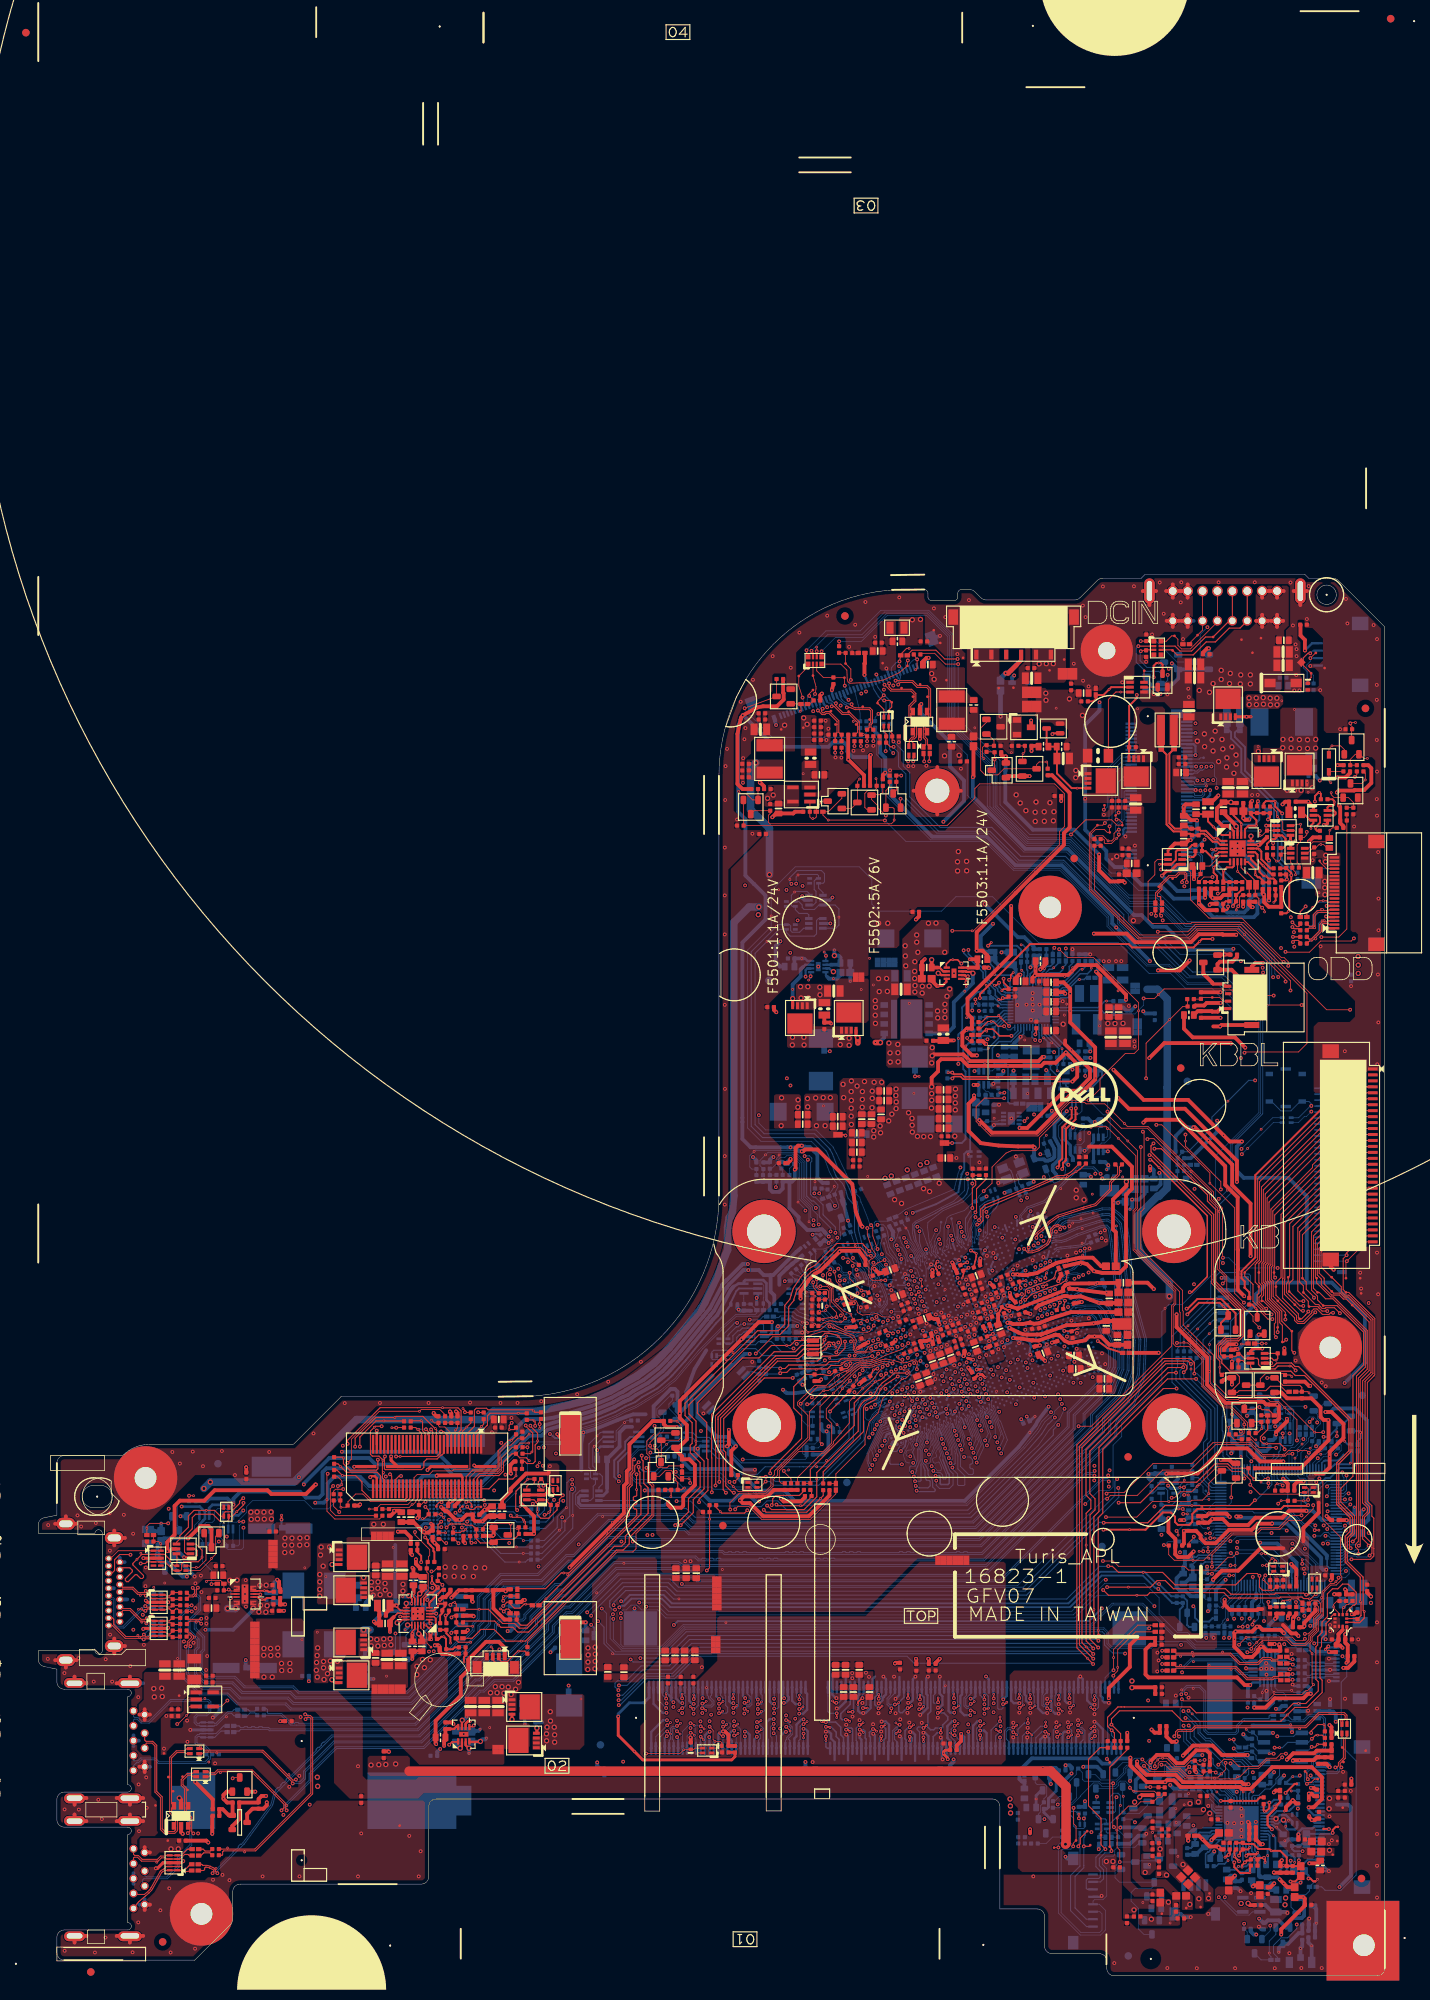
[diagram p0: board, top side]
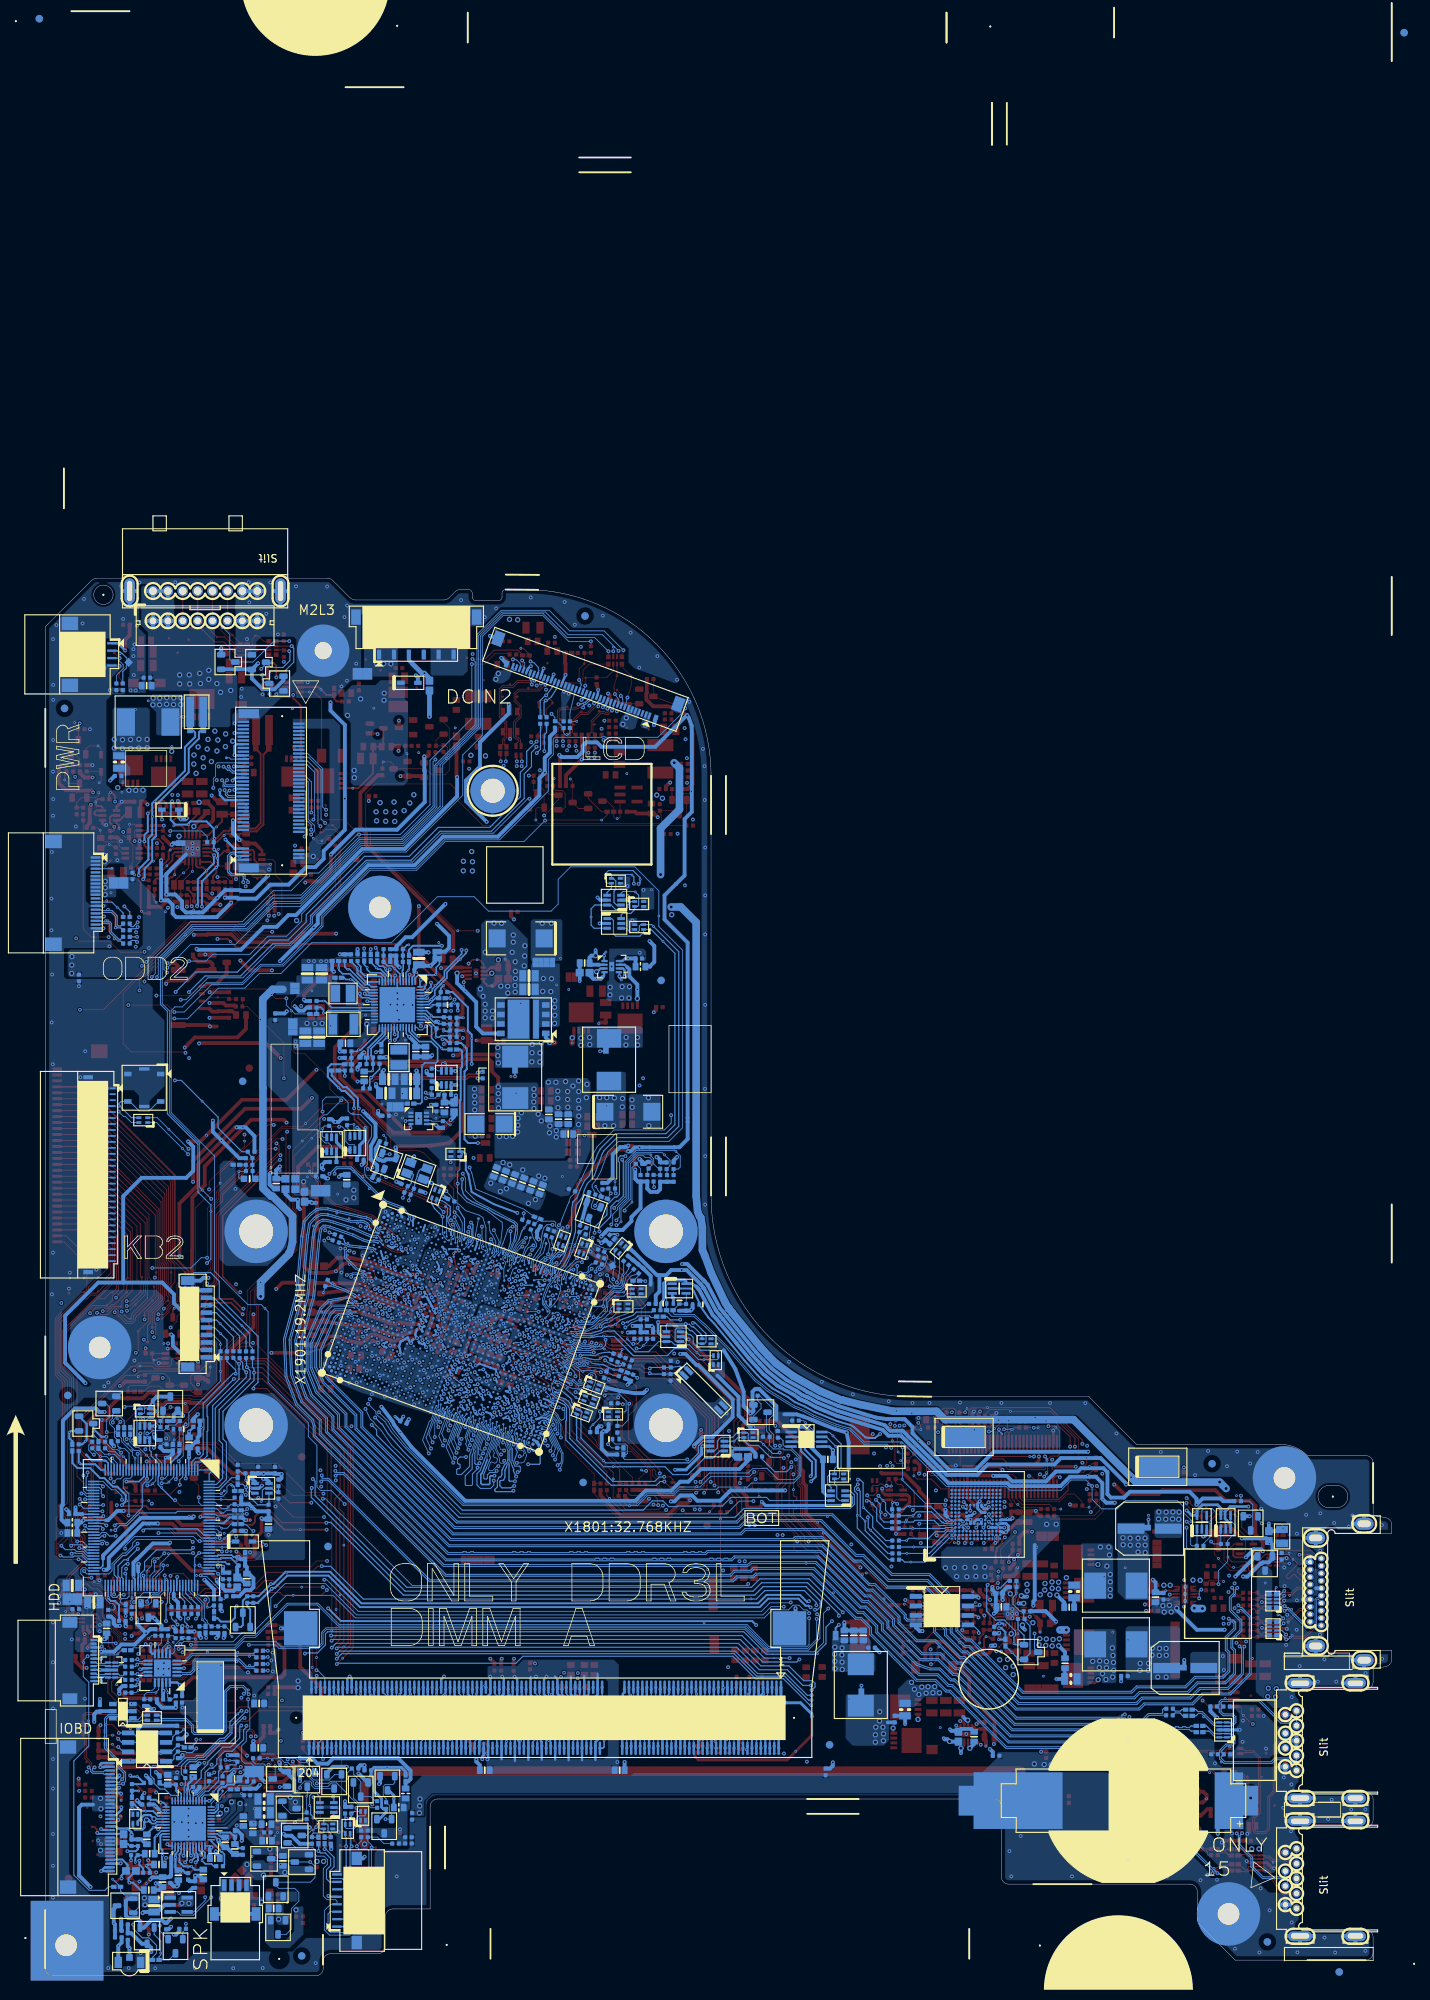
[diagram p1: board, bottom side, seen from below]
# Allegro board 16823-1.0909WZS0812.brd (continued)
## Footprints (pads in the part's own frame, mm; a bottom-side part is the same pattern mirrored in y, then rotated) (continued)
C144KA-108A7-L-1
  round 1.422 hole 1.016: 1(7,0) 2(5,0) 3(3,0) 4(1,0) 5(-1,0) 6(-3,0) 7(-5,0) 8(-7,0)
  oval 1.422x3.404 hole 0.711x2.692: 9(10.125,0) 10(-10.125,0)
C402H22
  custom 0.14x0.14 smd: 1(0,0.445) 2(0,-0.445)
C402H24
  custom 0.14x0.14 smd: 1(0,0.445) 2(0,-0.445)
C603
  custom 0.197x0.197 smd: 1(0,0.66) 2(0,-0.66)
C603H36
  custom 0.197x0.197 smd: 1(0,0.66) 2(0,-0.66)
C603H38
  custom 0.197x0.197 smd: 1(0,0.66) 2(0,-0.66)
C603H40
  custom 0.197x0.197 smd: 1(0,0.66) 2(0,-0.66)
C805H54
  rect 1.549x0.94 smd: 1(0,0.838) 2(0,-0.838)
C805H56
  rect 1.549x0.94 smd: 1(0,0.838) 2(0,-0.838)
C805H58
  rect 1.549x0.94 smd: 1(0,0.838) 2(0,-0.838)
C1206H71
  rect 1.854x1.27 smd: 1(0,1.397) 2(0,-1.397)
CON2O-U
  custom 0.159x0.159 smd: 1(0,0.254) 2(0,-0.254)
CT3528H79
  rect 2.286x2.286 smd: 1(0,1.905) 2(0,-1.905)
CT7343H83
  rect 2.413x2.286 smd: 1(0,3.15) 2(0,-3.15)
DFN8-G125065H32
  rect 0.305x0.838 smd: 1(0.75,1.029) 2(0.25,1.029) 3(-0.25,1.029) 4(-0.75,1.029) 5(-0.75,-1.029) 6(-0.25,-1.029) 7(0.25,-1.029) 8(0.75,-1.029)
  rect 1.245x0.66 smd: 9(0,0)
DFN8G2-G1710-U1H32
  rect 0.305x0.686 smd: 1(0.75,1.106) 2(0.25,1.106) 3(-0.25,1.106) 4(-0.75,1.106) 5(-0.75,-1.106) 6(-0.25,-1.106) 7(0.25,-1.106) 8(0.75,-1.106)
  rect 1.702x0.94 smd: 9(0,0)
DFN10G2510H26
  rect 0.305x0.787 smd: 1(1,0.494) 5(-1,0.494) 6(-1,-0.494) 10(1,-0.494)
  rect 0.254x0.787 smd: 2(0.521,0.494) 4(-0.521,0.494) 7(-0.521,-0.494) 9(0.521,-0.494)
  rect 0.025x0.025 smd: 3(0,0.494)
  rect 0.406x1.753 smd: 8(0,-0.494)
GAP-CLOSE-PWR-3
  rect 0.66x0.762 smd: 1(-0.305,0) 2(0.305,0)
HOLE276R91
  round 7.01 hole 2.311: 1(0,0)
HOLE335R115
  round 8.509 hole 2.921: 1(0,0)
HOLE335R178
  round 8.509 hole 4.521: 1(0,0)
HOLE384X421R115
  rect 9.754x10.693 hole 2.921: 1(0,0)
L603H38
  custom 0.197x0.197 smd: 1(0,0.66) 2(0,-0.66)
L2520-D620H48
  rect 2.261x1.245 smd: 1(0,1.018) 2(0,-1.018)
L7066-1630-1H119
  rect 3.251x2.489 smd: 1(0,2.866) 2(0,-2.866)
L7066-1830-UH119
  rect 3.505x2.921 smd: 1(0,2.78) 2(0,-2.78)
L125100-4P-4H28
  rect 0.762x0.432 smd: 1(-0.625,0.341) 2(0.625,0.341) 3(0.625,-0.341) 4(-0.625,-0.341)
L686647-127318H119
  rect 3.683x2.413 smd: 1(0,2.986) 2(0,-2.986)
L32250525H48
  rect 2.743x1.143 smd: 1(0,1.417) 2(0,-1.417)
LED3020-3P-19H44
  rect 1.499x0.991 smd: 1(0,1.5) 3(0,-1.5)
  rect 0.889x0.889 smd: 2(0.65,0)
LGA12G2H40
  rect 0.381x0.381 smd: 1(0.809,0.809) 4(-0.809,0.809) 7(-0.809,-0.809) 10(0.809,-0.809)
  rect 0.305x0.432 smd: 2(0.25,0.784) 3(-0.25,0.784) 8(-0.25,-0.784) 9(0.25,-0.784)
  rect 0.432x0.305 smd: 5(-0.784,0.25) 6(-0.784,-0.25) 11(0.784,-0.25) 12(0.784,0.25)
LQFP128H63
  rect 0.203x1.524 smd: 1(6.2,7.747) 2(5.8,7.747) 3(5.4,7.747) 4(5,7.747) 5(4.6,7.747) 6(4.2,7.747) 7(3.8,7.747) 8(3.4,7.747) 9(3,7.747) 10(2.6,7.747) 11(2.2,7.747) 12(1.8,7.747) 13(1.4,7.747) 14(0.999,7.747) 15(0.599,7.747) 16(0.199,7.747) 17(-0.199,7.747) 18(-0.599,7.747) 19(-0.999,7.747) 20(-1.4,7.747) 21(-1.8,7.747) 22(-2.2,7.747) 23(-2.6,7.747) 24(-3,7.747) 25(-3.4,7.747) 26(-3.8,7.747) 27(-4.2,7.747) 28(-4.6,7.747) 29(-5,7.747) 30(-5.4,7.747) 31(-5.8,7.747) 32(-6.2,7.747) 65(-6.2,-7.747) 66(-5.8,-7.747) 67(-5.4,-7.747) 68(-5,-7.747) 69(-4.6,-7.747) 70(-4.2,-7.747) 71(-3.8,-7.747) 72(-3.4,-7.747) 73(-3,-7.747) 74(-2.6,-7.747) 75(-2.2,-7.747) 76(-1.8,-7.747) 77(-1.4,-7.747) 78(-0.999,-7.747) 79(-0.599,-7.747) 80(-0.199,-7.747) 81(0.199,-7.747) 82(0.599,-7.747) 83(0.999,-7.747) 84(1.4,-7.747) 85(1.8,-7.747) 86(2.2,-7.747) 87(2.6,-7.747) 88(3,-7.747) 89(3.4,-7.747) 90(3.8,-7.747) 91(4.2,-7.747) 92(4.6,-7.747) 93(5,-7.747) 94(5.4,-7.747) 95(5.8,-7.747) 96(6.2,-7.747)
  rect 1.524x0.203 smd: 33(-7.747,6.2) 34(-7.747,5.8) 35(-7.747,5.4) 36(-7.747,5) 37(-7.747,4.6) 38(-7.747,4.2) 39(-7.747,3.8) 40(-7.747,3.4) 41(-7.747,3) 42(-7.747,2.6) 43(-7.747,2.2) 44(-7.747,1.8) 45(-7.747,1.4) 46(-7.747,0.999) 47(-7.747,0.599) 48(-7.747,0.199) 49(-7.747,-0.199) 50(-7.747,-0.599) 51(-7.747,-0.999) 52(-7.747,-1.4) 53(-7.747,-1.8) 54(-7.747,-2.2) 55(-7.747,-2.6) 56(-7.747,-3) 57(-7.747,-3.4) 58(-7.747,-3.8) 59(-7.747,-4.2) 60(-7.747,-4.6) 61(-7.747,-5) 62(-7.747,-5.4) 63(-7.747,-5.8) 64(-7.747,-6.2) 97(7.747,-6.2) 98(7.747,-5.8) 99(7.747,-5.4) 100(7.747,-5) 101(7.747,-4.6) 102(7.747,-4.2) 103(7.747,-3.8) 104(7.747,-3.4) 105(7.747,-3) 106(7.747,-2.6) 107(7.747,-2.2) 108(7.747,-1.8) 109(7.747,-1.4) 110(7.747,-0.999) 111(7.747,-0.599) 112(7.747,-0.199) 113(7.747,0.199) 114(7.747,0.599) 115(7.747,0.999) 116(7.747,1.4) 117(7.747,1.8) 118(7.747,2.2) 119(7.747,2.6) 120(7.747,3) 121(7.747,3.4) 122(7.747,3.8) 123(7.747,4.2) 124(7.747,4.6) 125(7.747,5) 126(7.747,5.4) 127(7.747,5.8) 128(7.747,6.2)
MSOP8-1H44
  rect 0.356x1.524 smd: 1(-0.975,-2.055) 2(-0.325,-2.055) 3(0.325,-2.055) 4(0.975,-2.055) 5(0.975,2.055) 6(0.325,2.055) 7(-0.325,2.055) 8(-0.975,2.055)
NTC-402H24-U
  custom 0.14x0.14 smd: 1(0,0.445) 2(0,-0.445)
NTC-603H38
  custom 0.216x0.216 smd: 1(0,0.762) 2(0,-0.762)
OSC-3225-4P-4H32
  rect 1.397x1.067 smd: 1(-1.171,-0.756) 2(1.171,-0.756) 3(1.171,0.756) 4(-1.171,0.756)
PAD-60P-1-NSP
  rect 0.305x2.515 smd: 1(-7.25,-2.99) 2(-7.25,2.99) 3(-6.75,-2.99) 4(-6.75,2.99) 5(-6.25,-2.99) 6(-6.25,2.99) 7(-5.751,-2.99) 8(-5.751,2.99) 9(-5.25,-2.99) 10(-5.25,2.99) 11(-4.75,-2.99) 12(-4.75,2.99) 13(-4.249,-2.99) 14(-4.249,2.99) 15(-3.75,-2.99) 16(-3.75,2.99) 17(-3.25,-2.99) 18(-3.25,2.99) 19(-2.75,-2.99) 20(-2.75,2.99) 21(-2.25,-2.99) 22(-2.25,2.99) 23(-1.75,-2.99) 24(-1.75,2.99) 25(-1.25,-2.99) 26(-1.25,2.99) 27(-0.751,-2.99) 28(-0.751,2.99) 29(-0.25,-2.99) 30(-0.25,2.99) 31(0.25,-2.99) 32(0.25,2.99) 33(0.751,-2.99) 34(0.751,2.99) 35(1.25,-2.99) 36(1.25,2.99) 37(1.75,-2.99) 38(1.75,2.99) 39(2.25,-2.99) 40(2.25,2.99) 41(2.75,-2.99) 42(2.75,2.99) 43(3.25,-2.99) 44(3.25,2.99) 45(3.75,-2.99) 46(3.75,2.99) 47(4.249,-2.99) 48(4.249,2.99) 49(4.75,-2.99) 50(4.75,2.99) 51(5.25,-2.99) 52(5.25,2.99) 53(5.751,-2.99) 54(5.751,2.99) 55(6.25,-2.99) 56(6.25,2.99) 57(6.75,-2.99) 58(6.75,2.99) 59(7.25,-2.99) 60(7.25,2.99)
  rect 2.54x0.432 smd: 61(-8.065,0) 64(8.065,0)
  rect 4.699x0.432 smd: 62(-3.175,0) 63(3.175,0)
PAD-87212-1002N
  rect 0.61x1.549 smd: 1(-4.5,-2.525) 2(-3.5,-2.525) 3(-2.5,-2.525) 4(-1.5,-2.525) 5(-0.5,-2.525) 6(0.5,-2.525) 7(1.5,-2.525) 8(2.5,-2.525) 9(3.5,-2.525) 10(4.5,-2.525)
  rect 1.194x1.803 smd: 11(-5.797,0) 12(5.797,0)
POLYSW-2114H30
  rect 1.6x0.965 smd: 1(0,0.94) 2(0,-0.94)
POLYSW-2114H50
  rect 1.6x0.965 smd: 1(0,0.94) 2(0,-0.94)
POLYSW-4633-UH43
  rect 3.505x1.626 smd: 1(0,1.834) 2(0,-1.834)
PPAK-8P-3232H36
  rect 0.406x0.914 smd: 1(-0.975,-2.396) 2(-0.325,-2.396) 3(0.325,-2.396) 4(0.975,-2.396)
  rect 3.353x2.692 smd: 5(0,0)
  rect 0.025x0.025 smd: 6(0.65,0.838) 7(0,0.838) 8(-0.65,0.838)
PPAK-8P-G5324H44-COLAY
  rect 0.762x1.016 smd: 1(-1.905,-3.01) 2(-0.635,-3.01) 3(0.635,-3.01) 4(1.905,-3.01) 5(1.905,3.01) 6(0.635,3.01) 7(-0.635,3.01) 8(-1.905,3.01)
  rect 5.207x2.896 smd: 9(0,0.65)
  rect 5.207x0.787 smd: 10(0,-1.7)
QFN20-G1D75H32
  rect 0.203x0.914 smd: 1(0.8,1.551) 2(0.4,1.551) 3(0,1.551) 4(-0.4,1.551) 5(-0.8,1.551) 11(-0.8,-1.551) 12(-0.4,-1.551) 13(0,-1.551) 14(0.4,-1.551) 15(0.8,-1.551)
  rect 0.914x0.203 smd: 6(-1.551,0.8) 7(-1.551,0.4) 8(-1.551,0) 9(-1.551,-0.4) 10(-1.551,-0.8) 16(1.551,-0.8) 17(1.551,-0.4) 18(1.551,0) 19(1.551,0.4) 20(1.551,0.8)
  rect 1.753x1.753 smd: 21(0,0)
QFN20-G2D25H32
  rect 0.305x1.168 smd: 1(1,1.924) 2(0.5,1.924) 3(0,1.924) 4(-0.5,1.924) 5(-1,1.924) 11(-1,-1.924) 12(-0.5,-1.924) 13(0,-1.924) 14(0.5,-1.924) 15(1,-1.924)
  rect 1.168x0.305 smd: 6(-1.924,1) 7(-1.924,0.5) 8(-1.924,0) 9(-1.924,-0.5) 10(-1.924,-1) 16(1.924,-1) 17(1.924,-0.5) 18(1.924,0) 19(1.924,0.5) 20(1.924,1)
  rect 2.261x2.261 smd: 21(0,0)
QFN20G3D5-G2D15H40
  rect 0.305x0.914 smd: 1(1,1.801) 5(-1,1.801) 11(-1,-1.801) 15(1,-1.801)
  rect 0.305x0.965 smd: 2(0.5,1.775) 3(0,1.775) 4(-0.5,1.775) 12(-0.5,-1.775) 13(0,-1.775) 14(0.5,-1.775)
  rect 0.914x0.305 smd: 6(-1.801,1) 10(-1.801,-1) 16(1.801,-1) 20(1.801,1)
  rect 0.965x0.305 smd: 7(-1.775,0.5) 8(-1.775,0) 9(-1.775,-0.5) 17(1.775,-0.5) 18(1.775,0) 19(1.775,0.5)
  rect 2.159x2.159 smd: 21(0,0)
QFN48J6-G465H40
  rect 0.203x0.965 smd: 1(2.2,3.025) 2(1.8,3.025) 3(1.4,3.025) 4(1,3.025) 5(0.6,3.025) 6(0.2,3.025) 7(-0.2,3.025) 8(-0.6,3.025) 9(-1,3.025) 10(-1.4,3.025) 11(-1.8,3.025) 12(-2.2,3.025) 25(-2.2,-3.025) 26(-1.8,-3.025) 27(-1.4,-3.025) 28(-1,-3.025) 29(-0.6,-3.025) 30(-0.2,-3.025) 31(0.2,-3.025) 32(0.6,-3.025) 33(1,-3.025) 34(1.4,-3.025) 35(1.8,-3.025) 36(2.2,-3.025)
  rect 0.965x0.203 smd: 13(-3.025,2.2) 14(-3.025,1.8) 15(-3.025,1.4) 16(-3.025,1) 17(-3.025,0.6) 18(-3.025,0.2) 19(-3.025,-0.2) 20(-3.025,-0.6) 21(-3.025,-1) 22(-3.025,-1.4) 23(-3.025,-1.8) 24(-3.025,-2.2) 37(3.025,-2.2) 38(3.025,-1.8) 39(3.025,-1.4) 40(3.025,-1) 41(3.025,-0.6) 42(3.025,-0.2) 43(3.025,0.2) 44(3.025,0.6) 45(3.025,1) 46(3.025,1.4) 47(3.025,1.8) 48(3.025,2.2)
  rect 4.648x4.648 smd: 49(0,0)
QFN52J6-G4D75H32
  rect 0.203x0.838 smd: 1(2.4,3.051) 13(-2.4,3.051) 27(-2.4,-3.051) 39(2.4,-3.051)
  rect 0.203x0.914 smd: 2(2,3.051) 3(1.6,3.051) 4(1.2,3.051) 5(0.8,3.051) 6(0.4,3.051) 7(0,3.051) 8(-0.4,3.051) 9(-0.8,3.051) 10(-1.2,3.051) 11(-1.6,3.051) 12(-2,3.051) 28(-2,-3.051) 29(-1.6,-3.051) 30(-1.2,-3.051) 31(-0.8,-3.051) 32(-0.4,-3.051) 33(0,-3.051) 34(0.4,-3.051) 35(0.8,-3.051) 36(1.2,-3.051) 37(1.6,-3.051) 38(2,-3.051)
  rect 0.838x0.203 smd: 14(-3.051,2.4) 26(-3.051,-2.4) 40(3.051,-2.4) 52(3.051,2.4)
  rect 0.914x0.203 smd: 15(-3.051,2) 16(-3.051,1.6) 17(-3.051,1.2) 18(-3.051,0.8) 19(-3.051,0.4) 20(-3.051,0) 21(-3.051,-0.4) 22(-3.051,-0.8) 23(-3.051,-1.2) 24(-3.051,-1.6) 25(-3.051,-2) 41(3.051,-2) 42(3.051,-1.6) 43(3.051,-1.2) 44(3.051,-0.8) 45(3.051,-0.4) 46(3.051,0) 47(3.051,0.4) 48(3.051,0.8) 49(3.051,1.2) 50(3.051,1.6) 51(3.051,2)
  rect 4.75x4.75 smd: 53(0,0)
R402H14
  custom 0.14x0.14 smd: 1(0,0.445) 2(0,-0.445)
R402H16
  custom 0.14x0.14 smd: 1(0,0.445) 2(0,-0.445)
R603H22
  custom 0.197x0.197 smd: 1(0,0.66) 2(0,-0.66)
R805H24
  rect 1.549x0.94 smd: 1(0,0.838) 2(0,-0.838)
R1206H28
  rect 1.854x1.27 smd: 1(0,1.397) 2(0,-1.397)
R3720H40
  rect 4.013x1.041 smd: 1(0,0.867) 2(0,-0.867)
SC70-2D2-312H44
  custom 0.152x0.152 smd: 1(-0.65,-0.902) 2(0.65,-0.902) 3(0,0.902)
SC70-5-1H44
  rect 0.356x1.219 smd: 1(-0.65,-0.922) 2(0,-0.922) 3(0.65,-0.922) 4(0.65,0.921) 5(-0.65,0.921)
SC70-6H44
  rect 0.406x1.016 smd: 1(-0.65,-0.94) 2(0,-0.94) 3(0.65,-0.94) 4(0.65,0.94) 5(0,0.94) 6(-0.65,0.94)
SE361414H178
  rect 1.372x3.607 smd: 1(0,2.499) 2(0,-2.499)
SKT-HDMI23-188137-5
  oval 0.787x0.94 hole 0.533: 1(-4.5,5.75) 2(-4,7.25) 3(-3.5,5.75) 4(-3,7.25) 5(-2.5,5.75) 6(-2,7.25) 7(-1.5,5.75) 8(-1,7.25) 9(-0.5,5.75) 10(0,7.25) 11(0.5,5.75) 12(1,7.25) 13(1.5,5.75) 14(2,7.25) 15(2.5,5.75) 16(3,7.25) 17(3.5,5.75) 18(4,7.25) 19(4.5,5.75)
  oval 1.626x2.515 hole 0.914x1.803: 20(-7.25,6.5) 21(7.25,6.5) 22(-9.15,0) 23(9.15,0)
SKT-USB13-157164-1
  round 1.067 hole 0.711: 1(3.5,9.41) 2(1,9.41) 3(-1,9.41) 4(-3.5,9.41) 5(-4,7.91) 6(-2,7.91) 7(0,7.91) 8(2,7.91) 9(4,7.91)
  oval 1.321x3.2 hole 0.711x2.489: 10(7.7,7.43) 11(-7.7,7.43)
  oval 1.321x2.819 hole 0.711x2.108: 12(7.7,0) 13(-7.7,0)
SLP2510P8-1H22
  rect 0.305x0.762 smd: 1(-1,-0.5) 5(1,-0.5) 6(1,0.5) 10(-1,0.5)
  rect 0.203x0.762 smd: 2(-0.5,-0.5) 4(0.5,-0.5) 7(0.5,0.5) 9(-0.5,0.5)
  rect 0.406x0.762 smd: 3(0,-0.5) 8(0,0.5)
SM3ZS067U410TAR1000R-DT
  round 0.254 hole 1.168 unplated: (-10,0)
  round 0.254 hole 1.651 unplated: (10,0)
  rect 0.305x1.549 smd: 1(-9.25,5.225) 2(-9,-2.225) 3(-8.75,5.225) 4(-8.5,-2.225) 5(-8.25,5.225) 6(-8,-2.225) 7(-7.75,5.225) 16(-5.5,-2.225) 17(-5.25,5.225) 18(-5,-2.225) 19(-4.75,5.225) 20(-4.5,-2.225) 21(-4.25,5.225) 22(-4,-2.225) 23(-3.75,5.225) 24(-3.5,-2.225) 25(-3.25,5.225) 26(-3,-2.225) 27(-2.75,5.225) 28(-2.5,-2.225) 29(-2.25,5.225) 30(-2,-2.225) 31(-1.75,5.225) 32(-1.5,-2.225) 33(-1.25,5.225) 34(-1,-2.225) 35(-0.75,5.225) 36(-0.5,-2.225) 37(-0.25,5.225) 38(0,-2.225) 39(0.25,5.225) 40(0.5,-2.225) 41(0.75,5.225) 42(1,-2.225) 43(1.25,5.225) 44(1.5,-2.225) 45(1.75,5.225) 46(2,-2.225) 47(2.25,5.225) 48(2.5,-2.225) 49(2.75,5.225) 50(3,-2.225) 51(3.25,5.225) 52(3.5,-2.225) 53(3.75,5.225) 54(4,-2.225) 55(4.25,5.225) 56(4.5,-2.225) 57(4.75,5.225) 58(5,-2.225) 59(5.25,5.225) 60(5.5,-2.225) 61(5.75,5.225) 62(6,-2.225) 63(6.25,5.225) 64(6.5,-2.225) 65(6.75,5.225) 66(7,-2.225) 67(7.25,5.225) 68(7.5,-2.225) 69(7.75,5.225) 70(8,-2.225) 71(8.25,5.225) 72(8.5,-2.225) 73(8.75,5.225) 74(9,-2.225) 75(9.25,5.225)
  rect 1.194x2.743 smd: 76(-10.35,4.5) 77(10.35,4.5)
SMD49-6914-0603H56
  rect 1.321x0.584 smd: 1(-3.297,-0.437) 4(-3.297,0.437)
  rect 1.372x0.584 smd: 2(3.272,-0.437) 3(3.272,0.437)
SMD-ARES4H18
  rect 0.356x0.66 smd: 1(-0.325,-0.599) 2(0.325,-0.599) 3(0.325,0.599) 4(-0.325,0.599)
SMD-ARES4H20
  rect 0.356x0.66 smd: 1(-0.325,-0.599) 2(0.325,-0.599) 3(0.325,0.599) 4(-0.325,0.599)
SOD123AK-2H43
  rect 1.143x1.499 smd: A(0,1.758) K(0,-1.758)
SOD323AKH38
  rect 0.559x1.016 smd: A(0,1.143) K(0,-1.143)
SOD323AKH42
  rect 0.559x1.016 smd: A(0,1.143) K(0,-1.143)
SOD882-10D6-1H20
  custom 0.114x0.114 smd: 1(0,0.445) 2(0,-0.445)
SOIC8-1H86
  rect 0.635x1.651 smd: 1(-1.905,-3.493) 2(-0.635,-3.493) 3(0.635,-3.493) 4(1.905,-3.493) 5(1.905,3.493) 6(0.635,3.493) 7(-0.635,3.493) 8(-1.905,3.493)
SOIC8H69
  rect 0.635x1.651 smd: 1(-1.905,-2.54) 2(-0.635,-2.54) 3(0.635,-2.54) 4(1.905,-2.54) 5(1.905,2.54) 6(0.635,2.54) 7(-0.635,2.54) 8(-1.905,2.54)
SON14J3020-G2610H32
  rect 0.025x0.025 smd: 1(1.2,1.105) 6(-0.8,1.105) 9(-0.8,-1.105) 14(1.2,-1.105)
  custom 0.151x0.151 smd: 2(0.8,1.105) 7(-1.2,1.105) 8(-1.2,-1.105) 13(0.8,-1.105)
  rect 0.203x0.813 smd: 3(0.4,1.105) 4(0,1.105) 5(-0.4,1.105) 10(-0.4,-1.105) 11(0,-1.105) 12(0.4,-1.105)
  rect 2.591x0.889 smd: 15(0,0)
SOT23-2D4-312H44
  custom 0.191x0.191 smd: 1(-0.984,-0.953) 2(0.984,-0.953) 3(0,0.953)
SOT23-2D4-312H48
  custom 0.191x0.191 smd: 1(-0.984,-0.953) 2(0.984,-0.953) 3(0,0.953)
SOT23CBE2D4H44
  custom 0.191x0.191 smd: B(-0.984,-0.953) C(0,0.953) E(0.984,-0.953)
SOT23CBE2D6H62
  custom 0.165x0.165 smd: B(-0.95,-1.092) C(0,1.092) E(0.95,-1.092)
SOT23DGS2D4H44
  custom 0.191x0.191 smd: D(0,0.953) G(-0.984,-0.953) S(0.984,-0.953)
SOT23DGS2D4H48
  custom 0.191x0.191 smd: D(0,0.953) G(-0.984,-0.953) S(0.984,-0.953)
SOT323CBE2D2H40
  custom 0.152x0.152 smd: B(-0.65,-0.902) C(0,0.902) E(0.65,-0.902)
SOT-6H58
  rect 0.584x1.016 smd: 1(-0.953,-1.346) 2(0,-1.346) 3(0.953,-1.346) 4(0.953,1.346) 5(0,1.346) 6(-0.953,1.346)
SOT-23-5H51
  rect 0.508x1.524 smd: 1(-0.95,-1.143) 2(0,-1.143) 3(0.95,-1.143) 4(0.95,1.143) 5(-0.95,1.143)
SOT-23-5H58
  rect 0.508x1.524 smd: 1(-0.95,-1.143) 2(0,-1.143) 3(0.95,-1.143) 4(0.95,1.143) 5(-0.95,1.143)
SOT-23-9H44
  custom 0.178x0.178 smd: 1(-0.95,-0.999) 2(0.95,-0.999) 3(0,0.999)
SOT-23-10H44
  rect 0.762x1.143 smd: 1(-0.984,-0.953) 2(0.984,-0.953) 3(0,0.953)
SOT-363H44
  rect 0.406x1.016 smd: 1(-0.65,-0.94) 2(0,-0.94) 3(0.65,-0.94) 4(0.65,0.94) 5(0,0.94) 6(-0.65,0.94)
SPR4527H308
  rect 8.992x3.404 smd: 1(-2.248,0)
SPR5630H142
  rect 5.283x2.692 smd: 1(-2.413,0)
STF236R128H101
  round 5.994 hole 3.251: 1(0,0)
TJE-533-S-V-T-R-744
  rect 0.61x0.991 smd: 1(-1.845,2.205) 2(-1.845,-2.205) 3(1.845,2.205) 4(1.845,-2.205)
  rect 0.457x1.397 smd: 5(-2.521,0) 6(2.521,0)
TPAD14-OP
  round 0.356 smd: 1(0,0)
unnamed
  round 0.254 hole 2.184 unplated: (0,0)

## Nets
1V_CPU_VCGI: C1019.1 C1020.1 C1021.1 C1022.1 C1023.1 C1024.1 C1025.1 C1026.1 C1027.1 C1028.1 C1029.1 C1030.1 CPU1.AA28 CPU1.AA30 CPU1.AA32 CPU1.AA36 CPU1.AA37 CPU1.AA39 CPU1.AC28 CPU1.AC30 CPU1.AC32 CPU1.AC36 CPU1.AC37 CPU1.AE28 CPU1.AE30 CPU1.AE32 CPU1.AE36 CPU1.AE37 CPU1.AG28 CPU1.AG30 CPU1.AG32 CPU1.AG36 CPU1.AJ28 CPU1.AJ30 CPU1.AJ32 CPU1.AK28 CPU1.AK30 CPU1.AK32 CPU1.AK34 CPU1.AM30 CPU1.E29 CPU1.E35 CPU1.E37 CPU1.E43 CPU1.E45 CPU1.E48 CPU1.E50 CPU1.F29 CPU1.R45 CPU1.R47 CPU1.U28 CPU1.U30 CPU1.U32 CPU1.U36 CPU1.U37 CPU1.U39 CPU1.U41 CPU1.U42 CPU1.U44 CPU1.U46 CPU1.U47 CPU1.U48 CPU1.V28 CPU1.V30 CPU1.V32 CPU1.V36 CPU1.V37 CPU1.V39 CPU1.V41 CPU1.Y28 CPU1.Y30 CPU1.Y32 CPU1.Y36 CPU1.Y37 CPU1.Y39 CPU1.Y41 PC1010.1 PC1012.1 PC1013.1 PC1014.1 PC1015.1 PC1016.1 PC1017.1 PC1018.1 PC1019.1 PC1020.1 PC1021.1 PC1022.1 PC1024.1 PC1025.1 PC1026.1 PC1028.1 PC1030.1 PC1031.1 PC1032.1 PC1033.1 PC1034.1 PC1035.1 PC1036.1 PC1037.1 PC1038.1 PC1039.1 PC1044.1 PC5106.2 PG5101.2 PL5103.2 PR5107.2 PR5108.2 PR5113.1 PT5102.1
1V_CPU_VNN: C1016.1 C1017.1 CPU1.AJ37 CPU1.AJ39 CPU1.AJ41 CPU1.AJ42 CPU1.AJ46 CPU1.AK37 CPU1.AK39 CPU1.AK41 CPU1.AK42 CPU1.AK44 CPU1.AK46 CPU1.AM23 CPU1.AM25 CPU1.AM41 CPU1.AM42 CPU1.AM44 PC1006.1 PC1007.1 PC1009.1 PC1011.1 PC1023.1 PC1048.1 PC1049.1 PC1050.1 PC1051.1 PG5103.2 PL5101.2 PT5101.1
3V_5V_PWRGD: ED1803.1 PR4534.2 PR5033.2 PR5046.2 PU4503.7
3V_EN: KBC24.63 Q2403.6 R4013.2 RN2406.2(A)
3V_FEEDBACK: PG4535.2 PR4512.1 PR4535.1
3V_S5_EN: D4001.1 PR4503.1 PR4504.2 R4013.1
5V_DDC_HDMI1: D5701.1 RN5701.3(B)
5V_DDC_HDMI2: D5701.2 RN5701.4(B)
5V_HDD_S0: C6022.1 C6023.1 HDD1.2 HDD1.3 HDD1.4 R6025.2
5V_HDMI_R_S0: F5701.1 R5718.2
5V_HDMI_S0: EC5701.1 F5701.2 HDMI1.18
5V_PWR: PC4518.1 PG4519.1 PG4523.1 PG4527.1 PG4532.1 PG4533.1 PG4537.1 PG4538.1 PG4540.1 PG4541.1 PG4544.1 PG4545.1 PL4501.2 PT4501.1
5V_PWR_2: PC4524.1 PU4503.13
5V_S0: C4006.1 C6020.1 C6021.1 D5701.3 EC4003.1 EC8919.1 EC8920.1 EC8921.1 EC8922.1 EC8923.1 EC8924.1 EC8925.1 EC8926.1 EC8928.1 EC8930.1 EC8931.1 Q2701.D Q2907.E Q5702.G Q6502.E R2712.1 R2716.1 R2720.2 R2733.1 R2926.2 R5512.2 R5718.1 R6004.1 R6025.1 R6504.1 R7009.1 U4001.8 U4001.9
5V_S0_CT: C4003.1 U4001.10
5V_S0_SIP: C2728.1 C2729.1 L2701.2 Q2701.S
5V_S5: C3509.1 C3604.1 C4005.1 DB3.1 EC4001.1 EC4005.1 EC8909.1 EC8910.1 EC8911.1 PC5003.1 PC5004.1 PC5007.1 PC5008.1 PC5024.1 PC5025.1 PG4519.2 PG4523.2 PG4527.2 PG4533.2 PG4537.2 PG4538.2 PG4540.2 PG4541.2 PG4544.2 PG4545.2 PR4303.1 PR4506.1 PR5031.1 PR5101.1 PR5103.1 PR5104.1 PU5001.19 PU5001.25 PU5001.26 PU5001.36 Q6403.E Q6404.E U3601.5 U3602.5 U4001.4 U4001.6 U4001.7 U4002.4
5V_S5_EN: D4001.2 PR4501.2 PR4502.1 PR4504.1 PR4530.1 R4007.1
5V_USB30: AFTP3501.1 AFTP3507.1 C3601.1 C3602.1 C3605.1 C3606.1 C3607.1 EU3502.5 EU5501.5 R3601.1 U3601.1 USB1.1 USB2.1
19V_AD+: PC4303.1 PC4304.1 PC4305.1 PC4306.1 PR4404.1 PR4405.1 PR4407.1 PR4408.1 PR4469.1 PU4301.5 PU4301.6 PU4301.7 PU4301.8 PU4402.5 PU4402.6 PU4402.7 PU4402.8 PU4403.4
19V_DCBATOUT: EC4401.1 EC4402.1 EC5501.1 EC5502.1 EC5503.1 EC8903.1 EC8904.1 EC8905.1 EC8906.1 EC8907.1 EC8908.1 F5501.1 PC4406.1 PC4408.1 PC4409.1 PC4426.1 PC4519.1 PC4531.1 PG4403.1 PG4518.1 PG4520.1 PG4521.1 PG4524.1 PG4525.1 PG4531.1 PG4534.1 PG4536.1 PG4542.1 PG4543.1 PG5113.1 PG5114.1 PG5115.1 PG5116.1 PG5117.1 PG5118.1 PG5119.1 PG5120.1 PR4402.2 PR4468.1 PR5007.1 PR5008.1 PT5103.1 PU4403.1 PU4403.2 PU4403.3 PU4405.5 PU4405.6 PU4405.7 PU4405.8 PU4503.12 R2726.1
19V_DCBATOUT_LCD: AFTP5501.1 C5501.1 C5503.1 C5511.1 F5501.2 LCD1.1 LCD1.2
+3.3V_1.8V_DVDD-IO: C2719.1 C2723.2 HDA27.9 R2729.2
+3V_1D5V_AVDD: C2715.1 C2721.1 HDA27.40 R2724.2
+3V_AVDD: C2716.1 C2717.1 HDA27.1 R2706.1 R2708.2 R2711.1
+5V_AVDD: C2710.1 C2711.1 HDA27.26 R2720.1
+5V_KB_BL: AFTP6501.1 C6501.1 KBBL1.1 R6504.2
+5V_PVDD: C2706.1 C2707.1 C2708.1 C2709.1 HDA27.41 HDA27.46 L2701.1 R2712.2 R2716.2
DVSS: HDA27.4 R2707.1
GND: AFTP2501.1 AFTP3504.1 AFTP3505.1 AFTP4309.1 AFTP4310.1 AFTP4311.1 AFTP6403.1 AFTP6531.1 AFTP6537.1 AFTP6565.1 AFTP6612.1 BATT1.7 BATT1.8 BATT1.9 BATT1.10 BATT2.7 BATT2.8 C601.2 C1001.2 C1002.2 C1003.2 C1004.2 C1005.2 C1006.2 C1007.2 C1008.2 C1009.2 C1010.2 C1011.2 C1012.2 C1013.2 C1014.2 C1015.2 C1016.2 C1017.2 C1018.2 C1019.2 C1020.2 C1021.2 C1022.2 C1023.2 C1024.2 C1025.2 C1026.2 C1027.2 C1028.2 C1029.2 C1030.2 C1101.2 C1102.2 C1103.2 C1104.2 C1106.2 C1107.2 C1108.2 C1109.2 C1110.2 C1111.2 C1112.2 C1113.2 C1201.2 C1202.2 C1203.2 C1205.2 C1206.2 C1207.2 C1208.2 C1209.2 C1210.2 C1211.2 C1212.2 C1213.2 C1214.2 C1215.2 C1216.2 C1217.2 C1218.2 C1220.2 C1223.2 C1224.2 C1801.2 C1802.2 C1803.2 C1804.2 C1805.2 C1901.2 C1902.2 C2401.2 C2414.2 C2417.2 C2418.2 C2428.1 C2429.2 C2430.2 C2431.2 C2432.2 C2433.2 C2439.2 C2440.2 C2441.2 C2443.2 C2444.2 C2445.2 C2446.2 C2447.2 C2501.2 C2502.2 C2503.2 C2504.2 C2601.2 C2602.2 C2605.2 C2701.2 C2704.1 C2706.2 C2707.2 C2708.2 C2709.2 C2714.2 C2716.2 C2717.2 C2718.2 C2719.2 C2722.1 C2723.1 C2728.2 C2729.2 C2905.2 C2907.2 C2909.2 C2910.2 C3509.2 C3515.2 C3517.2 C3518.2 C3601.2 C3602.2 C3604.2 C3605.2 C3606.2 C3607.2 C4002.2 C4003.2 C4004.2 C4005.2 C4006.2 C4010.2 C4011.2 C4014.2 C4030.2 C4031.2 C4033.2 C5501.2 C5502.2 C5503.2 C5509.1 C5510.2 C5511.2 C5514.2 C5515.2 C5516.2 C5536.1 C5538.2 C6009.2 C6010.2 C6012.2 C6020.2 C6021.2 C6022.2 C6023.2 C6024.2 C6101.2 C6102.2 C6103.2 C6301.2 C6302.2 C6303.2 C6304.2 C6305.2 C6401.2 C6501.2 C6502.2 C6504.2 C6601.2 C7001.2 C7002.2 C7003.2 C9901.2 C9902.2 C9903.2 C9904.2 C9905.2 CPU1.A5 CPU1.A9 CPU1.A12 CPU1.A16 CPU1.A20 CPU1.A24 CPU1.A28 CPU1.A32 CPU1.A36 CPU1.A40 CPU1.A44 CPU1.A48 CPU1.A52 CPU1.A56 CPU1.A62 CPU1.AA1 CPU1.AA2 CPU1.AA27 CPU1.AA34 CPU1.AA41 CPU1.AA63 CPU1.AB5 CPU1.AB9 CPU1.AB10 CPU1.AB12 CPU1.AB16 CPU1.AB48 CPU1.AB52 CPU1.AB57 CPU1.AB59 CPU1.AC18 CPU1.AC27 CPU1.AC34 CPU1.AC39 CPU1.AE1 CPU1.AE2 CPU1.AE4 CPU1.AE5 CPU1.AE7 CPU1.AE8 CPU1.AE10 CPU1.AE11 CPU1.AE13 CPU1.AE14 CPU1.AE16 CPU1.AE17 CPU1.AE23 CPU1.AE27 CPU1.AE34 CPU1.AE39 CPU1.AE41 CPU1.AE47 CPU1.AE48 CPU1.AE50 CPU1.AE51 CPU1.AE53 CPU1.AE54 CPU1.AE56 CPU1.AE57 CPU1.AE59 CPU1.AE63 CPU1.AG13 CPU1.AG18 CPU1.AG23 CPU1.AG27 CPU1.AG34 CPU1.AG37 CPU1.AG39 CPU1.AG41 CPU1.AG42 CPU1.AG44 CPU1.AG46 CPU1.AH5 CPU1.AH6 CPU1.AH7 CPU1.AH15 CPU1.AH16 CPU1.AH48 CPU1.AH52 CPU1.AH54 CPU1.AH55 CPU1.AH57 CPU1.AH58 CPU1.AH59 CPU1.AJ1 CPU1.AJ2 CPU1.AJ18 CPU1.AJ23 CPU1.AJ27 CPU1.AJ34 CPU1.AJ36 CPU1.AJ63 CPU1.AK5 CPU1.AK9 CPU1.AK10 CPU1.AK12 CPU1.AK18 CPU1.AK23 CPU1.AK27 CPU1.AK36 CPU1.AK48 CPU1.AK52 CPU1.AK59 CPU1.AM18 CPU1.AM22 CPU1.AM27 CPU1.AM34 CPU1.AM36 CPU1.AM39 CPU1.AM46 CPU1.AN1 CPU1.AN2 CPU1.AN5 CPU1.AN7 CPU1.AN8 CPU1.AN10 CPU1.AN11 CPU1.AN13 CPU1.AN14 CPU1.AN16 CPU1.AN17 CPU1.AN25 CPU1.AN27 CPU1.AN28 CPU1.AN30 CPU1.AN34 CPU1.AN36 CPU1.AN37 CPU1.AN39 CPU1.AN47 CPU1.AN48 CPU1.AN50 CPU1.AN51 CPU1.AN53 CPU1.AN54 CPU1.AN56 CPU1.AN57 CPU1.AN59 CPU1.AN63 CPU1.AP9 CPU1.AP55 CPU1.AR19 CPU1.AR32 CPU1.AR45 CPU1.AT2 CPU1.AT3 CPU1.AT7 CPU1.AT12 CPU1.AT16 CPU1.AT19 CPU1.AT25 CPU1.AT29 CPU1.AT35 CPU1.AT39 CPU1.AT45 CPU1.AT48 CPU1.AT52 CPU1.AT57 CPU1.AT61 CPU1.AT62 CPU1.AU32 CPU1.AV2 CPU1.AV3 CPU1.AV9 CPU1.AV19 CPU1.AV21 CPU1.AV23 CPU1.AV29 CPU1.AV32 CPU1.AV35 CPU1.AV41 CPU1.AV43 CPU1.AV45 CPU1.AV55 CPU1.AV61 CPU1.AV62 CPU1.AW14 CPU1.AW30 CPU1.AW34 CPU1.AW50 CPU1.AY6 CPU1.AY10 CPU1.AY32 CPU1.AY54 CPU1.AY58 CPU1.B2 CPU1.B3 CPU1.B9 CPU1.B62 CPU1.B63 CPU1.BA1 CPU1.BA2 CPU1.BA12 CPU1.BA16 CPU1.BA17 CPU1.BA21 CPU1.BA25 CPU1.BA27 CPU1.BA29 CPU1.BA32 CPU1.BA35 CPU1.BA37 CPU1.BA39 CPU1.BA43 CPU1.BA47 CPU1.BA48 CPU1.BA52 CPU1.BA62 CPU1.BA63 CPU1.BB3 CPU1.BB19 CPU1.BB25 CPU1.BB39 CPU1.BB45 CPU1.BB61 CPU1.BC32 CPU1.BD3 CPU1.BD8 CPU1.BD32 CPU1.BD56 CPU1.BD61 CPU1.BE1 CPU1.BE10 CPU1.BE12 CPU1.BE16 CPU1.BE17 CPU1.BE21 CPU1.BE27 CPU1.BE29 CPU1.BE35 CPU1.BE37 CPU1.BE43 CPU1.BE47 CPU1.BE48 CPU1.BE52 CPU1.BE54 CPU1.BE63 CPU1.BF3 CPU1.BF32 CPU1.BF61 CPU1.BG19 CPU1.BG23 CPU1.BG29 CPU1.BG32 CPU1.BG35 CPU1.BG41 CPU1.BG45 CPU1.BH1 CPU1.BH2 CPU1.BH21 CPU1.BH25 CPU1.BH39 CPU1.BH43 CPU1.BH62 CPU1.BH63 CPU1.BJ4 CPU1.BJ8 CPU1.BJ10 CPU1.BJ14 CPU1.BJ18 CPU1.BJ28 CPU1.BJ32 CPU1.BJ36 CPU1.BJ46 CPU1.BJ50 CPU1.BJ54 CPU1.BJ56 CPU1.BJ60 CPU1.C12 CPU1.C16 CPU1.C28 CPU1.C32 CPU1.C40 CPU1.C48 CPU1.D6 CPU1.D32 CPU1.D58 CPU1.E4 CPU1.E12 CPU1.E14 CPU1.E19 CPU1.E27 CPU1.E54 CPU1.F3 CPU1.F10 CPU1.F21 CPU1.F32 CPU1.F37 CPU1.F43 CPU1.F45 CPU1.F50 CPU1.F56 CPU1.F59 CPU1.F63 CPU1.G1 CPU1.G32 CPU1.H3 CPU1.H7 CPU1.H17 CPU1.H23 CPU1.H29 CPU1.H37 CPU1.H47 CPU1.H61 CPU1.J12 CPU1.J14 CPU1.J19 CPU1.J27 CPU1.J30 CPU1.J32 CPU1.J35 CPU1.J37 CPU1.J48 CPU1.J63 CPU1.K5 CPU1.K6 CPU1.K32 CPU1.K54 CPU1.K57 CPU1.L21 CPU1.L27 CPU1.L29 CPU1.L35 CPU1.L43 CPU1.L45 CPU1.L50 CPU1.M3 CPU1.M9 CPU1.M14 CPU1.M21 CPU1.M27 CPU1.M32 CPU1.M50 CPU1.M59 CPU1.N1 CPU1.N32 CPU1.N63 CPU1.P5 CPU1.P9 CPU1.P13 CPU1.P19 CPU1.P35 CPU1.P37 CPU1.P41 CPU1.P43 CPU1.P45 CPU1.P55 CPU1.P59 CPU1.R23 CPU1.R29 CPU1.R32 CPU1.T49 CPU1.U1 CPU1.U2 CPU1.U5 CPU1.U7 CPU1.U8 CPU1.U10 CPU1.U11 CPU1.U13 CPU1.U14 CPU1.U16 CPU1.U17 CPU1.U18 CPU1.U27 CPU1.U34 CPU1.U50 CPU1.U51 CPU1.U53 CPU1.U54 CPU1.U56 CPU1.U57 CPU1.U59 CPU1.U62 CPU1.U63 CPU1.V20 CPU1.V27 CPU1.V34 CPU1.V42 CPU1.Y5 CPU1.Y6 CPU1.Y7 CPU1.Y12 CPU1.Y16 CPU1.Y22 CPU1.Y27 CPU1.Y34 CPU1.Y42 CPU1.Y46 CPU1.Y48 CPU1.Y52 CPU1.Y54 CPU1.Y55 CPU1.Y57 CPU1.Y59 D4304.1 D4305.1 D4306.1 DB1.1 DB1.3 DB1.11 DB1.12 DB3.4 DB3.5 DB3.6 DCIN1.7 DCIN1.8 DCIN2.7 DCIN2.8 DM1.2 DM1.3 DM1.8 DM1.9 DM1.11 DM1.13 DM1.14 DM1.19 DM1.20 DM1.25 DM1.26 DM1.28 DM1.31 DM1.32 DM1.37 DM1.38 DM1.43 DM1.44 DM1.46 DM1.48 DM1.49 DM1.54 DM1.55 DM1.60 DM1.61 DM1.63 DM1.65 DM1.66 DM1.71 DM1.72 DM1.127 DM1.128 DM1.133 DM1.134 DM1.136 DM1.138 DM1.139 DM1.144 DM1.145 DM1.150 DM1.151 DM1.153 DM1.155 DM1.156 DM1.161 DM1.162 DM1.167 DM1.168 DM1.170 DM1.172 DM1.173 DM1.178 DM1.179 DM1.184 DM1.185 DM1.187 DM1.189 DM1.190 DM1.195 DM1.196 DM1.205 DM1.206 EC1801.2 EC1901.2 EC1902.2 EC2001.2 EC2002.2 EC2102.2 EC2401.2 EC2402.2 EC2403.2 EC2501.2 EC2502.2 EC2503.2 EC2504.2 EC2505.2 EC2506.2 EC2702.2 EC2703.2 EC2704.2 EC2705.2 EC2706.2 EC2708.2 EC2709.1 EC2901.2 EC2902.2 EC2903.2 EC2904.2 EC4001.2 EC4002.2 EC4003.2 EC4004.2 EC4005.2 EC4306.1 EC4307.2 EC4308.2 EC4309.2 EC4310.2 EC4401.2 EC4402.2 EC5501.2 EC5502.2 EC5503.2 EC5504.2 EC5505.2 EC5506.2 EC5507.2 EC5701.2 EC6401.2 EC6402.2 EC6403.2 EC6404.2 EC6501.2 EC6502.2 EC6503.2 EC6504.2 EC6505.2 EC6506.2 EC8901.2 EC8902.2 EC8903.2 EC8904.2 EC8905.2 EC8906.2 EC8907.2 EC8908.2 EC8909.2 EC8910.2 EC8911.2 EC8912.2 EC8913.2 EC8914.2 EC8915.2 EC8916.2 EC8917.2 EC8918.2 EC8919.2 EC8920.2 EC8921.2 EC8922.2 EC8923.2 EC8924.2 EC8925.2 EC8926.2 EC8927.2 EC8928.2 EC8929.2 EC8930.2 EC8931.2 ED1201.2 ED1202.2 ED1803.2 ED1804.2 ED1805.2 ED1806.2 ED1807.2 ED1808.2 ED1809.2 ED5701.3 ED5701.8 ED5702.3 ED5702.8 ED5703.3 ED5703.8 ED6401.2 ED6601.2 EL4303.2 EL4304.2 EU3501.3 EU3501.8 EU3502.2 EU3504.3 EU3504.8 EU5501.2 EU6001.3 EU6001.8 FC3503.2 FC3504.2 FC3505.2 FC3506.2 G1801.1 G6401.1 G6402.1 H1.1 H2.1 H3.1 H4.1 H5.1 H6.1 H7.1 H8.1 H9.1 H10.1 HDA27.49 HDD1.6 HDD1.9 HDD1.12 HDD1.13 HDD1.14 HDMI1.2 HDMI1.5 HDMI1.8 HDMI1.11 HDMI1.17 HDMI1.20 HDMI1.21 HDMI1.22 HDMI1.23 HS1.1 IOBD1.1 IOBD1.2 IOBD1.5 IOBD1.8 IOBD1.29 IOBD1.30 IOBD1.31 IOBD1.32 KB1.1 KB1.31 KB1.32 KB2.1 KB2.31 KB2.32 KBBL1.5 KBBL1.6 KBC24.5 KBC24.18 KBC24.45 KBC24.78 KBC24.89 KBC24.116 LCD1.13 LCD1.16 LCD1.19 LCD1.23 LCD1.24 LCD1.25 LCD1.29 LCD1.36 LCD1.41 LCD1.42 LCD1.43 LCD1.44 LED1.3 ODD1.1 ODD1.4 ODD1.7 ODD1.18 ODD1.19 ODD1.20 ODD1.21 ODD1.22 ODD2.1 ODD2.2 ODD2.3 ODD2.14 ODD2.17 ODD2.20 ODD2.21 ODD2.22 PC1001.2 PC1002.2 PC1003.2 PC1004.2 PC1006.2 PC1007.2 PC1008.2 PC1009.2 PC1010.2 PC1011.2 PC1012.2 PC1013.2 PC1014.2 PC1015.2 PC1016.2 PC1017.2 PC1018.2 PC1019.2 PC1020.2 PC1021.2 PC1022.2 PC1023.2 PC1024.2 PC1025.2 PC1026.2 PC1027.2 PC1028.2 PC1030.2 PC1031.2 PC1032.2 PC1033.2 PC1034.2 PC1035.2 PC1036.2 PC1037.2 PC1038.2 PC1039.2 PC1040.2 PC1041.2 PC1042.2 PC1043.2 PC1044.2 PC1045.2 PC1046.2 PC1047.2 PC1048.2 PC1049.2 PC1050.2 PC1051.2 PC1052.2 PC1101.2 PC1102.2 PC1103.2 PC4302.2 PC4303.2 PC4304.2 PC4305.2 PC4306.2 PC4401.2 PC4406.2 PC4407.2 PC4408.2 PC4409.2 PC4415.2 PC4416.2 PC4417.2 PC4418.2 PC4419.2 PC4425.2 PC4426.2 PC4435.2 PC4501.2 PC4509.2 PC4517.2 PC4518.2 PC4519.2 PC4520.2 PC4524.2 PC4525.2 PC4526.2 PC4527.2 PC4528.2 PC4529.2 PC4530.2 PC4531.2 PC4536.2 PC5003.2 PC5004.2 PC5005.2 PC5006.2 PC5007.2 PC5008.2 PC5009.2 PC5010.2 PC5011.2 PC5013.2 PC5015.2 PC5017.2 PC5018.2 PC5019.2 PC5020.2 PC5021.2 PC5022.2 PC5023.2 PC5024.2 PC5025.2 PC5026.2 PC5027.2 PC5028.2 PC5029.2 PC5030.2 PC5031.2 PC5032.2 PC5034.2 PC5035.2 PC5036.2 PC5101.2 PC5102.2 PC5103.2 PC5104.2 PC5107.2 PC5108.2 PC5109.2 PC5110.2 PC5112.2 PC5113.2 PC5114.2 PC5117.2 PC5118.2 PC5119.2 PC5120.2 PC5123.2 PC5124.2 PC5126.2 PC5127.2 PC5128.2 PC5129.2 PC5130.2 PC5131.2 PD4301.A PD4302.1 PD4303.3 PD4304.A PG4411.2 PQ4302.E PQ4304.E PQ4306.1 PQ4306.4 PQ4402.1 PQ4402.4 PQ4408.1 PQ4408.4 PQ4410.1 PQ4410.4 PQ4414.S PR4302.2 PR4308.2 PR4313.2 PR4405.2 PR4432.2 PR4433.2 PR4436.2 PR4464.2 PR4470.2 PR4471.1 PR4474.2 PR4517.2 PR4523.2 PR4526.2 PR4530.2 PR4531.2 PR5012.1 PR5014.1 PR5018.1 PR5021.2 PR5024.2 PR5036.2 PR5102.2 PR5112.2 PR5114.2 PT4501.2 PT4502.2 PT5101.2 PT5102.2 PT5103.2 PU4404.14 PU4406.1 PU4406.2 PU4406.3 PU4502.1 PU4502.2 PU4502.3 PU4503.21 PU4505.1 PU4505.2 PU4505.3 PU5001.7 PU5001.53 PU5101.1 PU5101.2 PU5101.3 PU5104.1 PU5104.2 PU5104.3 PU5105.5 PU5105.6 PU5105.7 PU5106.6 PU5106.9 PU5107.6 PU5107.9 PU5108.6 PU5108.9 PWR1.4 PWR1.5 PWR1.6 PWSW2.1 PWSW2.2 PWSW2.5 PWSW2.6 Q1801.S Q1802.S Q2401.C Q2402.S Q2403.1 Q2403.4 Q2502.S Q2906.E Q2908.E Q4001.1 Q4001.4 Q4002.1 Q4002.4 Q4003.1 Q4003.4 Q5503.S Q5702.S Q5703.S Q6501.S Q6505.S Q7001.1 Q7001.4 R803.1 R808.1 R1201.1 R1211.2 R1212.2 R1213.1 R1502.2 R1504.2 R1505.2 R1507.2 R1508.2 R1510.2 R1511.2 R1513.2 R1515.2 R1516.2 R1517.2 R1519.2 R1526.2 R1702.1 R1807.1 R1813.2 R1814.2 R1816.1 R1826.2 R1827.2 R1828.2 R2001.1 R2002.1 R2003.1 R2004.1 R2005.1 R2006.1 R2007.1 R2008.1 R2009.1 R2010.1 R2011.1 R2012.2 R2020.2 R2023.2 R2025.2 R2028.2 R2101.2 R2419.2 R2438.2 R2440.1 R2442.2 R2443.2 R2468.2 R2507.2 R2509.1 R2516.2 R2611.2 R2717.2 R2725.2 R2727.2 R2728.2 R2928.2 R3601.2 R4301.1 R5501.1 R5502.1 R5503.1 R5517.2 R5520.2 R5526.1 R5528.1 R5537.2 R5702.1 R6008.1 R6016.2 R6017.1 R6020.2 R6021.1 R6024.1 R6505.2 R6507.2 R6513.2 R6601.1 R6602.1 R6603.2 R7005.1 R7011.2 R9906.2 R9917.2 R9921.2 RTC1.2 SPI251.4 SPI252.4 SPK1.5 SPK1.6 SPR1.1 SPR2.1 SPR3.1 SPR4.1 SPR5.1 TP1.5 TP1.9 TP1.10 U1801.3 U2404.2 U2601.5 U3601.2 U3602.2 U4001.11 U4001.15 U4002.5 U4002.9 U4003.3 U4004.3 U5501.2 U6001.3 U6001.13 U6001.18 U6001.21 U6301.A6 U6301.C4 U6301.E7 U6301.G5 U6301.H10 U6301.J5 U6301.K8 U6301.N2 U6301.N5 U6301.P4 U6301.P6 U7001.5 U7001.6 U7001.7 U7001.8 USB1.4 USB1.7 USB1.10 USB1.11 USB1.12 USB1.13 USB2.4 USB2.7 USB2.10 USB2.11 USB2.12 USB2.13 WLAN1.1 WLAN1.7 WLAN1.18 WLAN1.33 WLAN1.39 WLAN1.45 WLAN1.51 WLAN1.57 WLAN1.63 WLAN1.69 WLAN1.75 WLAN1.76 WLAN1.77 X1801.2 X1801.3 X1901.2 X1901.4 XDP1.16 XDP1.57 XDP1.58 XDP1.61 XDP1.62 XDP1.63 XDP1.64
GND_R1: IOBD1.9 R6601.2
GND_R2: IOBD1.17 R6602.2
V3D3_STB: HDA27.20 R2710.1
VSS_VCCGI: CPU1.R43 PR5013.1
0D675V_S0_DISCHG: Q4001.3 R4003.2
0D675V_VREF_S0: C1207.1 C1208.1 C1209.1 C1210.1 C1212.1 C1220.1 DM1.203 DM1.204 PG5014.1 R4003.1
1D05V_FHV0: CPU1.T13 R609.1
1D05V_FHV1: CPU1.T15 R608.1
1D05V_FUSE: CPU1.P16 R610.1
1D05V_IO_3PHASEIO: C1001.1 C1002.1 C1003.1 C1004.1 CPU1.AA22 CPU1.AA23 CPU1.AC23 CPU1.V18 CPU1.Y18 CPU1.Y20 PC1008.1 R607.1
1D05V_PCH: C1005.1 C1006.1 C1007.1 C1008.1 CPU1.AA25 CPU1.AC25 CPU1.AE25 CPU1.U20 CPU1.U22 CPU1.U23 CPU1.U25 CPU1.V22 CPU1.V23 CPU1.V25 CPU1.Y23 CPU1.Y25 PC1040.1 PC1041.1 R701.2
1D05V_S0: EC8927.1 EC8929.1 PG5003.2 PG5004.2 PG5005.2 R607.2 R608.2 R609.2 R610.2 R701.1
1D8V_PCH: C1101.1 C1102.1 C1103.1 C1104.1 CPU1.AA46 CPU1.AC42 CPU1.AC44 CPU1.AC46 CPU1.AE42 CPU1.AE44 CPU1.AE46 CPU1.AG25 PC1101.1 R702.2
1D8V_S0: Q2101.G Q5701.2 Q5701.5 Q6301.G R804.1 R805.1 R2018.1 R2019.1 R2024.1 R2029.1 R2106.2 R2115.1 R2125.2 R2511.1 R2705.1 R2724.1 R2729.1 R4012.1 R4049.2 R4050.2 R5514.1 R5530.1 R5532.1 R6408.2 R7003.1 R7007.1 R7008.1 RN801.3(B) RN801.4(B)
1D8V_S0_DISCHG: Q4003.3 R4012.2
1D8V_S0_EN: C4011.1 R4005.2 U4002.3
1D8V_S0_SIP: C4030.1 R4049.1 U4002.7 U4002.8
1D8V_S5: C2439.1 C2446.1 C4031.1 C9901.1 C9902.1 C9905.1 PC5034.1 PG5007.2 PG5008.2 PG5009.2 PR5016.1 PR5025.1 PR5044.1 PU5001.17 Q1901.2 Q1901.5 Q1903.2 Q1903.5 Q1904.2 Q1904.5 Q2102.G Q6508.G R702.1 R1501.1 R1503.1 R1506.1 R1509.1 R1512.1 R1514.1 R1518.1 R1520.1 R1521.1 R1522.1 R1523.1 R1524.1 R1525.1 R1703.2 R1806.1 R1812.2 R1815.2 R1819.2 R1833.2 R1834.2 R2114.2 R2119.2 R2120.1 R2421.1 R2436.1 R2497.1 R2522.1 R2523.2 R2529.2 R2530.2 R2532.1 R2533.2 R2534.2 R2535.1 R5527.1 R5536.1 R5703.1 R6322.2 R9904.1 R9905.1 RN802.3(B) RN802.4(B) RN1603.3(B) RN1603.4(B) RN1606.3(B) RN1606.4(B) RN1607.3(B) RN1607.4(B) RN1608.3(B) RN1608.4(B) RN1701.1(A) RN1701.2(A) RN1802.1(A) RN1802.2(A) RN1904.3(B) RN1904.4(B) RN1909.1(A) RN1909.2(A) RN1910.3(B) RN1910.4(B) RN2101.3(B) RN2101.4(B) U2404.1 U4002.1 U4002.2 XDP1.1 XDP1.12
1D24V_AUD_ISH_PLL: C1009.1 C1010.1 CPU1.AJ20 CPU1.AJ22 CPU1.AK22 PC1042.1 R603.2
1D24V_DSI_CSI: C1106.1 C1107.1 CPU1.AA18 CPU1.AA20 PC1102.1 R606.1
1D24V_GLML: C601.1 C1011.1 C1012.1 C1013.1 CPU1.AK20 CPU1.AM20 CPU1.AM28 CPU1.AM37 PC1043.1 R605.1
1D24V_MPHY: C1014.1 C1015.1 C1018.1 CPU1.AE18 CPU1.AE20 CPU1.AE22 CPU1.AG22 PC1046.1 R604.1
1D24V_S5: PG5011.2 PG5012.2 R602.2 R603.1 R604.2 R605.2 R606.2
1D24V_USB2: C1112.1 CPU1.AG20 R602.1
1D35V_CPU_VDDQ_S3: CPU1.AN18 CPU1.AN20 CPU1.AN22 CPU1.AN23 CPU1.AN41 CPU1.AN42 CPU1.AN44 CPU1.AN46 CPU1.AR17 CPU1.AR47 CPU1.AT13 CPU1.AT17 CPU1.AT47 CPU1.AT51 CPU1.AV14 CPU1.AV50 PC1001.1 PC1002.1 PC1003.1 PC1004.1 PC1027.1 PC1045.1 PC1047.1 PC1052.1 PC5010.1 PG5104.2 PG5105.2 PG5106.2 PG5121.1 PG5122.1 PG5123.1 PG5124.1 PG5125.1 PG5126.1 PG5127.2 PG5128.2 PG5129.2 PU5001.3 R4006.1
1D35V_DIMM_VDDQ_S3: C1201.1 C1202.1 C1203.1 C1205.1 C1206.1 C1211.1 C1213.1 C1214.1 C1215.1 C1216.1 C1217.1 C1218.1 DM1.75 DM1.76 DM1.81 DM1.82 DM1.87 DM1.88 DM1.93 DM1.94 DM1.99 DM1.100 DM1.105 DM1.106 DM1.111 DM1.112 DM1.117 DM1.118 DM1.123 DM1.124 EC8912.1 EC8913.1 EC8914.1 PG5107.2 PG5108.2 PG5109.2 PG5121.2 PG5122.2 PG5123.2 PG5124.2 PG5125.2 PG5126.2 R1207.1 R1208.1 RN1201.1(A)
1D35V_S3_DISCHG: Q4002.3 R4006.2
1P8U: PC5023.1 PU5001.18 R4050.1
3D3V_1D8V_GSEN2: C7001.1 C7002.1 R7001.1 R7003.2 R7004.1 U7001.10
3D3V_AUX_KBC: D4304.2 D4305.2 D4306.2 PR4412.1 PR4415.1 Q2404.D R2408.2 R2435.2 R2437.1 R2441.1 R2462.1 R2608.1 R2613.1 RN2402.1(A) RN2402.2(A) RN2404.1(A) RN2404.2(A) RN2406.3(B) RN2406.4(B)
3D3V_AUX_S5: C2442.2 KBC24.75 PR4417.1 PR4419.1 PR4434.1 PR4435.1 PR4438.2 PR4501.1 PR4505.2 PR4534.1 Q2404.S Q2501.2 R2405.1 R2489.2 R2491.2 R2515.2 R2518.1 R2612.1 R4002.1 R4009.2 R4011.1
3D3V_CAMERA_S0: AFTP5522.1 C5510.1 EC5507.1 F5502.2 LCD1.32 R5525.2
3D3V_G_VDD_S0: C7003.1 R7002.2 U7001.9
3D3V_LCDVDD_S0: C5515.1 R5507.2 U5501.3
3D3V_LCDVDD_S0_CONN: AFTP5523.1 C5502.1 C5509.2 C5536.2 C5538.1 LCD1.4 LCD1.5 LCD1.6 LCD1.7 R5507.1
3D3V_PWR: PC4517.1 PG4517.2 PG4522.2 PG4526.2 PG4528.2 PG4529.2 PG4535.1 PL4502.1 PT4502.1
3D3V_PWR_2: PC4526.1 PR4505.1 PU4503.3
3D3V_S0: C1223.1 C1224.1 C2601.1 C2602.1 C4004.1 C5516.1 C6009.1 C6010.1 C6012.1 DB1.10 DM1.199 EC4004.1 EC8915.1 EC8916.1 EC8917.1 EC8918.1 F5502.1 IOBD1.15 PR5030.1 Q1601.G Q1701.2 Q1701.5 Q1905.2 Q1905.5 Q2103.G Q2104.G Q2603.2 Q2603.5 R1606.1 R1921.2 R1922.2 R2116.1 R2123.1 R2126.1 R2400.1 R2427.1 R2430.1 R2445.1 R2472.1 R2512.1 R2605.1 R2606.1 R2708.1 R5515.1 R5522.1 R5525.1 R5529.1 R5531.1 R6005.2 R6007.2 R6012.1 R6013.2 R6014.2 R6022.1 R6105.1 R6517.1 R6520.2 R7002.1 R7006.1 RN1704.1(A) RN1704.2(A) RN1912.3(B) RN1912.4(B) RN2601.1(A) RN2601.2(A) U2601.1 U4001.13 U4001.14 U5501.4 U5501.5 U6001.7 U6001.10 U6001.20
3D3V_S0_CT: C4014.1 U4001.12
3D3V_S5: AFTP6402.1 C2445.1 C4002.1 C6401.1 EC4002.1 PD4302.2 PG4517.1 PG4522.1 PG4526.1 PG4528.1 PG4529.1 PR4304.1 PR4472.1 PR4473.2 PWR1.1 R601.2 R1605.1 R1701.1 R1808.2 R1811.2 R1823.1 R1824.2 R1832.1 R1835.1 R1836.1 R1923.2 R2122.1 R2124.1 R2426.1 R2439.1 R2471.1 R2473.1 R2710.2 R6106.1 R6327.2 R6521.2 R6525.1 RN1703.1(A) RN1703.2(A) RN1803.1(A) RN1803.2(A) RN1907.3(B) RN1907.4(B) RN1908.3(B) RN1908.4(B) RN1911.3(B) RN1911.4(B) RN2401.1(A) RN2401.2(A) U1801.5 U2404.6 U4001.1 U4001.2 U4003.5 U4004.5
3D3V_TP_S5_R: C6503.2 Q6504.S R6520.1 R6521.1
3D3V_USB: C1108.1 C1109.1 C1110.1 C1111.1 CPU1.AA42 CPU1.AC41 CPU1.AJ25 CPU1.AK25 CPU1.V44 CPU1.V46 CPU1.Y44 PC1103.1 R601.1
3D3V_VCCRTC: C1113.1 CPU1.AA44 R611.2
3D3V_WLAN_S0: AFTP6101.1 C6101.1 C6102.1 C6103.1 R6105.2 R6106.2 WLAN1.2 WLAN1.4 WLAN1.72 WLAN1.74
+DC_IN: EC8902.1 EL4301.2 EL4302.2 PC4301.1 PC4302.1 PD4301.K PQ4305.2 PR4307.1 PR4312.1 PR4314.1 PU4301.1 PU4301.2 PU4301.3
+DC_IN_C: AFTP4313.1 AFTP4314.1 DCIN1.1 DCIN1.2 DCIN2.5 DCIN2.6 EC4301.1 EC4302.1 EL4301.1 EL4302.1
+RTC_PWR: AFTP2502.1 R2527.2 RTC1.1
AC_DIS: KBC24.11 PQ4304.B PQ4306.5
AC_IN#: PC4401.1 PQ4408.5 PR4425.2 PR4433.1 PR4434.2 PU4404.5 R2500.1
AC_IN#_G: PQ4306.2 PR4312.2 PR4313.1
AC_IN_KBC: PQ4306.6 TP4301.1
AC_IN_KBC#: KBC24.65 R2462.2
AC_PRESENT: CPU1.AK49 R1813.1 R2505.2 RN1803.3(B)
AC_PRESENT_KBC: KBC24.113 R2505.1
AD+_G_1: PQ4402.5 PQ4402.6 PR4401.1
AD+_G_2: PR4401.2 PR4403.2 PU4402.4
AD+_TO_SYS: PG4402.1 PR4402.1 PR4403.1 PU4402.1 PU4402.2 PU4402.3
AD_IA: C2428.2 C2438.2 KBC24.97 PR4422.2
AD_IA_HW: KBC24.105 PQ4407.5
AD_IA_HW2: KBC24.9 PQ4407.2
AD_OFF_L: PQ4304.C PQ4305.1
AD_OFF_R: PC4301.2 PQ4305.3 PR4307.2 PR4308.1 PU4301.4
ALERT#: R2605.2 U2601.6
AMBER_LED_BAT: EC6402.1 Q6403.C R6407.1
AUD_AGND: AFTP2908.1 AFTP6611.1 C2702.1 C2705.1 C2710.2 C2711.2 C2712.1 C2713.2 C2715.2 C2721.2 C2901.2 EC2702.1 EC2703.1 EC2704.1 EC2705.1 EC2706.1 EC2905.2 EC2906.2 EC2907.2 EC2908.2 HDA27.25 HDA27.38 IOBD1.18 IOBD1.28 R2713.1 R2714.2 R2725.1 R2727.1 R2728.1 R2917.2 R2918.2 R6603.1
AUD_HP1_JACK_L: HDA27.32 R2908.1 R2920.2
AUD_HP1_JACK_L1: EC2907.1 R2907.1 R2908.2 R2912.2 R2917.1
AUD_HP1_JACK_R: HDA27.33 R2910.1 R2919.2
AUD_HP1_JACK_R1: EC2908.1 R2909.1 R2910.2 R2913.2 R2918.1
AUD_PC_BEEP_3246: HDA27.16 R2719.1
AUD_PC_BEEP_C: C2720.1 D2701.3 R2717.1
AUD_PC_BEEP_R: C2720.2 R2719.2
AUD_PORTA_L_R_B: AFTP6606.1 IOBD1.19 R2907.2
AUD_PORTA_R_R_B: AFTP6608.1 IOBD1.20 R2909.2
AUD_SENSE: AFTP2909.1 C2901.1 R2715.2 R2914.2
AUD_SENSE_A: HDA27.13 R2711.2 R2715.1
AUD_SPK_L+: EC2902.1 HDA27.42 R2902.2 R2922.1
AUD_SPK_L+_C: AFTP2902.1 R2902.1 SPK1.3
AUD_SPK_L+_R: C2908.1 C2909.1 Q2904.B Q2905.E R2921.1 R2922.2
AUD_SPK_L-: EC2901.1 HDA27.43 R2901.2 R2923.1
AUD_SPK_L-_C: AFTP2901.1 R2901.1 SPK1.4
AUD_SPK_L-_R: C2908.2 C2910.1 Q2904.E Q2905.B R2921.2 R2923.2
AUD_SPK_R+: EC2904.1 HDA27.45 R2904.2 R2915.1
AUD_SPK_R+_C: AFTP2904.1 R2904.1 SPK1.1
AUD_SPK_R+_R: C2906.1 C2907.1 Q2902.E Q2903.B R2915.2 R2930.1
AUD_SPK_R-: EC2903.1 HDA27.44 R2903.2 R2916.1
AUD_SPK_R-_C: AFTP2903.1 R2903.1 SPK1.2
AUD_SPK_R-_R: C2905.1 C2906.2 Q2902.B Q2903.E R2916.2 R2930.2
AUD_VREF: C2705.2 HDA27.28
AVS_DMIC_CLK: CPU1.P54 Q1904.4 RN1910.2(A)
AVS_DMIC_DATA: CPU1.M54 Q1904.1 RN1910.1(A)
BAT_AMBER: LED1.1 R6407.2
BAT_WHITE: LED1.2 R6406.2
BATT_WHITE_LED#: KBC24.118 R6404.1
BATT_WHITE_LED_R#: Q6401.D Q6404.B R6404.2
BEEP: KBC24.32 R2730.1
BKLGT_PWM: KBC24.62 Q6501.G R6505.1
BKLT_CTRL: D5502.3 R5510.1 R5526.2 RN5501.6(B)
BLON_OUT_C: AFTP5516.1 LCD1.21 R5501.2 R5519.2
BLUETOOTH_EN_KBC: AFTP6108.1 KBC24.83 R2472.2 WLAN1.54
BOARD_ID2: CPU1.T54 R2028.1 R2029.2
BOOST_MODE#: PR4418.1 PR4435.2
BOOT_HALT_N: R9904.2 R9909.1 XDP1.36
BT+: AFTP4302.1 AFTP4306.1 AFTP4307.1 BATT1.1 BATT1.2 BATT2.1 BATT2.2 EC4307.1 EC4308.1 EC8901.1 PC4415.1 PC4416.1 PC4417.1 PC4418.1 PC4419.1 PD4304.K PG4410.2 PR4416.2 PU4403.5 PU4403.6 PU4403.7 PU4403.8
BT+_R: PG4409.2 PL4401.2 PR4416.1
BT+_R_1: PC4435.1 PR4440.2
BT_USB20_N: CPU1.AB7 ER6103.2
BT_USB20_P: CPU1.AB6 ER6102.2
BVCCRTC_EXTPAD: C1805.1 CPU1.AG51
CAMERA_DET#: CPU1.AB54 R2018.2 R5505.2
CAMERA_DET#_R: LCD1.33 R5505.1
CAP_LED: AFTP6532.1 KB1.4 KB2.4 R6506.2
CAP_LED#: KBC24.109 R6508.1
CAP_LED_Q: Q6502.C R6506.1
CAP_LED_R#: Q6502.B R6508.2
CARD1_USB20_N: CPU1.AC10 EL6602.2
CARD1_USB20_P: CPU1.AC12 EL6602.3
CBN: C2703.1 HDA27.35
CBP: C2703.2 HDA27.37
CCD_USB20_N: CPU1.V7 TR5501.3
CCD_USB20_P: CPU1.V9 TR5501.2
CFG0: CPU1.B33 XDP1.19
CFG1: CPU1.C39 XDP1.21
CFG2: CPU1.B39 XDP1.23
CFG3: CPU1.B35 XDP1.25
CFG4: CPU1.A34 XDP1.27
CFG5: CPU1.B31 XDP1.29
CFG6: CPU1.H39 R9924.1
CFG7: CPU1.B29 R9919.1
CHG_AGND: PC4403.2 PC4404.2 PC4410.2 PC4412.2 PC4420.2 PC4422.2 PC4423.2 PG4411.1 PQ4407.1 PQ4407.4 PR4413.2 PR4423.2 PR4424.2 PR4431.2 PU4404.21
CHG_AMBER_LED#: KBC24.16 R6405.1
CHG_AMBER_LED_R#: Q6403.B R6405.2
CLK_TP_SIO: EC6503.1 KBC24.72 RN6503.1(A) RN6504.4(B)
CLKRUN#: KBC24.8 R1921.1 R1924.1
COMBO-GPI: HDA27.48 TP2701.1
COMP2: PC5014.1 PR5019.2
COMP2_P: PC5016.1 PR5020.2
CPVDD: C2701.1 C2714.1 HDA27.36 R2705.2
CPVEE: C2704.2 HDA27.34
CT#_U4002: C4033.1 U4002.6
DAT_TP_SIO: EC6501.1 KBC24.71 RN6503.2(A) RN6504.3(B)
DBC_EN: Q2104.S R2123.2 RN5501.8(B)
DBC_EN_C: CPU1.AC48 Q2104.D R2122.2
DBC_EN_R: AFTP5513.1 LCD1.8 RN5501.1(A)
DBG_CFG6: R9924.2 XDP1.31
DBG_CFG7: R9919.2 XDP1.33
DBG_I2C_SCL_LB: Q1903.3 R1912.1 RN1908.2(A) XDP1.48
DBG_I2C_SDA_LB: Q1903.6 R1911.1 RN1908.1(A) XDP1.50
DBG_PMU_PLTRST: R9926.1 XDP1.7 XDP1.38
DBG_PMU_PWRBTN: C9904.1 R9925.2 R9929.2 XDP1.40
DBG_PMU_RSTBTN: C9903.1 R9913.2 XDP1.6 XDP1.34
DBG_PTI_CLK0: R2117.2 XDP1.13
DBG_RSMRST: R9912.1 XDP1.42
DBG_TARGET_PRESENT_N: R9905.2 R9917.1 R9930.1 XDP1.15
DBG_UART_RXD: R9901.1 XDP1.56
DBG_XDP_PRDY#: R9918.2 XDP1.11
DBG_XDP_PREQ#: R9902.1 XDP1.10
DBG_XDP_TCK: R9916.2 XDP1.3
DBG_XDP_TDI: R9922.2 XDP1.5
DBG_XDP_TDO: R9920.1 XDP1.4
DBG_XDP_TMS: R9910.1 XDP1.2
DBG_XDP_TRST#: R9908.2 XDP1.9
DC_DET: Q2908.B R2707.2 R2733.2 R2929.2
DC_IN_D: PQ4402.3 PR4404.2
DDI0_RCOMP_N: CPU1.AG2 R801.1
DDI0_RCOMP_P: CPU1.AG1 R801.2
DDR_DRAMRST#: CPU1.AR34 ED1202.1 RN1201.3(B) RN1201.4(B)
DDR_DRAMRST#_R: DM1.30 ED1201.1 RN1201.2(A)
DFX_MSR_STRAP: R9906.1 XDP1.17
DGPU_PWROK: KBC24.124 TP2412.1
DIMM1_SA0: DM1.197 R1213.2
DIMM1_SA1: DM1.201 R1201.2
DMIC_CLK: C2722.2 EC5505.1 R2723.1 RN5502.4(B)
DMIC_CLK_C: AFTP5510.1 LCD1.27 R5534.1 RN5502.1(A)
DMIC_CLK_C#: Q1905.1 R5534.2 RN1912.1(A)
DMIC_CLK_D: Q1904.3 Q1905.6 RN1911.1(A)
DMIC_CLK_R: HDA27.3 R2723.2
DMIC_DATA: EC2709.2 EC5504.1 R2709.1 RN5502.3(B)
DMIC_DATA_C: AFTP5511.1 LCD1.28 R5535.1 RN5502.2(A)
DMIC_DATA_C#: Q1905.4 R5535.2 RN1912.2(A)
DMIC_DATA_D: Q1904.6 Q1905.3 RN1911.2(A)
DMIC_DATA_R: HDA27.2 R2709.2
DP_HPD0_C: AFTP5515.1 LCD1.9 R5502.2 R5518.1
DP_HPD0_G: Q5503.G R5518.2
E51_RX1: TP6102.1 WLAN1.46
E51_RX2: TP6101.1 WLAN1.58
E51_TX1: R6107.2 WLAN1.44
E51_TX2: R6108.2 WLAN1.38
E51_TXD: KBC24.111 R6107.1 R6108.1
EC_AGND: C2416.2 C2436.2 C2438.1 KBC24.103 R2507.1
EC_AVCC: C2416.1 C2436.1 KBC24.102 R2435.1
EC_BRIGHTNESS: D5502.2 KBC24.106
EC_MUTE#: KBC24.30 R2706.2 R2722.1
EC_SMI#: R1805.2 R1834.1 R2128.2 R2503.2
EC_SMI#_SOC: CPU1.E39 R2128.1
EC_SPI_CLK: KBC24.92 R2418.1
EC_SPI_CS0#: KBC24.90 R2416.1
EC_SPI_MISO: KBC24.86 R2528.1
EC_SPI_MOSI: KBC24.87 R2401.1
EC_VCC1V8: KBC24.88 R2497.2
EC_VTT: C2447.1 KBC24.12 R2430.2 R2509.2
ECRST#: C2444.1 KBC24.85 Q2401.E R2404.2 RN2402.4(B)
EDP_AUX_CON_N: AFTP5507.1 C5505.1 LCD1.12 R5515.2
EDP_AUX_CON_P: AFTP5506.1 C5504.1 LCD1.11 R5520.1
EDP_AUX_CPU_N: C5505.2 CPU1.AH9
EDP_AUX_CPU_P: C5504.2 CPU1.AH10
EDP_BLCTRL_CPU: CPU1.C46 Q5504.E R805.2 R5528.2
EDP_BLEN_CPU: CPU1.B47 R803.2 R804.2 R2444.2
EDP_HPD_CPU_D: CPU1.P48 Q5503.D R5514.2
EDP_RCOMP_N: CPU1.AG5 R802.2
EDP_RCOMP_P: CPU1.AG6 R802.1
EDP_TX_CON_N0: AFTP5504.1 C5513.1 LCD1.14
EDP_TX_CON_N1: AFTP5502.1 C5506.1 LCD1.17
EDP_TX_CON_P0: AFTP5505.1 C5512.1 LCD1.15
EDP_TX_CON_P1: AFTP5503.1 C5507.1 LCD1.18
EDP_TX_CPU_N0: C5513.2 CPU1.AG9
EDP_TX_CPU_N1: C5506.2 CPU1.AG10
EDP_TX_CPU_P0: C5512.2 CPU1.AG7
EDP_TX_CPU_P1: C5507.2 CPU1.AG12
EDP_VDDEN_CPU: CPU1.C47 Q5501.E R808.2 R2506.2 R5527.2
EMMC_CLK: CPU1.Y58 R2016.2 R6310.1
EMMC_CLK_R: R6310.2 U6301.M6
EMMC_CLK_RC: EC2001.1 R2016.1
EMMC_CMD: CPU1.Y51 R6311.1
EMMC_CMD_R: R6311.2 U6301.M5
EMMC_DATA_0: CPU1.V58 R6314.2
EMMC_DATA_0_R: R6314.1 U6301.A3
EMMC_DATA_1: CPU1.T58 R6325.2
EMMC_DATA_1_R: R6325.1 U6301.A4
EMMC_DATA_2: CPU1.T59 R6315.2
EMMC_DATA_2_R: R6315.1 U6301.A5
EMMC_DATA_3: CPU1.V51 R6319.2
EMMC_DATA_3_R: R6319.1 U6301.B2
EMMC_DATA_4: CPU1.V52 R6318.2
EMMC_DATA_4_R: R6318.1 U6301.B3
EMMC_DATA_5: CPU1.Y49 R6321.2
EMMC_DATA_5_R: R6321.1 U6301.B4
EMMC_DATA_6: CPU1.V55 R6320.2
EMMC_DATA_6_R: R6320.1 U6301.B5
EMMC_DATA_7: CPU1.V57 R6317.2
EMMC_DATA_7_R: R6317.1 U6301.B6
EMMC_E9: TP6301.1 U6301.E9
EMMC_E10: TP6302.1 U6301.E10
EMMC_F10: TP6303.1 U6301.F10
EMMC_K10: TP6304.1 U6301.K10
EMMC_RCLK: CPU1.V54 R2012.1 R2017.2 R6323.1
EMMC_RCLK_R: R6323.2 U6301.H5
EMMC_RCLK_RC: EC2002.1 R2017.1
EMMC_RCOMP: CPU1.V59 R2008.2
EMMC_RESET#: Q6301.S R2118.2 R2119.1 R2125.1 R6312.1 U6301.K5
EMMC_RST_N: CPU1.L30 R2118.1
EMMC_VCC: C6302.1 C6305.1 R6327.1 U6301.E6 U6301.F5 U6301.J10 U6301.K9
EMMC_VCCQ: C6303.1 C6304.1 R6322.1 U6301.C6 U6301.M4 U6301.N4 U6301.P3 U6301.P5
EMMC_VDDI: C6301.1 U6301.C2
FALL_INT2: Q7001.2 Q7001.3 R7006.2
FAN1_DAC_1: KBC24.101 TP2408.1
FAN_TACH1: KBC24.31 TP2410.1
FB_VCCGI: CPU1.R41 PR5005.1
FB_VNN: CPU1.AG48 PR5035.2
FBL_VCCGI: PG5101.1 PR5004.1
FBL_VDDQ: PG5102.1 PR5001.2
FBL_VNN: PG5103.1 PR5034.2
FFS_INT2: CPU1.A26 Q7001.5 R7007.2 R7010.1 R7011.1 U7001.11
FFS_INT2_Q: HDD1.1 Q7001.6 R7009.2 R7010.2
GFX_CLKREQ_CPU#: CPU1.AK62 RN1606.2(A)
GP_SSP0_FS1: CPU1.H52 R9909.2
GP_SSP2_TXD: CPU1.E62 R1525.2 R1526.1 R9930.2
GPIO34_CPU: CPU1.B41 TP2105.1
GPIO35_CPU: CPU1.C41 TP2104.1
GPIO36_VCCIO_LEVEL: CPU1.F41 R1501.2 R1502.1
GPIO39_TXE_BPS: CPU1.B45 R1503.2 R1504.1
GPIO40_CPU: CPU1.A46 TP1804.1
GPIO43_EMMC_BOOT: CPU1.B43 R1505.1 R1521.2 R1801.1
GPIO44_SPI_BOOT: CPU1.A42 R1506.2 R1507.1
GPIO47_DNXFW: CPU1.H41 R1508.1 R1509.2 R1802.1
GPIO78_SMB_LEVEL: CPU1.K62 R1510.1 R1522.2
GPIO82_CPU: CPU1.M55 TP1901.1
GPIO88_PMU_LEVEL: CPU1.M58 R1511.1 R1523.2
GPIO92_SMB_NRB: CPU1.L63 R1512.2 R1513.1
GPIO110_LPC_LEVEL: CPU1.J52 R1516.1 R1524.2
GPIO111_BBS: CPU1.F58 R1514.2 R1515.1
GPIO118_FLASH_OVR: CPU1.F62 R1517.1 R1518.2 R1909.1
GPIO120_BIOS_SWAP: CPU1.E56 R1519.1 R1520.2
GPIO_RCOMP: CPU1.E34 R2006.2
GSENSOR_CS: R7001.2 U7001.2
GSENSOR_SDO: R7004.2 R7005.2 U7001.3
H_A20GATE: KBC24.121 R2445.2
H_PROCHOT#: PR4426.2 PR4465.1 PR4466.2 Q2402.D R1809.1
H_PROCHOT_EC: KBC24.24 Q2402.G R2442.1
H_RCIN#: KBC24.122 R2400.2
HDA_BITCLK_CPU: CPU1.AM48 R2107.2
HDA_CODEC_BITCLK: EC2102.1 EC2708.1 HDA27.6 R2107.1
HDA_CODEC_SDIN0: HDA27.8 R2101.1 R2121.2 R2721.2
HDA_CODEC_SDOUT: HDA27.5 R2104.1
HDA_CODEC_SYNC: HDA27.10 R2105.1
HDA_SDIN0_CPU: CPU1.AK51 R2721.1
HDA_SDOUT_CPU: CPU1.AM54 R2104.2
HDA_SPKR: CPU1.AK57 R2718.1
HDA_SPKR_R: D2701.2 R2718.2
HDA_SYNC_CPU: CPU1.AK58 R2105.2 R2121.1
HDD_DEVSLP: Q2101.D R2116.2 R6001.1
HDD_DEVSLP_R: HDD1.5 R6001.2
HDD_DEW1: R6012.2 R6016.1 U6001.16
HDD_DEW2: R6020.1 R6022.2 U6001.6
HDD_FALL_INT: CPU1.B37 R7008.2 U7001.12
HDD_SATA_RX_N: C6018.2 CPU1.T7 R6015.1
HDD_SATA_RX_P: C6015.2 CPU1.T9 R6023.1
HDD_SATA_TX_N: C6014.1 CPU1.Y2 R6010.1
HDD_SATA_TX_P: C6013.1 CPU1.Y3 R6011.1
HDMI_CLK_CON: ED5703.4 ED5703.7 HDMI1.15 Q5701.3 RN5701.2(A)
HDMI_CLK_CPU: CPU1.B49 Q5701.4 RN801.1(A) RN802.1(A)
HDMI_DATA_CON: ED5703.2 ED5703.9 HDMI1.16 Q5701.6 RN5701.1(A)
HDMI_DATA_CON_N0: C5703.2 ED5702.4 ED5702.7 HDMI1.9 R5704.2 RN5703.2(A)
HDMI_DATA_CON_N1: C5705.2 ED5701.1 ED5701.10 HDMI1.6 R5705.2 RN5702.4(A)
HDMI_DATA_CON_N2: C5707.2 ED5701.4 ED5701.7 HDMI1.3 R5706.2 RN5702.2(A)
HDMI_DATA_CON_N3: C5701.2 ED5702.1 ED5702.10 HDMI1.12 R5707.2 RN5703.4(A)
HDMI_DATA_CON_P0: C5704.2 ED5702.5 ED5702.6 HDMI1.7 R5704.1 RN5703.1(A)
HDMI_DATA_CON_P1: C5706.2 ED5701.2 ED5701.9 HDMI1.4 R5705.1 RN5702.3(A)
HDMI_DATA_CON_P2: C5708.2 ED5701.5 ED5701.6 HDMI1.1 R5706.1 RN5702.1(A)
HDMI_DATA_CON_P3: C5702.2 ED5702.2 ED5702.9 HDMI1.10 R5707.1 RN5703.3(A)
HDMI_DATA_CPU: CPU1.C49 Q5701.1 RN801.2(A) RN802.2(A)
HDMI_DATA_CPU_N0: C5703.1 CPU1.AH2
HDMI_DATA_CPU_N1: C5705.1 CPU1.AM2
HDMI_DATA_CPU_N2: C5707.1 CPU1.AK2
HDMI_DATA_CPU_N3: C5701.1 CPU1.AL1
HDMI_DATA_CPU_P0: C5704.1 CPU1.AH3
HDMI_DATA_CPU_P1: C5706.1 CPU1.AM3
HDMI_DATA_CPU_P2: C5708.1 CPU1.AK3
HDMI_DATA_CPU_P3: C5702.1 CPU1.AL2
HDMI_DET_CPU#: CPU1.C50 Q5703.D R5703.2
HDMI_HPD_G: Q5703.G R5701.2
HDMI_PLL_GND: Q5702.D RN5702.5(B) RN5702.6(B) RN5702.7(B) RN5702.8(B) RN5703.5(B) RN5703.6(B) RN5703.7(B) RN5703.8(B)
HPD_HDMI_CON: ED5703.1 ED5703.10 HDMI1.19 R5701.1 R5702.2
I2C3_SCL_CPU: CPU1.AL62 Q1901.1 RN1904.2(A)
I2C3_SDA_CPU: CPU1.AM62 Q1901.4 RN1904.1(A)
I2C7_SCL_CPU: CPU1.AP61 Q1903.4 R1912.2 RN1909.3(B)
I2C7_SDA_CPU: CPU1.AP62 Q1903.1 R1911.2 RN1909.4(B)
INT_SERIRQ: CPU1.AB62 R1919.2
INT_SERIRQ_KBC: C2401.1 KBC24.125 R2436.2 R2508.2 U2404.3
INT_SERIRQ_OE: R2419.1 R2421.2 U2404.5
INT_SPK_1: Q2906.C R2925.2
INT_SPK_R: Q2907.B R2924.2 R2925.1
INT_TP#_CONN: AFTP6525.1 Q6509.S R6514.1 R6524.2 TP1.4
INTRUDER: CPU1.AC54 R1816.2 R1817.2
JACK_PLUG: AFTP6607.1 IOBD1.27 R2914.1
JDREF: HDA27.15 R2714.1
JGND: AFTP4301.1 AFTP4315.1 DCIN1.5 DCIN1.6 DCIN2.1 DCIN2.2 EC4301.2 EC4302.2 EL4303.1 EL4304.1
JTAG_PMODE: CPU1.B19 TP1803.1
KB_BL_CTRL#: AFTP6567.1 KBBL1.4 Q6501.D
KB_DET#: AFTP6519.1 CPU1.AC51 KB1.30 KB2.30 RN1803.4(B)
KB_LED_BL_DET_R: CPU1.C38 R6503.1 R6507.1
KB_LED_DET_C: AFTP6566.1 C6502.1 KBBL1.2 R6503.2
KBC_BEEP_R: D2701.1 R2730.2
KBC_ON#_GATE: C2442.1 Q2403.2 Q2403.5 Q2404.G R2492.2
KBC_ON#_GATE_L: R2491.1 R2492.1 R2493.2
KBC_PECI: KBC24.13 TP2407.1
KBC_PWRBTN#: R2499.1 R9925.1 RN6401.2(A)
KBC_PWRBTN#_C: AFTP6404.1 EC6403.1 ED6401.1 G6401.2 G6402.2 PWR1.2 PWSW2.3 PWSW2.4 RN6401.3(B)
KBC_VBKUP: KBC24.114 R2425.1
KBC_VCC: C2414.1 C2429.1 C2430.1 C2431.1 C2440.1 C2441.1 KBC24.19 KBC24.46 KBC24.76 KBC24.115 R2408.1
KBC_VCC1D8V: C2432.1 C2433.1 KBC24.4 R2511.2 R2512.2
KBC_VCORF: C2443.1 KBC24.44
KSI0: AFTP6507.1 KB1.22 KB2.22 KBC24.54
KSI1: AFTP6540.1 KB1.24 KB2.24 KBC24.55
KSI2: AFTP6533.1 KB1.26 KB2.26 KBC24.56
KSI3: AFTP6502.1 KB1.23 KB2.23 KBC24.57
KSI4: AFTP6521.1 KB1.27 KB2.27 KBC24.58
KSI5: AFTP6513.1 KB1.25 KB2.25 KBC24.59
KSI6: AFTP6511.1 KB1.28 KB2.28 KBC24.60
KSI7: AFTP6523.1 KB1.29 KB2.29 KBC24.61
KSO0: AFTP6520.1 KB1.13 KB2.13 KBC24.53
KSO1: AFTP6517.1 KB1.15 KB2.15 KBC24.52
KSO2: AFTP6510.1 KB1.14 KB2.14 KBC24.51
KSO3: AFTP6518.1 KB1.16 KB2.16 KBC24.50
KSO4: AFTP6522.1 KB1.20 KB2.20 KBC24.49
KSO5: AFTP6536.1 KB1.21 KB2.21 KBC24.48
KSO6: AFTP6512.1 KB1.18 KB2.18 KBC24.47
KSO7: AFTP6534.1 KB1.19 KB2.19 KBC24.43
KSO8: AFTP6505.1 KB1.17 KB2.17 KBC24.42
KSO9: AFTP6516.1 KB1.7 KB2.7 KBC24.41
KSO10: AFTP6503.1 KB1.5 KB2.5 KBC24.40
KSO11: AFTP6506.1 KB1.6 KB2.6 KBC24.39
KSO12: AFTP6538.1 KB1.12 KB2.12 KBC24.38
KSO13: AFTP6535.1 KB1.9 KB2.9 KBC24.37
KSO14: AFTP6539.1 KB1.8 KB2.8 KBC24.36
KSO15: AFTP6515.1 KB1.10 KB2.10 KBC24.35
KSO16: AFTP6508.1 KB1.11 KB2.11 KBC24.34
L_BKLT_CTRL: D5502.1 Q5504.C R5510.2 R5529.2
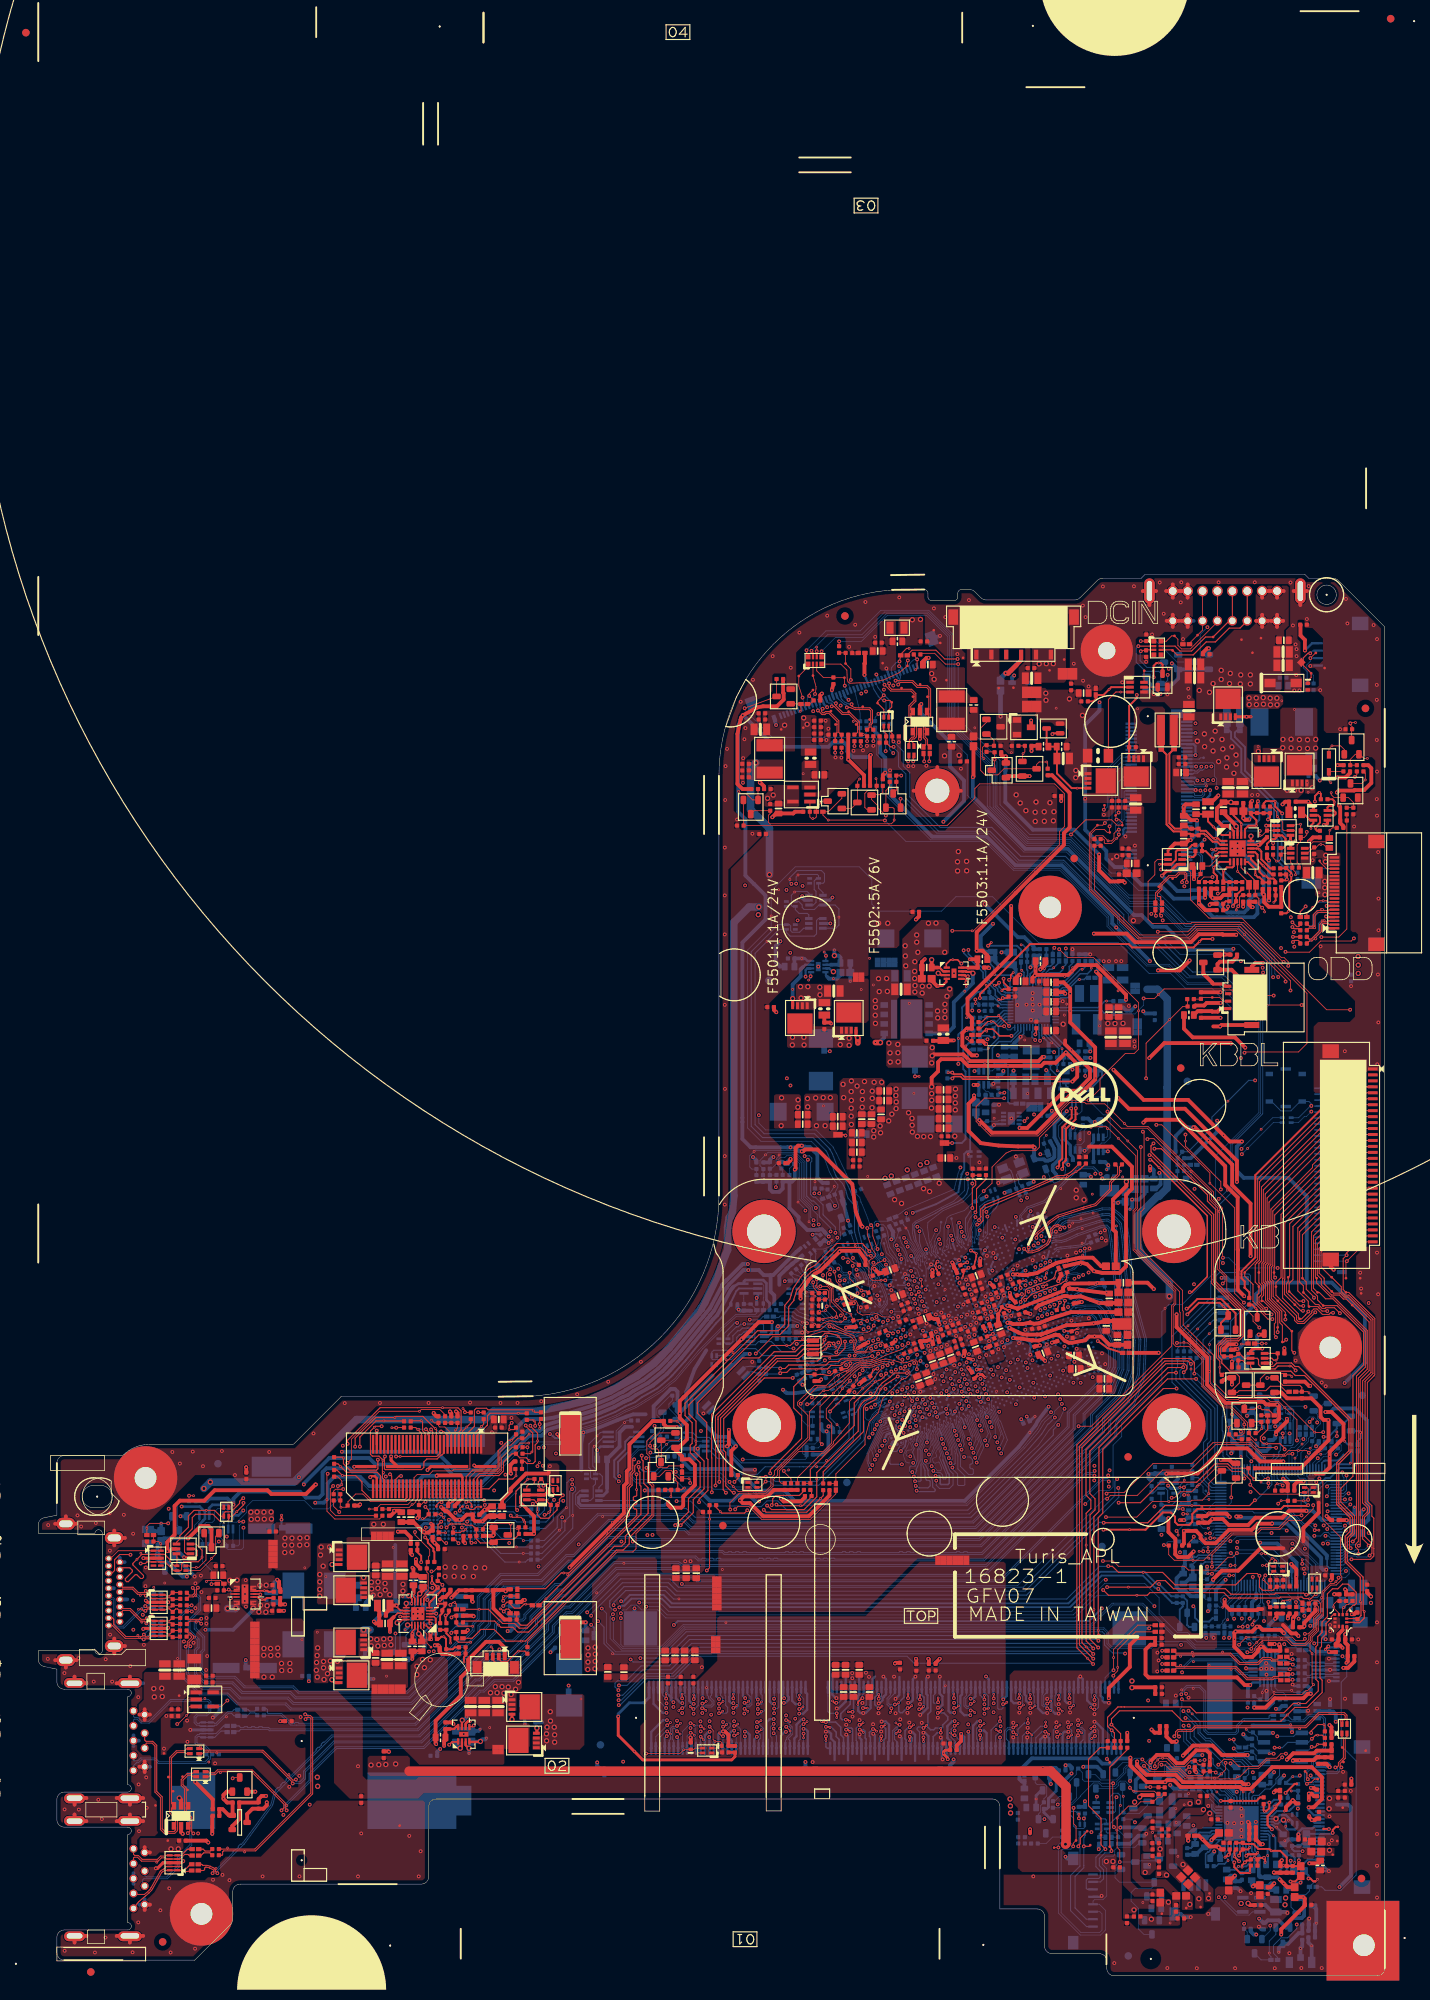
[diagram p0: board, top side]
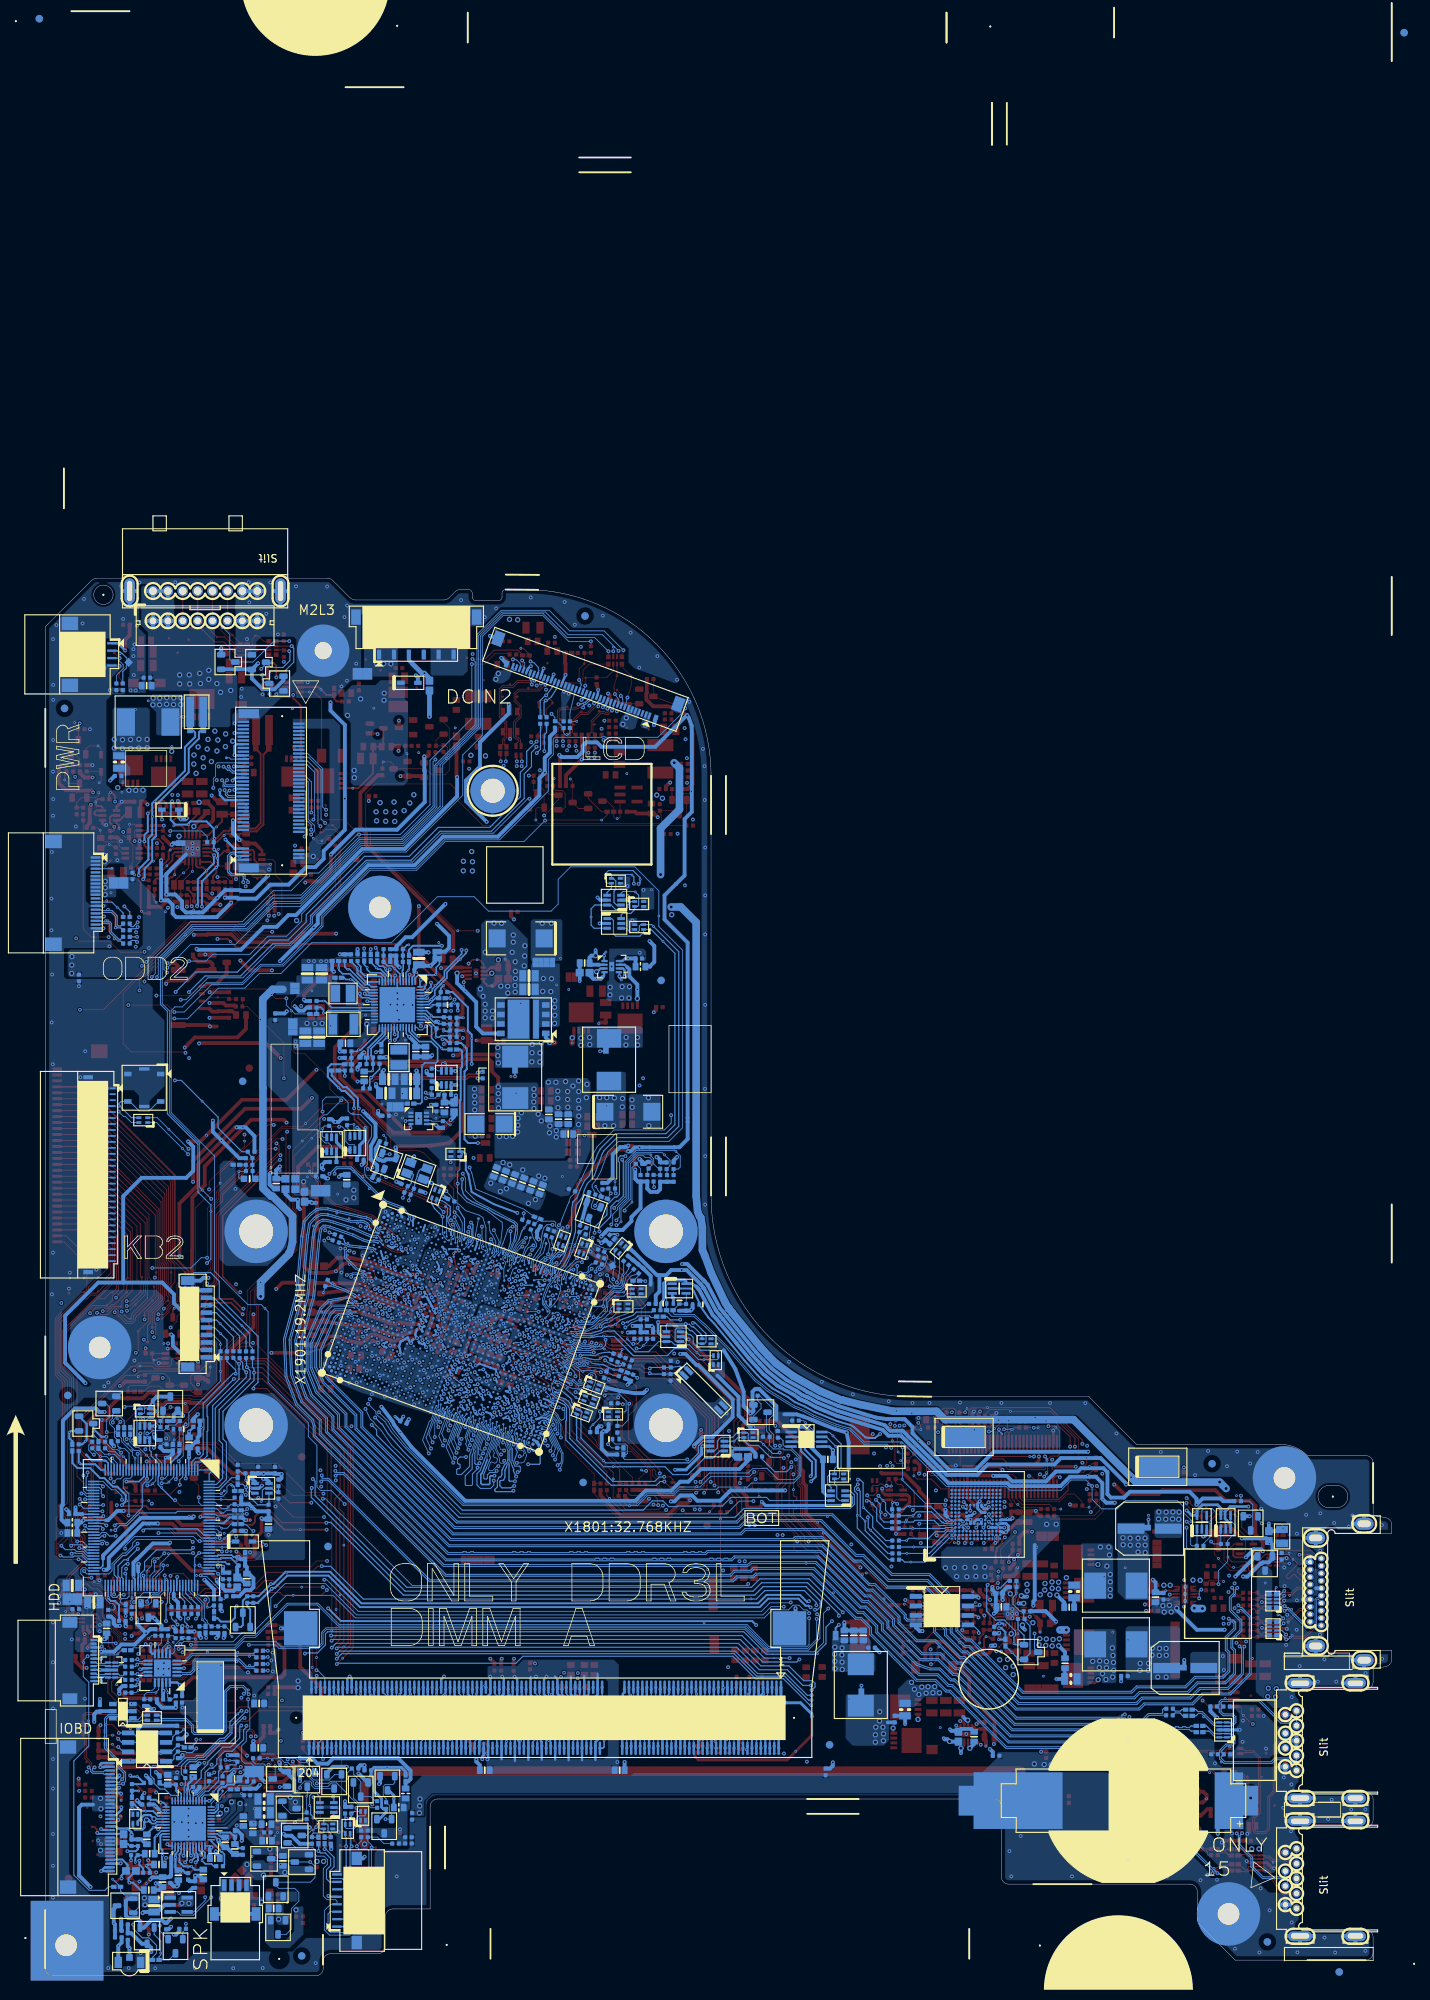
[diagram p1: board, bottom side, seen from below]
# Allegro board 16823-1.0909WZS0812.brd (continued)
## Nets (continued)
L_BKLT_CTRL_B: Q5504.B R5530.2
L_BKLT_EN_EC: KBC24.22 R2444.1
LAN_CLKREQ_CPU#: CPU1.AJ62 RN1603.2(A)
LCD_BRIGHTNESS: AFTP5517.1 EC5506.1 LCD1.20 RN5501.3(A)
LCD_TST: R2498.1 RN5501.7(B)
LCD_TST_C: AFTP5514.1 LCD1.10 RN5501.2(A)
LCD_TST_EN: D5501.2 KBC24.28 R5504.1
LCD_TST_KBC: KBC24.123 R2498.2
LDO1_CAP: C2702.2 HDA27.27 R2713.2
LDO2_CAP: C2712.2 HDA27.39
LDO3_CAP: C2718.1 HDA27.7
LID_CLOSE#: D2401.K KBC24.107 R2473.2 RN6401.1(A)
LID_CLOSE#_C: AFTP6401.1 EC6401.1 PWR1.3 RN6401.4(B)
LINE1-L_C: C2903.2 R2920.1
LINE1-L_R: C2904.2 R2919.1
LINE1_L: C2903.1 HDA27.22
LINE1_R: C2904.1 HDA27.21
LINE1_VREFO_L: HDA27.31 R2912.1
LINE1_VREFO_R: HDA27.30 R2913.1
LPC_AD_CPU_P0: KBC24.126 R9923.1 RN1905.5(B)
LPC_AD_CPU_P1: KBC24.127 R9928.1 RN1905.6(B)
LPC_AD_CPU_P2: KBC24.128 R9931.1 RN1905.7(B)
LPC_AD_CPU_P3: KBC24.1 R9932.1 RN1905.8(B)
LPC_CLK_CPU_P0: CPU1.AB61 R1905.2
LPC_CLK_CPU_P1: CPU1.AA62 R1908.2
LPC_CLK_DBG: DB1.2 EC1902.1 R1905.1
LPC_CLK_KBC: EC1901.1 KBC24.2 R1908.1
LPC_FRAME#_CPU: CPU1.V61 KBC24.3 R9915.1
LPC_FRAME#_DEBUG: DB1.5 R9915.2
LPC_LAD0_C: DB1.9 R9923.2
LPC_LAD0_R: CPU1.Y61 RN1905.4(A)
LPC_LAD1_C: DB1.8 R9928.2
LPC_LAD1_R: CPU1.Y62 RN1905.3(A)
LPC_LAD2_C: DB1.7 R9931.2
LPC_LAD2_R: CPU1.W62 RN1905.2(A)
LPC_LAD3_C: DB1.6 R9932.2
LPC_LAD3_R: CPU1.W63 RN1905.1(A)
LPSS_UART1_TXD: R1801.2 XDP1.54
LVDS_VDD_EN: D5501.1 Q5501.C R5531.2
LVDS_VDD_EN_B: Q5501.B R5532.2
LVDS_VDD_EN_KBC: KBC24.20 R2506.1
LVDS_VDD_EN_R: D5501.3 R5503.2 R5504.2 U5501.1
M_A_A0: CPU1.BG50 DM1.98
M_A_A1: CPU1.BG51 DM1.97
M_A_A2: CPU1.BH51 DM1.96
M_A_A3: CPU1.BD41 DM1.95
M_A_A4: CPU1.BE41 DM1.92
M_A_A5: CPU1.BJ52 DM1.91
M_A_A6: CPU1.BG53 DM1.90
M_A_A7: CPU1.BG55 DM1.86
M_A_A8: CPU1.BH53 DM1.89
M_A_A9: CPU1.BG52 DM1.85
M_A_A10: CPU1.BH49 DM1.107
M_A_A11: CPU1.BH55 DM1.84
M_A_A12: CPU1.BG54 DM1.83
M_A_A13: CPU1.BG46 DM1.119
M_A_A14: CPU1.BG56 DM1.80
M_A_A15: CPU1.BG57 DM1.78
M_A_BS0: CPU1.BJ48 DM1.109
M_A_BS1: CPU1.BG49 DM1.108
M_A_BS2: CPU1.BH57 DM1.79
M_A_CAS#: CPU1.BH47 DM1.115
M_A_CKE0: CPU1.BH61 DM1.73
M_A_CKE1: CPU1.BH60 DM1.74
M_A_CLK0: CPU1.BD45 DM1.101
M_A_CLK1: CPU1.BB48 DM1.102
M_A_CLK#0: CPU1.BE45 DM1.103
M_A_CLK#1: CPU1.BD48 DM1.104
M_A_CS#0: CPU1.AR43 DM1.114
M_A_CS#1: CPU1.BA41 DM1.121
M_A_DQ0: CPU1.AY62 DM1.41
M_A_DQ1: CPU1.AY61 DM1.42
M_A_DQ2: CPU1.BE62 DM1.53
M_A_DQ3: CPU1.BG62 DM1.52
M_A_DQ4: CPU1.BD63 DM1.51
M_A_DQ5: CPU1.AW62 DM1.39
M_A_DQ6: CPU1.AW63 DM1.40
M_A_DQ7: CPU1.BD62 DM1.50
M_A_DQ8: CPU1.AV59 DM1.33
M_A_DQ9: CPU1.AU63 DM1.22
M_A_DQ10: CPU1.AU62 DM1.21
M_A_DQ11: CPU1.AV58 DM1.35
M_A_DQ12: CPU1.AV57 DM1.34
M_A_DQ13: CPU1.AT55 DM1.23
M_A_DQ14: CPU1.AT54 DM1.24
M_A_DQ15: CPU1.AY59 DM1.36
M_A_DQ16: CPU1.AY57 DM1.6
M_A_DQ17: CPU1.BB57 DM1.15
M_A_DQ18: CPU1.BD59 DM1.17
M_A_DQ19: CPU1.BF59 DM1.16
M_A_DQ20: CPU1.AV54 DM1.5
M_A_DQ21: CPU1.AY55 DM1.7
M_A_DQ22: CPU1.AV52 DM1.4
M_A_DQ23: CPU1.BD58 DM1.18
M_A_DQ24: CPU1.BE56 DM1.57
M_A_DQ25: CPU1.BD54 DM1.59
M_A_DQ26: CPU1.BF58 DM1.58
M_A_DQ27: CPU1.BE50 DM1.70
M_A_DQ28: CPU1.BD50 DM1.68
M_A_DQ29: CPU1.BB50 DM1.67
M_A_DQ30: CPU1.BA50 DM1.69
M_A_DQ31: CPU1.BB54 DM1.56
M_A_DQ32: CPU1.AR39 DM1.129
M_A_DQ33: CPU1.AV37 DM1.143
M_A_DQ34: CPU1.AW37 DM1.140
M_A_DQ35: CPU1.AR37 DM1.141
M_A_DQ36: CPU1.AT37 DM1.132
M_A_DQ37: CPU1.AT41 DM1.130
M_A_DQ38: CPU1.AR41 DM1.131
M_A_DQ39: CPU1.AW35 DM1.142
M_A_DQ40: CPU1.BJ44 DM1.147
M_A_DQ41: CPU1.BG39 DM1.158
M_A_DQ42: CPU1.BG40 DM1.157
M_A_DQ43: CPU1.BJ40 DM1.159
M_A_DQ44: CPU1.BG43 DM1.146
M_A_DQ45: CPU1.BG44 DM1.148
M_A_DQ46: CPU1.BH45 DM1.149
M_A_DQ47: CPU1.BH41 DM1.160
M_A_DQ48: CPU1.BA34 DM1.176
M_A_DQ49: CPU1.BE34 DM1.175
M_A_DQ50: CPU1.BD34 DM1.177
M_A_DQ51: CPU1.BD37 DM1.164
M_A_DQ52: CPU1.BB37 DM1.166
M_A_DQ53: CPU1.BE39 DM1.163
M_A_DQ54: CPU1.BD39 DM1.165
M_A_DQ55: CPU1.BB34 DM1.174
M_A_DQ56: CPU1.BJ38 DM1.181
M_A_DQ57: CPU1.BG34 DM1.194
M_A_DQ58: CPU1.BG33 DM1.191
M_A_DQ59: CPU1.BH33 DM1.192
M_A_DQ60: CPU1.BG38 DM1.180
M_A_DQ61: CPU1.BH37 DM1.183
M_A_DQ62: CPU1.BG37 DM1.182
M_A_DQ63: CPU1.BJ34 DM1.193
M_A_DQS_DN0: CPU1.BC62 DM1.45
M_A_DQS_DN1: CPU1.AT58 DM1.27
M_A_DQS_DN2: CPU1.BB58 DM1.10
M_A_DQS_DN3: CPU1.BB52 DM1.62
M_A_DQS_DN4: CPU1.AW39 DM1.135
M_A_DQS_DN5: CPU1.BG42 DM1.152
M_A_DQS_DN6: CPU1.BD35 DM1.169
M_A_DQS_DN7: CPU1.BH35 DM1.186
M_A_DQS_DP0: CPU1.BB63 DM1.47
M_A_DQS_DP1: CPU1.AT59 DM1.29
M_A_DQS_DP2: CPU1.BB59 DM1.12
M_A_DQS_DP3: CPU1.BD52 DM1.64
M_A_DQS_DP4: CPU1.AV39 DM1.137
M_A_DQS_DP5: CPU1.BJ42 DM1.154
M_A_DQS_DP6: CPU1.BB35 DM1.171
M_A_DQS_DP7: CPU1.BG36 DM1.188
M_A_ODT0: CPU1.AW43 DM1.116
M_A_ODT1: CPU1.AW41 DM1.120
M_A_RAS#: CPU1.BG47 DM1.110
M_A_VREFCA_CPU: CPU1.AR35 TP509.1
M_A_VREFDQ_CPU: CPU1.AT34 TP510.1
M_A_WE#: CPU1.BG48 DM1.113
MCSI_RCOMP_1: CPU1.H27 R2005.2
MCSI_RCOMP_2: CPU1.F27 R2007.2
MDSI_RCOMP: CPU1.AP7 R2009.2
ME_FWP_EC_CPU: KBC24.79 R1909.2
MIC2_VREFO: HDA27.29 RN2901.1(A) RN2901.2(A)
MIC_CAP: C2713.1 HDA27.19
MIC_GND: AFTP5512.1 LCD1.26 R5517.1
NCT_CLK: Q2603.1 RN2601.4(B) U2601.8
NCT_DATA: Q2603.4 RN2601.3(B) U2601.7
NMI_SMI_DBG#_CPU: CPU1.M41 R1805.1
ODD_PWR_5V: C6024.1 ODD1.10 ODD1.11 ODD1.12 ODD1.13 ODD1.14 ODD1.15 ODD2.6 ODD2.7 ODD2.8 ODD2.9 ODD2.10 ODD2.11 R6004.2
ODD_SATA_RX_C_N: C6003.1 ODD1.5
ODD_SATA_RX_C_N2: C6005.1 ODD2.16
ODD_SATA_RX_C_P: C6001.1 ODD1.6
ODD_SATA_RX_C_P2: C6007.1 ODD2.15
ODD_SATA_RX_N: C6003.2 C6005.2 CPU1.T6
ODD_SATA_RX_P: C6001.2 C6007.2 CPU1.T5
ODD_SATA_TX_C_N: C6002.1 ODD1.3
ODD_SATA_TX_C_N2: C6006.1 ODD2.18
ODD_SATA_TX_C_P: C6004.1 ODD1.2
ODD_SATA_TX_C_P2: C6008.1 ODD2.19
ODD_SATA_TX_N: C6002.2 C6006.2 CPU1.W2
ODD_SATA_TX_P: C6004.2 C6008.2 CPU1.W1
P2800_DXN: C2603.2 C2604.2 Q2601.E Q2604.E U2601.3
P2800_DXP: C2603.1 C2604.1 Q2601.B Q2601.C Q2604.B Q2604.C U2601.2
PANEL_BKEN_EC: R2414.1 R5519.1
PANEL_BKEN_EC_KBC: KBC24.27 R2414.2
PANEL_SIZE_ID: CPU1.T52 R5536.2 R5537.1 R5538.2
PANEL_SIZE_ID_CONN: LCD1.22 R5538.1
PBAT_PRES1#: AFTP4303.1 BATT1.5 BATT2.5 RN4302.8(B)
PBAT_PRES#: D4304.3 EC4306.2 KBC24.80 PC4433.1 PR4472.2 RN2402.3(B) RN4302.1(A)
PBAT_SMBCLK1: AFTP4304.1 BATT1.3 BATT2.3 RN4302.6(B)
PBAT_SMBDAT1: AFTP4308.1 BATT1.4 BATT2.4 RN4302.7(B)
PCB_VER_AD: C2417.1 KBC24.98 R2437.2 R2438.1
PCH_SMB_CLK: DM1.202 EC6505.1 Q1701.4 R6515.1 RN1704.3(B) U7001.1
PCH_SMB_DATA: DM1.200 EC6506.1 Q1701.1 R6511.1 RN1704.4(B) U7001.4
PCIE_CLKREQ1_CPU#: CPU1.AH62 RN1606.1(A)
PCIE_OBSN_CPU: CPU1.F5 R1601.1
PCIE_OBSP_CPU: CPU1.F6 R1601.2
PCIE_REF_CLK_RCOMP: CPU1.E21 R2001.2
PCIE_WAKE0_CPU: CPU1.R62 RN1608.2(A)
PCIE_WAKE0_CPU#: TP6103.1 WLAN1.55
PCIE_WAKE1_CPU: CPU1.P62 RN1608.1(A)
PCIE_WAKE2_CPU: CPU1.P61 RN1607.2(A)
PCIE_WAKE3_CPU: CPU1.N62 RN1607.1(A)
PD4404_A: PD4404.A PQ4409.B
PD4404_K: PD4404.K PR4468.2
PD#: HDA27.47 R2722.2
PEG_CLKREQ_WLAN#: Q1601.S R1606.2 R1607.1 WLAN1.53
PLT_RST#: AFTP6104.1 ED1807.1 KBC24.7 Q6301.D R1829.2 R5533.1 R6312.2 R9914.1 R9926.2 WLAN1.52
PLT_RST#_DEBUG: DB1.4 R9914.2
PLTRST#_CPU: CPU1.AG57 R1829.1 R1832.2
PM_BATLOW#: CPU1.AH51 R1823.2
PM_CLKRUN#_EC: CPU1.V62 R1924.2
PM_PWRBTN#: KBC24.117 R1804.2 R9929.1
PM_PWRBTN#_CPU: CPU1.AK55 R1804.1 R1824.1
PM_RSMRST#: CPU1.AC57 ED1805.1 R1826.1 R1830.2 R9912.2 U1801.4 U4003.2 U4004.2
PM_RSTBTN#: CPU1.AD62 R1836.2 R9913.1
PM_SLP_S0#: CPU1.AD61 KBC24.81 PR5038.2
PM_SLP_S3#: KBC24.64 PR5039.2 Q4001.2 Q4003.2 R4004.1 R4005.1 R4008.2 U4003.4
PM_SLP_S4#: KBC24.21 PR5037.2 Q4002.2 R4010.2 U4004.4
PM_SUS_STAT#: CPU1.AG58 R1811.1
PM_SUSCLK: CPU1.AE62 R1803.1
PM_WAKE#: CPU1.AG55 R1835.2
PMIC_EN_KBC: KBC24.112 PR5045.2
PMIC_I2C_SCL: CPU1.H45 PR5016.2 PU5001.39
PMIC_I2C_SDA: CPU1.F47 PR5025.2 PU5001.40
PMIC_IRQ: CPU1.F34 PR5043.2 RN2101.2(A)
PMIC_PWRGD: EC2401.1 PR5030.2 PR5042.2 R2014.2 R2422.1 R2609.2
PMIC_PWROK_KBC: KBC24.10 R2422.2
PMIC_RSMRST#: ED1808.1 PR5040.2 PR5046.1 R2415.1 U1801.2
PMIC_THERMTRIP#: CPU1.J47 PR5041.2 R1819.1 R2412.2
PMIC_THERMTRIP#_KBC: KBC24.91 R2412.1
PMU_RCOMP: CPU1.AG59 R2002.2
PQ3802_1: PQ4302.B PR4302.1 PR4309.2
PQ3809_D: PQ4306.3 PR4314.2
PQ4408_2: PC4425.1 PQ4408.2 PR4437.2
PQ4408_6: PQ4408.6 PR4426.1
PQ4409_C: PQ4409.C PR4464.1 PR4475.1
PQ4409_E: PQ4409.E PR4469.2 PR4470.1
PQ4410_2: PQ4410.2 PR4475.2 PR4476.2
PQ4410_3: PQ4410.3 PR4466.1
PQ4410_5: PC4434.1 PQ4410.5 PR4471.2
PQ4410_6: PC4434.2 PQ4410.6 PR4473.1
PQ4414_D: PQ4414.D PR4465.2
PQ4414_G: PC4433.2 PQ4414.G PR4474.1
PRO_SP: Q2902.C Q2903.C Q2904.C Q2905.C R2924.1 R2926.1
PROCHOT#_CPU_R: CPU1.E47 R1809.2 R1815.1
PROJECT_ID1: CPU1.T55 R2019.2 R2020.1
PROJECT_ID2: C2418.1 KBC24.94 R2441.2 R2443.1
PS_ID: PQ4301.S PR4305.1 PR4306.2
PS_ID_R: AFTP4312.1 DCIN1.4 DCIN2.3 PR4317.1
PS_ID_R2: PD4303.1 PD4303.2 PQ4301.D PR4306.1 PR4309.1 PR4317.2
PSID: KBC24.99 PD4302.3 PR4304.2 PR4305.2
PSID_DISABLE#_R_C: PQ4301.G PQ4302.C PR4303.2
PSL_IN1#: KBC24.73 R2500.2
PSL_IN2#: KBC24.93 R2489.1 R2499.2
PSL_OUT#: KBC24.74 R2493.1
PTP_DIS#: AFTP6526.1 R2494.1 R6509.2 TP1.3
PURE_HW_SHUTDOWN#: C2605.1 D4001.3 EC2403.1 Q2401.B Q2602.D R2404.1 R2405.2 R2603.1
PWR_1D05V: PC5009.1 PC5020.1 PC5022.1 PC5030.1 PC5035.1 PC5036.1 PG5003.1 PG5004.1 PG5005.1 PL5002.2 PR5023.2
PWR_1D8V: PC5005.1 PC5006.1 PC5031.1 PC5032.1 PG5007.1 PG5008.1 PG5009.1 PL5003.2 PR5010.2
PWR_1D8V_FB: PR5010.1 PU5001.37
PWR_1D8V_PH: PL5003.1 PU5001.34 PU5001.35
PWR_1D24V: PC5017.1 PC5018.1 PG5011.1 PG5012.1 PL5001.2 PR5017.2
PWR_1D24V_FB: PR5017.1 PU5001.16
PWR_1D24V_PH: PL5001.1 PU5001.20
PWR_3D3V_CS2: PR4517.1 PU4503.5
PWR_3D3V_DRVH2: PU4503.10 PU4504.4
PWR_3D3V_DRVL2: PU4503.11 PU4505.4
PWR_3D3V_EN2: PC4501.1 PR4503.2 PR4506.2 PU4503.6
PWR_3D3V_FB2: PC4523.2 PR4512.2 PR4523.1 PU4503.4
PWR_3D3V_FB2_R: PC4523.1 PR4535.2
PWR_3D3V_LL2: PC4535.2 PL4502.2 PR4533.1 PU4503.8 PU4504.1 PU4504.2 PU4504.3 PU4505.5 PU4505.6 PU4505.7 PU4505.8
PWR_3D3V_SNUB: PC4520.1 PR4533.2
PWR_3D3V_VBST2: PR4528.2 PU4503.9
PWR_3D3V_VBST2_1: PC4535.1 PR4528.1
PWR_5V_CS1: PR4531.1 PU4503.1
PWR_5V_DRVH1: PU4501.4 PU4503.16
PWR_5V_DRVL1: PU4502.4 PU4503.15
PWR_5V_EN1: PR4502.2 PU4503.20
PWR_5V_FB1: PC4522.2 PR4526.1 PR4527.2 PU4503.2
PWR_5V_FB1_R: PC4522.1 PR4525.2
PWR_5V_LL1: PC4516.2 PL4501.1 PR4529.1 PU4501.1 PU4501.2 PU4501.3 PU4502.5 PU4502.6 PU4502.7 PU4502.8 PU4503.18
PWR_5V_SNUB: PC4536.1 PR4529.2
PWR_5V_VBST1: PR4524.1 PU4503.17
PWR_5V_VBST1_1: PC4516.1 PR4524.2
PWR_5V_VCLK: PU4503.19 TP4501.1
PWR_5V_VO1: PG4532.2 PR4525.1 PR4527.1 PU4503.14
PWR_CHG_ACDET: PC4412.1 PR4407.2 PR4431.1 PU4404.6
PWR_CHG_ACN: PC4402.2 PC4403.1 PG4403.2 PR4406.1 PU4404.1
PWR_CHG_ACOK: PQ4402.2 PQ4408.3 PR4419.2 PR4436.1 PR4439.2 PR4476.1
PWR_CHG_ACP: PC4402.1 PC4404.1 PG4402.2 PR4406.2 PU4404.2
PWR_CHG_BAT_SCL: PG4407.1 PU4404.9
PWR_CHG_BAT_SDA: PG4408.1 PU4404.8
PWR_CHG_BTST: PR4409.1 PU4404.17
PWR_CHG_BTST_R: PC4411.1 PD4401.K PR4409.2
PWR_CHG_CMPIN: PR4411.2 PR4413.1 PR4414.2 PR4427.2 PR4429.1 PU4404.4
PWR_CHG_CMPIN_R: PQ4407.3 PR4429.2
PWR_CHG_CMPIN_RR: PQ4407.6 PR4427.1
PWR_CHG_CMPOUT: PR4414.1 PR4430.2 PR4432.1 PR4437.1 PR4438.1 PU4404.3
PWR_CHG_CSON_1: PC4421.2 PC4423.1 PG4410.1 PR4420.2
PWR_CHG_CSOP_1: PC4420.1 PC4421.1 PG4409.1 PR4421.2
PWR_CHG_HIDRV: PC4413.2 PU4404.18 PU4405.4
PWR_CHG_IFAULT: PR4418.2 PU4404.11
PWR_CHG_ILIM: PR4417.2 PR4423.1 PU4404.10
PWR_CHG_IOUT: PC4422.1 PR4411.1 PR4422.1 PR4424.1 PU4404.7
PWR_CHG_LODRV: PU4404.15 PU4406.4
PWR_CHG_PHASE: PC4411.2 PC4413.1 PL4401.1 PR4440.1 PU4404.19 PU4405.1 PU4405.2 PU4405.3 PU4406.5 PU4406.6 PU4406.7 PU4406.8
PWR_CHG_REGN: PC4407.1 PD4401.A PR4425.1 PR4430.1 PR4439.1 PU4404.16
PWR_CHG_SRN: PR4420.1 PU4404.12
PWR_CHG_SRP: PR4421.1 PU4404.13
PWR_CHG_VCC: PC4410.1 PR4408.2 PU4404.20
PWR_COMP2: PC5016.2 PC5033.2 PU5001.44
PWR_CSDIS1: PR5021.1 PU5001.12
PWR_CSDIS2: PR5036.1 PU5001.13
PWR_DCBATOUT_3D3V: PC4509.1 PC4525.1 PC4528.1 PG4521.2 PG4524.2 PG4525.2 PG4531.2 PU4504.5 PU4504.6 PU4504.7 PU4504.8
PWR_DCBATOUT_5V: PC4527.1 PC4529.1 PC4530.1 PG4518.2 PG4520.2 PG4534.2 PG4536.2 PG4542.2 PG4543.2 PU4501.5 PU4501.6 PU4501.7 PU4501.8
PWR_DCBATOUT_VCCGI: PC5113.1 PC5114.1 PC5131.1 PG5114.2 PG5116.2 PG5117.2 PG5119.2 PU5105.2 PU5105.3 PU5105.4 PU5105.10
PWR_DCBATOUT_VDDQ: PC5102.1 PC5119.1 PC5128.1 PG5115.2 PG5118.2 PU5103.5 PU5103.6 PU5103.7 PU5103.8
PWR_DCBATOUT_VNN: PC5104.1 PG5113.2 PG5120.2 PU5102.5 PU5102.6 PU5102.7 PU5102.8
PWR_DDRSEL: PR5029.2 PU5001.21
PWR_FB2: PC5014.2 PC5033.1 PR5020.1 PR5032.2 PU5001.43
PWR_IRQ#: PR5043.1 PU5001.41
PWR_ISENSEN2: PC5029.1 PR5113.2 PU5001.28
PWR_ISENSEP2: PC5106.1 PR5110.2 PR5111.1 PU5001.29
PWR_OCSET6: PR5024.1 PU5001.14
PWR_PMIC_EN: PR5033.1 PR5045.1 PU5001.45
PWR_PWROK: PR5042.1 PU5001.38
PWR_RSMEST#: PR5040.1 PU5001.30
PWR_SLP_S0#: PR5038.1 PU5001.9
PWR_SLP_S3#: PR5039.1 PU5001.10
PWR_SLP_S4#: PR5037.1 PU5001.11
PWR_THERMTRIP#: PR5041.1 PR5044.2 PU5001.22
PWR_VCC: PC5028.1 PR5029.1 PR5031.2 PU5001.8
PWR_VCCGI_BOOT: PR5109.1 PU5107.4
PWR_VCCGI_BOOT_A: PC5121.1 PR5109.2
PWR_VCCGI_EN: PU5001.33 PU5107.1
PWR_VCCGI_HG: PU5105.1 PU5107.3
PWR_VCCGI_ISEN: PR5107.1 PR5108.1 PR5111.2
PWR_VCCGI_LG: PU5105.8 PU5107.7
PWR_VCCGI_PH: PC5105.1 PC5121.2 PG5111.2 PL5103.1 PR5110.1 PU5105.9 PU5107.2
PWR_VCCGI_PHA: PC5026.1 PG5111.1 PU5001.32
PWR_VCCGI_PWM: PU5001.31 PU5107.5
PWR_VCCGI_SNUB: PC5105.2 PR5102.1
PWR_VCCGI_VCC: PC5103.1 PR5101.2 PU5107.8
PWR_VCCRAM_FB: PR5023.1 PU5001.15
PWR_VCCRAM_PH: PL5002.1 PU5001.23 PU5001.24
PWR_VDDQ: PC5101.1 PC5107.1 PC5108.1 PC5110.1 PC5112.1 PC5117.1 PC5118.1 PC5120.1 PC5123.1 PC5126.1 PC5127.1 PC5129.1 PC5130.1 PG5102.2 PG5104.1 PG5105.1 PG5106.1 PG5107.1 PG5108.1 PG5109.1 PG5127.1 PG5128.1 PG5129.1 PL5102.2
PWR_VDDQ_BOOT: PR5106.1 PU5108.4
PWR_VDDQ_BOOT_A: PC5115.1 PR5106.2
PWR_VDDQ_EN: PU5001.50 PU5108.1
PWR_VDDQ_FB: PR5001.1 PU5001.4
PWR_VDDQ_HG: PU5103.4 PU5108.3
PWR_VDDQ_LG: PU5104.4 PU5108.7
PWR_VDDQ_PH: PC5115.2 PC5122.1 PG5112.2 PL5102.1 PU5103.1 PU5103.2 PU5103.3 PU5104.5 PU5104.6 PU5104.7 PU5104.8 PU5108.2
PWR_VDDQ_PHA: PC5027.1 PG5112.1 PU5001.51
PWR_VDDQ_PWM: PU5001.52 PU5108.5
PWR_VDDQ_SNUB: PC5122.2 PR5112.1
PWR_VDDQ_VCC: PC5109.1 PR5104.2 PU5108.8
PWR_VIN_CT: PC5021.1 PR5008.2 PR5018.2 PU5001.5
PWR_VNN_BOOT: PR5105.1 PU5106.4
PWR_VNN_BOOT_A: PC5116.1 PR5105.2
PWR_VNN_EN: PU5001.47 PU5106.1
PWR_VNN_FB: PR5034.1 PR5035.1 PU5001.46
PWR_VNN_HG: PU5102.4 PU5106.3
PWR_VNN_LG: PU5101.4 PU5106.7
PWR_VNN_PH: PC5116.2 PC5125.1 PG5110.2 PL5101.1 PU5101.5 PU5101.6 PU5101.7 PU5101.8 PU5102.1 PU5102.2 PU5102.3 PU5106.2
PWR_VNN_PHA: PC5011.1 PG5110.1 PU5001.48
PWR_VNN_PWM: PU5001.49 PU5106.5
PWR_VNN_SNUB: PC5125.2 PR5114.1
PWR_VNN_VCC: PC5124.1 PR5103.2 PU5106.8
PWR_VO2: PC5012.1 PR5004.2 PR5005.2 PR5019.1 PR5032.1 PU5001.42
PWR_VSS: PC5012.2 PC5013.1 PR5012.2 PR5013.2 PU5001.27
PWR_VSYS: PC5015.1 PR5007.2 PR5014.2 PU5001.6
PWR_VTT: PC5019.1 PG5014.2 PG5016.1 PU5001.2
PWR_VTT_SEN: PG5016.2 PU5001.1
Q6205_Q: Q6505.D R6522.2
RING2: EC2905.1 HDA27.17 R2906.1 RN2901.4(B)
RING2_R: AFTP6605.1 IOBD1.24 IOBD1.25 IOBD1.26 R2906.2
RSMRST#_KBC: ED1804.1 KBC24.15 R1830.1 R2440.2 U1801.1
RSMRST_IN_PMIC: KBC24.96 R2415.2 R2439.2
RTC_AUX_S5: Q2501.3 R611.1 R1817.1 R2425.2 R2515.1 RN1804.1(A) RN1804.2(A)
RTC_DET#: KBC24.6 Q2502.D RN2404.4(B)
RTC_DET#_G: Q2501.1 Q2502.G R2516.1 R2518.2 R2527.1
RTC_RST#: C1802.1 CPU1.AC55 ED1809.1 G1801.2 Q1801.D R1818.1 RN1804.3(B)
RTC_TEST#: C1801.1 CPU1.AH49 Q1802.D R1818.2 RN1804.4(B)
RTCRST_ON: KBC24.120 Q1801.G Q1802.G R1814.1
RUN_ON#: Q4001.5 Q4001.6 R4002.2
RUN_ON_R: C4010.1 R4004.2 U4001.3 U4001.5
S5_ENABLE: KBC24.14 Q2403.3 R4007.2 RN2406.1(A)
SATA3_DE1_HDD: R6007.1 R6024.2 U6001.9
SATA3_DE2_HDD: R6008.2 R6014.1 U6001.8
SATA3_DRX_CTX_N0: C6019.1 R6018.2 U6001.12
SATA3_DRX_CTX_N0_R: R6015.2 R6018.1
SATA3_DRX_CTX_P0: C6016.1 R6009.2 U6001.11
SATA3_DRX_CTX_P0_R: R6009.1 R6023.2
SATA3_DTX_CRX_N0: C6011.1 R6019.2 U6001.14
SATA3_DTX_CRX_N0_R: R6010.2 R6019.1
SATA3_DTX_CRX_P0: C6017.1 R6006.2 U6001.15
SATA3_DTX_CRX_P0_R: R6006.1 R6011.2
SATA3_EQ1_HDD: R6005.1 R6017.2 U6001.17
SATA3_EQ2_HDD: R6013.1 R6021.2 U6001.19
SATA3_PRX_DTX_N0_L: C6018.1 U6001.4
SATA3_PRX_DTX_P0_L: C6015.1 U6001.5
SATA3_PTX_DRX_N0_R: C6014.2 U6001.2
SATA3_PTX_DRX_P0_R: C6013.2 U6001.1
SATA_DEVSLP_HDD_CPU: CPU1.C25 Q2101.S R2115.2
SATA_LED: KBC24.100 Q6401.G R6408.1
SATA_LED#_CPU: CPU1.C31 Q6401.S R2106.1
SATA_ODD_DA#_C: ODD1.17 TP6001.1
SATA_ODD_DA#_C2: ODD2.4 TP6002.1
SATA_ODD_PRSNT#: Q2103.S R2126.2 R2129.1 R6002.2 R6003.2
SATA_ODD_PRSNT#_CPU: CPU1.B25 Q2102.S R2120.2 R2129.2
SATA_ODD_PRSNT#_D: Q2102.D Q2103.D R2124.2
SATA_ODD_PRSNT#_R: ODD1.8 R6002.1
SATA_ODD_PRSNT#_R2: ODD2.13 R6003.1
SATA_RXN0_C: C6019.2 EU6001.4 EU6001.7 HDD1.8
SATA_RXP0_C: C6016.2 EU6001.5 EU6001.6 HDD1.7
SATA_TXN0_C: C6011.2 EU6001.2 EU6001.9 HDD1.10
SATA_TXP0_C: C6017.2 EU6001.1 EU6001.10 HDD1.11
SD_AMP: Q2907.C R2927.2 R2928.1 R2929.1
SD_AMP#: Q2701.G Q2908.C R2726.2
SD_AMP_R: Q2906.B R2927.1
SERIRQ: R1919.1 R1922.1 R1923.1 R2508.1 U2404.4
SIO_EXT_SCI#: KBC24.17 R2501.1
SIO_EXT_SMI#: KBC24.119 R2503.1
SIO_SLP_S3: Q4003.5 Q4003.6 R4011.2
SIO_SLP_S3#: CPU1.AC62 R4008.1 U4003.1
SIO_SLP_S4: Q4002.5 Q4002.6 R4009.1
SIO_SLP_S4#: CPU1.AK54 R4010.1 U4004.1
SLEEVE: EC2906.1 HDA27.18 R2911.1 RN2901.3(B)
SLEEVE_R: AFTP6609.1 IOBD1.21 IOBD1.22 IOBD1.23 R2911.2
SM_RCOMP_0: CPU1.AV34 R2011.2
SM_RCOMP_1: CPU1.AV30 R2010.2
SMB_ALERT#_CPU: CPU1.R63 R1701.2
SMB_CLK: CPU1.T62 Q1701.3 RN1703.3(B)
SMB_CLK_CPU: KBC24.67 Q2603.6 RN2401.3(B)
SMB_DATA: CPU1.T61 Q1701.6 RN1703.4(B)
SMB_DATA_CPU: KBC24.68 Q2603.3 RN2401.4(B)
SMBCLK1: D4306.3 EC4309.1 KBC24.70 PG4407.2 PR4415.2 RN4302.3(A)
SMBDA1: D4305.3 EC4310.1 KBC24.69 PG4408.2 PR4412.2 RN4302.2(A)
SOC_PWROK_CPU: CPU1.AG49 R2013.2 R2014.1 R2023.1
SOC_RUNTIME_SCI#: CPU1.C34 R2501.2 RN2101.1(A)
SPI1_HOLD_ROM_R: R2523.1 SPI252.7
SPI1_SO_ROM_R: EC2506.1 R2528.2 SPI252.2
SPI1_VCC_1D8V: C2503.1 C2504.1 R2530.1 SPI252.8
SPI1_WP_ROM_R: R2522.2 SPI252.3
SPI_CLK_ROM: EC2505.1 R2418.2 SPI252.6
SPI_CLK_ROM_CPU: CPU1.C56 R2502.2
SPI_CLK_ROM_R1: EC2503.1 R2502.1 SPI251.6
SPI_CS_CPU_N0: CPU1.B57 R2531.1
SPI_CS_ROM_N0_R: R2416.2 R2535.2 SPI252.1
SPI_CS_ROM_N0_R1: R2531.2 R2532.2 SPI251.1
SPI_HOLD_ROM: CPU1.B61 R2517.2 R2534.1
SPI_HOLD_ROM_R: R2517.1 SPI251.7
SPI_SI_ROM: EC2504.1 R2401.2 SPI252.5
SPI_SI_ROM_CPU: CPU1.A58 R2513.2
SPI_SI_ROM_R1: EC2501.1 R2513.1 SPI251.5
SPI_SO_ROM: CPU1.B58 R2510.1
SPI_SO_ROM_R1: EC2502.1 R2510.2 SPI251.2
SPI_VCC_1D8V: C2501.1 C2502.1 R2529.1 SPI251.8
SPI_WP_ROM: CPU1.B60 R2514.1 R2533.1
SPI_WP_ROM_R: R2514.2 SPI251.3
SUS_PWR_ACK_R: KBC24.25 R2411.2
SUS_PWRDN_ACK: CPU1.AC63 R1807.2 R1808.1 R2411.1
SUSCLK: EC1801.1 KBC24.77 R1803.2
SYS_PRES1#: AFTP4305.1 BATT1.6 BATT2.6 R4301.2
SYS_PWROK: EC2402.1 KBC24.84 R2013.1 R2426.2 R2607.2
SYS_PWROK_G: Q2602.G R2607.1 R2609.1
T_CRIT#: R2601.1 R2606.2 U2601.4
THERM_SYS_SHDN#: Q2602.S R2601.2 R2602.1
TOUCH_INT_CPU: CPU1.C26 TP2101.1
TOUCH_PANEL_EN: D2401.A KBC24.23 R2427.2 RN5501.5(B)
TOUCH_RST_CPU: CPU1.C33 TP2102.1
TP_CLK_C: AFTP6527.1 RN6503.4(B) TP1.1
TP_DATA_C: AFTP6528.1 RN6503.3(B) TP1.2
TP_DISABLE#_R: KBC24.29 R2494.2
TP_EN#: KBC24.33 R6516.1 RN2404.3(B)
TP_I2C_CLK: EC6504.1 Q1902.1 R6518.1 RN1906.1(A)
TP_I2C_CLK_C: AFTP6524.1 R6515.2 R6518.2 TP1.6
TP_I2C_CLK_D: Q1901.6 Q1902.6 RN1907.1(A)
TP_I2C_DATA: EC6502.1 Q1902.4 R6519.1 RN1906.2(A)
TP_I2C_DATA_C: AFTP6530.1 R6511.2 R6519.2 TP1.7
TP_I2C_DATA_D: Q1901.3 Q1902.3 RN1907.2(A)
TP_IN#_CPU: CPU1.J39 Q6508.S R2114.1
TP_IN#_CPU_D: Q6508.D Q6509.D R6523.1 R6525.2
TP_INT#_EC: KBC24.26 R6523.2
TP_ON#_GATE: C6503.1 Q6504.G Q6505.G R6516.2
TP_RESET: LCD1.38 R5533.2
TP_VDD: AFTP6529.1 C6504.1 Q1902.2 Q1902.5 Q6504.D Q6509.G R6509.1 R6513.1 R6514.2 R6517.2 R6522.1 R6524.1 RN1906.3(B) RN1906.4(B) RN6504.1(A) RN6504.2(A) TP1.8
TPAN_VDD: AFTP5521.1 C5514.1 F5503.2 LCD1.40 R5523.1
TPAN_VDD_F: F5503.1 R5512.1 R5522.2 R5523.2
TPNL_EN: AFTP5520.1 LCD1.37 RN5501.4(A)
TRST_PD: R9921.1 XDP1.8
TS#_DIMM0_1: DM1.198 TP1201.1
TS_USB20_N: CPU1.Y10 R5506.2
TS_USB20_P: CPU1.Y9 R5516.2
UART2_RTS#: CPU1.L41 TP1802.1
UART2_RXD: CPU1.J41 DB3.3
UART2_TXD: DB3.2 R1802.2
USB1_USB20_N: CPU1.V10 EL6601.2
USB1_USB20_P: CPU1.V12 EL6601.3
USB1_USB30_RX_CON_N: EU3501.1 EU3501.10 FC3506.1 R3502.2 USB1.5
USB1_USB30_RX_CON_P: EU3501.2 EU3501.9 FC3505.1 R3503.2 USB1.6
USB1_USB30_RX_N: CPU1.K10 R3502.1
USB1_USB30_RX_P: CPU1.K9 R3503.1
USB1_USB30_TX_CON_N: ER3505.2 EU3501.4 EU3501.7 FC3504.1 USB1.8
USB1_USB30_TX_CON_P: ER3506.2 EU3501.5 EU3501.6 FC3503.1 USB1.9
USB1_USB30_TX_N: C3502.1 CPU1.J2
USB1_USB30_TX_N_R: C3502.2 ER3505.1
USB1_USB30_TX_P: C3501.1 CPU1.J1
USB1_USB30_TX_P_R: C3501.2 ER3506.1
USB2_CON_USB20_N: AFTP3503.1 EL3503.3 EU3502.1 USB1.2
USB2_CON_USB20_P: AFTP3502.1 EL3503.2 EU3502.6 USB1.3
USB2_OTG_ID: CPU1.AC15 R1703.1
USB2_USB20_N: CPU1.V15 EL3503.4
USB2_USB20_P: CPU1.V16 EL3503.1
USB2_USB30_RX_CON_N: ER3511.2 EU3504.1 EU3504.10 USB2.5
USB2_USB30_RX_CON_P: ER3512.2 EU3504.2 EU3504.9 USB2.6
USB2_USB30_RX_N: CPU1.G2 ER3511.1
USB2_USB30_RX_P: CPU1.F2 ER3512.1
USB2_USB30_TX_CON_N: ER3509.2 EU3504.4 EU3504.7 USB2.8
USB2_USB30_TX_CON_P: ER3510.2 EU3504.5 EU3504.6 USB2.9
USB2_USB30_TX_N: C3508.1 CPU1.K2
USB2_USB30_TX_N_R: C3508.2 ER3509.1
USB2_USB30_TX_P: C3507.1 CPU1.K3
USB2_USB30_TX_P_R: C3507.2 ER3510.1
USB2_VBUS_SNS: CPU1.AC16 R1702.2
USB3_CON_USB20_N: AFTP3508.1 EL3504.3 EU3502.3 USB2.2
USB3_CON_USB20_P: AFTP3506.1 EL3504.2 EU3502.4 USB2.3
USB3_USB20_N: CPU1.V13 EL3504.4
USB3_USB20_P: CPU1.Y13 EL3504.1
USB20_VCCA: AFTP6610.1 C3515.1 C3517.1 C3518.1 C6601.1 ED6601.5 IOBD1.10 IOBD1.11 IOBD1.12 IOBD1.13 U3602.1
USB_CON_PN1: AFTP6603.1 ED6601.1 EL6601.1 IOBD1.6
USB_CON_PN3: AFTP5509.1 EU5501.1 LCD1.30 TR5501.4
USB_CON_PN5: AFTP6106.1 ER6103.1 WLAN1.5
USB_CON_PN6: AFTP6601.1 EL6602.1 IOBD1.3
USB_CON_PP1: AFTP6604.1 ED6601.6 EL6601.4 IOBD1.7
USB_CON_PP3: AFTP5508.1 EU5501.6 LCD1.31 TR5501.1
USB_CON_PP5: AFTP6107.1 ER6102.1 WLAN1.3
USB_CON_PP6: AFTP6602.1 EL6602.4 IOBD1.4
USB_OC#0: CPU1.B55 RN1701.4(B) U3602.3
USB_OC#1: CPU1.C55 RN1701.3(B) U3601.3
USB_PN4_TPNL: AFTP5518.1 EU5501.3 LCD1.34 R5506.1
USB_PP4_TPNL: AFTP5519.1 EU5501.4 LCD1.35 R5516.1
USB_PWR_EN#: KBC24.108 R2471.2 U3601.4 U3602.4
USB_RCOMP: CPU1.Y15 R2004.2
USB_SSIC_RCOMP: CPU1.AB15 R2003.2
VD1_EN#: KBC24.66 R2468.1
VD_IN1: C2606.1 C2607.1 KBC24.95 KBC24.104 R2608.2 R2610.1 R2612.2
VD_IN1_C: C2606.2 C2607.2 R2610.2 R2611.1
VD_OUT1#: KBC24.110 R2602.2 R2603.2 R2613.2
VRAM_ID1: CPU1.P57 R2024.2 R2025.1
VREF_CA: DM1.126 R1207.2 R1211.1
VREF_DQ: DM1.1 R1208.2 R1212.1
WHITE_LED_BAT: EC6404.1 Q6404.C R6406.1
WIFI_RF_EN: AFTP6103.1 KBC24.82 WLAN1.56
WLAN_CLK_CPU: CPU1.A7 WLAN1.47
WLAN_CLK_CPU#: CPU1.B8 WLAN1.49
WLAN_CLKREQ_CPU#: CPU1.AH61 D1601.1 R1607.2 RN1603.1(A)
WLAN_CLKREQ_D: D1601.3 Q1601.D R1605.2
WLAN_CPU_TX_N: C1602.1 CPU1.M2
WLAN_CPU_TX_P: C1601.1 CPU1.N2
WLAN_PCIE_RX_N: CPU1.H6 WLAN1.43
WLAN_PCIE_RX_P: CPU1.H5 WLAN1.41
WLAN_PCIE_TX_N: C1602.2 WLAN1.37
WLAN_PCIE_TX_P: C1601.2 WLAN1.35
XDP_PRDY#: CPU1.C21 R9918.1 RN1802.4(B)
XDP_PREQ#: CPU1.C20 R9902.2 RN1802.3(B)
XDP_PTI_CLK0: CPU1.A38 R2117.1
XDP_TCK: CPU1.B23 R1827.1 R9916.1
XDP_TDI: CPU1.C22 R1806.2 R9922.1
XDP_TDO: CPU1.A22 R1833.1 R9920.2
XDP_TMS: CPU1.C23 R1812.1 R9910.2
XDP_TRST#: CPU1.C24 ED1806.1 R1828.1 R9908.1
XDP_UART_RXD_CPU: CPU1.C43 R9901.2
XTL_19D2M_X1_CPU: C1901.1 CPU1.P29 R1907.2 X1901.1
XTL_19D2M_X2_CPU: C1902.1 CPU1.R27 R1907.1 X1901.3
XTL_32K_X1_CPU: C1803.1 CPU1.AC59 R1810.1 X1801.4
XTL_32K_X2_CPU: C1804.1 CPU1.AC58 R1810.2 X1801.1

Pads without a net: CPU1 A3 A4 A10 A14 A18 A30 A50 A54 A60 A61 AB2 AB3 AB13 AB49 AB51 AB55 AB58 AC1 AC2 AC5 AC6 AC7 AC9 AC13 AC20 AC22 AC49 AC52 AD2 AD3 AE60 AF2 AF3 AF61 AF62 AG15 AG16 AG52 AG54 AG62 AG63 AH12 AH13 AJ44 AK6 AK7 AK13 AK15 AK16 AK61 AL63 AM5 AM6 AM7 AM9 AM10 AM12 AM13 AM15 AM16 AM32 AM49 AM51 AM52 AM55 AM57 AM58 AM59 AM61 AN32 AN62 AP2 AP3 AP5 AP6 AP10 AP12 AP13 AP15 AP49 AP51 AP52 AP54 AP57 AP58 AP59 AR1 AR2 AR21 AR23 AR25 AR27 AR29 AR30 AR62 AR63 AT5 AT6 AT9 AT10 AT21 AT23 AT27 AT30 AT43 AU1 AU2 AV5 AV6 AV7 AV10 AV12 AV16 AV17 AV25 AV27 AV47 AV48 AW1 AW2 AW16 AW17 AW19 AW21 AW23 AW25 AW27 AW29 AW45 AW47 AW48 AY2 AY3 AY5 AY7 AY9 B4 B5 B7 B11 B13 B15 B17 B21 B27 B51 B53 BA14 BA19 BA23 BA30 BA45 BB1 BB5 BB6 BB7 BB10 BB12 BB14 BB16 BB17 BB21 BB23 BB27 BB29 BB30 BB41 BB43 BB47 BC2 BD1 BD2 BD5 BD6 BD10 BD12 BD14 BD16 BD17 BD19 BD21 BD23 BD25 BD27 BD29 BD30 BD43 BD47 BE2 BE8 BE14 BE19 BE23 BE25 BE30 BF5 BF6 BG1 BG2 BG7 BG8 BG9 BG10 BG11 BG12 BG13 BG14 BG15 BG16 BG17 BG18 BG20 BG21 BG22 BG24 BG25 BG26 BG27 BG28 BG30 BG31 BG63 BH3 BH4 BH6 BH7 BH9 BH11 BH13 BH15 BH17 BH19 BH23 BH27 BH29 BH31 BH58 BJ2 BJ3 BJ6 BJ12 BJ16 BJ20 BJ22 BJ24 BJ26 BJ30 BJ58 BJ61 BJ62 C1 C2 C9 C10 C11 C13 C14 C15 C17 C18 C19 C27 C29 C30 C35 C36 C37 C42 C44 C45 C51 C52 C53 C54 C57 C62 C63 D1 D2 D4 D8 D59 D61 E3 E6 E8 E10 E16 E17 E23 E25 E30 E41 E52 E63 F1 F8 F12 F14 F16 F17 F19 F23 F25 F30 F35 F39 F48 F52 F54 F61 G62 H10 H12 H14 H16 H19 H21 H25 H30 H34 H35 H43 H48 H50 H54 H57 H58 H59 H63 J16 J17 J21 J23 J25 J29 J34 J43 J45 J50 J62 K7 K55 K58 K59 K61 L1 L2 L14 L16 L17 L19 L23 L25 L34 L37 L39 L47 L48 L62 M5 M6 M7 M10 M12 M16 M17 M19 M23 M25 M29 M30 M34 M35 M37 M39 M43 M45 M47 M48 M52 M57 M61 M62 P2 P3 P6 P7 P10 P12 P17 P21 P23 P25 P27 P30 P34 P39 P47 P51 P52 P58 R1 R2 R17 R19 R21 R25 R30 R34 R35 R37 R39 T2 T3 T10 T12 T51 T57 V2 V3 V5 V6 V48 V49; D1601 2; DCIN1 3; DCIN2 4; DM1 77 122 125; ED5703 5 6; ED6601 3 4; HDA27 11 12 14 23 24; HDMI1 13 14; IOBD1 14 16; KB1 2 3; KB2 2 3; KBBL1 3; LCD1 3 39; ODD1 9 16; ODD2 5 12; RN4302 4 5; U6301 A1 A2 A7 A8 A9 A10 A11 A12 A13 A14 B1 B7 B8 B9 B10 B11 B12 B13 B14 C1 C3 C5 C7 C8 C9 C10 C11 C12 C13 C14 D1 D2 D3 D4 D12 D13 D14 E1 E2 E3 E5 E8 E12 E13 E14 F1 F2 F3 F12 F13 F14 G1 G2 G3 G10 G12 G13 G14 H1 H2 H3 H12 H13 H14 J1 J2 J3 J12 J13 J14 K1 K2 K3 K6 K7 K12 K13 K14 L1 L2 L3 L12 L13 L14 M1 M2 M3 M7 M8 M9 M10 M11 M12 M13 M14 N1 N3 N6 N7 N8 N9 N10 N11 N12 N13 N14 P1 P2 P7 P8 P9 P10 P11 P12 P13 P14; WLAN1 6 16 17 19 20 21 22 23 24 25 26 27 28 29 30 31 32 34 36 40 42 48 50 59 60 61 62 64 65 66 67 68 70 71 73; XDP1 14 18 20 22 24 26 28 30 32 35 37 39 41 43 44 45 46 47 49 51 52 53 55 59 60

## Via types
v1: diameter 0.356, hole 0.178, TOP to BOTTOM, 835 vias
v2: diameter 0.508, hole 0.254, TOP to BOTTOM, 2398 vias
v3: diameter 0.711, hole 0.406, TOP to BOTTOM, 440 vias
v4: diameter 0.559, hole 0.305, TOP to BOTTOM, 2 vias

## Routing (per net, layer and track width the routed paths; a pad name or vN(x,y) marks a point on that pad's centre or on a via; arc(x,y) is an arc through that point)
1V_CPU_VCGI: length 51.8
  TOP w0.203: v2(138.79,119.99) 136.76,119.99 136.46,120.3 124.14,120.3 123.78,120.65 122.92,120.65 v2(122.68,120.41)
  TOP w0.508: v3(119.9,119.28) 119.9,120.5 120.76,121.36 120.76,122.58 121.17,122.99 123.88,122.99 124.78,122.09 134.59,122.09 135.01,122.51 136.53,122.51 v2(137.9,123.88) 139.43,122.35 139.43,120.63 v2(138.79,119.99)
  BOTTOM w0.203: PR5108.2 138.04,119.29 137.9,119.43 PC5106.2 138.77,120.02 v2(138.79,119.99) ; PR5107.2 v2(122.68,120.41)
  BOTTOM w0.305: CPU1.E37 v2(119.81,95.46) CPU1.E35 ; CPU1.E45 v2(116.32,94.16) CPU1.E43 ; CPU1.F29 v2(123.58,96.03) CPU1.E29 ; CPU1.E50 113.82,92.65 113.85,92.64 v2(114.26,92.64) CPU1.E48
  BOTTOM w0.508: PR5113.1 138.48,123.41 138.01,123.88 v2(137.9,123.88)
  vias: v1(111.31,107.27) v1(117.51,118.42) v1(121.7,92.1) v2(118.17,88.83) v2(119.07,89.19) v2(120.46,88.74) v2(121.19,88.99) v2(121.69,87.64) v2(122.18,88.58) v2(122.43,87.9) v2(123.17,88.18) v2(124.16,90.07) v2(124.65,88.71) v2(125.14,87.34) v2(125.4,88.99) v2(125.64,88.31) v2(125.64,85.99) v2(125.89,87.62) v3(112.12,113.4) v3(112.12,112.55) v3(112.99,114.02) v3(113.04,113.11) v3(114.13,114.71) v3(114.55,115.61) v3(114.92,104.14) v3(115.12,118.98) v3(115.09,118.11) v3(115.15,117.25) v3(115.12,116.36) v3(115.86,103.63) v3(116.8,115.8) v3(117.25,115.04) v3(117.28,114.12) v3(117.3,113.21) v3(117.99,112.63) v3(118.83,112.6) v3(118.8,105.62) v3(119.62,105.23) v3(119.74,112.6) v3(119.9,118.37) v3(119.9,117.48) v3(119.87,116.44) v3(120.91,106.35)
1V_CPU_VNN: length 7.9
  L4 w0.203: 127.26,84.74 127.69,84.51 128.26,84.68 v2(129.35,85.02)
  L4 w0.305: 127.26,84.74 126.7,85.02 126.48,85.02 126.46,85 124.19,84.18 122.43,84.18 v2(121.95,84.66)
  vias: v1(105.37,116.72) v2(119.46,84.51) v2(119.72,83.85) v2(120.46,84.12) v2(121.21,84.39) v3(103.23,117.71) v3(103.26,116.59) v3(104.33,117.79) v3(104.43,114.06) v3(105.34,117.83) v3(105.6,114.06) v3(106.31,117.83)
3V_5V_PWRGD: length 154.8
  TOP w0.102: v2(125.77,131) v1(125.77,130.44) ; v2(50.55,59.54) 50.55,59.16 52.08,57.63 52.53,57.18 52.53,56.4 52.36,56.22 52.36,55.62 PR5046.2 52.14,55.4 PR4534.2 52.14,54.18 52.33,53.99 52.33,51.69 51.89,51.25 51.89,51.14 51.33,50.59 PU4503.7
  L3 w0.102: v2(40.88,71.12) 42.53,69.47 43.82,69.47 46.01,67.29 46.01,62.81 47.5,61.32 48.78,61.32 v2(50.55,59.54)
  L4 w0.102: v2(125.77,131) 125.77,129.7 125.78,129.7 125.78,129.34 124.16,127.73 124.15,127.73 123.49,127.06 123.21,126.78 123.21,124.7 124.14,123.77 124.14,115.52 120.12,111.51 111.13,111.51 110.76,111.88 100.07,111.88 95.64,107.45 95.64,105.49 92.36,102.21 92.36,95.84 90.51,93.98 88.08,89.57 88.08,89.49 86.65,87.36 86.62,87.34 86.56,87.24 83.82,84.36 81.33,81.74 78.97,80.02 73,77.4 68.18,76.25 65.03,76.25 64.55,75.77 60.38,75.77 59.85,76.3 58.58,76.3 58.38,76.1 56.67,76.1 56.55,76.23 45.75,76.23 40.88,71.35 v2(40.88,71.12)
  BOTTOM w0.102: PR5033.2 126.99,130.28 ED1803.1 126.23,130.52 125.81,130.94 125.81,130.95 v2(125.77,131)
3V_EN: length 193.4
  TOP w0.102: v2(174.51,53.42) 174.51,53.24 v1(174.15,52.88) 173.9,52.63 173.39,52.63 172.3,51.53 172.3,48.47 171.58,47.75 171.58,47.39 171.58,47.39 171.58,46.65 171.58,46.64 171.58,46.36 170.75,45.53 170.75,45.01 170.06,44.33 168.21,44.33 167.57,44.96 164.27,44.96 163.23,43.92 163.23,43.69 162.95,43.41 v2(162.26,43.41) ; v2(52.77,54.26) 53.07,54.26 53.51,54.7 R4013.2
  L3 w0.102: v2(52.77,54.26) 52.41,53.9 52.41,51.92 52.64,51.69 52.64,48.24 53.12,47.75 53.12,45.26 52.44,44.58 v2(52.44,43.5)
  L4 w0.102: v2(174.51,53.42) 174.38,53.42 173.79,54 172.73,54 172.42,54.31 172.42,57.38 171.99,57.81 171.99,60.99 172.45,61.44 172.45,71.18 170.69,72.93 170.19,73.44 170.19,75.57 170.06,75.69 v2(170.06,76.33) ; v2(52.44,43.5) 52.44,43.5 52.83,43.11 57.29,43.11 59.85,45.67 59.85,46.64 61.64,48.43 61.64,50.64 62.14,51.14 73.39,51.14 73.48,51.06 74.54,51.06 76.83,48.77 76.83,48.76 77.07,48.52 v2(77.12,48.52)
  BOTTOM w0.102: v2(162.26,43.41) 161.92,43.76 155.21,43.76 154.13,44.83 149.75,44.83 149.06,44.14 144.1,44.14 143.63,44.62 143.63,46.08 143.01,46.69 86.74,46.69 83.74,43.69 78.31,43.69 76.74,45.25 76.74,48.14 v2(77.12,48.52) ; Q2403.6 167.99,74.54 168,74.55 168,74.91 167.99,74.92 167.99,75.37 RN2406.2 167.49,75.42 167.37,75.54 167.37,76.26 167.54,76.43 169.96,76.43 v2(170.06,76.33) ; KBC24.63 174.88,54.32 175.3,54.75 175.67,54.75 175.93,54.5 175.93,53.93 175.42,53.42 v2(174.51,53.42)
3V_FEEDBACK: length 33.2
  TOP w0.254: PR4512.1 55.11,48.68 54.77,48.34 v2(54.67,48.34) 54.67,47.65 54.77,47.55 PR4535.1 ; v2(32.65,61.22) v1(32.65,61.8)
  L4 w0.254: v2(54.67,48.34) 53.4,49.61 53.4,51.13 53.7,51.44 53.7,52.53 53.35,52.89 53.35,52.92 53.05,53.22 52.61,53.22 47.12,58.7 39.83,58.7 37.24,61.29 32.72,61.29 v2(32.65,61.22)
  BOTTOM w0.254: PG4535.2 v2(32.65,61.22)
3V_S5_EN: length 17.3
  TOP w0.14: v2(54.24,52.45) 53.72,52.97 PR4503.1 53.6,53.63 R4013.1
  BOTTOM w0.14: PR4504.2 50.16,46.5 49.35,45.68 D4001.1 50.55,44.42 v1(50.71,44.58) 50.71,45.44 50.51,45.64 50.51,46.26 51.98,47.73 53.17,47.73 54.36,48.92 54.36,52.33 v2(54.24,52.45)
5V_DDC_HDMI1: length 8
  TOP w0.102: D5701.1 23.81,58.97 23.81,56.57 v1(23.25,56.01) 23.25,55.91 21.7,54.36 RN5701.3
5V_DDC_HDMI2: length 6.9
  TOP w0.102: RN5701.4 20.26,55.01 20.48,54.79 v1(21.22,54.79) 21.52,54.79 22.51,55.78 22.51,59.15 D5701.2
5V_HDD_S0: length 1.7
  TOP w0.305: v1(172.73,43.79) v2(173.13,44.2)
  BOTTOM w0.305: v2(173.13,44.2) 173.28,44.05 HDD1.3
5V_HDMI_R_S0: length 2.9
  BOTTOM w0.508: v1(16.49,60.71) R5718.2 15.55,59.67 15.32,59.9 F5701.1
5V_HDMI_S0: length 1.2
  BOTTOM w0.508: 10.95,56.07 HDMI1.18 11.6,55.5
  vias: v1(13.77,56.69)
5V_PWR:
  vias: v1(35.39,45.09) v3(30.28,43.92) v3(30.26,43) v3(30.28,40.08) v3(31.17,43.92) v3(31.2,42.98) v3(31.4,40.08) v3(32.14,43.97) v3(32.16,43.03) v3(32.65,41.91) v3(32.67,40.97) v3(33.76,41.91) v3(33.79,40.97)
5V_PWR_2: length 4.1
  TOP w0.203: 47.71,48.14 48.22,48.65 48.87,48.65 48.93,48.59 PU4503.13
  TOP w0.508: 47.71,48.14 47.2,47.63 PC4524.1 v1(47.2,46.13)
5V_S0: length 327.3
  TOP w0.508: R5512.2 125.51,160.92 v2(125.43,160.83) ; R2720.2 v1(169.76,10.57) 169.97,10.35 EC8923.1 169.97,9.41 166.81,6.25 v2(166.81,5.54) ; EC8922.1 v2(176.22,26.46) ; R7009.1 v2(160.19,82.41) ; v4(178.85,50.9) 178.34,51.41 EC8925.1 ; v2(20.1,58.7) 20.15,58.7 21.8,60.35 22.82,60.35 23.25,59.92 D5701.3 ; R2733.1 157.23,29.83 156.8,30.25 155.4,30.25 153.68,28.53 152.76,28.53 151.66,29.63 150.12,29.63 149.28,28.79 v2(149.28,28.63) ; R6504.1 153.76,127.07 154.92,125.91 160.61,125.91 v2(161.98,124.54) ; v2(163.79,86.03) 164.41,86.03 Q6502.E ; v2(32.47,34.17) EC8926.1 ; R2926.2 148.07,24.24 v3(147.81,23.98)
  TOP w1.27: 49.77,27.46 135.87,27.46 137.93,25.4 137.93,17.73 v3(137.85,17.66)
  L3 w0.508: v2(178.54,90.27) 175.47,93.35 170.9,93.35 169.93,94.31 164.06,94.31 161.2,91.45 161.2,90.61 161.17,90.59 161.17,88.2 163.34,86.03 v2(163.79,86.03) ; v2(161.98,124.54) 161.98,128.49 160.38,130.09 v2(160.38,137.8)
  L4 w0.508: v2(160.38,137.8) 160.52,137.66 166.54,137.66 v2(166.78,137.9) ; v2(19.95,53.57) 19.59,53.22 19.59,46.99 20.45,46.13 22.13,46.13 v2(22.44,46.43)
  L4 w1.27: v2(166.81,5.54) 172.08,5.54 177.87,11.33 177.87,27.25 177.86,27.26 177.86,38.76 178.19,39.09 178.19,48.26
  BOTTOM w0.508: v3(28.86,49.33) 28.86,49.14 26.16,46.43 v2(22.44,46.43) ; v2(149.28,28.63) 149.21,28.55 149.21,27.79 148.81,27.39 Q2907.E 148.26,27.23 147.28,26.25 147.28,24.66 ; v2(125.43,160.83) 125.43,158.25 132.47,151.21 138.16,151.21 147.05,142.32 148.06,142.32 149.64,140.74 151.37,140.74 154.44,137.67 160.26,137.67 v2(160.38,137.8) ; v2(160.19,82.41) 160.69,82.91 161.94,82.91 163.58,84.55 163.58,85.83 v2(163.79,86.03) ; v2(19.95,53.57) 19.36,53.57 17.61,55.32 17.46,55.32 17.3,55.48 16.52,55.48 16.02,55.98 Q5702.G 16.02,57.87 R5718.1 16.85,58.7 v2(20.1,58.7)
  vias: v3(29.6,48.82) v3(29.83,49.71) v3(30.54,48.8) v3(30.72,49.66) v3(37.45,26.65) v3(37.5,25.43) v3(44.66,28.27) v3(45.7,28.32) v3(46.64,28.35) v3(47.96,28.42) v3(130.41,23.73) v3(130.46,22.79) v3(130.49,21.85) v3(147.13,23.31) v3(177.12,136.76) v3(177.15,135.61) v3(177.15,134.5) v4(178.85,50.04)
5V_S0_CT: length 3
  TOP w0.203: 29.57,50.67 29.41,50.83 U4001.10
  TOP w0.254: 29.57,50.67 29.77,50.47 v1(30.03,50.47) 30.44,50.47 30.67,50.69 C4003.1
5V_S0_SIP:
  vias: v1(149.54,19.23)
5V_S5: length 264
  TOP w0.203: U4001.4 25.9,51.23
  TOP w0.508: 137.8,125.5 137.8,125 141.14,121.66 141.14,120.48 139.41,118.75 137.71,118.75 132.72,113.76 v2(131.7,113.76) ; v2(134.47,135.03) 135.16,135.71 PR5031.1 ; PR5101.1 127.36,136.91 126.73,137.54 v2(125.94,137.54) 125.94,140.03 131.16,145.25 131.16,145.27 133.88,147.99 133.9,147.99 137.65,151.74 137.65,153.32 138.41,154.08 138.41,158.73 136.06,161.08 PR4303.1 ; v3(162.36,9.73) 162.62,9.48 EC8909.1 ; DB3.1 62.6,44.01 61.8,44.81 60.08,44.81 57.69,42.42 57.69,41.02 56.7,40.03 56.7,37.59 53.32,34.22 PR5104.1 53.32,31.17 v2(53.4,31.09) ; v2(48.27,59.59) 49.23,59.59 49.98,58.84 PR4506.1
  L3 w0.508: v2(34.98,66.91) 37.32,66.91 38.16,66.07 38.16,62.08 39.2,61.04 42.98,61.04 44.43,59.59 v2(48.27,59.59)
  L4 w0.508: v2(53.4,31.09) 53.17,30.86 45.04,30.86 42.91,28.73 v2(42.91,28.12)
  BOTTOM w0.203: PU5001.36 132.26,126.41 v2(131.83,125.99) ; v2(137.49,130.76) 137.35,130.76 137.29,130.7 PU5001.19
  BOTTOM w0.305: v2(131.7,113.76) U4002.4
  BOTTOM w0.508: v2(163.84,7.67) 164.38,7.13 EC4001.1 164.69,7.13 165.01,7.44 166.48,7.44 167.47,6.45 167.96,6.45 Q6404.E 167.99,7.33 168.4,7.74 169.54,7.74 169.88,8.08 169.88,10.06 169.59,10.35 Q6403.E ; PC5007.1 PC5008.1 130.97,125.12 v2(131.83,125.99) ; v2(99.6,138.81) 98.97,138.18 98.97,136.04 99.52,135.49 99.52,135.41 PR5103.1
  BOTTOM w1.016: v3(96.71,143.41) 95.41,143.41 93.35,141.35 93.35,104.63 93.16,102.55 92.9,101.9 92.73,101.72 92.51,100.41 92.51,97.39 92.21,96.7 91.33,94.32 89.43,90.31 88.98,89.58 88.97,89.56 88.93,89.49 88.51,88.98 88.51,88.98 84.66,84.28 83.7,83.24 82.64,82.18 80.34,80.47 76.73,78.46 73.98,77.3 73.74,77.24 73.7,77.24 72.88,77.03 71.23,76.63 66.89,75.74 61.07,75.74 59.95,74.63 42.7,74.63 v2(34.98,66.91) 34.32,66.25 v3(23.1,66.25) v3(22.23,65.38) ; v3(25.41,49.28) 26.45,49.28 v3(26.5,49.33)
  vias: v1(136,125.17) v3(96.63,142.37) v3(137.55,127.69) v3(143.34,15.34) v3(144.23,15.34) v3(161.42,9.7)
5V_S5_EN: length 15.5
  BOTTOM w0.14: R4007.1 PR4501.2 50.43,52.08 50.43,51.18 50.81,50.8 50.81,49.84 49.89,48.92 PR4530.1 49.4,48.01 PR4504.1 49.27,47.67 48.55,46.94 48.55,43.25 D4001.2 50.04,42.45 v1(50.94,43.36) PR4502.1
5V_USB30: length 234.7
  TOP w0.508: 13.57,35.05 USB1.1 ; USB1.1 14.28,34.34 ; USB1.1 14.28,35.76 ; USB1.1 14.99,35.05 ; v2(118.5,170.64) 118.32,170.46 EU5501.5 ; 14.28,17.26 USB2.1 14.99,16.55 ; EU3502.5 19.16,23.62 v3(18.93,23.85)
  L3 w0.508: USB1.1 14.99,35.05 ; USB1.1 14.28,34.34 ; USB1.1 14.28,35.76 ; USB2.1 14.28,17.26 ; USB2.1 14.99,16.55 ; USB2.1 14.28,15.84 ; v2(121.47,154.84) 115.78,154.84 114.18,156.44 108.69,156.44 95.89,143.64 95.89,134.59 95.89,119.55 95.89,119.15 95.89,119.15 95.89,118.78 95.89,118.78 95.89,118.41 95.89,117.56 95.89,115.39 96.63,114.65 96.63,104.77 100.24,101.15 100.24,98.7 98.65,97.11 98.56,97.11 98.56,97.11 98.4,96.95 98.4,96.95 97.68,96.23 96.96,95.51 v2(95.23,95.51)
  L4 w0.508: v3(15.5,38.53) 15.5,46.71 16.72,47.93 16.72,56.66 16.67,56.71 16.67,64.04 20.15,67.52 23.48,67.52 25.08,69.12 38.79,69.12 39.99,70.31 v2(40.75,70.31)
  BOTTOM w0.508: v2(121.47,154.84) 124.24,157.61 124.24,160.38 122.36,162.26 122.36,165.51 118.5,169.37 v2(118.5,170.64) ; v2(40.75,70.31) 53.42,70.31 55.89,67.85 59.38,67.85 64.32,72.79 64.32,73.65 65.38,74.7 67.82,74.7 69.22,74.9 74.28,76.45 76.96,77.57 77.97,78.13 78.43,78.33 78.86,78.63 81.22,79.95 83.23,81.51 84.34,82.62 85.33,83.7 89.24,88.47 89.65,88.97 89.7,89.04 90.14,89.58 91.78,92.66 91.82,92.76 92.2,93.14 92.24,93.19 92.24,93.2 92.38,93.37 92.43,93.38 94.38,95.33 94.55,95.51 v2(95.23,95.51)
  vias: v3(15.58,37.42) v3(16.57,38.58) v3(16.64,37.47) v3(17.81,17.02) v3(18.79,17.03)
19V_AD+: length 107.6
  TOP w0.406: v1(162.75,168.93) v2(162.16,168.93) PU4403.4
  TOP w0.508: v2(166.99,157.18) 167.34,157.53 PR4405.1 167.85,157.52 PR4404.1 ; PR4407.1 156.57,144.68 v2(156.6,144.66) ; v2(174.28,158.78) 174.53,159.03 176.61,159.03 176.67,159.09 177.95,159.09 178.9,160.05 178.9,162.03 178.49,162.44 PR4469.1 ; PR4408.1 157.53,157.53 v2(158.37,158.37)
  L3 w0.508: v2(174.28,158.78) 173.89,158.78 172.01,156.9 167.27,156.9 v2(166.99,157.18) 164.98,159.19 159.18,159.19 v2(158.37,158.37) ; v2(142.43,170.86) 159.65,170.86 161.59,168.93 v2(162.16,168.93)
  L4 w0.508: v2(156.6,144.66) 156.6,145.36 158.76,147.52 158.76,151.77 158.37,152.16 v2(158.37,158.37)
  BOTTOM w0.508: v2(142.43,170.86) 142.43,169.78 140.49,167.85 v2(140.49,157.94) 140.49,153.76 143.34,150.92 143.34,149.88 144.45,148.77 145.68,148.77 148.04,146.41 150.5,146.41 152.38,144.53 154.85,144.53 154.97,144.66 v2(156.6,144.66)
19V_DCBATOUT: length 202.3
  TOP w0.203: PU4503.12 48.94,48.99 48.91,49.03 48.59,49.03 48.09,49.53 v2(48.09,49.68)
  TOP w0.508: PC4531.1 46.65,48.66 47.2,49.2 PC4519.1 v2(48.09,49.68) ; PR4468.1 176.04,161.38 175.45,160.78 v2(174.35,160.78)
  L3 w0.102: v2(36.43,22.96) 36.61,23.14 48.5,23.14 50.93,25.58 50.93,38.43
  L3 w0.508: v2(174.35,160.78) 171.89,158.32 167.32,158.32 164.29,161.34 v3(160.46,161.34)
  L4 w0.102: v2(36.43,22.96) 37.95,24.49 50.96,24.49 51.77,25.3 131.68,25.3 133.97,23.01 133.97,21.48 135.4,20.04 140.92,20.04 141.26,20.39 146.96,20.39 v2(147.17,20.6)
  BOTTOM w0.102: v2(147.17,20.6) 146.76,21.02 R2726.1
  BOTTOM w0.508: v2(48.09,49.68) 48.09,50.24 47.91,50.42 47.91,57.81 ; PR5007.1 PR5008.1 133.57,137.77 133.57,138.11 132.34,139.35 131.47,139.35 v2(127.01,143.81)
  BOTTOM w1.016: v3(96.3,162.77) 95.59,162.05 95.59,156.49 98.13,153.95 v3(98.13,147.75)
  vias: v1(111.56,136.53) v3(45.03,60.58) v3(46.31,60.58) v3(50.81,41.53) v3(50.81,40.41) v3(51.57,42.45) v3(51.82,41.35) v3(52.61,42.39) v3(54.62,54.84) v3(54.59,53.57) v3(55.81,53.6) v3(55.91,54.82) v3(57.03,53.55) v3(57.28,54.79) v3(58.4,53.58) v3(58.68,54.76) v3(59.9,54.74) v3(112.78,141.23) v3(114,141.23) v3(123.37,149.47) v3(123.38,148.24) v3(123.48,150.84) v3(124.58,149.54) v3(124.59,148.26) v3(131.24,158.46) v3(131.78,157.36) v3(132.54,156.34) v3(133.79,156.12) v3(133.8,154.89) v3(133.9,157.49) v3(135.01,156.19) v3(135.02,154.91) v3(135.77,157.41) v3(136.24,154.97) v3(136.3,156.19) v3(155.55,165.66) v3(156.5,166.63) v3(156.52,164.92) v3(157.54,165.81) v3(157.67,164.34) v3(157.94,167.01) v3(158.4,162.92) v3(158.86,165.89) v3(158.97,164.6) v3(159.52,163.43) v3(159.47,162.18) v3(160.19,164.89) v3(160.74,163.8) v3(160.77,162.58)
19V_DCBATOUT_LCD:
  vias: v3(100.16,167.79)
+3.3V_1.8V_DVDD-IO: length 4.9
  BOTTOM w0.203: HDA27.9 162.46,24.43 162.69,24.67 v1(162.97,24.67)
  BOTTOM w0.254: R2729.2 165.09,25.65 C2723.2 164.25,25.66 C2719.1 163.13,25.62 163.13,24.82 v1(162.97,24.67)
+3V_1D5V_AVDD: length 5.8
  BOTTOM w0.203: HDA27.40 157.48,19.45
  BOTTOM w0.254: C2721.1 154.71,17.13 C2715.1 R2724.2 155.86,19.22 157.25,19.22 157.48,19.45
+3V_AVDD: length 14.9
  TOP w0.254: R2711.1 163.96,23.94 163.48,23.47 v1(161.62,23.47) 160.03,23.47 C2717.1 158.72,23.46 v2(158.71,23.48)
  BOTTOM w0.203: HDA27.1 v2(158.71,23.48)
  BOTTOM w0.254: R2706.1 153.5,26.19 R2708.2 153.65,27.41 C2716.1 155.4,25.66 156.27,25.66 156.57,25.35 156.98,25.35 157.08,25.25 157.08,25.25 157.33,25 157.33,24.99 157.51,24.82 157.51,24.51 158.55,23.48 v2(158.71,23.48)
+5V_AVDD: length 9.7
  TOP w0.508: R2720.1 167.65,11.89 v1(167.15,12.39) v2(166.61,12.93)
  BOTTOM w0.203: HDA27.26 163.26,16.81 163.81,16.26 163.81,16
  BOTTOM w0.508: 163.81,16 163.81,13.45 C2710.1 164.03,13.24 C2711.1 164.98,13.21 166.33,13.21 v2(166.61,12.93)
+5V_KB_BL: length 5
  TOP w0.406: 158.68,129.77 KBBL1.1
  TOP w0.508: 158.68,129.77 158.28,129.37 AFTP6501.1 157.49,129.43 C6501.1 155.6,129.43 R6504.2
+5V_PVDD: length 3.9
  BOTTOM w0.203: 156.31,19.85 HDA27.41 ; HDA27.46 157.96,21.85 157.87,21.95 157.49,22.33 157.49,23
  vias: v1(153.78,22.94)
DVSS: length 4.5
  BOTTOM w0.102: HDA27.4 160.46,23.88 160.23,24.11 160.18,24.11 158.71,25.59 R2707.1 158.21,26.13 v1(157.82,26.52)
GND: length 989.3
  TOP w0.203: U4001.11 29.73,51.23 v2(29.8,51.16)
  TOP w0.254: C1005.2 129.1,89.28 C1018.2 129.7,89.51 v2(130.32,89.23)
  TOP w0.305: PU4404.14 v2(163.72,151.76) ; ODD1.7 v2(172.91,143.55) ; PU5107.6 124.34,134.27 124.5,134.11 v2(124.75,134.11) ; v2(44.55,66.9) 44.68,67.03 45.17,67.03 45.43,66.77 XDP1.58 ; v2(172.83,142.14) 172.92,142.05 ODD1.4 ; v2(57.92,34.18) 57.7,34.18 57.6,34.08 57.59,34.08 57.42,33.91 57.42,33.9 57.36,33.83 PU5108.6 ; XDP1.57 v2(45.43,73.15) ; ODD1.1 v2(172.91,140.55) ; XDP1.16 55.93,63.92 55.65,63.64 55.33,63.64 55.3,63.67 v2(55.3,63.67)
  TOP w0.406: v2(47.35,69.68) 47.35,69.17 48.19,68.33 XDP1.63 ; v2(170.44,157.53) 171.13,156.85 PQ4402.1 ; v2(58.5,68.48) 58.66,68.33 XDP1.61 ; v2(52.23,67.87) 52.69,68.33 XDP1.62 ; PQ4408.4 168.05,152.28 v2(168.03,152.25) 168.08,152.2 PQ4410.1 ; PQ4408.1 v2(164.79,154.32) ; v2(17.42,46.69) 17.35,46.61 ED5701.8 ED5701.3 14.16,46.61 v2(14.08,46.53) ; v2(19.46,15.39) 19.24,15.17 EU3504.3 EU3504.8 16.75,15.17 16.01,14.43 v2(15.78,14.43) ; v2(17.43,50.14) 17.41,50.12 ED5702.8 ED5702.3 14.66,50.12 v2(14.43,50.34) ; ED5703.8 ED5703.3 v2(14.1,56.03) ; XDP1.64 42.43,68.33 v2(42.4,68.3) ; v2(164.27,84.15) 163.05,84.15 162.69,83.8 Q7001.4 ; v2(172.52,154.41) 172.8,154.41 173.01,154.61 PQ4402.4 ; Q7001.1 v2(165.46,82.21)
  TOP w0.508: BATT2.7 154.25,182.61 ; BATT2.7 154.25,180.99 ; BATT2.7 153.44,181.8 ; C6303.2 52.92,58.37 v2(53.19,58.09) 53.66,57.62 EC8908.2 ; v2(69.65,72.67) 70.04,72.29 SPR1.1 ; 125.31,80.96 v2(124.82,81.61) ; v2(155.38,27.33) 155.2,27.51 R2928.2 ; 10.52,23.85 USB1.11 ; USB1.11 12.3,22.96 ; USB1.11 14.08,23.85 ; v2(157.09,178.11) 156.87,178.11 156.31,177.54 EC8901.2 ; v2(172.91,61.67) 173.44,61.14 C2430.2 ; C2445.2 173.62,53.71 173.62,53.24 v2(173.44,53.06) ; BATT1.10 150.01,185.8 ; BATT1.10 148.24,185.8 ; BATT1.10 149.12,183.92 ; PR4470.2 v2(174.38,162.44) ; v2(58.3,50.19) 58.2,50.29 C2502.2 C2501.2 ; v2(140.04,90.4) 139.93,90.4 C1014.2 ; R1526.2 108.61,90.17 v2(109.44,90.24) ; R2023.2 171.39,48.93 170.54,48.08 170.54,48.02 169.9,47.38 v2(169.9,46.91) 169.76,46.77 C2601.2 ; PR4517.2 55.32,51.51 PR4523.2 54.27,50.81 v2(53.91,50.45) ; PC4501.2 49.98,56.66 v2(50.17,56.47) ; v2(149.71,92.15) 148.88,92.99 PC1102.2 ; v2(52.69,46) 52.62,45.94 PR4526.2 ; USB2.10 14.08,20.75 ; USB2.10 12.3,21.64 ; USB2.10 10.52,20.75 ; R2005.1 123.17,94.64 R2007.1 122.79,95.48 v2(122.66,95.71) ; USB1.4 14.28,28.76 ; USB1.4 14.28,27.34 ; USB1.4 13.57,28.05 ; v2(158.66,130.53) 156.8,130.53 156.46,130.19 155.28,130.19 155.15,130.06 R6507.2 ; 6.46,20.75 USB2.12 4.87,21.64 ; R2440.1 C2431.2 167.69,66.04 v2(167.05,66.68) ; KBBL1.6 162.86,135.42 163.33,135.89 v2(164.35,135.89) ; R1816.1 115.02,85.17 v2(115.05,85.33) ; R9917.2 56.27,75.52 v2(56.07,75.72) ; R1511.2 108.97,87.02 v2(108.41,86.97) ; 152.25,180.99 BATT2.8 ; BATT2.8 153.06,181.8 ; BATT2.8 152.25,182.61 ; BATT2.8 151.44,181.8 ; ED1202.2 87.56,31.95 v2(87.53,31.98) ; v2(105.16,172.04) 104.95,171.82 R5502.1 ; C4003.2 32.46,50.68 EC8931.2 v2(33.13,49.84) ; 4.87,4.46 USB2.13 6.46,5.35 ; v2(55.3,63.67) 55.29,63.67 55.29,63.63 55.01,63.34 C9902.2 ; EC5506.2 v2(106.51,172.52) ; EU5501.2 v2(118.32,165.97) ; v2(19.39,19.05) 19.16,19.28 EU3502.2 ; EC2703.2 162.52,19.06 EC2705.2 162.53,19.91 EC2706.2 162.52,20.47 v2(162.36,20.63) ; v2(112.21,94.86) 112.8,94.27 R803.1 113.16,94.28 PC1010.2 ; R2001.1 v2(126.43,96.24) ; Q2502.S v2(29.13,24.7) ; v2(91.9,32.79) 92.16,32.79 92.63,32.32 ED1201.2 92.64,30.85 R1212.2 ; 153.36,185.8 BATT1.7 ; BATT1.7 154.25,184.91 ; BATT1.7 154.25,186.69 ; 2.26,42.35 HDMI1.22 ; HDMI1.22 3.7,41.36 ; HDMI1.22 5.14,42.35 ; v2(65.29,50.42) 65.08,50.42 64.8,50.14 EC2502.2 ; C1215.2 120.43,41.98 v2(120.98,42.54) ; C1003.2 v2(127.7,92.96) ; PC1046.2 139.9,92.03 v2(139.43,92.11) C1107.2 ; v2(110.17,79.38) 110.42,79.62 R2002.1 ; v2(173.31,27.99) 172.87,28.44 C2503.2 172.67,28.44 C2504.2 ; v2(133.03,160.96) 133.02,160.97 PQ4302.E 130.07,160.97 PD4302.1 ; v2(133.29,164.35) PR4302.2 134.14,165.03 PR4308.2 ; 10.52,5.35 USB2.11 ; USB2.11 14.08,5.35 ; USB2.11 12.3,4.46 ; PD4303.3 v2(133.24,168.42) ; C6304.2 50.08,62.27 C9903.2 51.09,61.62 v2(50.88,61.42) ; PR4436.2 171.06,152.74 v2(170.54,152.22) ; R1702.1 v2(136.89,93.22) ; C1015.2 v2(133.15,88.81) ; HS1.1 120.65,162.18 ; HS1.1 120.65,155.82 ; HS1.1 117.47,159 ; HS1.1 123.83,159 ; HDMI1.20 11.64,44.25 ; HDMI1.20 10.2,43.26 ; HDMI1.20 10.2,45.24 ; v2(117.79,42.54) 117.84,42.49 C1213.2 ; 10.52,39.25 USB1.10 12.3,40.14 ; PC4425.2 163.89,151.76 v2(163.72,151.76) ; R7011.2 159.15,84.16 159.73,84.74 v2(160.79,84.74) ; v2(58.43,48.24) 58.35,48.31 EC2503.2 ; EC8930.2 v2(32.98,48.97) ; PC5109.2 55.49,34 v2(55.71,33.78) ; C6301.2 57.07,58.28 v2(57.28,58.06) ; 169.37,183.92 BATT1.9 ; BATT1.9 168.49,185.8 ; BATT1.9 170.26,185.8 ; C6502.2 v2(158.64,131.97) ; C6305.2 59.24,61.88 v2(59.9,62.54) 59.91,62.54 60.19,62.54 60.64,62.99 C6302.2 ; v2(117.79,141.73) 118.21,142.15 EC8904.2 ; BATT1.8 153.14,185.8 ; BATT1.8 152.25,186.69 ; BATT1.8 151.36,185.8 ; BATT1.8 152.25,184.91 ; HDMI1.21 11.64,58.75 ; HDMI1.21 10.2,59.74 ; HDMI1.21 10.2,57.76 ; v2(152.76,31.47) 152.69,31.4 152.11,31.4 151.4,32.1 C1207.2 C1208.2 ; C1005.2 128.81,87.82 PC1006.2 ; v2(173.92,51.21) 173.94,51.18 R7005.1 ; v2(165.92,44.52) C6009.2 ; v2(119.44,42.54) 119.51,42.46 C1214.2 ; C9904.2 43.03,63.1 v2(43.19,63.25) ; v2(120.94,87.37) 120.7,88.09 120.2,88.15 PC1103.2 ; C1101.2 v2(120.71,85.73) ; Q1802.S 160.31,68.75 159.85,69.22 v2(158.71,69.22) ; R6505.2 159.96,137.04 v2(159.21,137.04) 158.34,137.04 Q6501.S ; v2(57.64,46.39) 57.38,46.13 EC2501.2 ; EC8905.2 v2(137.28,157.63) ; 6.46,23.85 USB1.13 4.87,22.96 ; 133.69,84.43 v2(134.42,84.59) ; v2(100.95,109.6) 100.95,109.4 100.59,109.04 EC8907.2 ; KBBL1.5 158.79,127.57 v2(158.6,127.38) AFTP6537.1 ; v2(99.68,64.01) 100.03,63.65 102.34,63.65 102.89,64.2 R2101.2 ; C3605.2 22.56,18.14 v2(22.82,17.88) ; PR4432.2 157.36,143.84 v2(157.21,143.69) ; PR4405.2 v2(170.44,157.53) ; 14.28,8.84 USB2.4 14.99,9.55 ; R1211.2 123.26,30.9 123.85,31.49 v2(123.85,32.46) ; EC2505.2 EC2504.2 173.55,33.36 v2(173.29,33.63) ; v2(162.9,157.63) 162.72,157.46 PC4407.2 ; v2(127.59,135.21) 127.52,135.28 PC5103.2 ; PC4401.2 155.1,148.7 155.1,147.84 PR4433.2 155.1,147.82 v2(155.1,147.14) ; v2(99.04,129.29) 98.72,129.61 EC8906.2 ; 2.26,60.65 HDMI1.23 ; HDMI1.23 3.7,61.64 ; HDMI1.23 5.14,60.65 ; v2(47.06,30.05) 47,30.11 EC8928.2 ; SPR4.1 71.4,46.5 72.32,47.42 v2(73.46,47.42) ; R2516.2 23.41,23.66 v2(21.06,26.01) ; R2006.1 120.01,94.26 120.01,94.65 v2(119.98,94.68) ; v2(166,47.91) 166.17,48.08 EC2403.2 EC2402.2 ; v2(105.06,80.01) 104.85,79.8 EC1902.2 ; v2(159.9,61.57) 159.47,62 157.08,62 156.76,61.69 C2440.2 C2441.2 ; KB1.32 173.45,95.14 v2(173.84,94.74) ; v2(170.8,25.22) 171.17,25.22 171.41,24.98 R6601.1 ; v2(114.97,41.91) 115.06,42 C1206.2 ; v2(45.04,47.53) 45.3,47.27 PC4524.2 45.77,47.39 PC4531.2 45.77,48.92 45.52,49.16 PC4519.2 ; v2(98.51,155.45) 99.02,155.96 C5516.2 101.33,155.96 101.56,156.19 R5503.1 ; C1106.2 R2003.1 v2(130.38,91.63) ; v2(32.06,53.14) 32.32,52.88 EC4004.2 32.32,52.1 32.49,51.92 C4014.2 ; 136.76,85.16 v2(136.04,84.95) ; 6.46,39.25 USB1.12 4.87,40.14 ; PC1101.2 v2(127.12,86.55) ; C6501.2 v2(158.66,128.54) ; PC1001.2 v2(135.13,82.5) ; EC8916.2 97.4,159.6 96.91,160.1 v2(96.83,160.1) ; R9906.2 53.44,75.07 53.07,75.44 v2(53.07,75.52) ; EC6506.2 v2(146.15,32.6) ; v2(161.7,143.46) EC4310.2 ; C5514.2 118.73,176.35 119.21,176.84 v2(119.49,176.84)
  L3 w0.508: USB2.11 14.08,5.35 ; USB2.11 10.52,5.35 ; USB2.11 12.3,4.46 ; USB1.11 14.08,23.85 ; USB1.11 12.3,22.96 ; USB1.11 10.52,23.85 ; 4.87,4.46 USB2.13 6.46,5.35 ; 4.87,40.14 USB1.12 6.46,39.25 ; 151.44,181.8 BATT2.8 ; BATT2.8 153.06,181.8 ; BATT2.8 152.25,182.61 ; BATT2.8 152.25,180.99 ; USB2.10 12.3,21.64 ; USB2.10 10.52,20.75 ; USB2.10 14.08,20.75 ; BATT2.7 154.25,182.61 ; BATT2.7 154.25,180.99 ; BATT2.7 153.44,181.8 ; BATT2.7 155.06,181.8 ; 11.6,50.5 HDMI1.8 10.3,50.5 ; BATT1.10 150.01,185.8 ; BATT1.10 148.24,185.8 ; BATT1.10 149.12,183.92 ; 2.26,60.65 HDMI1.23 ; HDMI1.23 3.7,61.64 ; HDMI1.23 5.14,60.65 ; 152.25,184.91 BATT1.8 ; BATT1.8 153.14,185.8 ; BATT1.8 152.25,186.69 ; BATT1.8 151.36,185.8 ; USB1.7 13.49,31.55 ; USB1.7 12.78,32.26 ; USB1.7 12.78,30.84 ; 10.2,43.26 HDMI1.20 ; HDMI1.20 10.2,45.24 ; HDMI1.20 11.64,44.25 ; 14.28,8.84 USB2.4 ; USB2.4 14.28,10.26 ; USB2.4 13.57,9.55 ; USB2.4 14.99,9.55 ; USB2.7 12.78,13.76 ; USB2.7 13.49,13.05 ; USB2.7 12.78,12.34 ; 2.26,42.35 HDMI1.22 ; HDMI1.22 3.7,41.36 ; HDMI1.22 5.14,42.35 ; USB1.10 12.3,40.14 ; USB1.10 14.08,39.25 ; USB1.10 10.52,39.25 ; 6.46,20.75 USB2.12 4.87,21.64 ; 168.49,185.8 BATT1.9 ; BATT1.9 169.37,183.92 ; BATT1.9 170.26,185.8 ; 4.87,22.96 USB1.13 6.46,23.85 ; USB1.4 14.28,28.76 ; USB1.4 14.99,28.05 ; USB1.4 13.57,28.05 ; USB1.4 14.28,27.34 ; 154.25,184.91 BATT1.7 ; BATT1.7 154.25,186.69 ; BATT1.7 155.14,185.8 ; BATT1.7 153.36,185.8 ; 10.2,57.76 HDMI1.21 ; HDMI1.21 11.64,58.75 ; HDMI1.21 10.2,59.74 ; 10.95,46.93 HDMI1.2 ; HDMI1.2 10.3,47.5 ; HDMI1.2 11.6,47.5
  L4 w0.508: BATT1.9 170.26,185.8 ; BATT1.9 168.49,185.8 ; BATT1.9 169.37,183.92 ; BATT1.8 152.25,186.69 ; BATT1.8 151.36,185.8 ; BATT1.8 152.25,184.91 ; BATT1.8 153.14,185.8 ; USB2.10 14.08,20.75 ; USB2.10 12.3,21.64 ; USB2.10 10.52,20.75 ; BATT1.7 155.14,185.8 ; BATT1.7 154.25,184.91 ; BATT1.7 153.36,185.8 ; BATT1.7 154.25,186.69 ; HDMI1.20 11.64,44.25 ; HDMI1.20 10.2,43.26 ; HDMI1.20 10.2,45.24 ; USB2.7 12.78,13.76 ; USB2.7 12.78,12.34 ; USB2.7 13.49,13.05 ; 13.57,28.05 USB1.4 ; USB1.4 14.99,28.05 ; USB1.4 14.28,27.34 ; USB1.4 14.28,28.76 ; 11.6,50.5 HDMI1.8 10.3,50.5 ; 10.2,57.76 HDMI1.21 ; HDMI1.21 11.64,58.75 ; HDMI1.21 10.2,59.74 ; USB1.11 14.08,23.85 ; USB1.11 12.3,22.96 ; USB1.11 10.52,23.85 ; 151.44,181.8 BATT2.8 ; BATT2.8 153.06,181.8 ; BATT2.8 152.25,180.99 ; BATT2.8 152.25,182.61 ; USB1.10 12.3,40.14 ; USB1.10 14.08,39.25 ; USB1.10 10.52,39.25 ; 10.95,46.93 HDMI1.2 ; HDMI1.2 10.3,47.5 ; HDMI1.2 11.6,47.5 ; HDMI1.23 3.7,61.64 ; HDMI1.23 2.26,60.65 ; HDMI1.23 5.14,60.65 ; 4.87,22.96 USB1.13 6.46,23.85 ; 6.46,39.25 USB1.12 4.87,40.14 ; BATT2.7 155.06,181.8 ; BATT2.7 154.25,180.99 ; BATT2.7 154.25,182.61 ; BATT2.7 153.44,181.8 ; 4.87,4.46 USB2.13 6.46,5.35 ; 10.52,5.35 USB2.11 ; USB2.11 14.08,5.35 ; USB2.11 12.3,4.46 ; 14.28,8.84 USB2.4 ; USB2.4 13.57,9.55 ; USB2.4 14.99,9.55 ; USB2.4 14.28,10.26 ; 148.24,185.8 BATT1.10 ; BATT1.10 149.12,183.92 ; BATT1.10 150.01,185.8 ; 2.26,42.35 HDMI1.22 ; HDMI1.22 3.7,41.36 ; HDMI1.22 5.14,42.35 ; 4.87,21.64 USB2.12 6.46,20.75 ; USB1.7 13.49,31.55 ; USB1.7 12.78,32.26 ; USB1.7 12.78,30.84
  BOTTOM w0.076: 53.14,59.15 53.32,58.93 53.32,58.22 v2(53.19,58.09) 53.04,58.09 52.82,58.31 52.82,58.94 53.04,59.15 U6301.N2 53.14,59.15
  BOTTOM w0.127: U6301.C4 57.72,60.49 57.4,60.49 57.06,60.15 56.86,60.15 v2(56.85,60.15) ; U6301.P4 52.56,60.17 53.05,60.65 U6301.N5
  BOTTOM w0.152: 59.65,61.6 59.62,61.6 59.18,61.15 U6301.A6
  BOTTOM w0.203: v2(172.91,61.67) 173.06,61.52 KBC24.45 ; v2(163,53.52) 163.05,53.47 KBC24.89 ; v2(108.41,86.97) 108.89,86.97 CPU1.N63 ; CPU1.A40 117.59,95.79 CPU1.C40 ; v2(167.52,53.7) 167.45,53.63 KBC24.78 ; CPU1.AA63 109.99,83.46 v2(109.57,83.23) ; v2(115.77,70.4) 116.34,71.09 CPU1.BJ60 ; CPU1.BH43 124.03,74.65 124.22,74.12 v2(124.33,73.6) ; CPU1.BD56 117.05,75.17 117.25,75.6 117.27,75.62 117.37,75.83 v2(117.53,76.25) ; PU5001.7 v2(133.46,131.85) ; v2(119.26,71.56) 119.28,71.6 119.28,72.43 CPU1.BJ54 ; v2(140.04,90.4) 139.5,90.2 139.45,90.2 ; CPU1.BJ56 117.89,71.87 v2(117.84,71.27) ; CPU1.BD61 115.12,73.85 115.12,73.42 115.18,73.36 115.18,73.34 CPU1.BF61 115.37,73.05 v2(115.52,72.63) ; v2(159.9,61.57) 159.85,61.52 KBC24.116 ; v2(161.86,66.73) 161.85,66.73 KBC24.5 ; CPU1.BA62 113.94,74.9 113.85,74.9 113.73,74.86 113.53,74.86 CPU1.BA63 ; KBC24.18 v2(167.05,66.68) ; v2(125.99,74.56) 125.84,75.18 CPU1.BH39
  BOTTOM w0.229: CPU1.BJ50 121.02,73.11 121.11,72.87 121.15,72.83 121.24,72.57 v2(121.24,72.04)
  BOTTOM w0.254: v2(134.88,96.45) 134.97,96.45 135.27,96.16 CPU1.P5 135.52,96.69 135.52,96.69 CPU1.M3 ; v2(115.84,96.18) 115.81,96.15 115.81,95.86 CPU1.A44 ; CPU1.AT61 CPU1.AT62 112.92,76.98 112.71,76.9 112.71,76.9 112.63,76.87 112.55,76.79 v2(112.31,76.63) ; CPU1.BE37 v2(126.5,77) ; v2(126.5,77) CPU1.BG35 ; v2(126.5,77) CPU1.BE35 ; v2(116.93,74.29) CPU1.BD56 ; CPU1.AJ63 111.24,79.93 v2(110.17,79.38) ; v2(120.62,74.99) 120.79,75.21 CPU1.BE48 CPU1.BE47 ; v2(122.7,98.71) CPU1.A28 CPU1.C28 ; v2(110.64,81.25) 110.67,81.5 110.98,81.81 ; CPU1.BJ46 122.82,73.63 122.81,73.62 v2(122.99,73.13) ; v2(124.82,81.61) CPU1.AT35 125.49,81.15 125.53,81.06 CPU1.AV35 ; v2(117.15,96.59) 117.42,96.35 CPU1.A40 ; CPU1.E54 v2(112.21,92.55) ; CPU1.C12 129.88,100.31 CPU1.A12 ; C1113.2 104.4,99.54 v2(103.92,99.44) ; DM1.8 84.07,31.89 v2(84.34,32.16) ; DM1.156 130.87,31.97 v2(130.85,32) ; CPU1.AK48 118.73,82.17 v2(118.4,82.5) 118.4,82.95 CPU1.AH48 ; CPU1.A20 126.26,99.93 v2(126.35,100.02) ; v2(112.21,94.86) 112.23,94.84 112.27,94.56 CPU1.A52 ; v2(119.72,77.54) 119.97,77.51 CPU1.BA48 ; CPU1.BA39 v2(123.94,78.38) CPU1.BB39 ; v2(114.28,77.06) CPU1.AV61 CPU1.AV62 ; CPU1.P59 v2(110.41,87.55) CPU1.M59 ; v2(131.19,101.83) 131.32,101.41 CPU1.A9 CPU1.B9 ; CPU1.Y59 v2(111.77,84.15) CPU1.AB59 ; CPU1.A36 119.22,97.08 v2(119.14,97.47) ; v2(122.19,77.89) 122.04,77.57 CPU1.BB45 ; v2(112.48,88.39) 112.71,88.17 CPU1.P55 ; v2(109.94,94.06) 110.15,93.77 CPU1.A56 ; CPU1.F43 v2(116.5,93.53) CPU1.F45 ; v2(113.01,74.39) 113.14,74.66 113.25,74.7 CPU1.BA63 ; CPU1.C48 CPU1.A48 v2(113.77,95.42) ; CPU1.A24 v2(124.2,99.22) ; CPU1.AN63 v2(111.7,78.14) ; CPU1.G1 v2(136.56,99.85) ; DM1.14 85.87,31.89 v2(85.73,32.03) ; CPU1.BE52 118.97,74.9 118.77,74.99 v2(118.66,74.95) 118.48,74.84 CPU1.BE54 ; v2(127.32,74.97) 127.15,75.26 CPU1.BJ36 ; CPU1.M21 127.6,94.27 127.54,94.43 CPU1.L21 127.78,94.75 v2(128.05,94.62) 127.85,95.18 CPU1.J19 ; v2(123.02,75.72) 123.27,76.08 CPU1.BE43 ; v2(124.41,96.37) CPU1.E27
  BOTTOM w0.279: CPU1.BG45 122.97,75.44 v2(123.02,75.72) ; v2(133.59,98) 133.91,97.8 CPU1.K6 134.24,97.71 CPU1.K5
  BOTTOM w0.305: DM1.155 130.57,36.93 130.92,36.58 v2(131.66,36.58) ; DM1.187 140.17,39.83 v2(139.84,40.16) 139.57,39.89 DM1.185 ; CPU1.BA47 v2(121.19,78.17) ; DM1.25 89.16,38.71 v2(89.16,37.26) ; CPU1.D58 109.89,91.95 v2(109.95,91.58) ; DM1.20 87.67,31.8 87.53,31.94 v2(87.53,31.98) ; v2(106.51,172.52) 106.53,171.98 LCD1.16 ; ODD1.1 v2(172.91,140.55) ; DM1.71 102.97,38.05 103.19,37.83 103.19,35.7 102.66,35.17 v2(102.13,35.17) ; v2(136.95,35.18) 136.59,35.18 136.46,35.18 135.97,35.67 135.97,37.54 DM1.173 ; IOBD1.1 173.14,28.55 173.35,28.33 173.35,28.03 v2(173.31,27.99) 172.8,27.99 172.75,28.05 IOBD1.2 ; v2(126.4,32.91) 126.94,32.91 127.27,32.58 DM1.144 ; 84.97,37.32 84.97,37.31 84.97,36.97 v2(85.24,36.71) ; 84.97,37.32 84.37,37.92 DM1.9 ; 84.97,37.32 DM1.11 ; U6001.3 v2(162.08,41.28) ; DM1.3 82.57,36.49 83.77,35.29 v2(84.31,35.29) ; DM1.168 134.47,31.7 134.88,32.11 v2(135.14,32.11) ; v2(102.98,134.06) 102.98,134.95 103.19,135.16 PU5106.6 ; DM1.170 135.07,32.04 v2(135.14,32.11) ; v2(86.44,36.59) 86.22,36.59 85.59,37.22 85.59,38.7 DM1.13 ; v2(156.52,152.45) 155.32,151.25 WLAN1.7 ; v2(125.08,34.97) 124.27,34.97 123.76,35.49 123.76,37.54 123.97,37.76 DM1.133 ; v2(135.14,32.11) 135.41,32.11 135.67,31.85 DM1.172 ; ED1803.2 v2(125.34,129.52) ; v2(126.4,34.18) 126.08,34.18 125.47,33.57 DM1.138 ; v2(112.88,90.68) 112.88,90.09 CPU1.K54 ; v2(141.75,32.82) 141.52,32.82 141.07,32.38 DM1.190 ; v2(128.47,96.31) 128.66,96.59 CPU1.H17 ; DM1.128 122.47,31.44 122.01,31.9 122.01,31.96 122.01,33.42 122.01,33.51 122.68,34.18 122.78,34.18 v2(122.98,34.18) ; DM1.196 142.87,33.09 141.86,34.09 v2(141.75,34.09) ; DM1.60 99.67,32.23 100.17,32.73 v2(100.34,32.73) ; CPU1.H23 126.31,96.2 v2(126.43,96.24) ; DM1.195 142.57,37.58 142.86,37.29 142.86,36.89 143.06,36.68 143.61,36.68 v2(143.67,36.62) ; IOBD1.29 172.71,14.55 v2(173.21,14.05) IOBD1.30 ; v2(94.83,32.77) 95.06,32.76 95.47,32.35 DM1.46 ; WLAN1.63 155.05,165.25 155.3,165 v2(155.3,163.78) 155.28,163.75 WLAN1.57 ; v2(96.57,37.07) 96.37,37.27 DM1.49 ; DM1.37 92.77,37.43 92.74,37.4 92.74,36.84 93,36.58 v2(93.28,36.58) ; v2(98.69,34.44) 98.16,34.44 97.78,34.06 97.78,31.79 97.87,31.7 DM1.54 ; v2(135.4,35.26) 134.83,35.26 134.17,35.92 DM1.167 ; IOBD1.5 170.97,26.55 170.76,26.76 v2(170.76,26.89) ; v2(108.74,171.2) 108.27,171.6 LCD1.19 ; v2(133.54,92.03) 133.37,91.61 CPU1.AB12 ; v2(133.54,92.03) 133.14,92.24 CPU1.Y12 ; v2(133.54,92.03) CPU1.AB10 ; WLAN1.33 156.59,157.75 157.26,158.42 v2(157.26,159.08) ; v2(161.4,73.01) 160.83,73.59 C2432.2 ; DM1.189 140.77,36.94 141.33,36.38 v2(141.75,36.38) ; v2(127.19,40.16) 127.57,39.78 DM1.145 ; v2(102.7,34.41) 102.46,34.41 101.76,33.71 101.76,32.13 101.47,31.84 DM1.66 ; v2(155.56,160.38) 155.18,160.75 WLAN1.45 ; DM1.44 94.87,32.09 v2(94.83,32.13) ; v2(145.9,152.86) 145.62,153.14 145.62,153.79 145.83,154 WLAN1.18 ; v2(155.3,166.75) 155.3,166.75 WLAN1.69 ; v2(168.33,39.09) 168.55,38.88 R6016.2 ; v2(91.9,32.79) 91.65,32.79 91.27,32.41 DM1.32 ; DM1.61 99.97,37.37 v2(100.09,37.25) ; DM1.28 90.07,32 v2(90.04,32.03) ; CPU1.F21 126.84,96.89 v2(127.06,97.35) CPU1.E19 ; CPU1.A5 v2(133.17,102.6) ; DM1.2 82.27,32.73 83.84,34.3 v2(84.37,34.3) ; v2(96.43,32.07) 96.07,31.71 DM1.48 ; R1516.2 v2(108.67,101.33) ; v2(100.06,36.61) 100.27,36.61 100.71,37.05 100.71,37.4 100.57,37.54 DM1.63 ; DM1.150 v2(129.07,31.98) ; v2(167.98,41.12) 167.74,41.12 167.59,41.28 U6001.13 ; v2(122.92,35.31) 122.39,35.31 122.17,35.53 DM1.127 ; U6001.18 164.98,38.38 v2(164.83,38.23) ; CPU1.BA52 118.71,77.3 v2(118.72,77.31) CPU1.AW50 ; CPU1.BE63 113.86,72.63 113.54,71.95 v2(113.6,71.79) ; CPU1.AY54 117.67,76.58 v2(117.53,76.25) ; U2601.5 75.46,71.01 v2(74.99,70.54) ; DM1.153 129.97,37.56 v2(129.5,37.09) 129.37,37.22 DM1.151 ; LCD1.29 v2(112.48,174.6) ; v2(155.38,162.25) WLAN1.51 ; DM1.184 139.27,32 v2(139.54,32.26) ; v2(90.1,32.74) 89.95,32.74 89.47,32.26 DM1.26 ; v2(128.25,114.15) 128.39,114.29 U4002.5 ; DM1.179 137.77,36.89 138.05,36.61 v2(138.39,36.61) ; v2(128.53,93.36) CPU1.P19 ; LCD1.36 115.82,175.53 v2(115.52,175.72) ; LCD1.13 105.44,170.61 v2(105.86,170.21) ; CPU1.R23 v2(127.7,92.96) ; DM1.19 87.37,36.9 87.78,36.49 v2(87.97,36.49) ; v2(124.82,32.75) 124.87,32.7 DM1.136 ; IOBD1.8 170.97,25.05 v2(170.8,25.22) ; v2(138.24,32.74) 137.71,32.74 137.47,32.51 DM1.178 ; v2(125.13,37.19) 125.46,37.19 125.77,37.5 125.77,38.72 DM1.139 ; HDD1.9 v2(173.36,41.05) ; v2(133.13,36.55) 132.94,36.55 132.56,36.94 132.56,37.55 132.37,37.74 DM1.161 ; DM1.38 93.07,31.53 92.93,31.67 92.93,31.74 92.82,31.85 92.82,32.58 93.13,32.88 v2(93.39,32.88) ; v2(91.36,37.14) 90.97,37.54 DM1.31 ; DM1.55 98.17,36.79 98.46,36.5 v2(98.75,36.5) ; v2(155.33,159.11) 155.14,159.11 155,159.25 WLAN1.39 ; U6301.P4 52.54,60.13 v2(52,60.13) ; v2(122.19,77.89) 122.56,78.28 ; v2(102.15,36.46) 101.61,36.46 101.17,36.9 DM1.65 ; CPU1.BA62 114.41,74.79 CPU1.BB61 ; HDD1.12 v2(173.21,39.55) ; ODD1.7 v2(172.91,143.55) ; DM1.43 94.57,37.56 v2(94.87,37.26) ; v2(115.59,75.48) CPU1.AY58 ; HDD1.6 v2(173.21,42.55) ; v2(123.85,32.46) 124.27,32.04 DM1.134 ; TP1.5 142.58,10.6 v2(142.7,10.72) ; v2(172.83,142.14) 172.92,142.05 ODD1.4 ; v2(132.73,31.98) 132.67,31.92 DM1.162 ; CPU1.AB9 v2(135.12,91.63) ; DM1.72 103.27,32.79 102.93,33.14 v2(102.7,33.14) ; CPU1.BG41 v2(124.88,76.44)
  BOTTOM w0.356: U6301.J5 55.06,61.14 v2(55.11,61.18) 55.74,61.18 56.06,60.86 U6301.G5 ; U6301.E7 56.83,61.65 56.75,61.73 56.41,61.73 56.02,62.13 v2(55.98,62.13) ; CPU1.BH62 CPU1.BH63 ; U4004.3 24.83,59.22 25.13,58.93 v2(25.31,58.93) ; U4003.3 21.63,60.56 22.12,61.05 22.12,61.07 22.37,61.33 22.37,62.27 21.67,62.96 v2(19.24,62.96) ; v2(55.3,63.67) 55.3,63.64 55.56,63.38 U6301.H10 55.56,62.69 55.03,62.15 U6301.K8 ; ED1804.2 96.41,90.2 v2(96.41,90.95) 96.56,91.09 U1801.3 ; v2(50.88,61.42) 51.11,61.19 52.34,61.19 52.38,61.15 U6301.P6
  BOTTOM w0.406: v2(20.4,33) EU3501.3 EU3501.8 ; EU6001.8 173.34,41.02 v2(173.36,41.05) ; v2(167.93,72.77) 167.99,72.71 Q2403.1 ; v2(166,73.71) 166.05,73.76 Q2403.4 ; 142.92,110.62 v2(143.54,110.62) ; v2(138.84,113.82) 138.5,113.47 Q4002.4 ; Q4001.4 141.62,111.85 140.47,110.7 v2(140.42,110.7) 140.32,110.8 Q4002.1 ; U2404.2 151.99,65.41 v2(151.62,65.78) ; Q4003.1 128.02,119.53 v2(128.18,119.69) ; Q4003.4 125.66,121.41 v2(125.64,121.39)
  BOTTOM w0.457: CPU1.BH63 v2(114.29,70.94)
  BOTTOM w0.508: SPK1.5 v2(157,8.3) ; BATT1.10 150.01,185.8 ; BATT1.10 149.12,183.92 ; BATT1.10 148.24,185.8 ; 132.21,74.11 v2(131.92,74.67) ; v2(133.15,135.31) 133.6,135.75 PR5018.1 PC5021.2 PR5014.1 PC5015.2 ; R1504.2 99.92,109.21 100.18,108.94 R1502.2 100.55,109.21 v2(100.95,109.6) ; v2(161.35,11.36) 160.9,11.8 EC2704.2 ; v2(63,46.26) 63,46.26 63.35,46.26 63.86,46.76 SPI251.4 ; v2(160,28.5) 160.13,28.37 160.15,28.37 160.54,27.99 C2718.2 ; PR5036.2 PR5024.2 v2(141.18,137.05) ; HDMI1.21 10.2,59.74 ; HDMI1.21 11.64,58.75 ; HDMI1.21 10.2,57.76 ; 10.52,39.25 USB1.10 ; USB1.10 14.08,39.25 ; USB1.10 12.3,40.14 ; SPI252.4 v2(165.7,32.59) ; BATT2.7 155.06,181.8 ; BATT2.7 154.25,182.61 ; BATT2.7 153.44,181.8 ; BATT2.7 154.25,180.99 ; C1220.2 152.79,31.45 v2(152.76,31.47) ; 14.99,28.05 USB1.4 14.28,27.34 ; PC5019.2 129.29,137.34 v2(129.27,137.31) ; PC4435.2 171.38,160.99 v2(171.99,160.38) ; R6021.1 164.89,38.17 v2(164.83,38.23) ; BATT1.8 152.25,186.69 ; BATT1.8 151.36,185.8 ; BATT1.8 153.14,185.8 ; BATT1.8 152.25,184.91 ; Q6505.S 135.76,25.87 v2(135.9,25.73) ; v2(150.45,107.72) 150.6,107.57 150.6,106.17 150.07,105.64 PC1008.2 ; v2(137.85,15.98) 138.08,15.75 TP1.10 ; v2(20.99,53.57) 18.28,56.28 Q5702.S ; R2438.2 C2417.2 v2(156.85,54.89) ; USB2.11 14.08,5.35 ; USB2.11 10.52,5.35 ; USB2.11 12.3,4.46 ; R6008.1 R6024.1 165.11,47.02 v2(166,47.91) 166.16,48.07 Q2401.C ; v2(95.92,109.86) 96.37,109.4 R1508.2 ; v2(53.93,30.43) 53.54,30.04 EC8919.2 ; EC6402.2 170.5,6.1 EC6404.2 170.5,7.61 v2(170.57,7.67) ; v2(80.02,49.3) 80.02,47.42 DM1.205 ; C2433.2 v2(161.4,73.01) ; 10.2,43.26 HDMI1.20 ; HDMI1.20 11.64,44.25 ; HDMI1.20 10.2,45.24 ; R2442.2 171.85,71.46 171.48,71.1 v2(171.48,71.05) ; R6020.2 162.36,46.84 v2(162.29,46.92) ; 151.44,181.8 BATT2.8 ; BATT2.8 152.25,180.99 ; BATT2.8 153.06,181.8 ; BATT2.8 152.25,182.61 ; USB2.10 14.08,20.75 ; USB2.10 12.3,21.64 ; USB2.10 10.52,20.75 ; R2717.2 166.57,26.22 167.19,26.85 v2(167.19,26.88) ; v2(163.81,6.58) 164.15,6.24 EC4001.2 ; EC1801.2 106.67,73.45 106.41,73.71 v2(106.05,73.71) ; v2(142.32,16.99) 142.32,17.39 142.37,17.44 EC6504.2 ; v2(68.74,43.41) 69.35,44.02 PC5112.2 ; v2(148.29,129.42) 148.58,129.12 EC8927.2 ; v2(98.66,109.86) 98.56,109.86 98.18,109.48 R1505.2 98.13,109.13 R1507.2 ; LCD1.42 v2(119.49,176.84) ; v2(163.72,151.76) 163.51,151.97 PG4411.2 ; v2(136.02,116.05) 136.02,115.65 135.77,115.39 C4031.2 ; C4033.2 127.88,113.78 v2(128.25,114.15) ; D4304.1 v2(157.09,178.11) ; v2(158.81,93.65) 159.49,93.65 159.87,93.28 DB1.12 ; v2(155.38,27.33) 155.96,26.75 C2716.2 ; PC5031.2 135.85,118.87 136.33,119.36 v2(136.33,119.66) ; v2(177.88,62.59) 177.52,62.22 C2443.2 ; R2020.2 v2(102.52,86.31) ; PC5003.2 141.18,125.02 v2(141.18,124.03) PR5012.1 ; v2(130.97,174.47) 130.69,174.2 PD4301.A ; 10.52,23.85 USB1.11 ; USB1.11 12.3,22.96 ; USB1.11 14.08,23.85 ; v2(151.9,25.61) 152.39,25.11 C2708.2 C2706.2 ; v2(138.79,121.59) 138.79,121.89 138.48,122.21 PC5029.2 ; USB1.7 13.49,31.55 ; USB1.7 12.78,30.84 ; USB1.7 12.78,32.26 ; C1201.2 122.38,28.28 122.84,28.73 v2(122.84,29.03) ; PC5006.2 PC5005.2 130.84,121.4 v2(130.89,121.45) ; v2(159.34,53.14) 158.01,51.81 158.06,51.75 C2428.1 ; 4.87,22.96 USB1.13 6.46,23.85 ; EC6503.2 EC6501.2 v2(140.47,23.42) ; R2028.2 99.12,87 v2(99.27,87.15) 99.32,87.15 99.36,87.19 R2025.2 ; v2(59.9,62.54) 59.9,61.85 59.65,61.6 ; PC5013.2 v2(141.21,123.17) ; v2(108.67,101.33) Q1801.S R1814.2 ; 169.37,183.92 BATT1.9 ; BATT1.9 168.49,185.8 ; BATT1.9 170.26,185.8 ; EC6502.2 146.57,17.72 147.65,18.8 148.44,18.8 v2(148.7,19.05) ; v2(167.63,8.43) 167.6,8.43 167.47,8.56 C3515.2 165.62,8.56 164.65,9.53 U3602.2 ; C1902.2 v2(129.67,105.06) ; ED1805.2 R1826.2 94.13,89.24 v2(93.98,89.39) 93.83,89.54 ED1808.2 ; C4030.2 v2(128.94,116.87) ; 5.14,60.65 HDMI1.23 3.7,61.64 ; v2(160.84,24.69) 160.81,24.72 160.5,24.72 160.48,24.73 160.46,24.73 159.99,25.21 EC2708.2 ; v2(128.79,123.52) 128.96,123.34 PC5007.2 PC5008.2 ; C2701.2 157.28,16.05 157.82,16.59 v2(157.82,16.69) ; v2(166.1,35.82) 166.53,35.82 166.92,36.21 R6017.1 ; 4.87,21.64 USB2.12 6.46,20.75 ; v2(142.78,106.99) 143.01,106.99 143.29,107.27 EC8929.2 ; PC5127.2 PC5129.2 PC5130.2 v2(73.46,47.42) ; C2418.2 R2443.2 157.49,45.6 v2(157.74,45.34) ; PC1040.2 141,107.47 v2(141.27,107.2) ; 12.78,12.34 USB2.7 12.78,13.76 ; PR5021.2 v2(138.79,137.75) ; BATT1.7 154.25,186.69 ; BATT1.7 154.25,184.91 ; BATT1.7 153.36,185.8 ; v2(161.73,32.41) 161.73,32.34 162.25,31.82 EC2506.2 ; v2(36.32,39.52) PC4518.2 ; C4011.2 128.49,120 v2(128.18,119.69) ; C2602.2 75.01,70.51 v2(74.99,70.54) ; ED6601.2 170.37,35.51 v2(170.42,35.56) ; PR4530.2 46.44,48.92 v2(45.04,47.53) ; 3.7,41.36 HDMI1.22 5.14,42.35 ; v2(75.01,28.63) 75.01,28.17 75.38,27.8 EC8920.2 ; Q2906.E 142.92,27.22 142.09,28.04 v2(140.24,28.04) ; 6.46,5.35 USB2.13 4.87,4.46 ; HDMI1.11 10.16,52 ; v2(32.06,53.14) 31.7,52.78 C4006.2 31.6,51.36 EC4003.2 ; v2(156.22,29.62) 156.2,29.61 C2722.1 ; v2(23.43,34.65) 23.48,34.65 24.34,35.51 FC3503.2 ; USB2.4 14.28,10.26 ; USB2.4 13.57,9.55 ; USB2.4 14.99,9.55 ; USB2.4 14.28,8.84 ; v3(44.69,44.27) 43.85,43.44 PC4536.2 ; DM1.206 v2(149.09,46.62) ; HDMI1.8 11.94,50.5 ; PC5032.2 135.44,121.34 v2(135.26,121.52) ; v2(154.67,7.88) 153.75,7.88 153.33,8.3 SPK1.6 ; C1205.2 v2(102.95,28.69) ; v2(52.69,46) 52.7,46 52.76,45.94 PR4531.2 ; X1901.2 v2(128.84,106.38) ; v2(146.52,26.14) Q2908.E ; PC4520.2 43.95,50.09 v3(44.94,51.08) ; 4.87,40.14 USB1.12 6.46,39.25 ; X1901.4 131.2,109.93 v2(131.2,109.93) ; C6601.2 v2(173.36,37.14) ; LCD1.44 v2(121.01,179.78) ; LCD1.41 v2(99.02,167.82) ; R2468.2 169.92,46.93 v2(169.9,46.91) ; Q5703.S v2(19.08,61.66) ; C1901.2 v2(133.59,106.56)
  vias: v1(124.8,110.24) v1(132.77,118.37) v2(1.33,60.48) v2(1.29,42.52) v2(3.51,40.62) v2(3.54,22.33) v2(3.54,3.35) v2(5.27,61.77) v2(5.39,42.62) v2(5.44,22.3) v2(5.75,60.28) v2(7.45,39.47) v2(7.6,3.13) v2(7.73,60.76) v2(8.06,23.62) v2(8.54,21.03) v2(9.05,42.47) v2(9.02,5.13) v2(9.58,62.05) v2(9.61,57.05) v2(9.63,45.77) v2(9.91,39.47) v2(11.49,61.85) v2(12.35,41.56) v2(12.73,59.31) v2(12.73,50.37) v2(12.66,3.15) v2(12.76,46.43) v2(13.42,37.39) v2(13.42,7.16) v2(13.47,25.68) v2(13.52,19.41) v2(14.03,48.44) v2(14.18,44.4) v2(14.43,54.79) v2(14.38,52.28) v2(14.49,26.62) v2(14.56,22.53) v2(16.39,8.79) v2(16.87,30.48) v2(17.19,34.86) v2(17.51,62.66) v2(17.59,11.73) v2(17.76,3.13) v2(17.99,70.28) v2(19.01,68.73) v2(19.55,44.86) v2(19.97,34.24) v2(20.02,31.4) v2(20.73,70.33) v2(20.84,44.68) v2(21.04,3.63) v2(21.09,52.66) v2(21.09,49.33) v2(21.44,19.1) v2(21.83,53.7) v2(21.9,51.49) v2(22.11,68.38) v2(22.52,41.04) v2(22.59,48.01) v2(22.56,47.25) v2(22.66,42.9) v2(23.45,12.88) v2(23.73,28.5) v2(24.65,70.41) v2(24.72,13.54) v2(25.66,12.83) v2(26.4,67.19) v2(27.69,52.2) v2(27.74,51.23) v2(27.72,50.29) v2(27.85,53.09) v2(27.87,49.53) v2(30.11,13.34) v2(30.99,70.28) v2(32.9,21.59) v2(33.69,25.35) v2(35.03,26.82) v2(35.06,13.34) v2(35.21,34.72) v2(36.94,72.77) v2(41.13,76.84) v2(42.91,13.34) v2(43.34,19.1) v2(45.85,76.86) v2(49.79,18.77) v2(50.32,48.57) v2(50.93,49.2) v2(50.93,48.59) v2(50.91,47.98) v2(51.06,13.34) v2(51.32,16.72) v2(51.54,48.54) v2(52.38,76.86) v2(57.11,32.44) v2(57.94,76.91) v2(62.03,76.86) v2(63.51,74.86) v2(64.32,76.86) v2(67.5,77.09) v2(72.32,78.03) v2(76.49,79.71) v2(80.88,82.37) v2(84.32,36.56) v2(85.24,36.07) v2(85.72,34.23) v2(86.41,35.26) v2(86.82,55.62) v2(87.54,55.63) v2(87.54,33.25) v2(87.95,35.16) v2(88.87,34.14) v2(88.9,32.79) v2(89.06,41.4) v2(89.12,35.26) v2(89.26,75.44) v2(90.09,34.16) v2(90.31,35.03) v2(91.36,35.87) v2(91.9,34.06) v2(92.13,151.39) v2(92.13,144.96) v2(92.13,139.73) v2(92.13,130.28) v2(92.13,109.98) v2(92.13,103.48) v2(92.23,162.31) v2(92.18,157.76) v2(92.16,119) v2(92.44,164.62) v2(93.3,35.28) v2(93.39,34.15) v2(93.78,155.15) v2(94.27,170.94) v2(94.6,163.37) v2(94.57,160.07) v2(94.77,165.91) v2(94.75,35.18) v2(94.9,167.41) v2(95.84,153.24) v2(95.82,82.37) v2(95.92,173.89) v2(96.43,33.39) v2(96.57,35.8) v2(98.56,177.07) v2(98.69,33.17) v2(98.75,35.23) v2(99.56,33.18) v2(100.36,34.94) v2(100.92,137.26) v2(100.99,175.52) v2(101.59,34.5) v2(102.14,180.22) v2(103.99,169.67) v2(104.68,135.41) v2(105.67,168.4) v2(105.77,165.81) v2(105.87,182.5) v2(106.04,167.32) v2(106.23,94.11) v2(106.99,163.48) v2(107.68,170.44) v2(107.7,88.61) v2(107.78,163.45) v2(108.82,178.31) v2(109.07,85.11) v2(109.23,40.62) v2(109.25,39.93) v2(109.41,164.37) v2(109.63,181.28) v2(110.38,89.68) v2(110.45,172.05) v2(110.68,164.43) v2(110.73,91.34) v2(111.01,184.33) v2(111.08,172.32) v2(111.08,40.67) v2(111.21,165.03) v2(111.49,40.11) v2(112.07,165.03) v2(112.31,179.64) v2(113.04,84.61) v2(113.11,80.61) v2(113.49,172.57) v2(113.7,78.75) v2(114.31,161.75) v2(114.48,92.01) v2(114.75,173.12) v2(115.09,81.33) v2(115.41,88.44) v2(115.49,165.52) v2(115.55,184.94) v2(115.95,78.66) v2(116.28,77.76) v2(116.77,162.31) v2(116.94,81.97) v2(117.04,86.05) v2(117.43,162.31) v2(117.54,90.83) v2(117.55,78.3) v2(117.69,90.2) v2(118.61,90.51) v2(119.18,162.36) v2(120.2,183.47) v2(120.56,90.4) v2(120.81,92.78) v2(121.06,98.21) v2(121.54,90.82) v2(121.49,79.77) v2(121.73,182.3) v2(122.44,80.14) v2(122.89,134.52) v2(122.9,36.62) v2(122.98,32.91) v2(123.22,109.73) v2(123.17,85.85) v2(123.35,177.34) v2(123.42,89.8) v2(123.63,92.97) v2(123.82,161.96) v2(123.9,88.45) v2(124.39,87.08) v2(124.51,93.42) v2(124.8,33.74) v2(124.9,184.58) v2(124.92,85.73) v2(124.9,83.4) v2(125.24,91.41) v2(125.78,79.1) v2(125.89,89.93) v2(126.3,109.15) v2(126.33,82.99) v2(126.44,80.09) v2(126.97,36.44) v2(126.97,35.17) v2(127.12,88.83) v2(127.21,83.29) v2(127.37,88.16) v2(127.6,85.16) v2(128.15,80.63) v2(128.22,36.56) v2(128.21,35.36) v2(128.36,100.46) v2(128.84,91.03) v2(128.8,81.68) v2(128.85,84.09) v2(128.96,75.67) v2(129.15,33.48) v2(129.29,80.29) v2(129.39,99.04) v2(129.89,81.26) v2(129.98,183.47) v2(130.02,78.28) v2(130.07,85.3) v2(130.38,79.97) v2(130.47,93.45) v2(130.49,82.3) v2(130.59,115.04) v2(130.85,33.95) v2(131.12,98.8) v2(131.2,76.68) v2(131.4,130.25) v2(131.43,95.3) v2(131.46,82.69) v2(131.63,97.5) v2(131.68,88.06) v2(131.71,78.95) v2(131.66,35.31) v2(132.46,86.68) v2(132.54,82.3) v2(132.62,130.3) v2(132.76,81.55) v2(132.78,33.28) v2(133.14,35.28) v2(133.23,128.27) v2(133.41,131.07) v2(133.43,82.58) v2(133.46,130.3) v2(133.46,129.52) v2(133.45,100.49) v2(133.46,96.01) v2(133.54,79.57) v2(133.54,13.34) v2(133.66,77.57) v2(134.13,88.23) v2(134.37,130.3) v2(134.62,99.25) v2(134.95,107.16) v2(135.04,102.51) v2(135.12,77.73) v2(135.4,37.16) v2(135.8,80.55) v2(136.03,88.88) v2(135.97,82.8) v2(136.64,34.01) v2(136.7,32.75) v2(136.85,83.19) v2(136.91,183.57) v2(136.86,78.03) v2(136.95,36.45) v2(137.54,81.21) v2(137.71,84.44) v2(138.11,96.64) v2(138.05,85.77) v2(138.19,89.74) v2(138.18,34.01) v2(138.39,100.59) v2(138.47,35.34) v2(138.66,87.91) v2(138.92,79.58) v2(138.97,176.05) v2(139.06,93.52) v2(139.05,82.39) v2(139.27,97.04) v2(139.39,86.25) v2(139.35,84.13) v2(139.54,34.3) v2(139.89,79.57) v2(140.19,183.85) v2(140.22,173.76) v2(140.55,182.3) v2(140.95,173) v2(140.95,94.36) v2(140.99,88.22) v2(141.03,81.89) v2(141.08,97.59) v2(141.51,80.32) v2(141.74,68.43) v2(141.71,66.47) v2(141.75,35.11) v2(142.76,83.52) v2(142.88,186.41) v2(143.01,155.78) v2(142.98,136.13) v2(143.13,100.03) v2(143.19,82.07) v2(143.27,98.66) v2(143.7,136.13) v2(143.67,65.64) v2(143.77,67.82) v2(144.41,1.7) v2(144.63,136.15) v2(145.35,136.15) v2(145.47,173.55) v2(146.36,130.13) v2(147.05,186.44) v2(147.1,125.38) v2(147.12,124.69) v2(147.17,151.64) v2(148.67,176.3) v2(148.94,36.95) v2(149.37,142.49) v2(149.47,179.97) v2(149.69,171.96) v2(149.79,62.97) v2(150.2,43.36) v2(150.17,40.85) v2(150.35,42.32) v2(150.5,186.95) v2(150.68,148.44) v2(150.74,59.17) v2(150.91,141.61) v2(151.04,182.76) v2(151.53,171.93) v2(151.52,1.04) v2(152.66,37.59) v2(153.22,56.82) v2(153.32,184.28) v2(153.4,186.97) v2(153.5,40.72) v2(153.63,179.35) v2(153.8,146.18) v2(154.34,172.7) v2(154.41,171.58) v2(154.38,37.32) v2(155.02,20.17) v2(155.18,105.59) v2(155.3,168.05) v2(155.48,1.02) v2(157,22.79) v2(157.44,162.26) v2(157.69,160.43) v2(158.4,186.97) v2(159.6,20.53) v2(160.48,20.47) v2(160.61,1.02) v2(161.45,22.43) v2(161.5,21.47) v2(161.5,20.53) v2(161.46,19.56) v2(161.46,18.67) v2(162.29,35.99) v2(162.69,64.92) v2(162.76,11.1) v2(162.9,158.42) v2(163,27.31) v2(163.25,186.97) v2(163.41,20.65) v2(163.66,158.45) v2(164.12,41.2) v2(164.47,72.11) v2(164.78,41.96) v2(164.83,41.2) v2(164.83,40.41) v2(165.54,41.2) v2(165.95,1.02) v2(167.9,3.03) v2(168.05,186.95) v2(168.1,142.04) v2(168.21,43.18) v2(168.38,181.18) v2(168.51,140.03) v2(168.56,172.47) v2(168.56,138.08) v2(168.74,178.64) v2(168.74,82.55) v2(168.82,174.53) v2(168.87,178.01) v2(168.87,177.07) v2(169.25,172.47) v2(169.5,1.04) v2(170.25,182.04) v2(170.49,186.46) v2(170.72,175.74) v2(171.03,149.68) v2(172.04,172.51) v2(172.09,138.13) v2(172.24,79.61) v2(172.24,1.04) v2(172.45,119.09) v2(172.78,79.1) v2(173.29,21.39) v2(173.36,47.07) v2(173.39,46.23) v2(174.71,167.26) v2(175.11,27.37) v2(175.34,124.06) v2(175.37,37.18) v2(175.5,184.74) v2(175.69,181.45) v2(175.98,120.56) v2(176.14,24.81) v2(176.18,132.79) v2(176.59,154.21) v2(177.15,45.14) v2(177.4,94.34) v2(177.53,92.2) v2(178.54,59.41) v2(179.21,181.23) v2(179.64,173.2) v2(179.64,171.2) v2(179.64,165.81) v2(179.64,157.89) v2(179.66,179.35) v2(179.66,161.57) v2(179.66,155.65) v2(179.69,122.3) v2(179.66,97.03) v2(179.66,47.42) v2(179.66,42.06) v2(179.66,35.87) v2(179.66,29.09) v2(179.66,25.12) v2(179.66,19.03) v2(179.66,14.76) v2(179.66,10.49) v2(179.81,150.78) v2(179.79,134.34) v2(179.84,127.92) v2(179.81,91.44) v2(179.86,144.53) v2(179.86,140.29) v3(28.53,62.21) v3(28.58,61.24) v3(29.37,62.23) v3(29.42,61.29) v3(30.28,62.21) v3(30.33,61.27) v3(31.25,62.23) v3(31.3,61.29) v3(44.61,45.21) v3(44.71,52.81) v3(44.74,51.92) v3(45.45,45.11) v3(45.6,52.85) v3(45.57,52) v3(45.57,44.25) v3(45.88,51.13) v3(46.36,45.19) v3(46.44,44.33) v3(46.54,52.64) v3(46.57,51.77) v3(47.18,51.13) v3(47.23,45.23) v3(47.33,44.4) v3(48.94,51.63) v3(48.95,52.53) v3(60.69,37.98) v3(61.34,38.8) v3(61.58,37.98) v3(62.24,38.79) v3(62.49,37.92) v3(63.07,38.74) v3(63.46,37.75) v3(64.05,38.44) v3(64.45,39.37) v3(99.7,114.06) v3(99.75,117.81) v3(101.94,116.54) v3(101.96,117.53) v3(102.29,132.72) v3(102.37,131.19) v3(103.28,132.72) v3(103.36,131.19) v3(104.88,132.64) v3(104.91,131.62) v3(108.01,119.61) v3(108.08,117.83) v3(109.13,120.07) v3(109.1,118.65) v3(109.13,117.45) v3(109.1,116.41) v3(109.1,115.34) v3(109.13,114.23) v3(109.89,119.38) v3(110.6,118.65) v3(110.6,117.58) v3(110.57,116.54) v3(110.88,119.99) v3(111.92,118.7) v3(111.92,117.73) v3(111.89,116.49) v3(112.17,119.89) v3(113.19,119.89) v3(113.65,107.01) v3(114.49,107.32) v3(116.34,138.2) v3(116.36,136.83) v3(116.42,135.51) v3(116.62,108.13) v3(117.63,136.07) v3(117.61,134.77) v3(117.61,133.81) v3(117.63,132.01) v3(117.66,132.87) v3(117.89,139.65) v3(117.89,138.69) v3(118.04,137.33) v3(118.37,108.82) v3(118.63,131.85) v3(118.65,132.77) v3(119.26,109.12) v3(119.46,141.23) v3(119.57,132.79) v3(120.48,141.25) v3(120.68,129.44) v3(120.71,128.53) v3(121.65,137.33) v3(121.67,130.35) v3(121.67,129.44) v3(121.67,128.55) v3(121.95,131.42) v3(122.31,132.41) v3(122.99,112.65) v3(123.1,118.98) v3(123.07,118.04) v3(123.07,117.12) v3(123.07,116.18) v3(167.6,159.08) v3(168.56,159.06) v3(169.48,159.06) v3(172.78,150.34) v3(172.75,149.48)
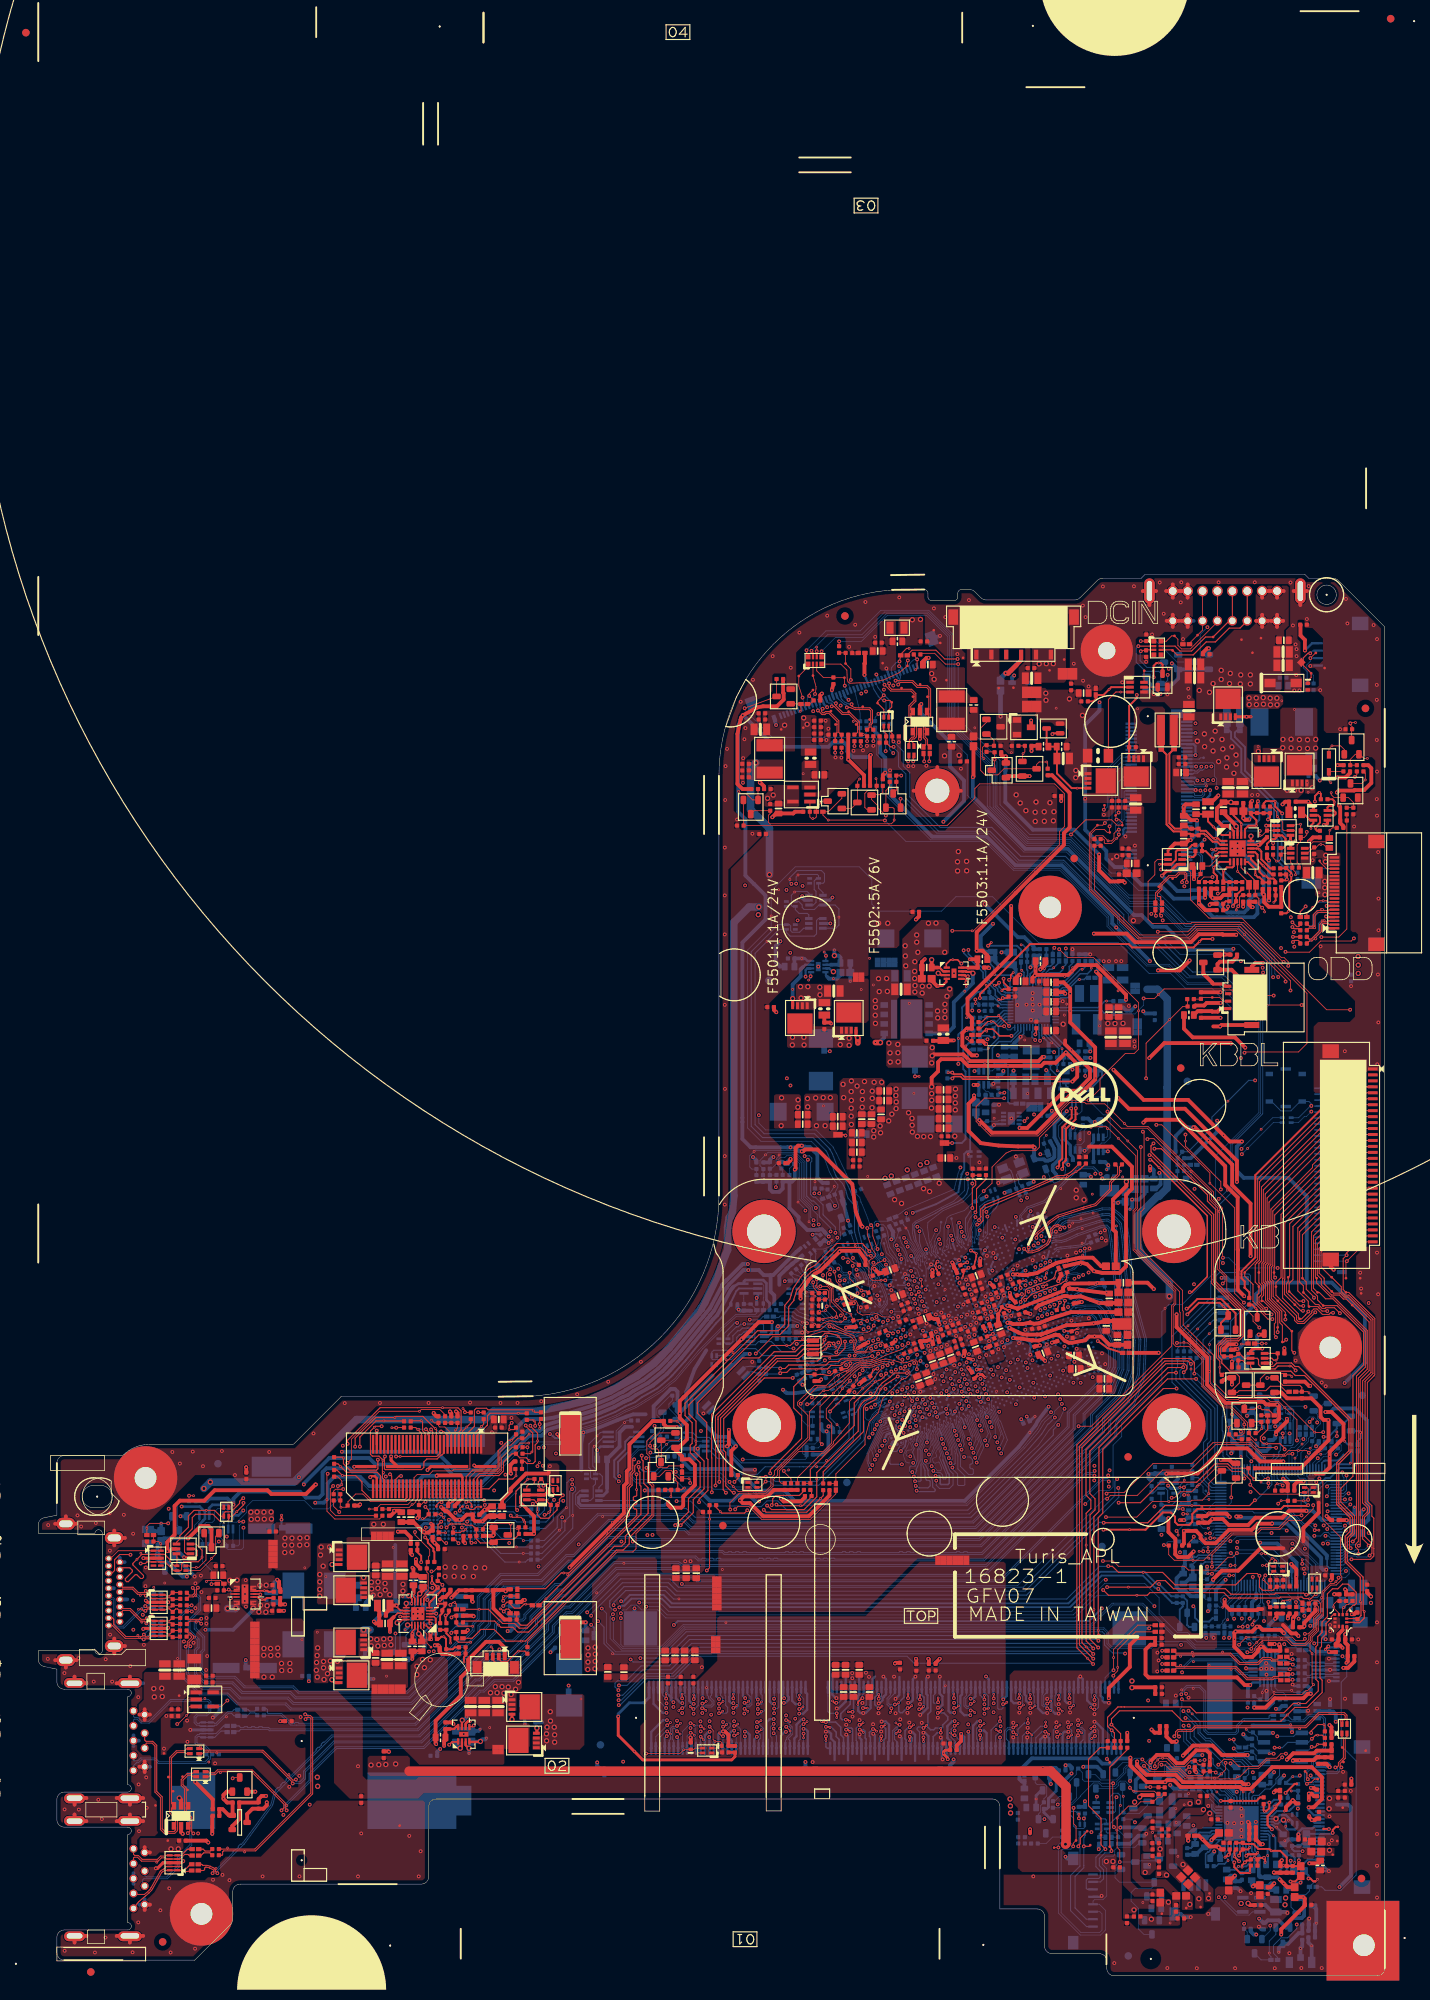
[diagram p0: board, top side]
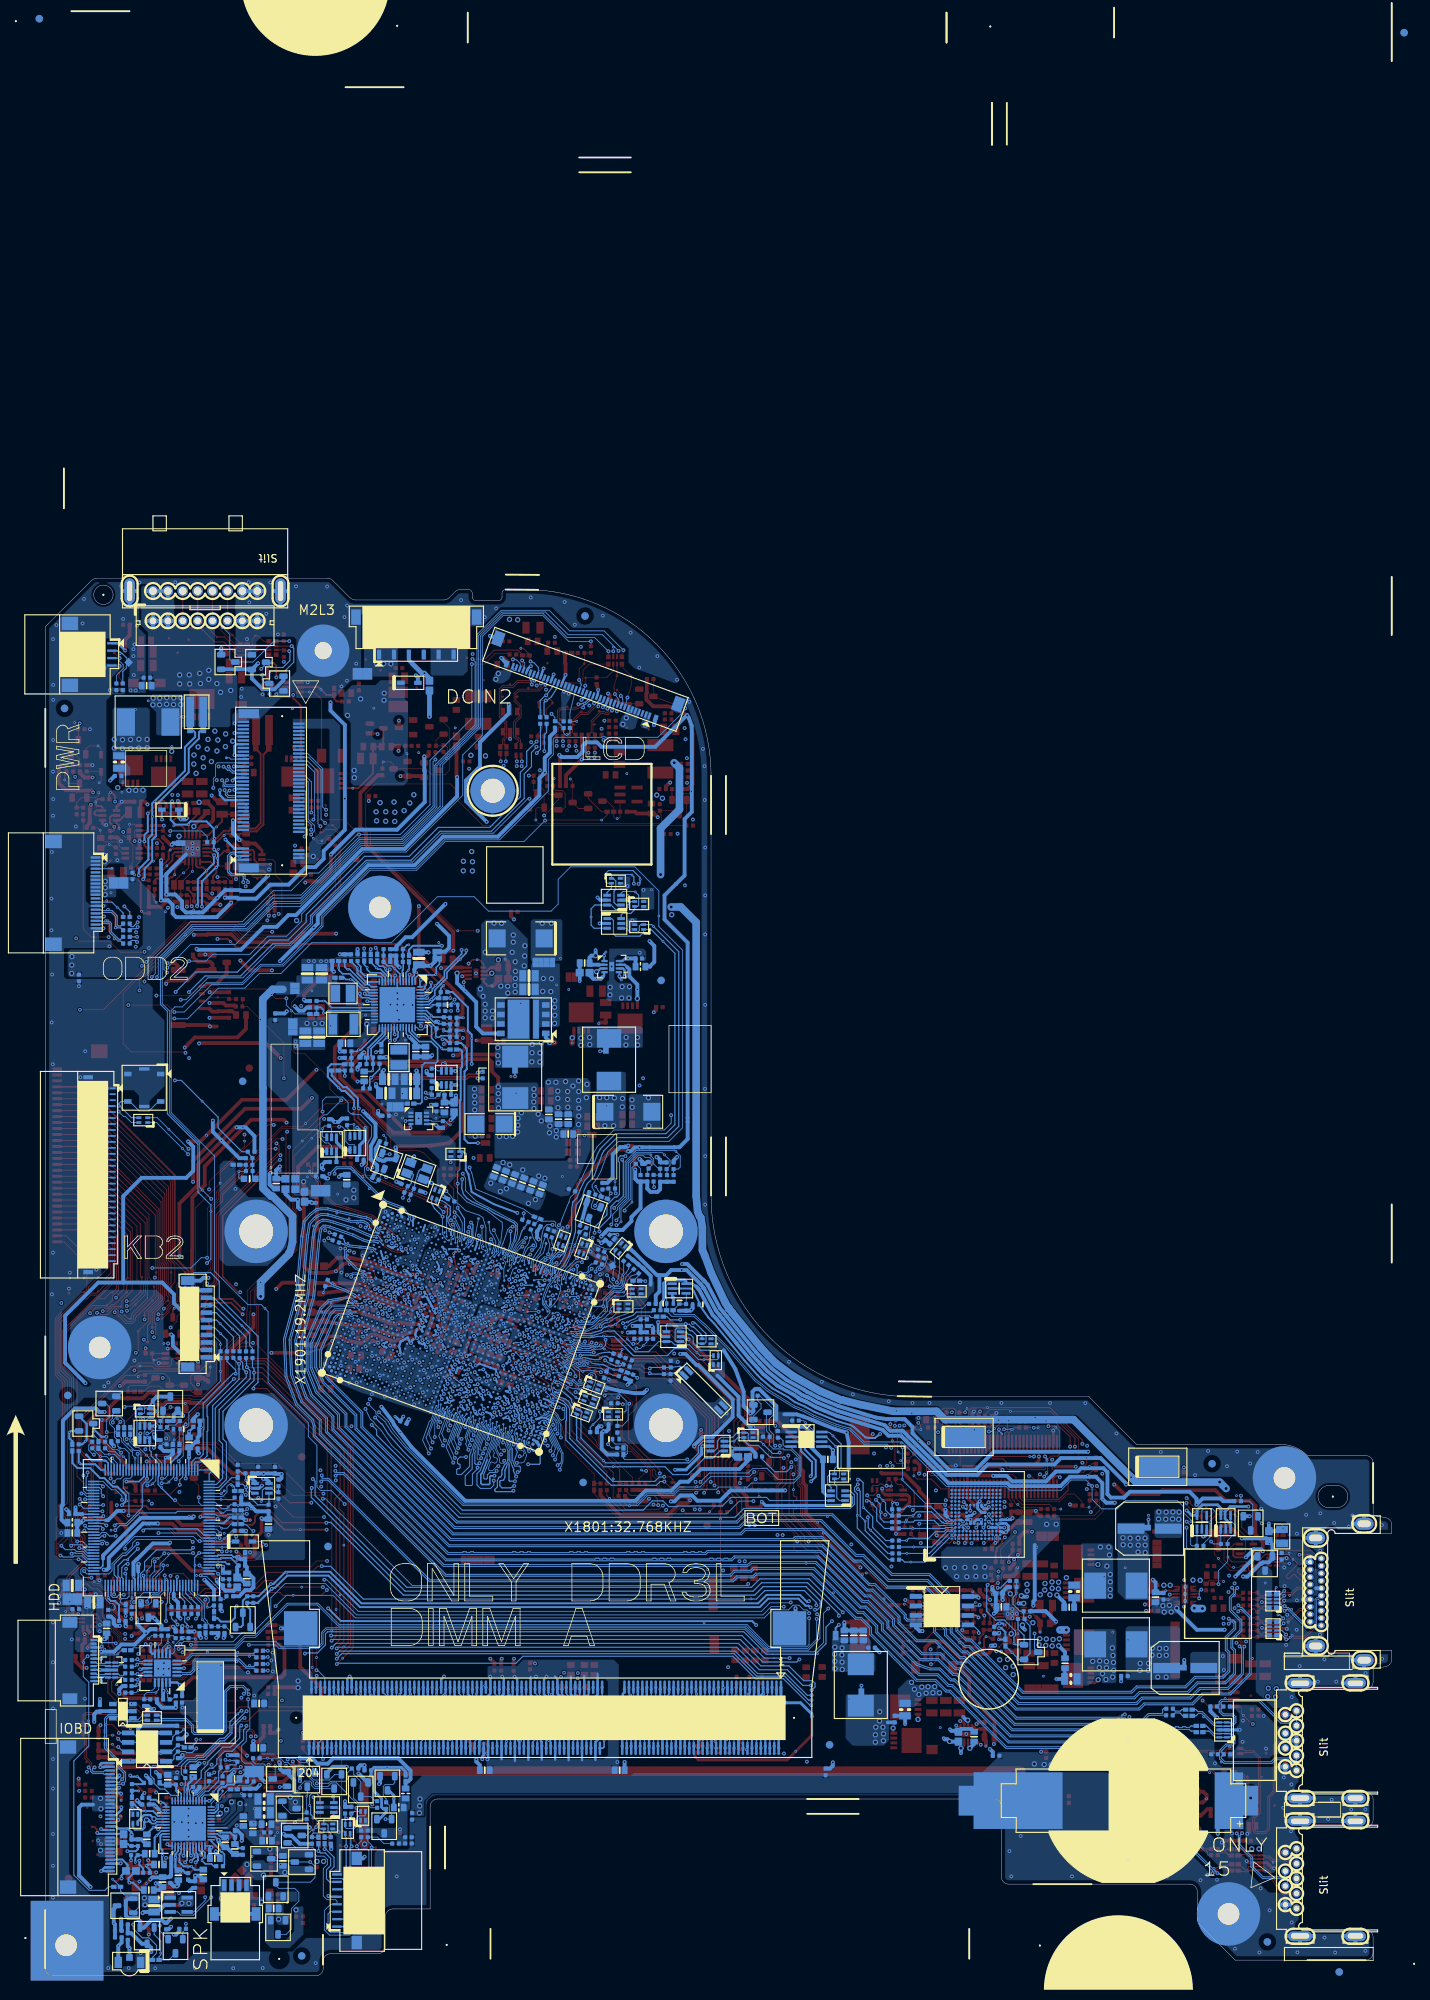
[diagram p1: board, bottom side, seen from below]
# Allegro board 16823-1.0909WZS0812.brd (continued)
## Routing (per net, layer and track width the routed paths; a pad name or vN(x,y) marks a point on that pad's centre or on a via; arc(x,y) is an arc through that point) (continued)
GND_R1: length 3.6
  TOP w0.508: R6601.2 171.22,24.09 170.87,24.44 v2(170.52,24.44) v1(170.52,23.57)
  BOTTOM w0.305: v2(170.52,24.44) 170.63,24.55 IOBD1.9
GND_R2: length 2.9
  TOP w0.508: R6602.2 171.52,21.1 171.33,20.91 v2(170.92,20.91) 170.57,21.26 v1(170.57,21.44)
  BOTTOM w0.305: IOBD1.17 171.28,20.55 v2(170.92,20.91)
V3D3_STB: length 6.4
  TOP w0.305: v2(165.56,19.66) 164.98,20.24 164.98,21.41 166.11,22.55 v1(166.11,22.78) 166.66,23.32 R2710.1
  BOTTOM w0.203: v2(165.56,19.66) 165.55,19.66 165.36,19.85 HDA27.20
VSS_VCCGI: length 51.9
  TOP w0.254: v2(139.25,116.41) 139.2,116.36 139.2,114.9 137.93,113.63 137.93,109.45 137.52,109.04 137.52,108.36 v2(137.42,108.26)
  L4 w0.203: v2(118.02,89.51) 117.69,89.18 117.69,88.63 117.97,88.35 118.37,88.35 119.54,88.41
  L4 w0.254: v2(137.42,108.26) 137.37,108.21 137.37,107.05 135.29,104.97 135.29,103.97 134.45,102.72 134.38,102.61 134.11,102.15 134.1,102.14 133.97,101.96 133.84,101.83 132.77,100.75 132.67,100.68 130.74,99.18 130.48,98.91 130.28,98.49 130.28,98.49 129.95,98.17 129.95,97.2 129.71,96.1 129.38,95.78 129.24,95.64 128.9,95.29 128.28,95.29 127.74,95.11 127.52,94.83 127.46,94.6 127.46,93.76 126.29,91.24 126.29,91.24 126.29,90.91 125.92,90.54 125.41,90.35 125.31,90.35 125.24,90.33 124.51,89.6 123.41,89.2 122.18,89.2 121.87,89.09 121.74,88.96 121.62,88.69 121.47,88.55 120.6,88.23 119.93,88.23 119.54,88.41
  BOTTOM w0.254: v2(118.02,89.51) 118.16,89.51 CPU1.R43 ; v2(139.25,116.41) 139.25,117.51 140.46,118.72 140.9,118.72 v1(141.33,119.15) 142.78,120.6 142.78,121.85 142.33,122.3 PR5013.1
0D675V_S0_DISCHG: length 1.4
  BOTTOM w0.406: 141.62,110.62 141.62,109.2 R4003.2
0D675V_VREF_S0: length 172.9
  TOP w0.508: v2(160.87,106.53) 160.87,109.36 153.89,116.33 146.36,116.33 v2(144.91,117.78) ; v3(146.77,38.66) 146.82,38.71 C1210.1 C1209.1 ; v2(149.41,33.03) 149.41,33.02 149.82,32.62 C1207.1 C1208.1
  L3 w0.508: v2(128.12,141.15) 129.34,141.15 133.38,137.11 139.58,137.11 140.15,137.68 146.38,137.68 149.75,134.31 149.75,122.62 v2(144.91,117.78) 143.98,117.78 140.59,114.39 140.59,113.74 139.55,112.71 139.55,109.55 140.24,108.87 143.49,108.87 v2(143.59,108.76) ; v3(146.77,39.55) 150.91,39.55 152.13,40.77 152.13,59.74 151.04,60.84 151.04,62.8 149.89,63.94 149.89,67.73 150.98,68.81 152.99,68.81 156.67,72.49 156.67,89.66 160.87,93.86 v2(160.87,106.53)
  BOTTOM w0.508: v1(143.39,108.18) 143.59,108.38 v2(143.59,108.76) 143.16,109.2 R4003.1 ; v2(128.12,141.15) 126.5,139.52 126.5,137.95 127.03,137.42 PG5014.1
1D05V_FHV0: length 19.5
  L4 w0.305: 137.31,99.25 137.19,99.19 136.68,98.69 136.47,98.54 136.1,97.82 135.92,97.63 135.43,97.41 134.48,97.41 134.13,97.06 133.14,97.06 132.49,96.41 v2(132.49,94.62)
  L4 w0.508: v2(144.91,103.71) 140.95,100.89 137.31,99.25
  BOTTOM w0.305: CPU1.T13 131.78,94.16 132.16,94.54 132.18,94.54 132.27,94.62 v2(132.49,94.62)
  BOTTOM w0.508: R609.1 145.89,103.85 145.05,103.85 v2(144.91,103.71) v1(144.36,103.71)
1D05V_FHV1: length 14
  TOP w0.508: R608.1 142.65,95.2 141.51,96.35 139.74,96.35 139.18,96.22 138.19,96 138.14,95.99 138.12,95.99 136.63,95.66 136.58,95.61 136.16,95.4 136.11,95.36 134.75,94.69 134.02,94.29 133.18,94.14 132.69,94.03 132.53,94.01 132.14,94.01 v1(131.4,94.11) v2(130.79,94.11)
  BOTTOM w0.305: 130.98,93.63 130.98,93.92 v2(130.79,94.11)
1D05V_FUSE: length 25.8
  L4 w0.305: 137.31,98.54 137.23,98.54 136.82,98.26 136.53,97.67 136.26,97.31 135.52,96.98 134.66,96.98 134.31,96.63 133.32,96.63 132.93,96.24 132.93,95.35 133.03,95.25 133.03,94.4 132.71,94.09 131.71,94.09 131.01,94.78 v2(130.82,94.78)
  L4 w0.508: 137.31,98.54 141.21,100.26 144.89,102.65 146.37,104.12 146.47,104.14 v2(146.79,104.14)
  BOTTOM w0.305: v2(130.82,94.78) 130.78,94.78 130.31,94.36 CPU1.P16
  BOTTOM w0.508: v1(146.52,102.86) 146.79,103.13 v2(146.79,104.14) 147.7,104.14 148.47,104.92 R610.1
1D05V_IO_3PHASEIO: length 39.4
  TOP w0.508: v1(149.21,108.03) v2(149.21,108.59)
  L4 w0.508: v2(129.6,91.28) 129.46,91.42 129.46,94.32 129.47,94.36 130.94,95.83 130.97,95.94 130.97,97.74 131.95,98.73 132.32,98.73 133.26,99.67 133.68,99.81 135.52,101.65 136.31,103.46 136.58,104.7 141.31,109.43 148.37,109.43 v2(149.21,108.59)
  BOTTOM w0.305: v2(128.58,89.38) 128.8,89.84 CPU1.AA22 129.06,90.32 129.09,90.33 CPU1.Y20 v2(129.6,91.28) ; v2(128.58,89.38) 128.12,89.59 128.1,89.59 ; v2(128.58,89.38) 128.37,88.91 CPU1.AC23 ; v2(129.6,91.28) CPU1.V18 ; v2(129.6,91.28) 130.08,91.08
  BOTTOM w0.508: R607.1 149.69,106.94 PC1008.1 149.71,108.08 v2(149.21,108.59)
1D05V_PCH:
  vias: v1(141.46,104.88) v2(127.12,91.15) v2(127.31,96.6) v2(127.38,90.48) v2(127.61,89.79) v2(127.85,91.44) v2(127.85,89.11) v2(128.18,96.98) v3(139.3,105.41) v3(139.3,104.4) v3(140.34,104.12)
1D05V_S0: length 12.3
  TOP w0.508: R608.2 144.61,99.77 144.23,100.15 144.23,104.17 146.03,105.97 v3(146.03,106.56)
  vias: v1(145.52,107.19)
1D8V_PCH: length 88.1
  TOP w0.508: C1102.1 C1103.1 119.23,85.19 v2(119.97,85.46) ; C1101.1 v2(119.97,85.46) ; v2(119.97,85.46) C1104.1 ; PC1101.1 v2(127.86,86.8)
  L4 w0.203: 128.58,85.68 127.85,85.6 127.57,85.9 127.57,86.24 v2(127.86,86.8)
  L4 w0.305: v2(119.97,85.46) 120.25,85.14 122.18,85.2 125.61,85.2 126.4,85.99 126.4,86.59 126.9,87.08 127.53,87.08 127.82,86.8 v2(127.86,86.8) ; v2(135.59,76.35) 135.82,76.58 135.82,77.47 134.17,83.08 131.68,85.58 131.54,85.67 131.15,86.06 130.87,86.16 130.41,86.16 129.44,85.88 129.42,85.88 128.58,85.68
  BOTTOM w0.305: v2(127.86,86.8) 127.89,86.81 CPU1.AG25
  BOTTOM w0.508: v2(135.59,76.35) 134.12,74.42 133.86,73.9 v1(133.08,72.9) 131.57,70.95 124.35,63.73 101.5,63.73 100.13,65.1 96.68,65.1 95.48,66.3 94.4,66.3 92.7,68 87.54,68 86.39,69.14 R702.2
1D8V_S0: length 617.8
  TOP w0.254: Q5701.2 21.04,57.28 21.27,57.05 21.27,56.4 21.03,56.16 v2(19.57,56.16)
  TOP w0.406: Q5701.5 17.97,57.28 17.66,56.97 v2(17.3,56.97)
  TOP w0.508: v2(102.47,110.62) 102.65,110.62 102.9,110.87 104.58,110.87 109.24,106.21 109.33,105.57 109.71,102.52 110.4,100.71 v2(110.6,100.51) ; R5530.1 94.51,159.23 93.83,159.92 93.83,166.62 94.26,168.58 94.33,168.83 v2(94.55,169.12) 96.51,170.19 97.26,170.33 99.13,170.33 100.03,171.24 100.03,172.09 99.97,172.15 R5514.1 ; v2(144.3,121.57) 148.34,117.53 154.31,117.53 v1(159.06,112.78) 159.9,111.94 v2(161.53,111.94) ; Q6301.G 61.11,59.15 v2(61.07,59.11) 60.99,59.03 R2125.2 ; v2(154.34,18.14) 154.3,18.18 R2705.1 ; v2(160.92,84.1) 160.61,84.1 160.51,84 R7007.1 ; R7008.1 176.82,48.74 176.59,48.52 v2(176.28,48.52) ; R2018.1 93.01,70.44 v2(93.61,71.03) ; v2(111.72,163.81) 111.63,163.72 R5532.1 ; v2(133.7,111.14) 133.66,111.14 133.52,111.28 131.5,111.28 128.88,111.4 126.49,111.72 124.85,113.36 124.85,116.99 125.58,117.73 v2(125.58,118.11) ; v2(37.24,65.92) 37.19,65.92 35.92,64.65 31.27,64.65 30.77,65.15 23.68,65.15 22.28,63.76 19.01,63.76 18.3,63.04 18.3,59.18 17.3,58.19 v2(17.3,56.97) ; R7003.1 176.63,42.17 175.77,41.32 v2(175.15,41.32)
  L3 w0.508: v2(133.7,111.14) 130.96,111.14 129.93,112.17 129.93,115.72 132.65,118.44 141.72,118.44 144.3,121.02 v2(144.3,121.57) ; v2(79.79,58.27) 79.79,59.89 84.74,64.85 84.74,66.89 84.79,66.94 84.79,67.75 84.92,67.88 84.92,67.88 85.29,68.25 85.29,68.25 85.69,68.65 85.69,68.65 86.87,69.83 92.4,69.83 v2(93.61,71.03) 93.87,71.3 93.87,74.7 96.9,77.73 100.31,77.73 101.86,79.28 101.86,79.7 102.42,80.26 102.42,85.05 101.79,85.69 101.79,87.11 v2(101.86,87.19) ; v2(95.49,83.44) 95.49,83.62 96.39,84.52 96.39,88.51 100.95,93.07 101.26,93.38 101.29,93.38 105.2,97.29 105.2,99.66 105.21,99.67 105.88,100.33 105.88,101.21 105.51,102 105.51,102.08 104.99,103.29 104.92,103.35 104.92,103.36 104.87,103.4 104.61,103.66 103.11,104.32 101.35,106.88 100.87,107.36 100.87,108.48 101.58,109.19 101.58,109.91 100.95,110.54 v2(100.95,111.15) ; v2(160.1,70.11) 160,70.11 159.47,70.64 159.47,77.36 161.08,78.97 161.08,83.94 v2(160.92,84.1)
  L4 w0.508: v2(37.24,65.92) 37.27,65.89 38.23,65.89 39.53,64.59 46.77,64.59 47.29,64.07 49.09,64.07 49.72,63.45 49.72,62.69 49.74,62.66 49.74,61.66 50.63,60.77 52.63,60.77 53.96,59.44 59.72,59.44 60.05,59.11 v2(61.07,59.11) 65.18,59.11 67.67,56.62 78.54,56.62 79.79,57.86 v2(79.79,58.27) ; v2(125.58,118.11) 125.58,113.78 122.34,110.54 120.87,110.54 120.77,110.44 110.68,110.44 110.38,110.75 102.63,110.75 102.5,110.62 v2(102.47,110.62) ; v2(133.7,111.14) 133.57,111.27 129.74,111.27 129.27,110.87 127.82,109.42 127.49,108.87 127.49,108.82 127.52,108.48 127.52,108.47 127.53,108.35 127.53,108.32 127.54,108.23 127.54,104.85 v2(127.26,104.57) ; v2(163.46,5.54) 163.96,5.54 164.57,6.15 164.57,9.96 164.07,10.47 162.67,10.47 161.32,10.47 160.26,11.53 155.76,11.53 152.86,14.43 152.86,17.17 153.83,18.14 v2(154.34,18.14) 154.31,18.16 154.31,19.26 154.59,19.53 155.29,19.53 156.05,20.3 158.4,20.3 165.44,27.33 v2(165.84,27.33) 166.02,27.51 168.84,27.51 169.68,28.35 169.68,36.37 169.6,36.44 169.6,37.64 172.37,40.42 174.25,40.42 v2(175.15,41.32) 176.26,42.42 176.26,48.49 v2(176.28,48.52) 176.23,48.57 176.23,51.48 176.23,51.48 176.23,52.22 176.23,52.22 176.23,54.68 175.6,55.31 175.6,55.62 175.6,56.42 174.91,57.11 174.91,58.93 174.73,59.11 174.73,60.67 174.91,60.84 174.91,63.47 174.72,63.66 174.72,64.98 176.23,66.48 176.23,78.16 175.32,79.07 v2(175.32,79.53)
  BOTTOM w0.508: v2(154.34,18.14) 154.34,18.16 154.31,18.19 154.31,18.9 154.91,19.5 R2724.1 ; v2(17.3,56.97) 17.56,57.23 18.5,57.23 v2(19.57,56.16) ; v2(160.92,84.1) 161.05,84.1 161.78,84.83 161.78,88.59 163.43,90.24 163.43,91.44 165.01,93.02 170.24,93.02 ; R6408.2 162.71,5.96 163.13,5.54 v2(163.46,5.54) ; 170.24,93.02 173.59,93.02 178.04,88.57 178.04,82.25 v2(175.32,79.53) ; 170.24,93.02 170.24,104.6 167.77,107.06 161.78,107.06 160.84,108 160.84,111.25 v2(161.53,111.94) ; R2106.2 v2(127.26,104.57) ; v2(102.47,110.62) 102.4,110.62 102.12,110.62 101.59,111.15 101.04,111.15 v2(100.95,111.15) 100.53,111.15 96.31,111.15 96.29,111.17 95.6,111.17 94.5,112.27 94.5,114.55 94.5,138.64 97.59,141.73 97.59,144.96 96.07,146.48 96.05,146.48 94.9,147.63 94.9,155.2 93.94,156.16 93.94,167.72 94.33,168.75 94.55,169.02 v2(94.55,169.12) 94.62,169.12 98.84,164.9 106.05,164.9 106.64,165.48 108.11,165.48 108.57,165.03 108.57,164.26 109.3,163.53 111.44,163.53 v2(111.72,163.81) ; 135.81,111.96 136.33,111 136.36,110.9 136.36,109.85 136.1,109.59 135.82,109.49 135.48,109.36 135.16,109.36 134.97,109.55 133.78,109.55 Q2101.G 133.63,111.06 v2(133.7,111.14) ; v2(160.1,70.11) 160.1,70.16 160.26,70.31 R2511.1 ; v2(125.58,118.11) 125.58,117.78 125.84,117.52 R4050.2 R4049.2 127.13,118.2 R4012.1 ; v2(95.49,83.44) 94.78,83.44 93.31,81.97 93.09,81.97 88.45,77.33 88.45,74.98 91.12,72.31 92.48,72.31 93.61,71.18 v2(93.61,71.03) ; v2(165.84,27.33) 165.36,26.85 165.36,26.81 R2729.1 ; v2(101.86,87.19) R2024.1 R2019.1 R2029.1
1D8V_S0_DISCHG: length 2.6
  TOP w0.508: v2(125.53,119.53) v1(126.09,119.53)
  BOTTOM w0.406: v2(125.53,119.53) Q4003.3 126.23,118.22 R4012.2
1D8V_S0_EN: length 8.9
  TOP w0.102: v1(129.06,118.47) 129.62,118.47 v2(129.65,118.49) ; v1(132.76,115.09) v2(132.36,114.68)
  L4 w0.127: v2(132.36,114.68) 132.01,114.68 130.28,116.41 130.28,117.86 v2(129.65,118.49)
  BOTTOM w0.102: v2(132.36,114.68) 132.25,114.79 U4002.3 ; C4011.1 128.82,119.1 R4005.2 129.37,118.21 v2(129.65,118.49)
1D8V_S0_SIP:
  vias: v1(128.28,115.06)
1D8V_S5: length 698.4
  TOP w0.305: 56.42,63.61 56.61,63.8 56.7,63.8 56.93,64.03 XDP1.12 56.93,66.91 56.7,67.13
  TOP w0.406: v2(68.38,65.36) 68.38,64.93 67.97,64.52 Q1903.2 65.84,64.52 65.84,64.51 65.57,64.51 Q1903.5 65.01,64.52 64.73,64.24 64.73,63.48 65.61,62.59
  TOP w0.508: v2(92.69,73.26) 92.69,71.29 v2(92.44,71.05) ; v2(167.09,69.01) 164.02,69.01 162.27,70.77 158.96,70.77 155.6,67.4 151.43,67.4 v2(151.39,67.36) ; R5527.1 113.34,161.11 v2(113.65,161.42) ; v2(167.57,29.01) 168.42,29.86 171.22,29.86 171.58,30.22 R2530.2 173.55,30.23 R2523.2 ; 65.61,62.59 66.53,61.67 v2(66.53,59.31) 66.5,59.31 66.48,59.29 R2119.2 ; v2(101.53,108.18) 101.63,108.28 101.63,111.05 101.96,111.38 v2(102.47,111.38) ; v2(125.97,123.5) 125.31,123.5 124.02,124.78 124.02,126.5 124.62,127.1 PR5016.1 PR5025.1 125.29,128.49 124.71,129.07 124.71,131.14 130.56,137 v2(130.56,143.54) ; R2120.1 159.05,79.96 159.22,79.96 159.49,80.23 Q2102.G v2(160.19,79.34) ; R1819.2 111.02,96.08 110.14,97.28 107.65,97.28 v2(107.53,97.16) 104.94,94.57 104.24,94.21 103.37,93.34 103.31,93.17 102.97,92.72 102.96,92.7 102.95,92.68 102.3,91.81 v2(102.3,90.86) ; R9905.1 55.43,75.47 55.25,75.64 v2(55.25,75.72) ; R1812.2 63.84,69.01 63.35,68.53 63.35,67.46 v2(63.43,67.39) ; R9904.1 47.3,61.74 47.73,62.18 47.73,62.36 v2(47.76,62.38) 47.77,62.39 48.54,62.39 R6322.2 ; R1703.2 139.94,95.71 140.75,95.48 v2(141.69,94.54) 142.78,94.31 145.1,94.31 145.98,95.19 145.98,104.8 146.77,105.59 146.77,108.56 144.08,111.25 141,111.25 ; 56.42,63.61 55.9,63.1 C9902.1 ; v2(53.47,67.08) 53.53,67.13 56.7,67.13 ; v2(162.29,29.62) 158.86,29.62 157.59,30.89 154.97,30.89 v2(153.63,29.54) ; R2533.2 62.57,47.8 61.08,49.29 R2529.2 61.13,51.77 62.55,51.77 v2(62.72,51.59) 62.98,51.86 R2532.1 ; PC5034.1 137.62,131.98 v2(137.83,131.78)
  L3 w0.508: v2(102.3,90.86) 102.3,90.8 100.46,88.97 100.46,80.74 100.21,80.48 100.21,78.9 v2(99.94,78.63) 99.94,78.63 96.55,78.63 96.22,78.3 96.18,78.3 92.69,74.8 v2(92.69,73.26) 90.15,70.72 v2(88.5,70.72) 86.87,70.72 86.5,70.72 84.03,68.25 84.03,68.24 83.9,68.12 83.9,67.31 83.85,67.26 83.85,65.21 78.26,59.63 v2(78.26,58.27) ; v2(101.91,141.61) 101.94,141.63 101.94,142.93 105.9,146.89 127.21,146.89 v2(130.56,143.54) 133.43,140.67 v2(144.66,140.67) ; v2(133.64,115.57) 133.84,115.37 139.77,115.37 147.76,123.36 147.76,129 147.23,129.53 v2(147.23,130.08) ; v2(167.09,69.01) 167.7,68.4 167.7,62.87 166.81,61.98 166.81,53.37 162.57,49.13 v2(162.57,47.93) 163.66,47.93 163.96,48.24 164.75,48.24 165.13,47.86 165.13,47.13 165.13,47.12 165.13,44.33 166.3,43.16 166.3,38.69 168.26,36.73 v2(168.26,32.69) 168.26,29.69 v2(167.57,29.01) 167.57,28.98 167.16,28.58 165.49,28.58 164.45,29.62 v2(162.29,29.62) ; v2(60.89,72.93) 60.89,71.22 63.43,68.68 v2(63.43,67.39) 63.43,64.78 63.04,64.39 61.92,64.39 v2(61.18,65.13) 61.18,60.8 62.31,59.67 62.31,52 62.72,51.59 v2(62.72,51.59) ; v2(151.39,67.36) 153.35,67.36 157.94,71.96 157.94,77.09 v2(160.19,79.34) ; v2(107.53,97.16) 107.53,97.27 106.83,98.5 106.6,98.73 v2(106.08,99.19) ; v2(53.47,67.08) 53.47,66.25 49.49,62.26 47.89,62.26 v2(47.76,62.38)
  L4 w0.305: v2(114.49,98.81) 114.16,99.13 109.04,99.13 107.59,100.58 106.04,100.58 105.77,100.31 105.77,99.49 v2(106.08,99.19)
  L4 w0.508: v2(149,67.34) 149.06,67.4 149.06,67.61 148.17,68.51 145.98,70.69 145.98,76.81 146.99,77.82 146.99,89.91 142.36,94.54 v2(141.69,94.54) ; v2(125.97,123.5) 125.97,123.01 124.67,121.72 124.67,115.44 120.3,111.08 110.95,111.08 110.58,111.44 102.55,111.44 102.49,111.38 v2(102.47,111.38) ; v2(138.67,27.15) 138.79,27.28 147,27.28 147.02,27.26 151.52,27.26 153.25,28.98 153.25,29.16 v2(153.63,29.54) ; v2(137.83,131.78) 137.83,132.01 138.23,132.41 146.16,132.41 147.23,131.35 v2(147.23,130.08) 148.17,130.08 149.18,131.08 v2(149.18,136.15) ; v2(53.47,67.08) 56.42,67.08 56.75,66.75 59.55,66.75 v2(61.18,65.13) 61.95,64.35 62.67,64.35 63.21,64.9 67.93,64.9 v2(68.38,65.36) ; v2(60.89,72.93) 60.15,73.66 57.43,73.66 56.36,74.73 56.07,74.73 55.25,75.54 v2(55.25,75.72) ; v2(106.31,141.2) 102.34,141.2 101.94,141.61 v2(101.91,141.61) ; v2(78.26,58.27) 77.25,57.25 68.59,57.25 v2(66.53,59.31) ; v2(141.03,113.08) 136.13,113.08 v2(133.64,115.57)
  BOTTOM w0.203: v2(137.83,131.78) 137.62,131.57 137.15,131.57 137.08,131.5 PU5001.17
  BOTTOM w0.406: Q1901.2 88.86,71.07 v2(88.5,70.72) ; Q1904.2 v2(106.31,141.2) ; v2(96.17,67.9) 94.72,67.9 92.62,70 92.62,70.87 v2(92.44,71.05) 92.41,71.07 Q1901.5
  BOTTOM w0.508: v2(53.47,67.08) 51.67,67.08 50.93,66.34 46.39,66.34 45.06,67.67 42.14,67.67 41.71,68.1 38.68,68.1 38.16,67.58 38.16,64.62 37.7,64.16 35.92,64.16 35.14,64.95 27.13,64.95 26.19,64.01 v2(26.19,63.22) 25.38,64.04 22.97,64.04 22.61,63.68 R5703.1 ; R1815.2 R2114.2 114.7,99.03 v2(114.49,98.81) ; v2(168.26,32.69) 168.26,33.14 167.84,33.56 163.01,33.56 R2522.1 ; R702.1 88.2,69.62 88.55,69.98 88.55,70.66 v2(88.5,70.72) 86.01,70.72 85.39,70.09 R2534.2 ; R1509.1 R1506.1 R1521.1 98.18,105.54 98.53,105.18 99.47,105.18 99.91,105.62 R1503.1 100.8,106.57 R1501.1 ; R2421.1 149.19,66.59 149,66.78 v2(149,67.34) 149.79,67.34 149.85,67.4 C2446.1 151.33,67.4 151.37,67.36 v2(151.39,67.36) 151.43,67.4 C2439.1 152.14,67.41 R2436.1 152.95,66.68 152.56,66.29 U2404.1 ; PR5044.1 145.6,129.92 146.03,129.49 146.64,129.49 v2(147.23,130.08) ; 113.84,161.23 113.84,161.32 113.67,161.49 113.67,163.43 112.99,164.11 112.99,166.25 112.3,166.93 R5536.1 ; 113.84,161.23 v2(113.65,161.42) ; 113.84,161.23 114.38,160.68 114.38,158.37 115.46,157.3 115.5,157.3 119.95,152.85 127.3,152.85 131.14,149 137.35,149 144.13,142.23 144.13,141.2 v2(144.66,140.67) v2(149.18,136.15) ; R1501.1 100.81,103.02 102.04,101.8 102.04,101.25 103.21,100.08 103.65,100.08 103.65,100.08 104.18,100.08 104.18,100.08 104.75,100.08 104.84,100.15 105.19,100.15 105.42,99.92 105.57,99.75 105.57,99.74 106.08,99.23 v2(106.08,99.19) ; R1501.1 101.15,106.56 101.53,106.94 v2(101.53,108.18) ; 102.5,96.59 R1512.1 101.14,95.49 R1518.1 99.45,93.9 99.45,92.71 ; v2(99.94,78.63) 100.27,78.3 100.46,78.2 100.48,78.18 101.64,78.18 103.42,78.45 103.42,78.45 103.56,78.47 103.61,78.49 105.47,78.92 ; v2(162.57,47.93) 162.87,48.24 R2497.1 ; v2(138.67,27.15) 137.46,25.95 Q6508.G ; v2(102.47,111.38) 102.6,111.25 102.91,111.25 102.96,111.2 103.55,111.2 104.13,110.62 104.13,110.62 104.55,110.2 104.55,107.09 105.25,106.39 R1834.2 ; R2535.1 162.61,29.2 162.29,29.52 v2(162.29,29.62)
  vias: v1(139.81,112.19)
1D24V_AUD_ISH_PLL: length 16.5
  TOP w0.508: v2(130.33,86.94) 130.38,86.89 131.48,86.36 131.54,86.3 132.21,86.07 132.69,86.04 134.05,86.04 C1010.1 135.39,86.35 137.98,87.3 138.91,87.3 v1(141.64,87.54) 142.22,87.64 PC1042.1 144.18,87.86 R603.2
  BOTTOM w0.33: 130.08,86.45 v2(130.33,86.94) ; v2(130.33,86.94) CPU1.AJ20 ; v2(130.33,86.94) CPU1.AJ22
1D24V_DSI_CSI: length 18.4
  TOP w0.457: C1106.1 132.38,89.87 136.19,91.37 136.68,91.57 C1107.1
  TOP w0.508: C1106.1 130.66,89.75 130.59,89.83 v2(130.06,89.92) ; R606.1 PC1102.1 142.74,92.94 v1(142.15,92.94) 142.13,92.93 141.03,92.9 138.39,92.88 137.85,92.69 137.54,92.31 C1107.1
  BOTTOM w0.305: CPU1.AA18 v2(130.06,89.92) CPU1.AA20
1D24V_GLML: length 29
  TOP w0.508: C1011.1 124.31,83.69 124.29,83.66 124.29,83.4 124.25,83.22 v2(124.17,83.14) ; 127.74,84.52 127.65,84.41 v2(127.13,84.22) ; v2(130.82,85.56) 131.87,85.5 C1012.1 134.26,85.23 135.57,85.71 C1013.1 136.98,85.97 137.75,85.21 138.32,84.94 138.74,84.94 140.49,85.27 141,85.78 v1(141.75,85.78) 142.64,85.78 143.73,84.68 144.24,84.68 PC1043.1 R605.1
  L4 w0.305: v2(124.17,83.14) 124.49,83.82 126.44,84.54 v2(127.13,84.22) 127.15,84.19 128.51,83.56 129.52,83.56 129.59,83.58 130.4,84.4 130.47,84.6 v2(130.82,85.56)
  BOTTOM w0.305: v2(124.17,83.14) 124.12,83.23 CPU1.AM37 ; v2(127.13,84.22) 127.15,84.23 CPU1.AM28 ; CPU1.AK20 CPU1.AM20 v2(130.82,85.56)
1D24V_MPHY: length 13.8
  TOP w0.508: R604.1 PC1046.1 143.05,90.25 v1(142.34,90.29) 141.2,90.7 139.93,91.17 C1014.1 138.06,91.19 137.74,91.23 137.05,90.98 136.55,90.81 134.86,90.17 134.24,89.93 133.88,89.57
  BOTTOM w0.305: v2(130.58,88.55) 130.6,88.56 CPU1.AE18 ; CPU1.AG22 v2(129.84,88.28) ; v2(129.84,88.28) CPU1.AE20 ; v2(129.84,88.28) 129.81,88.28 CPU1.AE22
1D24V_S5: length 46.6
  BOTTOM w1.016: 148.8,132.36 150.2,132.36 151.52,131.04 151.52,119.17 151.49,119.14 151.49,105.68 150.43,104.61 150.22,104.61 147.51,101.91 147.51,98.5 147.81,97.28 147.99,96.98 147.99,96.85 v1(151.8,93.04) v3(151.8,91.16)
1D24V_USB2: length 15.8
  TOP w0.508: R602.1 v1(143.57,89.05) 138.6,89.05 136.12,88.27 134.47,87.62 134.23,87.53 133.63,87.49 C1112.1 132.13,87.45 130.8,87.45 130.45,87.61 130.09,87.61 v2(130.07,87.62)
  BOTTOM w0.305: CPU1.AG20 130.12,87.64 v2(130.07,87.62)
1D35V_CPU_VDDQ_S3: length 135.8
  TOP w0.508: v2(131.8,134.32) 131.63,134.32 131.17,133.86 PC5010.1 ; v2(149.11,123.14) 151.11,125.15 160,125.15 v2(160.05,125.1)
  L3 w0.508: v2(160.05,125.1) 160.05,95.76 158.58,94.29 158.55,94.29 158.17,93.91 158.17,93.88 154.52,90.22 152.68,90.22 145.26,82.81 139.86,82.81 139.48,83.19 138.07,83.19 137.08,84.18 137.08,84.81 136.31,85.59 135.78,85.59 135.36,85.16 v2(135.36,84.68) ; v2(131.8,134.32) 131.81,134.32 133,133.12 147.63,133.12 149.12,131.64 149.12,123.15 v2(149.11,123.14) 149.09,123.14 144.55,118.6 143.9,118.6 139.95,114.66 139.95,114.01 138.92,112.97 138.92,109.02 138.72,108.82 v2(138.23,108.82)
  BOTTOM w0.203: v2(131.8,134.32) 131.86,134.26 PU5001.3
  BOTTOM w0.254: v2(122.92,81.92) 122.52,82.05 CPU1.AN41 CPU1.AN42 CPU1.AN44 CPU1.AN46 v2(120.14,80.74) CPU1.AR47
  BOTTOM w0.305: v2(129.59,84.34) 129.62,84.35 CPU1.AN23 129.86,84.83 130.04,84.75 130.49,84.91 CPU1.AN22 ; CPU1.AV50 118.7,78.39 v2(118.37,78.37) 118.37,78.87 CPU1.AT51 ; CPU1.AV14 135.23,84.41 v2(135.36,84.68) 135.3,84.83 CPU1.AT13 ; CPU1.AN20 131.46,85.3 v2(131.61,84.89) 131.75,84.94 131.9,85.27 CPU1.AN18 132.72,85.24 CPU1.AR17 133.16,84.67 CPU1.AT17 133.11,84.16 133.04,83.6 v2(133.13,83.34) ; CPU1.AT47 120.25,80.03 v2(120.38,80.07)
  BOTTOM w0.508: v2(138.23,108.82) 137.97,109.08 R4006.1
  vias: v1(91.8,54.51) v1(120.35,78.82) v1(128.61,78.44)
1D35V_DIMM_VDDQ_S3: length 77.5
  BOTTOM w0.305: 108.67,28.92 DM1.82 108.67,32.12 v2(108.43,32.36) ; v2(120.99,40.14) 120.97,40.12 DM1.123 120.97,37.88 121.35,37.5 121.35,36.35 120.97,35.97 v2(120.74,35.97) ; 108.37,40.22 DM1.81 108.37,36.81 107.43,35.87 v2(107.16,35.87) ; v2(121.37,29.04) 121.27,29.04 DM1.124 121.27,31.83 v2(121.11,31.98) ; v2(112.79,36.55) 112.87,36.55 113.3,36.97 113.3,37.24 113.49,37.43 113.49,37.48 113.77,37.76 DM1.99 113.77,39.79 v2(113.42,40.14) ; 115.87,28.96 DM1.106 115.87,31.89 v2(115.63,32.14) ; v2(112.05,32.48) 112.27,32.26 DM1.94 112.27,28.99 ; v2(119.39,40.14) 119.17,39.92 DM1.117 119.17,37.83 119.34,37.66 119.34,35.94 118.4,35.01 v2(118.35,35.01) ; v2(115.05,37.16) 115.55,37.66 115.55,38.7 DM1.105 115.57,40.09 ; 110.47,28.92 DM1.88 110.47,31.68 110.23,31.92 v2(110.23,32.4) ; 106.57,40.5 DM1.75 106.57,37.72 107.03,37.26 v2(107.12,37.26) ; 112.3,40.16 111.97,39.83 DM1.93 111.97,37.89 111.7,37.61 111.7,37.16 111.7,36.3 111.7,35.92 111.03,35.26 v2(110.71,35.26) 110.32,35.26 110.04,35.54 110.04,37.61 110.17,37.74 DM1.87 110.17,40.17 ; v2(113.17,34.12) 113.74,34.12 114.18,33.68 114.18,31.48 114.07,31.37 DM1.100 114.07,28.99 ; v2(118.79,32.62) 119,32.62 119.47,32.15 DM1.118 119.47,29.05 ; 106.87,28.95 DM1.76 106.87,31.35 106.4,31.82 106.4,32.47 106.11,32.77 v2(105.7,32.77) ; v2(117.72,40.14) 117.37,39.79 DM1.111 117.37,36.97 117.02,36.62 v2(116.75,36.62) ; v2(117.02,32.71) 117.31,32.71 117.67,32.35 DM1.112 117.67,28.83
  vias: v1(89.67,38.66) v1(92.29,47.37) v1(121.72,38.91) v2(103.92,28.68) v2(108.42,33.68) v2(109.28,34.78) v2(110.22,34.31) v2(110.6,36.61) v2(112.03,33.75) v2(112.76,35.23) v2(113.12,32.78) v2(114.85,40.14) v2(115.05,35.22) v2(115.68,34.41) v2(116.65,35.28) v2(116.9,33.98) v2(118.33,36.45) v2(118.57,33.94) v2(120.72,34.63)
1D35V_S3_DISCHG: length 4.8
  BOTTOM w0.406: v1(137.78,113.82) 137.78,112.17 138.5,111.45 Q4002.3 138.5,110.19 138.86,109.83 R4006.2
1P8U: length 39
  TOP w0.508: PC5023.1 137.6,133.3 138.49,132.41 v2(138.49,131.78) v1(138.49,129.44) 138.49,127.92 141.84,124.56 141.84,120.28 139.67,118.11 138.41,118.11 136.66,116.36 136.66,115.79 133.99,113.12 127.99,113.12 v2(126.3,114.81)
  BOTTOM w0.203: PU5001.18 137.15,131.1 137.29,131.24 138.18,131.24 138.49,131.55 v2(138.49,131.78)
  BOTTOM w0.508: R4050.1 125.84,115.27 v2(126.3,114.81)
3D3V_1D8V_GSEN2: length 19
  TOP w0.356: v2(175.42,45.82) 175.42,45.88 175.62,46.08 U7001.10
  TOP w0.508: v2(175.42,45.82) 175.41,45.81 C7002.1 175.41,44.69 175.74,44.36 R7003.2 175.74,42.18 v1(175.55,41.99) ; v2(175.38,51.85) 175.51,51.72 R7004.1 R7001.1
  L3 w0.508: v2(175.42,45.82) 175.42,48.08 ; 175.42,48.08 173.48,48.08 172.73,47.33 172.73,45.21 v2(172.78,45.16) ; 175.42,48.08 175.42,51.81 v2(175.38,51.85)
  BOTTOM w0.508: v2(172.78,45.16) 172.68,45.16 172.47,45.37 C7001.1
3D3V_AUX_KBC: length 271.8
  TOP w0.508: v2(152.76,88.75) 152.76,87.04 154.46,85.35 154.46,85.35 154.81,85 156.31,83.5 156.86,82.95 156.86,79.33 159.07,77.12 159.32,76.87 161.19,76.87 161.33,77.01 161.44,77.01 161.45,77.02 164.42,77.02 164.78,76.66 165.16,76.66 165.19,76.63 v2(166.28,76.63) 166.48,76.43 166.48,75.67 166.53,75.62 166.53,74.75 166.15,74.37 R2613.1 ; 171.41,67.39 172.47,67.39 173.31,68.23 173.31,70.31 175.17,72.16 175.17,74.04 173.57,75.64 v2(172.75,75.64) ; 167.1,57.37 164.03,57.37 161.02,54.36 158.83,54.36 157.67,53.2 v2(157.67,53.14) ; 169.78,58.3 169.78,60.07 171.84,62.13 171.84,63.5 ; v2(162.97,143.39) 162.85,143.39 162.52,143.72 PR4412.1 PR4415.1
  L3 w0.508: v2(166.28,76.63) 166.81,76.63 167.8,75.64 v2(172.75,75.64) ; v2(152.14,176.1) 152.14,176.49 154.95,179.3 171.46,179.3 177.55,173.21 177.55,157.9 173.53,153.88 173.14,153.88 170.82,151.56 169.96,151.56 162.97,144.58 v2(162.97,143.39)
  L4 w0.508: v2(156.75,45.34) 156.75,46.3 157.67,47.23 v2(157.67,53.14) ; v2(162.97,143.39) 163,143.36 163,143.24 163.86,142.38 164.22,142.38 166.97,142.38 167.57,142.98 169.07,142.98 170.26,141.78 170.26,137.67 169.3,136.7 164.01,136.7 159.37,132.06 159.37,127.25 158.21,126.09 v2(158.21,114.73) 158.2,114.72 158.2,107.83 159.34,106.69 159.34,102.08 152.76,95.51 v2(152.76,88.75) ; v2(169.86,54.61) 169.53,54.61 169.25,54.33 169.25,53.46 170.16,52.55 170.16,52.48 170.8,51.85 170.8,47.07 v2(170.7,46.97)
  BOTTOM w0.356: RN2406.3 166.14,75.42 165.95,75.61 165.95,75.88 166.14,76.07 RN2406.4 166.74,76.37 166.48,76.63 v2(166.28,76.63)
  BOTTOM w0.508: R2408.2 178.14,60.81 178.52,61.19 178.52,63.02 178.34,63.2 178.34,74.5 176.72,76.13 173.9,76.13 173.42,75.64 v2(172.75,75.64) ; R2441.1 156.65,45.54 156.75,45.44 v2(156.75,45.34) ; v2(152.14,176.1) 152.97,175.27 D4306.2 ; D4305.2 148.74,173.81 149.93,172.62 151.53,172.62 152.98,174.07 D4306.2 ; R2462.1 171.88,48.2 171.51,47.83 171.51,47.43 171.51,47.24 171.23,46.97 v2(170.7,46.97) ; R2608.1 154.67,109.7 v1(157.04,112.08) 158.21,113.25 v2(158.21,114.73) ; v2(157.67,53.14) 157.67,52.94 157.11,52.38 R2437.1 156.89,52.04 156.52,51.67 155.4,51.67 R2435.2 ; v2(166.28,76.63) 166.28,77.17 165.73,77.71 Q2404.D ; D4306.2 153,175.29 D4304.2
3D3V_AUX_S5: length 435.4
  TOP w0.508: v2(165.16,149.66) 164.9,149.91 PR4419.1 ; v2(155.02,113.84) 155.23,113.84 160.23,108.84 160.23,106.07 162.69,103.61 v2(162.69,96.57) ; PR4534.1 51.25,54.7 50.68,55.27 v2(50.68,55.88) ; v2(30.56,24.13) 29.98,24.13 29.57,23.73 R2515.2 29.51,23.24 R2518.1 26.97,21.02 26.03,20.08 Q2501.2 ; v2(165.17,144.3) PR4435.1 165.17,145.8 PR4417.1 ; v2(150.27,134.9) 153.19,134.9 v2(154.52,136.22) ; v2(169.11,45.6) 168.76,45.94 168.17,45.94 167.04,47.07 ; PR4438.2 156.65,142.98 155.76,143.87 v2(155.76,143.97) PR4434.1 ; 164.27,49.2 163.71,49.2 163.57,49.06 162.06,49.06 162.02,49.09 159.91,49.09 159.21,49.79 v2(159.21,50.47)
  L3 w0.508: v2(30.56,24.13) 48.27,24.13 49.92,25.78 49.92,42.6 52,44.69 52,47.74 52.2,47.94 v2(52.2,50.43) 52.2,51.51 51.95,51.76 51.95,53.46 50.68,54.73 v2(50.68,55.88) ; v2(150.27,134.9) 150.39,134.79 150.39,120.86 143.78,114.25 142.76,114.25 142.45,114.56 v2(141.79,114.56) ; v2(162.21,75.14) 161.57,75.14 160.77,74.33 160.77,72.44 164.22,68.99 164.22,58.37 v2(163.96,58.12) 163.96,58.11 162.63,56.78 162.63,55.06 159.21,51.64 v2(159.21,50.47)
  L4 w0.508: v2(162.21,75.14) 162.21,78.87 162.06,79.03 162.06,82.29 162.06,82.98 161.88,83.16 161.88,83.8 161.83,83.85 161.83,89.23 162.44,89.84 162.44,90.25 162.69,90.5 v2(162.69,96.57) ; v2(155.76,143.97) 154.52,142.72 v2(154.52,136.22) 155.38,135.36 155.38,114.2 v2(155.02,113.84) ; v2(141.79,114.56) 141.51,114.84 135.62,114.84 129.52,120.93 v2(129.52,121.41) ; v2(159.21,50.47) 159.21,46.24 159.34,46.11 159.34,46.09 159.82,45.6 v2(159.82,45.34) ; v2(30.56,24.13) 33.26,24.13 35.16,22.23 37.35,22.23 38.59,23.47 51.57,23.47 52.59,24.49 131,24.49 133.1,22.38 133.1,20.91 135.52,18.49 141.76,18.49 142.53,19.25 147.07,19.25 148.27,20.45 150.5,20.45 154.26,24.21 158.9,24.21 161.29,26.6 163.19,26.6 164.95,28.36 164.95,33.15 168.33,36.53 168.33,37.96 169.12,38.74 169.12,45.58 v2(169.11,45.6)
  BOTTOM w0.203: 168.87,53.72 168.87,53.43 168.65,53.22 KBC24.75
  BOTTOM w0.508: v2(165.16,149.66) 165.16,144.34 165.17,144.32 v2(165.17,144.3) 164.22,144.3 163.61,143.69 163.61,142.52 163.13,142.04 160.86,142.04 160.36,142.04 159.82,142.04 158.18,142.04 158.18,142.04 157.69,142.04 v2(155.76,143.97) ; 168.87,53.72 168.87,55.43 168.42,55.88 168.39,55.88 166.27,58 164.08,58 v2(163.96,58.12) ; v2(162.21,75.14) 162.21,75.16 162.86,75.81 Q2404.S 163.47,75.27 163.47,74.5 R2491.2 C2442.2 ; R4002.1 142.26,114.92 141.89,114.56 v2(141.79,114.56) 141.36,114.56 140.89,115.03 R4009.2 ; R4011.1 129.2,120.84 129.52,121.16 v2(129.52,121.41) ; v2(155.02,113.84) v1(154.19,113.84) 153.8,113.84 152.62,112.66 R2612.1 ; PR4501.1 51.62,52.15 52.24,51.53 PR4505.2 52.24,50.47 v2(52.2,50.43) ; R2489.2 160,45.6 159.82,45.42 v2(159.82,45.34)
3D3V_CAMERA_S0: length 1.1
  BOTTOM w0.305: v2(113.82,175.41) 114,174.94 LCD1.32
3D3V_G_VDD_S0: length 4
  TOP w0.305: 175.06,46.4 U7001.9
  TOP w0.508: v1(175.05,43.99) 174.71,44.33 R7002.2 174.13,44.55 174.49,44.91 C7003.1 174.49,45.84 175.06,46.4
3D3V_LCDVDD_S0:
  vias: v1(102.65,161.29)
3D3V_LCDVDD_S0_CONN:
  vias: v3(102.72,168.79) v3(103.18,167.92)
3D3V_PWR:
  vias: v1(35.77,54.74) v3(33.1,58.73) v3(33.08,57.79) v3(33.08,56.8) v3(34.04,58.73) v3(34.02,57.79) v3(34.04,56.85) v3(35.11,58.73) v3(35.08,57.79) v3(36.08,58.78) v3(36.05,57.84)
3D3V_PWR_2: length 4.9
  TOP w0.203: PU4503.3 v2(53.4,48.59)
  BOTTOM w0.508: v2(53.4,48.59) 53.04,48.95 PC4526.1 53.13,49.6 PR4505.1 53.6,51.78 v1(53.6,52.19)
3D3V_S0: length 588.2
  TOP w0.508: v2(170.77,37.85) 170.39,37.85 169.78,37.24 165.95,37.24 164.7,35.99 v2(163.18,35.99) ; v2(84.54,63.6) 84.54,63.17 84.89,62.82 86.29,62.82 86.55,63.08 86.55,64.28 86.7,64.42 86.7,64.43 88.12,65.86 88.12,68.56 87.37,69.31 R1606.1 86.39,69.7 85.52,70.58 Q1601.G 85.94,70.87 87.05,71.98 87.05,73.9 86.09,74.86 v2(86.09,75.47) 86.09,77.11 86.59,77.62 86.59,77.62 v2(94.37,85.4) 94.52,85.55 94.53,85.55 96.23,87.26 96.69,87.71 v2(98.46,87.71) ; v2(166.55,44.47) 166.55,44.27 166.67,44.15 C6010.1 166.66,43.63 C6009.1 164.89,43.63 164.35,44.17 v2(164.09,44.17) 164.01,44.09 164.01,44.07 163.66,43.72 163.66,43.51 162.93,42.78 161.89,42.78 160.51,44.15 160.51,46.03 v2(160.68,46.19) 162.91,46.19 v2(163.56,46.84) 163.89,46.84 164.32,46.41 166.73,46.41 v2(167.16,45.98) ; EC8918.1 27.92,68.21 v2(27.9,68.23) ; v2(155.05,56.92) 154.31,56.19 152.96,56.19 152.59,56.56 152.59,57.43 152.6,57.44 R2427.1 152.6,58.61 151.67,59.54 v2(151.67,61.39) ; v2(127.21,125.02) 127.13,125.02 126.74,125.4 PR5030.1 ; R1921.2 169.4,68.1 171.71,70.41 171.75,70.41 172.12,70.78 172.12,70.82 173.16,71.86 173.16,74.53 v2(173.11,74.58) 172.5,74.58 172.09,74.98 172.09,76.25 170.86,77.48 R2126.1 167.6,77.48 166.82,78.27 Q2103.G ; v2(143.67,37.26) 143.67,38.61 146.49,41.43 146.49,44.38 147.43,45.32 C1223.1 C1224.1 149.26,44.43 148.6,43.77 148.6,40.44 149,40.03 160.89,40.03 161.91,39.01 v2(162.64,39.01) ; v2(161.83,91.19) 160.97,92.05 160.97,94.75 160.99,94.78 160.99,97.38 160.97,97.4 160.97,104.44 159.29,106.11 159.29,108.64 153.07,114.86 148.7,114.86 v2(148.32,114.48) ; R7002.1 173.26,43.44 v2(173.21,43.48) ; v2(146.57,29.26) 146.57,28.2 148.78,25.99 v2(151.21,25.99) 151.47,26.24 152.41,26.24 153.32,25.33 161.25,25.33 161.5,25.07 162.69,25.07 165.61,27.99 170.9,27.99 172.27,26.62 172.27,23.73 171.15,22.61 v2(170.49,22.61) ; C2601.1 168.36,47.4 168.41,47.45 v2(168.41,47.83) 168.41,48 168.51,48.1 168.51,48.17 168.82,48.47 R2472.1 ; R5531.1 110.81,161.09 v2(108.71,163.2) R5515.1 ; R7006.1 v2(167.23,84.2) ; v2(166.12,72.65) 166.12,72.94 167.57,74.39 v2(167.57,74.73)
  L3 w0.508: v2(167.23,84.2) 166.45,84.2 166.21,84.44 166.07,84.44 164.6,85.92 164.6,87.15 163.6,88.15 163.6,89.42 161.84,91.19 v2(161.83,91.19) ; v2(168.41,47.83) 168.41,48.77 169.5,49.86 169.5,51.37 171.68,53.55 172.81,53.55 173.49,54.22 173.49,54.75 173.12,55.12 171.12,55.12 171.04,55.2 171.04,55.2 170.33,55.91 168.66,55.91 167.65,56.92 167.65,58.85 168.33,59.54 168.33,67.96 168.43,68.06 168.43,68.28 169.55,69.39 169.55,70.31 170.85,71.6 170.85,72.5 171.93,73.59 172.8,73.59 173.11,73.89 v2(173.11,74.58) 172.73,74.96 167.8,74.96 v2(167.57,74.73) 164.17,74.73 162.97,75.92 160.81,75.92 v2(160.23,75.34) 160.13,75.24 160.13,71.25 160.74,70.64 160.74,67.92 156.4,63.58 156.4,58.27 v2(155.05,56.92) ; v2(148.32,114.48) 151.67,117.83 151.67,134.83 147.71,138.79 147.71,140.85 v3(146.97,141.58) ; v2(102.57,146.23) 102.57,144.91 v2(102.52,144.86)
  L3 w1.016: 100.44,157.46 114.64,157.46 115.81,156.29 121.39,156.29 131.31,146.37 137.79,146.37 142.58,141.58 v3(146.97,141.58)
  L4 w0.508: v2(94.85,146.31) 98.28,146.31 99.73,144.86 v2(102.52,144.86) 102.55,144.88 106.38,144.88 v2(106.59,144.68) ; v2(167.57,74.73) 167.57,76.99 167.23,77.33 v2(167.23,84.2) ; v2(170.77,37.85) 170.77,36.17 171.69,35.26 171.69,23.83 170.49,22.63 v2(170.49,22.61) ; v2(164.09,44.17) 162.92,43 162.92,39.29 v2(162.64,39.01) 162.59,38.96 162.59,36.59 162.92,36.26 162.92,36.25 v2(163.18,35.99) ; v2(127.21,125.02) 129.64,125.02 130.76,123.9 131.17,123.9 136.23,118.85 136.23,118.44 136.51,118.15 136.51,117.52 v2(138.03,116) 138.29,115.75 139.5,115.75 140.55,116.79 143.82,116.79 146.13,114.48 v2(148.32,114.48)
  BOTTOM w0.305: IOBD1.15 171.19,21.55 170.49,22.25 v2(170.49,22.61) ; U6001.7 164.48,43.83 164.14,44.17 v2(164.09,44.17) ; v2(166.55,44.47) 166.55,43.43 166.32,43.2 U6001.10 ; U6001.20 162.98,39.35 v2(162.64,39.01) ; v2(143.67,37.26) 143.67,37.39 143.77,37.49 DM1.199
  BOTTOM w0.356: Q1701.5 97.9,85.75 98.46,86.31 v2(98.46,87.71) ; v2(94.37,85.4) 94.61,85.4 94.97,85.75 Q1701.2
  BOTTOM w0.406: v2(84.54,63.6) 84.04,63.11 72.84,63.11 72.52,63.43 72.52,64.19 72.75,64.42 Q2603.2 ; Q2603.5 75.8,64.42 76.33,64.95 76.33,65.44 ; v2(106.59,144.68) 106.23,144.32 Q1905.5 ; Q1905.2 102.8,144.32 102.52,144.6 v2(102.52,144.86)
  BOTTOM w0.508: 82.58,74.63 82.58,76.44 84.88,78.73 R2123.1 85.44,78.73 85.78,78.39 85.78,76.72 Q2104.G 85.67,75.78 85.91,75.54 86.09,75.54 ; v2(168.41,47.83) 168.41,47.22 v2(167.16,45.98) ; R6517.1 R6520.2 132,26.08 131.68,26.39 131.68,27.53 133.34,29.19 142.07,29.19 142.79,28.46 144.17,28.46 144.86,29.16 146.46,29.16 v2(146.57,29.26) ; v2(167.16,45.98) 168.69,44.45 170.48,44.45 170.97,43.96 170.98,43.96 171.46,43.49 173.16,43.49 173.16,43.48 v2(173.21,43.48) ; v2(167.16,45.98) 166.62,46.52 R6007.2 ; 86.09,75.54 86.82,76.28 86.98,76.46 86.98,78.39 88.09,81.42 89.65,83.93 ; 86.09,75.54 v2(86.09,75.47) ; v2(163.56,46.84) 163.2,46.48 R6014.2 ; R2430.1 165.7,71.87 166.02,72.19 166.02,72.54 v2(166.12,72.65) ; 81.52,75.34 79.83,75.33 78.94,75.04 77.74,74.57 74.73,73.36 v2(73.16,72.9) 72.88,71.53 72.88,67.82 ; v2(160.23,75.34) 160.83,74.74 R2512.1 ; 79.69,73.66 78.77,73.66 78.01,72.9 78.01,71 76.33,69.32 C2602.1 76.33,65.44 ; v2(170.77,37.85) 170.77,38.43 170.33,38.88 R6012.1 ; v2(162.64,39.01) 162.34,38.71 C6012.1 ; R2708.1 151.82,26.6 v2(151.21,25.99) ; R2400.1 R2445.1 153.34,63.27 152.39,62.32 R1922.2 150.73,61.27 C4004.1 151.54,61.27 v2(151.67,61.39) ; v2(138.03,116) v1(137.38,115.36) 136.38,114.35 136.38,112.5 137.01,111.3 137.01,109.59 136.15,108.72 136.15,108.08 136.57,107.55 R2116.1 ; R6005.2 165.73,36.67 165.03,35.97 163.2,35.97 v2(163.18,35.99) R6013.2 ; R6022.1 v2(160.68,46.19) ; DB1.10 161.04,91.98 v2(161.83,91.19)
  vias: v3(29.74,52.4) v3(30.59,52.4) v3(97.87,157.99) v3(98.64,158.42) v3(117.3,181.94) v3(118.4,181.99) v3(121.62,163.68) v3(123.58,163.76)
3D3V_S0_CT: length 2.8
  TOP w0.203: 29.62,51.67 29.4,51.67 29.36,51.63 U4001.12
  TOP w0.254: C4014.1 30.88,51.53 30.74,51.67 v1(30.33,51.67) 29.62,51.67
3D3V_S5: length 833
  TOP w0.508: R2124.1 169.97,79.72 170.54,79.15 v2(170.7,79.15) ; v2(165.82,24.61) 166.06,24.86 R2710.2 ; v2(165.59,60.68) 165.56,60.66 163.66,60.66 162.85,59.84 159.8,59.84 158,58.04 156.65,58.04 155.99,58.7 155.99,59.08 155.38,59.69 v2(153.75,59.69) 153.75,57.99 153.5,57.74 R2473.1 ; R1824.2 106.18,64.44 103.39,61.65 97.28,61.65 95.51,63.43 94.55,63.43 v2(94.17,63.81) 94.67,64.31 96.38,64.31 97.24,64.32 97.84,64.32 98.72,65.19 R1836.1 R1823.1 R1811.2 ; PD4302.2 129.86,163.57 v2(129.83,163.6) 129.45,163.6 129.23,163.82 PR4304.1 ; v2(147.48,28.75) 147.45,28.73 147.45,28.21 148.69,26.98 152.64,26.98 153.63,25.99 161.48,25.99 161.76,25.71 v2(162.41,25.71) ; v2(142.37,150.45) 142.37,148.31 143.85,146.84 145,146.84 R6106.1 145.61,146.88 v2(145.8,146.69) ; R601.2 146.6,83.58 146.61,83.59 150.34,83.59 v2(150.35,83.59) ; v2(169.98,177.83) 169.98,179.25 AFTP6402.1 169.39,181.25 C6401.1 ; v2(71.31,54.79) 78.59,62.08 78.59,65.74 78.98,66.12 78.98,67.69 79.33,68.04 79.33,71.31 82.45,74.42 83.92,74.42 R1605.1 83.94,74.03 84.36,73.61 v2(85.68,73.61) ; 68.54,67.54 68.38,67.39 65.46,67.39 63.41,65.33 63.41,65.03 62.24,63.86 R6327.2 ; PR4473.2 175.15,154.24 174.72,154.68 PR4472.1 174.72,156.83 174.58,156.97 v2(174.58,157.13) ; R2426.1 167.93,48.5 167.7,48.27 v2(167.7,47.96)
  L3 w0.508: v2(172.85,54.49) 172.8,54.43 171.43,54.43 167.7,50.7 v2(167.7,47.96) 167.7,47.25 167.85,47.09 167.85,44.15 167.16,43.46 167.16,38.86 169.7,36.32 169.7,28.36 165.95,24.61 v2(165.82,24.61) 164.83,24.61 163.74,25.71 v2(162.41,25.71) ; v2(151.44,66.68) 152,66.68 152.56,66.12 152.56,64.82 154.69,62.69 154.69,60.78 153.75,59.84 v2(153.75,59.69) ; v2(145.8,146.69) 145.83,146.71 151.24,146.71 152.74,145.21 155.05,145.21 155.94,146.1 155.94,146.89 158.1,149.05 162.85,149.05 164.85,151.06 164.85,152.22 166.61,153.98 168.92,153.98 170.82,155.88 173.34,155.88 v2(174.58,157.13) 175.34,157.89 175.34,173.7 170.96,178.08 170.24,178.08 v2(169.98,177.83) ; v2(103.82,77.62) 103.82,78.06 v2(102.57,79.3) ; v2(105.8,73.05) 105.8,73 104.03,71.23 104.03,69.76 98.61,64.34 94.7,64.34 v2(94.17,63.81) ; v2(165.59,60.68) 164.88,59.97 164.88,58.04 163.27,56.43 163.27,54.78 159.95,51.46 159.95,50.31 158.56,48.92 v2(156.98,48.92) ; v2(68.66,68.38) 66.83,66.55 66.83,64.12 67,63.95 67,62.32 66.99,62.3 66.99,60.11 67.16,59.93 67.16,54.94 v2(67.14,54.92)
  L4 w0.508: v3(25.71,53.06) 24.62,51.97 24.62,36.76 25.15,36.22 51.82,36.22 60.31,44.71 62.87,44.71 63.73,45.57 75.35,45.57 76.23,44.68 76.23,33.22 80.31,29.14 101.2,29.14 101.86,29.8 105.85,29.8 106.61,29.03 120.45,29.03 121.19,29.77 134.47,29.77 136,28.25 v2(137.87,28.25) 138.39,28.25 139.2,29.06 141.79,29.06 142.43,28.42 144.25,28.42 144.46,28.63 147.35,28.63 v2(147.48,28.75) ; v2(150.35,83.59) 150.46,83.48 150.46,77.73 148.59,75.86 148.59,72.3 152.03,68.86 152.03,67.1 151.6,66.68 v2(151.44,66.68) ; 170.7,79.17 170.7,86.29 172.27,87.86 172.27,95.79 173.49,97 173.49,124.61 175.09,126.21 175.09,134.07 175.92,134.89 175.92,151.07 174.4,152.58 174.4,156.95 v2(174.58,157.13) ; 170.7,79.17 v2(170.7,79.15) ; 170.7,79.17 173.79,76.08 173.79,74.09 173.54,73.84 173.54,66.11 173.61,66.04 173.61,65.65 173.61,63.2 173.67,63.14 173.67,61.18 173.62,61.13 173.62,58.58 173.69,58.51 173.69,58.47 173.69,55.86 172.85,55.02 v2(172.85,54.49) ; v3(26.68,53.09) 26.68,61.6 v2(27.52,62.44) 28.56,63.48 v2(37.17,63.48) 37.78,62.87 40.7,62.87 41.78,61.79 46.97,61.79 50.4,58.36 50.4,58.31 51.41,57.3 51.96,57.3 52.78,56.48 64.46,56.48 66.02,54.92 v2(67.14,54.92) 67.27,54.79 v2(71.31,54.79) 81.59,54.79 87.02,60.21 88.59,60.21 91.89,63.51 93.77,63.51 94.06,63.81 v2(94.17,63.81) ; v2(145.8,146.69) 129.14,146.69 128.05,145.59 100.52,145.59 v2(100.41,145.7)
  BOTTOM w0.305: v2(169.98,177.83) 170.96,178.8 PWR1.1
  BOTTOM w0.356: U4003.5 22.93,62.76 23.38,63.2 25.43,63.2 26.13,62.49 U4004.5 26.86,61.78 v2(27.52,62.44) ; 93.34,92.5 93.96,92.86 U1801.5 94.71,93.18 94.88,93.35 97.29,93.35 97.72,92.92 97.72,90.68 98.14,90.26 R1701.1
  BOTTOM w0.508: R2471.1 153.88,59.72 153.86,59.69 v2(153.75,59.69) ; v2(37.17,63.48) 38.31,63.48 38.84,64.01 38.84,66.09 39.71,66.95 43.19,66.95 44.44,65.71 51.19,65.71 51.57,66.09 59.48,66.09 65.86,72.47 67.54,72.47 68.33,73.26 74.22,75.06 74.59,75.17 77.29,76.3 78.53,76.99 78.73,77.07 79.18,77.27 79.45,77.38 80.21,77.93 82.49,79.2 84.35,80.73 86.29,82.86 87.87,84.79 87.95,84.88 90.26,87.71 90.26,87.71 90.58,88.1 91.13,88.66 92.92,92 93.07,92.19 93.2,92.35 93.34,92.5 ; 90.51,80.55 87.66,77.7 87.66,75.19 86.09,73.61 v2(85.68,73.61) ; U2404.6 150.68,66.26 150.73,66.34 151.06,66.68 v2(151.44,66.68) ; v2(165.59,60.68) 167.58,60.68 172.18,56.08 172.18,54.73 172.42,54.49 v2(172.85,54.49) ; 105.11,74.04 105.11,73.33 105.39,73.05 v2(105.8,73.05) 106.03,72.82 106.03,70.72 105.25,69.94 R1832.1 ; R6525.1 138.68,27.98 138.41,28.25 v2(137.87,28.25) R6521.2 ; v2(129.83,163.6) 129.83,161.7 129.78,161.65 129.78,157.48 133.48,153.77 139.05,153.77 v2(142.37,150.45) ; R2439.1 157.17,49.11 v2(156.98,48.92) ; R1808.2 102.12,79.82 102.12,79.76 v2(102.57,79.3)
  vias: v1(99.35,145.72)
3D3V_TP_S5_R: length 13.8
  BOTTOM w0.381: Q6504.S 135.86,21.02 134.96,21.92 C6503.2 135.33,22.39 135.57,22.64 135.57,23.78 136.61,24.82 136.61,26.52 136.98,26.89 R6521.1 136.57,27.97 v1(134.83,27.97) 132.93,27.97 132.34,27.38 R6520.1
3D3V_USB: length 31.3
  TOP w0.254: v2(142.2,85.17) 143.5,84.22 R601.1 ; C1111.1 v2(128.11,86.13)
  L3 w0.203: v2(128.11,86.13) 128.36,86.37 128.56,86.4 130.01,86.4 130.6,86.49 130.62,86.5 131.73,86.5 131.83,86.4
  L3 w0.254: v2(142.2,85.17) 139.97,87.4 138.44,87.4 138.3,87.54 136.05,87.54 135.93,87.5 134.24,87.5 132.91,86.17 132.07,86.17 131.83,86.4
  L4 w0.254: v2(120.46,86.41) 122.18,86.54 122.24,86.57 124.76,86.57 125.62,86.79 125.97,86.9 126.02,86.92 126.68,87.58 128.07,87.58 128.46,87.2 128.46,86.41 128.18,86.13 v2(128.11,86.13)
  BOTTOM w0.254: CPU1.AK25 128.45,85.99 v2(128.11,86.13) 128.35,86.6 CPU1.AJ25
  vias: v1(119.67,87.17) v2(119.22,87.52)
3D3V_VCCRTC: length 99.6
  L3 w0.508: v2(106.07,98.33) 105.93,98.14 105.93,97.12 101.55,92.74 101.52,92.74 101.22,92.44 97.02,88.24 97.02,81.98 89.85,74.81 88.29,74.81 82.4,68.92 82.4,68.92 82.28,68.79 82.28,67.98 82.23,67.93 82.23,65.96 v2(81.39,65.12)
  L4 w0.254: 108.77,76.58 109.11,76.93 109.86,77.28 111.34,78.75 112.45,79.63 113.4,79.91 114.04,80.08 115.01,80.08 115.15,79.94 115.55,79.94 115.69,80.08 117.32,80.08 118.59,81.35 118.59,81.76 118.65,82.07 118.88,82.3 118.88,82.7 118.61,82.97 118.45,83.44 118.65,85.71 118.67,85.99 v2(118.73,86.57)
  L4 w0.508: 108.77,76.58 106.75,74.56 105.99,74.56 105.23,73.8 104.97,73.28 104.97,72.95 104.99,72.94 104.99,72.28 104.73,71.91 104.73,71.79 104.53,71.59 104.53,70.89 103.49,68.91 101.59,67.12 100.26,65.79 99.8,65.79 98.47,64.45 97.53,64.45 v2(96.73,63.65)
  BOTTOM w0.305: v2(106.07,98.33) v1(106.51,98.68) ; CPU1.AA44 v2(118.73,86.57)
  BOTTOM w0.508: v2(106.07,98.33) C1113.1 R611.2 ; v2(96.73,63.65) 96.25,63.65 95.46,64.44 93.89,64.44 93.19,63.74 90.12,63.74 88.74,65.12 v2(81.39,65.12)
3D3V_WLAN_S0:
  vias: v3(144.74,150.19)
+DC_IN:
  vias: v1(136.61,170.08) v3(135.21,172.09) v3(135.24,171.15) v3(138.39,171.33) v3(139.22,160.76) v3(139.25,161.72) v3(140.14,169.12)
+DC_IN_C:
  vias: v3(125.95,178.51) v3(127.95,178.56) v3(129.98,180.67) v3(129.99,179.45) v3(132.33,180.75) v3(132.34,179.53)
+RTC_PWR: length 7.9
  TOP w0.508: R2527.2 23.35,21.4 AFTP2502.1 v2(23.35,19.05)
  BOTTOM w0.508: v2(23.35,19.05) 23.35,21 RTC1.1
AC_DIS: length 158.7
  TOP w0.102: v2(150.6,171.99) 150.23,172.36 PQ4304.B 150.22,172.9 PQ4306.5 ; v1(164.1,66.25) 164.58,66.73 v2(165.03,66.73)
  L4 w0.102: v2(150.6,171.99) 150.96,171.99 154.67,175.69 169.1,175.69 170.21,174.58 170.58,174.58 172.75,172.41 172.75,159.59 170.9,157.74 170.9,156.87 166.38,152.35 166.38,150.27 163.18,147.07 162.67,147.07 159.24,143.64 159.24,143.28 159.57,142.95 162.03,142.95 162.19,143.11 162.19,143.64 162.39,143.84 163.35,143.84 163.63,143.56 163.63,143.22 164.04,142.81 166.57,142.81 167.39,143.64 169.27,143.64 170.8,142.12 170.8,137.47 166.89,133.56 166.89,133.24 166.89,97.53 164.99,95.64 164.98,95.56 164.98,90.34 164.37,89.74 164.37,87.6 164.53,87.44 164.53,85.76 163.79,85.02 163.79,84.66 163.84,84.61 163.84,83.97 164.02,83.8 164.02,81.48 164.02,81.48 164.02,79.84 164.83,79.02 164.83,72.95 164.9,72.88 164.9,68.39 165.03,68.26 v2(165.03,66.73)
  BOTTOM w0.102: v2(165.03,66.73) 164.66,66.73 164.25,67.13 KBC24.11
AC_IN#: length 142.7
  TOP w0.102: v2(168.71,152.25) 168.74,152.27 168.74,153.55 168.61,153.67 PQ4408.5 167.16,153.67 167.01,153.82 167.01,154.82 v1(166.3,155.53) 166.2,155.63 166.2,156.16 165.48,156.89 PR4425.2 ; v2(157.59,147.42) 156.43,147.42 PR4434.2 155.58,146.93 155.58,147.3 155.98,147.69 PR4433.1 155.98,148.66 PC4401.1 157.23,148.9 158.6,150.26 PU4404.5
  L3 w0.102: v2(157.59,147.42) 157.59,147.78 158.22,148.41 162.85,148.41 165.76,151.33 167.79,151.33 v2(168.71,152.25)
  L4 w0.102: v2(168.71,152.25) 169.5,152.25 169.91,152.66 171.43,152.66 173.77,150.32 173.77,142.39 174.14,142.03 174.14,136.37 169.1,131.33 169.1,93.39 168.56,92.85 168.56,85.19 168.13,84.76 168.13,77.4 168.73,76.8 168.73,72.63 169.35,72.01 169.35,71.17 169.5,71.01 169.5,69.46 169.32,69.27 169.32,62.59 169.96,61.95 169.96,61.59 169.4,61.03 169.4,58.82 168.84,58.26 168.84,57.07 167.72,55.96 167.72,54.52 168.26,53.99 168.26,53.37 169.48,52.15 169.48,50.85 169.91,50.42 v2(169.91,48.29)
  BOTTOM w0.102: R2500.1 v2(169.91,48.29)
AC_IN#_G: length 6.7
  TOP w0.254: PR4312.2 141.59,170.99 141.92,171.33 PR4313.1 142.95,171.85 v1(143.7,172.6) 144,172.9 PQ4306.2
AC_IN_KBC: length 1.6
  TOP w0.102: PQ4306.6 148.39,175.08 TP4301.1
AC_IN_KBC#: length 4.8
  BOTTOM w0.102: KBC24.65 172.65,50.6 171.98,49.93 171.62,49.93 171.36,49.66 v1(171.36,49.46) 171.36,49.23 171.5,49.09 R2462.2
AC_PRESENT: length 107
  TOP w0.102: v1(152.97,59.13) 152.97,59.49 v2(152.76,59.69) ; v2(117.91,81.39) 117.91,82 117.96,82.05 117.96,82.39 117.73,82.63 117.39,82.63 117.33,82.57 116.52,82.27 116.15,82.25 116.15,82.24 115.8,82.24 115.78,82.26 115.69,82.3 114.82,82.56 113.88,82.75 113.33,82.7 112.94,82.55 112.36,82.39 111.68,82.16 111.6,82.13 111,82.1 110.65,82.12 110.54,82.1 110.04,82.07 109.59,81.7 108.95,81.19 106.22,79.03 106.18,79 104.55,79 v2(102.32,76.76)
  L3 w0.102: v2(155.1,92.79) 154.92,92.79 153.08,90.95 152.72,90.95 145.75,83.97 142.69,83.97 140.35,83.97 139.47,84.85 137.91,84.85 136.74,86.02 135.62,86.02 134.08,85.34 133.7,84.96 132.22,84.01 131.33,83.52 130.75,83.4 128.12,83.4 127.49,83.77 127.14,83.79 126.95,83.79 126.37,84.09 124.23,84.09 122.98,83.63 122.93,83.57 121.44,82.96 121.32,82.96 121.17,82.91 121.14,82.9 120.61,82.53 120.45,82.44 118.96,82.44 v2(117.91,81.39)
  L4 w0.102: v2(152.76,59.69) 152.97,59.9 152.97,62.3 152.92,62.35 152.92,62.92 153.32,63.33 153.32,65.71 154.41,66.81 154.41,71.35 155.04,71.98 155.04,75.69 153.19,77.54 153.19,82.95 154.38,84.13 154.38,86.46 154.39,86.48 155.56,87.64 155.56,90.38 155.1,90.83 v2(155.1,92.79)
  BOTTOM w0.102: v2(102.32,76.76) 102.47,76.61 102.47,74.58 103.27,73.78 R1813.1 103.9,73.79 RN1803.3 ; R2505.2 153.96,60.61 153.88,60.53 153.73,60.53 152.89,59.69 v2(152.76,59.69) ; CPU1.AK49 118.15,81.93 117.91,81.69 v2(117.91,81.39)
AC_PRESENT_KBC: length 3.8
  BOTTOM w0.102: R2505.1 155.76,60.61 156.32,60.05 v1(157.03,60.05) 157.31,60.32 KBC24.113
AD+_G_1: length 5.6
  TOP w0.254: PQ4402.5 173.92,155.7 174.1,155.88 174.1,156.11 173.86,156.35 PQ4402.6 173.02,156.37 173.02,156.77 173.2,156.95 173.74,156.95 173.92,157.13 v1(173.92,157.48) 173.92,157.63 173.69,157.86 PR4401.1
AD+_G_2: length 56
  TOP w0.254: PR4401.2 172.13,158.59 v1(171.94,158.78) 171.81,158.78 171.33,158.29 v2(171.33,157.56) ; PU4402.4 146.38,164.83 PR4403.2 146.4,170.4 147.43,171.43 v2(147.43,171.86)
  L4 w0.254: v2(147.43,171.86) 148.55,172.98 151.52,172.98 154.54,176 169.59,176 173.06,172.53 173.06,159.29 v2(171.33,157.56)
AD+_TO_SYS:
  vias: v1(147.53,170)
AD_IA: length 107.3
  TOP w0.102: v2(158.3,145.21) 158.53,145.21 159.04,145.72 PR4422.2 ; v2(159.85,53.72) v1(160.41,53.72)
  L3 w0.127: v2(161.4,123.14) 160.92,123.62 160.92,128.93 159.66,130.19 159.66,140.02 158.3,141.38 v2(158.3,145.21)
  L4 w0.127: v2(159.85,53.72) 158.86,54.71 158.86,56.03 156.51,58.38 156.51,59.03 156.48,59.05 156.48,62.95 157.6,64.07 157.6,70.12 157.6,70.75 158.23,71.37 158.23,76.99 157.78,77.44 157.78,77.7 157.78,77.7 157.78,80.78 157.77,80.79 157.52,81.04 157.38,81.2 157.37,81.21 157.36,81.22 157.36,85.66 158.31,86.61 158.31,87.87 158.31,92.32 158.02,92.61 158.02,93.92 158.5,94.4 158.52,94.4 159.46,95.34 159.46,98.11 162.76,101.41 162.76,112.15 160.92,113.99 160.92,122.66 v2(161.4,123.14)
  BOTTOM w0.102: C2438.2 156.39,50.93 156.39,50.78 156.65,50.52 C2428.2 157.17,51.71 159.04,53.57 159.69,53.57 v2(159.85,53.72) 159.65,53.92 KBC24.97
AD_IA_HW: length 120.1
  TOP w0.102: v2(167.14,136.04) 167.01,136.04 161.75,141.3 154.79,141.3 154.67,141.18 149.51,141.18 148.94,141.74 148.94,146.83 149.84,147.73 149.84,149.43 150.2,149.79 PQ4407.5 ; v2(156.98,56.92) v1(156.98,57.48)
  L4 w0.102: v2(167.14,136.04) 166.45,136.04 163.84,133.43 163.84,131.65 162,129.81 162,125.23 160.68,123.9 160.68,113.89 162.52,112.05 162.52,101.51 159.02,98.01 159.02,97.45 159.02,96.99 157.52,95.49 157.52,92.41 157.82,92.11 157.82,88.08 157.82,86.82 156.87,85.86 156.87,81 156.92,80.94 157.14,80.72 157.15,80.71 157.28,80.58 157.28,77.9 157.28,77.23 157.73,76.78 157.73,71.58 157.11,70.95 157.11,69.91 157.11,64.28 155.99,63.16 155.99,59.03 155.99,58.84 156.01,58.82 156.01,58.17 156.56,57.62 156.88,57.3 156.88,57.03 v2(156.98,56.92)
  BOTTOM w0.102: v2(156.98,56.92) 157.11,57.05 157.56,57.05 157.64,57.12 KBC24.105
AD_IA_HW2: length 99.2
  TOP w0.102: v2(167.75,135.51) 167.75,136.07 167.22,136.6 166.83,136.6 161.53,141.91 157.11,141.91 154.64,144.37 154.64,148.05 154.33,148.37 154.33,149.54 154.08,149.79 PQ4407.2 ; v1(165.09,65.54) v2(165.09,66.1)
  L4 w0.102: v2(165.09,66.1) 165.05,66.1 164.6,66.55 164.6,71.27 164.04,71.83 164.04,72.55 164.42,72.93 164.42,73.21 164.54,73.33 164.54,75.95 164.6,76.01 164.6,76.61 164.54,76.68 164.54,78.99 163.79,79.74 163.79,81.57 163.79,83.7 163.61,83.88 163.61,84.51 163.56,84.56 163.56,85.19 164.31,85.94 164.31,87.34 164.14,87.51 164.14,89.83 164.3,89.99 164.3,95.27 166.66,97.63 166.66,133.65 167.75,134.74 v2(167.75,135.51)
  BOTTOM w0.102: v2(165.09,66.1) 164.32,66.1 163.61,66.81 163.46,66.96 163.45,67 KBC24.9
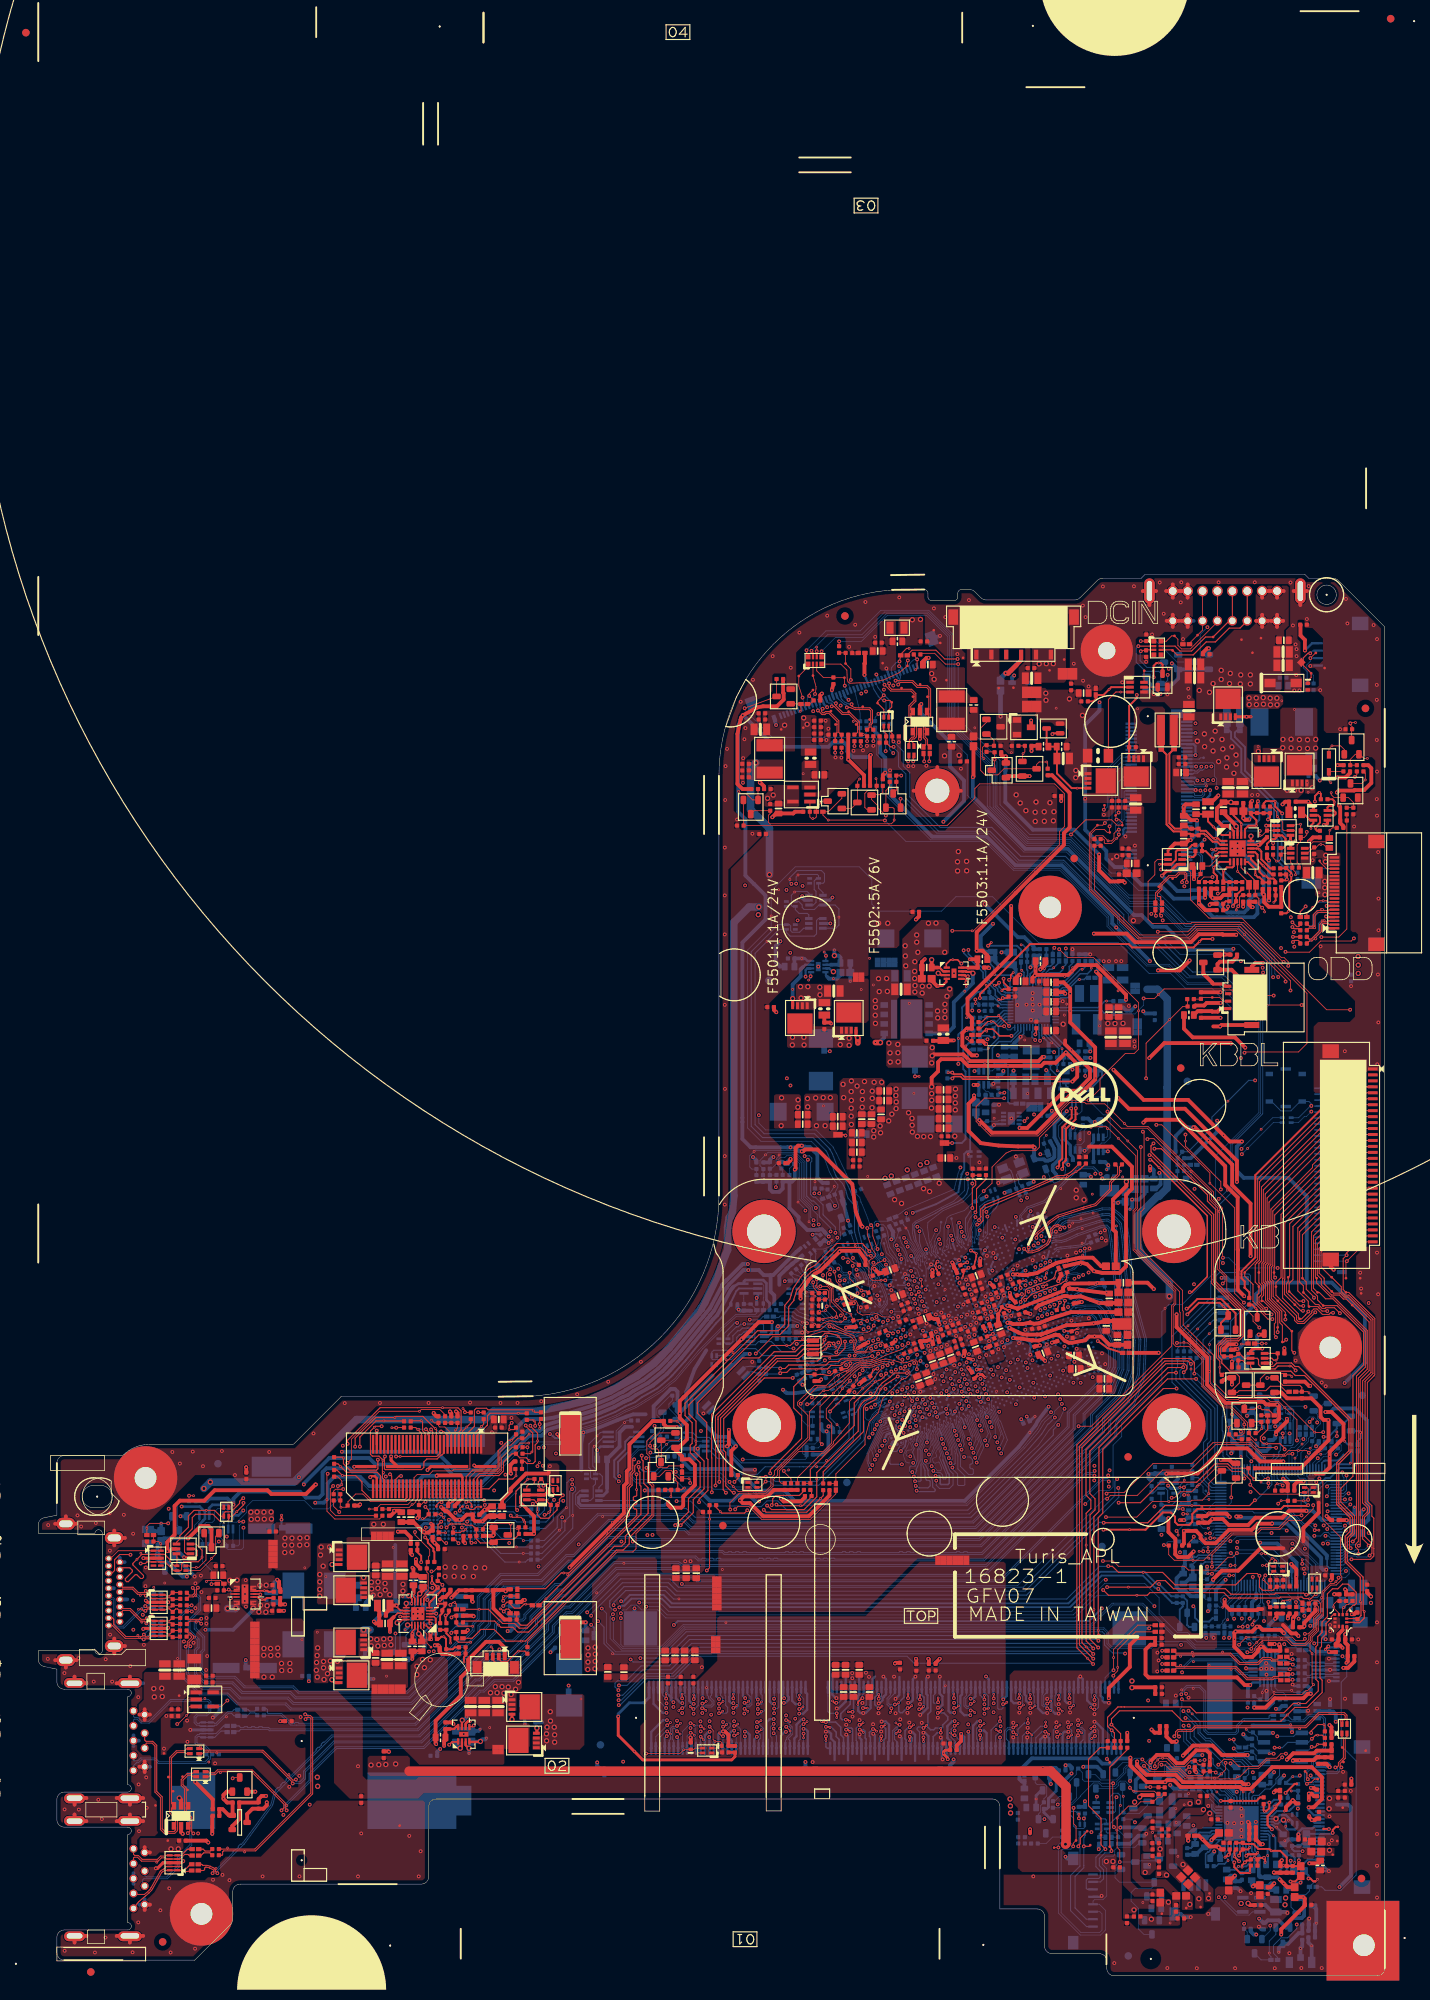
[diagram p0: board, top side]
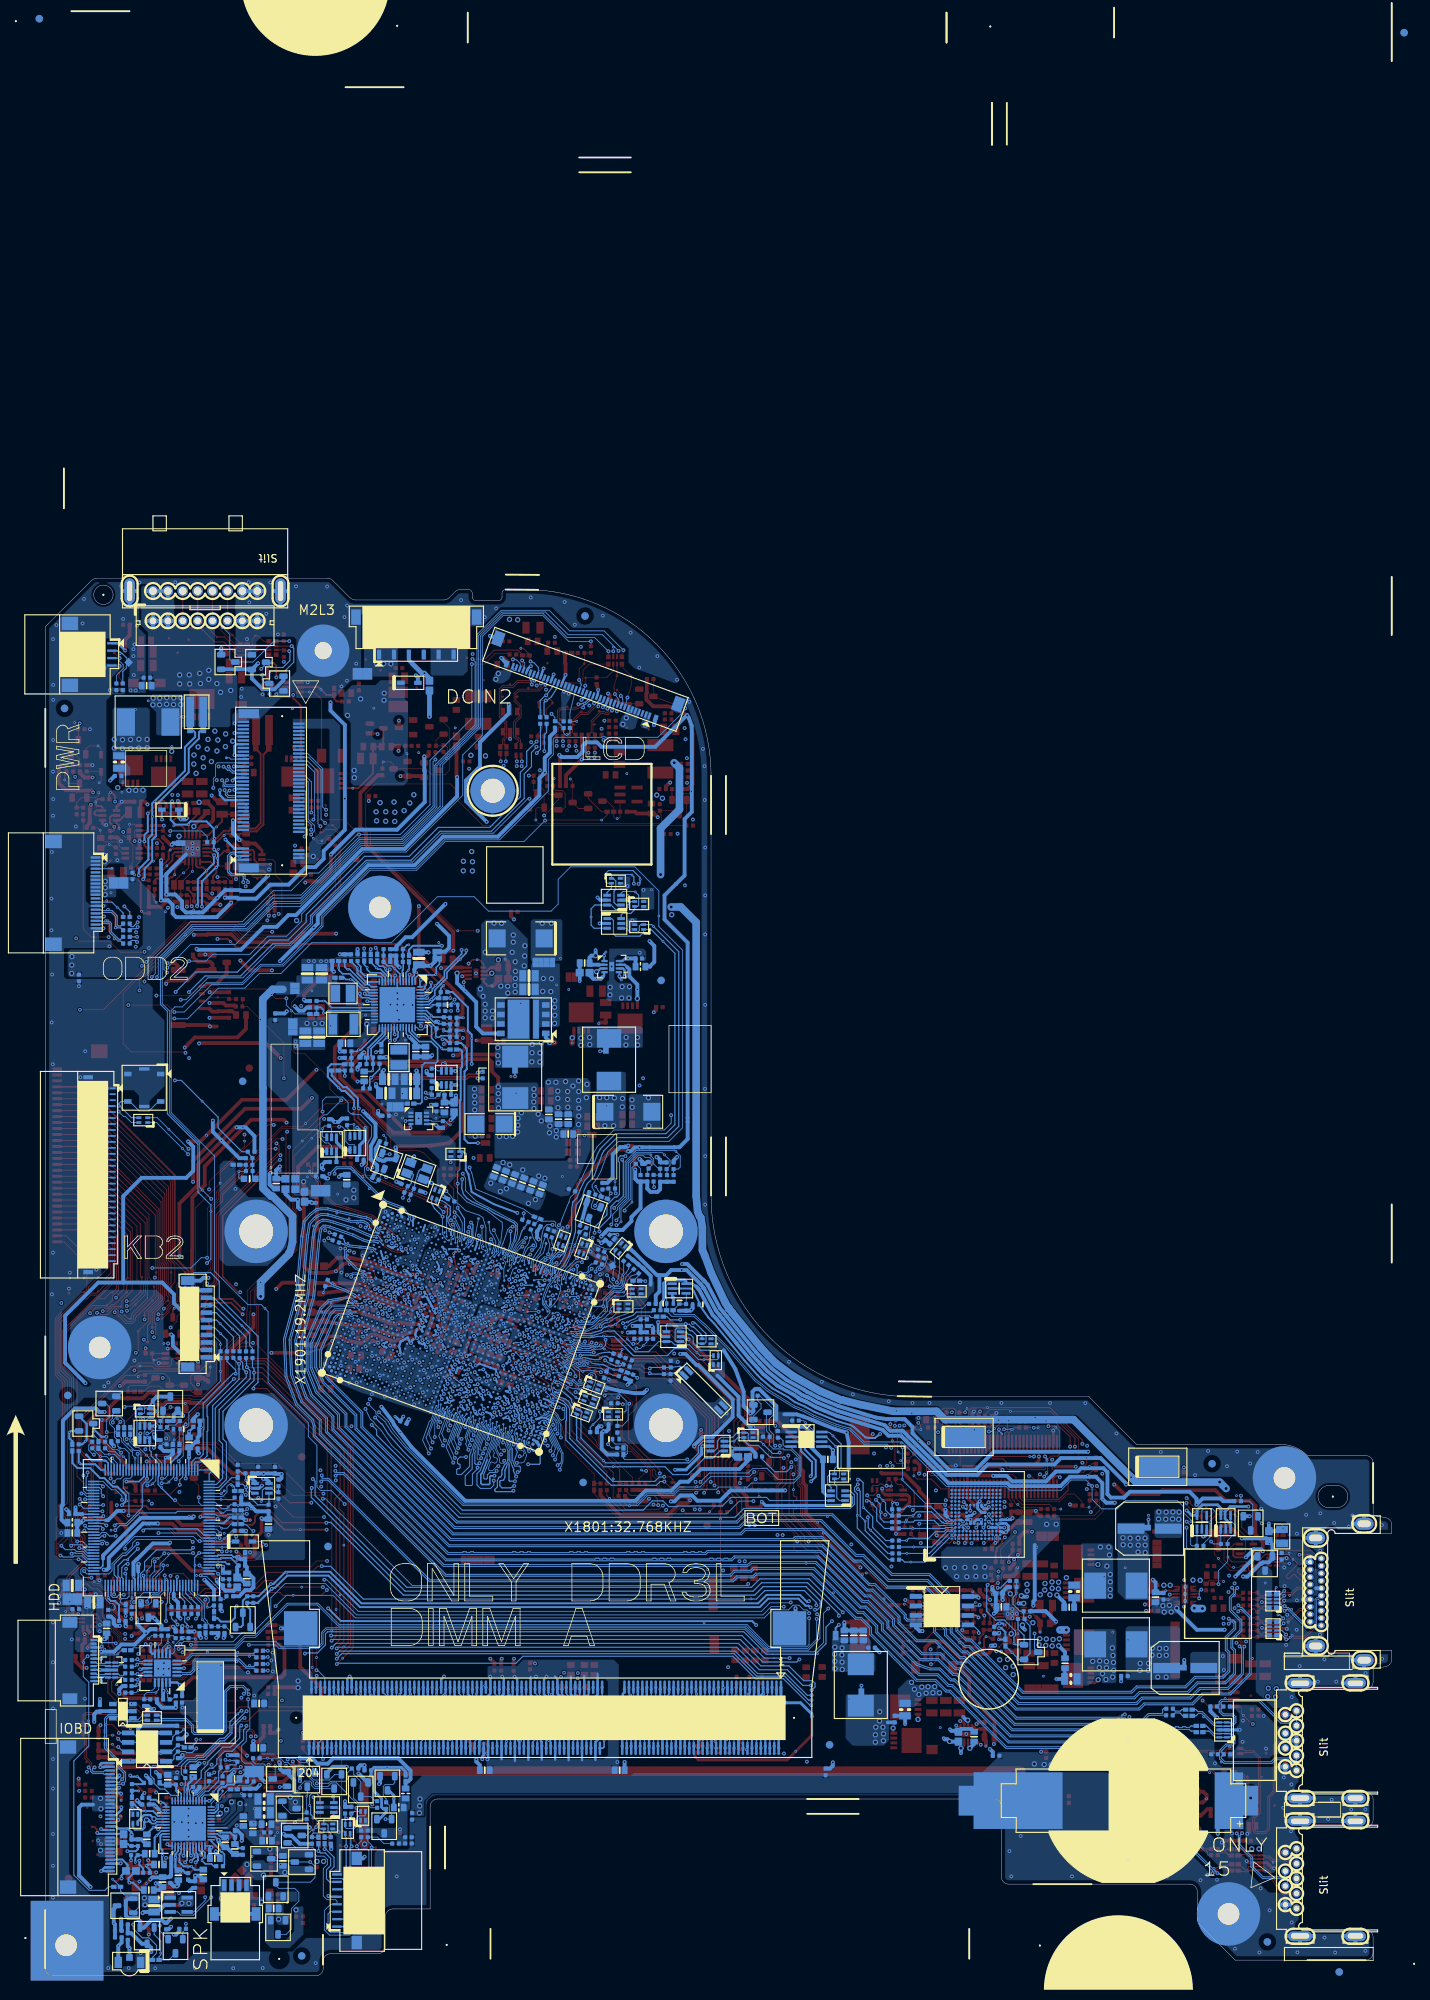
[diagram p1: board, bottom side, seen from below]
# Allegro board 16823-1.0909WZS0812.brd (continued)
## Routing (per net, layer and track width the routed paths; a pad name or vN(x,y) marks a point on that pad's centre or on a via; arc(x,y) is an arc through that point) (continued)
AD_OFF_L: length 22.5
  TOP w0.254: PQ4304.C 150.88,175.92 150.65,176.15 v1(150.38,176.15) 150.07,176.15 149.69,175.77 v2(149.69,174.22) ; v2(136.1,166.6) 136.21,166.71 PQ4305.1
  L4 w0.254: v2(149.69,174.22) 146.95,174.22 145.77,173.04 141.73,173.04 136.1,167.41 v2(136.1,166.6)
AD_OFF_R: length 12.2
  TOP w0.254: PQ4305.3 135.33,165.17 PR4308.1 PR4307.2 136.71,164.9 PC4301.2 136.71,161.33 138.69,159.35 v1(139.43,159.35) PU4301.4
ALERT#: length 5
  BOTTOM w0.102: U2601.6 77.41,71.66 77.55,71.81 77.55,73.1 v1(78.67,74.22) 78.95,74.5 R2605.2
AMBER_LED_BAT: length 4.5
  BOTTOM w0.508: R6407.1 EC6402.1 171.34,6.9 v1(171.51,7.06) 171.51,8.97 Q6403.C
AUD_AGND: length 37.5
  TOP w0.508: v2(160.59,13.44) 159.93,12.78 R2727.1 ; R2725.1 163.16,12.14 v2(163.02,12) ; EC2906.2 EC2908.2 v2(169.12,18.98) ; AFTP6611.1 167.44,22.63 v2(168.36,23.55) 168.38,23.55 168.82,23.12 AFTP2908.1 ; v2(165.82,13.87) 165.86,13.83 EC2905.2 R2917.2 EC2907.2 ; v2(170.58,15.09) 171.79,15.09 172.04,15.34 R6603.1 ; EC2702.1 165.35,11.88 v2(165.87,12.4) ; v2(164.32,17.66) 164.05,17.66 163.44,18.26 EC2703.1 163.41,19.06 EC2705.1 163.42,19.91 EC2706.1 ; v2(157.46,18.21) 158.43,19.18 R2728.1
  BOTTOM w0.203: HDA27.25 164.09,17.43 v2(164.32,17.66) ; v2(157.46,18.21) 157.9,18.65 HDA27.38
  BOTTOM w0.305: v2(169.12,18.98) 169.15,19 169.15,19.28 169.63,19.76 170.97,19.76 171.26,20.05 IOBD1.18 ; v2(170.58,15.09) 170.62,15.05 IOBD1.28
  BOTTOM w0.508: C2713.2 167.14,17.66 167.79,18.3 R2918.2 EC2908.2 v2(169.12,18.98) ; C2721.2 155.14,16.25 C2715.2 155.48,16.36 156.37,17.25 C2712.1 156.6,17.3 156.75,17.3 157.44,17.99 157.44,18.19 v2(157.46,18.21) ; C2705.1 160,13.44 v2(160.59,13.44) EC2704.1 161.32,12.69 R2713.1 ; C2702.1 162.85,12.18 v2(163.02,12) 163.46,12 C2710.2 ; C2901.2 165.36,11.51 C2711.2 165.44,12.4 v2(165.87,12.4) ; R2714.2 167.85,22.99 168.36,23.5 v2(168.36,23.55)
AUD_HP1_JACK_L: length 13.6
  TOP w0.254: v2(161.14,15.37) v1(160.54,15.97) 160.54,15.98 160.54,16.73 R2908.1
  L4 w0.254: v2(168.08,15.45) 167.62,14.99 163.53,14.99 163.25,14.71 161.72,14.71 161.14,15.29 v2(161.14,15.37)
  BOTTOM w0.203: HDA27.32 160.86,16.49 160.69,16.32 160.69,15.83 v2(161.14,15.37)
  BOTTOM w0.254: v2(168.08,15.45) 168.08,14.91 167.56,14.39 R2920.2
AUD_HP1_JACK_L1: length 10.7
  TOP w0.254: R2907.1 169.41,14.72 EC2907.1 R2917.1 167.55,15.9 166.68,16.77 v1(165.46,16.77) 165.21,17.02 163.74,17.02 163.08,17.68 161.82,17.68 R2912.2 R2908.2
AUD_HP1_JACK_R: length 16.8
  TOP w0.254: R2910.1 162.62,14.67 v1(162.62,13.87) 162.54,13.79 161.3,13.79 160.51,14.58 v2(160.51,15.22)
  L4 w0.254: v2(160.51,15.22) 160.51,15.2 161.51,14.2 163.46,14.2 163.74,14.48 168.17,14.48 v2(169.18,15.5)
  BOTTOM w0.203: 160.26,16.31 160.46,16.51 HDA27.33
  BOTTOM w0.254: R2919.2 v2(169.18,15.5) ; 160.26,16.31 160.26,16.06 160.21,16.01 160.21,15.52 v2(160.51,15.22)
AUD_HP1_JACK_R1: length 12
  TOP w0.254: v1(164.65,15.22) 164.65,15.67 v2(164.5,15.83) 163.91,15.83 163.71,15.62 R2913.2 R2910.2
  L4 w0.254: v2(164.5,15.83) 164.52,15.85 165.82,15.85 166.68,16.72 v2(169.68,16.72)
  BOTTOM w0.254: v2(169.68,16.72) 168.56,16.72 168.26,17.02 R2918.1 EC2908.1 169.34,17.41 169.6,17.68 R2909.1
AUD_PC_BEEP_3246: length 5.3
  BOTTOM w0.203: 165.38,21.45 HDA27.16
  BOTTOM w0.254: R2719.1 168.85,23.08 168.1,22.33 168.1,22.33 168.01,22.24 168,22.24 167.86,22.1 v1(167.22,22.1) 166.22,22.1 165.57,21.45 165.38,21.45
AUD_PC_BEEP_C: length 62.3
  L3 w0.254: v2(172.5,72.32) 172.5,71.22 168.97,67.69 168.97,59.01 169.22,58.75 169.22,56.85 169.53,56.54 170.59,56.54 171.3,55.83 171.38,55.76 173.38,55.76 174.18,54.96 174.18,53.98 173.95,53.75 173.95,52.85 173.65,52.55 173.64,52.55 170.42,49.33 170.42,48.08 169.92,47.58 169.76,47.58 168.49,46.31 168.49,43.92 168.89,43.51 168.89,40.52 171.48,37.93 171.48,29.06 v2(169.3,26.88)
  BOTTOM w0.254: D2701.3 174.26,73.42 173.16,72.32 v2(172.5,72.32) ; v2(169.3,26.88) 169.15,26.72 v1(168.36,26.72) 168.3,26.72 R2717.1 167.62,25.72 C2720.1
AUD_PC_BEEP_R: length 1.8
  BOTTOM w0.254: v1(168.16,24.79) 168.19,24.83 C2720.2 R2719.2
AUD_PORTA_L_R_B: length 12.8
  TOP w0.254: R2907.2 168.69,12.65 v2(168.05,12.65) ; v2(173.21,19.69) 173.18,19.71 AFTP6606.1
  L4 w0.254: v2(168.05,12.65) 168.05,13.44 170.77,16.16 170.77,17.25 v2(173.21,19.69)
  BOTTOM w0.254: v2(173.21,19.69) 173.07,19.55 IOBD1.19
AUD_PORTA_R_R_B: length 4.9
  TOP w0.254: v2(173.72,19.18) 173.72,19.58 174.13,19.99 AFTP6608.1
  BOTTOM w0.254: v2(173.72,19.18) 173.59,19.05 IOBD1.20 170.24,19.05 R2909.2
AUD_SENSE: length 20.1
  TOP w0.254: v2(167.39,24.54) 168.61,25.76 AFTP2909.1
  L3 w0.254: v2(169.4,12.5) 168.59,13.31 168.59,15.85 167.83,16.61 167.83,24.11 v2(167.39,24.54)
  BOTTOM w0.254: R2715.2 167.69,24.3 167.44,24.54 v2(167.39,24.54) ; C2901.1 167.93,11.51 168.92,12.5 v2(169.4,12.5) 169.53,12.63 169.53,13.08 R2914.2
AUD_SENSE_A: length 5.6
  TOP w0.254: v2(165.21,23.24) 165.21,22.48 164.8,22.07 v1(164.57,22.07) 164.45,22.2 R2711.2
  BOTTOM w0.203: v2(165.21,23.24) 164.83,23.24 164.49,22.9 HDA27.13
  BOTTOM w0.254: v2(165.21,23.24) 165.46,23.24 165.84,23.62 166.54,23.62 R2715.1
AUD_SPK_L+:
  vias: v1(152.66,22.43) v3(154.57,23.12)
AUD_SPK_L+_C:
  vias: v3(154.54,9.58)
AUD_SPK_L+_R:
  vias: v1(151.9,7.09) v3(149.38,7.6)
AUD_SPK_L-:
  vias: v1(154.36,24.44) v3(155.7,23.32)
AUD_SPK_L-_C:
  vias: v3(151.67,9.88)
AUD_SPK_L-_R:
  vias: v1(148.24,9.83) v3(147.05,8.84)
AUD_SPK_R+:
  vias: v1(152.94,16.03) v3(151.42,13.52) v3(153.63,14.94) v3(157.21,21.8)
AUD_SPK_R+_C:
  vias: v3(157.06,10.39)
AUD_SPK_R+_R:
  vias: v1(149.13,14.94) v3(148.55,13.87)
AUD_SPK_R-:
  vias: v1(152.71,20.58) v3(156.37,22.3)
AUD_SPK_R-_C:
  vias: v3(155.76,10.34)
AUD_SPK_R-_R:
  vias: v1(149.89,18.75) v3(150.55,17.02)
AUD_VREF: length 5.9
  BOTTOM w0.203: HDA27.28 162.46,16.55 162.69,16.31 162.69,15.39
  BOTTOM w0.254: C2705.2 159.52,14.23 160.61,14.23 v1(161.07,14.68) 162.12,14.68 162.69,15.26 162.69,15.39
AVS_DMIC_CLK: length 70.3
  BOTTOM w0.102: 111.84,94.49 112.05,94.11 112.15,94.08 112.27,94 112.31,93.84 112.31,93.76 112.3,93.7 112.29,93.65 112.29,93.52 112.34,93.44 112.4,93.38 112.53,93.27 112.59,93.08 113.04,92.64 113.16,92.38 113.6,91.29 113.8,90.53 113.8,90.28 113.7,90.12 113.69,90.11 113.69,90.09 113.67,90.08 113.44,89.74 112.97,89.26 112.97,89.06 113.01,88.92 CPU1.P54
  BOTTOM w0.14: Q1904.4 102.71,140.55 102.18,140.02 101.19,140.02 100.97,140.23 100.97,140.87 100.8,141.04 RN1910.2 99.32,141.04 v1(99.05,140.78) 95.68,137.41 95.68,113.98 97.2,112.47 103.96,112.47 105.74,110.69 105.74,110.68 105.98,110.23 107.03,107.36 107.03,107.35 107.34,106.9 107.94,106.31 107.96,106.27 108.37,105.42 108.49,104.89 108.67,104.37 109.43,103.45 109.44,103.42 109.54,102.78 109.54,99.96 109.57,99.76 110.38,96.84 110.45,96.61 111.2,95.28 111.79,94.69 111.84,94.49
AVS_DMIC_DATA: length 71.8
  BOTTOM w0.102: 111.57,95.76 111.57,95.61 111.91,95.27 112.38,95.27 112.62,95.03 112.62,94.24 112.6,94.19 112.6,94.07 112.63,93.96 112.77,93.84 112.86,93.75 112.88,93.67 112.88,93.57 112.86,93.45 112.86,93.26 113.04,92.93 113.26,92.71 113.72,91.68 113.95,90.82 113.99,90.62 113.99,90.18 113.89,90.03 113.88,90.02 113.82,89.96 CPU1.M54
  BOTTOM w0.14: Q1904.1 104.7,141.85 104.45,141.61 104.45,139.8 104.15,139.5 100.9,139.5 100.4,140 RN1910.1 99.4,140.39 v1(97.8,138.79) 96.2,137.19 96.2,114.2 97.41,112.99 104.18,112.99 106.17,111 106.22,110.95 106.26,110.87 106.26,110.85 106.57,110.31 107.65,107.44 107.78,107.25 108.31,106.72 108.48,106.39 108.85,105.63 108.9,105.49 109.28,104.53 109.35,104.37 109.9,103.82 109.92,103.71 110.06,102.82 110.06,100.27 110.09,100 110.09,99.99 110.19,99.59 110.65,97.75 110.88,96.97 110.91,96.92 111,96.66 111.44,95.89 111.44,95.89 111.57,95.76
BAT_AMBER: length 3.5
  BOTTOM w0.508: LED1.1 v1(170.9,4.02) 170.45,4.46 R6407.2
BAT_WHITE: length 2.5
  BOTTOM w0.508: LED1.2 v1(169.4,3.66) 169.4,3.74 169.63,3.96 R6406.2
BATT_WHITE_LED#: length 85.1
  TOP w0.127: v1(171.86,59.79) v2(171.3,59.79)
  L3 w0.127: v2(168.89,6.89) 175.57,13.57 175.57,36 172.64,38.93 172.64,42.91 172.24,43.31 172.24,47.96 174.94,50.65 174.94,52.03 175.28,52.38 176.16,52.38 176.69,52.91 176.69,56.24 176.36,56.56 175.68,56.56 175.2,57.04 174.57,57.04 174.56,57.05 173.47,57.05 173.45,57.04 172.03,57.04 172.01,57.05 171.97,57.05 171.47,57.55 171.47,58.62 171.7,58.85 171.7,59.4 v2(171.3,59.79)
  BOTTOM w0.127: v2(168.89,6.89) 168.89,6.32 167.67,5.09 166.77,5.09 165.77,4.09 165.77,3.02 166.31,2.48 R6404.1 ; KBC24.118 162.96,62.32 163.18,62.11 168.05,62.11 169.75,60.4 170.7,60.4 v2(171.3,59.79)
BATT_WHITE_LED_R#: length 7.4
  BOTTOM w0.127: Q6401.D 164.1,2.14 R6404.2 165.42,2.58 165.21,2.8 v1(165.21,3.05) 165.21,4.68 166.09,5.55 Q6404.B
BEEP: length 5.5
  BOTTOM w0.203: 173.44,68.07 173.24,67.87 KBC24.32
  BOTTOM w0.254: 173.44,68.07 174,68.63 175.93,68.63 v1(176.08,68.79) 176.21,68.91 R2730.1
BKLGT_PWM: length 105
  TOP w0.508: v2(160.79,61.62) v1(161.4,61.62) ; R6505.1 160.88,136.69 160.26,136.07 158.58,136.07 158.26,135.75 Q6501.G 160.15,134.98 161.6,133.53 164.17,133.53 164.47,133.23 v2(164.47,133.1)
  L4 w0.508: v2(160.79,61.62) 160.77,61.62 159.43,62.97 159.43,77.46 159.05,77.84 159.05,81.22 158.54,81.73 158.54,85.17 158.8,85.43 158.8,85.43 159.6,86.22 159.6,94.24 160.33,94.98 160.33,97.47 163.63,100.78 163.63,112.51 162.1,114.05 162.1,121.21 162.62,121.73 162.62,129.64 164.47,131.5 v2(164.47,133.1)
  BOTTOM w0.203: KBC24.62 173.26,54.72 172.97,55.02 172.97,55.94 172.94,55.98
  BOTTOM w0.508: 172.94,55.98 172.94,56.4 167.89,61.44 160.97,61.44 v2(160.79,61.62)
BKLT_CTRL: length 32.2
  TOP w0.102: D5502.3 115.16,159.06 R5510.1 R5526.2 v2(115.81,161.04) ; v1(104.45,178.28) 104.47,178.26 v2(104.47,177.72) RN5501.6
  L3 w0.127: v2(104.47,177.72) 104.47,175.74 103.02,174.28 103.02,169.56 104.6,167.97 104.6,163.6 105.53,162.68 114.17,162.68 v2(115.81,161.04)
BLON_OUT_C: length 6.3
  TOP w0.102: R5519.2 108.34,177.51 R5501.2 108.35,176.09 AFTP5516.1 108.49,175.92 109.05,175.33 v2(109.05,173.87)
  BOTTOM w0.102: v2(109.05,173.87) 108.79,173.32 108.77,173.2 LCD1.21
BLUETOOTH_EN_KBC: length 145.7
  TOP w0.102: v2(168.79,50.14) 168.82,50.12 R2472.2 ; v2(143.77,154.23) 143.77,153.44 AFTP6108.1 143.47,153.42 143.09,153.8 141.88,153.8 141.28,153.2 141.28,145.76 147.7,139.35 154.41,139.35 155.53,140.46 161.12,140.46 v1(161.91,139.68) 161.91,139.65 168.05,133.5 v2(168.05,132.21)
  L4 w0.102: v2(168.79,50.14) 168.79,51.82 167,53.61 167,64.63 166.56,65.08 166.56,73.88 165.84,74.59 165.84,81.65 165.89,81.7 165.89,82.71 165.67,82.94 165.67,86.87 166.53,87.74 166.53,89.72 167.29,90.49 167.29,92.93 167.29,93.34 167.85,93.9 167.85,132.01 v2(168.05,132.21)
  BOTTOM w0.102: KBC24.83 165.45,51.57 165.59,51.44 167.49,51.44 v2(168.79,50.14) ; v2(143.77,154.23) 144.1,154.56 144.1,161.61 145.49,163 WLAN1.54
BOARD_ID2: length 19.3
  L4 w0.102: v2(101.35,84.18) 101.35,84.97 101.61,85.22 102.4,85.22 103.45,86.27 103.45,86.34 105.71,88.59 106.18,88.78 107.3,88.78 107.73,89.21 112.82,89.21 113.94,88.09 v2(114.01,87.94)
  BOTTOM w0.102: v2(101.35,84.18) 100.82,84.18 v1(100.45,84.55) 99.96,85.04 R2029.2 R2028.1 ; v2(114.01,87.94) CPU1.T54
BOOST_MODE#: length 1.9
  TOP w0.254: PR4418.1 166.02,145.79 166.02,145.51 166.06,145.47 PR4435.2 166.06,144.29 v1(165.82,144.05)
BOOT_HALT_N: length 6.7
  TOP w0.102: XDP1.36 50.93,63.99 50.66,63.72 50.66,63.58 50.31,63.24 v1(50.17,63.24) 49.76,62.82 47.27,62.82 R9904.2 R9909.1
BT+: length 21.9
  TOP w0.508: BATT1.1 167.14,185.8 ; BATT1.1 165.36,185.8 ; BATT1.1 166.25,184.91 ; BATT2.2 165.06,181.8 ; BATT2.2 163.44,181.8 ; BATT2.2 164.25,180.99 ; BATT2.2 164.25,182.61 ; 166.25,180.99 BATT2.1 ; BATT2.1 166.25,182.61 ; BATT2.1 165.44,181.8 ; BATT2.1 167.06,181.8 ; 165.14,185.8 BATT1.2 164.25,184.91
  BOTTOM w0.508: 163.44,181.8 BATT2.2 ; BATT2.2 165.06,181.8 ; BATT2.2 164.25,180.99 ; BATT2.2 164.25,182.61 ; 165.44,181.8 BATT2.1 ; BATT2.1 166.25,180.99 ; BATT2.1 167.06,181.8 ; BATT2.1 166.25,182.61 ; 165.14,185.8 BATT1.2 164.25,184.91 ; BATT1.1 167.14,185.8 ; BATT1.1 165.36,185.8 ; BATT1.1 166.25,184.91
  vias: v3(155.81,172.47) v3(157.18,172.21) v3(157.67,173.38) v3(158.76,175.16) v3(158.76,173.94) v3(159.87,173.38) v3(159.98,174.75) v3(161.32,173.33) v3(161.37,174.55) v3(162.67,174.55) v3(162.67,173.33)
BT+_R:
  vias: v1(166.89,171.07) v3(162.49,171.45) v3(162.52,170.56) v3(163.46,171.45) v3(163.48,170.56) v3(164.4,171.5) v3(164.42,170.61) v3(165.34,171.43) v3(165.36,170.54) v3(166.22,171.43) v3(166.25,170.54)
BT+_R_1:
  vias: v1(170.29,160.07)
BT_USB20_N: length 63.2
  TOP w0.127: ER6103.2 149.92,142.3 v2(149.99,142.23)
  L3 w0.114: v2(149.99,142.23) 150.14,142.08 150.14,141.29 153.23,138.19 153.23,136.29 153.95,135.57 153.95,113.85 154.44,113.36 154.44,106.5 145.41,97.47 141.47,95.41 141.19,95.26 141.16,95.25 140.08,94.89 140.06,94.88 140.04,94.87 139.42,94.54 139.38,94.52 138.56,94.2 138.56,94.2 137.63,93.49 137.59,93.45 137.31,92.92 137.07,92.74 136.97,92.7 136.71,92.66 136.71,92.66 136.61,92.64 136.6,92.64 136.27,92.57 136.11,92.41 136.08,92.37 v2(135.8,91.88)
  BOTTOM w0.127: CPU1.AB7 v2(135.8,91.88)
BT_USB20_P: length 63.1
  TOP w0.127: ER6102.2 150.81,142.85 150.52,142.56 150.52,142.42 v2(150.71,142.23)
  L3 w0.114: v2(150.71,142.23) 150.61,142.23 150.37,141.98 150.37,141.38 153.46,138.29 153.46,136.38 154.18,135.66 154.18,113.94 154.67,113.46 154.67,106.4 145.55,97.28 141.26,95.04 141.1,94.99 140.15,94.67 139.48,94.31 138.68,94 138.65,93.98 138.52,93.88 137.78,93.31 137.78,93.31 137.65,93.07 137.61,92.99 137.48,92.77 137.19,92.53 137.15,92.52 137.02,92.48 136.75,92.43 136.75,92.43 136.65,92.42 136.54,92.39 136.45,92.31 v2(136.45,92.13)
  BOTTOM w0.127: v2(136.45,92.13) 136.39,92.08 136.19,92.08 135.97,92.3 CPU1.AB6
BVCCRTC_EXTPAD: length 3.6
  TOP w0.102: C1805.1 115.55,83.24 v1(115.3,83.03) 115.3,82.97 115.45,82.76 v2(115.97,82.65)
  BOTTOM w0.102: v2(115.97,82.65) 115.97,82.97 115.9,83.03 115.9,83.29 116.08,83.47 116.63,83.47 116.69,83.4 CPU1.AG51
CAMERA_DET#: length 203.6
  TOP w0.127: R2018.2 93.9,66.74 v2(93.43,66.27) ; v2(123.38,176.68) 121.65,176.68 120.47,177.87 117.27,177.87 116.63,177.23 R5505.2
  L3 w0.127: v2(115.31,84.39) 116.34,83.35 117.01,83.35 117.05,83.31 117.6,82.89 118.15,82.89 118.21,82.95 118.58,82.95 118.63,82.89 119.05,82.83 120.28,82.83 120.3,82.85 121.28,83.2 121.39,83.2 122.69,83.74 122.75,83.8 124.29,84.37 124.54,84.37 126.25,84.66 127.56,84.66 127.85,84.43 128.56,83.72 128.64,83.65 130.21,83.65 131.17,83.8 132.15,84.33 133.47,85.19 133.73,85.45 134.23,85.67 135.26,86.26 136.84,86.26 138.01,85.09 139.75,85.09 140.63,84.22 141.8,84.22 143.34,84.22 143.6,84.48 150.87,91.74 152.28,91.74 153.31,91.74 157.2,95.63 v2(158.99,95.63)
  L4 w0.127: v2(115.31,84.39) 115.27,84.39 115.15,84.5 114.76,84.57 114.35,84.57 113.47,84.27 113.17,84.16 112.44,83.87 112.28,83.81 109.78,82.8 109.02,82.69 108.55,82.69 108.54,82.68 107.41,81.56 107.11,81.1 107.11,80.93 107.08,80.9 107.08,80.61 106.52,80.05 106.41,80.05 105.06,78.01 105,77.95 104.87,77.73 104.87,77 104.31,76.44 103.82,75.69 103.63,75.5 103.6,75.45 103.6,75.3 102.97,74.67 102.97,74.08 102.59,72.61 102.59,71.73 99.31,68.44 97.38,68.44 96.27,67.34 94.81,67.34 93.72,66.25 93.45,66.25 v2(93.43,66.27)
  BOTTOM w0.127: v2(158.99,95.63) 158.48,96.14 v1(158.48,102.57) 158.48,103.43 160.22,105.17 160.22,111.56 164.32,115.66 164.32,129.42 165.25,130.34 165.25,136.47 160.93,140.78 153.99,140.78 150.17,144.6 146.4,144.6 138.56,152.44 132.83,152.44 128.42,156.86 128.42,162.42 123.01,167.83 123.01,176.32 v2(123.38,176.68) ; CPU1.AB54 v2(115.31,84.39)
CAMERA_DET#_R: length 4.9
  TOP w0.127: v2(115.58,176.35) R5505.1 115.74,177.32 116.53,178.11 v1(116.87,178.11)
  BOTTOM w0.127: v2(115.58,176.35) 115.07,176.15 114.54,175.56 114.46,175.14 LCD1.33
CAP_LED: length 39.3
  TOP w0.254: R6506.2 162.52,91.72 AFTP6532.1 161.91,93.16 161.48,93.59 161.48,94.54 163.33,96.4 163.33,107.43 172.55,116.65 v2(172.55,116.69) 175.14,119.28 KB1.4
  BOTTOM w0.254: KB2.4 v2(172.55,116.69)
CAP_LED#: length 35.3
  TOP w0.102: v1(164.78,84.84) v2(164.22,84.84) R6508.1
  L4 w0.102: v2(165.51,59.41) 165.16,59.77 165.16,65.55 165.52,65.92 165.52,68.09 165.13,68.48 165.13,73.15 165.06,73.23 165.06,79.11 164.24,79.93 164.24,81.38 164.24,83.52 164.7,83.97 164.7,84.33 164.22,84.81 v2(164.22,84.84)
  BOTTOM w0.102: v2(165.51,59.41) 160.43,59.41 159.75,58.72 KBC24.109
CAP_LED_Q: length 2.4
  TOP w0.254: R6506.1 162.89,90.06 v1(163.39,89.56) 163.58,89.37 Q6502.C
CAP_LED_R#: length 2.4
  TOP w0.102: Q6502.B 162.35,85.88 R6508.2 162.28,84.76 v1(161.45,84.76)
CARD1_USB20_N: length 99.8
  TOP w0.127: v1(169.27,33.15) 169.27,33.29 ; 169.27,33.29 170.13,33.29 171.91,35.07 175.19,35.07 175.39,34.87 175.39,34.47 175.26,34.34 175.04,34.34 174.95,34.26 EL6602.2 ; 169.27,33.29 155.33,33.29 154.86,32.81 153.04,32.81 152.86,32.63 152.86,32.34 v2(153.1,32.11)
  L4 w0.114: v2(153.1,32.11) 152.84,32.36 152.84,35.52 146.69,41.67 146.69,48.88 145.63,49.94 145.63,62.95 146.22,63.54 146.22,66.35 142.96,69.6 142.96,77.85 144.13,79.01 144.13,84.39 140.94,87.58 138.8,88.57 138.03,88.57 135.39,87.61 134.69,87.57 133.99,87.74 133.71,87.94 133.65,88.12 133.65,88.12 133.87,88.9 133.88,88.92 133.88,88.94 134.02,89.94 134.02,90.63 134.22,91.01 v2(134.45,91.38)
  BOTTOM w0.127: v2(134.45,91.38) 134.35,91.38 134.21,91.24 134.21,90.9 CPU1.AC10
CARD1_USB20_P: length 99.6
  TOP w0.127: v2(152.46,32.13) 152.46,32.14 152.62,32.3 152.62,32.73 152.94,33.05 154.76,33.05 155.23,33.53 168.08,33.53 ; 168.08,33.53 170.03,33.53 171.81,35.31 175.29,35.31 175.63,34.97 EL6602.3 ; 168.08,33.53 v1(168.08,33.68)
  L4 w0.114: v2(152.46,32.13) 152.61,32.28 152.61,35.43 146.46,41.58 146.46,48.79 145.4,49.85 145.4,63.04 145.99,63.64 145.99,66.25 142.74,69.5 142.74,77.94 143.9,79.1 143.9,84.3 140.81,87.39 138.75,88.35 138.07,88.35 135.73,87.49 135.65,87.46 135.44,87.39 134.67,87.34 133.9,87.53 133.52,87.79 133.48,87.9 133.45,87.99 133.42,88.08 133.42,88.15 133.65,88.95 133.65,88.95 133.79,89.96 v2(133.79,91.14)
  BOTTOM w0.127: CPU1.AC12 v2(133.79,91.14)
CBN: length 4.5
  BOTTOM w0.203: C2703.1 158.1,14.71 158.4,15.01 159.21,15.01 v1(159.67,15.47) 159.67,15.62 159.27,16.03 159.27,16.52 159.66,16.92 HDA27.35
CBP: length 4.4
  BOTTOM w0.203: HDA27.37 158.44,18.07 157.28,16.92 157.28,16.82 157.09,16.63 156.97,16.63 156.66,16.32 156.66,14.91 C2703.2
CCD_USB20_N: length 105.9
  TOP w0.127: v2(116.74,162.94) 116.84,163.04 TR5501.3 ; v1(135.34,94.34) 135.16,94.16 v2(135.16,93.62)
  L3 w0.114: v2(135.16,93.62) 134.88,93.73 134.82,93.91 134.84,94.02 134.86,94.07 134.98,94.18 135.27,94.33 139.2,95.93 139.21,95.93 139.21,95.93 139.31,95.96 139.44,96 139.84,96.18 141.78,97.05 141.78,97.05 143.54,97.97 143.84,98.12 144.77,99.03 152.66,106.91 152.66,135.14 148.64,139.16 148.64,141.58 147.36,142.86 142.96,142.86 138.27,147.55 132.23,147.55 123.48,156.31 123.48,159.89 121.49,161.88 118.85,161.88 118.37,162.35 118.37,163.42 117.98,163.81 117.13,163.81 116.87,163.55 116.87,163.08 v2(116.74,162.94)
  BOTTOM w0.127: CPU1.V7 v2(135.16,93.62)
CCD_USB20_P: length 105.5
  TOP w0.127: v2(117.42,162.94) 117.42,163.64 TR5501.2 ; v1(134.02,93.68) 134.32,93.38 v2(134.49,93.38)
  L3 w0.114: v2(117.42,162.94) 117.35,162.94 117.1,163.2 117.1,163.46 117.22,163.58 117.89,163.58 118.14,163.32 118.14,162.26 118.75,161.65 121.39,161.65 123.25,159.79 123.25,156.21 132.14,147.32 138.18,147.32 142.87,142.63 147.26,142.63 148.41,141.48 148.41,139.07 152.43,135.05 152.43,107.01 144.61,99.19 143.71,98.31 141.68,97.25 139.75,96.39 139.36,96.22 139.12,96.14 135.18,94.55 135.17,94.54 134.84,94.37 134.82,94.34 134.67,94.2 134.62,94.09 134.62,94.08 134.58,93.91 134.63,93.75 134.67,93.65 v2(134.49,93.38)
  BOTTOM w0.127: CPU1.V9 134.13,93.75 134.31,93.75 134.49,93.58 v2(134.49,93.38)
CFG0: length 94.4
  TOP w0.14: XDP1.19 54.93,72.51 54.41,73.03 v2(54.06,73.03)
  L4 w0.127: v2(120.89,98.82) 120.94,98.93 120.94,100.23 116.44,104.73 111.71,104.73 110.86,104.73 110.31,105.28 109.95,105.28 109.95,105.28 109.03,105.28 108.4,105.91 104.09,105.91 103.34,105.16 102.33,105.16 100.76,103.58 100.76,101.76 101.07,101.44 101.07,98.36 93.79,91.08 93.79,91.04 93.32,90.56 92.98,90.09 92.74,89.75 92.31,89.15 92.31,89.15 91.89,88.56 91.78,88.41 91.78,88.4 91.71,88.31 91.19,87.18 91.05,86.93 91.05,86.87 91.03,86.82 90.72,86.42 90.42,86.02 90.37,85.95 90.28,85.84 89.99,85.1 83.47,78.58 83.41,78.52 83.32,78.45 83.31,78.45 80.77,76.44 73.84,73.66 72.98,73.34 69.97,71.79 69.91,71.77 63.45,71.77 62.74,71.06 61.62,71.06 61.02,71.66 56.27,71.66 54.9,73.03 v2(54.06,73.03)
  BOTTOM w0.102: v2(120.89,98.82) 120.85,98.75 120.77,98.71 120.6,98.35 120.61,98.33 120.44,97.95 120.73,97.14 CPU1.B33
  BOTTOM w0.14: v2(54.06,73.03) 53.7,73.03 v1(53.3,73.43)
CFG1: length 108.3
  TOP w0.14: v2(46.52,69.68) 46.46,69.61 46.46,68.03 46.57,67.92 51.44,67.92 51.75,68.23 51.75,68.94 52.16,69.35 53.52,69.35 54.04,69.86 54.16,69.86 54.43,70.13 XDP1.21
  L4 w0.127: v2(46.52,69.68) 46.97,69.23 48.37,69.23 48.56,69.43 49.2,70.07 60.23,70.07 60.76,69.53 63.76,69.53 63.91,69.38 71.91,69.38 72.26,69.74 76.75,69.74 78.45,71.44 78.62,71.44 79.21,71.44 80.84,73.08 82.99,73.08 83.74,73.83 83.74,74.1 83.74,75.65 84.79,76.7 84.89,76.8 84.94,76.85 92.15,84.06 92.39,84.3 92.73,85.11 93.42,85.79 93.97,86.35 94.63,86.35 96.01,87.72 96.01,88.97 99.74,92.7 99.74,93.38 103.33,96.98 103.33,101.65 103.76,102.07 104.77,102.07 104.99,102.29 107.92,102.29 108.17,102.54 109.17,102.54 109.73,101.98 112.75,101.98 114.14,100.6 114.76,100.6 115.96,99.4 115.96,99.24 v2(116.19,99.01)
  BOTTOM w0.089: 118.38,95.32 118.38,95.84 118.39,95.89 118.4,95.91 118.4,96.14 118.24,96.31 118.19,96.38 118.14,96.53 118.11,96.62 118.1,96.65 117.94,97.07 117.74,97.34 117.33,98.11 116.63,98.81 v2(116.19,99.01)
  BOTTOM w0.14: v1(46.26,69.17) 46.26,69.42 v2(46.52,69.68)
CFG2: length 101.3
  TOP w0.14: v2(48.01,69.68) 53.48,69.68 53.93,70.13 XDP1.23
  L4 w0.127: v2(116.44,98.43) 116.63,98.88 116.63,99.2 114.98,100.85 114.24,100.85 112.86,102.24 109.83,102.24 109.28,102.79 108.07,102.79 107.82,102.54 104.86,102.54 104.64,102.33 103.65,102.33 103.08,101.76 103.08,97.3 98.98,93.2 98.98,92.3 95.75,89.08 95.75,89.04 95.04,88.33 95.04,87.79 95.19,87.64 95.19,87.27 94.53,86.6 93.87,86.6 93.16,85.9 93.16,85.9 92.48,85.21 92.12,84.39 91.97,84.24 84.76,77.03 84.74,77.01 83.48,75.76 83.48,74.2 83.48,73.93 82.88,73.33 80.74,73.33 79.1,71.69 78.56,71.69 74.87,71.69 73.17,69.99 72.16,69.99 71.8,69.64 64.01,69.64 63.86,69.79 61.03,69.79 60.5,70.32 49.1,70.32 48.46,69.68 v2(48.01,69.68)
  BOTTOM w0.089: CPU1.B39 117.96,96.46 117.92,96.58 117.92,96.59 117.91,96.59 117.9,96.62 117.9,96.63 117.59,97.23 117.08,98 116.76,98.32 116.67,98.32 v2(116.44,98.43)
  BOTTOM w0.14: v2(48.01,69.68) 48.02,69.67 v1(48.57,69.67)
CFG3: length 117.5
  TOP w0.14: XDP1.25 53.43,73.25 51.63,75.05 51.61,75.05 51.6,75.06 48.01,75.06 v1(47.86,74.91) 45.29,74.91 42.53,72.14 v2(42.53,71)
  L4 w0.127: v2(117.97,100.51) 117.67,100.51 116.12,102.06 115.9,102.06 115.61,102.35 114.86,102.35 113.48,103.74 112.12,103.74 112.12,103.74 110.45,103.74 109.9,104.29 109.54,104.29 108.62,104.29 108.11,104.8 105.82,104.8 105.07,104.05 102.63,104.05 101.75,103.17 101.75,102.17 102.06,101.85 102.06,97.95 95,90.88 95,89.9 94.74,89.64 94.74,89.51 94.15,88.93 93.76,88.93 92.83,88 92.83,87.9 92.79,87.86 92.56,87.62 92.56,87.58 92.35,87.19 92.3,87.08 92.3,87.01 92.09,86.59 92.09,86.58 92.08,86.56 92.07,86.55 91.27,85.43 91.12,84.83 84.07,77.78 83.96,77.67 81.79,75.5 78.34,72.46 74.55,72.46 72.88,70.78 69.19,70.78 68.55,70.14 64.23,70.14 64.07,70.3 61.24,70.3 60.64,70.89 45.14,70.89 44.6,71.44 42.97,71.44 v2(42.53,71)
  BOTTOM w0.102: v2(117.97,100.51) 118.2,100.51 118.32,100.45 118.63,100.13 118.8,99.6 119.23,98.42 119.27,98.3 119.3,98.24 119.33,98.21 119.38,98.06 119.38,98.01 119.5,97.7 119.55,97.65 119.55,97.1 CPU1.B35
CFG4: length 95.4
  TOP w0.14: v2(52.71,73.31) 52.93,73.09 XDP1.27
  L4 w0.127: v2(52.71,73.31) 54.62,71.4 60.86,71.4 61.45,70.8 62.84,70.8 63.55,71.52 72.57,71.52 73.61,72.55 74.02,73.46 77.8,74.98 81.1,76.17 83.51,78.26 83.65,78.4 90.32,85.07 90.53,85.75 90.57,85.8 90.64,85.89 91.3,86.76 91.32,86.78 91.32,86.83 91.54,87.27 91.6,87.36 91.62,87.38 91.82,87.82 91.82,87.93 91.9,88.01 91.9,88.09 92,88.18 92.03,88.26 92.03,88.33 92.09,88.41 92.45,88.91 92.45,88.91 92.95,89.61 93.19,89.95 93.51,90.4 94.05,90.93 94.05,90.98 101.32,98.25 101.32,101.55 101.01,101.86 101.01,103.47 102.44,104.9 103.44,104.9 104.19,105.65 108.3,105.65 108.93,105.03 109.85,105.03 109.85,105.02 110.21,105.02 110.76,104.47 111.81,104.47 113.8,104.47 115.18,103.09 117.45,103.09 v2(120.49,100.05)
  BOTTOM w0.089: CPU1.A34 120.16,97.42 119.77,98.49 v2(120.49,100.05)
  BOTTOM w0.14: v2(52.71,73.31) 52.71,73.1 v1(52.31,72.7)
CFG5: length 97.8
  TOP w0.14: XDP1.29 52.43,72.93 v2(52.03,73.33)
  L4 w0.127: v2(52.03,73.33) 52.11,73.33 52.53,73.75 54.63,73.75 56.41,71.97 61.65,71.97 62.29,72.62 66.84,72.62 68.48,73.14 73.59,74.38 80.45,77.2 82.8,79.03 89.26,85.5 89.49,86.16 89.72,86.48 90.55,87.92 90.69,88.14 91.07,88.74 91.86,89.84 92.65,90.93 92.65,90.97 92.75,91.12 100.31,98.67 100.31,101.13 99.99,101.44 99.99,103.05 99.99,103.58 99.99,103.9 102.04,105.95 102.79,105.95 103.05,105.95 103.77,106.67 107.68,106.67 108.72,106.67 109.35,106.04 110.27,106.04 110.27,106.04 110.63,106.04 111.18,105.49 116.86,105.49 121.25,101.1 121.51,101.1 v2(122.1,100.52)
  BOTTOM w0.089: CPU1.B31 121.97,97.46 122.14,97.63 122.19,97.73 122.19,97.88 122.13,98.04 121.96,98.19 121.94,98.67
  BOTTOM w0.102: v2(122.1,100.52) 122.1,98.99 121.94,98.67
  BOTTOM w0.14: v2(52.03,73.33) v1(51.09,73.33)
CFG6: length 111.8
  TOP w0.14: R9924.1 49.04,74.45 v1(46.39,74.45) 45.32,74.45 43.16,72.29 v2(43.16,71)
  L4 w0.127: v2(118.26,99.9) 117.92,99.9 116.01,101.81 115.8,101.81 115.51,102.1 114.76,102.1 113.37,103.48 112.22,103.48 110.35,103.48 109.79,104.03 109.43,104.03 108.52,104.03 108,104.55 105.93,104.55 105.18,103.8 102.74,103.8 102,103.06 102,102.27 102.31,101.96 102.31,97.84 95.25,90.78 95.25,89.8 94.99,89.54 94.99,89.41 94.23,88.65 93.84,88.65 93.09,87.9 93.09,87.79 92.82,87.52 92.56,87.05 92.56,86.97 92.41,86.59 92.36,86.51 92.36,86.51 92.31,86.44 91.52,85.33 91.35,84.7 81.83,75.18 78.44,72.2 78.44,72.2 78.02,72.2 74.66,72.2 72.98,70.53 69.29,70.53 68.66,69.89 64.12,69.89 63.97,70.04 61.14,70.04 60.54,70.64 44.69,70.64 44.33,71 v2(43.16,71)
  BOTTOM w0.089: 118.9,95.6 118.99,95.81 119.24,96.05 119.27,96.22 119.27,96.46 119.1,96.64 118.99,96.84 118.91,97.04 118.88,97.07
  BOTTOM w0.102: 118.9,95.6 119.16,94.9 119.16,93.8 119.1,93.27 ; 118.88,97.07 118.87,97.09 118.82,97.15 118.68,97.33 118.52,97.59 118.43,97.86
  BOTTOM w0.14: 118.43,97.86 118.27,98.42 118.26,98.44 v2(118.26,99.9)
CFG7: length 100.3
  TOP w0.14: v1(47.45,73.54) v2(48.04,73.54) 48.06,73.56 R9919.1
  L4 w0.127: v2(122.5,99.31) 122.54,99.39 122.54,100.71 117.5,105.74 111.28,105.74 110.73,106.29 110.37,106.29 110.37,106.3 109.75,106.3 109.12,106.92 107.57,106.92 103.67,106.92 102.94,106.2 102.68,106.2 101.94,106.2 99.74,104 99.74,101.34 100.05,101.02 100.05,98.78 92.22,90.94 91.73,90.22 91.49,89.85 91.28,89.54 90.86,88.88 90.48,88.28 90.47,88.27 90.28,87.97 90.09,87.69 89.71,86.96 89.34,86.46 88.97,85.56 82.71,79.3 80.37,77.48 78.66,76.74 73.56,74.64 72.25,74.32 68.35,73.37 66.78,72.88 62.19,72.88 61.54,72.23 57.62,72.23 55.84,74 48.51,74 v2(48.04,73.54)
  BOTTOM w0.102: CPU1.B29 122.29,98.38 122.29,98.87 v2(122.5,99.31)
CHG_AGND: length 60.6
  TOP w0.356: 151.92,151.31 151.62,151.01 PQ4407.4 ; PQ4407.1 152.85,149.14 151.95,148.24 151.44,148.24 v2(150.81,147.6)
  TOP w0.508: PC4410.2 153.98,157.18 153.73,156.92 v1(153.73,156.85) PC4403.2 154.08,155.65 154.67,155.07 155.46,155.07 v2(155.51,155.02) ; PC4423.2 PC4420.2 166.8,143.44 165.14,143.44 164.52,144.05 164.52,145.01 v2(164.45,145.09) 164.32,145.21 PR4423.2 ; PR4424.2 PC4422.2 159.86,145.85 PR4413.2 159.06,145.01 158.63,144.58 157.67,144.58 v2(157.61,144.63) 157.39,144.86 PC4412.2 PR4431.2 ; v2(154.64,152.38) 154.41,152.38 153.96,151.92 PC4404.2 152.53,151.92 151.92,151.31
  L3 w0.508: v2(150.81,147.6) 153.35,147.6 154.64,148.9 v2(154.64,152.38)
  BOTTOM w0.508: v2(150.81,147.6) 152.86,145.54 154.42,145.54 154.55,145.67 156.57,145.67 v2(157.61,144.63) 157.61,144.62 159.56,142.67 160.1,142.67 161.13,142.67 161.13,142.67 161.83,142.67 162.34,143.18 162.34,144.17 163.25,145.09 v2(164.45,145.09) 164.45,147.83 161.81,150.47 ; v2(155.51,155.02) 155.51,153.29 154.64,152.43 v2(154.64,152.38)
  vias: v2(160.23,151.26) v2(160.94,151.97) v2(160.94,151.26) v2(160.94,150.55) v2(161.65,151.28)
CHG_AMBER_LED#: length 67.3
  L4 w0.127: v2(171.38,60.42) 171.75,60.06 171.75,57.71 172.07,57.39 172.07,54.32 172.77,53.62 173.62,53.62 174.7,52.54 174.7,44.06 175.03,43.73 v2(175.03,42.88)
  BOTTOM w0.127: v2(175.03,42.88) 175.6,42.3 175.6,40.13 174.86,39.4 v1(174.86,34.19) 174.86,30.84 176.87,28.83 176.87,13.52 174.82,11.47 172.7,11.47 172.23,11.94 R6405.1 ; v2(171.38,60.42) 171.15,60.66 169.86,60.66 167.69,62.83 167.69,65.83 167.29,66.23 166.79,66.23 166.25,66.77 KBC24.16
CHG_AMBER_LED_R#: length 7.4
  BOTTOM w0.127: Q6403.B 168.12,9.22 168.12,10.73 168.25,10.87 170.1,10.87 170.61,11.38 R6405.2 171.62,12.96 v1(171.66,12.96)
CLK_TP_SIO: length 63.4
  TOP w0.14: v2(139.66,21.13) v1(139.66,21.69)
  L4 w0.127: v2(169.96,53.98) 170.2,53.72 171.9,52.03 171.9,47.18 171.09,46.37 170.23,46.37 170.2,46.4 169.65,46.4 169.44,46.61 168.89,46.61 168.41,46.13 168.41,44.01 167.18,42.78 167.18,37.52 164.57,34.92 164.57,33.76 164.26,33.44 164.26,29.92 162.31,27.97 161.67,27.97 158.61,24.91 153.88,24.91 150.18,21.2 146.86,21.2 146.67,21.01 141,21.01 140.66,20.66 140.13,20.66 v2(139.66,21.13)
  BOTTOM w0.14: KBC24.72 169.85,53.87 v2(169.96,53.98) ; RN6503.1 139.79,21 v2(139.66,21.13) 139.66,21.76 EC6503.1 139.52,21.78 139.24,22.06 RN6504.4
CLKRUN#: length 177.4
  TOP w0.14: v2(163.18,66.63) 162.4,67.4 R1921.1 160.22,68.1 159.63,68.69 157.93,68.69 157.34,68.11 157.34,68.1 v1(156.84,67.6) 155.47,66.23 150.66,66.23 147.91,63.48 v2(144.99,63.48)
  L3 w0.127: v2(75.13,47.58) 75.01,47.69 75.01,50.55 72.73,52.83 72.73,56.33 72.08,56.98 72.08,58.07 72.61,58.61 72.61,62.58 74.12,64.09 74.12,66.39 79.11,71.38 80.24,71.38 80.24,71.38 81.26,71.38 81.83,71.95 83.4,71.95 84.77,73.31 84.77,73.42 85.98,74.63 86.77,74.63 87.37,75.24 87.37,76.49 95.65,84.77 95.65,87.87 v2(95.49,88.04)
  L4 w0.127: v2(145.85,43.23) 145.85,48.68 144.9,49.64 144.9,63.38 v2(144.99,63.48)
  BOTTOM w0.14: v2(145.85,43.23) 145.77,43.32 144.18,43.32 143.1,44.4 143.1,45.86 142.79,46.17 86.96,46.17 83.95,43.15 83.1,43.15 77.35,43.15 76.99,43.5 75.93,44.57 75.93,46.78 v2(75.13,47.58) ; v2(95.49,88.04) 95.52,88 96.83,88 97.26,88.44 R1924.1 ; v2(163.18,66.63) 163.05,66.75 KBC24.8
COMBO-GPI: length 2.8
  BOTTOM w0.102: TP2701.1 156.9,24.64 158.44,23.11 HDA27.48
COMP2: length 1.7
  BOTTOM w0.254: v1(124.59,126.82) PC5014.1 PR5019.2
COMP2_P: length 1.8
  BOTTOM w0.254: PR5020.2 PC5016.1 v1(124.59,128.55)
CPVDD: length 7.1
  TOP w0.508: C2714.1 158.72,16.96 158.45,17.22 v2(158.4,17.22) 158.27,17.35 157.21,17.35 v1(156.24,18.32) 155.76,18.8 R2705.2
  BOTTOM w0.203: v2(158.4,17.22) 158.6,17.43 HDA27.36
  BOTTOM w0.508: v2(158.4,17.22) 158.6,17.02 C2701.1
CPVEE: length 2.7
  TOP w0.305: v1(159.27,15.9) v2(159.75,16.23) 159.9,16.39 C2704.2
  BOTTOM w0.203: HDA27.34 160.06,16.85 159.75,16.54 v2(159.75,16.23)
CT#_U4002: length 3.4
  BOTTOM w0.102: U4002.6 128.92,114.79 128.8,114.67 C4033.1 127.02,114.67 126.52,114.18 v1(126.35,114.18)
DAT_TP_SIO: length 67.2
  TOP w0.14: v2(169.63,55.27) v1(169.63,55.83)
  L4 w0.127: v2(169.63,55.27) 169.56,55.27 168.8,54.52 168.8,53.28 169.72,52.36 169.72,50.95 170.35,50.31 170.35,48.1 169.39,47.15 168.54,47.15 167.9,46.51 167.9,44.22 166.67,42.99 166.67,37.73 164.07,35.13 164.07,33.97 163.75,33.65 163.75,30.13 162.1,28.48 161.46,28.48 158.4,25.41 153.67,25.41 149.97,21.71 146.44,21.71 146.25,21.52 140.72,21.52 v2(140.32,21.11)
  BOTTOM w0.14: EC6501.1 140.47,21.26 v2(140.32,21.11) 140.44,20.99 RN6503.2 140.44,19.91 140.29,19.76 139.25,19.76 138.95,20.07 138.95,21.13 138.62,21.47 137.88,21.47 137.73,21.61 RN6504.3 ; v2(169.63,55.27) 169.93,55.27 170.44,54.77 170.44,53.46 170.25,53.28 KBC24.71
DBC_EN: length 308
  TOP w0.102: v2(103.11,177.85) 103.11,177.57 103.32,177.36 RN5501.8
  L3 w0.127: v2(82.74,71.12) 82.74,69.88 81.96,69.11 81.96,69.1 81.46,68.6 81.45,68.6 81.19,68.34 81.19,68.33 81.19,68.33 81.19,67.3 79.33,65.45 79.33,64.2 76.11,60.97 76.11,54.09 78.81,51.39 78.81,49.26 v2(78.19,48.64)
  L4 w0.127: v2(149.79,49.59) 148.92,50.46 148.92,65.84 149.51,66.43 149.51,67.79 148.61,68.69 146.73,70.57 146.43,70.87 146.43,76.63 147.72,77.92 147.72,99.2 152.76,104.24 v2(158.43,104.24)
  BOTTOM w0.102: v2(78.19,48.64) 78.19,48.79 78.5,49.1 78.93,49.1 79.56,49.73 80.33,49.73 80.96,49.1 83.14,49.1 84.22,48.02 139.07,48.02 142.1,51.06 148.33,51.06 v2(149.79,49.59) ; v2(82.74,71.12) 82.94,71.33 82.94,72.62 83.55,73.23 83.55,74.7 83.01,75.24 83.01,76.05 84.81,77.84 R2123.2 85.1,77.19 84.64,76.74 84.64,76.13 85.67,75.1 Q2104.S ; v2(158.43,104.24) v1(159.6,105.42) 159.98,105.79 159.98,111.66 164.04,115.73 164.04,129.48 165.01,130.44 165.01,136.37 160.83,140.54 153.65,140.54 150.07,144.12 146.53,144.12 138.52,152.14 132.79,152.14 128.15,156.78 128.15,162.35 122.77,167.73 122.77,179.95 119.51,183.21 113.07,183.21 110.31,180.46 105.71,180.46 v2(103.11,177.85)
DBC_EN_C: length 65.5
  TOP w0.102: v2(116.75,84.89) 116.71,84.8 115.98,84.08 113.65,83.24 112.71,82.74 112.2,82.56 111.86,82.44 110.95,82.33 110.32,82.35 110.01,82.31 109.63,82.18 109.43,82.02 109.19,81.7 108.77,81.34 108.26,81.1 107.12,80.57 105.77,79.22 104.21,79.22 102.82,77.84 102.79,77.84 101.89,76.94 101.89,76.58 103.28,75.19 103.28,72.22 101.88,70.82 99.69,68.63 98.99,67.93 98.99,67.93 98.81,67.75 98.81,67.26 98.33,66.78 98.33,65.74 97.57,64.98 95.23,64.98 93.94,64.98 v1(93.28,65.64) 92.77,66.14 v2(92.77,66.27)
  BOTTOM w0.102: Q2104.D 83.93,75.45 83.93,73.13 83.48,72.68 R2122.2 83.48,71.19 82.98,70.69 81.64,70.69 81.52,70.56 80.63,70.56 79.53,69.47 79.53,67.18 80.11,66.6 82.35,66.6 83.8,68.05 85.78,68.05 86.37,67.46 91.57,67.46 v2(92.77,66.27) ; CPU1.AC48 117.42,84.99 v2(116.75,84.89)
DBC_EN_R: length 6.4
  TOP w0.102: v2(102.57,171.5) 102.06,173.08 AFTP5513.1 103.32,175.66 RN5501.1
  BOTTOM w0.102: v2(102.57,171.5) LCD1.8
DBG_CFG6: length 4.8
  TOP w0.14: R9924.2 50.06,74.47 v1(51.39,74.47) 51.58,74.29 51.58,73.14 51.93,72.79 XDP1.31
DBG_CFG7: length 3.2
  TOP w0.14: XDP1.33 51.43,72.79 v1(50.93,73.28) 50.65,73.56 R9919.2
DBG_I2C_SCL_LB: length 29
  TOP w0.14: RN1908.2 69.73,65.69 69.63,65.79 68.88,65.79 68.66,66.01 68.38,66.01 68.12,65.75 v2(67.8,65.75) 67.8,66.33 R1912.1 67.11,66.28 67.11,65.69 67.44,65.36 Q1903.3 ; v2(48.68,67.06) 48.42,67.06 47.93,66.57 XDP1.48
  L4 w0.127: v2(67.8,65.75) 66.17,65.75 66.14,65.78 63.44,65.78 62.71,66.51 61.77,67.45 57.5,67.45 56.64,68.32 49.98,68.32 48.73,67.06 v2(48.68,67.06)
  BOTTOM w0.14: v1(67.16,65.71) 67.76,65.71 v2(67.8,65.75)
DBG_I2C_SDA_LB: length 37.8
  TOP w0.14: XDP1.50 47.43,67.06 v2(47.2,67.29) ; Q1903.6 66.52,63.87 66.74,63.65 66.74,63.58 66.99,63.34 v1(66.99,62.28) 66.99,61.85 67.44,61.4 68.52,61.4 69.63,62.51 69.63,63.13 R1911.1 69.93,63.44 69.93,63.93 70.37,64.37 70.37,64.44 v2(70.4,64.47) 69.47,64.47 69.08,64.86 RN1908.1
  L4 w0.127: v2(70.4,64.47) 70.36,64.47 69.98,64.86 68.52,64.86 68.06,64.39 63.33,64.39 62.85,63.91 61.72,63.91 59.42,66.21 49.02,66.21 48.28,66.21 v2(47.2,67.29)
DBG_PMU_PLTRST: length 20.6
  TOP w0.102: v1(44.41,62.63) R9926.1 45.93,63.23 49.59,63.23 50.43,64.07 XDP1.38 50.43,66.83 50.86,67.26 52.47,67.26 52.95,67.74 55.6,67.74 55.75,67.9 57.74,67.9 57.93,68.09 XDP1.7
DBG_PMU_PWRBTN: length 13.9
  TOP w0.102: R9925.2 R9929.2 40.53,62.96 v1(40.62,62.87) 41.3,62.87 C9904.1 41.56,63.13 41.56,63.6 42.6,64.65 43.56,64.65 44.57,63.64 49.39,63.64 49.62,63.87 49.85,64.1 49.85,64.12 49.93,64.2 XDP1.40
DBG_PMU_RSTBTN: length 26.6
  TOP w0.102: v2(51.98,63.6) 51.92,63.55 51.72,63.55 51.33,63.16 C9903.1 51.09,63.71 51.43,64.05 XDP1.34 ; v2(59.85,63.81) 58.71,63.81 58.43,64.08 XDP1.6 58.43,66.65 59.17,67.39 61.75,67.39 62.19,67.83 62.19,68.23 62.19,69.5 63.61,70.92 R9913.2 64.1,70.93 64.65,71.48 v1(65.83,71.48)
  L4 w0.127: v2(59.85,63.81) 59.8,63.81 58.9,64.7 53.08,64.7 v2(51.98,63.6)
DBG_PTI_CLK0: length 118.8
  TOP w0.14: v2(41.51,71.38) 41.51,71.86 45.89,76.23 50.92,76.23 54.15,76.23 54.16,76.23 v1(54.26,76.23) 54.29,76.2 56.34,76.2 56.74,75.8 56.74,73.25 56.43,72.93 XDP1.13
  L4 w0.127: v2(116.49,102.31) 116.16,102.31 115.87,102.61 114.97,102.61 113.58,103.99 112.01,103.99 110.56,103.99 110.01,104.54 109.65,104.54 108.73,104.54 108.21,105.06 105.72,105.06 104.97,104.31 102.53,104.31 101.49,103.27 101.49,102.06 101.81,101.75 101.81,98.05 94.55,90.79 94.55,90.58 93.56,89.59 93.56,89.53 93.45,89.38 93.2,89.04 93.2,88.9 92.82,88.51 92.63,88.25 92.49,87.99 92.49,87.91 92.31,87.73 92.31,87.64 92.13,87.31 92.03,87.11 92.03,87.11 92.03,87.09 91.83,86.68 91.83,86.65 91.77,86.57 91.76,86.56 91.02,85.56 90.85,84.92 83.99,78.06 83.78,77.85 83.71,77.78 80.4,74.88 80.37,74.85 78.23,72.71 74.45,72.71 72.77,71.03 69.08,71.03 68.45,70.4 64.33,70.4 64.18,70.55 61.35,70.55 60.75,71.15 45.55,71.15 45,71.69 41.83,71.69 v2(41.51,71.38)
  BOTTOM w0.14: R2117.2 116.49,101.64 v2(116.49,102.31)
DBG_RSMRST: length 13.3
  TOP w0.14: XDP1.42 49.43,64.15 49.16,63.88 44.69,63.88 43.44,65.14 43.44,66.27 42.59,67.12 v1(40.83,67.12) 40.09,67.86 R9912.1
DBG_TARGET_PRESENT_N: length 4.7
  TOP w0.102: R9930.1 R9905.2 R9917.1 56.27,73.51 v1(56.01,73.26) 55.93,73.17 XDP1.15
DBG_UART_RXD: length 8.7
  TOP w0.14: XDP1.56 45.93,66.68 45.92,66.69 45.92,67.12 45.47,67.57 41.34,67.57 v1(40.59,68.32) 40.21,68.7 R9901.1
DBG_XDP_PRDY#: length 3.8
  TOP w0.14: XDP1.11 56.93,73.05 v1(57.51,73.64) 58.06,74.18 58.06,74.68 R9918.2
DBG_XDP_PREQ#: length 12.2
  TOP w0.14: R9902.1 64.12,72.46 v1(63.51,71.85) 63.12,71.85 62.59,71.32 62.59,71.32 62.32,71.05 62.32,71.05 61.71,70.44 61.71,68.03 61.55,67.87 58.33,67.87 57.43,66.97 XDP1.10
DBG_XDP_TCK: length 9.8
  TOP w0.14: R9916.2 v1(64.42,75.48) 60.62,75.48 60.28,75.14 60.28,73.89 60.22,73.83 60.22,73.83 59.5,73.11 58.93,72.54 XDP1.3
DBG_XDP_TDI: length 3.9
  TOP w0.14: R9922.2 59.77,74.01 59.48,73.71 v1(59.47,73.71) 58.43,72.67 XDP1.5
DBG_XDP_TDO: length 10.8
  TOP w0.14: XDP1.4 58.93,66.72 59.33,67.12 61.83,67.12 62.43,67.73 62.43,68.33 62.43,68.9 63.59,70.06 R9920.1 64.1,70.02 64.62,69.5 65.51,69.5 v1(65.89,69.12)
DBG_XDP_TMS: length 6.4
  TOP w0.14: XDP1.2 60.49,65.34 61.81,66.65 63.69,66.65 v1(64.12,67.08) 64.12,67.91 R9910.1
DBG_XDP_TRST#: length 14.3
  TOP w0.14: R9908.2 66.67,75.61 v1(66.48,75.8) 66.33,75.95 60.36,75.95 60.15,76.15 58.78,76.15 58.53,75.9 58.53,73.72 57.43,72.62 XDP1.9
DC_DET: length 17.9
  TOP w0.102: v2(158.02,27.28) 157.87,27.43 R2733.2 R2929.2 156.39,27.02 156.24,26.88 154.21,26.88 153.22,27.87 152.27,27.87 151.38,28.75 150.55,28.75 150.3,28.5 150.3,27.97 150.02,27.69 149.51,27.69 v1(149.26,27.94) v2(148.17,29.03)
  BOTTOM w0.102: Q2908.B 144.55,27.63 145.55,28.63 146.57,28.63 147.12,29.19 148.01,29.19 v2(148.17,29.03) ; v2(158.02,27.28) 158.29,27.01 R2707.2
DC_IN_D: length 3.3
  TOP w0.254: 169.53,156.11 169.65,156.11 170.37,155.4 170.37,155.4 170.71,155.05 PQ4402.3 171.13,154.66 170.8,154.33 v1(170.8,153.95)
DDI0_RCOMP_N: length 5.3
  BOTTOM w0.089: CPU1.AG2 138.44,90.81 139.07,91.42
  BOTTOM w0.127: 139.07,91.42 139.5,91.62 139.51,91.62 139.96,91.87 139.96,91.87 140.4,92.09 141.51,92.5 141.81,92.61 141.96,92.67 ; 141.96,92.67 142.27,92.78 R801.1 ; 141.96,92.67 v1(141.92,92.79)
DDI0_RCOMP_P: length 5.2
  BOTTOM w0.127: v1(143.39,91.65) 143.11,92.52 142.35,92.55 141.9,92.38 141.9,92.38 141.6,92.27 140.49,91.87 140.07,91.66 139.63,91.42 CPU1.AG1
DDR_DRAMRST#: length 142.6
  TOP w0.102: 88.57,30.55 RN1201.3 ; 88.57,30.55 88.45,30.43 88.45,30.08 88.63,29.9 RN1201.4 ; 88.57,30.55 88.17,30.55 88.01,30.39 ED1202.1 86.68,30.39 v1(86.62,30.33) 86.11,29.82 v2(81.57,29.82)
  L3 w0.127: v2(149.08,31.52) 147.99,31.52 143.77,27.31 139.81,27.31 139.48,27.64 138.44,27.64 138.23,27.43 135.59,27.43 134.92,28.1 132.33,28.1 132.33,28.1 83.29,28.1 v2(81.57,29.82)
  L4 w0.127: v2(125.69,82.01) 126.52,81.64 126.52,81.64 126.93,81.46 129.62,77.47 131.74,74 132.37,72.96 133.66,70.84 138.34,57.58 140.65,49.74 140.65,32.54 141.71,31.47 149.03,31.47 v2(149.08,31.52)
  BOTTOM w0.102: CPU1.AR34 v2(125.69,82.01)
DDR_DRAMRST#_R: length 8.3
  TOP w0.102: v2(90.1,33.43) 90.1,33.42 90.56,32.96 90.56,31.7 v1(90.81,31.45) 91.56,31.45 91.74,31.27 ED1201.1 91.27,30.86 90.96,30.55 RN1201.2
  BOTTOM w0.102: DM1.30 90.67,32.85 90.1,33.42 v2(90.1,33.43)
DFX_MSR_STRAP: length 5
  TOP w0.102: v1(52.79,74.55) 53.16,74.18 R9906.1 53.7,73.81 53.88,73.64 54.57,73.64 55.43,72.77 XDP1.17
DGPU_PWROK: length 2.2
  BOTTOM w0.127: KBC24.124 157.03,64.72 TP2412.1
DIMM1_SA0: length 12.6
  TOP w0.102: v2(144.3,41) v1(144.3,42.7) 144.3,43.79 147.56,47.05 149.27,47.05 149.28,47.04 R1213.2
  BOTTOM w0.102: DM1.197 143.17,40.01 144.15,41 v2(144.3,41)
DIMM1_SA1: length 11.3
  TOP w0.102: v2(144.28,40.26) 144.28,40.34 144.86,40.92 v1(144.86,41.38) 144.86,43.74 147.28,46.15 R1201.2
  BOTTOM w0.102: DM1.201 144.37,39.8 144.28,39.89 v2(144.28,40.26)
DMIC_CLK: length 181.7
  TOP w0.14: RN5502.4 114.12,167.14 114.6,166.66 EC5505.1 114.6,165.78 v2(114.76,165.61)
  L4 w0.127: v2(156.52,28.97) 157.08,29.53 157.08,44.02 156.05,45.05 156.05,46.59 156.19,46.73 156.19,50.46 154.6,52.04 154.6,59.16 154.68,59.24 154.68,63.56 155.89,64.76 155.89,71.44 156.02,71.57 156.02,80.12 155.89,80.26 155.66,80.5 155.66,86.36 156.61,87.32 156.61,91.61 156.32,91.91 156.32,95.99 157.76,97.44 157.76,98.47 161.31,102.01 161.31,106.71 160.97,107.06 160.97,112.53 159.93,113.58 159.93,124.23 161.25,125.55 161.25,130.41 162.84,132.01 v2(163.2,132.01)
  BOTTOM w0.14: v2(114.76,165.61) 114.76,165.61 116.09,164.29 116.09,162.33 116.95,161.47 116.95,158.18 121.04,154.09 127.97,154.09 131.86,150.2 137.85,150.2 145.68,142.37 145.68,141.41 148.11,138.98 150.62,138.98 154.92,134.67 160.53,134.67 v2(163.2,132.01) ; v2(156.52,28.97) 156.44,28.88 v1(155.93,28.88) 155.93,28.88 155.09,28.88 C2722.2 154.92,28.5 155.12,28.3 155.92,28.3 R2723.1
DMIC_CLK_C: length 8.8
  TOP w0.14: v2(113.52,171.12) 114.28,171.12 AFTP5510.1 114.54,170.23 114.12,169.82 RN5502.1
  BOTTOM w0.14: R5534.1 113.76,169.22 113.76,170.88 v2(113.52,171.12) 113.35,171.12 112.8,171.59 112.72,171.69 112.15,172.6 LCD1.27
DMIC_CLK_C#: length 47.2
  L4 w0.127: v2(101.71,146.53) 101.71,147.68 97.33,152.07 97.33,158.25 98.67,159.59 101.74,159.59 108.26,166.11 112.26,166.11 113.72,164.64 v2(113.72,164.31)
  BOTTOM w0.14: v2(101.71,146.53) 101.71,147.45 v1(101.96,147.7) 102.03,147.77 104.56,147.77 104.72,147.61 RN1912.1 104.47,147.24 104.36,147.13 104.36,147.13 104.32,147.09 104.32,147.09 104.13,146.9 104.13,145.76 104.38,145.52 104.38,144.02 104.03,143.67 Q1905.1 ; v2(113.72,164.31) 113.72,166.51 113.42,166.81 R5534.2
DMIC_CLK_D: length 11.5
  BOTTOM w0.14: Q1904.3 107.03,140.55 107.45,140.97 v1(107.45,142.05) 107.45,143.16 106.93,143.67 Q1905.6 104.77,143.67 104.17,143.08 102.78,143.08 102.52,143.33 102.52,143.68 102.06,144.14 RN1911.1
DMIC_CLK_R: length 6.9
  BOTTOM w0.14: HDA27.3 160.06,23.9 159.19,24.77 158.8,24.77 157.44,26.14 157.44,27.43 157.14,27.73 R2723.2 v1(157.14,28.98)
DMIC_DATA: length 183.1
  TOP w0.14: RN5502.3 113.47,166.95 113.79,166.64 EC5504.1 EC2709.2 114.35,164.9 v2(114.79,164.9) ; v1(154.04,27.6) 154.06,27.62 154.06,27.64 v2(154.46,28.04)
  L4 w0.127: v2(161.42,131.98) 160.28,130.84 160.28,126.54 159.23,125.49 159.23,108.47 160.24,107.46 160.24,101.67 157.18,98.6 157.18,97.77 155.81,96.39 155.81,91.68 156.1,91.39 156.1,87.53 154.86,86.28 154.85,86.27 154.85,83.72 155.15,83.42 155.15,81.82 154.41,81.08 154.41,77.68 155.51,76.58 155.51,71.78 154.88,71.15 154.88,64.55 153.16,62.82 153.16,62.45 153.21,62.4 153.21,57.46 153.8,56.87 153.8,51.8 155.46,50.15 155.46,49 155.32,48.86 155.32,42.4 156.02,41.7 156.28,41.44 156.28,33.15 156.28,33.15 156.28,32.42 156.28,32.42 156.28,31.13 154.62,29.47 154.62,28.2 v2(154.46,28.04)
  BOTTOM w0.14: v2(114.79,164.9) 114.79,164.8 115.45,164.14 115.45,162.23 116.43,161.25 116.43,157.97 120.83,153.57 127.72,153.57 131.61,149.68 137.63,149.68 145.08,142.24 145.08,141.28 147.89,138.46 150.17,138.46 154.48,134.15 159.25,134.15 v2(161.42,131.98) ; v2(154.46,28.04) 154.73,27.78 155.57,27.78 155.92,27.43 156.62,27.43 156.9,27.15 R2709.1
DMIC_DATA_C: length 9.1
  TOP w0.14: RN5502.2 113.47,169.92 AFTP5511.1 112.63,170.97 v2(113.47,171.81)
  BOTTOM w0.14: R5535.1 114.28,171.1 113.57,171.81 v2(113.47,171.81) 112.68,172.87 112.31,173.66
DMIC_DATA_C#: length 51
  L4 w0.127: v2(101.07,146.51) 101.07,147.6 96.79,151.88 96.79,158.48 98.41,160.1 101.53,160.1 108.05,166.61 113.48,166.61 114.31,165.79 114.31,164.49 v2(114.74,164.06)
  BOTTOM w0.14: R5535.2 114.24,167.95 114.24,164.56 v2(114.74,164.06) ; Q1905.4 105.32,145.34 104.72,145.94 RN1912.2 105.32,146.59 105.52,146.79 105.52,147.88 105.11,148.29 101.82,148.29 100.87,147.35 v1(100.87,147.09) 100.87,146.71 v2(101.07,146.51)
DMIC_DATA_D: length 7.9
  BOTTOM w0.14: Q1905.3 103.44,145.24 103.18,145.49 101.58,145.49 v1(101.51,145.42) 101.07,144.98 101.07,143.62 101.2,143.49 RN1911.2 101.6,143.05 102.11,142.55 103.21,142.55 103.41,142.34 Q1904.6
DMIC_DATA_R: length 4
  BOTTOM w0.14: R2709.2 156.97,25.87 v1(158.17,24.67) 158.58,24.26 159.34,24.26 159.66,23.94 HDA27.2
DP_HPD0_C: length 4.3
  TOP w0.102: R5518.1 103.58,170.64 R5502.2 104.06,171.13 v2(103.46,171.73) 103.46,172.01 AFTP5515.1
  BOTTOM w0.102: LCD1.9 103.19,170.86 103.19,171.22 103.23,171.5 v2(103.46,171.73)
DP_HPD0_G: length 2.4
  TOP w0.102: Q5503.G 102.32,170.67 R5518.2 102.36,169.76 v1(102.27,169.67)
E51_RX1: length 6.7
  TOP w0.102: v2(144.99,156.09) TP6102.1
  BOTTOM w0.102: v2(144.99,156.09) 144.99,160.2 145.79,161 WLAN1.46
E51_RX2: length 10.4
  TOP w0.102: v2(143.01,156.46) 143.09,156.53 TP6101.1
  BOTTOM w0.102: WLAN1.58 145.49,164 143.47,161.98 143.47,156.82 143.1,156.46 v2(143.01,156.46)
E51_TX1: length 12.5
  TOP w0.102: R6107.2 142.95,152.52 143.06,152.4 143.06,152.03 143.17,151.92 144.03,151.92 v1(144.74,152.63) 145.02,152.91 v2(145.02,153.14)
  BOTTOM w0.102: WLAN1.44 145.72,160.5 145.42,160.2 145.42,155.2 144.58,154.36 144.58,153.59 145.02,153.16 v2(145.02,153.14)
E51_TX2: length 11.3
  TOP w0.102: R6108.2 141.74,152.76 141.94,152.96 142.88,152.96 v1(143.57,152.28) 144.06,152.28 144.37,152.59 144.37,153.28 144.86,153.77 v2(145.02,153.77)
  BOTTOM w0.102: WLAN1.38 145.87,159 145.72,158.85 145.72,155.14 145.02,154.43 v2(145.02,153.77)
E51_TXD: length 129.8
  TOP w0.102: v2(157.29,58.73) 157.79,58.73 157.79,58.73 157.82,58.73 v1(157.85,58.73) ; R6107.1 R6108.1 141.74,145.74 147.82,139.65 154.28,139.65 155.4,140.77 161.3,140.77 162.03,140.03 162.05,140.03 170.26,131.82 170.26,125.1 169.12,123.95 161.98,123.95 v2(161.88,123.85)
  L4 w0.102: v2(161.88,123.85) 161.88,121.97 161.4,121.49 161.4,113.95 163.08,112.28 163.08,101.01 159.77,97.71 159.77,95.21 158.65,94.08 158.63,94.08 158.34,93.79 158.34,92.75 158.63,92.45 158.63,87.74 158.63,86.48 157.68,85.53 157.68,81.34 157.75,81.26 157.82,81.19 158.1,80.91 158.1,77.57 158.57,77.1 158.57,71.15 157.92,70.5 157.92,63.52 156.8,62.4 156.8,59.18 157.26,58.73 v2(157.29,58.73)
  BOTTOM w0.102: v2(157.29,58.73) 157.69,59.13 157.69,59.35 157.87,59.52 KBC24.111
EC_AGND: length 12.7
  BOTTOM w0.203: 155,56.19 155.43,56.19 155.68,56.44 157.49,56.44 157.6,56.32 KBC24.103
  BOTTOM w0.508: C2438.1 154.67,50.93 153.85,51.75 153.15,51.75 152.76,52.14 152.76,53.34 153.37,53.95 C2416.2 153.65,54.83 C2436.2 153.88,55.06 R2507.1 154.48,55.89 154.77,56.19 v1(154.79,56.19) 155,56.19
EC_AVCC: length 7.7
  BOTTOM w0.203: C2436.1 155.77,56.06 157.06,56.06 v1(157.08,56.03) 157.19,55.92 KBC24.102
  BOTTOM w0.508: C2436.1 154.95,54.85 R2435.1 154.64,53.44 153.83,52.63 C2416.1
EC_BRIGHTNESS: length 142.9
  TOP w0.102: D5502.2 v2(115.72,157.93) ; v2(156.34,56.95) v1(155.79,56.95)
  L4 w0.127: v2(162.52,130.96) 161.75,130.2 161.75,125.33 160.43,124 160.43,113.79 162.28,111.95 162.28,101.61 158.78,98.11 158.78,97.09 157.28,95.59 157.28,92.31 157.58,92.01 157.58,88.18 157.58,86.92 156.62,85.96 156.62,80.9 156.97,80.55 156.97,80.55 157.04,80.48 157.04,78 157.04,77.13 157.49,76.68 157.49,71.68 156.86,71.05 156.86,69.81 156.87,69.81 156.87,64.38 155.75,63.26 155.75,59.02 155.75,58.74 155.75,58.74 155.75,58.09 156.34,57.49 v2(156.34,56.95)
  BOTTOM w0.102: v2(156.34,56.95) 156.34,57.05 156.2,57.19 156.2,57.36 156.36,57.52 KBC24.106 ; v2(162.52,130.96) 161.81,130.96 158.87,133.9 154.17,133.9 149.86,138.21 147.79,138.21 144.83,141.17 144.83,142.13 137.53,149.43 131.42,149.43 127.54,153.32 120.56,153.32 115.94,157.93 v2(115.72,157.93)
EC_MUTE#: length 66.8
  TOP w0.102: v2(153.47,37.11) 153.7,36.88 164.98,36.88 165.83,37.73 169.59,37.73 170.14,38.28 170.37,38.28 v1(171.15,39.06) 170.95,39.26 170.95,43.33 170.67,43.61 170.67,44.65 170.95,44.93 170.95,45.45 171.53,46.03 171.78,46.28 171.78,46.45 171.78,46.56 171.79,46.56 171.79,47.68 172.5,48.39 172.5,51.45 173.48,52.43 174.2,52.43 174.94,53.17 174.94,53.6 174.78,53.75 174.78,58.83 172.4,61.22 172.4,66.26 v2(171.93,66.73)
  BOTTOM w0.102: v2(153.47,37.11) 153.47,36.04 153.25,35.82 153.25,33.17 153.73,32.69 153.73,31.47 154.34,30.86 154.34,28.86 154.01,28.53 153.07,28.53 152.69,28.15 152.69,26.12 R2706.2 153.22,25.58 154.68,25.58 154.93,25.33 R2722.1 ; KBC24.30 171.85,66.8 v2(171.93,66.73)
EC_SMI#: length 250.5
  TOP w0.102: v2(153.6,62.64) v1(153.04,62.64)
  L3 w0.102: v2(154.52,27.31) 149.31,22.1 135.49,22.1 132.85,24.74 59.02,24.74 52.97,30.79 52.97,33.2 61.4,41.63 61.4,42.29 64.24,45.14 64.24,59.35 65.11,60.21 65.11,64.08 65.26,64.23 65.26,67.96 67.88,70.57 v2(67.88,70.89)
  L4 w0.102: v2(67.88,70.89) 68.6,70.89 68.98,71.27 72.67,71.27 74.35,72.95 78.13,72.95 80.21,75.03 80.26,75.07 83.61,78.02 83.82,78.23 90.53,84.94 90.77,85.67 90.83,85.74 91.57,86.71 91.57,86.74 91.77,87.13 91.77,87.14 91.79,87.18 91.84,87.28 91.85,87.29 92.06,87.74 92.06,87.83 92.15,87.91 92.15,87.99 92.22,88.07 92.26,88.15 92.27,88.16 92.27,88.17 92.29,88.2 92.42,88.38 92.46,88.45 92.48,88.46 92.86,88.98 92.86,88.99 93.32,89.61 93.32,89.69 94.24,90.61 94.29,90.66 94.29,90.88 101.57,98.15 101.57,101.65 101.25,101.96 101.25,103.37 102.43,104.55 104.38,104.55 v2(104.81,104.98) ; v2(153.6,62.64) 153.83,62.41 153.83,62.41 154.19,62.06 154.19,59.44 154.08,59.34 154.08,51.86 155.7,50.25 155.7,48.78 155.56,48.64 155.56,44.85 155.6,44.81 155.6,42.46 156.12,41.94 156.59,41.47 156.59,31.09 154.95,29.46 154.95,27.74 v2(154.52,27.31)
  BOTTOM w0.102: R1834.1 R1805.2 v2(104.81,104.98) R2128.2 ; R2503.2 154.33,62.38 153.86,62.38 v2(153.6,62.64)
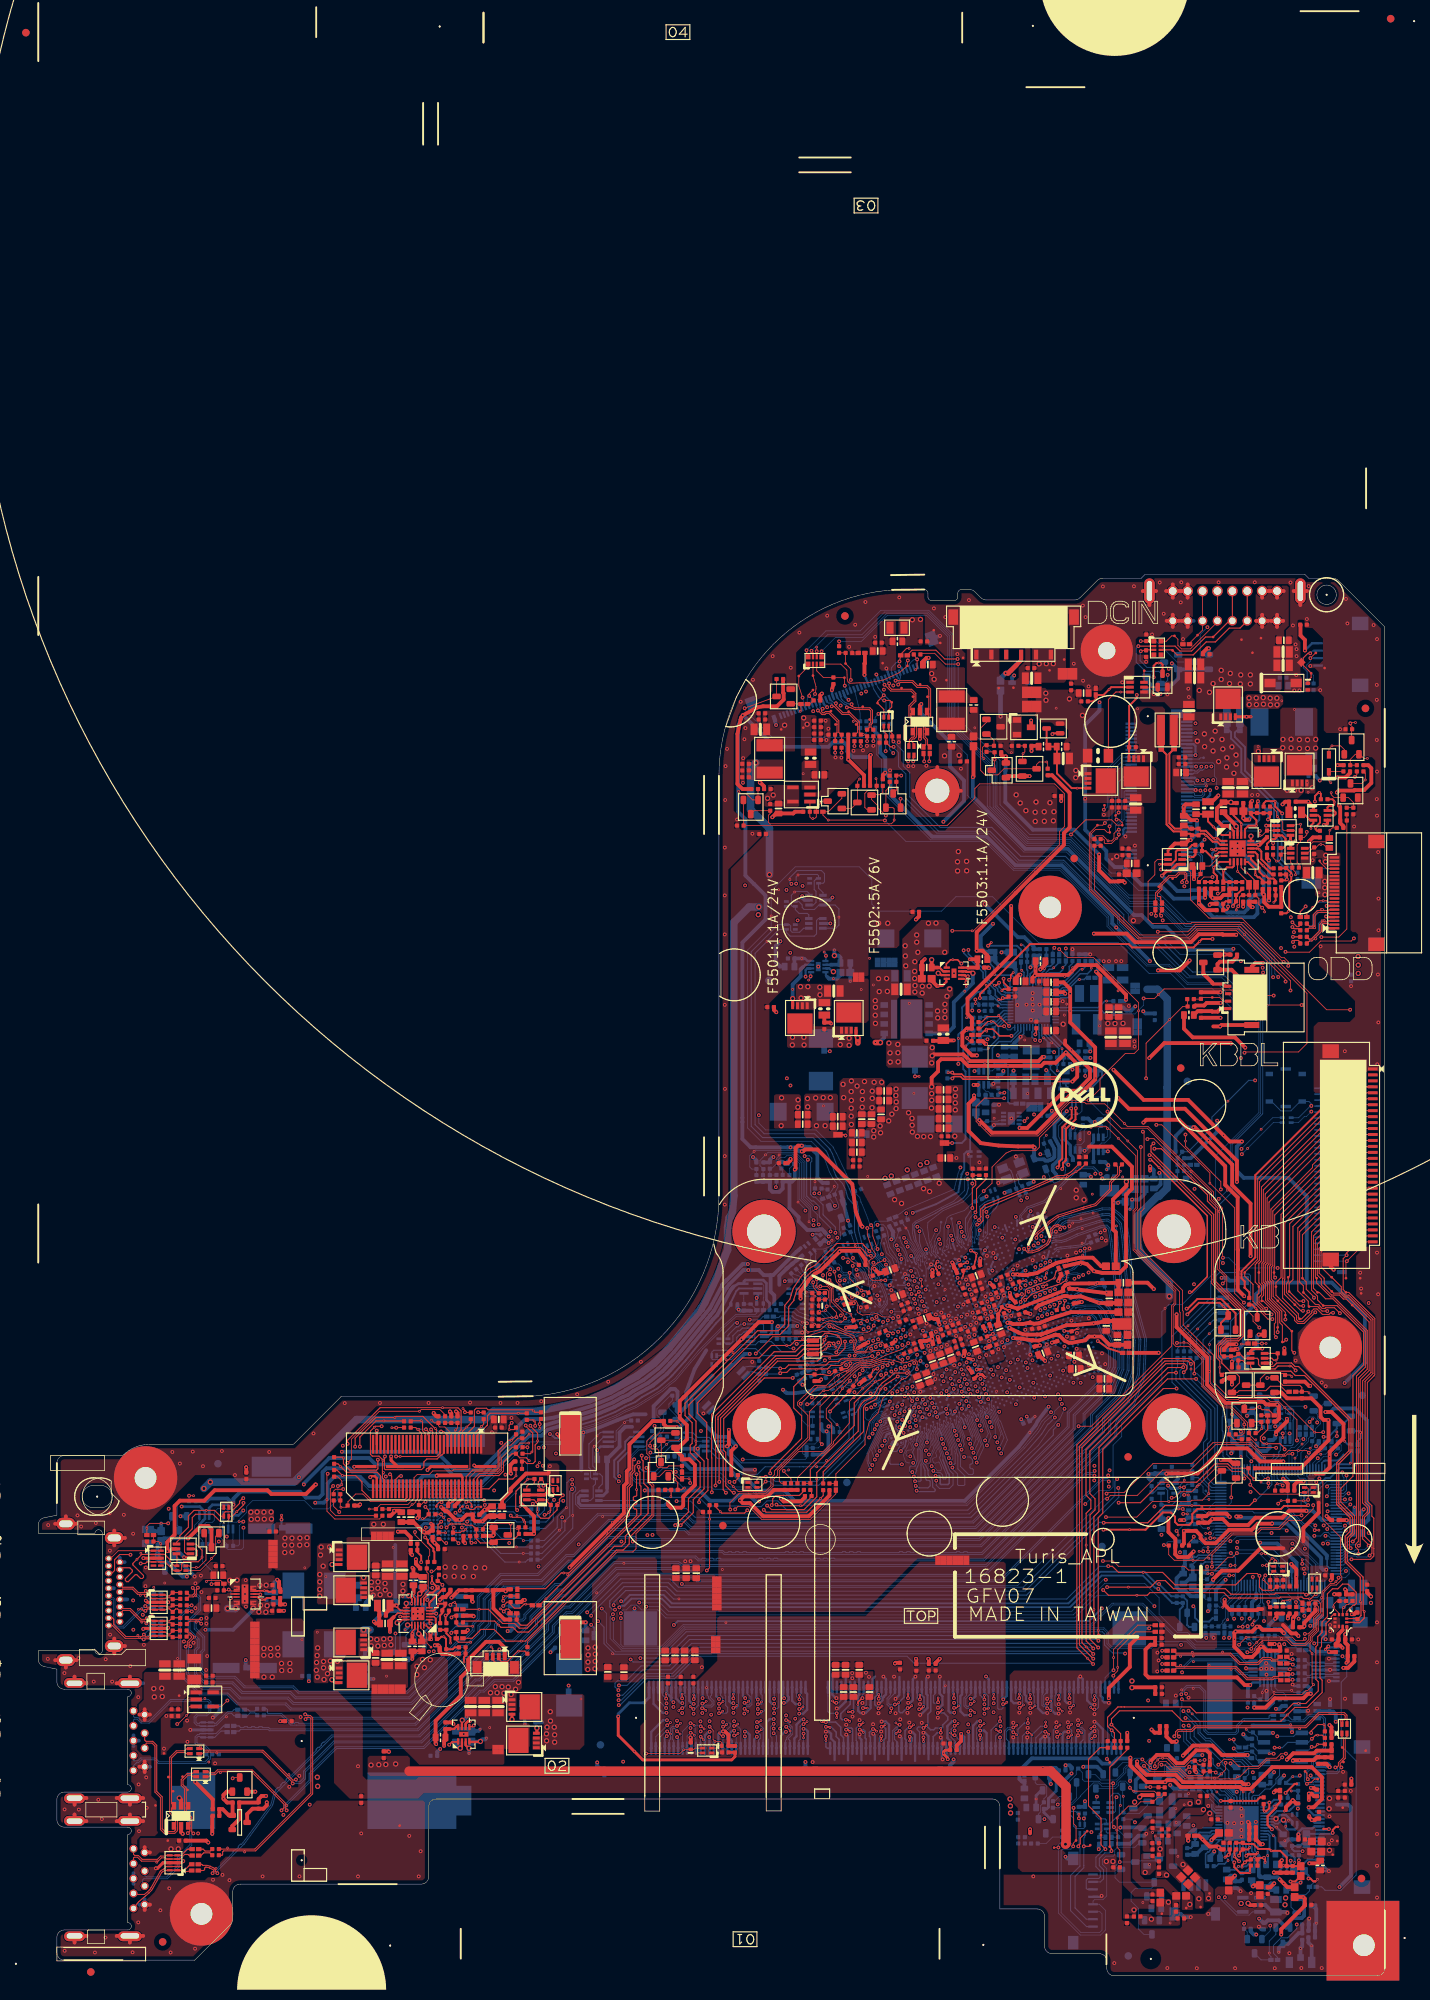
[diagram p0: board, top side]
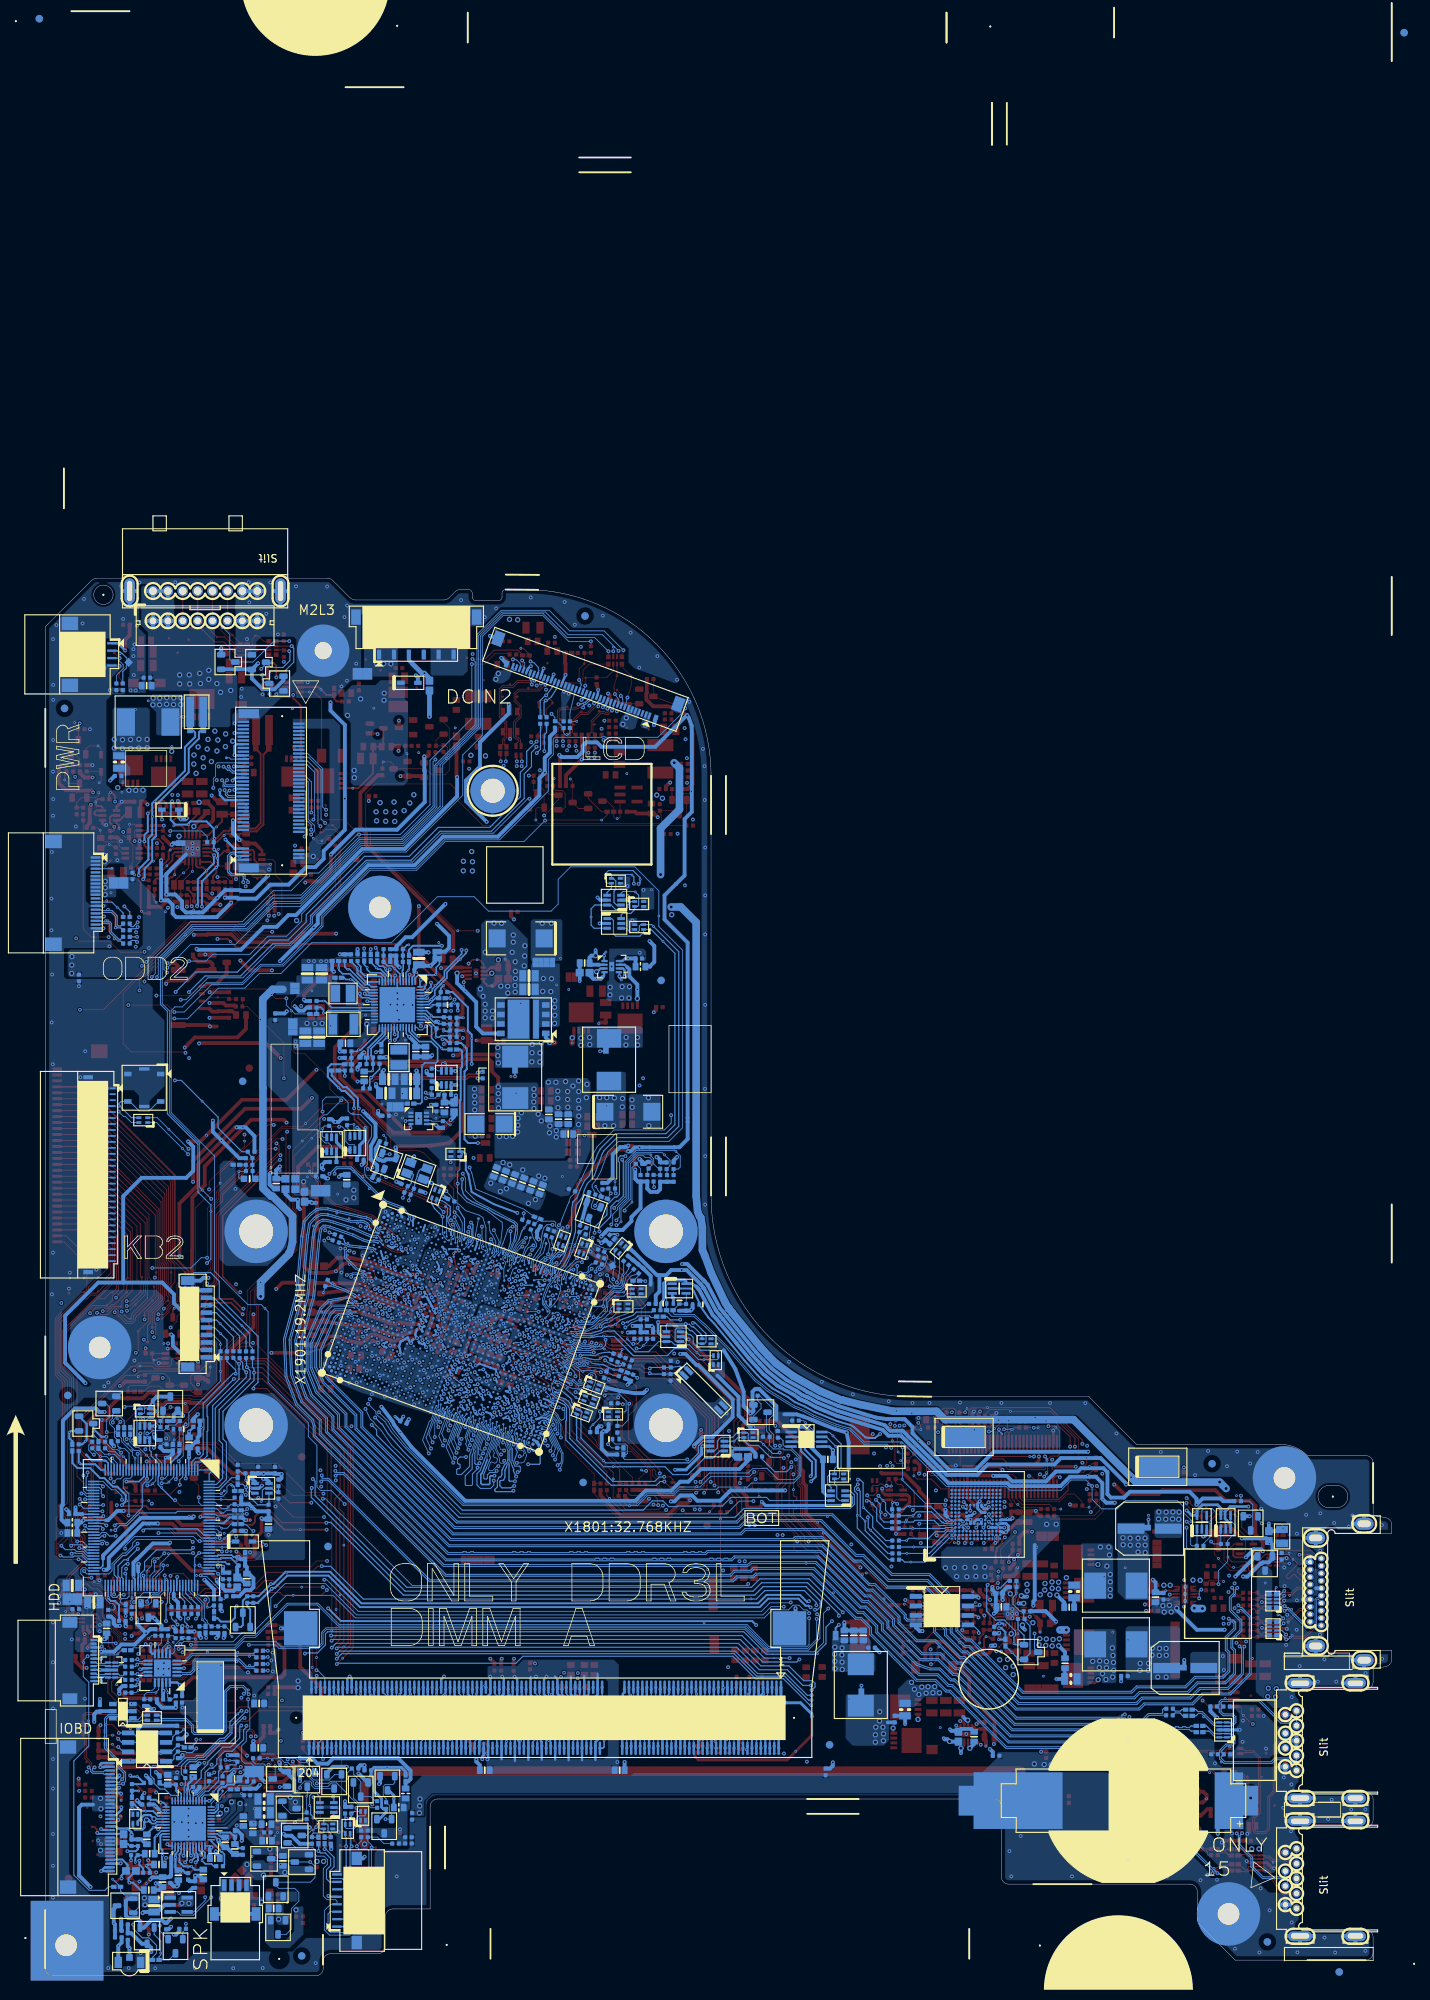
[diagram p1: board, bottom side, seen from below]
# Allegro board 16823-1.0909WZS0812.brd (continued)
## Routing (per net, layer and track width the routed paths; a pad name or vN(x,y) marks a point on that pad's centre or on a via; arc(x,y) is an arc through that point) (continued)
EC_SMI#_SOC: length 20.2
  L4 w0.102: v2(106.92,103.33) 107.76,103.33 108.05,103.03 109.02,103.03 109.38,103.03 109.93,102.48 112.64,102.48 112.96,102.48 114.34,101.09 115.08,101.09 116.87,99.3 116.87,98.04 v2(116.67,97.84)
  BOTTOM w0.089: CPU1.E39 118.1,95.11 118.09,95.15 118.09,95.39 118.1,95.39 118.1,95.63 117.83,95.9 117.83,96.14 117.83,96.14 117.83,96.25 117.79,96.36 117.79,96.38 117.78,96.39 117.75,96.48 117.56,96.85
  BOTTOM w0.102: v1(106.83,105.92) 106.66,105.65 106.52,105.39 106.34,105.15 106.09,104.89 106.09,104.55 v2(106.92,103.33) ; 117.56,96.85 117.36,97.24 116.98,97.62 116.71,97.84 v2(116.67,97.84)
EC_SPI_CLK: length 3.6
  BOTTOM w0.14: R2418.1 160.21,49.68 v1(161.2,50.68) 161.85,51.33 KBC24.92
EC_SPI_CS0#: length 3.2
  BOTTOM w0.14: KBC24.90 162.65,50.91 162.41,50.67 161.98,50.24 R2416.1
EC_SPI_MISO: length 24.6
  TOP w0.14: v1(159.87,31.7) v2(160.43,31.7)
  L3 w0.127: v2(164.49,47.6) 164.49,46.96 163.86,46.33 163.46,46.33 161.96,44.83 161.96,43.97 160.99,43 160.99,42.24 160.43,41.68 v2(160.43,31.7)
  BOTTOM w0.14: KBC24.86 164.25,51.51 164.3,51.46 164.3,50.06 164.49,49.87 v2(164.49,47.6) ; v2(160.43,31.7) 160.43,31.33 R2528.1
EC_SPI_MOSI: length 3.1
  BOTTOM w0.14: R2401.1 163.76,49.79 164.03,50.06 164.03,51.35 163.85,51.53 KBC24.87
EC_VCC1V8: length 3.1
  BOTTOM w0.203: 163.45,51.29 KBC24.88
  BOTTOM w0.508: 163.45,51.29 163.45,50.67 v1(163.41,50.63) 162.87,50.09 R2497.2
EC_VTT: length 5.2
  BOTTOM w0.203: KBC24.12 164.65,69.42 v1(164.55,69.52)
  BOTTOM w0.508: v1(164.55,69.52) 164.09,69.52 163.58,70.03 R2509.2 C2447.1 164.82,70.42 165.23,70.84 R2430.2
ECRST#: length 10.8
  TOP w0.102: v2(164.68,53.72) 164.42,53.47 v1(164.42,53.16) 164.42,53.1 R2404.2 C2444.1 165.32,53.83 165.78,54.29 RN2402.4
  BOTTOM w0.102: v2(164.68,53.72) 164.65,53.7 KBC24.85 164.65,51.59 165.29,50.95 166.17,50.95 166.43,50.69 166.43,50.16 166.86,49.74 167.6,49.74 Q2401.E
EDP_AUX_CON_N: length 7.7
  TOP w0.127: C5505.1 107.82,165.69 R5515.2 107.73,166.52 107.44,166.82 107.44,168.39 106.26,169.57 ; v2(105.26,170) 105.11,169.84 105.11,169.64 105.29,169.46 105.47,169.46 105.65,169.64 106.19,169.64 106.26,169.57 ; AFTP5507.1 106.26,169.57
  BOTTOM w0.127: v2(105.26,170) 105.03,170 104.92,170.12 104.92,170.39 LCD1.12
EDP_AUX_CON_P: length 7.3
  TOP w0.127: v2(104.63,169.78) 105.19,169.22 105.57,169.22 105.75,169.39 106.09,169.39 107.2,168.29 107.2,167.9 ; 107.2,167.9 AFTP5506.1 ; 107.2,167.9 107.2,166.79 R5520.1 106.94,166.51 C5504.1
  BOTTOM w0.127: LCD1.11 v2(104.63,169.78)
EDP_AUX_CPU_N: length 137.8
  TOP w0.127: C5505.2 v2(107.8,164.11)
  L3 w0.114: v2(135.4,88.75) 135.36,88.75 135.15,88.54 135.15,88.4 135.25,88.29 135.8,88.29 135.87,88.32 136.17,88.42 140.95,90.09 143.84,92.3 143.85,92.31 144.08,92.48 145.69,92.98 152.79,92.98 157.33,97.52 157.33,138.36 150.17,145.53 144.11,145.53 139.27,150.37 133.97,150.37 127.59,156.75 127.59,162.13 126.22,163.5 126.22,164.46 122.04,168.63 110.02,168.63 107.38,165.99 107.38,164.29 107.38,164.29 107.38,164.13 107.46,164.05 107.74,164.05 v2(107.8,164.11)
  BOTTOM w0.127: v2(135.4,88.75) 135.26,88.89 135.26,89.11 135.44,89.28 CPU1.AH9
EDP_AUX_CPU_P: length 138.4
  TOP w0.127: C5504.2 v2(106.94,164.11)
  L3 w0.114: v2(134.71,88.52) 135.16,88.06 135.84,88.06 135.95,88.1 136.21,88.19 141.06,89.88 141.37,90.12 141.46,90.19 143.79,91.98 143.98,92.12 144.18,92.27 145.73,92.75 152.89,92.75 157.56,97.43 157.56,138.45 150.26,145.75 144.21,145.75 139.36,150.6 134.06,150.6 127.82,156.84 127.82,162.22 126.45,163.6 126.45,164.55 122.14,168.86 109.93,168.86 107.15,166.08 107.15,164.32 v2(106.94,164.11)
  BOTTOM w0.127: CPU1.AH10 v2(134.71,88.52)
EDP_BLCTRL_CPU: length 154.6
  TOP w0.102: v2(122.66,140.21) v1(125.35,140.21) 125.51,140.21 130.73,145.43 130.73,145.45 137.07,151.78 137.07,153.55 137.73,154.21 137.73,158.6 136.4,159.92 126.32,159.92 125.69,159.28 125.69,158.04 121.98,154.33 R5528.2 94.63,154.36 Q5504.E
  L3 w0.127: v2(107.24,99.04) 107.42,99.37 107.42,99.78 107.41,99.82 107.37,99.93 107.3,100.03 107.3,100.04 106.84,100.81 106.78,100.88 106.44,101.46 106.44,101.48 106.1,102.02 105.94,102.19 105.8,102.72 105.69,103.15 105.45,103.6 104.81,104.24 104.73,104.29 103.56,104.7 102.16,109.52 101.98,110.16 101.8,110.34 101.26,111.88 100.81,112.33 100.81,118.45 100.02,119.24 100.02,132.96 108.56,141.51 111.28,141.51 112.17,140.62 122.26,140.62 v2(122.66,140.21)
  L4 w0.127: v2(113.21,96.82) 112.59,96.82 111.69,97.73 109.63,97.73 108.35,97.73 107.24,98.84 v2(107.24,99.04)
  BOTTOM w0.102: v2(113.21,96.82) 112.99,98.1 113.16,98.6 113.33,99.17 R805.2 113.85,98.42 114.03,97.75 114.3,96.97 115.16,95.97 115.23,95.8 115.23,95.19 115.15,95.03 CPU1.C46
EDP_BLEN_CPU: length 273.6
  TOP w0.102: v1(171.01,74.72) v2(170.62,74.32) ; R803.2 111.8,94.11 111.8,95.03 112.04,95.27 112.24,95.27 112.62,95.65 v2(113.58,96.04)
  L3 w0.127: v2(170.62,74.32) 170.23,73.93 170.23,71.83 169.07,70.68 168.12,70.68 165.96,68.51 165.96,60.94 166.03,60.87 166.03,58.05 165.34,57.36 165.34,53.75 162.66,51.08 162.34,51.08 158.44,47.18 158.44,43.6 157.31,42.47 157.31,31.92 157.27,31.88 157.27,31.76 152.08,26.57 149.58,26.57 145.94,22.94 145.02,22.94 144.55,22.47 140.27,22.47 139.25,23.5 134.79,23.5 133.06,25.23 60.29,25.23 54.71,30.82 54.71,33.88 61.94,41.11 62.12,41.11 66.2,45.19 66.2,51.29 65.92,51.56 65.92,63.51 66.01,63.6 66.01,66.72 v2(67.72,68.43)
  L4 w0.127: v2(113.58,96.04) 112.55,96.04 112.43,96.16 111.26,96.16 109.95,97.47 108.25,97.47 107.87,97.86 106.22,97.86 96.77,88.41 96.77,87.17 94.01,84.41 93.67,84.41 84.5,75.23 84.5,73.78 84.5,73.51 83.3,72.32 81.16,72.32 79.52,70.68 78.77,70.68 77.07,68.98 76.44,68.98 72.58,68.98 71.54,67.93 68.22,67.93 v2(67.72,68.43)
  BOTTOM w0.102: R804.2 112.7,98.25 112.56,97.96 112.32,97.83 112.17,97.62 112.25,97.05 112.4,96.9 112.57,96.7 112.62,96.65 112.62,96.58 112.97,96.23 112.99,96.23 v2(113.58,96.04) 114.11,95.79 114.46,94.84 CPU1.B47 ; R2444.2 170.92,74.02 v2(170.62,74.32)
EDP_HPD_CPU_D: length 289.4
  TOP w0.102: v2(94.8,170.08) Q5503.D R5514.2
  L4 w0.127: v2(114.49,89.11) 113.49,90.1 110.19,90.1 109.53,89.45 107.21,89.45 106.78,89.02 105.79,89.02 103.18,86.41 103.18,86.34 102.43,85.59 101.64,85.59 100.88,84.84 100.88,83.71 98.8,81.62 98.8,80.52 94.61,76.33 94.06,75.78 94.06,75.78 93.31,75.02 93.31,74.85 93.31,73.25 92.87,72.81 92.25,72.81 87.41,67.97 86.55,67.97 86.2,67.62 v2(85.55,67.62) ; v2(135.92,75.62) 135.92,68.24 140.52,63.64 v2(140.52,63.3)
  BOTTOM w0.102: v2(114.49,89.11) 114.49,89.1 CPU1.P48 ; v2(85.55,67.62) 86.15,67.02 91.38,67.02 92.82,65.58 95.58,65.58 96.5,64.67 99.95,64.67 101.32,63.3 124.53,63.3 132.19,70.96 134.11,73.34 134.66,74.35 v2(135.92,75.62) ; v2(94.8,170.08) 94.8,169.86 98.5,166.17 105.52,166.17 105.59,166.25 105.95,166.25 106.03,166.17 112.3,166.17 112.53,165.94 112.53,163.83 113.19,163.17 113.19,158.96 119.73,152.41 127.12,152.41 130.96,148.57 137.17,148.57 143.66,142.08 143.66,140.9 148.85,135.71 151.81,135.71 154.3,133.23 159.09,133.23 162.31,130 163.31,130 163.81,129.49 163.81,115.83 157.98,109.99 157.98,94.53 153.49,90.05 151.71,90.05 v1(151.22,89.55) 150.8,89.13 150.8,79.62 145.4,74.22 145.4,72.34 144.24,71.19 144.24,65.6 143.77,65.13 142.35,65.13 v2(140.52,63.3)
EDP_RCOMP_N: length 1.7
  TOP w0.127: R802.2 v2(137.78,90.59)
  BOTTOM w0.127: CPU1.AG5 v2(137.78,90.59)
EDP_RCOMP_P: length 1.6
  TOP w0.127: R802.1 v2(137.11,90.34)
  BOTTOM w0.127: CPU1.AG6 v2(137.11,90.34)
EDP_TX_CON_N0: length 7.9
  TOP w0.127: v2(106.49,170.34) 106.49,170.33 106.79,170.33 107.89,169.23 108.86,169.23 109.94,168.15 109.94,167.9 ; 109.94,167.9 109.94,166.83 109.65,166.54 C5513.1 ; 109.94,167.9 AFTP5504.1
  BOTTOM w0.127: v2(106.49,170.34) 106.56,170.41 106.56,170.64 106.43,170.77 106.04,170.77 105.97,170.83 105.74,171.26
EDP_TX_CON_N1: length 8.4
  TOP w0.127: 111.72,168.56 AFTP5502.1 ; 111.72,168.56 111.72,168.17 111.51,167.97 111.51,167.48 C5506.1 ; 111.72,168.56 111.72,169.69 111.51,169.89 109.62,169.89 108.88,170.19 v2(108.52,170.18)
  BOTTOM w0.127: v2(108.52,170.18) 108.41,170.53 108.4,170.54 108.25,170.6 108.23,170.61 108.12,170.66 107.78,170.97 107.34,171.33 LCD1.17
EDP_TX_CON_P0: length 7.4
  TOP w0.127: C5512.1 110.18,166.75 110.18,168.25 108.96,169.47 108.74,169.47 ; 108.74,169.47 AFTP5505.1 ; 108.74,169.47 107.99,169.47 107.04,170.42 v2(107.04,170.74)
  BOTTOM w0.127: LCD1.15 106.52,171.01 106.53,171.01 106.71,170.83 v2(107.04,170.74)
EDP_TX_CON_P1: length 8.4
  TOP w0.127: 110.65,170.13 AFTP5503.1 ; 110.65,170.13 111.61,170.13 111.96,169.79 111.96,168.07 111.75,167.87 111.75,167.52 C5507.1 ; 110.65,170.13 109.67,170.13 109.23,170.31 v2(109.15,170.61)
  BOTTOM w0.127: v2(109.15,170.61) 108.78,170.65 108.5,170.76 108.25,170.86 108.13,170.97 107.94,171.15 107.78,171.29 LCD1.18
EDP_TX_CPU_N0: length 135.1
  TOP w0.127: v2(109.53,165) C5513.2
  L3 w0.114: v2(109.53,165) 109.58,165.05 109.86,165.05 109.96,164.96 109.96,164.16 109.68,163.88 108.75,163.88 108.54,164.09 108.54,165.94 110.43,167.83 121.82,167.83 125.47,164.18 125.47,163.13 126.74,161.86 126.74,156.45 133.61,149.58 139.03,149.58 143.81,144.8 149.87,144.8 156.11,138.56 156.11,138.56 156.6,138.07 156.6,97.81 152.67,93.88 144.19,93.88 143.19,93.56 143,93.45 142.97,93.43 139.92,91.74 139.68,91.61 139.56,91.54 137.74,91.29 137.72,91.28 137.13,91.06 136.76,90.93 136.73,90.92 136.47,90.7 136.17,90.47 135.95,90.23 v2(135.76,89.82)
  BOTTOM w0.127: CPU1.AG9 135.4,90.22 135.62,90.22 135.76,90.08 v2(135.76,89.82)
EDP_TX_CPU_N1: length 128
  TOP w0.127: v2(111.23,165.66) C5506.2
  L3 w0.114: v2(135.11,89.56) 134.75,89.9 134.68,90.05 134.64,90.16 134.66,90.28 135.03,90.65 135.45,90.93 136.2,91.25 136.45,91.34 137.73,91.81 138.36,92.32 139.51,92.7 139.51,92.7 139.59,92.73 139.83,92.85 142.7,94.23 143.62,94.46 152.55,94.46 156.04,97.95 156.04,137.93 149.66,144.31 143.61,144.31 138.84,149.07 133.02,149.07 126.09,156 126.09,161.74 124.98,162.86 124.98,163.98 121.62,167.34 112.31,167.34 111.46,166.49 111.46,165.89 v2(111.23,165.66)
  BOTTOM w0.127: CPU1.AG10 v2(135.11,89.56)
EDP_TX_CPU_P0: length 135.6
  TOP w0.127: v2(110.4,165) C5512.2
  L3 w0.114: v2(136.37,90.04) 136.37,90.34 136.61,90.52 136.65,90.56 136.84,90.72 137.2,90.85 137.8,91.07 139.63,91.32 143.28,93.35 144.23,93.65 152.76,93.65 156.83,97.71 156.83,138.16 156.21,138.79 149.96,145.03 149.36,145.03 143.91,145.03 139.12,149.81 133.71,149.81 126.97,156.55 126.97,161.96 125.7,163.23 125.7,164.28 121.92,168.06 110.34,168.06 108.31,166.03 108.31,163.99 108.66,163.65 109.77,163.65 110.19,164.06 110.19,164.79 v2(110.4,165)
  BOTTOM w0.127: CPU1.AG7 v2(136.37,90.04)
EDP_TX_CPU_P1: length 127.9
  TOP w0.127: v2(112.07,165.66) C5507.2
  L3 w0.114: v2(134.49,89.32) 134.6,89.43 134.6,89.69 134.47,89.96 134.47,89.97 134.4,90.14 134.41,90.2 134.44,90.39 134.89,90.83 134.9,90.84 135.34,91.13 136.11,91.46 136.37,91.56 137.62,92.01 138.25,92.52 139.43,92.92 139.5,92.94 139.73,93.05 141.79,94.04 142.25,94.27 142.3,94.29 142.62,94.44 143.59,94.69 152.46,94.69 155.81,98.05 155.81,137.83 149.57,144.08 143.51,144.08 138.74,148.85 132.93,148.85 125.86,155.91 125.86,161.65 124.75,162.77 124.75,163.88 121.52,167.11 112.4,167.11 111.69,166.4 111.69,165.81 111.84,165.66 v2(112.07,165.66)
  BOTTOM w0.127: CPU1.AG12 134.05,89.71 134.31,89.71 134.49,89.54 v2(134.49,89.32)
EDP_VDDEN_CPU: length 266.7
  TOP w0.102: v2(113.75,155.68) 113.72,155.68 112.68,156.72 112.68,156.97 111.83,157.82 Q5501.E 111.89,158.47 112.99,158.47 113.34,158.83 R5527.2 ; v2(112.63,97.51) 112,99.28 112,100.48 v2(111.77,100.71)
  L3 w0.127: v2(96.71,115.47) 96.71,117.38 96.34,117.75 96.34,118.6 96.34,119.36 96.34,134.4 96.34,140.98 97.52,142.17 97.52,143.58 109.72,155.78 113.65,155.78 v2(113.75,155.68)
  L4 w0.127: v2(113.75,155.68) 114.13,155.3 122.09,155.3 127.45,160.66 127.45,162.94 130.11,165.6 139.09,165.6 147.1,173.61 151.29,173.61 155.19,177.51 169.05,177.51 170.37,176.19 170.91,176.19 173.48,173.62 173.48,152.01 174.85,150.64 174.85,144.71 174.99,144.57 174.99,135.28 174.01,134.3 174.01,129.06 170.17,125.22 170.17,90.76 170.89,90.04 170.89,87.11 170.25,86.47 170.25,78.58 171.64,77.19 v2(171.64,74.25)
  BOTTOM w0.102: v2(96.71,115.47) 96.71,114.4 97.62,113.49 104.39,113.49 106.69,111.19 106.69,111.14 107.14,110.32 108.44,107.6 108.5,107.48 v1(108.84,106.8) R808.2 109.8,104.88 110.24,104.44 110.39,103.94 110.42,103.78 110.42,103.75 110.6,103.43 111.31,101.66 111.55,100.93 v2(111.77,100.71) ; CPU1.C47 114.9,94.63 114.93,94.68 114.93,94.81 114.89,94.92 114.8,95 114.8,95 114.51,95.29 114.28,95.91 113.77,96.43 113.73,96.45 113.41,96.45 113.38,96.42 113.05,96.42 112.81,96.66 112.81,96.73 112.71,96.83 112.67,96.88 v2(112.63,97.51) ; R2506.2 170.11,74.48 170.61,74.98 171.17,74.98 171.64,74.52 v2(171.64,74.25)
EMMC_CLK: length 84.5
  TOP w0.14: v2(51.95,62.92) 52.39,62.47 R6310.1 51.82,61.35 v1(51.58,61.35)
  L4 w0.127: v2(112.4,84.38) 112.05,84.59 111.58,84.59 111.53,84.54 111.16,84.48 110.73,84.05 109.27,83.6 v2(108.87,83.21) 108.59,83.21 108.03,82.9 106.57,81.44 106.57,80.82 106.31,80.56 106.2,80.56 105.51,79.86 105.43,79.73 105.43,79.65 105.32,79.53 104.73,78.51 104.36,77.86 104.36,77.37 103.73,76.74 103.63,76.56 103.63,76.35 103.36,76.09 103.31,76 103.31,75.98 102.82,75.49 102.71,75.28 102.71,75.13 102.46,74.88 102.46,74.14 102.27,73.38 102.09,73.2 102.09,71.94 99.1,68.95 96.3,68.95 95.22,67.87 92.32,67.87 86.66,62.21 85.42,62.21 84.26,62.21 83.06,61.01 70.53,61.01 70.52,61.01 70.06,61.01 69.81,61.27 69.81,61.34 68.33,62.82 66.03,62.82 65.34,63.5 63.7,63.5 63.22,63.02 61.35,63.02 59.11,65.25 52.91,65.25 51.53,63.88 51.53,63.44 51.56,63.42 51.56,63.31 v2(51.95,62.92)
  BOTTOM w0.14: CPU1.Y58 v2(112.4,84.38) ; R2016.2 104.99,83.67 105.73,83.63 106.41,83.47 106.87,83.22 107.21,83.22 107.31,83.24 107.55,83.29 108.55,83.29 v2(108.87,83.21)
EMMC_CLK_R: length 2.4
  TOP w0.14: R6310.2 53.29,61.93 v2(54.05,61.93) 54.05,61.84 v1(54.41,61.47)
  BOTTOM w0.14: U6301.M6 53.56,61.16 54.05,61.65 v2(54.05,61.93)
EMMC_CLK_RC: length 1.8
  BOTTOM w0.14: EC2001.1 R2016.1 v1(103.3,84.05)
EMMC_CMD: length 102.8
  TOP w0.14: R6311.1 54.01,58.6 54.54,58.07 v2(54.74,58.07)
  L3 w0.127: v2(46.64,66.99) 46.64,64.09 47.19,63.54 47.19,62.15 47.65,61.69 49.04,61.69 51.2,59.53 51.2,58.92 51.74,58.38 52.27,58.38 53,57.65 54.33,57.65 v2(54.74,58.07)
  L4 w0.127: v2(115.78,85.6) 115.33,85.66 115.24,85.75 114.86,85.75 114.4,85.3 113.46,85.3 112.9,85.85 112.84,85.85 110.41,85.85 109.16,84.61 107.61,84.61 107.42,84.42 106.78,84.42 103.02,80.66 103.02,79.12 102.76,78.86 102.24,78.86 100.82,77.44 100.82,73.59 100.82,72.46 98.66,70.3 96.92,70.3 94.77,70.3 93.68,69.22 91.87,69.22 86.82,64.16 84.42,64.16 82.64,62.38 70.02,62.38 69.69,62.72 68.83,63.58 68.4,64.01 63.49,64.01 63.01,63.53 61.56,63.53 59.32,65.76 58.9,65.76 52.7,65.76 47.99,65.76 46.99,66.77 46.86,66.77 v2(46.64,66.99)
  BOTTOM w0.14: v1(46.34,67.52) 46.34,67.29 v2(46.64,66.99) ; 115.89,86.1 v2(115.78,85.6)
EMMC_CMD_R: length 3.2
  TOP w0.14: v1(54.67,59.44) 53.8,59.44 R6311.2 53.64,59.6 53.64,60.5 v2(54.07,60.93)
  BOTTOM w0.14: v2(54.07,60.93) 53.79,60.65 U6301.M5
EMMC_DATA_0: length 61.2
  L4 w0.127: v2(112.05,85.22) 111.77,85.23 111.59,85.42 111.21,85.42 110.44,84.65 110.19,84.3 108.22,83.66 107.61,83.25 107.59,83.24 107.19,82.84 107.05,82.84 104.8,80.6 104.62,80.2 104.16,79.39 104.16,78.64 103.98,78.32 103.89,78.32 102.77,77.21 102.13,77.21 101.87,76.94 101.87,76.58 101.94,76.51 101.94,74.16 101.81,73.64 101.58,73.41 101.58,72.15 98.89,69.46 98.09,69.46 98.09,69.46 97.67,69.46 96.09,69.46 95.01,68.38 92.11,68.38 86.45,62.71 85.63,62.71 84.05,62.71 82.96,61.62 70.42,61.62 v2(70.31,61.52)
  BOTTOM w0.14: v2(70.31,61.52) 70.26,61.47 70.26,60.12 v1(69.93,59.79) 67.67,57.53 R6314.2 ; CPU1.V58 v2(112.05,85.22)
EMMC_DATA_0_R: length 8
  BOTTOM w0.14: U6301.A3 59.64,59.65 61.75,57.53 v1(64.17,57.53) R6314.1
EMMC_DATA_1: length 59.4
  L4 w0.089: 110.47,87.1 110.68,87.16 111.03,87.2 v2(111.41,87)
  L4 w0.127: v2(70.45,63.73) 70.66,63.53 82.17,63.53 83.94,65.31 85.35,65.31 87,66.96 87.83,66.96 91.48,70.6 92.62,70.6 92.88,70.86 92.88,71.39 94.32,72.83 94.32,74.56 96.41,76.65 96.67,76.65 96.67,76.65 96.96,76.65 100.97,80.67 100.97,81.72 104.68,85.43 104.68,85.69 104.68,85.69 104.68,85.83 105.27,86.41 106.35,86.41 106.49,86.55 108.59,86.55 108.75,86.71 110.47,87.1
  BOTTOM w0.14: R6325.2 68.08,60.02 69.12,61.06 69.12,62.74 v1(69.76,63.38) 70.11,63.73 v2(70.45,63.73) ; CPU1.T58 111.41,86.99 v2(111.41,87)
EMMC_DATA_1_R: length 7.2
  BOTTOM w0.14: U6301.A4 59.85,60.15 59.98,60.02 v1(64.24,60.02) R6325.1
EMMC_DATA_2: length 60.8
  L4 w0.127: v2(110.75,86.76) 110.31,86.69 109.92,86.66 109.3,86.55 108.8,86.46 108.68,86.34 106.58,86.34 106.17,85.93 105.46,85.93 105.06,85.53 105.06,85.28 101.84,82.05 101.84,79.9 100.05,78.11 100.05,73.77 100.05,72.78 98.5,71.23 94.52,71.23 93.52,70.22 91.64,70.22 87.99,66.58 87.16,66.58 85.5,64.92 84.1,64.92 82.32,63.15 70.41,63.15 70.01,63.55 70.01,63.7 69.3,64.41 v2(68.89,64.41)
  BOTTOM w0.14: CPU1.T59 v2(110.75,86.76) ; v2(68.89,64.41) v1(68.28,63.81) 67.93,63.45 67.93,62.46 67.21,61.75 R6315.2
EMMC_DATA_2_R: length 8
  BOTTOM w0.14: U6301.A5 59.67,60.65 59.71,60.7 60.04,60.7 60.21,60.86 60.36,60.86 61.75,62.26 63.74,62.26 v1(64.24,61.75) R6315.1
EMMC_DATA_3: length 76.2
  L4 w0.127: v2(116.09,86.67) 116.09,89.23 113.82,91.5 113.65,91.66 113.48,91.91 112.4,92.99 109.49,92.99 109.35,92.92 107.96,91.53 106.76,91.53 105.97,90.73 104.95,90.73 103.12,88.89 102.4,88.89 100.99,87.48 100.99,86.38 99.87,85.26 99.87,84.15 97.78,82.07 97.78,80.94 94.19,77.35 93.05,76.2 93.05,76.2 92.45,75.6 92.4,75.55 92.29,75.45 92.29,75.29 87.5,70.5 87.26,70.26 86.38,70.26 85.11,68.99 84.95,68.82 84.9,68.78 82.2,66.08 79.57,66.08 78.17,67.48 77.69,67.48 77.69,67.48 75.81,67.48 75.81,67.48 74.21,67.48 74.21,67.48 73.2,67.48 v2(71.66,65.94)
  BOTTOM w0.14: CPU1.V51 v2(116.09,86.67) ; R6319.2 67.5,55.83 71.73,60.07 v1(71.73,61.77) 71.73,64.69 72.09,65.05 72.09,65.52 v2(71.66,65.94)
EMMC_DATA_3_R: length 9.2
  BOTTOM w0.076: U6301.B2 58.8,58.91 59.22,58.91 59.4,58.74
  BOTTOM w0.14: R6319.1 65.69,55.83 65.37,55.51 v1(64.55,55.51) 64.55,55.51 62.62,55.51 59.4,58.74
EMMC_DATA_4: length 73.3
  L4 w0.127: v2(71.64,65.31) 71.83,65.5 71.85,65.5 71.94,65.58 82.25,65.58 84.88,68.22 85.29,68.62 86.54,69.88 88.29,69.88 88.65,70.24 88.95,70.53 88.95,71.41 92.67,75.14 92.67,75.28 92.72,75.33 93.43,76.05 94.35,76.96 98.17,80.78 98.17,81.91 100.25,83.99 100.25,85.1 101.37,86.22 101.37,87.32 102.56,88.51 103.27,88.51 105.11,90.35 106.12,90.35 106.92,91.15 108.12,91.15 109.02,92.05 109.65,92.39 111.74,92.39 112.03,92.1 112.36,92.1 112.54,91.97 115.83,88.69 115.83,88.07 115.45,87.65 115.4,87.11 115.4,86.82 v2(115.4,86.41)
  BOTTOM w0.14: v2(71.64,65.31) 71.34,65.01 71.34,61.68 v1(70.67,61.01) 70.67,59.74 67.6,56.67 R6318.2 ; CPU1.V52 v2(115.4,86.41)
EMMC_DATA_4_R: length 8.8
  BOTTOM w0.076: 59.62,59.11 59.32,59.41 58.8,59.41 U6301.B3
  BOTTOM w0.14: 59.62,59.11 62.06,56.67 v1(65.08,56.67) R6318.1
EMMC_DATA_5: length 75.7
  L4 w0.127: v2(71.64,66.58) 71.81,66.75 71.94,66.75 73.04,67.86 74.05,67.86 77.53,67.86 78.33,67.86 78.8,67.52 79.86,66.46 82.05,66.46 84.12,68.54 84.63,69.05 84.72,69.13 84.79,69.2 84.95,69.37 86.23,70.64 86.85,70.64 87.29,71.08 88.14,71.92 88.38,71.92 91.91,75.45 91.91,75.61 92.13,75.82 92.21,75.9 92.67,76.36 92.67,76.36 94.03,77.73 97.4,81.1 97.4,82.23 99.49,84.31 99.49,85.42 100.6,86.53 100.6,87.64 102.24,89.27 102.96,89.27 104.8,91.11 105.45,91.11 106.23,91.89 106.61,91.89 106.63,91.91 107.79,91.91 109.26,93.37 112.56,93.37 113.97,91.96 114.03,91.82 116.5,89.35 116.5,86.19 v2(116.4,85.82)
  BOTTOM w0.14: CPU1.Y49 v2(116.4,85.82) ; R6321.2 67.9,58.4 69.65,60.15 69.65,61.59 v1(70.87,62.81) 70.94,62.88 70.94,66.16 71.36,66.58 v2(71.64,66.58)
EMMC_DATA_5_R: length 8.3
  BOTTOM w0.076: 59.95,59.72 59.76,59.91 58.84,59.91 58.6,60.15 U6301.B4
  BOTTOM w0.14: R6321.1 v1(65.11,58.4) 64.8,58.7 62.14,58.7 61.25,59.59 60.08,59.59 59.95,59.72
EMMC_DATA_6: length 64
  L4 w0.127: v2(114.05,85.92) 113.58,85.96 113.14,85.97 113.04,86.07 108.6,86.07 107.99,85.93 107.99,85.93 106.87,85.93 102.22,81.28 102.22,79.74 102.01,79.53 102.01,79.19 100.44,77.61 100.44,73.68 100.43,73.68 100.43,72.62 98.5,70.68 94.54,70.68 93.58,69.72 91.78,69.72 86.6,64.54 84.26,64.54 82.48,62.77 70.25,62.77 69.3,63.72 69.3,63.78 v2(69.22,63.86)
  BOTTOM w0.14: CPU1.V55 v2(114.05,85.92) ; v2(69.22,63.86) 68.64,63.27 v1(68.64,62.26) 68.64,61.39 68.13,60.89 R6320.2
EMMC_DATA_6_R: length 8.1
  BOTTOM w0.076: U6301.B5 58.56,60.65 58.81,60.4 59.98,60.4
  BOTTOM w0.14: 59.98,60.4 59.99,60.42 60.73,60.42 61.42,61.11 63.99,61.11 64.22,60.89 v1(65.26,60.89) R6320.1
EMMC_DATA_7: length 62.3
  L4 w0.127: v2(112.71,85.4) 112.4,85.52 112.27,85.64 110.75,85.64 110.3,85.25 109.44,84.39 108.52,84.39 108.41,84.37 107.27,83.23 106.89,83.23 103.4,79.74 103.4,78.96 102.92,78.48 102.4,78.48 102.24,78.19 102.16,78.04 101.2,77.07 101.2,73.5 101.2,73.5 101.2,72.83 101.2,72.83 101.2,72.31 98.81,69.92 96.01,69.92 94.85,68.76 91.96,68.76 86.29,63.1 83.89,63.1 82.8,62 69.87,62 69.39,62.48 68.54,63.33 v2(66.37,63.33)
  BOTTOM w0.14: v2(66.37,63.33) 66.54,63.5 v1(66.99,63.5) 67.05,63.44 R6317.2 ; CPU1.V57 v2(112.71,85.4)
EMMC_DATA_7_R: length 8.7
  BOTTOM w0.076: 59.42,60.96 59.3,60.91 58.9,60.91 58.87,60.94 58.86,60.94 58.64,61.15 U6301.B6
  BOTTOM w0.14: 59.42,60.96 59.85,60.96 61.88,62.99 v1(64.68,62.99) 65.08,62.99 65.49,62.59 R6317.1
EMMC_E9: length 2.8
  TOP w0.14: TP6301.1 58.78,62.92 58.43,62.56 57.94,62.56 v2(57.56,62.94)
  BOTTOM w0.14: U6301.E9 57.27,62.65 v2(57.56,62.94)
EMMC_E10: length 1.8
  TOP w0.14: TP6302.1 58.17,63.27 57.87,63.57 v2(57.43,63.57)
  BOTTOM w0.14: v2(57.43,63.57) 57.43,63.54 57.06,63.18 U6301.E10
EMMC_F10: length 1.5
  TOP w0.14: v2(56.56,62.4) 56.56,62.7 56.83,62.97 TP6303.1
  BOTTOM w0.14: v2(56.56,62.4) 56.56,62.7 56.56,62.7 U6301.F10
EMMC_K10: length 1.6
  TOP w0.14: v2(54.12,63.54) 53.82,63.54 53.42,63.14 TP6304.1
  BOTTOM w0.14: v2(54.12,63.54) 54.5,63.15 U6301.K10
EMMC_RCLK: length 86.3
  TOP w0.14: v1(86.72,65.43) 86.55,65.43 86.32,65.2 R2017.2 85.82,66.18 v2(85.38,66.63) ; v2(56.4,58.04) 55.86,58.57 R6323.1 ; R2012.1 v2(114.7,86.2)
  L3 w0.127: v2(62.69,67.24) 62.3,67.24 60.37,65.31 60.37,59.33 58.66,57.62 56.82,57.62 v2(56.4,58.04)
  L4 w0.127: v2(114.7,86.2) 114.03,86.61 113.72,86.79 112.9,87.61 112.9,88.51 112.9,88.57 112.65,88.81 112.59,88.81 110.06,88.81 108.64,87.39 107.02,87.39 106.35,86.72 105.82,86.72 105.62,86.92 105.06,86.92 104.17,86.04 104.17,85.64 100.46,81.93 100.46,80.88 96.75,77.16 96.16,77.16 94.06,75.06 93.81,74.81 93.81,73.04 93.08,72.3 92.46,72.3 87.62,67.46 86.77,67.46 85.94,66.63 v2(85.38,66.63) 84.59,65.84 83.87,65.84 83.76,65.84 81.96,64.04 71.56,64.04 69.31,66.28 63.79,66.28 63.16,66.91 62.84,67.24 v2(62.69,67.24)
  BOTTOM w0.14: CPU1.V54 v2(114.7,86.2)
EMMC_RCLK_R: length 3.2
  TOP w0.14: v1(57.36,59.92) 57.11,59.67 56.83,59.67 56.62,59.46 R6323.2 55.66,60.05 v2(55.76,60.15)
  BOTTOM w0.14: U6301.H5 55.56,60.35 v2(55.76,60.15)
EMMC_RCLK_RC: length 1.7
  TOP w0.14: EC2002.1 R2017.1 84.93,64.33 v1(84.89,64.29)
EMMC_RCOMP: length 2.1
  TOP w0.508: v2(111.38,85) R2008.2 v1(109.97,84.22)
  BOTTOM w0.305: CPU1.V59 v2(111.38,85)
EMMC_RESET#: length 13.8
  TOP w0.14: R2118.2 64.49,59.31 R2119.1 64.51,59.22 63.84,58.55 61.48,58.55 Q6301.S 61.01,58.08 59.33,58.08 58.76,58.65 58.76,59 R2125.1 R6312.1 58.24,60.45 57.39,60.45 57.22,60.62 v1(55.43,60.62) 55.26,60.62 v2(54.8,60.15)
  BOTTOM w0.14: v2(54.8,60.15) 54.56,60.38 U6301.K5
EMMC_RST_N: length 101.3
  TOP w0.14: R2118.1 65.37,60.92 v1(65.14,61.16) 64.78,61.52 63.63,61.52 v2(63.41,61.75)
  L3 w0.127: v2(62.14,71.5) 64,69.64 64,64.54 63.32,63.85 63.32,61.84 v2(63.41,61.75)
  L4 w0.127: v2(123.38,93.65) 122.05,94.69 121.67,99.52 121.59,100.12 116.6,105.11 111.02,105.11 110.47,105.66 110.11,105.66 109.19,105.66 108.56,106.29 103.93,106.29 103.2,105.56 102.2,105.56 100.38,103.74 100.38,101.6 100.69,101.29 100.69,98.52 93.41,91.24 93.41,91.2 93.03,90.81 92.67,90.32 92.43,89.98 92.08,89.49 92.08,89.49 91.58,88.79 91.39,88.52 91.32,88.41 91.03,87.76 90.72,87.45 90.4,86.9 90.04,86.27 89.91,86.09 89.61,85.31 83.03,78.73 80.55,76.77 73.7,74.02 73.46,73.96 71.1,73.28 69.83,72.15 63.29,72.15 62.64,71.5 v2(62.14,71.5)
  BOTTOM w0.14: CPU1.L30 v2(123.38,93.65)
EMMC_VCC: length 12.7
  TOP w0.508: v2(54.06,62.9) 54.33,62.64 54.34,62.64 54.65,62.33 54.88,62.33 56.02,61.2 v2(56.53,61.2) 56.82,61.2 57.5,61.88 C6305.1 58.31,61.3 58.63,60.99 v1(59.65,60.99) 60.33,61.67 C6302.1 R6327.1
  BOTTOM w0.356: U6301.E6 57.02,61.2 v2(56.53,61.2) 56.53,60.68 U6301.F5 ; U6301.J10 55.06,63 54.71,62.65 U6301.K9 54.31,62.65 v2(54.06,62.9)
EMMC_VCCQ: length 19
  TOP w0.508: v1(52.71,60.66) 52.92,60.45 C6303.1 52.67,59.76 52.38,59.46 51.85,59.46 v2(51.77,59.54) 51.7,59.54 50.35,60.89 C6304.1 R6322.1
  L3 w0.508: v2(51.77,59.54) 51.81,59.5 52.77,59.5 53.48,60.2 v2(54.09,60.2) 54.09,59.68 54.64,59.13 56.98,59.13 57.56,59.71 v2(57.56,60.94)
  BOTTOM w0.356: U6301.C6 57.77,61.15 v2(57.56,60.94) ; U6301.P3 52.54,59.63 52.36,59.63 52.18,59.46 51.86,59.46 v2(51.77,59.54) 51.77,59.54 51.44,59.86 51.44,60.37 51.79,60.71 52.14,60.71 52.15,60.69 52.23,60.69 52.28,60.65 U6301.P5 ; U6301.N4 U6301.M4 54.04,60.15 54.08,60.2 v2(54.09,60.2)
EMMC_VDDI: length 2.8
  TOP w0.14: C6301.1 57.96,58.28 v2(58.15,58.09) 58.68,58.09 v1(58.71,58.12)
  BOTTOM w0.076: U6301.C2 58.06,59.14 58.3,58.9 58.3,58.25 v2(58.15,58.09)
FALL_INT2: length 4.4
  TOP w0.152: Q7001.3 166.33,83.51 R7006.2 166.34,82.82 v1(166.12,82.6) 165.79,82.6 165.54,82.86 Q7001.2
FAN1_DAC_1: length 2.8
  BOTTOM w0.203: KBC24.101 156.57,55.52 156.29,55.25 TP2408.1
FAN_TACH1: length 4.3
  BOTTOM w0.203: KBC24.31 172.25,68.8 172.55,69.1 172.55,69.12 172.68,69.12
  BOTTOM w0.254: TP2410.1 174.43,69.14 172.7,69.14 172.68,69.12
FB_VCCGI: length 45.7
  TOP w0.254: v2(138.62,116.38) 138.69,116.31 138.69,115.11 137.42,113.84 137.42,109.66 137.01,109.25 137.01,108.69 v2(136.79,108.46)
  L4 w0.254: v2(136.79,108.46) 136.79,108.28 136.86,108.12 136.86,107.26 134.78,105.18 134.78,104.13 134.49,103.69 134.03,103 133.68,102.43 133.58,102.28 132.43,101.14 132.36,101.08 130.4,99.56 130.05,99.21 129.96,99 129.85,98.78 129.45,98.38 129.45,97.26 129.24,96.35 128.68,95.8 128.2,95.8 127.42,95.55 127.11,95.13 127.06,95.05 126.97,94.73 126.95,94.67 126.95,93.87 126.42,92.73 125.83,91.46 125.78,91.35 125.78,91.12 125.64,90.98 125.32,90.86 124.85,90.86 122.24,89.91 122,89.68 121.7,89.57 120.55,89.57 119.95,89.85 v2(118.85,89.87)
  BOTTOM w0.254: PR5005.1 142.26,120.8 v1(141.92,120.46) 140.69,119.23 140.25,119.23 138.74,117.72 138.74,116.51 v2(138.62,116.38) ; v2(118.85,89.87) 118.9,89.87 CPU1.R41
FB_VNN: length 126.6
  TOP w0.254: v2(126.37,131.19) 126.37,131.71 133.1,138.43 146.35,138.43 146.81,137.97 155.05,137.97 v1(155.86,138.79) 156.19,139.12 v2(157.59,139.12)
  L3 w0.203: v2(118.96,83.59) 119.25,83.35 119.3,83.32 119.74,83.25 120.11,83.25 120.15,83.27 121.13,83.62 121.31,83.62 122.27,84.02 122.37,84.11 124.31,84.83 124.78,84.83 126.6,85.15 126.85,85.39 127.49,85.65 127.91,85.65 127.91,85.64 129.7,85.64 129.99,85.94 130.75,86.05 131.47,86.05 131.86,85.66
  L3 w0.254: v2(157.59,139.12) 157.82,139.12 158.71,138.23 158.71,136.82 159.21,136.32 159.21,98.28 153.12,92.19 150.68,92.19 143.16,84.66 141.99,84.66 139.75,86.89 138.23,86.89 138.09,87.03 136.14,87.03 136.02,86.99 134.47,86.99 133.14,85.66 131.86,85.66
  BOTTOM w0.203: CPU1.AG48 v2(118.96,83.59)
  BOTTOM w0.254: PR5035.2 126.4,131.17 v2(126.37,131.19)
FBL_VCCGI: length 16.7
  TOP w0.203: PG5101.1 v2(122.64,111.74)
  BOTTOM w0.254: v2(122.64,111.74) 123.93,111.74 124.44,112.24 124.44,121.34 124.14,121.64 124.14,124.41 v1(124.49,124.76) 124.87,125.15 PR5004.1
FBL_VDDQ: length 149.1
  TOP w0.254: v2(127.46,138.2) v1(127.9,138.64)
  L3 w0.254: v2(74.2,47.09) 74,47.09 73.79,46.89 72.96,46.89 70.64,49.2 70.64,53.77 70.26,54.15 70.26,59.72 70.82,60.28 70.82,63.35 72.23,64.75 72.23,67.03 78.1,72.91 78.36,73.17 80.52,73.17 81.09,73.74 81.79,73.74 93.14,85.08 93.14,87.68 95.9,90.44 96.7,90.44 98.37,92.1 99.06,92.8 99.97,93.71 100.69,93.71 101,94.01 101.03,94.01 104.57,97.56 104.57,99.92 105.25,100.6 105.25,101.02 105.03,101.23 105.03,101.24 103.77,102.8 101.07,105.21 100.54,106.47 100.31,106.7 100.31,107.02 100.24,107.1 100.24,108.74 100.31,108.82 100.31,111.42 100.36,111.47 100.36,118.26 99.58,119.05 99.58,132.78 99.58,133.63 108.19,142.24 122.1,142.24 126.14,138.2 v2(127.46,138.2)
  BOTTOM w0.254: v2(127.46,138.2) 131.35,138.2 131.88,137.67 PR5001.2 ; v2(74.2,47.09) 74.63,46.66 PG5102.1
FBL_VNN: length 36.2
  TOP w0.203: PG5103.1 108.13,112.85 108.24,112.75 v2(108.34,112.75)
  L4 w0.254: v2(123.48,122.35) 123.71,122.13 123.71,115.7 119.94,111.94 111.31,111.94 110.5,112.75 v2(108.34,112.75)
  BOTTOM w0.254: PR5034.2 126.05,132.01 123.98,129.94 123.98,126.8 123.48,126.29 v1(123.48,125.77) v2(123.48,122.35)
FFS_INT2: length 128.8
  TOP w0.152: v2(149.79,110.97) 150.72,110.97 156.9,104.79 156.9,103.94 158.02,102.82 158.02,93.14 161.8,89.36 161.8,88.91 161.8,85.92 161.07,85.19 159.54,85.19 158.66,84.32 158.66,83.41 158.96,83.11 R7011.1 159.15,83.12 R7007.2 160.71,83.12 R7010.1 161.26,83.45 161.86,82.86 Q7001.5 163.58,82.86 163.76,82.68 163.76,82.02 164.03,81.75 165.74,81.75 166.21,82.22 168.18,82.22 168.65,81.75 169.14,81.75 176.17,74.72 176.17,70.32 174.53,68.68 174.53,63.37 176.38,61.52 176.38,59.47 175.67,58.76 175.67,55.62 177.8,53.49 177.8,49.02 v1(177.95,48.87) 177.95,48 177.34,47.39 176.67,47.39 176.63,47.43 U7001.11
  L4 w0.152: v2(123.57,101.06) 124.04,101.06 125.32,99.79 125.93,99.79 126.16,99.56 126.54,99.56 126.85,99.88 126.85,99.92 126.87,99.94 126.93,100.1 126.94,100.11 127.13,100.62 127.18,100.68 127.2,100.72 127.24,100.76 127.77,101.48 127.95,101.84 127.95,104.47 128,104.51 128,108.25 127.99,108.36 127.98,108.49 127.98,108.5 127.97,108.57 127.97,108.74 128.01,108.78 128.01,108.78 128.19,109.01 128.2,109.04 129.97,110.82 133.38,110.82 133.51,110.68 133.89,110.68 133.91,110.7 139,110.7 139.53,110.16 143.73,110.16 144.24,110.67 149.49,110.67 v2(149.79,110.97)
  BOTTOM w0.152: v2(123.57,101.06) 123.31,100.8 123.31,99.07 123.34,99.01 123.45,98.71 123.58,98.58 CPU1.A26
FFS_INT2_Q: length 53.1
  TOP w0.152: R7009.2 161.04,81.68 R7010.2 161.64,82.56 162,82.21 Q7001.6 162.69,81.71 162.97,81.43 166,81.43 166.38,81.82 v1(167.98,81.82) 168.16,81.82 v2(168.74,81.23)
  L4 w0.152: v2(171.23,44.6) 171.23,44.97 172.65,46.39 172.65,52.94 171.51,54.07 171.51,55.57 171.15,55.93 171.15,57.76 170.54,58.37 170.54,60.59 171.94,61.99 171.94,65.08 170.82,66.19 170.82,68.74 170.06,69.5 170.06,71.65 170.24,71.82 170.24,72.2 170.06,72.38 170.06,72.45 168.98,73.53 168.98,76.91 168.74,77.15 v2(168.74,81.23)
  BOTTOM w0.152: v2(171.23,44.6) 171.34,44.71 173.46,44.71 173.8,45.05 HDD1.1
GFX_CLKREQ_CPU#: length 4.7
  BOTTOM w0.102: RN1606.2 108.07,79.11 108.36,79 v1(109.1,78.74) 109.98,78.82 110.44,79 111.82,79.78 CPU1.AK62
GP_SSP0_FS1: length 103.9
  TOP w0.102: R9909.2 46.18,61.67 45.8,61.29 39.79,61.29 38.74,62.34 v1(38.74,63.88) 38.74,67.26 v2(38.84,67.36)
  L4 w0.127: v2(38.84,67.36) 38.95,67.36 39.44,67.86 48.81,67.86 49.77,68.82 57.32,68.82 58.19,67.96 63.57,67.96 64.74,66.79 69.52,66.79 71.77,64.54 81.74,64.54 85.26,68.06 86.7,69.5 88.45,69.5 89.33,70.37 89.33,71.23 93.05,74.95 93.05,75.13 93.81,75.89 94.5,76.58 98.55,80.63 98.55,81.75 100.63,83.83 100.63,84.94 101.75,86.06 101.75,86.44 102.31,87 102.31,87.33 103.1,88.13 103.43,88.13 104.69,89.39 106.72,89.39 107.95,90.62 108.13,90.62 109.01,91.5 109.4,91.5 110,90.9 111.95,90.9 112.34,91.29 v2(112.6,91.29)
  BOTTOM w0.102: CPU1.H52 v2(112.6,91.29)
GP_SSP2_TXD: length 110
  TOP w0.102: v2(41.51,68.84) 42.02,69.34 42.02,71.99 45.78,75.74 v1(51.16,75.74) 51.4,75.99 53.89,75.99 54.59,75.29 R9930.2 ; R1526.1 v2(107.19,90.66)
  L3 w0.127: v2(107.19,90.66) 106.55,91.3 103.03,91.3 102.72,91.31 102.12,91.31 100.02,89.21 100.02,82.82 90.3,73.1 v2(88.93,73.1)
  L4 w0.127: v2(88.93,73.1) 88.78,73.1 86.7,71.02 86.07,71.02 84.8,69.75 84.63,69.59 84.47,69.42 84.37,69.32 83.74,68.69 83.74,68.69 81.89,66.84 80.02,66.84 78.96,67.9 78.93,67.9 78.58,68.15 78.49,68.24 77.37,68.24 77.37,68.24 76.13,68.24 76.13,68.24 73.9,68.24 73.9,68.24 72.88,68.24 71.83,67.19 64.7,67.19 63.68,68.21 60.47,68.21 59.6,69.08 49.67,69.08 48.84,68.24 44.4,68.24 43.81,68.84 v2(41.51,68.84)
  BOTTOM w0.102: R1525.2 102.75,93.78 103.08,92.59 103.45,92.22 104.48,92.22 106.04,90.66 v2(107.19,90.66) 107.25,90.71 107.25,90.83 107.47,91.1 107.6,91.18 107.75,91.18 CPU1.E62
GPIO34_CPU: length 3.8
  BOTTOM w0.102: CPU1.B41 117.02,95.93 116.9,96.26 116.74,96.42 116.29,97.67 115.86,98.25 TP2105.1
GPIO35_CPU: length 2.9
  TOP w0.102: TP2104.1 v2(118.44,93.41)
  BOTTOM w0.102: CPU1.C41 117.93,94.8 118.1,94.34 v2(118.44,93.41)
GPIO36_VCCIO_LEVEL: length 31.7
  L4 w0.127: v2(102.95,102.67) 103.51,102.67 103.55,102.71 104.04,102.71 104.17,102.58 104.53,102.58 104.75,102.8 105.4,102.8 106.38,103.77 107.7,103.77 108.2,103.27 109.12,103.27 109.48,103.27 110.03,102.72 112.54,102.72 113.06,102.72 114.44,101.34 115.19,101.34 115.48,101.04 115.64,101.04 117.36,99.32 117.37,99.31 117.37,98.4 117.59,97.79 117.59,94.36 v2(117.36,93.86)
  BOTTOM w0.102: R1501.2 100.81,108.31 R1502.1 101.96,108.42 v1(101.96,103.81) 102.95,102.82 v2(102.95,102.67) ; v2(117.36,93.86) 117.4,93.84 117.44,93.85 CPU1.F41
GPIO39_TXE_BPS: length 31.4
  L4 w0.127: v2(112.63,100.76) 112.56,100.76 112.15,101.16 110.61,101.16 110.34,100.88 108.49,100.88 107.94,101.43 105.21,101.43 105.09,101.31 104.61,101.31 104.24,100.94 104.24,100.9 v2(104.05,100.71)
  BOTTOM w0.102: CPU1.B45 115.5,95.63 115.28,96.25 114.38,97.61 114.27,97.77 114.08,98.64 114.08,99.19 114.01,99.65 114.01,99.79 113.78,100.36 113.41,100.76 113.27,100.76 113.06,100.78 112.66,100.78 v2(112.63,100.76) ; R1503.2 99.91,108.14 R1504.1 99.27,108.78 99.27,109.49 99.56,109.78 100.18,109.78 100.44,110.03 101.13,110.03 102.19,108.97 102.19,104.17 103.44,102.92 v1(103.44,101.17) 103.89,100.71 v2(104.05,100.71)
GPIO40_CPU: length 3.4
  BOTTOM w0.102: TP1804.1 113.84,96.99 114.59,96.29 114.76,95.8 CPU1.A46
GPIO43_EMMC_BOOT: length 33.3
  L4 w0.127: v2(104.05,101.37) 104.24,101.56 104.98,101.56 105.2,101.78 108.13,101.78 108.38,102.03 108.96,102.03 109.51,101.47 112.54,101.47 113.93,100.09 114.55,100.09 115.45,99.19 115.45,98.38 115.58,98.25 115.83,97.57 115.83,97.25 v2(115.61,96.77)
  BOTTOM w0.102: v2(115.61,96.77) 116,96.59 116.27,96.32 116.36,96.06 CPU1.B43 ; R1801.1 99.04,107.43 R1521.2 R1505.1 98.41,108.29 99.04,108.92 99.04,109.63 99.42,110 v1(99.42,110.14) 99.55,110.26 101.22,110.26 102.42,109.06 102.42,104.26 103.66,103.02 103.66,101.81 104.05,101.42 v2(104.05,101.37)
GPIO44_SPI_BOOT: length 33.5
  L4 w0.127: v2(115.2,98.01) 115.2,99.08 114.48,99.8 109.21,99.8 107.84,101.18 105.8,101.18 105.4,100.78 104.89,100.78 104.87,100.81 v2(104.74,100.81)
  BOTTOM w0.102: v2(115.2,98.01) 115.89,97.68 116.24,97.11 CPU1.A42 ; v2(104.74,100.81) 104.54,101.01 104.54,102.15 103.89,102.8 103.89,103.11 102.65,104.36 102.65,109.16 101.32,110.49 97.94,110.49 v1(97.59,110.15) 96.86,109.41 96.86,108.7 R1507.1 97.26,108.19 R1506.2
GPIO47_DNXFW: length 119.3
  TOP w0.102: R1802.1 65.64,44.82 77.7,56.87 79.79,56.87 80.22,57.3 80.22,59.34 82.61,61.73 82.61,65.83 82.03,66.41 82.03,67.64 82.06,67.68 82.06,69.68 81.67,70.08 81.67,71.73 82.71,72.77 v2(82.71,73.79)
  L4 w0.127: v2(117.59,93.22) 117.84,93.71 117.84,97.93 117.62,98.54 117.62,99.42 117.62,99.43 115.75,101.3 115.59,101.3 115.3,101.59 114.55,101.59 113.16,102.97 112.43,102.97 110.14,102.97 109.58,103.53 109.22,103.53 108.31,103.53 107.79,104.04 106.28,104.04 105.5,103.25 104.6,103.25 104.38,103.02 v2(104.35,103.02) 104.33,103.02 104.24,103.11 102.77,103.11 102.51,102.85 102.51,102.48 102.82,102.17 102.82,97.63 97.09,91.89 97.09,90.91 95.5,89.32 95.5,89.15 94.3,87.95 94.3,87.4 92.91,86 92.2,85.3 91.85,84.48 91.79,84.42 84.58,77.21 84.58,77.21 83.23,75.86 83.23,74.31 v2(82.71,73.79)
  BOTTOM w0.102: v2(104.35,103.02) 102.88,104.5 102.88,109.25 101.41,110.72 96.17,110.72 v1(96.06,110.61) 95.49,110.04 95.49,108.51 95.75,108.24 R1508.1 R1509.2 ; CPU1.H41 v2(117.59,93.22)
GPIO78_SMB_LEVEL: length 17.5
  TOP w0.102: v2(105.32,94.01) 105.32,93.27 105.83,92.76 106.02,92.67 106.46,92.23 106.46,90.43 108.07,88.82 v2(108.28,88.23) 107.96,87.8 v1(107.7,87.74) 107.09,87.74 106.54,87.87 106.24,87.88 105.54,87.68 105.04,87.32 R1510.1
  BOTTOM w0.102: R1522.2 103.07,94.43 103.09,94.29 103.28,94.1 103.31,93.88 103.42,93.25 103.42,93.24 103.56,92.91 103.83,92.64 104.34,92.64 104.96,93.26 104.96,93.65 v2(105.32,94.01) ; CPU1.K62 v2(108.28,88.23)
GPIO82_CPU: length 2.9
  TOP w0.102: TP1901.1 v2(111.91,88.12)
  BOTTOM w0.102: CPU1.M55 112.31,88.89 112.17,89.03 111.87,89.03 111.59,88.75 111.59,88.44 v2(111.91,88.12)
GPIO88_PMU_LEVEL: length 14.2
  TOP w0.102: v2(106.3,94.8) 105.77,94.28 105.77,93.17 106.09,92.86 106.24,92.77 106.38,92.67 106.65,92.4 106.65,92.26 106.69,90.76 106.82,90.46 108.07,89.21 v1(109.06,88.77) R1511.1 110.32,88.06 v2(111.23,87.87)
  BOTTOM w0.102: v2(106.3,94.8) 105.96,94.8 105.66,95.1 105.54,95.34 105.54,95.44 105.48,95.63 105.47,95.63 105.39,95.87 105.21,96.34 105.21,96.54 105.28,96.64 R1523.2 ; v2(111.23,87.87) CPU1.M58
GPIO92_SMB_NRB: length 14.6
  TOP w0.102: v2(104.96,92.51) 105.87,92.51 106.24,92.18 106.26,92 106.26,89.87 107.11,89.01 v2(107.11,88.37) 106.53,88.32 v1(106.48,88.32) 106.33,88.32 R1513.1
  BOTTOM w0.102: v2(104.96,92.51) 104.94,92.52 104.53,92.52 104.46,92.45 103.55,92.45 103.29,92.71 103.28,92.74 103.06,93.99 102.72,94.34 102.39,94.89 102.39,95.36 ; v2(107.11,88.37) 107.67,87.82 108.45,87.82 CPU1.L63
GPIO110_LPC_LEVEL: length 13.7
  BOTTOM w0.102: CPU1.J52 113.5,90.17 113.25,89.93 113.25,89.9 113.07,89.73 112.82,89.73 112.39,90.16 111.92,90.85 111.57,91.98 111.57,92.53 111.95,92.91 111.95,93.01 111.97,93.09 112.01,93.24 112.01,93.35 112,93.47 111.87,93.54 111.73,93.69 111.73,93.88 111.74,93.91 111.74,94.05 111.67,94.31 111.49,94.54 110.76,95.38 109.99,97.07 v1(109.63,97.97) 109.28,98.95 109.22,99.14 109.17,99.31 109.15,99.31 109.15,99.34 109.11,99.45 109.1,99.52 R1524.2 R1516.1
GPIO111_BBS: length 8.9
  TOP w0.102: v2(106.84,94.48) 107.11,93.16 107.26,93.01 v1(107.59,92.68) 107.9,92.37 v2(109.22,91.05) 109.25,91.09 110.38,91.09 R1515.1
  BOTTOM w0.102: v2(106.84,94.48) 106.84,94.6 106.76,94.68 106.76,94.94 106.49,95.21 106.23,95.21 R1514.2 ; v2(109.22,91.05) 109.3,91.14 109.75,91.14 109.75,91.14 110.21,91.14 CPU1.F58
GPIO118_FLASH_OVR: length 13
  TOP w0.102: v2(105.82,89.83) v1(105.65,89.26) R1517.1
  BOTTOM w0.102: CPU1.F62 108.08,90.54 107.83,90.54 107.7,90.47 107.48,90.2 107.11,89.83 v2(105.82,89.83) 105.82,90.53 104.45,91.9 103.45,91.9 102.86,92.49 102.5,93.4 102.12,93.88 101.05,94.25 101.19,93.79 R1909.1
GPIO120_BIOS_SWAP: length 7.6
  TOP w0.102: R1519.1 111.17,91.9 110.52,91.9 v2(110.47,91.95) 110.42,92 110.42,92.01 v1(109.87,92.56) 108.9,93.53 108.9,94.2 108.89,94.21 v2(108.89,94.32)
  BOTTOM w0.102: v2(108.89,94.32) 108.61,94.32 108.59,94.34 108.09,94.34 107.83,94.59 107.83,95.09 107.41,95.51 107.03,95.51 R1520.2 ; CPU1.E56 110.6,91.83 v2(110.47,91.95)
GPIO_RCOMP: length 2.5
  TOP w0.203: 120.82,94.18 120.62,94.7 120.47,94.85 v1(120.41,95.26) 120.47,95.62 v2(120.69,95.84)
  BOTTOM w0.203: CPU1.E34 v2(120.69,95.84)
GSENSOR_CS: length 2.6
  TOP w0.102: U7001.2 175.06,49.29 v1(175.17,49.39) 175.58,49.81 175.83,49.81 176.31,50.29 R7001.2
GSENSOR_SDO: length 3.5
  TOP w0.102: U7001.3 174.56,48.64 173.84,49.35 v1(173.84,49.51) 173.84,49.84 174.3,50.29 R7005.2 R7004.2
H_A20GATE: length 4
  BOTTOM w0.102: KBC24.121 157.86,63.52 157.03,62.69 156.37,62.69 v1(156.17,62.89) 155.79,63.27 R2445.2
H_PROCHOT#: length 203.8
  TOP w0.102: v2(170.24,153.48) 170.24,153.09 169.87,152.72 PR4426.2 169.4,152.69 169.4,152.2 168.94,151.74 168.94,149.4 169.18,149.16 PR4466.2 ; PR4465.1 176.96,161.15 176.69,160.88 v2(176.69,160.86) ; v2(172.44,72.95) 172.4,72.9 171.33,72.9 v1(171.28,72.94) 170.97,73.25 166.75,77.47 165.53,77.47 165.15,77.86 161.11,77.86 161.1,77.85 160.99,77.85 160.85,77.71 159.67,77.71 159.44,77.93 157.7,79.68 157.7,82.6 157.7,83.29 156.89,84.1 154.81,86.18 154.81,86.18 153.65,87.34 153.65,89.18 153.58,89.25 153.58,91.95 147.97,97.56 147.97,102.5 148.4,102.93 148.4,113.1 v2(148.24,113.26)
  L3 w0.127: v2(176.69,160.86) 176.69,157.96 173.62,154.89 171.54,154.89 170.24,153.59 v2(170.24,153.48)
  L4 w0.127: v2(123.76,108.46) 124.01,108.46 128.21,112.66 133.67,112.66 134.45,112.66 134.92,112.19 142.7,112.19 143.77,113.26 v2(148.24,113.26) ; v2(170.24,153.48) 171.24,153.48 174.42,150.31 174.42,144.54 174.56,144.4 174.56,135.45 173.54,134.44 173.54,129.31 169.74,125.52 169.74,93.12 169.29,92.66 169.29,88.81 169.82,88.28 169.82,78.4 171.11,77.1 171.11,73.22 171.38,72.95 v2(172.44,72.95)
  BOTTOM w0.102: Q2402.D 172.55,76.79 172.07,76.3 172.07,75 172.47,74.59 172.47,72.98 v2(172.44,72.95) ; v2(123.76,108.46) 123.46,107.7 122.91,105.54 116.41,102.84 R1809.1
H_PROCHOT_EC: length 9.7
  BOTTOM w0.102: Q2402.G 171.66,75.31 171.66,74.83 172.07,74.43 172.07,74.07 171.41,73.41 171.41,72.29 170.96,71.85 R2442.1 170.96,71.06 v1(170.7,70.79) 170.67,70.77 170.06,70.77 169.45,70.16 KBC24.24
H_RCIN#: length 3.5
  BOTTOM w0.102: KBC24.122 v1(157.11,63.92) 155.53,63.92 R2400.2
HDA_BITCLK_CPU: length 38.9
  TOP w0.14: R2107.2 90.98,62.83 v1(91.53,62.28) 91.72,62.09 94.78,62.09 v2(95.16,62.46)
  L4 w0.127: v2(95.16,62.46) 95.26,62.56 96.63,62.56 97.78,63.72 98.75,63.72 100.12,65.09 100.67,65.09 101.17,65.59 104.38,68.8 105.39,70.73 106.31,72.69 106.31,72.93 106.45,73.24 110.35,77.14 111.42,77.48 111.54,77.48 111.69,77.54 112.18,78.02 112.38,78.63 112.38,78.66 113.25,79.53 113.62,79.66 115.98,79.66 117.41,79.7 119.23,81.52 119.23,81.86 v2(119.24,81.86)
  BOTTOM w0.14: CPU1.AM48 v2(119.24,81.86)
HDA_CODEC_BITCLK: length 126.1
  TOP w0.14: R2107.1 EC2102.1 v1(90.09,61.28) 90.09,54.75 v2(89.72,54.38)
  L3 w0.127: v2(154.39,33.58) 154.21,33.76 154.21,33.77 153.91,34.06 153.91,34.06 153.89,34.08 148.33,34.08 143.8,29.54 124.4,29.54 123.68,30.27 120.88,30.27 120.03,29.42 105.41,29.42 104.65,30.18 102.22,30.18 101.41,29.37 84.09,29.37 81.39,32.07 81.39,35.17 81.11,35.45 81.11,39.63 88.35,46.87 88.35,53.01 v2(89.72,54.38)
  BOTTOM w0.14: HDA27.6 161.26,24.26 161.35,24.34 161.35,24.88 EC2708.1 160.88,25.46 159.77,26.56 159.77,27.51 158.89,28.39 158.89,28.68 156.9,30.67 155.83,30.67 154.6,31.89 154.6,33.36 v2(154.39,33.58)
HDA_CODEC_SDIN0: length 138.8
  TOP w0.14: R2121.2 103.78,65.03 R2101.1 103.78,64.28 102.57,63.07 v1(102.31,63.07) 99.22,63.07 v2(99.07,63.22)
  L3 w0.127: v2(153.68,35.51) 149.54,35.51 148.78,36.27 145.85,36.27 144.69,35.11 144.69,32.16 143.26,30.74 125.28,30.74 124.67,31.35 120.17,31.35 119.51,30.69 107.22,30.69 106.56,31.35 101.12,31.35 100.54,30.76 84.23,30.76 82.46,32.54 82.46,35.57 82.15,35.87 82.15,39.24 89.36,46.45 89.36,52.58 98.08,61.29 98.08,61.39 99.07,62.38 v2(99.07,63.22)
  BOTTOM w0.14: HDA27.8 162.06,25.35 161.91,25.5 161.91,25.85 161.91,25.85 R2721.2 161.92,26.53 162.44,27.05 162.44,28.17 161.65,28.96 161.61,29 160.55,29 160.25,29.29 159.47,29.29 157.24,31.52 156.67,31.52 155.65,32.55 155.65,33.59 153.73,35.51 v2(153.68,35.51)
HDA_CODEC_SDOUT: length 140.6
  TOP w0.14: R2104.1 105.34,64.42 v1(104.99,64.07) 103.13,62.21 97.67,62.21 v2(97.37,62.51)
  L3 w0.127: v2(97.37,62.51) 97.06,62.51 87.84,53.29 87.84,47.08 80.6,39.84 80.6,37.19 79,35.59 79,33.74 83.88,28.86 101.62,28.86 102.43,29.67 104.44,29.67 105.2,28.91 120.24,28.91 121.09,29.76 123.47,29.76 124.19,29.03 142.45,29.03 142.89,28.6 143.58,28.6 148.53,33.56 v2(153.7,33.56)
  BOTTOM w0.14: v2(153.7,33.56) 153.7,33.38 154.08,33 154.08,31.68 155.64,30.12 156.63,30.12 157.67,29.09 157.67,28.4 158.19,27.87 158.22,27.87 158.22,27.87 158.66,27.87 159.25,27.27 159.25,25.36 160.29,24.32 160.31,24.32 160.33,24.3 160.57,24.3 160.86,24.01 HDA27.5
HDA_CODEC_SYNC: length 145.1
  TOP w0.14: v2(98.44,63.16) 98.56,63.28 98.56,64.01 99.01,64.46 102.16,64.46 102.75,65.05 R2105.1
  L3 w0.127: v2(154.36,35.56) 153.86,35.05 149.64,35.05 148.68,36.02 145.95,36.02 144.94,35.01 144.94,32.03 143.36,30.46 124.97,30.46 124.38,31.04 120.5,31.04 119.87,30.41 106.94,30.41 106.33,31.02 101.43,31.02 100.85,30.43 84.11,30.43 82.2,32.34 82.2,35.46 81.87,35.79 81.87,39.32 89.11,46.56 89.11,52.69 97.82,61.4 97.82,61.57 98.44,62.18 v2(98.44,63.16)
  BOTTOM w0.14: HDA27.10 162.86,23.99 163.08,24.21 163.81,24.21 164.66,25.05 165.32,25.05 166.1,25.83 166.1,26.39 166.58,26.88 166.58,27.87 166.25,28.2 162.97,28.2 161.95,29.21 161.9,29.26 160.66,29.26 160.36,29.56 159.58,29.56 157.28,31.86 156.72,31.86 155.91,32.66 155.91,34.09 v1(154.86,35.14) 154.44,35.56 v2(154.36,35.56)
HDA_SDIN0_CPU: length 160.8
  TOP w0.14: v2(97.8,63.09) 97.87,63.09 98.41,62.55 102.76,62.55 104.48,64.26 v1(104.48,66.66) 104.48,67.52 110.04,73.08 110.04,75.92 110.43,76.72 110.85,77.14 111.82,77.57 112.15,77.9 112.66,78.87 113.26,79.55 114.32,80.33 114.88,80.88 v2(116.58,80.88)
  L3 w0.127: v2(97.8,63.09) 97.81,63.08 97.81,62.11 90.53,54.84 90.53,54.47 88.86,52.79 88.86,46.66 81.62,39.42 81.62,35.66 81.9,35.38 81.9,32.29 83.62,30.56 83.62,30.55 84.3,29.88 101.18,29.88 102.01,30.71 105.06,30.71 105.85,29.92 119.82,29.92 120.67,30.77 123.9,30.77 124.62,30.05 143.59,30.05 145.19,31.66 145.19,34.9 146.06,35.77 148.57,35.77 149.71,34.62 153.93,34.62 v2(153.96,34.6)
  BOTTOM w0.14: v2(116.58,80.88) 116.93,80.88 117.38,81.33 CPU1.AK51 ; v2(153.96,34.6) 154.21,34.6 155.13,33.68 155.13,32.11 156.05,31.19 156.68,31.19 156.68,31.19 157.12,31.19 159.27,29.03 160.14,29.03 160.44,28.73 161.37,28.73 161.91,28.2 R2721.1
HDA_SDOUT_CPU: length 19.9
  TOP w0.14: v2(115.35,80.42) 113.61,79.26 v1(113.08,78.73) 112.42,77.36 111.7,76.99 111.05,76.64 110.75,76.2 110.75,73.02 105.34,67.62 R2104.2
  BOTTOM w0.14: CPU1.AM54 115.88,80.46 115.78,80.46 v2(115.35,80.42)
HDA_SPKR: length 166.1
  TOP w0.254: v2(170.42,63.15) 170.31,63.04 167.19,63.04 166.78,62.64 155.56,62.64 154.87,61.95 154.87,60.91 154.46,60.5 152.93,60.5 152.56,60.88 152.56,61.6 152,62.16 150.91,62.16 148.61,59.86 v1(146.46,59.86) v2(142.95,59.86)
  L3 w0.254: v2(142.95,59.86) 142.04,58.96 142.04,50.9 142.73,50.22 v2(142.73,49.3)
  L4 w0.254: v2(114.48,81.09) 114.18,81.4 113.68,81.4 113.52,81.23 113.06,81.23 112.82,80.99 112.8,80.99 110.36,78.91 109.29,78.82 106.7,76.23 106.05,76.23 105.75,75.93 105.58,75.93 103.92,74.27 103.92,73.53 103.6,71.76 103.51,71.27 100.62,67.99 100.62,67.58 100.09,67.05 99.16,67.05 98.19,66.08 97.86,65.75 95.93,65.75 94.72,64.54 94.72,63.48 94.04,62.79 94.04,62.35 92.67,60.99 90.69,60.99 83.62,53.93 83.62,48.26 84.82,47.07 v2(85.3,47.07)
  BOTTOM w0.254: v2(85.3,47.07) 85.82,47.59 139.25,47.59 139.27,47.61 141.03,47.61 v2(142.73,49.3) ; v2(170.42,63.15) 170.41,63.15 169.9,63.65 169.9,64.49 171.05,65.64 171.62,65.64 172.77,66.79 173.35,66.79 174.68,68.12 176.38,68.12 177.07,68.81 R2718.1 ; CPU1.AK57 v2(114.48,81.09)
HDA_SPKR_R: length 3.2
  BOTTOM w0.254: D2701.2 177.27,73.11 v1(177.48,72.9) 177.48,72.14 177.07,71.73 R2718.2
HDA_SYNC_CPU: length 20.5
  TOP w0.14: v2(113.77,80.82) 113.7,80.59 113.12,80.01 v1(112.35,79.71) 109.51,76.87 109.51,73.84 103.61,67.94 R2121.1 R2105.2
  BOTTOM w0.14: CPU1.AK58 v2(113.77,80.82)
HDD_DEVSLP: length 108.8
  TOP w0.102: v2(163.87,86.98) 163.02,87.83 163.02,88.49 159.5,92.02 159.5,93.89 158.5,94.89 158.5,103.11 157.47,104.15 157.47,105.1 148.84,113.72 145.34,113.72 143.49,115.57 v2(143.49,115.95)
  L4 w0.102: v2(167.22,44.5) 167.22,45.21 166.4,46.03 166.4,47.7 166.43,47.73 166.43,48.09 166.4,48.11 166.4,50.21 165.11,51.5 165.11,54.2 164.42,54.89 164.42,55.44 164.73,55.75 164.73,56.08 165.3,56.66 165.3,58.39 164.8,58.89 164.8,65.56 164.37,65.99 164.37,68.27 164.07,68.58 164.07,71.48 163.81,71.74 163.81,72.65 164.19,73.02 164.19,73.3 164.31,73.43 164.31,76.04 164.37,76.11 164.37,76.52 164.31,76.58 164.31,78.89 163.56,79.65 163.56,81.67 163.56,83.61 163.38,83.78 163.38,84.42 163.33,84.47 163.33,86.44 v2(163.87,86.98)
  BOTTOM w0.102: R6001.1 168.89,44.01 167.71,44.01 v2(167.22,44.5) ; v2(143.49,115.95) 143.52,115.98 143.52,117.4 143.01,117.91 140.8,117.91 140.06,117.17 140.06,116.03 139.68,115.65 v1(139.4,115.65) 138.36,115.52 136.91,114.02 136.94,112.57 137.47,111.61 137.47,108.84 137.85,108.46 137.85,108.04 137.74,107.35 137.04,106.64 136.46,106.39 136.28,106.39 R2116.2 Q2101.D
HDD_DEVSLP_R: length 4.4
  BOTTOM w0.102: R6001.2 170.47,43.69 v1(170.95,43.21) 171.1,43.06 172.55,43.06 172.55,43.05 HDD1.5
HDD_DEW1: length 5
  BOTTOM w0.102: R6012.2 R6016.1 168.52,37.99 v1(168.21,38.31) 166.33,38.31 165.98,38.65 U6001.16
HDD_DEW2: length 4.9
  BOTTOM w0.102: U6001.6 163.62,43.2 163.33,43.49 163.33,44.35 162.38,45.3 R6020.1 R6022.2 160.68,45.3 v1(160.54,45.16)
HDD_FALL_INT: length 131.3
  TOP w0.152: v2(149.66,111.69) 149.33,111.36 149.33,110.55 157.74,102.15 157.74,93.02 161.52,89.24 161.52,86.04 160.96,85.47 159.42,85.47 158.7,84.75 158.67,84.75 158.38,84.47 158.38,83.09 158.83,82.64 158.83,82.22 159.93,81.13 168.1,81.13 168.69,80.55 169.95,80.55 175.89,74.6 175.89,70.44 174.25,68.8 174.25,63.26 176.05,61.46 176.05,59.63 175.39,58.98 175.39,55.5 177.42,53.48 v1(177.42,50.19) 177.52,50.09 177.52,48.34 R7008.2 176.97,47.93 U7001.12
  L4 w0.152: v2(124.75,106.89) 125.84,107.98 125.84,109.34 128.49,111.99 134.17,111.99 134.64,111.52 143.17,111.52 143.34,111.69 v2(149.66,111.69)
  BOTTOM w0.089: 117.8,98.68 117.81,98.64 118.09,98.13 118.25,97.66 118.66,96.98 118.66,96.98 118.79,96.85 118.87,96.65 118.88,96.62 118.89,96.59 118.91,96.52 118.91,96.48 CPU1.B37
  BOTTOM w0.152: 117.8,98.68 117.54,100.11 117.54,100.68 117.82,101.04 120.43,102.31 121.3,102.9 123.43,103.88 124.15,104.36 124.59,104.9 124.81,105.69 v2(124.75,106.89)
HDD_SATA_RX_N: length 65.1
  TOP w0.127: R6015.1 150.88,42.72 v2(150.83,42.78)
  L4 w0.114: v2(150.83,42.78) 151.14,43.08 151.54,43.08 152.1,43.64 152.1,45.51 148.13,49.48 147.1,50.52 147.1,62.32 147.66,62.88 147.66,66.95 144.41,70.2 144.41,77.25 144.7,77.54 145.58,78.41 145.58,79.01 145.57,79.01 145.57,86.3 142.07,89.81 140.54,91.06 140.5,91.07 139.64,91.4 139.6,91.42 138.47,91.89 137.87,92.58 137.42,93.69 137.23,93.84 136.26,94.61 136.13,94.72 135.8,94.87 135.75,94.89 135.32,95.05 135.3,95.05 135.15,95.07 135.14,95.07 134.61,95.07 134.54,95.14 v2(134.54,95.35)
  BOTTOM w0.127: CPU1.T7 v2(134.54,95.35) ; R6015.1 150.88,42.72 v2(150.83,42.78)
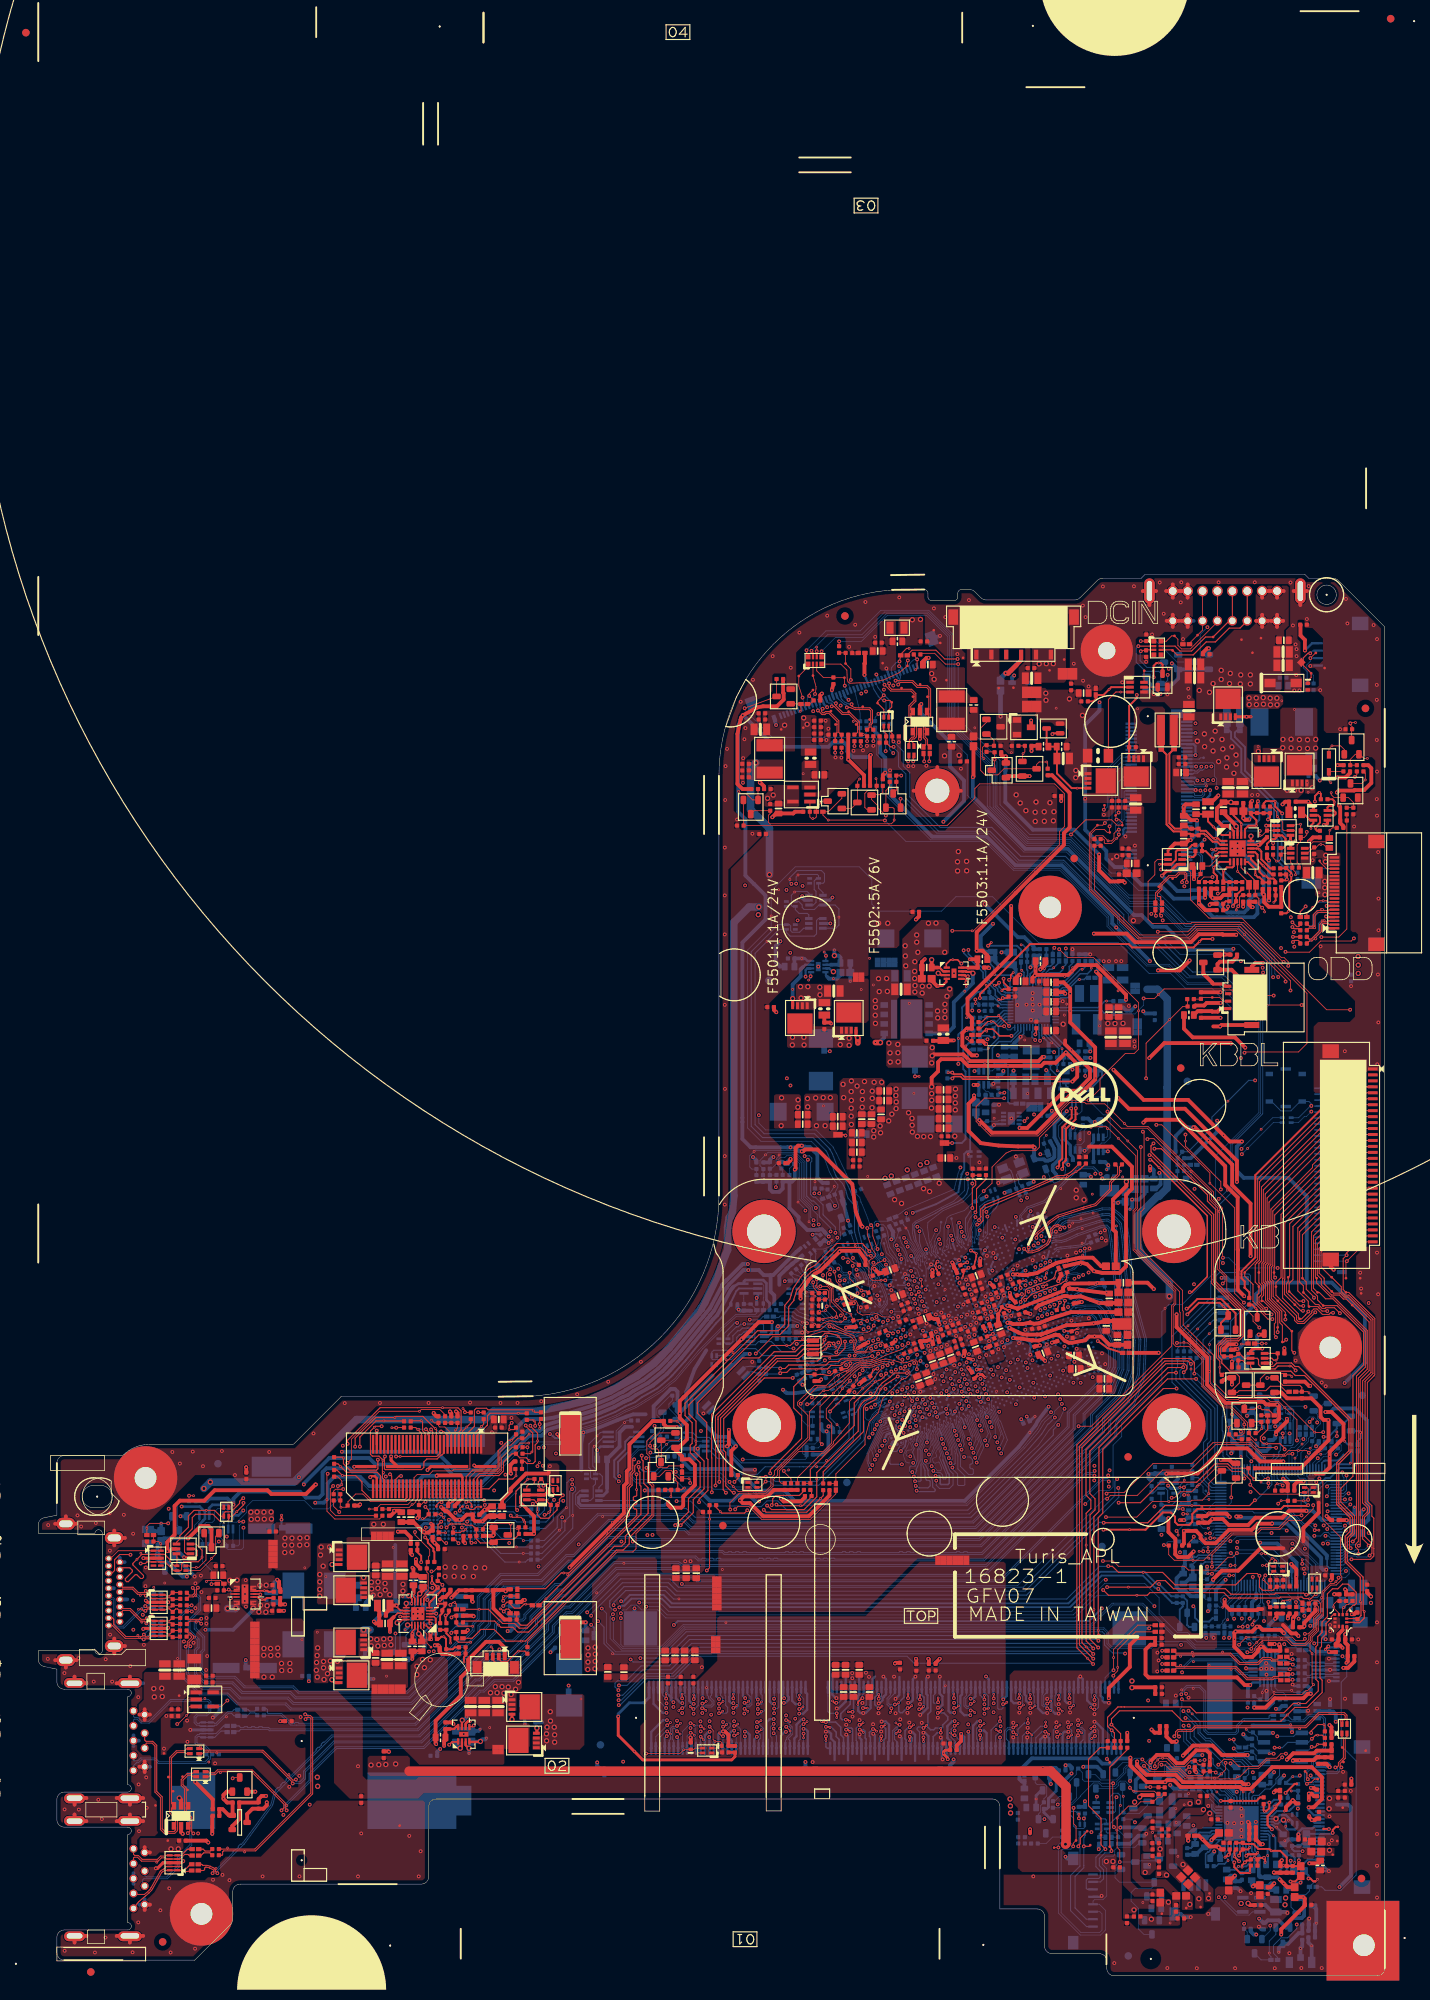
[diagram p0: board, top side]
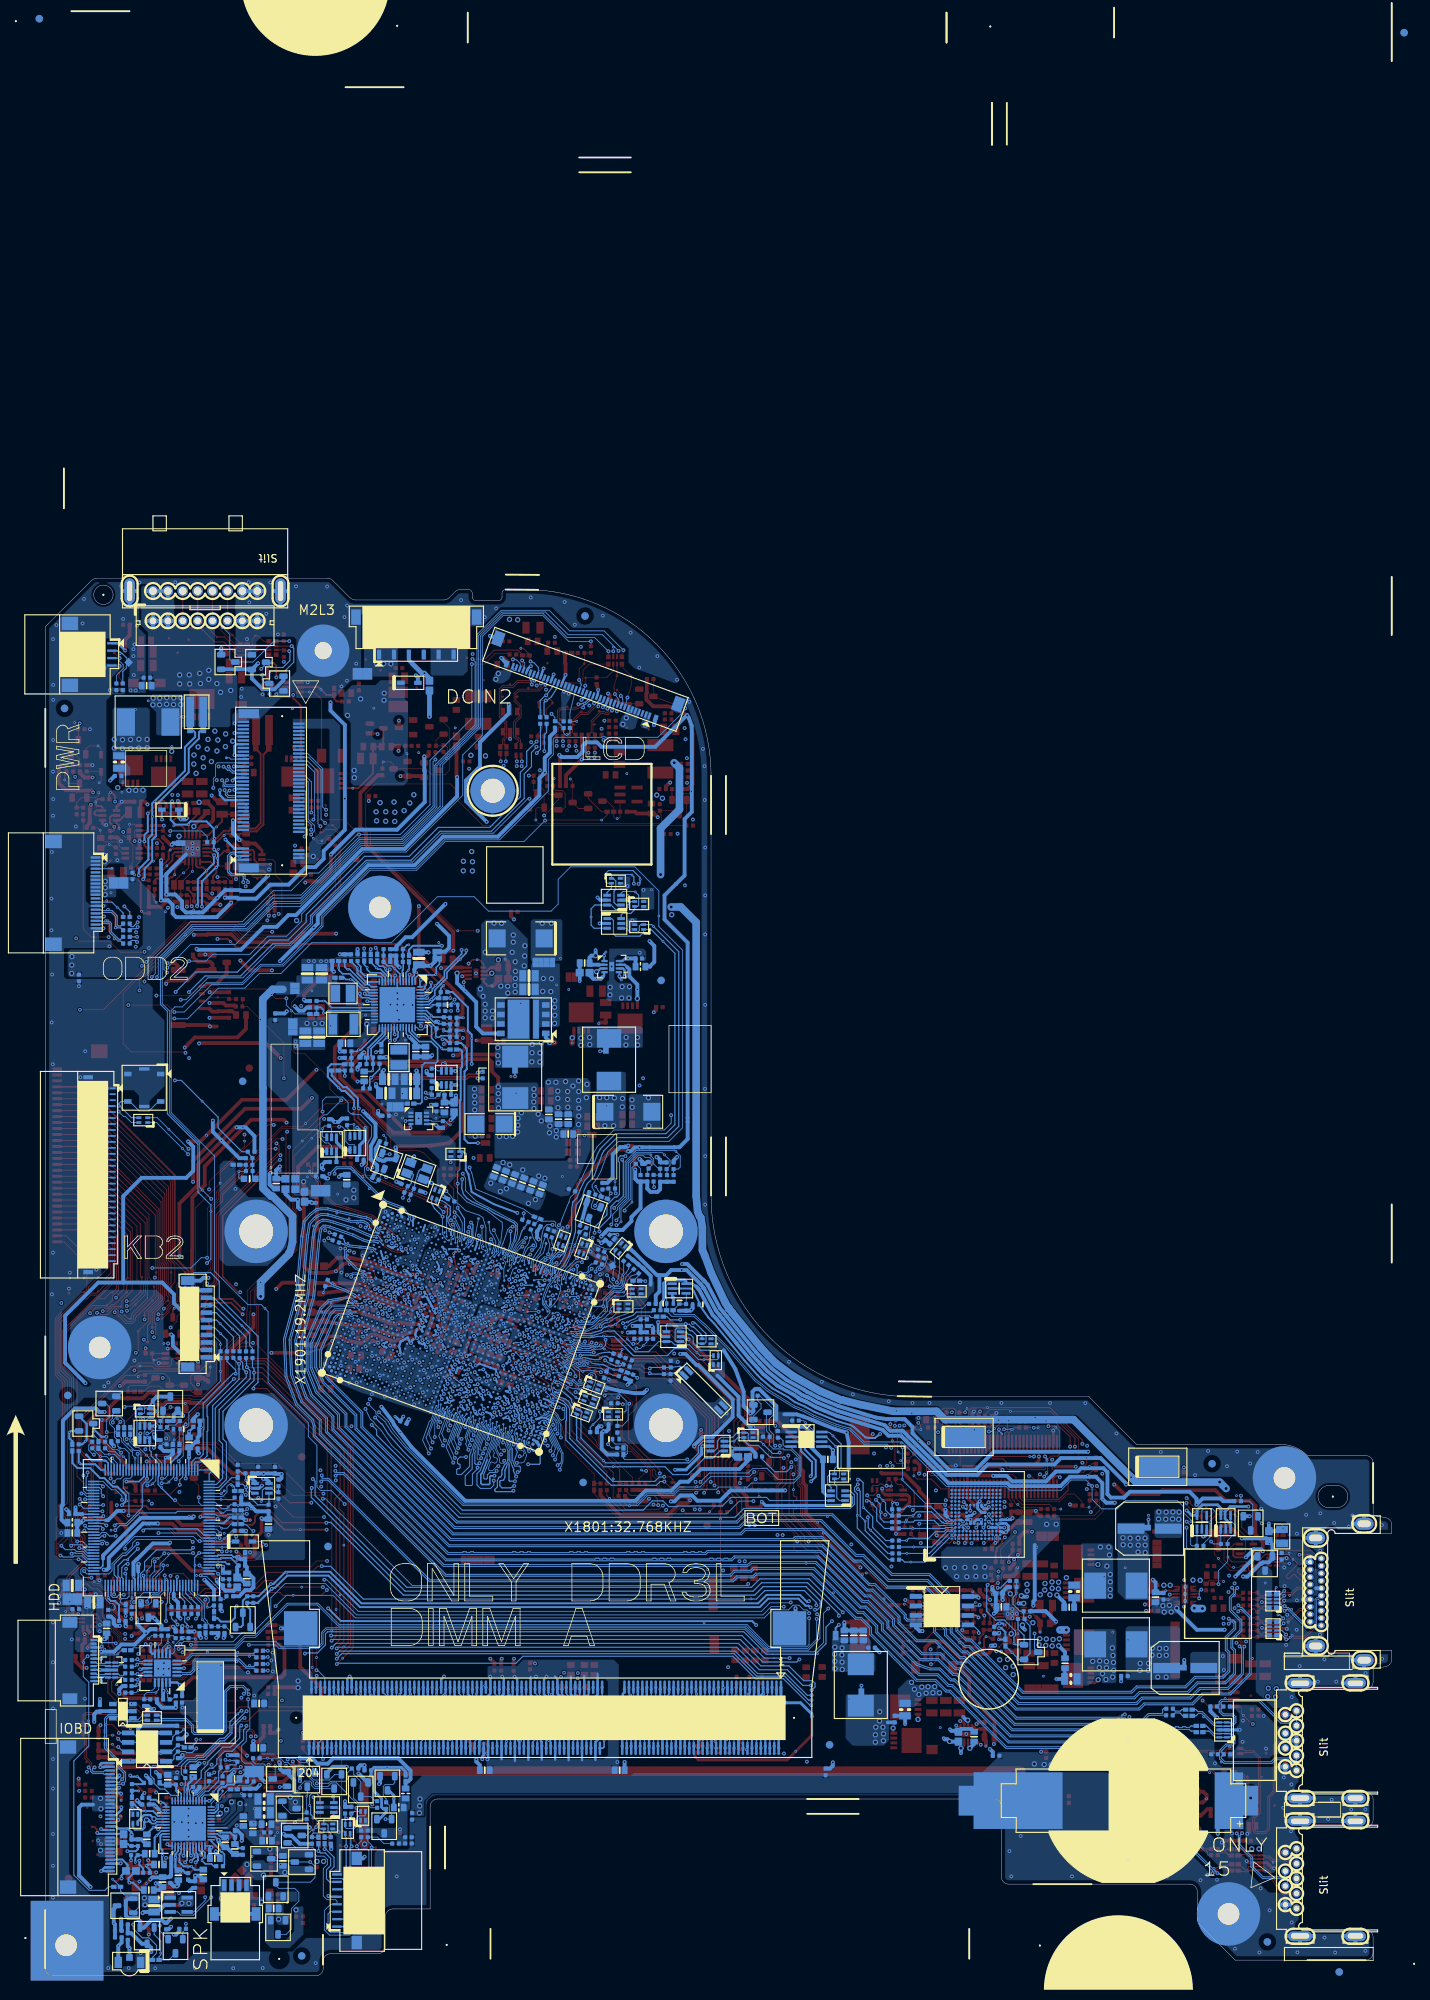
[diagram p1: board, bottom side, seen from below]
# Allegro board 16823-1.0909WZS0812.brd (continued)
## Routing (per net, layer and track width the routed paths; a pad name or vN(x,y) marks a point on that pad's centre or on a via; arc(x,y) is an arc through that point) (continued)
HDD_SATA_RX_P: length 65.1
  TOP w0.127: v2(150.83,43.61) R6023.1
  L4 w0.114: v2(150.83,43.61) 151.14,43.31 151.45,43.31 151.87,43.73 151.87,45.42 147.91,49.39 146.87,50.42 146.87,62.41 147.44,62.97 147.44,66.85 144.18,70.1 144.18,77.34 144.61,77.76 145.35,78.5 145.35,86.21 141.92,89.64 140.42,90.86 139.55,91.19 138.34,91.7 137.67,92.46 137.23,93.54 136,94.53 135.71,94.66 135.25,94.83 135.12,94.84 135.12,94.84 134.51,94.84 134.17,94.86 v2(133.81,95.09)
  BOTTOM w0.127: v2(150.83,43.61) R6023.1 ; CPU1.T9 133.78,94.61 133.92,94.74 133.92,94.99 v2(133.81,95.09)
HDD_SATA_TX_N: length 67.7
  TOP w0.127: R6010.1 v2(150.83,41.84)
  L4 w0.114: v2(150.83,41.84) 151.16,41.51 151.78,41.51 152.6,42.32 152.6,45.72 147.68,50.63 147.68,62.16 148.16,62.64 148.16,67.15 147.24,68.07 145.16,70.15 144.91,70.4 144.91,77.04 146.07,78.2 146.07,79.21 146.07,79.21 146.07,86.55 141.73,90.9 139.75,92.46 139.38,92.59 139.33,92.6 138.75,92.89 138.71,92.91 138.67,92.93 138.51,93.1 138.35,93.42 138.35,93.71 138.43,94.01 138.55,94.16 138.63,94.25 138.98,94.51 139.02,94.51 139.03,94.52 139.2,94.55 139.25,94.56 139.47,94.53 139.56,94.5 139.61,94.48 139.72,94.37 139.73,94.36 139.82,94.25 v2(140.22,94.03)
  BOTTOM w0.089: v2(140.22,94.03) 139.51,94.28 139.43,94.31 138.88,94.31 138.29,94.2 138.15,94.17 138.14,94.16 138.05,94.13 137.9,94.08 137.86,94.06 137.75,94.03 137.75,94.02 CPU1.Y2
  BOTTOM w0.127: R6010.1 v2(150.83,41.84)
HDD_SATA_TX_P: length 67.7
  TOP w0.127: R6011.1 v2(150.83,40.95)
  L4 w0.114: v2(150.83,40.95) 151.16,41.28 151.87,41.28 152.83,42.23 152.83,45.81 147.91,50.73 147.91,62.07 148.39,62.54 148.39,67.25 147.47,68.16 145.32,70.31 145.14,70.5 145.14,76.95 146.3,78.11 146.3,86.65 141.88,91.07 139.86,92.67 139.72,92.72 139.7,92.72 139.41,92.81 138.81,93.12 138.7,93.23 138.58,93.47 138.58,93.68 138.64,93.9 138.79,94.08 139.08,94.29 139.25,94.33 139.42,94.31 139.48,94.28 139.56,94.21 139.64,94.1 v2(139.64,93.79)
  BOTTOM w0.089: CPU1.Y3 137.41,93.73 137.53,93.7 137.68,93.7 137.77,93.72 137.86,93.79 137.98,93.9 138.12,93.95 138.2,93.99 138.33,94.02 138.89,94.12 139.4,94.12 139.55,94.07 v2(139.64,93.79)
  BOTTOM w0.127: R6011.1 v2(150.83,40.95)
HDMI_CLK_CON: length 19.6
  TOP w0.14: v2(12.38,56.49) 12.35,56.52 10.93,56.52 10.24,55.83 10.24,54.38 9.86,54 HDMI1.15 ; Q5701.3 20.69,57.93 20.69,57.93 21.15,57.93 21.98,57.1 v1(21.98,56.19) 21.98,56.07 21.46,55.55 19.54,55.55 19.24,55.25 19.24,54.49 19.11,54.36 RN5701.2 18.19,54.36 17.02,55.53 ED5703.7 ED5703.4 14.59,55.53 14.38,55.32 v2(13.75,55.32)
  L3 w0.127: v2(13.75,55.32) 13.55,55.32 v2(12.38,56.49)
HDMI_CLK_CPU: length 139.7
  TOP w0.14: Q5701.4 18.55,58.16 19,58.61 19,59.05 20.15,60.2 20.15,61.7 20.9,62.45 v1(22.56,62.45) 23.67,62.45 24.46,61.66 RN802.1 24.9,62.06 25.1,62.26 25.89,62.26 27.02,63.39 27.02,63.67 27.44,64.09 v2(27.52,64.09) ; v2(111.54,97.21) 111.53,97.21 111.46,97.32 111.42,97.39 110.87,97.93 110.81,98.01 110.77,98.07 110.63,98.26 107.17,98.26 104.26,95.35 103.78,95.09 103.46,94.91 103.45,94.91 103.33,94.84 103.31,94.76 102.49,93.95 102.44,93.89 102.27,93.67 101.32,92.23 101.04,91.32 101.03,91.32 100.87,90.79 100.18,89.95 100.18,87.43 99.31,86.55 96.53,86.55 86.8,76.83 86.8,75.16 87.75,74.21 87.75,71.44 87.5,71.19 87.5,70.18 88.82,68.85 88.82,65.55 87.26,63.98 87.26,62.23 v2(85.48,60.45)
  L4 w0.127: v2(27.52,64.09) 27.67,64.09 28.51,64.92 36.18,64.92 36.45,65.19 37.94,65.19 39.32,63.82 41.25,63.82 42.33,62.74 46.52,62.74 47.12,63.34 48.35,63.34 49.02,62.67 49.02,61.38 50.01,60.39 50.02,60.39 50.34,60.07 50.93,60.07 51.33,59.68 51.33,59.36 51.35,59.33 51.35,58.71 51.81,58.26 52.35,58.26 53.18,57.43 65.01,57.43 65.29,57.15 66.52,55.92 80.97,55.92 85.48,60.43 v2(85.48,60.45)
  BOTTOM w0.102: 113.25,95.43 113.3,95.32 113.56,95.06 113.73,94.59 113.76,94.5 CPU1.B49
  BOTTOM w0.14: 113.25,95.43 112.88,95.8 112.88,96.01 112.41,96.48 112.41,96.54 111.94,97 v2(111.54,97.21) 111.88,97.61 111.92,97.64 111.95,97.7 111.95,98.1 RN801.1
HDMI_DATA_CON: length 18.1
  TOP w0.14: Q5701.6 18.61,56.57 RN5701.1 18.28,55.01 17.66,55.63 17.66,55.86 16.98,56.53 ED5703.9 ED5703.2 13.89,56.53 v1(13.25,55.89) 12.69,55.33 12.69,55.14 14.13,53.7 14.13,53.47 13.97,53.31 13.73,53.31 13.22,53.82 13.02,53.82 12.08,52.88 11.85,52.88 11.68,53.04 11.68,53.28 12.63,54.22 12.63,54.42 12.3,54.74 11.19,54.74 HDMI1.16
HDMI_DATA_CON_N0: length 16.1
  TOP w0.127: C5703.2 19.04,49.71 R5704.2 17.81,49.48 17.28,49.48 17.14,49.62 ED5702.7 ED5702.4 15.13,49.62 14.97,49.46 14.51,49.46 v2(14.36,49.61)
  BOTTOM w0.089: HDMI1.9 9.72,50.73 10.09,50.73 10.29,50.53 10.29,47.13 10.44,46.98
  BOTTOM w0.127: 10.44,46.98 10.52,46.9 11.39,46.9 13.55,49.07 ; RN5703.2 15.04,50.03 14.61,49.61 v2(14.36,49.61) 14.16,49.41 13.89,49.41 13.55,49.07 ; 13.55,49.07 v1(13.44,49.18)
HDMI_DATA_CON_N1: length 11.2
  TOP w0.127: HDMI1.6 11.18,49.27 12.38,49.27 13.81,47.83 14.43,47.83 v2(14.56,47.96) 14.76,47.75 15.12,47.75 15.26,47.61 ED5701.1 ED5701.10 17.57,47.61 17.99,48.03 R5705.2 19.03,48.03 C5705.2
  BOTTOM w0.127: RN5702.4 15.03,47.49 v2(14.56,47.96) 15.03,48.43 v1(15.27,48.43)
HDMI_DATA_CON_N2: length 13.7
  TOP w0.127: HDMI1.3 9.48,48.03 9.96,48.03 10.14,47.86 10.14,47.14 11.76,45.52 13.37,45.52 ; C5707.2 19.01,46.32 R5706.2 18.04,46.23 17.66,45.85 17.38,45.85 17.12,46.11 ED5701.7 ED5701.4 15.1,46.11 14.99,46 14.99,45.72 14.74,45.46 14.47,45.46 14.17,45.76 v2(14.17,45.78) 14.17,45.78 13.91,45.52 13.37,45.52 ; 13.37,45.52 v1(13.37,45.67)
  BOTTOM w0.127: v2(14.17,45.78) 14.73,46.34 RN5702.2
HDMI_DATA_CON_N3: length 11.4
  TOP w0.127: HDMI1.12 11.31,52.14 12.72,52.14 13.42,51.44 14.23,51.44 v2(14.43,51.64) 14.56,51.64 15.09,51.12 ED5702.1 ED5702.10 17.04,51.12 17.19,50.97 17.57,50.97 18.02,51.41 R5707.2 19.03,51.41 C5701.2
  BOTTOM w0.127: v2(14.43,51.64) 14.89,51.18 RN5703.4 15.48,51.49 15.63,51.64 15.63,51.99 v1(15.5,52.12)
HDMI_DATA_CON_P0: length 17.2
  TOP w0.127: v1(13.85,49.23) 14.1,48.97 v2(14.39,48.97) 14.63,49.21 15,49.21 15.1,49.12 ED5702.5 ED5702.6 17.15,49.12 17.28,49.24 17.62,49.24 R5704.1 18.45,49.23 18.71,49.23 C5704.2
  BOTTOM w0.089: HDMI1.7 9.45,50.13 9.85,50.54 10.01,50.54 10.1,50.45 10.1,46.98 10.27,46.81
  BOTTOM w0.127: 10.27,46.81 10.42,46.66 11.49,46.66 13.99,49.16 14.2,49.16 v2(14.39,48.97) 14.79,49.38 RN5703.1
HDMI_DATA_CON_P1: length 11
  TOP w0.127: 13.9,47.59 13.71,47.59 12.28,49.02 11.39,49.02 10.95,48.59 HDMI1.4 ; 13.9,47.59 v1(13.9,47.45) ; 13.9,47.59 14.22,47.59 v2(14.51,47.3) 14.73,47.51 14.94,47.51 15.02,47.44 15.02,47.2 15.1,47.11 ED5701.2 ED5701.9 17.12,47.11 17.38,47.37 17.82,47.37 R5705.1 19,47.14 C5706.2
  BOTTOM w0.127: v2(14.51,47.3) 14.97,46.84 RN5702.3
HDMI_DATA_CON_P2: length 12.8
  TOP w0.127: C5708.2 18.94,45.43 R5706.1 17.86,45.61 ED5701.6 ED5701.5 15.23,45.61 14.84,45.22 14.24,45.22 v2(14.16,45.14) 14.01,45.28 11.66,45.28 9.94,47 HDMI1.1
  BOTTOM w0.127: RN5702.1 14.71,45.69 14.36,45.34 14.35,45.34 v2(14.16,45.14) 13.9,45.14 v1(13.62,45.42)
HDMI_DATA_CON_P3: length 10.4
  TOP w0.127: 13.7,51.2 14.24,51.2 v2(14.43,51.01) 14.51,51.08 14.78,51.08 15.24,50.62 ED5702.2 ED5702.9 17.07,50.62 17.18,50.73 17.84,50.73 R5707.1 19,50.52 C5702.2 ; 13.7,51.2 v1(13.7,51.06) ; 13.7,51.2 13.32,51.2 12.62,51.89 11.34,51.89 HDMI1.10
  BOTTOM w0.127: RN5703.3 14.91,50.53 v2(14.43,51.01)
HDMI_DATA_CPU: length 141.7
  TOP w0.14: Q5701.1 19.87,56.63 19.63,56.87 19.63,58.95 20.67,59.98 20.67,61.48 21.12,61.93 23.45,61.93 24.42,60.96 25.36,60.96 25.55,61.16 RN802.2 26.03,61.66 v1(26.65,62.28) 27.54,63.17 v2(27.54,63.45) ; v2(86.21,60.45) 87.9,62.14 87.9,63.9 89.35,65.34 89.35,69.06 88.02,70.39 88.02,70.97 88.27,71.22 88.27,74.42 87.32,75.38 87.32,76.61 96.74,86.03 99.53,86.03 100.71,87.21 100.71,89.76 101.41,90.63 101.41,90.78 101.79,92.01 101.82,92.05 102.06,92.29 102.62,93.05 102.87,93.58 102.88,93.6 103.77,94.49 104.39,94.83 104.45,94.83 104.5,94.85 104.57,94.92 107.39,97.73 110.33,97.73 110.97,97.1 111.24,96.61 111.73,96.61 v2(111.74,96.61)
  L4 w0.127: v2(27.54,63.45) 27.83,63.45 28.79,64.42 36.39,64.42 36.65,64.67 37.75,64.67 39.1,63.31 41.04,63.31 42.12,62.23 46.73,62.23 47.33,62.83 48.14,62.83 48.51,62.46 48.51,61.32 48.51,60.9 50.58,58.82 50.84,58.56 50.84,58.5 51.6,57.75 52.14,57.75 52.97,56.92 64.8,56.92 65.07,56.64 66.31,55.41 81.2,55.41 86.21,60.43 v2(86.21,60.45)
  BOTTOM w0.102: v2(111.74,96.61) 111.82,96.52 112.07,96.52 112.63,95.96 112.63,95.7 113.12,95.21 113.13,95.19 113.39,94.92 113.51,94.6 113.48,94.55 113.44,94.39 113.49,94.26 113.53,94.21 113.91,94.04 CPU1.C49
  BOTTOM w0.14: v2(111.74,96.61) 111.5,96.64 111.1,97.04 111.1,97.05 111.03,97.34 111.01,97.77 RN801.2
HDMI_DATA_CPU_N0: length 175.7
  TOP w0.127: v2(20.58,49.71) C5703.1
  BOTTOM w0.089: CPU1.AH2 139.12,90.56 139.15,90.59 139.73,91.04 139.73,91.04 140.2,91.08 140.23,91.08 140.89,90.98
  BOTTOM w0.127: v2(20.58,49.71) 20.29,49.42 20.1,49.42 18.87,48.18 18.87,42.57 ; 18.87,42.57 v1(18.7,42.57) ; 18.87,42.57 18.87,40.46 21.63,37.69 25.34,37.69 26.67,36.36 33.16,36.36 33.84,35.68 50.46,35.68 57.38,42.59 57.99,42.59 61.49,46.09 61.49,47.08 62.01,47.6 65.06,47.6 65.43,47.96 65.43,48.39 69.42,52.38 70.16,52.38 76.49,58.71 79.97,58.71 80.27,58.42 126.35,58.42 141.46,73.53 141.46,75.27 144.43,78.23 145.68,81.36 145.68,85.37 143.84,89.6 143.81,89.63 142.77,90.67 142.7,90.71 141.37,90.91 140.89,90.98
HDMI_DATA_CPU_N1: length 166.1
  TOP w0.127: C5705.1 20.12,47.83 21.8,47.83 v2(21.88,47.91)
  BOTTOM w0.089: 141.71,88.56 141.7,88.56 141.53,88.73 141.42,88.79 141.41,88.79 141.35,88.8 141.34,88.81 141.29,88.81 141.16,88.83 140.8,88.89 140.54,88.92 140.28,88.95 140.11,88.94 140.04,88.94 140.01,88.93 139.77,88.84 CPU1.AM2
  BOTTOM w0.127: 141.71,88.56 141.86,88.41 141.96,88.32 143.87,83.91 143.87,81.67 142.98,80.16 138.34,75.52 138.34,73.59 125.51,60.76 87.84,60.76 86.85,61.75 75.75,61.75 ; v2(21.88,47.91) 21.7,47.73 21.22,47.73 20.94,47.45 20.94,46.54 22.09,45.39 22.09,43.79 21.74,43.43 21.74,40.82 22.62,39.94 26.33,39.94 27.62,38.64 34.17,38.64 34.89,37.92 49.53,37.92 54.84,43.23 54.84,43.23 56.54,44.93 57.16,44.93 58.49,46.27 58.49,47.18 59.16,47.85 59.16,50.8 62.08,53.72 67.11,53.72 75.14,61.75 75.75,61.75 ; 75.75,61.75 v1(75.75,61.62)
HDMI_DATA_CPU_N2: length 168.2
  TOP w0.127: C5707.1 19.91,46.19 20.12,45.98 20.46,45.98 20.82,45.62 20.82,45.44 ; 20.82,45.44 20.82,45.3 20.24,44.72 20.24,44.38 v2(20.41,44.2) ; 20.82,45.44 v1(20.99,45.44)
  BOTTOM w0.089: CPU1.AK2 139.46,89.71 139.94,89.71 140.55,89.8 142.24,89.8 142.3,89.74
  BOTTOM w0.127: v2(20.41,44.2) 20.41,44.2 20.23,44.02 20.23,43.99 20.16,43.93 20.16,40.57 22.05,38.68 25.8,38.68 27.1,37.39 33.57,37.39 34.29,36.67 50.05,36.67 56.97,43.58 57.58,43.58 59.77,45.77 59.77,46.56 60.46,47.25 60.46,50.32 62.42,52.28 67.67,52.28 71.15,55.77 72.14,55.77 76.38,60.01 86.79,60.01 87.39,59.41 125.94,59.41 140.23,73.7 140.23,75.43 143.26,78.47 143.74,78.95 144.9,81.61 144.9,84.77 142.92,89.12 142.3,89.74
HDMI_DATA_CPU_N3: length 174
  TOP w0.127: C5701.1 20.25,51.08 20.71,51.08 20.96,51.34 20.96,51.82 v2(20.73,52.05)
  BOTTOM w0.089: 142.06,89.3 141.86,89.51 140.49,89.51 140.46,89.49 140.01,89.33 CPU1.AL1
  BOTTOM w0.127: v2(20.73,52.05) 20.96,51.82 20.96,51.26 21.55,50.67 21.55,49.12 20.12,47.7 20.12,46.3 21.34,45.08 21.34,44.1 20.98,43.73 20.98,40.49 22.28,39.19 26.01,39.19 27.31,37.89 33.78,37.89 34.5,37.17 49.84,37.17 56.76,44.09 57.37,44.09 59.24,45.96 59.24,46.87 59.95,47.58 59.95,50.53 62.34,52.92 67.58,52.92 70.94,56.28 71.93,56.28 76.64,60.99 77.05,60.99 ; 77.05,60.99 v1(77.05,60.86) ; 77.05,60.99 86.53,60.99 87.51,60.01 125.82,60.01 139.14,73.33 139.14,75.17 143.43,79.47 144.52,81.6 144.52,84.37 142.58,88.79 142.06,89.3
HDMI_DATA_CPU_P0: length 174.9
  TOP w0.127: C5704.1 v2(20.6,48.89)
  BOTTOM w0.089: CPU1.AH3 138.42,90.24 138.92,90.22 138.98,90.22 139.08,90.25 139.27,90.44 139.8,90.85 140.15,90.88 140.23,90.89 140.69,90.82 140.77,90.76
  BOTTOM w0.127: v1(71.05,53.82) 71.16,53.72 ; 71.16,53.72 70.06,52.63 69.32,52.63 65.18,48.49 65.18,48.06 64.96,47.84 62.78,47.84 61.91,47.84 61.25,47.18 61.25,46.19 57.89,42.83 57.28,42.83 50.36,35.92 33.94,35.92 33.26,36.6 26.77,36.6 25.44,37.93 21.73,37.93 19.11,40.56 19.11,48.08 20.2,49.18 20.32,49.18 v2(20.6,48.89) ; 71.16,53.72 76.39,58.96 80.07,58.96 80.37,58.66 126.25,58.66 141.22,73.63 141.22,75.37 144.22,78.37 145.44,81.41 145.44,85.32 143.64,89.46 142.62,90.47 140.77,90.76
HDMI_DATA_CPU_P1: length 165.7
  TOP w0.127: v2(21.88,47.25) 21.53,47.59 21.22,47.59 ; 21.22,47.59 20.33,47.59 C5706.1 ; 21.22,47.59 v1(21.22,47.45)
  BOTTOM w0.089: CPU1.AM3 139.2,88.62 139.3,88.6 139.41,88.5 139.48,88.48 139.67,88.48 139.85,88.66 139.9,88.69 140.07,88.75 140.12,88.75 140.27,88.76 140.77,88.7 140.77,88.7 141.03,88.66 141.03,88.66 141.1,88.65 141.31,88.62 141.31,88.62 141.42,88.56 141.49,88.44
  BOTTOM w0.127: 141.49,88.44 141.75,88.18 143.63,83.86 143.63,81.74 142.79,80.31 138.09,75.62 138.09,73.69 125.41,61 87.94,61 86.95,61.99 75.04,61.99 67.01,53.96 61.98,53.96 58.92,50.9 58.92,47.95 58.25,47.28 58.25,46.37 57.06,45.18 56.44,45.18 54.43,43.16 49.43,38.17 34.99,38.17 34.27,38.89 27.72,38.89 26.43,40.18 22.72,40.18 21.98,40.92 21.98,43.33 22.33,43.69 22.33,45.49 21.18,46.64 21.18,47.35 21.32,47.49 21.64,47.49 v2(21.88,47.25)
HDMI_DATA_CPU_P2: length 169.7
  TOP w0.127: C5708.1 20.14,45.74 20.36,45.74 20.58,45.52 20.58,45.4 20,44.82 20,44.39 v2(19.78,44.17)
  BOTTOM w0.089: CPU1.AK3 138.58,89.39 139.06,89.87 139.19,89.92 139.35,89.92 139.38,89.91 139.93,89.91 140.53,89.99 142.39,89.99 142.47,89.91
  BOTTOM w0.127: v1(76.28,59.39) 76.19,59.48 ; 76.19,59.48 76.48,59.77 86.69,59.77 87.29,59.17 126.04,59.17 140.47,73.6 140.47,75.33 143.36,78.22 143.95,78.81 145.15,81.56 145.15,84.82 143.12,89.26 142.98,89.4 142.47,89.91 ; 76.19,59.48 72.24,55.53 71.25,55.53 67.77,52.04 62.52,52.04 60.7,50.22 60.7,47.15 60.01,46.46 60.01,45.67 57.68,43.34 57.07,43.34 50.15,36.43 34.19,36.43 33.47,37.15 27,37.15 25.7,38.44 21.95,38.44 19.92,40.47 19.92,44.03 v2(19.78,44.17)
HDMI_DATA_CPU_P3: length 174
  TOP w0.127: 21.04,51.08 21.2,51.24 21.2,51.86 v2(21.42,52.07) ; 21.04,51.08 20.81,50.84 20.21,50.84 C5702.1 ; 21.04,51.08 v1(21.14,50.98)
  BOTTOM w0.089: 141.89,89.13 141.71,89.32 140.52,89.32 140.09,89.16 140.08,89.15 139.83,89.06 139.75,89.04 139.64,89.06 CPU1.AL2
  BOTTOM w0.127: v2(21.42,52.07) 21.2,51.86 21.2,51.36 21.79,50.77 21.79,49.02 20.37,47.6 20.37,46.4 21.58,45.18 21.58,44 21.22,43.63 21.22,40.59 22.38,39.43 26.11,39.43 27.41,38.14 33.88,38.14 34.6,37.42 49.74,37.42 56.66,44.33 57.27,44.33 59,46.06 59,46.97 59.71,47.68 59.71,50.63 62.24,53.16 67.48,53.16 70.84,56.52 71.83,56.52 76.54,61.23 86.63,61.23 87.61,60.25 125.72,60.25 138.89,73.43 138.89,75.27 143.23,79.61 144.28,81.66 144.28,84.32 142.37,88.65 141.89,89.13
HDMI_DET_CPU#: length 119.5
  TOP w0.102: v1(20.84,64.42) v2(20.24,64.42)
  L4 w0.127: v2(20.24,64.42) 20.34,64.52 23.55,64.52 25.74,66.7 27.43,66.7 28.35,67.63 37.96,67.63 39.84,69.51 44.6,69.51 45.38,68.73 48.58,68.73 48.69,68.84 48.92,69.07 49.42,69.56 60.01,69.56 60.55,69.03 63.55,69.03 64.89,67.68 71.64,67.68 72.68,68.72 73.7,68.72 76.33,68.72 76.33,68.72 77.17,68.72 78.88,70.42 79.63,70.42 81.27,72.06 83.41,72.06 84.75,73.41 84.75,73.68 84.75,73.68 84.75,75.13 93.78,84.15 94.11,84.15 97.02,87.06 97.02,88.3 106.32,97.6 107.76,97.6 108.31,97.06 109.41,97.06 110.79,95.68 v2(112.08,95.68)
  BOTTOM w0.102: v2(112.08,95.68) 112.12,95.63 112.41,95.63 112.93,95.11 112.93,94.84 112.89,94.76 112.89,94.65 112.96,94.46 113.06,94.37 113.12,94.34 CPU1.C50 ; Q5703.D 18.93,60.17 18.65,60.45 18.65,63.22 19.11,63.68 R5703.2 v2(20.24,64.42)
HDMI_HPD_G: length 5.4
  TOP w0.102: v2(17.43,60.71) 14.94,60.71 14.57,60.34 v1(14.57,60.05) R5701.2
  BOTTOM w0.102: Q5703.G 17.95,61.22 v2(17.43,60.71)
HDMI_PLL_GND:
  vias: v1(16.97,52.71)
HPD_HDMI_CON: length 10.3
  TOP w0.102: R5701.1 R5702.2 16.14,58.27 v1(16.42,57.98) 16.46,57.95 ED5703.10 ED5703.1 10.74,57.03 9.7,56 HDMI1.19
I2C3_SCL_CPU: length 32.4
  BOTTOM w0.102: 111.96,77.78 112.1,77.81 112.29,77.94 112.52,78.18 112.52,78.18 112.64,78.3 112.64,78.61 112.73,78.77 112.76,78.85 112.76,79.06 CPU1.AL62
  BOTTOM w0.14: Q1901.1 90.17,70.42 91.15,69.44 92.25,69.44 94.45,67.24 95.9,67.24 95.9,67.24 96.48,67.24 97.54,68.3 102.18,68.3 102.18,68.3 102.67,68.3 102.67,68.3 v1(104.48,68.3) 105.76,68.3 109.38,71.93 109.38,74.74 RN1904.2 109.78,75.6 110.03,76.06 110.14,76.51 110.49,77.09 110.94,77.39 111.96,77.78
I2C3_SDA_CPU: length 29.3
  BOTTOM w0.102: CPU1.AM62 112.23,78.67 112.04,78.59 111.62,78.59 111.48,78.55
  BOTTOM w0.14: Q1901.4 92.43,71.72 93.05,71.1 93.05,70.13 94.36,68.82 105.48,68.82 v1(105.8,69.14) 108.81,72.15 108.81,75.17 108.67,75.54 108.67,75.67 108.81,75.83 RN1904.1 109.49,76.17 110.02,76.97 110.16,77.46 111.48,78.55
I2C7_SCL_CPU: length 70.7
  TOP w0.14: Q1903.4 65.56,65.66 65.82,65.92 66.33,65.92 66.59,66.18 R1912.2 65.72,66.65 65.7,66.63 ; v1(65.69,66.63) 65.7,66.63 ; 65.7,66.63 64.11,65.04 64.11,64.68 64.07,64.65 64.07,62.68 v2(64.27,62.49) ; RN1909.3 96.84,65.54 v2(97.62,66.32)
  L4 w0.127: v2(64.27,62.49) 64.98,61.77 66.53,61.77 66.53,61.78 66.89,61.78 67.31,61.78 69.34,59.74 71.05,59.74 83.59,59.74 84.78,60.94 87.79,60.94 88.21,60.94 88.21,60.94 88.3,60.94 91.58,64.21 93.48,64.21 95.59,66.32 v2(97.62,66.32)
  BOTTOM w0.102: CPU1.AP61 113.19,78.02 113.17,78.02 113.05,77.89 112.91,77.59 112.91,77.46 112.85,77.33 112.84,77.31 112.76,77.23 112.51,77.14 112.09,77.14 112,77.09
  BOTTOM w0.14: 112,77.09 110.98,76.58 110.75,76.23 110.75,74.51 110.84,74.41 110.84,71.91 104.75,65.82 104.31,65.82 98.68,65.82 98.18,66.32 v2(97.62,66.32)
I2C7_SDA_CPU: length 60.8
  TOP w0.14: v2(67.95,61.85) 68.18,61.85 v1(68.51,62.18) 68.78,62.45 R1911.2 68.55,63.4 68.54,63.4 68.07,63.87 Q1903.1 ; v2(97.64,66.96) 96.83,66.96 96.44,66.57 RN1909.4
  L4 w0.127: v2(97.64,66.96) 96.71,66.96 96.58,66.83 95.3,66.83 94.02,65.55 92.1,65.55 88,61.44 84.57,61.44 83.38,60.25 82.55,60.25 70.84,60.25 70.84,60.25 69.55,60.25 v2(67.95,61.85)
  BOTTOM w0.14: v2(97.64,66.96) 97.67,66.93 98.31,66.93 98.9,66.34 104.53,66.34 110.32,72.13 110.32,76 110.47,76.39 111.2,77.13 111.8,77.41 112.18,77.54 112.57,77.93 CPU1.AP62
INT_SERIRQ: length 7.9
  BOTTOM w0.089: 108.62,82.62 109.13,82.62 109.15,82.65 109.71,82.65 110,82.76 110.03,82.77 110.31,83.05 110.34,83.06 110.35,83.07 110.64,83.17 110.65,83.17 110.72,83.2 110.74,83.2 110.75,83.21 CPU1.AB62
  BOTTOM w0.102: 108.62,82.62 108.17,82.62 107.59,82.43 107.37,82.2 107.29,82.18 106.98,82.12
  BOTTOM w0.14: R1919.2 v1(104.4,81.31) 105.5,81.84 105.85,81.99 106.98,82.12
INT_SERIRQ_KBC: length 9.9
  BOTTOM w0.14: U2404.3 152.9,64.76 153.26,65.12 153.26,65.86 153.8,66.4 v1(153.8,66.5) 153.8,67.38 R2436.2 154.24,67.41 154.5,67.68 C2401.1 R2508.2 155.67,66.84 157.39,65.12 KBC24.125
INT_SERIRQ_OE: length 4.9
  BOTTOM w0.14: v1(151.72,63.63) 151.57,63.78 151.57,65.13 151.29,65.41 U2404.5 150.3,65.41 149.78,64.89 R2419.1 R2421.2
INT_SPK_1: length 9.9
  TOP w0.102: R2925.2 150.15,24.41 149.79,24.77 v1(147.02,24.77) 146.96,24.77 v2(146.5,25.22)
  BOTTOM w0.102: v2(146.5,25.22) 146.5,25.5 145.87,26.13 145.2,26.13 144.98,25.9 144.98,25.54 144.56,25.12 Q2906.C
INT_SPK_R: length 3.5
  TOP w0.102: R2924.2 150.36,25.28 R2925.1 150.31,25.33 v2(149.23,25.33) v1(148.67,25.33)
  BOTTOM w0.102: Q2907.B 149.13,25.43 v2(149.23,25.33)
INT_TP#_CONN: length 41.5
  TOP w0.102: AFTP6525.1 136.35,17.22 v2(136.9,17.22)
  BOTTOM w0.102: Q6509.S 147.77,17.84 147.17,17.25 144.84,17.25 144.46,16.87 144.46,16.23 144.28,16.05 143.29,16.05 142.81,15.57 142.81,14.96 143.39,14.38 143.39,10.72 142.88,10.21 141.74,10.21 141.55,10.02 TP1.4 142.4,9.6 143.24,8.77 143.24,6.15 142.55,5.46 139.86,5.46 136.9,8.42 v2(136.9,17.22) 136.9,17.54 137.42,18.06 R6514.1 136.11,18.61 135.25,17.74 R6524.2
INTRUDER: length 19.4
  TOP w0.102: v2(106.18,87.14) v1(106.71,86.95) 107.19,86.75 109.41,85.9 109.78,85.27 109.78,85.06 109.56,84.39 109.56,84.14 109.71,83.88 109.76,83.83 109.95,83.77 110.94,83.77 111.28,84.11 111.4,84.41 111.87,84.69 112.78,84.99 112.93,85.02 113.12,85.02 113.31,84.97 R1816.2 v2(114.61,84.15)
  BOTTOM w0.102: v2(106.18,87.14) 105.92,87.35 105.8,87.47 105.71,87.5 105.69,87.54 105.5,87.59 105.25,87.69 104.96,87.69 104.8,87.85 104.12,88.32 102.99,88.72 102.55,88.88 102.08,89.06 101.58,89.56 100.54,89.56 99.96,90.15 R1817.2 ; CPU1.AC54 v2(114.61,84.15)
JACK_PLUG: length 5.9
  TOP w0.254: v2(170.47,13.06) 170.72,13.06 171.1,12.68 AFTP6607.1
  BOTTOM w0.254: IOBD1.27 171.48,15.55 171.44,15.6 170.37,15.6 169.65,14.88 169.65,14.28 R2914.1 170.47,13.46 v2(170.47,13.06)
JDREF: length 2.8
  BOTTOM w0.203: HDA27.15 164.99,21.85 165.45,22.32
  BOTTOM w0.508: R2714.1 166.12,22.99 v1(165.87,22.74) 165.45,22.32
JGND:
  vias: v3(133.94,181.92) v3(133.89,178.64) v3(134.32,176.02) v3(134.91,181.94) v3(134.86,178.67) v3(135.29,176.05) v3(135.85,181.94) v3(135.8,178.67) v3(136.23,176.05)
JTAG_PMODE: length 4.2
  BOTTOM w0.102: TP1803.1 126.75,103 126.7,102.84 126.7,102.29 126.87,101.86 126.87,99.96 126.86,99.94 126.83,99.87 CPU1.B19
KB_BL_CTRL#: length 5.6
  TOP w0.406: AFTP6567.1 157.66,133.07 158.99,133.07 159.3,132.77 KBBL1.4
  TOP w0.508: AFTP6567.1 157.56,133.26 156.35,134.47 Q6501.D
KB_DET#: length 254.6
  TOP w0.102: v2(105.63,77.87) 105.63,77.84 103.51,75.71 103.51,72.06 102.04,70.59 101.97,70.59 99.79,68.4 99.78,68.4 99.22,67.84 99.22,67.16 98.62,66.56 98.62,65.7 97.66,64.75 95.33,64.75 95.33,64.75 94.09,64.75 92.82,63.48 92.82,62.64 92.87,62.59 v2(92.87,62.56) ; AFTP6519.1 175.5,95.77 v2(175.62,95.89) 178.21,98.48 KB1.30
  L3 w0.127: v2(175.62,95.89) 174.03,94.3 170.57,94.3 169.22,95.66 164.29,95.66 159.75,91.12 159.75,80.41 160.64,79.52 160.64,79.15 158.39,76.91 158.39,71.72 153.31,66.64 153.31,65.35 153.7,64.96 153.97,64.96 155.14,63.79 155.14,60.08 153.73,58.67 153.73,50.2 152.93,49.4 152.93,42.33 155.16,40.09 155.16,33.03 153.1,30.96 152.41,30.96 151.19,32.18 148.14,32.18 143.51,27.56 139.91,27.56 139.58,27.89 138.31,27.89 138.11,27.69 135.74,27.69 135.08,28.36 132.22,28.36 104.88,28.36 104.1,29.14 103.14,29.14 102.67,29.14 101.89,28.36 83.67,28.36 78.42,33.61 78.42,35.72 80.09,37.4 80.09,40.07 87.26,47.24 87.26,47.24 87.26,53.99 92.9,59.63 92.9,62.53 92.87,62.55 v2(92.87,62.56)
  L4 w0.127: v2(115.96,84.63) 115.96,84.63 115.96,84.46 115.88,84.35 115.21,83.68 114.6,83.46 114.28,83.31 113.92,83.18 113.5,83.03 111.99,82.48 111.94,82.44 111.53,82.39 110.72,82.32 108.92,81.67 105.64,77.88 v2(105.63,77.87)
  BOTTOM w0.102: v2(115.96,84.63) 115.99,84.61 116.17,84.61 CPU1.AC51 ; RN1803.4 102.93,75.66 102.75,75.85 102.75,77.17 103.62,78.04 103.67,78.05 103.69,78.06 105.45,78.06 v2(105.63,77.87) ; KB2.30 v2(175.62,95.89)
KB_LED_BL_DET_R: length 64
  TOP w0.102: R6503.1 154.24,131 R6507.1 153.6,130.06 v1(151.84,128.3) 148.67,125.13 v2(148.67,120.42)
  L4 w0.102: v2(148.67,120.42) 148.75,120.35 148.75,113.16 148.42,112.83 143.93,112.83 142.88,111.77 134.74,111.77 134.28,112.24 128.38,112.24 125.51,109.36 125.51,108.46 v2(124.67,107.62)
  BOTTOM w0.089: CPU1.C38 118.7,96.16 118.7,96.5 118.7,96.57 118.64,96.75 118.56,96.83 118.54,96.84 118.51,96.89 118.4,97.06 118.11,97.47
  BOTTOM w0.102: 118.11,97.47 117.92,98.06 117.71,98.46 117.58,98.59 117.32,99.61 117.32,100.85 117.71,101.24 118.37,101.55 121.18,103.09 122.86,103.93 124.31,105.39 124.31,107.03 v2(124.67,107.62)
KB_LED_DET_C: length 4.9
  TOP w0.102: R6503.2 156,131.05 C6502.1 156.22,131.27 AFTP6566.1 158.54,131.27 159.04,130.77 KBBL1.2
KBC_BEEP_R: length 4.9
  BOTTOM w0.254: R2730.2 175.72,71.31 v1(175.32,71.72) 175.14,71.9 175.14,74.05 D2701.1
KBC_ON#_GATE: length 11.4
  BOTTOM w0.102: v1(161.91,76.79) 164.32,76.79 164.9,76.21 Q2404.G 164.9,74.8 C2442.1 R2492.2 165.26,73.61 165.97,74.32 165.97,74.55 166.22,74.81 166.88,74.81 167.34,74.35 Q2403.5 167.34,73.05 167.44,72.95 167.44,72.42 167.34,72.31 Q2403.2
KBC_ON#_GATE_L: length 32.8
  TOP w0.102: v1(167.01,72.21) v2(167.01,72.77)
  L4 w0.102: v2(169.15,47.91) 169.15,49.81 169.22,49.89 169.22,52.08 167.95,53.35 167.95,53.97 167.32,54.61 167.32,58.84 168.04,59.57 168.04,69.64 167.88,69.8 167.88,70.75 167.51,71.12 166.98,71.65 166.98,72.77 v2(167.01,72.77)
  BOTTOM w0.102: R2493.2 169.15,48.53 v2(169.15,47.91) ; v2(167.01,72.77) 166.68,72.77 166.25,73.2 165.89,73.2 165.84,73.15 164.82,73.15 R2492.1 164.08,73.89 163.23,73.89 162.67,74.45 R2491.1
KBC_PECI: length 2.3
  BOTTOM w0.102: KBC24.13 165.06,67.87 165.06,68.81 165.82,69.57 TP2407.1
KBC_PWRBTN#: length 264.4
  TOP w0.102: v2(40.93,65.31) 40.9,65.28 39.89,65.28 39.64,65.04 R9925.1
  L3 w0.102: v2(40.93,65.31) 41.69,64.54 43.93,64.54 52.61,55.86 60.48,55.86 61.6,54.73 61.6,44.12 61.45,43.97 61.45,42.99 60.94,42.48 60.94,41.82 52.51,33.39 52.51,30.47 58.7,24.28 132.65,24.28 136.25,20.68 142.09,20.68 142.63,21.21 150.06,21.21 157.98,29.14 157.98,41.94 159.11,43.07 v2(159.11,45.34)
  L4 w0.102: v2(161.48,110.95) 162.03,110.39 162.03,101.71 158.53,98.21 158.53,97.19 157.04,95.69 157.04,92.21 157.34,91.91 157.34,88.28 157.34,87.02 156.38,86.06 156.38,80.8 156.79,80.39 156.8,80.38 156.8,77.03 157.25,76.58 157.25,71.78 156.62,71.15 156.62,64.48 155.51,63.36 155.51,59 155.51,58.64 155.51,56.66 155.78,56.39 157.31,56.39 158.35,55.35 158.35,49.9 158.78,49.46 158.78,45.75 159.11,45.42 v2(159.11,45.34)
  BOTTOM w0.102: v2(159.11,45.34) 159.11,45.42 159.19,45.49 R2499.1 ; RN6401.2 165.66,115.14 v1(164.11,113.59) v2(161.48,110.95)
KBC_PWRBTN#_C: length 87
  TOP w0.127: ED6401.1 170.39,173.76 170.82,174.2 AFTP6404.1 169.76,175.85 G6401.2 169.76,176.81 170.39,177.45 v2(170.7,177.45)
  L4 w0.127: v2(170.85,116.72) 170.85,125.12 174.64,128.92 174.64,134.25 175.47,135.08 175.47,150.75 173.96,152.26 173.96,157.64 174.82,158.5 174.82,162.62 174.02,163.42 174.02,174.13 170.7,177.45 v2(170.7,177.45)
  BOTTOM w0.127: PWR1.2 171.05,177.8 v2(170.7,177.45) 170.39,177.45 169.76,176.81 G6401.2 169.78,176.2 169.78,175.5 170.29,175 EC6403.1 ; PWSW2.3 165.5,117.31 166.76,116.05 168.1,116.05 169.36,117.31 PWSW2.4 170.53,117.31 170.85,116.99 v2(170.85,116.72) 170.72,116.72 169.14,115.14 RN6401.3
KBC_VBKUP: length 3.7
  BOTTOM w0.203: 156.89,60.72 KBC24.114
  BOTTOM w0.254: 156.89,60.72 156.74,60.72 v1(156.19,61.27) 155.96,61.5 R2425.1
KBC_VCC: length 50.6
  TOP w0.508: v2(169.8,66.32) 169.01,66.32 168.57,65.88 C2431.1 ; v2(168.16,55.25) 168.16,55.22 168.83,54.55 v1(168.83,53.56) C2429.1 ; C2441.1 C2440.1 157.06,60.8 v2(157.55,61.29) 158.96,61.29 159.77,60.48 162.36,60.48 163.35,61.47 166.95,61.47 167.89,62.41 170.16,62.41 v2(170.19,62.38) ; v2(175.59,61.12) 175.57,61.14 C2430.1
  L4 w0.508: v2(168.16,55.25) 168.16,55.63 169.32,56.8 169.32,58.12 169.83,58.63 169.83,60.85 170.39,61.41 170.39,62.18 v2(170.19,62.38) 169.76,62.82 169.76,66.27 v2(169.8,66.32)
  BOTTOM w0.203: 168.23,54.21 168.23,53.36 168.25,53.33 KBC24.76 ; v2(175.59,61.12) KBC24.46 172.56,61.12 ; KBC24.19 167.45,66.97 168.11,66.32 v2(169.8,66.32) ; v2(157.55,61.29) 157.72,61.12 KBC24.115
  BOTTOM w0.508: v2(168.16,55.25) 168.16,55.22 168.23,55.15 168.23,54.21 ; v2(170.19,62.38) 171.03,62.38 172.29,61.12 172.56,61.12 ; C2414.1 R2408.1 175.9,60.81 v2(175.59,61.12)
KBC_VCC1D8V: length 7.5
  BOTTOM w0.203: KBC24.4 161.45,69.45 161.4,69.5
  BOTTOM w0.508: R2512.2 C2432.1 159.94,73.56 160.03,73.46 160.03,72.46 160.26,72.24 R2511.2 160.52,71.64 161.25,70.92 C2433.1 v1(161.4,69.68) 161.4,69.5
KBC_VCORF: length 3.4
  BOTTOM w0.203: 175.72,61.92 KBC24.44
  BOTTOM w0.508: v1(176.63,62.87) C2443.1 175.75,61.95 175.72,61.92
KSI0: length 64.4
  TOP w0.127: KB1.22 175.11,104.88 v2(172.52,102.29) 169.65,99.42 AFTP6507.1 170.16,93.09 170.16,92.12 171.2,91.08 v2(171.2,90.98)
  L3 w0.127: v2(173.06,57.99) 175.42,57.99 178.84,61.4 178.84,86.1 173.95,90.98 v2(171.2,90.98)
  BOTTOM w0.127: KBC24.54 173.2,57.92 173.13,57.99 v2(173.06,57.99) ; KB2.22 v2(172.52,102.29)
KSI1: length 58.3
  TOP w0.127: v2(176.41,58.27) 176.9,58.76 176.9,80.47 178.1,81.66 178.1,86.47 173.74,90.83 172.77,90.83 171.91,91.7 AFTP6540.1 171.14,92.24 171.14,99.28 v2(172.55,100.69) 175.14,103.28 KB1.24
  BOTTOM w0.127: KBC24.55 174.93,57.52 175.68,58.27 v2(176.41,58.27) ; KB2.24 v2(172.55,100.69)
KSI2: length 58
  TOP w0.127: v2(177.22,57.71) 177.41,57.9 177.41,80.01 178.61,81.21 178.61,87.72 AFTP6533.1 175.52,90.81 175.15,90.81 174.61,91.34 173.55,91.34 172.19,92.7 172.19,93.49 171.65,94.03 171.65,98.14 v2(172.6,99.09) 173.36,99.09 175.95,101.68 KB1.26
  BOTTOM w0.127: KB2.26 v2(172.6,99.09) ; KBC24.56 175.08,57.12 175.78,57.83 177.11,57.83 v2(177.22,57.71)
KSI3: length 61.9
  TOP w0.127: v2(176.13,57.38) 175.97,57.55 175.97,58.68 176.65,59.36 176.65,61.74 174.81,63.58 174.81,65.41 176.44,67.03 176.44,80.56 177.84,81.97 177.84,86.37 174.3,89.92 AFTP6502.1 171.69,90.68 171.69,91.18 170.88,91.98 170.88,99.81 v2(172.56,101.49) 175.15,104.08 KB1.23
  BOTTOM w0.127: v2(176.13,57.38) 176.05,57.3 175.62,57.3 175.04,56.72 KBC24.57 ; KB2.23 v2(172.56,101.49)
KSI4: length 59.4
  TOP w0.127: v2(178.54,57.71) 178.54,57.81 177.73,58.63 177.73,61.38 177.73,61.38 177.73,61.63 178.37,62.27 178.37,62.81 177.73,63.45 177.73,79.82 178.86,80.95 178.86,87.99 175.78,91.07 175.24,91.07 174.72,91.59 173.82,91.59 AFTP6521.1 172.57,92.84 172.57,93.6 171.9,94.28 171.9,97.63 v2(172.57,98.29) 173.67,98.29 176.26,100.88 KB1.27
  BOTTOM w0.127: KB2.27 v2(172.57,98.29) ; v2(178.54,57.71) 178.01,57.18 176.76,57.18 176.52,56.94 175.61,56.94 175,56.32 KBC24.58
KSI5: length 59.6
  TOP w0.127: KB1.25 175.17,102.48 v2(172.57,99.89) 171.39,98.71 171.39,93.77 AFTP6513.1 171.56,92.97 173.45,91.09 173.85,91.09 178.35,86.58 178.35,81.38 177.16,80.19 177.16,58.27 176.78,57.89 176.78,57.53 177.17,57.13 v2(177.17,56.62)
  BOTTOM w0.127: v2(177.17,56.62) 177.05,56.75 176.69,56.75 176.62,56.68 175.77,56.68 175.01,55.92 KBC24.59 ; KB2.25 v2(172.57,99.89)
KSI6: length 59.5
  TOP w0.127: v2(178.67,56.39) 178.99,56.7 178.99,57.42 178.99,57.99 177.99,58.99 177.99,61.52 178.67,62.21 178.67,62.92 178.06,63.53 178.06,79.76 179.12,80.81 179.12,88.09 175.88,91.33 175.34,91.33 174.87,91.8 174.87,92.45 AFTP6511.1 173.53,93.73 172.15,95.1 172.15,97.12 v2(172.57,97.54) 173.84,97.54 176.39,100.08 KB1.28
  BOTTOM w0.127: v2(172.57,97.54) 172.53,97.49 KB2.28 ; v2(178.67,56.39) 178.52,56.39 178.32,56.19 176.98,56.19 176.84,56.33 175.77,56.33 174.97,55.52 KBC24.60
KSI7: length 57.5
  TOP w0.127: v2(176.23,55.88) 178.79,55.88 179.12,56.21 179.24,56.33 179.24,56.6 179.24,57.32 179.24,57.32 179.24,61.41 178.98,61.67 178.98,63.07 178.37,63.68 178.37,79.61 179.24,80.48 179.24,80.49 179.37,80.62 179.37,88.2 175.87,91.7 AFTP6523.1 175.13,92.06 175.13,96.24 v2(175.58,96.69) 175.58,96.99 177.87,99.28 KB1.29
  BOTTOM w0.127: KBC24.61 175.19,55.12 175.95,55.88 v2(176.23,55.88) ; KB2.29 v2(175.58,96.69)
KSO0: length 81
  TOP w0.127: v2(171.38,89.03) 169.87,87.52 169.01,87.52 168.6,87.93 168.6,88.27 166.35,90.52 AFTP6520.1 165.73,91.18 165.73,93.22 165.48,93.47 165.48,95.09 165.68,95.29 165.68,102.61 v2(172.56,109.49) 175.15,112.08 KB1.13
  L3 w0.127: v2(171.38,89.03) 171.99,89.63 174.94,89.63 178.58,85.99 178.58,61.51 175.52,58.45 172.88,58.45 v2(172.42,57.99)
  BOTTOM w0.127: v2(172.42,57.99) 172.87,58.43 173.24,58.43 173.35,58.32 KBC24.53 ; KB2.13 v2(172.56,109.49)
KSO1: length 77.1
  TOP w0.127: KB1.15 175.1,110.48 v2(172.51,107.89) 166.78,102.16 166.78,93.68 166.1,92.99 AFTP6517.1 166.1,91.33 168.85,88.57 168.85,88.04 169.12,87.77 169.72,87.77 170.91,88.96 170.91,89.19 171.2,89.47 171.6,89.47 172.33,88.75 173.22,88.75 173.43,88.96 v2(173.76,88.96)
  L3 w0.127: v2(173.76,88.96) 174.15,89.35 174.87,89.35 178.33,85.89 178.33,61.61 175.75,59.03 v2(172.75,59.03)
  BOTTOM w0.127: v2(172.75,59.03) 173.13,59.03 173.43,58.72 KBC24.52 ; KB2.15 v2(172.51,107.89)
KSO2: length 71.8
  TOP w0.127: v2(166,93.68) 165.84,93.83 AFTP6510.1 165.84,95.1 165.93,95.19 165.93,102.07 v2(172.55,108.69) 175.14,111.28 KB1.14
  L3 w0.127: v2(171.25,59.03) 170.84,59.45 170.84,61.1 172.37,62.64 172.37,66.11 172.8,66.55 172.8,67.48 174.76,69.43 174.76,74.73 172.35,77.14 172.07,77.14 167.93,81.28 167.93,84.13 167.15,84.91 166.24,84.91 165.04,86.1 165.04,87.34 164.36,88.02 164.36,89.7 166,91.33 v2(166,93.68)
  BOTTOM w0.127: KBC24.51 173.47,59.12 173.12,59.48 172.57,59.48 172.1,59.01 171.28,59.01 v2(171.25,59.03) ; KB2.14 v2(172.55,108.69)
KSO3: length 69.1
  TOP w0.127: v2(170.45,89.13) 170.45,89.06 170.08,88.69 170.08,88.67 169.55,88.14 AFTP6518.1 169.11,88.31 169.11,88.81 167,90.92 167,93.53 167.04,93.57 167.04,101.58 v2(172.55,107.09) 175.14,109.68 KB1.16
  L3 w0.127: v2(175.47,59.74) 175.4,59.74 174.89,60.25 174.89,61.43 177.57,64.11 177.57,84.91 174.27,88.2 171.38,88.2 v2(170.45,89.13)
  BOTTOM w0.127: KBC24.50 175.25,59.52 v2(175.47,59.74) ; KB2.16 v2(172.55,107.09)
KSO4: length 61.2
  TOP w0.127: KB1.20 175.16,106.48 v2(172.57,103.89) 169.03,100.35 169.03,91.91 170.44,90.5 170.44,89.89 AFTP6522.1 171.73,89.79 171.85,89.63 172.3,89.19 v2(172.98,89.19)
  L3 w0.127: v2(175.37,60.4) 175.14,60.63 175.14,61.32 177.82,64 177.82,85.01 174.37,88.46 173.63,88.46 172.98,89.11 v2(172.98,89.19)
  BOTTOM w0.127: KB2.20 v2(172.57,103.89) ; v2(175.37,60.4) 175.37,60.36 174.93,59.92 KBC24.49
KSO5: length 64
  TOP w0.127: KB1.21 175.13,105.68 v2(172.54,103.09) 169.29,99.84 169.29,93.08 169.78,92.59 AFTP6536.1 171.42,90.06 171.85,90.06 172.04,89.8 172.3,89.55 172.69,89.55 172.77,89.63 173.95,89.63 v2(174.68,88.9)
  L3 w0.127: v2(174.68,88.9) 178.07,85.51 178.07,63.84 176.33,62.09 176.33,59.98 175.65,59.3 173.68,59.3 173.03,59.95 v2(172.98,59.95)
  BOTTOM w0.127: v2(172.98,59.95) 172.98,60.1 173.21,60.32 KBC24.48 ; KB2.21 v2(172.54,103.09)
KSO6: length 78.7
  TOP w0.127: v2(169.77,89.88) 169.32,89.88 168.57,90.63 168.55,90.63 167.51,91.67 167.51,92.88 167.75,93.12 AFTP6512.1 167.94,93.92 167.94,100.9 v2(172.53,105.49) 175.12,108.08 KB1.18
  L3 w0.127: v2(169.77,89.88) 169.77,89.89 170.23,90.34 170.23,90.64 171.02,91.43 173.86,91.43 179.09,86.2 179.09,61.28 177.65,59.84 177.65,58.89 176.59,57.83 175.62,57.83 175.34,57.55 174.78,57.55 174.77,57.56 173.25,57.56 173.24,57.55 172.24,57.55 171.98,57.81 171.98,58.41 172.21,58.64 172.21,60.14 v2(172.5,60.43)
  BOTTOM w0.127: KBC24.47 173.3,60.72 173.27,60.7 172.87,60.7 172.6,60.43 v2(172.5,60.43) ; KB2.18 v2(172.53,105.49)
KSO7: length 80.4
  TOP w0.127: v2(169.78,90.53) 169.17,90.53 AFTP6534.1 167.88,92.89 168.38,93.4 168.38,100.54 v2(172.54,104.69) 175.13,107.28 KB1.19
  L3 w0.127: v2(169.78,90.53) 169.78,90.55 170.91,91.68 173.97,91.68 179.34,86.31 179.34,61.61 179.34,61.17 177.99,59.81 177.99,57.84 177.28,57.14 176.72,57.14 176.52,56.94 175.66,56.94 175.31,57.29 174.68,57.29 174.67,57.3 173.36,57.3 173.35,57.29 172.13,57.29 171.72,57.7 171.72,58.51 171.95,58.74 171.95,61.35 172.93,62.32 v2(173.03,62.32)
  BOTTOM w0.127: KB2.19 v2(172.54,104.69) ; KBC24.43 v2(173.03,62.32)
KSO8: length 62.6
  TOP w0.127: KB1.17 175.15,108.88 v2(172.56,106.29) 167.29,101.02 167.29,93.47 167.25,93.43 167.25,91.43 168.31,90.37 AFTP6505.1 169.45,89.23 v2(169.73,89.23)
  L3 w0.127: v2(176.08,63.25) 177.31,64.48 177.31,84.8 177.06,85.05 174.16,87.95 171,87.95 169.73,89.22 v2(169.73,89.23)
  BOTTOM w0.127: KB2.17 v2(172.56,106.29) ; KBC24.42 175.56,62.72 v2(176.08,63.25)
KSO9: length 74.1
  TOP w0.127: KB1.7 175.04,116.88 v2(172.45,114.29) 172.45,114.12 164.15,105.83 164.15,95.93 163.81,95.58 AFTP6516.1 163.81,92.98 164.18,92.61 164.18,91.4 164.04,91.26 163.82,91.05 163.82,90.4 164.71,89.51 v2(164.8,89.51)
  L3 w0.127: v2(164.8,89.51) 164.8,87.94 165.4,87.35 167.45,87.35 172.9,81.89 175.45,81.89 176.3,81.04 176.3,67.03 172.93,63.66 v2(172.93,63.17)
  BOTTOM w0.127: KBC24.41 172.98,63.12 v2(172.93,63.17) ; KB2.7 v2(172.45,114.29)
KSO10: length 79
  TOP w0.127: KB1.5 175.1,118.48 v2(172.51,115.89) 172.51,115.81 163.65,106.95 163.65,96.14 161.91,94.4 AFTP6503.1 161.91,93.88 163.02,92.76 163.02,90.48 164.1,89.4 164.1,89.04 165.03,88.11 v2(165.62,88.11)
  L3 w0.127: v2(176.08,63.98) 177.06,64.96 177.06,84.69 176.8,84.95 174.06,87.7 170.65,87.7 169.84,88.51 166.03,88.51 165.64,88.11 v2(165.62,88.11)
  BOTTOM w0.127: KB2.5 v2(172.51,115.89) ; v2(176.08,63.98) 175.57,63.48 175.13,63.48 175.09,63.52 KBC24.40
KSO11: length 75.8
  TOP w0.127: v2(165.51,88.75) 164.76,88.75 164.36,89.15 164.36,89.51 163.57,90.29 163.57,91.35 163.81,91.59 AFTP6506.1 163.81,92.58 163.32,93.08 163.32,95.42 163.52,95.62 163.52,95.65 163.9,96.03 163.9,106.54 v2(172.45,115.09) 175.04,117.68 KB1.6
  L3 w0.127: v2(175.36,63.92) 175.41,63.97 175.41,64.91 176.55,66.05 176.55,83.77 176.3,84.03 173.13,87.19 170.44,87.19 170.03,87.6 165.5,87.6 165.17,87.93 165.17,88.41 v2(165.51,88.75)
  BOTTOM w0.127: KBC24.39 v2(175.36,63.92) ; KB2.6 v2(172.45,115.09)
KSO12: length 67.2
  TOP w0.127: v2(167.37,88.06) AFTP6538.1 167.37,89.02 165.48,90.91 165.48,93.11 165.22,93.37 165.22,95.2 165.42,95.4 165.42,102.86 171,108.44 171,108.79 v2(172.5,110.29) 175.09,112.88 KB1.12
  L3 w0.127: v2(167.37,88.06) 167.48,87.95 170.04,87.95 170.54,87.44 173.24,87.44 176.55,84.13 176.8,83.88 176.8,65.67 v2(175.85,64.72)
  BOTTOM w0.127: v2(175.85,64.72) 175.55,64.72 175.15,64.32 KBC24.38 ; KB2.12 v2(172.5,110.29)
KSO13: length 68.4
  TOP w0.127: KB1.9 175.04,115.28 v2(172.45,112.69) 164.66,104.9 164.66,95.71 164.46,95.51 164.46,93.05 164.7,92.81 164.7,90.73 164.7,90.6 166.35,88.95 166.35,87.02 AFTP6535.1 v2(166.33,86.36)
  L3 w0.127: v2(175.57,67.13) 176.04,67.6 176.04,80.89 175.42,81.51 172.92,81.51 168.07,86.36 v2(166.33,86.36)
  BOTTOM w0.127: v2(175.57,67.13) 175.57,65.11 175.19,64.72 KBC24.37 ; KB2.9 v2(172.45,112.69)
KSO14: length 69.7
  TOP w0.127: KB1.8 175.04,116.08 v2(172.45,113.49) 164.41,105.45 164.41,95.82 164.21,95.62 164.21,92.94 164.45,92.7 164.45,91.31 164.19,91.06 AFTP6539.1 164.39,90.55 166.06,88.88 166.06,87.64 165.88,87.47 165.88,86.03 166.1,85.81 v2(166.1,85.68)
  L3 w0.127: v2(166.1,85.68) 166.22,85.8 167.92,85.8 172.53,81.18 175.24,81.18 175.79,80.63 175.79,68.31 v2(175.01,67.54)
  BOTTOM w0.127: KB2.8 v2(172.45,113.49) ; v2(175.01,67.54) 175.01,67.06 175.22,66.86 175.22,65.28 175.06,65.12 KBC24.36
KSO15: length 67.8
  TOP w0.127: v2(167.48,85.35) 167.17,85.04 AFTP6515.1 166.96,87.28 166.61,87.63 166.61,89.06 164.96,90.71 164.96,90.79 164.96,90.8 164.96,92.91 164.71,93.16 164.71,95.41 164.92,95.61 164.92,104.36 v2(172.45,111.89) 175.04,114.48 KB1.10
  L3 w0.127: v2(167.48,85.35) 168,85.35 173.92,79.43 173.92,76.29 175.27,74.94 175.27,69.14 173.41,67.29 173.41,64.92 172.93,64.44 v2(172.93,64.34)
  BOTTOM w0.127: KB2.10 v2(172.45,111.89) ; KBC24.35 173.45,65.52 173.18,65.25 173.18,64.7 172.93,64.44 v2(172.93,64.34)
KSO16: length 64
  TOP w0.127: v2(168.56,83.59) 168.51,83.59 168.23,83.87 AFTP6508.1 166.89,87.84 166.89,89.14 165.21,90.82 165.21,90.84 165.21,93.02 164.97,93.26 164.97,95.3 165.17,95.5 165.17,103.81 v2(172.45,111.09) 175.04,113.68 KB1.11
  L3 w0.127: v2(172.96,65.66) 173.06,65.76 173.06,67.29 175.01,69.25 175.01,74.84 173.43,76.43 173.43,79.57 169.4,83.59 v2(168.56,83.59)
  BOTTOM w0.127: KBC24.34 173.14,65.92 172.96,65.74 v2(172.96,65.66) ; KB2.11 v2(172.45,111.09)
L_BKLT_CTRL: length 28
  TOP w0.102: Q5504.C 96.07,156.33 R5529.2 98.23,155.96 98,155.73 98,154.76 98.19,154.57 114.5,154.57 114.87,154.94 v1(114.87,155.09) 114.87,156.57 114.7,156.73 D5502.1 113.75,159.04 114.27,159.55 R5510.2
L_BKLT_CTRL_B: length 4.6
  TOP w0.102: v1(93.99,158.93) 94.32,158.6 95.03,158.6 95.85,157.77 Q5504.B 96.59,157.78 R5530.2
L_BKLT_EN_EC: length 5.7
  BOTTOM w0.102: R2444.1 170.92,72.57 170.44,72.09 170.44,71.68 168.99,70.23 168.99,69.83 168.65,69.49 v1(168.65,69.46) KBC24.22
LAN_CLKREQ_CPU#: length 5.6
  BOTTOM w0.102: CPU1.AJ62 112.43,79.94 112.45,79.76 112.39,79.59 112.27,79.49 112.17,79.48 112.1,79.48 111.97,79.5 111.69,79.45 v1(109.48,77.57) 109.47,77.56 RN1603.2
LCD_BRIGHTNESS: length 7
  TOP w0.102: v2(108.24,173.1) AFTP5517.1 106.75,174.17 EC5506.1 105.35,174.21 104.47,175.09 RN5501.3
  BOTTOM w0.102: LCD1.20 108.24,173.12 v2(108.24,173.1)
LCD_TST: length 174.1
  TOP w0.102: v2(103.77,177.78) 103.97,177.57 RN5501.7 ; v2(153.78,64.52) v1(154.34,64.52)
  L4 w0.102: v2(153.78,64.52) 154.64,65.38 154.64,71.25 155.27,71.88 155.27,75.79 154.19,76.87 154.19,77.56 154.17,77.58 154.17,83.11 154.6,83.54 154.6,86.37 154.62,86.38 155.86,87.63 155.86,90.73 155.57,91.02 155.57,96.95 156.4,97.77 156.4,98.16 160,101.77 160,107.32 158.99,108.34 158.99,125.59 160.04,126.64 160.04,131.21 163.46,134.62 v2(164.37,134.62)
  BOTTOM w0.102: v2(153.78,64.52) 153.78,64.52 153.87,64.52 R2498.1 ; v2(164.37,134.62) 164.78,135.03 164.78,136.27 160.74,140.31 153.55,140.31 149.97,143.89 146.41,143.89 138.39,151.91 132.7,151.91 127.72,156.89 127.72,162.46 122.54,167.64 122.54,179.86 119.41,182.98 113.58,182.98 110.53,179.94 105.93,179.94 v2(103.77,177.78)
LCD_TST_C: length 5.7
  TOP w0.102: RN5501.2 AFTP5514.1 104.38,172.96 104.38,172.67 v2(104.25,171.99)
  BOTTOM w0.102: 103.86,170.58 103.7,171.05 103.73,171.19 v2(104.25,171.99)
LCD_TST_EN: length 144.9
  TOP w0.102: D5501.2 107.84,158 106.03,156.19 R5504.1 105.3,155.74 105.98,155.07 v1(106.02,155.07) 113.57,155.07 v2(113.62,155.02) ; v2(169.55,130.25) 164.32,130.25 v2(163.38,129.31)
  L4 w0.102: v2(171.71,69.45) 171.91,69.65 171.91,71.39 169.23,74.07 169.23,88.27 168.87,88.64 168.87,92.83 169.32,93.29 169.32,130.02 v2(169.55,130.25)
  BOTTOM w0.102: v2(163.38,129.31) 162.06,129.31 158.38,133 154.21,133 151.72,135.49 148.76,135.49 143.43,140.81 143.43,141.99 137.08,148.34 130.87,148.34 127.02,152.19 116.45,152.19 v2(113.62,155.02) ; v2(171.71,69.45) 171.66,69.39 171.66,69.38 171.05,68.77 KBC24.28
LCD_TST_KBC: length 5.2
  BOTTOM w0.102: KBC24.123 156.87,64.32 156.32,64.87 156.32,65.64 156.04,65.92 v1(155.79,65.92) 155.58,65.92 155.29,65.62 R2498.2
LDO1_CAP: length 5.1
  BOTTOM w0.203: HDA27.27 162.86,16.74 162.89,16.71 163.23,16.37 163.23,16.21
  BOTTOM w0.305: R2713.2 161.87,13.78 162.24,14.15 C2702.2 163.23,14.53 v1(163.23,15.9) 163.23,16.21
LDO2_CAP: length 2.1
  BOTTOM w0.203: 157.21,18.8 157.33,18.8 157.59,19.05 HDA27.39
  BOTTOM w0.305: C2712.2 156.98,18.57 157.21,18.8
LDO3_CAP: length 3.6
  BOTTOM w0.203: v1(161.7,24.67) 161.66,24.62 HDA27.7
  BOTTOM w0.305: C2718.1 160.84,26.42 161.56,25.7 161.56,25.11 161.66,25.01 161.66,24.71 v1(161.7,24.67)
LID_CLOSE#: length 68.2
  TOP w0.102: R2473.2 154.43,58.13 155.08,58.78 v2(155.08,58.93)
  L4 w0.102: v2(155.08,58.93) 155.18,59.03 155.18,63.35 156.39,64.57 156.39,71.25 157.02,71.87 157.02,76.49 156.51,76.99 156.51,80.34 156.15,80.7 156.15,86.16 157.11,87.11 157.11,88.37 157.11,91.82 156.81,92.11 156.81,95.79 158.26,97.24 158.26,98.26 161.81,101.81 161.81,106.92 161.53,107.2 v2(161.53,110.24)
  BOTTOM w0.102: RN6401.1 165.77,114.48 v1(162.3,111.01) v2(161.53,110.24) ; KBC24.107 156.26,57.92 155.91,58.27 D2401.K 155.18,58.83 v2(155.08,58.93)
LID_CLOSE#_C: length 74.2
  TOP w0.102: v2(170.72,176.8) 171.42,177.5 AFTP6401.1
  L4 w0.102: v2(170.72,176.8) 173.73,173.79 173.73,157.75 173.72,157.74 173.72,152.15 175.09,150.78 175.09,144.81 175.23,144.67 175.23,135.18 174.25,134.2 174.25,128.96 170.42,125.12 170.42,116.38 v2(170.85,115.95)
  BOTTOM w0.102: v2(170.85,115.95) 170.19,115.29 169.93,115.29 169.13,114.48 RN6401.4 ; PWR1.3 v2(170.72,176.8) 170.72,176.38 170.24,175.9 170.24,175.39 171.15,174.47 EC6401.1
LINE1-L_C: length 2.2
  BOTTOM w0.254: R2920.1 166.67,14.21 167.14,14.68 v1(167.14,14.78) 166.99,14.94 C2903.2
LINE1-L_R: length 2.1
  BOTTOM w0.254: C2904.2 167.55,16.18 R2919.1 168.61,15.86 v1(168.61,15.22)
LINE1_L: length 5
  BOTTOM w0.203: 165.2,18.84 164.99,19.05 HDA27.22
  BOTTOM w0.254: 165.2,18.84 165.25,18.79 165.25,17.14 164.98,16.87 v1(164.98,16.13) 165.03,16.08 165.03,15.19 C2903.1
LINE1_R: length 4.1
  BOTTOM w0.203: 165.58,18.97 165.1,19.45 HDA27.21
  BOTTOM w0.254: 165.58,18.97 v1(165.76,18.79) 166.02,18.53 C2904.1
LINE1_VREFO_L: length 3.4
  TOP w0.254: v2(161.14,16.13) 161.27,16.26 161.27,16.56 161.3,16.58 161.3,16.6 R2912.1 162.33,16.96 v1(162.59,17.22)
  BOTTOM w0.203: v2(161.14,16.13) 161.26,16.25 HDA27.31
LINE1_VREFO_R: length 4.1
  TOP w0.254: v1(161.55,14.58) 161.55,14.84 v2(161.93,15.22) 162.19,15.47 162.58,15.47 R2913.1
  BOTTOM w0.203: v2(161.93,15.22) 161.93,15.27 161.66,15.54 HDA27.30
LPC_AD_CPU_P0: length 195.8
  TOP w0.14: v2(142.25,44.05) 141.15,45.14 v1(141.15,51.11) 141.15,61.84 141.82,62.52 141.82,64.01 141.13,64.7 141.13,70.41 151.65,80.93 v2(152.69,80.93) ; RN1905.5 101.86,85.24 101.6,85.24 100.94,84.58 98.4,84.58 96.73,82.9 94.5,82.9 88.45,76.85 88.45,75.49 89.71,74.23 89.71,69.44 89.87,69.27 89.87,65.13 88.68,63.93 v2(88.68,63.55)
  L3 w0.127: v2(88.68,63.55) 88.68,62.2 82.58,56.1 82.58,51.99 82.61,51.97 82.61,49.12 77.59,44.1 77.59,39.99 77.43,39.83 77.43,38.76 77.72,38.46 77.73,38.46 v2(77.86,38.33)
  BOTTOM w0.14: R9923.1 152.89,81.64 152.69,81.43 v2(152.69,80.93) 152.69,79.89 156.85,75.72 156.85,72.04 156.39,71.57 156.39,66.58 157.45,65.52 KBC24.126 ; v2(142.25,44.05) 141.69,44.6 87.69,44.6 84.67,41.58 80.91,41.58 78.92,39.59 77.74,39.59 77.39,39.25 77.39,38.77 77.83,38.33 v2(77.86,38.33)
LPC_AD_CPU_P1: length 190
  TOP w0.14: v2(90.39,64.87) 90.39,69.49 90.36,69.52 90.36,74.33 90.36,75.33 98.76,83.73 101.58,83.73 102.43,84.58 RN1905.6 ; v2(153.65,81.66) 153.6,81.61 151.59,81.61 140.61,70.63 140.61,64.49 141.26,63.83 141.26,62.7 140.63,62.06 v1(140.63,57.79) 140.63,44.93 141.59,43.97 v2(141.59,43.92)
  L3 w0.127: v2(77.93,38.97) 77.93,39.55 78.1,39.71 78.1,43.89 83.12,48.91 83.12,55.91 89.34,62.14 89.34,63.82 v2(90.39,64.87)
  BOTTOM w0.14: R9928.1 153.75,82.53 153.69,82.47 153.69,81.7 v2(153.65,81.66) 153.21,81.22 153.21,80.1 157.37,75.94 157.37,71.82 156.91,71.36 156.91,66.75 157.73,65.92 KBC24.127 ; v2(141.59,43.92) 141.42,44.08 87.9,44.08 84.88,41.06 81.12,41.06 79.02,38.97 v2(77.93,38.97)
LPC_AD_CPU_P2: length 192.8
  TOP w0.14: v2(90.89,65.79) 90.91,65.81 90.91,70.13 90.88,70.16 90.88,74.54 90.88,75.11 98.93,83.16 98.93,83.16 98.96,83.19 101.79,83.19 102.68,84.08 RN1905.7 ; v2(141.59,43.18) v1(140.65,44.12) 140.07,44.7 140.07,70.87 151.33,82.13 153.82,82.13 154.12,81.83 154.12,81.37 v2(153.73,80.98)
  L3 w0.127: v2(90.89,65.79) 90.9,65.78 90.9,64.58 89.91,63.59 89.91,61.99 83.62,55.7 83.62,48.7 78.61,43.68 78.61,38.29 77.97,37.64 v2(77.86,37.64)
  BOTTOM w0.14: KBC24.128 158.71,67.33 157.89,68.15 157.89,76.16 153.73,80.32 v2(153.73,80.98) 154.21,81.46 154.21,82.25 154.62,82.66 R9931.1 ; v2(141.59,43.18) 141.21,43.56 88.12,43.56 85.1,40.54 81.34,40.54 78.44,37.64 v2(77.86,37.64)
LPC_AD_CPU_P3: length 193.7
  TOP w0.14: v2(154.69,82.09) 154.3,82.49 151.2,82.49 139.73,71.02 139.73,44.4 141.58,42.55 v2(141.59,42.55) ; RN1905.8 102.74,83.43 102.53,83.21 101.99,82.82 99.07,82.82 91.22,74.97 91.22,74.69 91.23,74.69 91.23,70.31 91.37,70.16 91.37,66.3 v2(91.4,66.27)
  L3 w0.127: v2(77.88,36.98) 78.94,38.04 78.94,43.54 83.95,48.56 83.95,55.57 90.24,61.85 90.24,62.13 90.24,62.13 90.24,63.45 91.23,64.44 91.23,65.41 91.4,65.57 v2(91.4,66.27)
  BOTTOM w0.14: v2(141.59,42.55) 141.4,42.73 141.4,42.73 140.91,43.22 88.26,43.22 85.24,40.2 81.48,40.2 78.26,36.98 v2(77.88,36.98) ; KBC24.1 158.66,67.87 158.24,68.29 158.24,76.5 154.7,80.03 v1(154.7,81.41) 154.7,82.09 v2(154.69,82.09) 154.77,82.09 155.46,82.78 R9932.1
LPC_CLK_CPU_P0: length 5.9
  TOP w0.14: v2(108.99,82.19) 108.89,81.85 108.6,81.5 108.18,81.44 R1905.2
  BOTTOM w0.089: CPU1.AB61 111.35,83.32 111.02,82.99 110.9,82.97 110.76,82.97 110.75,82.98 110.63,82.98 110.5,82.93 110.48,82.91 110.42,82.89 110.14,82.6 109.92,82.52 109.37,82.32 109.01,82.19 v2(108.99,82.19)
  BOTTOM w0.14: v1(107.86,82.15) 108.22,82.38 108.57,82.38 v2(108.99,82.19)
LPC_CLK_CPU_P1: length 7.1
  BOTTOM w0.089: 109.35,82.88 109.46,82.83 109.64,82.83 109.79,82.88 110.07,83.17 110.56,83.34 110.73,83.51 CPU1.AA62
  BOTTOM w0.102: 109.35,82.88 109.11,82.88 109.04,82.81 108.7,82.81 108.57,82.94 108.25,82.94
  BOTTOM w0.14: 108.25,82.94 107.96,82.87 107.02,82.67 106.44,82.67 106.26,82.86 v1(106.2,82.86) 106.11,82.96 105.66,83.11 105.38,83.11 R1908.2
LPC_CLK_DBG: length 190.2
  TOP w0.14: v2(152.76,78.79) 150.98,78.79 142.86,70.67 142.86,62.09 142.25,61.47 v1(142.25,46.36) 142.25,45.75 v2(142.35,45.65) ; v2(98.23,67.41) 98.23,67.88 98.49,68.14 98.49,68.14 99.48,69.13 101.67,71.32 102.45,72.1 102.45,75.13 101.39,76.19 101.39,79.05 103.02,80.69 EC1902.1 105.24,80.69 105.94,80.55 106.32,80.55 106.58,80.82 106.59,80.82 106.94,81.14
  L3 w0.127: v2(80.8,42.63) 80.8,43.23 85.48,47.91 85.48,54.93 91.77,61.22 91.77,62.76 91.76,62.76 91.76,62.82 92.79,63.85 92.79,65.08 93.03,65.32 95.14,65.32 97.24,67.41 v2(98.23,67.41)
  BOTTOM w0.14: DB1.2 159.78,83.98 160.02,84.23 160.02,87.83 162.68,90.48 162.68,93.96 162.48,94.15 160.95,94.15 160.75,94.36 158.52,94.36 157.34,93.19 157.34,91 152.15,85.8 152.15,79.63 152.76,79.02 v2(152.76,78.79) ; v2(80.8,42.63) 82.89,42.63 84.19,42.63 87.21,45.65 v2(142.35,45.65)
LPC_CLK_KBC: length 187.8
  TOP w0.14: v2(142.27,44.96) 141.67,45.56 v1(141.67,49.15) 141.67,61.63 142.34,62.3 142.34,70.89 151.54,80.09 v2(155.38,80.09)
  L3 w0.127: v2(79.5,42.45) 79.5,43.38 84.46,48.35 84.46,55.36 90.75,61.64 90.75,62.34 90.75,62.34 90.75,63.24 91.74,64.23 91.74,65.06 92.5,65.83 94.81,65.83 97.29,68.3 100.93,68.3 103.28,70.66 103.28,71.57 106.9,75.19 107,75.19 111.11,79.29 111.11,81.47 110.85,81.73 110.44,81.73 110.22,81.51 107.6,81.51 106.53,82.58 v2(105.57,82.58)
  BOTTOM w0.127: 105.19,82.28 v2(105.57,82.58) ; R1908.1 EC1901.1
  BOTTOM w0.14: v2(142.27,44.96) 142.11,45.13 87.42,45.13 84.4,42.11 79.84,42.11 v2(79.5,42.45) ; 105.19,82.28 104.84,82.12 104.14,81.82 104.11,81.82 103.66,81.82 103.53,81.82 EC1901.1 ; KBC24.2 160.65,68.77 160.48,68.94 159.79,68.94 158.99,69.74 158.99,70.21 158.99,73.03 158.89,73.12 158.89,74.99 158.99,75.08 158.99,76.48 v2(155.38,80.09)
LPC_FRAME#_CPU: length 207.1
  TOP w0.14: v2(92.29,64.82) 92.29,64.85 91.92,65.21 91.92,70.1 91.57,70.45 91.57,74.83 99.22,82.48 104.58,82.48 105.25,83.15 106.27,83.15 106.96,83.2 107.27,83.22 108.26,84.21 v2(108.26,85.09) ; v2(155.15,80.8) 155.15,82.12 155.14,82.13 155.14,82.28 154.59,82.83 150.98,82.83 139.38,71.24 139.38,44.01 v1(140.78,42.62) v2(141.56,41.84)
  L3 w0.127: v2(77.91,36.32) 79.43,37.85 79.43,41.66 80.04,42.27 80.04,43.21 84.97,48.14 84.97,55.15 91.26,61.43 91.26,62.55 91.26,62.55 91.26,63.03 92.29,64.06 v2(92.29,64.82)
  BOTTOM w0.089: 109.34,84.77 109.36,84.78 109.41,84.9 109.41,84.9 109.65,84.99 109.66,84.99 109.95,85.1 110.03,85.19 110.13,85.29 110.36,85.29 110.42,85.28 CPU1.V61
  BOTTOM w0.102: v2(108.26,85.09) 108.62,84.87 108.98,84.7 109.15,84.7 109.34,84.77
  BOTTOM w0.14: R9915.1 156.32,82.45 155.15,81.28 v2(155.15,80.8) 155.51,80.8 159.51,76.8 159.51,74.79 159.41,74.69 159.41,73.34 159.51,73.24 159.51,69.96 159.99,69.47 160.51,69.47 161.05,68.93 KBC24.3 ; v2(77.91,36.32) 78.09,36.32 81.62,39.86 85.38,39.86 88.4,42.88 116.59,42.88 117.53,41.94 141.46,41.94 v2(141.56,41.84)
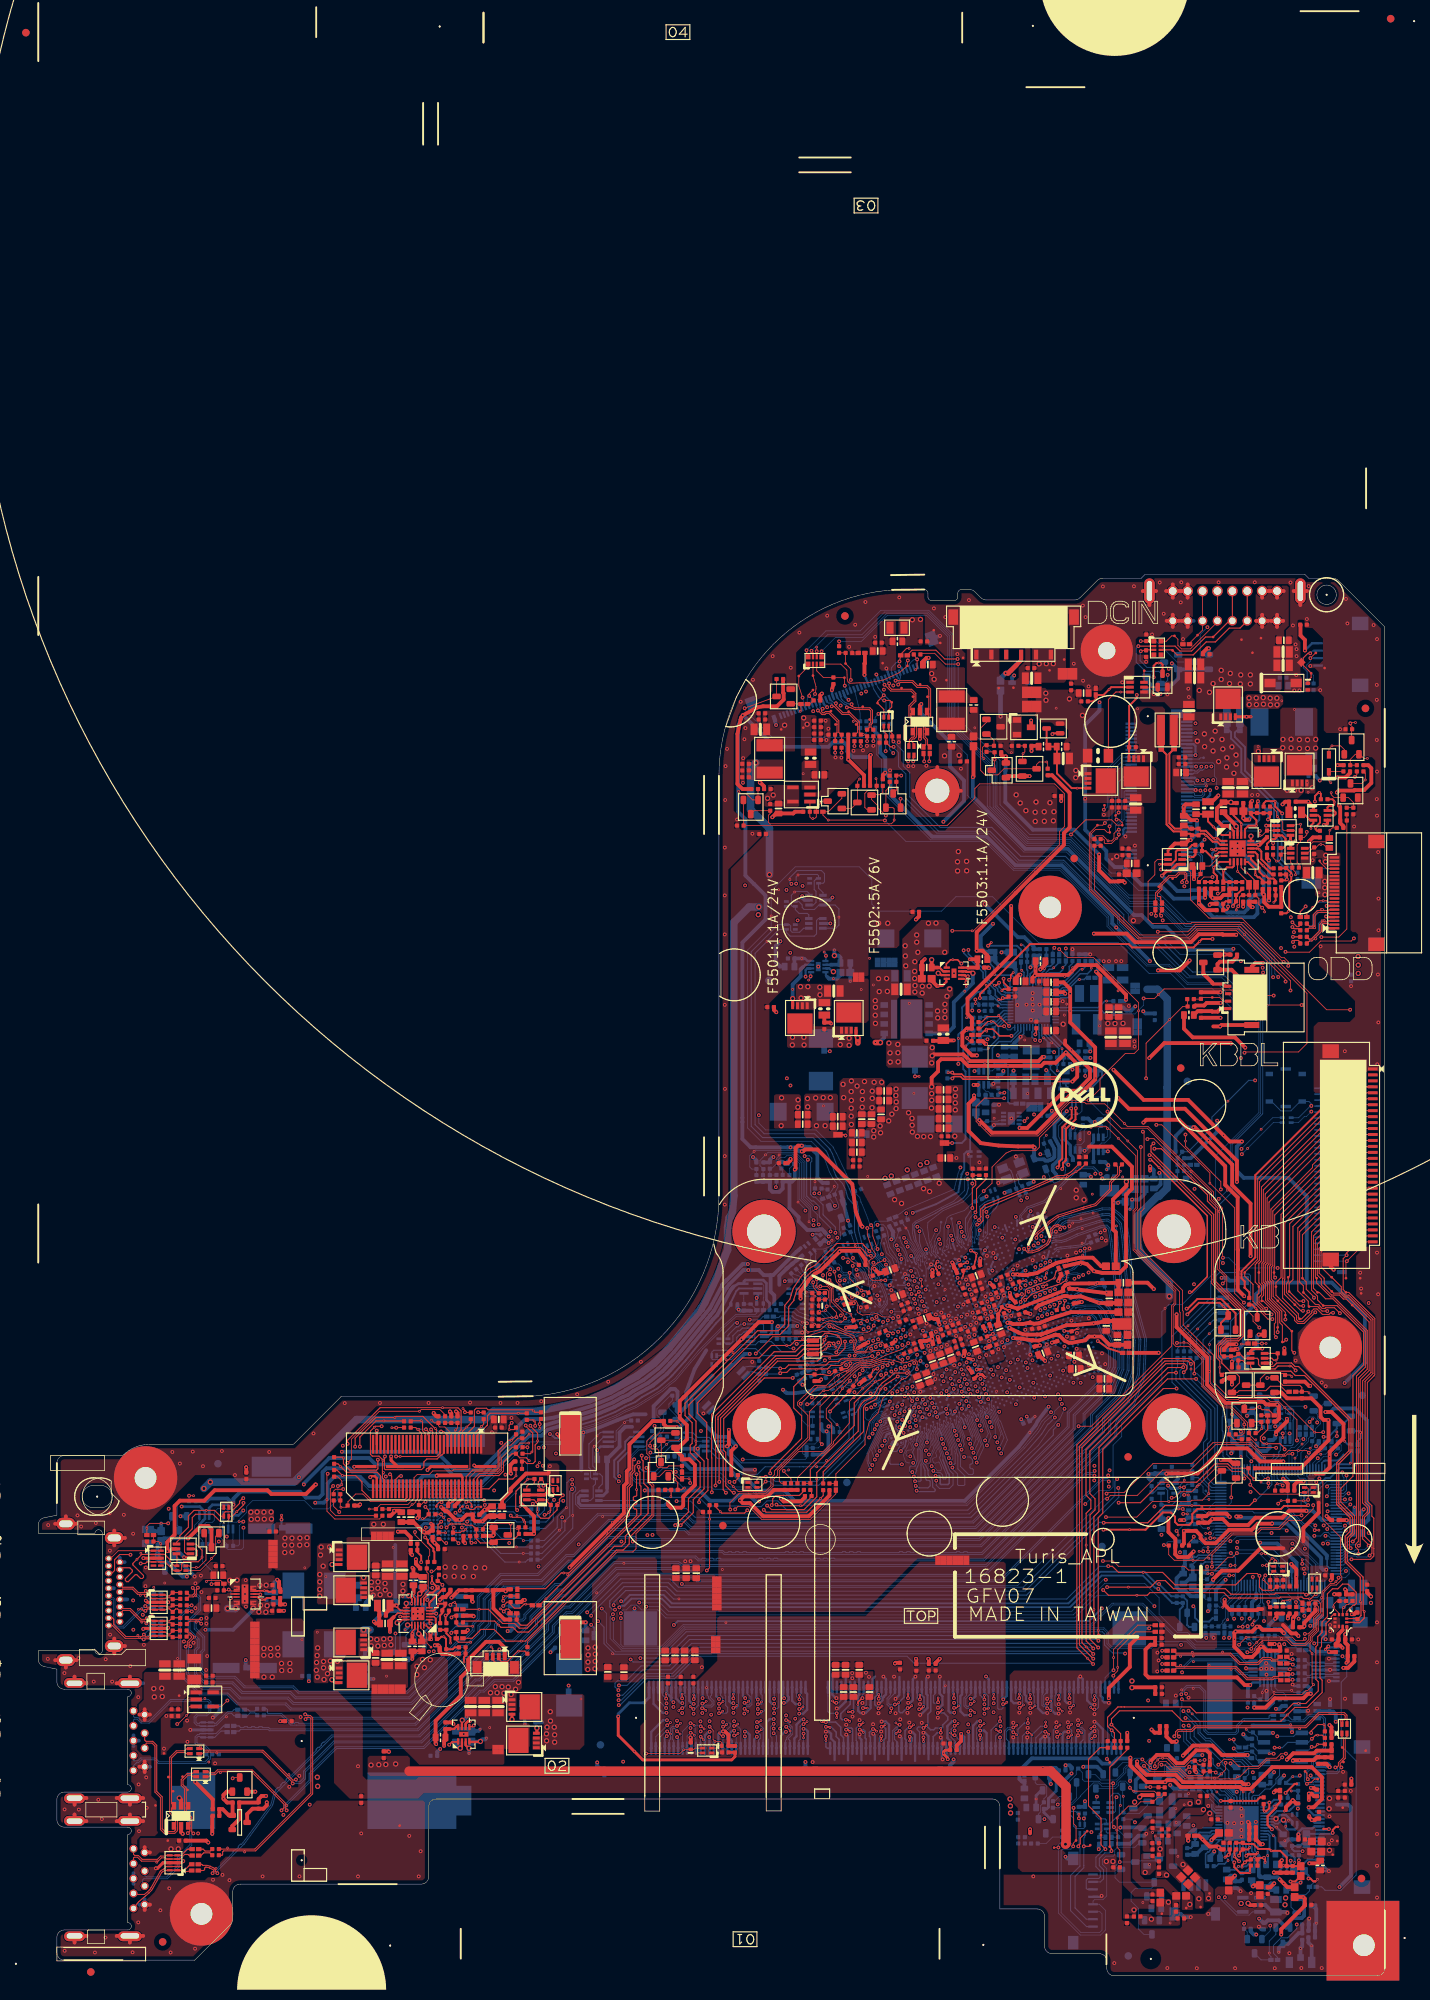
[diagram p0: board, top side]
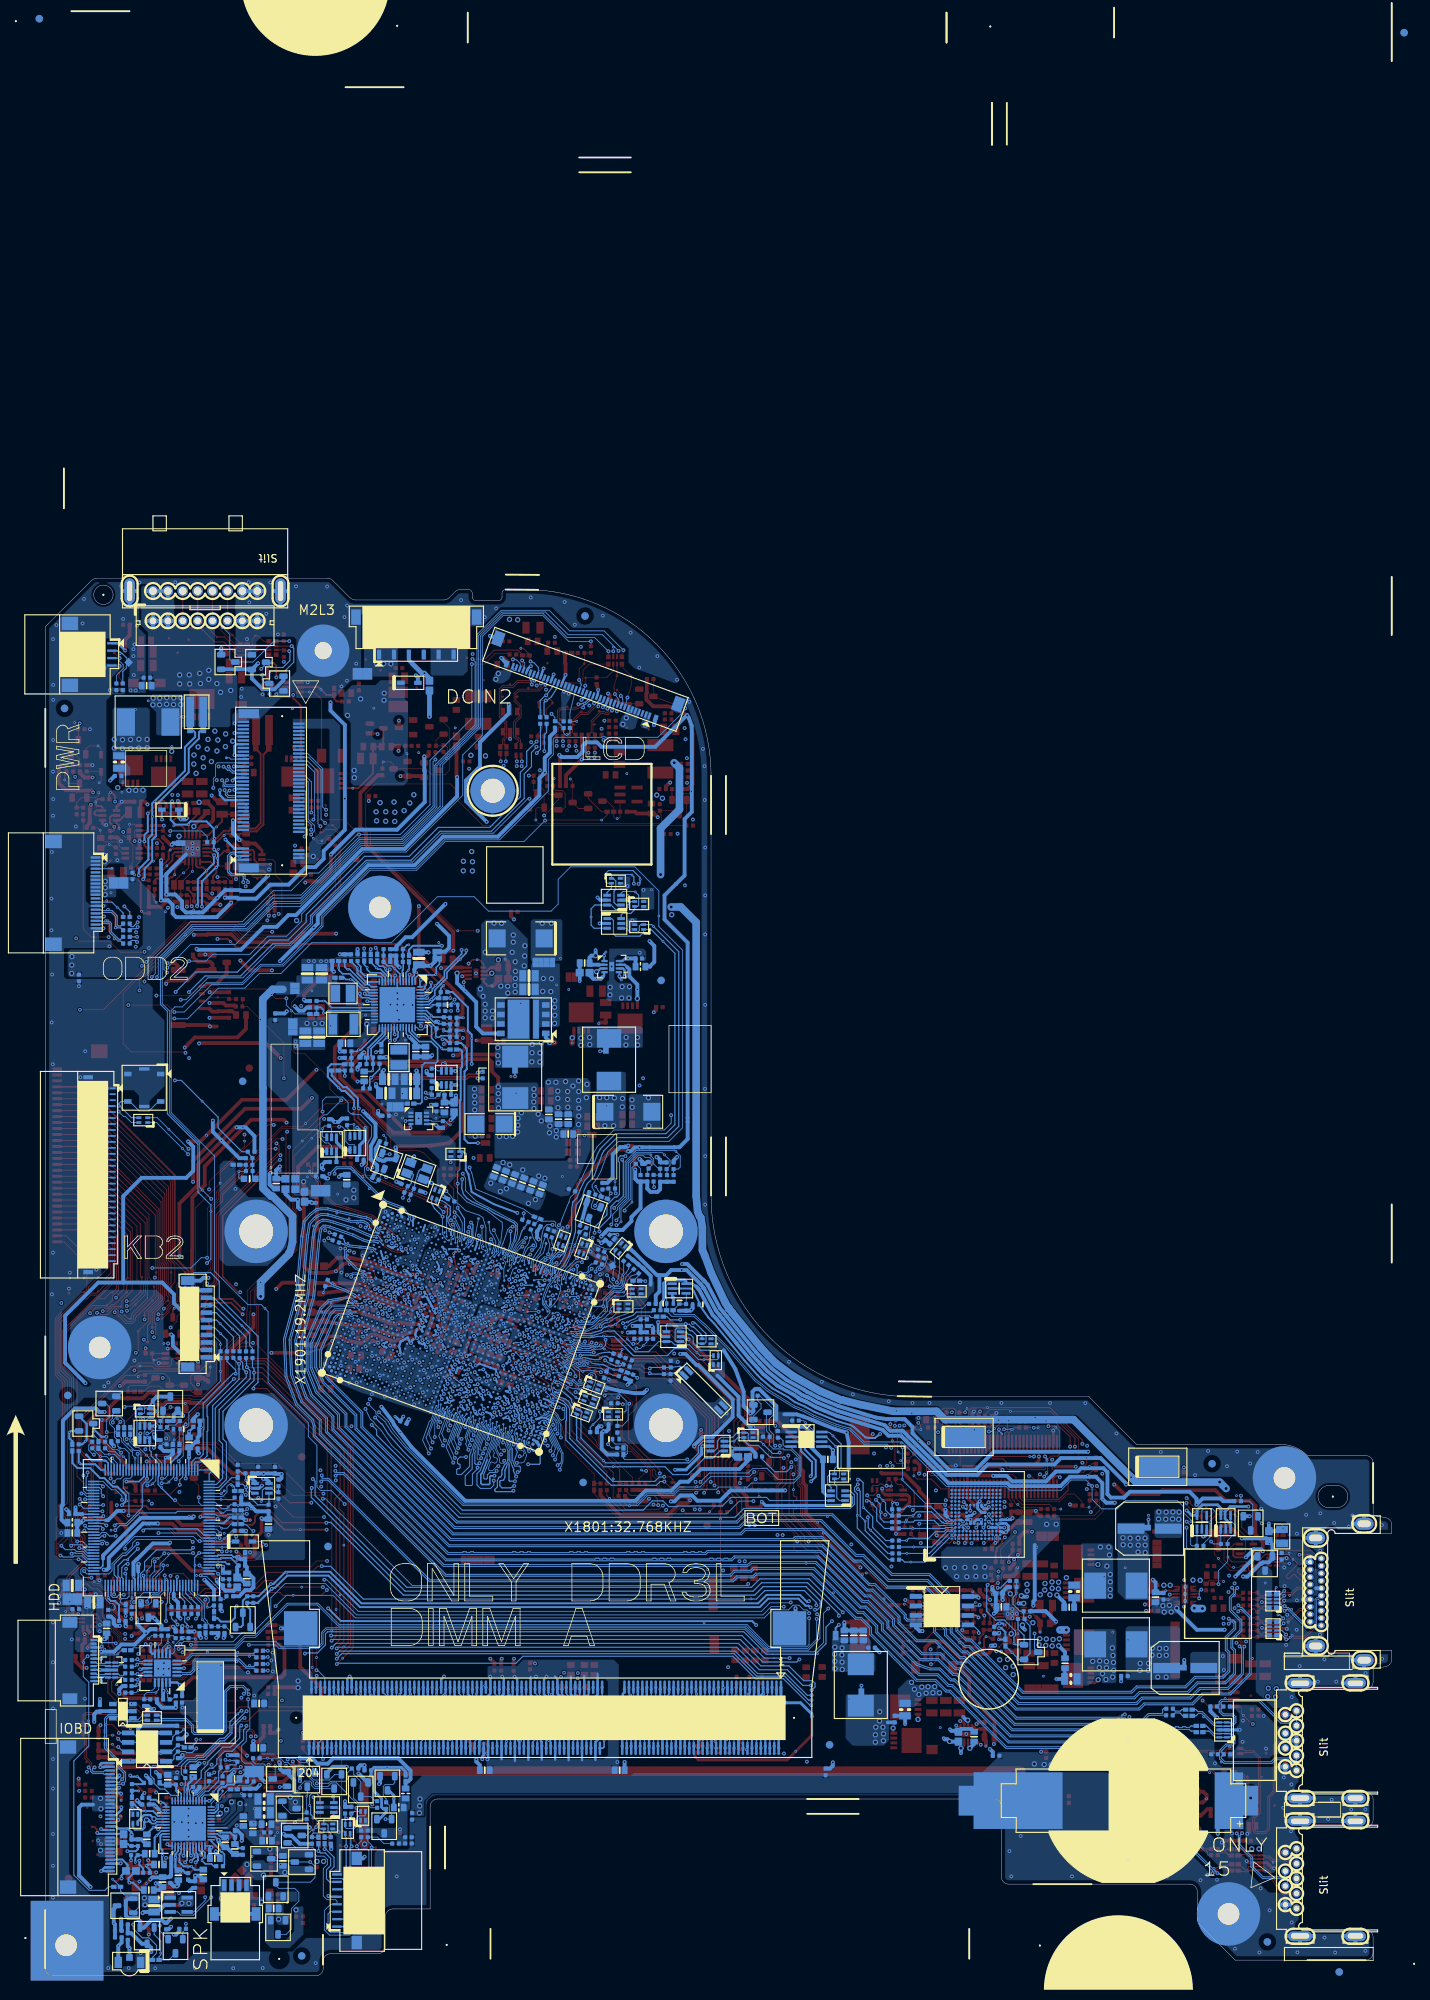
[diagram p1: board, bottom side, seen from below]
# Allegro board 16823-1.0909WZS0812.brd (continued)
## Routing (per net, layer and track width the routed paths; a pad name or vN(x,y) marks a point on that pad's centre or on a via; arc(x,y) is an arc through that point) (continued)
LPC_FRAME#_DEBUG: length 5
  BOTTOM w0.14: R9915.2 156.32,85.32 v1(157.14,86.15) 157.98,86.98 DB1.5
LPC_LAD0_C: length 10.3
  BOTTOM w0.14: DB1.9 158.07,90.98 v1(154.3,87.21) 153.26,86.18 153.26,84.55 152.89,84.18 R9923.2
LPC_LAD0_R: length 10.3
  TOP w0.14: v2(107.09,83.64) 107.82,84.88 107.79,85.06 107.75,85.2 107.72,85.45 v1(107.34,85.83) 107.2,85.97 106.1,86.22 105.57,86.21 105.25,85.89 RN1905.4
  BOTTOM w0.102: CPU1.Y61 110.91,84.18 110.81,83.96 110.72,83.88 110.61,83.84 110.48,83.84 110.45,83.85 110.23,83.85 110.13,83.82 109.72,83.67 109.66,83.64 v2(107.09,83.64)
LPC_LAD1_C: length 9
  BOTTOM w0.14: DB1.8 158.03,89.98 153.75,85.7 v1(153.75,85.02) R9928.2
LPC_LAD1_R: length 8.1
  TOP w0.14: v1(105.8,85.83) v2(105.51,85.35) 105.29,84.84 105.06,84.66 RN1905.3
  BOTTOM w0.102: CPU1.Y62 110.38,84.12 109.73,83.89 107.46,83.89 107.3,84.05 106.83,84.05 106.77,84.08 106.23,84.08 105.95,84.15
  BOTTOM w0.14: 105.95,84.15 105.51,84.59 v2(105.51,85.35)
LPC_LAD2_C: length 7.8
  BOTTOM w0.14: DB1.7 157.77,88.98 v1(155.58,86.79) 154.62,85.83 R9931.2
LPC_LAD2_R: length 7.6
  TOP w0.14: RN1905.2 104.93,84.16 105.14,84.25 105.71,84.74 105.98,85.01 105.99,85.01 106.01,85.03 106.22,85.03 106.43,84.99 v2(106.74,84.84) v1(107.04,84.33)
  BOTTOM w0.089: CPU1.W62 110.18,84.69 110.13,84.72 110.02,84.72 109.84,84.65 109.67,84.49 109.62,84.41 109.57,84.4
  BOTTOM w0.102: 109.57,84.4 109.23,84.27 109.08,84.27 108.86,84.31 108.53,84.44 107.66,84.44 107.54,84.56 107.19,84.56 v2(106.74,84.84)
LPC_LAD3_C: length 6.4
  BOTTOM w0.14: R9932.2 155.46,85.73 v1(157.23,87.5) 157.71,87.98 DB1.6
LPC_LAD3_R: length 6.2
  TOP w0.14: RN1905.1 104.94,83.67 v1(105.66,84.09) v2(106.15,84.58)
  BOTTOM w0.102: CPU1.W63 109.93,84.23 109.36,84.08 108.94,84.08 108.8,84.11 108.62,84.18 108.03,84.18
  BOTTOM w0.127: 107.62,84.18 108.03,84.18
  BOTTOM w0.14: 107.62,84.18 107.44,84.36 107.12,84.36 106.57,84.41 v2(106.15,84.58)
LPSS_UART1_TXD: length 83.3
  TOP w0.14: v2(46.08,73.74) 45.23,73.74 v1(45.09,73.6) 44.58,73.09 44.58,69.98 44.83,69.73 45.73,69.73 46.19,69.27 46.19,66.8 46.43,66.56 XDP1.54
  L4 w0.127: v2(98.99,105.82) 98.05,104.88 98.05,104.54 94.74,101.23 94.74,94.39 93.22,92.87 92.5,91.82 91.27,89.99 91.07,89.68 90.26,88.42 88.89,86.35 88.48,85.44 82.54,79.49 81.62,78.77 80.25,77.72 77.98,76.73 73.48,74.89 68.27,73.65 66.74,73.13 62.08,73.13 61.43,72.48 57.73,72.48 55.95,74.26 46.6,74.26 v2(46.08,73.74)
  BOTTOM w0.14: v2(98.99,105.82) 99.07,105.89 R1801.2
LVDS_VDD_EN: length 5.7
  TOP w0.102: v1(110.24,160.58) 109.93,160.26 R5531.2 Q5501.C 109.12,156.62 D5501.1
LVDS_VDD_EN_B: length 6.1
  TOP w0.102: v1(112.43,160.63) 112.52,160.54 R5532.2 112.52,159.35 112.2,159.03 111.31,159.03 110.93,158.65 110.93,156.77 111.25,156.45 Q5501.B
LVDS_VDD_EN_KBC: length 6.2
  BOTTOM w0.102: KBC24.20 167.85,70.19 168.13,70.47 168.73,70.47 v1(169.6,71.35) 169.73,71.35 170.21,71.84 170.21,72.27 170.11,72.37 R2506.1
LVDS_VDD_EN_R: length 6.2
  TOP w0.102: U5501.1 103.56,156.2 R5503.2 103.55,155.49 103.77,155.27 v1(103.94,155.27) 104.2,155.27 104.41,155.49 R5504.2 104.41,156.73 105.29,157.61 D5501.3
M_A_A0: length 64.4
  TOP w0.203: v2(113.17,33.42) 113.36,33.42 v1(113.65,33.71)
  L4 w0.191: v2(120.51,66.44) 120.59,66.23 120.35,65.73 120.46,65.42 120.67,65.33 120.9,64.69 120.65,64.15 119.63,63.78 119.33,63.14 116.8,62.22 116.13,60.79 115.22,60.51 113.66,57.63 112.87,56.11 112.87,56.11 112.76,55.88 112.49,55.35 112.23,55.04 111.81,54.53 110.78,53.51 110.78,53.5 109.72,52.44 108.64,52.44 108.52,52.33 108.52,51.78 108.71,51.59 108.99,51.59 109.18,51.4 109.18,50.96 108.99,50.77 108.71,50.77 108.52,50.58 108.52,45.16 108.34,44.99 107.86,44.99 107.68,44.81 107.68,44.25 107.86,44.07 108.77,44.07 108.95,43.89 108.95,43.46 108.77,43.28 107.48,43.28 107.3,43.11 107.3,42.16 107.77,41.69 109.79,41.69 110.38,41.1 110.38,38.24 110.61,38 111.7,38 112.13,37.57 112.13,36.07 111.72,35.67 111.72,34.83 112.56,33.99 112.56,33.68 112.82,33.42 v2(113.17,33.42)
  BOTTOM w0.089: 120.66,74.12 120.66,73.55 120.64,73.51 120.64,73.39 120.89,72.71 120.89,72.42 120.81,72.08 120.81,71.88 121.68,69.5
  BOTTOM w0.127: 121.68,69.5 121.8,69.17 121.85,69.05 122.37,67.75 122.77,67.35 122.77,65.87 122.3,65.4 120.94,65.4 120.51,65.82 v2(120.51,66.44)
  BOTTOM w0.203: DM1.98 113.47,31.65 113.73,31.91 113.73,33.15 113.47,33.42 v2(113.17,33.42)
M_A_A1: length 65.5
  TOP w0.203: v2(112.79,37.18) v1(112.79,37.75)
  L3 w0.089: 119.31,64.46 119.23,64.68 119.8,65.89 119.56,66.54 v2(120.12,67.75)
  L3 w0.191: v2(112.79,37.18) 112.47,37.5 112.47,38.31 112.57,38.41 114.63,38.41 114.74,38.52 114.74,39.5 114.63,39.61 113.88,39.61 113.69,39.42 113.69,39.3 113.5,39.11 113.05,39.11 112.86,39.3 112.86,39.42 112.67,39.61 112.12,39.61 111.97,39.76 111.97,40.79 112.15,40.97 113.9,40.97 114.08,41.15 114.08,41.73 113.9,41.91 112.61,41.91 112.43,42.09 112.43,42.69 112.79,43.06 114.42,43.06 114.6,43.23 114.6,45.29 115.75,46.44 116.08,46.83 116.92,48.31 117.27,48.66 117.33,48.83 117.55,49.31 117.7,49.37 119.32,48.61 119.49,48.68 119.71,49.14 119.65,49.3 118.59,49.8 118.53,49.97 118.8,50.56 119.05,50.65 119.45,50.47 119.63,50.54 122.3,56.26 121.72,57.85 120.76,58.3 120.68,58.3 120.48,58.84 120.48,59.08 120.55,59.24 120.99,59.4 121.08,59.6 120.83,60.3 120.67,60.38 119.92,60.1 119.79,60.17 119.57,60.78 119.63,60.91 120.41,61.2 120.46,61.3 120.18,62.06 120.08,62.11 119.33,61.84 119.15,61.92 118.9,62.61 118.99,62.8 119.66,63.05 119.75,63.25 119.31,64.46
  BOTTOM w0.089: CPU1.BG51 120.21,74.02 120.16,73.91 120.08,73.75 120.05,73.63 120.13,73.4 120.24,73.34 120.25,73.32 120.26,73.32 120.37,73.02 120.5,72.66 120.35,72.03 121.12,69.91 121.04,69.73
  BOTTOM w0.127: v2(120.12,67.75) 120.35,67.53 121.04,67.53 121.37,67.2 121.37,66.78 121.49,66.67 121.74,66.67 121.85,66.78 121.85,67.3 121.51,68.13 121.12,69.07 120.94,69.51 121.04,69.73
  BOTTOM w0.152: v2(112.79,37.18) 113.11,37.5 113.17,37.56 DM1.97
M_A_A2: length 64.4
  TOP w0.203: v2(113.14,32.14) v1(113.14,31.57)
  L3 w0.089: 119.75,64.94 120.22,65.94 120.05,66.4 120.36,67.07 v2(120.42,67.09)
  L3 w0.191: 119.75,64.94 122.94,56.19 120.27,50.46 120.27,48.41 119.2,47.35 118.93,47.35 118.49,47.78 118.22,47.78 117.95,47.51 117.95,47.24 118.39,46.81 118.39,46.54 117.99,46.14 117.72,46.14 117.08,46.77 116.83,46.77 116.55,46.49 116.55,46.23 117.18,45.6 117.18,45.33 116.42,44.57 116.42,43.4 116.23,43.21 115.45,43.21 115.27,43.03 115.27,42.62 115.45,42.44 116.19,42.44 116.36,42.27 116.36,41.86 116.19,41.68 115.6,41.68 115.42,41.5 115.42,41.1 115.6,40.92 116.19,40.92 116.36,40.74 116.36,39.74 116.19,39.56 115.6,39.56 115.42,39.39 115.42,38.98 115.6,38.8 116.32,38.8 116.45,38.68 116.45,37.86 116.23,37.65 114.21,37.65 113.98,37.42 113.98,37.16 113.98,35.78 113.98,34.69 114.33,34.34 114.79,34.34 115.07,34.06 115.07,32.32 114.9,32.14 v2(113.14,32.14)
  BOTTOM w0.089: CPU1.BH51 120.36,73.6 120.4,73.48 120.41,73.48 120.45,73.35 120.45,73.35 120.49,73.24 120.56,73.04 120.58,72.99 120.7,72.67 120.7,72.6 120.56,72.02 121.42,69.66 121.41,69.21
  BOTTOM w0.203: 121.41,69.21 122.08,67.45 122.25,67.29 122.25,66.08 122.08,65.92 121.16,65.92 121.04,66.03 121.04,66.98 120.93,67.09 v2(120.42,67.09) ; DM1.96 112.9,30.55 112.9,31.9 v2(113.14,32.14)
M_A_A3: length 66.8
  TOP w0.203: v1(113.24,36.2) 112.93,35.88 v2(112.76,35.88)
  L4 w0.089: 123.78,75.38 123.43,76.36 v2(123.62,76.76)
  L4 w0.191: 123.78,75.38 123.88,75.1 123.49,74.26 125.59,68.5 126.67,67.99 127.32,66.2 127.4,66.17 127.7,65.34 127.94,64.72 128.82,62.3 131.14,55.91 129.9,50.33 129.61,49.02 124.7,44.11 124.7,39.95 123.1,38.35 122.44,38.35 121.41,37.32 121.41,34.62 119.84,33.05 119.84,31.93 119.27,31.37 115.72,31.37 113.71,33.38 113.71,33.65 113.7,33.66 113.7,34.26 113.65,34.32 113.37,34.6 113.37,34.6 113.21,34.76 112.57,34.76 112.29,35.04 112.29,35.46 v2(112.76,35.88)
  BOTTOM w0.203: CPU1.BD41 v2(123.62,76.76) ; v2(112.76,35.88) 112.26,36.39 112.26,37.36 112.57,37.67 DM1.95
M_A_A4: length 64.8
  TOP w0.203: v1(112.5,32.82) 112.21,33.12 v2(112.03,33.12)
  L4 w0.089: 124.82,73.62 124.84,73.66 v2(123.95,76.08)
  L4 w0.191: 124.82,73.62 126.35,69.4 126.64,69.27 127.6,66.63 127.95,66.47 128.03,66.24 128.03,66.24 128.3,65.51 129.23,62.95 131.81,55.87 130.15,48.55 125.28,43.68 125.28,39.74 123.33,37.79 122.67,37.79 121.96,37.08 121.96,36.97 121.96,34.58 121.96,34.44 121.96,34.4 120.42,32.86 120.42,31.6 119.6,30.78 115.2,30.78 114.62,31.37 113.25,31.37 112.53,32.09 112.53,32.76 v2(112.03,33.12)
  BOTTOM w0.203: v2(112.03,33.12) 111.87,32.96 111.85,32.96 111.54,32.66 111.54,32.14 111.67,32.02 DM1.92 ; CPU1.BE41 v2(123.95,76.08)
M_A_A5: length 63.9
  TOP w0.203: v2(110.68,35.92) v1(111.26,35.92)
  L3 w0.089: v2(119.9,68.38) 119.9,68.31 119.2,66.81 119.2,65.65 118.69,64.57 118.72,64.51
  L3 w0.191: v2(110.68,35.92) 110.77,35.92 111.19,35.51 111.19,34.9 110.76,34.47 110.76,33.62 110.76,33.05 110.93,32.87 111.34,32.87 111.52,33.05 111.52,33.91 111.93,34.32 111.93,36.18 111.73,36.37 111.24,36.37 111.11,36.5 111.11,37.01 111.24,37.14 111.73,37.14 111.93,37.33 111.93,38.99 110.61,40.31 110.61,41.64 112.57,43.6 112.57,43.87 112.02,44.42 112.02,44.68 112.3,44.96 112.55,44.96 113.11,44.41 113.38,44.41 113.89,44.92 113.89,45.35 115.35,46.81 115.63,47.14 116.68,48.98 117.15,49.81 117.67,50.96 118.6,51.3 118.88,51.17 119.13,51.26 119.29,51.61 119.2,51.86 118.92,51.99 118.83,52.24 118.99,52.59 119.24,52.68 119.52,52.55 119.77,52.64 119.93,52.99 119.84,53.24 119.56,53.37 119.47,53.62 119.63,53.97 119.89,54.06 120.16,53.93 120.42,54.02 120.58,54.37 120.49,54.62 120.21,54.75 120.12,55 120.28,55.35 120.53,55.44 120.81,55.31 121.06,55.4 121.22,55.75 121.13,56 120.85,56.13 120.76,56.39 120.99,56.88 120.75,57.56 120.04,57.88 118.26,62.77 118.85,64.03 118.72,64.39 118.72,64.51
  BOTTOM w0.089: CPU1.BJ52 120.22,72.62 120.15,72.04 120.66,70.64 120.43,70.15 120.59,69.73 120.54,69.62 120.07,69.43 119.99,69.26 120.15,68.87 120.37,68.77 120.81,68.95 120.92,68.9 121.17,68.27 121.22,68.11 121.14,67.81 120.99,67.76 120.69,67.76 120.08,68.37 120.06,68.38 v2(119.9,68.38)
  BOTTOM w0.152: DM1.91 111.37,37.81 111.11,37.56 111.11,37.28 111.11,36.35 v2(110.68,35.92)
M_A_A6: length 64.6
  TOP w0.203: v1(110.73,32.67) 110.36,33.03 v2(110.24,33.03)
  L4 w0.089: v2(119.12,70.48) 119.12,69.9 119.2,69.68 119.48,69.4 119.51,69.3 119.51,68.94 119.44,68.87 119.33,68.63 119.33,68.24
  L4 w0.191: v2(110.24,33.03) 110.33,33.03 110.88,32.48 111.16,32.48 111.34,32.66 111.34,33.95 109.83,35.46 109.83,40.87 109.57,41.13 107.47,41.13 106.72,41.88 106.72,45.33 106.92,45.53 107.78,45.53 107.98,45.72 107.98,46.17 107.78,46.36 106.88,46.36 106.77,46.47 106.77,47.07 106.88,47.19 107.78,47.19 107.98,47.38 107.98,47.82 107.78,48.01 106.96,48.01 106.84,48.12 106.84,48.72 106.96,48.84 107.78,48.84 107.98,49.03 107.98,49.47 107.78,49.66 107.01,49.66 106.89,49.78 106.89,50.37 107.01,50.49 107.78,50.49 107.98,50.68 107.98,51.12 107.78,51.31 107.17,51.31 106.98,51.5 106.98,52.05 107.98,53.05 110.28,53.9 111.71,55.33 112.11,55.81 112.38,56.35 112.38,56.36 114.77,60.96 116.61,62.8 118.23,63.39 119.33,64.49 119.33,65.8 119.52,65.99 119.78,65.99 119.97,66.18 119.97,66.62 119.78,66.81 119.52,66.81 119.33,67 119.33,68.24
  BOTTOM w0.089: CPU1.BG53 119.2,73.45 119.18,73.31 119.24,73.14 119.3,73.07 119.41,72.94 119.48,72.76 119.52,72.47 119.53,72.38 119.53,72.15 119.53,72.05 119.84,71.21 119.58,70.64 v2(119.12,70.48)
  BOTTOM w0.203: DM1.90 111.11,30.55 111.11,31.78 110.97,31.91 110.97,32.78 110.72,33.03 v2(110.24,33.03)
M_A_A7: length 63.9
  TOP w0.203: v1(110.7,33.96) 110.41,33.67 v2(110.21,33.67)
  L4 w0.191: v2(117.67,66.36) 117.77,66.36 118.32,65.8 118.32,64.9 117.96,64.54 116.14,63.88 113.41,61.14 110.84,56.05 110.6,55.76 109.68,54.84 108.86,54.54 106.82,53.78 104.68,51.65 104.68,51.1 104.87,50.91 105.39,50.91 105.57,50.73 105.57,50.26 105.39,50.09 104.87,50.09 104.68,49.89 104.68,49.45 104.87,49.26 105.26,49.26 105.44,49.08 105.44,48.61 105.26,48.43 104.87,48.43 104.68,48.24 104.68,47.7 104.87,47.51 105.26,47.51 105.44,47.33 105.44,46.92 105.26,46.75 104.87,46.75 104.68,46.55 104.68,46.17 104.87,45.98 105.24,45.98 105.42,45.81 105.42,45.4 105.24,45.22 104.87,45.22 104.68,45.03 104.68,43.61 104.86,43.44 105.32,43.44 105.49,43.26 105.49,42.72 105.32,42.55 104.86,42.55 104.68,42.37 104.68,42.03 108.36,38.35 108.36,36.68 108.21,36.53 108.21,35.25 108.8,34.66 108.92,34.3 108.92,32.11 109.1,31.93 109.56,31.93 109.74,32.11 109.74,33.35 110.05,33.67 v2(110.21,33.67)
  BOTTOM w0.089: CPU1.BG55 118.36,73.27 118.36,73.16 118.29,73.02 118.39,72.77 118.45,72.74 118.46,72.72 118.61,72.31 118.38,71.81 118.38,71.71 118.52,71.32 118.52,71.26 118.24,70.66 118.19,70.62 118.19,70.61 118.19,69.18 118.45,68.45 118.47,68.4
  BOTTOM w0.152: 118.47,68.4 118.47,66.47 118.35,66.36 v2(117.67,66.36) ; v2(110.21,33.67) 109.76,33.23 109.76,31.56 109.87,31.45 DM1.86
M_A_A8: length 64.4
  TOP w0.203: v2(110.6,37.26) 110.54,37.26 109.99,36.71 v1(109.99,36.4)
  L3 w0.089: 118.15,64.31 118.21,64.43 118.17,64.53 118.62,65.5 118.37,66.17 118.45,66.33 118.4,66.44 117.96,66.65 117.9,66.8 118.11,67.25 118.26,67.31 118.71,67.1 118.83,67.14 119.06,67.64 119.01,67.76 118.14,68.16 118.09,68.32 118.3,68.76 118.45,68.82 119.32,68.41 119.44,68.46 119.79,69.22 v2(119.53,69.94)
  L3 w0.191: v2(110.6,37.26) 110.66,37.31 110.66,39.44 110.04,40.06 110.04,41.79 109.68,42.14 109.68,42.95 110.66,43.92 110.66,44.58 112.18,46.11 112.45,46.11 113.02,45.54 113.29,45.54 113.56,45.81 113.56,46.08 112.88,46.76 112.88,47.01 113.17,47.3 113.42,47.3 114.1,46.62 114.37,46.62 114.64,46.89 114.64,47.16 114.07,47.73 114.07,48 114.74,48.67 115.4,48.67 115.6,48.87 115.6,49.71 115.44,49.87 115.22,49.97 115.12,50.22 115.31,50.63 115.56,50.72 116.55,50.27 116.8,50.37 116.98,50.77 116.89,51.02 115.9,51.47 115.81,51.73 115.99,52.13 116.24,52.22 117.23,51.78 117.48,51.87 118.05,53.11 118.24,53.3 118.59,53.3 118.78,53.49 118.78,53.94 118.59,54.13 117.4,54.13 117.28,54.24 117.28,54.84 117.4,54.95 119.45,54.95 119.57,55.07 119.57,55.66 119.45,55.78 118.24,55.78 118.05,55.97 118.05,56.52 118.3,57.07 118.47,57.13 119.93,56.45 120.08,56.51 120.32,57.01 120.26,57.16 119.14,57.69 119.08,57.86 119.3,58.33 117.57,63.07 118.15,64.31
  BOTTOM w0.089: CPU1.BH53 119.55,73.13 119.55,73.11 119.61,72.95 119.61,72.94 119.7,72.7 119.71,72.7 119.72,72.66 119.72,72.19 119.72,72.1 119.82,71.82 120.15,70.91 120.15,70.76 119.97,70.36 119.77,69.94 v2(119.53,69.94)
  BOTTOM w0.152: DM1.89 110.77,37.84 110.6,37.67 v2(110.6,37.26)
M_A_A9: length 62.6
  TOP w0.203: v1(108.69,35.42) v2(109.28,35.42)
  L4 w0.191: v2(109.28,35.42) 108.95,35.75 108.95,36.32 109.18,36.55 109.18,37.49 108.95,37.72 108.95,38.56 108.24,39.27 108.24,39.58 108.63,39.97 108.63,40.22 108.27,40.58 108.02,40.58 107.66,40.21 107.33,40.21 106.13,41.41 106.13,43.67 105.94,43.87 105.69,43.87 105.5,44.06 105.5,44.5 105.69,44.69 105.94,44.69 106.13,44.88 106.13,52.03 107.58,53.48 109.98,54.37 111,55.4 111.37,55.84 111.74,56.57 114.02,60.98 116.44,63.41 118.06,63.99 118.64,64.57 118.64,68.71 117.59,69.77 117.59,70.32 116.82,71.09 116.82,72.28 117.18,72.64 118.04,72.64 118.48,72.2 118.48,69.74 v2(119.11,69.1)
  BOTTOM w0.089: CPU1.BG52 119.76,73.09 119.82,72.93 119.91,72.7 119.96,72.56 119.94,72.05 120.39,70.8 119.75,69.43 119.75,68.96 119.57,68.78 119.21,68.78 119.11,68.88 v2(119.11,69.1)
  BOTTOM w0.203: v2(109.28,35.42) 109.42,35.55 109.42,37.6 109.57,37.76 DM1.85
M_A_A10: length 65.6
  TOP w0.203: v1(117.23,36.25) 116.9,35.92 v2(116.66,35.92)
  L4 w0.089: v2(121.69,70.76) 121.45,70.23 121.78,69.31 121.57,68.86 122.25,66.99
  L4 w0.191: 122.25,66.99 122.36,66.94 123.35,64.23 123.12,63.74 123.03,63.55 123.03,63.22 122.91,62.95 123.17,62.21 123.17,62.13 122.68,61.07 122.37,60.42 122.27,60.2 122.23,60.12 120.58,59.51 119.78,57.5 119.89,57.25 121.64,56.56 121.7,56.41 121.48,55.86 121.33,55.79 119.59,56.49 119.34,56.38 119.25,56.16 119.25,55.02 118.86,54.63 118.86,54.37 119.92,53.31 119.92,53.04 119.61,52.72 119.34,52.72 118.19,53.87 118.03,53.87 117.6,53.45 117.6,53.29 118.75,52.14 118.75,51.87 118.44,51.56 118.17,51.56 117.11,52.61 116.84,52.61 116.13,51.9 116.13,51.35 116.32,51.16 117.22,51.16 117.33,51.05 117.33,50.45 117.22,50.34 116.05,50.34 115.94,50.22 115.94,49.63 116.05,49.51 116.96,49.51 117.15,49.32 117.15,48.88 116.96,48.69 116.32,48.69 116.13,48.5 116.13,48.05 116.32,47.86 116.96,47.86 117.15,47.67 117.15,47.23 116.96,47.04 116.32,47.04 116.13,46.84 116.13,39.68 115.81,39.36 115.81,38.98 116.13,38.66 116.13,37.08 116.27,36.94 116.27,36.43 116.66,36.03 v2(116.66,35.92)
  BOTTOM w0.089: v2(121.69,70.76) 121.69,70.64 121.81,70.53 122.25,70.53 122.36,70.64 122.36,70.74 122.07,71.63 121.41,73.42 121.28,73.78 CPU1.BH49
  BOTTOM w0.203: DM1.107 116.17,37.36 115.48,36.67 115.48,35.5 115.67,35.31 115.97,35.31 116.59,35.92 v2(116.66,35.92)
M_A_A11: length 63.8
  TOP w0.203: v2(108.41,33.02) 108.67,33.02 v1(108.92,32.77)
  L3 w0.191: v2(117.76,65.73) 117.7,65.61 117.48,65.53 117.47,65.52 116.36,63.14 117.73,59.38 116.92,57.64 113.74,50.82 113.64,50.61 113.47,50.55 113.24,50.55 111.39,48.71 111.39,48.44 111.57,48.27 111.57,48 111.25,47.68 110.98,47.68 110.66,48 110.5,48 110.08,47.58 110.08,47.42 110.4,47.1 110.4,46.83 110.08,46.52 109.81,46.52 109.64,46.69 109.37,46.69 109.06,46.37 109.06,46.1 109.23,45.93 109.23,45.37 109.09,45.23 107.12,45.23 106.94,45.05 106.94,44.5 107.13,44.31 108.57,44.31 108.74,44.13 108.74,43.73 108.57,43.55 107.13,43.55 106.94,43.36 106.94,37.76 106.45,37.26 106.45,35.82 106.27,35.64 105.62,35.64 105.44,35.46 105.44,34.77 105.62,34.6 106.92,34.6 107.09,34.42 107.09,33.71 106.92,33.53 106.43,33.53 106.26,33.35 106.26,32.72 106.43,32.54 107.93,32.54 108.41,33.02 v2(108.41,33.02)
  BOTTOM w0.089: CPU1.BH55 118.61,72.85 118.62,72.83 118.8,72.34 118.8,72.26 118.57,71.77 118.57,71.74 118.72,71.31 118.72,71.25 118.4,70.55 118.38,70.53 118.38,69.21 118.6,68.59 118.72,68.53 118.78,68.37
  BOTTOM w0.152: v2(117.76,65.73) 118.27,65.47 119.42,65.47 119.69,65.75 119.69,66.29 119.63,66.44 119.19,66.51 119.01,66.92 119.01,67.81 118.85,68.18 118.78,68.37
  BOTTOM w0.203: v2(108.41,33.02) 108.63,33.24 109.13,33.24 109.27,33.1 DM1.84
M_A_A12: length 63.8
  TOP w0.203: v1(108.9,34.14) 108.67,34.36 v2(108.38,34.36)
  L3 w0.191: v2(108.38,34.36) 108.04,34.36 107.91,34.49 107.91,35.26 108.1,35.45 108.65,35.45 108.78,35.58 108.78,36.17 108.65,36.3 108.04,36.3 107.91,36.43 107.91,36.95 108.1,37.14 109.87,37.14 109.99,37.26 109.99,37.77 109.87,37.9 108.1,37.9 107.91,38.09 107.91,38.47 108.1,38.66 109.89,38.66 110.02,38.79 110.02,39.3 109.89,39.42 108.1,39.42 107.91,39.61 107.91,42.09 109.78,43.95 109.78,45.24 112.56,48.03 112.83,48.61 113,48.67 113.5,48.44 113.66,48.5 113.88,48.96 113.82,49.13 113.4,49.32 113.34,49.49 113.57,49.98 113.83,50.08 114.21,49.9 114.37,49.96 118.52,58.85 116.96,63.12 117.88,65.08 v2(117.87,65.09)
  BOTTOM w0.089: 118.6,70.44 118.96,71.22 118.77,71.73 118.93,72.07 119.03,72.28 118.85,72.77 118.91,72.92 118.92,73.04 CPU1.BG54
  BOTTOM w0.152: 118.6,70.44 118.6,69.25 118.78,68.75 119.02,68.64 119.32,68.05 119.42,67.82 119.42,67.28 119.57,66.95 119.82,66.88 120.03,66.42 120.03,65.6 120.36,65.26 120.36,65.08 120.25,64.97 118,64.97 v2(117.87,65.09)
  BOTTOM w0.203: v2(108.38,34.36) 107.88,34.36 107.71,34.54 107.71,35.17 108.97,36.43 DM1.83
M_A_A13: length 65.9
  TOP w0.203: v2(120.71,35.27) 120.9,35.27 v1(121.32,35.69)
  L4 w0.191: v2(124.24,69.61) 124.95,67.64 125.57,67.36 126.22,65.58 126.51,65.44 126.69,64.95 126.85,64.43 126.9,64.27 128.2,60.71 128.2,60.7 128.22,60.7 128.52,59.88 128.6,59.67 128.7,59.38 129.8,56.12 128.26,49.35 127.88,48.97 127.43,48.97 127.07,48.61 127.07,48.16 125.75,46.83 125.31,46.83 124.95,46.47 124.95,46.03 124.58,45.67 124.15,45.67 123.78,45.3 123.78,44.87 123.41,44.5 122.98,44.5 122.61,44.13 122.61,43.7 121.65,42.74 121.65,41.94 121.46,41.75 121.19,41.75 121.07,41.62 121.07,41.05 121.19,40.92 121.46,40.92 121.65,40.73 121.65,39.72 120.22,38.29 120.22,35.44 120.38,35.27 v2(120.71,35.27)
  BOTTOM w0.089: CPU1.BG46 122.52,74.44 122.36,74.09 122.52,73.64 122.61,73.4 122.51,73.25 123.6,70.27
  BOTTOM w0.127: 123.6,70.27 123.75,69.84 123.75,68.35 124.85,67.25 125.36,67.25 125.49,67.38 125.49,67.91 125.36,68.04 125.16,68.04 125.03,68.17 125.03,68.55 125.16,68.67 125.26,68.67 125.38,68.8 125.38,69.26 125.03,69.61 v2(124.24,69.61)
  BOTTOM w0.203: DM1.119 119.77,35.47 119.39,35.09 119.39,33.37 119.75,33.01 120.18,33.01 120.41,33.24 121.24,33.24 121.37,33.37 121.37,33.65 122.06,34.33 122.06,34.76 121.55,35.27 v2(120.71,35.27)
M_A_A14: length 64.8
  TOP w0.203: v2(105.7,34.04) 105.21,34.04 v1(105.14,34.11)
  L3 w0.191: v2(105.7,34.04) 105.14,34.04 104.84,34.34 104.84,34.76 104.84,35.79 104.84,36.47 106.34,37.96 106.34,45.32 107.03,46.01 107.72,46.01 111.11,49.41 111.11,50.88 111.56,51.33 111.56,53.06 113.86,57.96 114.02,58.02 114.64,57.72 114.7,57.57 112.38,52.59 112.43,52.44 113.05,52.15 113.2,52.2 116.89,60.1 116.24,61.87 115.88,62.04 115.57,62.91 117.18,66.38 117.18,66.38 117.34,66.72 117.34,66.72 117.45,66.96 v2(117.51,66.99)
  BOTTOM w0.089: 118.05,68.42 118.17,68.68 117.99,69.14 117.99,70.56 118,70.56 118,70.65 118.03,70.73 118.08,70.77 118.31,71.27 118.31,71.32 118.15,71.77 118.4,72.32 118.31,72.58 118.24,72.61 118.08,72.88 CPU1.BG56
  BOTTOM w0.152: 118.05,68.42 117.82,67.94 117.88,67.78 v2(117.51,66.99)
  BOTTOM w0.203: DM1.80 108.07,31.96 107.69,32.34 107.69,33.36 107.02,34.04 106.19,34.04 v2(105.7,34.04)
M_A_A15: length 62.8
  TOP w0.203: v2(105.7,33.4) 106.15,33.4 v1(106.26,33.3)
  L3 w0.191: v2(105.7,33.4) 105.42,33.4 105.19,33.17 105.19,32.49 105.01,32.31 104.47,32.31 104.29,32.49 104.29,34.28 104.29,36.65 104.29,36.86 105.7,38.26 105.7,45.47 106.34,46.12 106.34,46.57 105.7,47.22 105.7,47.51 106.08,47.9 106.35,47.9 107.18,47.07 107.43,47.07 107.72,47.36 107.72,47.61 106.89,48.44 106.89,48.71 107.16,48.98 107.43,48.98 108.36,48.05 108.61,48.05 108.9,48.34 108.9,48.59 107.97,49.52 107.97,49.79 108.24,50.06 108.51,50.06 109.47,49.09 109.73,49.09 110.01,49.38 110.01,49.63 109.05,50.6 109.05,50.87 109.89,51.71 109.89,52.13 110.83,53.07 114.25,60.39 114.04,60.95 116.54,66.32 116.45,66.56 116.85,67.42 v2(117.3,67.59)
  BOTTOM w0.089: 117.34,71.33 117.64,71.97 117.62,72.02 117.55,72.22 117.79,72.74 117.65,73.12 CPU1.BG57
  BOTTOM w0.127: v2(117.3,67.59) 117.08,67.59 116.95,67.71 116.95,68.26 117.08,68.39 117.68,68.39 117.87,68.81 117.34,70.27 117.56,70.73 117.34,71.33
  BOTTOM w0.203: DM1.78 107.47,31.72 107.09,32.09 107.09,32.69 106.38,33.4 106.19,33.4 v2(105.7,33.4)
M_A_BS0: length 64.4
  TOP w0.203: v2(116.73,37.26) v1(116.73,37.82)
  L4 w0.089: 122.62,67.33 122.28,67.49 121.84,68.69 v2(122.2,69.46)
  L4 w0.191: 122.62,67.33 123.78,64.13 123.53,63.59 123.96,62.41 122.35,58.94 122.09,58.85 121.33,59.2 121.08,59.11 120.9,58.6 121.01,58.35 122.64,57.77 122.71,57.63 122.51,57.07 122.26,56.82 122.26,54.42 122.05,54.22 121.6,54.22 120.39,55.43 120.21,55.43 119.81,55.02 119.81,54.84 121.02,53.63 121.02,53.36 120.79,53.13 120.79,52.86 121.18,52.48 121.45,52.48 122.43,53.46 122.61,53.46 123.02,53.06 123.02,52.88 122.03,51.89 122.03,51.62 122.52,51.13 122.52,50.95 122.12,50.55 121.94,50.55 120.21,52.28 119.94,52.28 119.62,51.97 119.62,51.7 121.38,49.94 121.38,49.76 120.98,49.36 120.8,49.36 119.04,51.11 118.77,51.11 117.71,50.06 117.71,49.51 117.9,49.32 118.08,49.32 118.27,49.13 118.27,48.68 118.08,48.49 117.9,48.49 117.71,48.3 117.71,47.86 117.9,47.67 118.08,47.67 118.27,47.48 118.27,47.03 118.08,46.84 117.9,46.84 117.71,46.65 117.71,46.55 116.67,45.51 116.67,41.22 116.68,37.31 v2(116.73,37.26)
  BOTTOM w0.089: v2(122.2,69.46) 122.2,69.36 122.33,69.23 122.62,69.23 122.74,69.36 122.74,70.93 122.49,71.63 121.8,73.53 CPU1.BJ48
  BOTTOM w0.203: DM1.109 116.77,37.3 v2(116.73,37.26)
M_A_BS1: length 65.4
  TOP w0.203: v2(116.95,33.35) 117.12,33.35 v1(117.46,33.68)
  L4 w0.089: v2(121.44,71.36) 121.06,70.55 121.52,69.29 121.31,68.84 122.91,64.47
  L4 w0.191: v2(116.95,33.35) 116.5,33.35 116.4,33.45 116.4,34.62 116.04,34.98 116.04,35.85 115.72,36.17 115.72,36.37 115.72,36.72 115.58,36.86 115.58,38.33 115.05,38.87 115.05,39.53 115.58,40.06 115.58,40.38 114.31,41.65 114.31,42.19 114.5,42.38 115.39,42.38 115.58,42.57 115.58,43.02 115.39,43.21 114.5,43.21 114.31,43.4 114.31,43.84 114.5,44.03 115.39,44.03 115.58,44.22 115.58,44.67 115.39,44.86 114.5,44.86 114.31,45.05 114.31,45.49 114.5,45.68 115.39,45.68 115.58,45.87 115.58,46.32 115.39,46.51 114.5,46.51 114.31,46.7 114.31,47.14 114.5,47.33 115.39,47.33 115.58,47.53 115.58,47.97 115.39,48.16 114.5,48.16 114.31,48.35 114.31,48.8 114.5,48.99 115.25,48.99 115.38,49.11 115.38,49.68 115.25,49.81 114.5,49.81 114.31,50 114.31,50.94 115.44,52.07 115.44,52.56 115.73,52.85 116.22,52.85 116.6,53.23 116.6,53.5 116.24,53.87 116.24,54.04 116.65,54.45 116.83,54.45 117.19,54.09 117.46,54.09 117.84,54.47 118.31,55.68 118.2,55.93 117.67,56.14 117.59,56.3 117.8,56.84 117.97,56.91 118.5,56.7 118.75,56.81 118.91,57.22 118.8,57.47 118.46,57.6 118.39,57.77 118.6,58.3 118.76,58.37 119.1,58.24 119.35,58.35 119.55,58.86 120.05,59.93 121.85,60.59 122.6,62.19 122.45,62.6 122.27,63.11 122.91,64.47
  BOTTOM w0.089: CPU1.BG49 121.02,74.24 120.92,73.97 120.92,73.95 121,73.72 121.1,73.67 121.13,73.64 121.23,73.36 121.73,71.99 v2(121.44,71.36)
  BOTTOM w0.203: v2(116.95,33.35) 116.78,33.35 116.33,32.89 116.33,31.78 116.47,31.63 DM1.108
M_A_BS2: length 61.8
  TOP w0.203: v1(106.59,36.88) 106.84,36.62 v2(107.1,36.62)
  L4 w0.191: v2(117.03,69.7) 116,67.49 116,66.3 115.32,64.85 112.17,61.69 109.84,56.71 109.71,56.42 109.68,56.39 109.08,55.79 107.34,55.14 106.01,54.65 105.09,54.31 102.02,51.24 102.02,50.69 102.21,50.5 102.75,50.5 102.94,50.31 102.94,49.86 102.75,49.67 102.21,49.67 102.02,49.48 102.02,49.04 102.21,48.85 103.16,48.85 103.29,48.72 103.29,48.15 103.16,48.02 102.21,48.02 102.02,47.83 102.02,47.39 102.21,47.2 103.41,47.2 103.54,47.07 103.54,46.5 103.41,46.37 102.21,46.37 102.02,46.18 102.02,45.74 102.21,45.55 103.44,45.55 103.57,45.42 103.57,44.85 103.44,44.72 102.21,44.72 102.02,44.53 102.02,44.09 102.21,43.9 103.46,43.9 103.59,43.77 103.59,41.56 104.98,40.17 104.98,39.9 104.42,39.34 104.42,39.08 104.74,38.76 105.01,38.76 105.56,39.32 105.83,39.32 106.15,39 106.15,38.73 105.59,38.18 105.59,37.54 106.51,36.62 v2(107.1,36.62)
  BOTTOM w0.089: CPU1.BH57 117.32,72.5 117.28,72.4 117.43,71.98 117.29,71.69 117.13,71.62 117.05,71.45 117.3,70.79 117.18,70.56 116.75,70.53 116.58,70.46 116.43,70.12 116.55,69.78 116.74,69.7 v2(117.03,69.7)
  BOTTOM w0.152: v2(107.1,36.62) 107.38,36.62 108.01,37.25 108.01,37.58 107.77,37.83 DM1.79
M_A_CAS#: length 66.9
  TOP w0.203: v1(118.8,36.15) 118.42,35.77 v2(118.22,35.77)
  L4 w0.089: v2(122.68,68.2) 122.81,67.86 123.29,67.64 123.49,67.09
  L4 w0.191: 123.49,67.09 123.51,67.09 124.16,65.31 124.59,64.14 124.66,63.93 124.74,63.73 124.82,63.51 125.61,61.34 125.62,61.3 125.88,60.58 125.71,60.2 125.54,60.14 125.27,60.26 125.11,60.2 124.99,59.94 124.79,59.52 124.93,58.46 125.53,57.97 125.66,57.42 125.38,56.75 125.38,56.38 125.05,55.13 124.77,54.05 124.63,53.5 124.95,52.89 124.95,52.52 124.49,52.06 124.49,51.55 124.67,51.3 124.7,51.02 124.47,50.77 123.96,50.77 122.79,49.59 122.79,49.32 123.59,48.52 123.59,48.34 123.19,47.93 123.01,47.93 122.2,48.74 121.93,48.74 121.62,48.42 121.62,48.15 122.45,47.33 122.45,47.15 122.05,46.74 121.87,46.74 121.04,47.57 120.77,47.57 120.45,47.26 120.45,46.99 121.24,46.19 121.24,45.93 120.93,45.61 120.66,45.61 119.87,46.4 119.6,46.4 119.28,46.09 119.28,45.82 120.08,45.03 120.08,44.76 119.76,44.44 119.49,44.44 118.7,45.24 118.43,45.24 118.04,44.85 118.04,44.72 118.86,43.91 118.86,43.6 118.31,43.06 118.31,42.07 118.12,41.88 117.9,41.88 117.79,41.77 117.79,41.19 117.92,41.06 118.12,41.06 118.31,40.87 118.31,39.77 117.78,39.23 117.78,38.3 117.92,38.14 117.92,37.68 117.78,37.58 117.78,37.31 117.78,36.21 v2(118.22,35.77)
  BOTTOM w0.089: 123.33,70 123.19,70.38 123.28,70.58 122.28,73.33 122.36,73.52 122.15,74.1 CPU1.BH47
  BOTTOM w0.127: 123.33,70 123.41,69.76 123.41,68 124.34,67.07 124.34,65.9 124.22,65.78 123.5,65.78 123.38,65.9 123.38,67.33 122.68,68.02 v2(122.68,68.2)
  BOTTOM w0.203: DM1.115 118.57,37.67 118.87,37.37 118.87,36.02 118.63,35.77 v2(118.22,35.77)
M_A_CKE0: length 54.2
  TOP w0.203: v2(107.15,35.22) v1(107.15,34.65)
  L4 w0.191: v2(115.9,68.63) 113.79,64.09 111.67,61.97 109.39,57.03 109.35,56.94 109.26,56.74 109.23,56.71 108.77,56.26 107.15,55.65 104.77,54.77 101.42,51.42 101.42,39.99 106.19,35.22 v2(107.15,35.22)
  BOTTOM w0.089: 115.52,70.89 115.63,71.12 116.05,71.27 116.17,71.52 115.97,72.04 CPU1.BH61
  BOTTOM w0.152: DM1.73 105.97,37.57 105.97,35.46 106.21,35.22 v2(107.15,35.22) ; 115.52,70.89 115.34,70.5 115.2,70.36 114.4,70.36 114.28,70.24 114.28,68.74 114.4,68.63 v2(115.9,68.63)
M_A_CKE1: length 53.8
  TOP w0.203: v2(105.7,32.13) v1(105.7,31.57)
  L4 w0.191: v2(105.7,32.13) 105.74,32.13 106.53,32.92 106.53,33.69 107.63,34.79 107.63,38.29 104.14,41.79 104.14,48.94 103.95,49.13 103.68,49.13 103.49,49.32 103.49,49.76 103.68,49.95 103.95,49.95 104.14,50.15 104.14,50.59 103.95,50.78 103.68,50.78 103.49,50.97 103.49,51.52 106.06,54.08 106.42,54.22 109.38,55.31 110.14,56.08 110.14,56.08 110.39,56.38 110.53,56.66 112.89,61.65 116.36,65.11 116.58,65.59 116.58,67.16 117.3,68.7 v2(117.42,68.82)
  BOTTOM w0.089: CPU1.BH60 116.63,72.2 116.88,71.53 116.59,70.91 116.59,70.91 116.09,69.84 116.4,68.98 116.74,68.82 v2(117.42,68.82)
  BOTTOM w0.203: v2(105.7,32.13) 105.7,30.72 105.91,30.52 DM1.74
M_A_CLK0: length 60.9
  TOP w0.127: v1(114.33,35.33) 114.49,35.49 v2(114.49,35.89)
  L4 w0.114: v2(121.84,76.06) 121.8,76.05 121.46,75.32 121.66,74.78 121.27,73.95 120.98,73.66 120.92,73.6 120.76,73.26 120.68,73.08 120.41,72.5 120.41,70.2 120.84,69.01 120.84,68.81 120.87,68.72 121.38,67.33 121.8,66.16 121.8,65.49 122.15,64.54 122.15,64.2 121.95,63.79 121.91,63.7 121.8,63.46 121.8,63.46 121.28,62.95 121.16,62.83 121.16,61.98 121.07,61.8 120.96,61.55 120.69,61.45 119.91,61.45 118.25,59.8 118.12,59.56 117.32,58.12 117.16,57.82 116.88,57.32 116.45,56.52 116.2,56.08 116.01,55.73 115.57,54.93 115.42,54.67 114.59,53.16 113.3,51.87 113.3,51.06 113.18,50.95 111.74,50.95 111.49,50.7 111.49,49.99 111.74,49.74 113.18,49.74 113.3,49.63 113.3,49.11 113.18,48.99 111.79,48.99 111.54,48.75 111.54,48.04 111.79,47.79 113.18,47.79 113.3,47.67 113.3,47.15 113.18,47.04 111.82,47.04 111.57,46.79 111.57,46.08 111.82,45.83 113.18,45.83 113.3,45.72 113.3,45.17 113.21,45.08 112.91,45.08 112.66,44.83 112.66,44.12 112.91,43.88 113.21,43.88 113.3,43.79 113.3,43.04 113.18,42.92 113.01,42.92 112.76,42.68 112.76,41.97 113.01,41.72 113.18,41.72 113.3,41.6 113.3,40.82 113.55,40.57 113.88,40.57 113.99,40.46 113.99,39.86 113.6,39.47 113.6,38.66 114.34,37.91 114.34,36.27 114.49,36.12 v2(114.49,35.89)
  BOTTOM w0.127: CPU1.BD45 v2(121.84,76.06) ; v2(114.49,35.89) 114.43,35.89 113.91,36.41 113.91,37.23 114.37,37.69 DM1.101
M_A_CLK1: length 60.2
  TOP w0.127: v1(115.09,33.94) 115.35,33.68 v2(115.61,33.68)
  L4 w0.114: v2(115.61,33.68) 115.48,33.56 115.44,33.56 115.35,33.56 114.97,33.56 114.81,33.71 114.81,34.73 113.59,35.95 113.59,37.56 112.84,38.31 112.84,39.74 111.9,40.68 111.9,43.7 110.73,44.87 110.73,48.06 110.48,48.31 110.36,48.31 110.25,48.42 110.25,48.94 110.36,49.06 110.48,49.06 110.73,49.31 110.73,50.02 110.48,50.26 110.31,50.26 110.2,50.38 110.2,50.9 110.31,51.01 110.48,51.01 110.73,51.26 110.73,52.01 112.08,53.36 113.05,53.36 113.9,54.83 113.81,55.17 113.72,55.22 113.68,55.38 113.79,55.58 113.95,55.62 114.04,55.56 114.38,55.65 114.59,56.02 114.5,56.36 114.41,56.41 114.36,56.57 114.48,56.76 114.64,56.81 114.73,56.75 115.07,56.84 115.28,57.2 115.19,57.54 115.09,57.6 115.05,57.75 115.17,57.95 115.32,57.99 115.42,57.94 115.76,58.03 115.97,58.39 115.87,58.73 115.78,58.79 115.74,58.94 115.85,59.14 116.01,59.18 116.1,59.13 116.44,59.22 116.85,59.92 117.74,60.74 117.75,61.21 117.95,61.39 118.41,61.37 119.03,61.94 120.1,62.33 120.6,63.41 121.3,63.66 121.59,64.29 121.59,64.77 121.49,65.05 121.49,66.14 120.55,68.71 120.52,68.81 120.52,69.21 120.14,70.25 120.14,72.44 120.87,74 121.14,74.27 121.16,74.32 121.41,74.84 120.82,76.44 v2(119.96,76.84)
  BOTTOM w0.127: DM1.102 114.67,32.89 115.14,33.36 115.29,33.36 v2(115.61,33.68) ; CPU1.BB48 v2(119.96,76.84)
M_A_CLK#0: length 60.9
  TOP w0.127: v2(114.97,36.41) 115.23,36.41 v1(115.48,36.65)
  L4 w0.114: v2(122,75.43) 121.74,75.21 121.91,74.77 121.47,73.82 121.14,73.5 121.11,73.47 120.99,73.21 120.96,73.14 120.89,72.99 120.64,72.45 120.64,70.24 121.07,69.05 121.07,68.85 121.08,68.8 121.59,67.41 122.03,66.2 122.03,65.53 122.37,64.58 122.37,64.15 122.16,63.7 122.11,63.6 122.01,63.37 121.97,63.29 121.95,63.29 121.44,62.78 121.39,62.73 121.39,61.93 121.28,61.7 121.13,61.37 120.73,61.22 120,61.22 118.44,59.66 118.32,59.45 117.52,58.01 117.36,57.7 117.08,57.21 116.96,56.98 116.65,56.41 116.48,56.11 116.4,55.97 116.21,55.62 116.04,55.32 115.77,54.82 115.62,54.56 114.77,53.02 113.53,51.77 113.53,50.97 113.28,50.72 111.83,50.72 111.72,50.61 111.72,50.09 111.83,49.97 113.28,49.97 113.53,49.72 113.53,49.01 113.28,48.77 111.88,48.77 111.77,48.65 111.77,48.13 111.88,48.02 113.28,48.02 113.53,47.77 113.53,47.06 113.28,46.81 111.91,46.81 111.8,46.7 111.8,46.17 111.91,46.06 113.28,46.06 113.53,45.81 113.53,45.08 113.3,44.85 113,44.85 112.89,44.74 112.89,44.22 113,44.1 113.3,44.1 113.53,43.88 113.53,42.94 113.28,42.7 113.1,42.7 112.99,42.58 112.99,42.06 113.1,41.95 113.28,41.95 113.53,41.7 113.53,40.92 113.65,40.8 113.98,40.8 114.22,40.55 114.22,39.76 113.83,39.37 113.83,38.75 114.57,38.01 114.57,36.41 114.7,36.28 114.81,36.28 114.94,36.41 v2(114.97,36.41)
  BOTTOM w0.127: v2(114.97,36.41) 114.91,36.35 114.32,36.35 114.15,36.52 114.15,37.13 114.97,37.95 DM1.103 ; CPU1.BE45 122.58,75.76 122.58,75.56 122.3,75.28 122.14,75.28 v2(122,75.43)
M_A_CLK#1: length 60.2
  TOP w0.127: v1(115.12,32.51) 115.45,32.84 v2(115.6,32.84)
  L4 w0.114: v2(120.21,76.24) 120.49,76.34 120.64,76.27 121.16,74.85 120.97,74.45 120.95,74.4 120.68,74.13 119.91,72.49 119.91,70.21 120.27,69.22 120.29,69.17 120.29,68.77 120.34,68.63 121.26,66.1 121.26,65.01 121.37,64.73 121.37,64.35 121.13,63.85 120.43,63.59 119.94,62.52 118.91,62.14 118.88,62.11 118.32,61.6 117.86,61.62 117.53,61.31 117.51,60.85 116.67,60.06 116.29,59.42 116.14,59.37 116.04,59.43 115.7,59.34 115.49,58.97 115.58,58.64 115.68,58.58 115.72,58.43 115.61,58.23 115.45,58.19 115.36,58.24 115.02,58.15 114.81,57.79 114.9,57.45 114.99,57.39 115.03,57.24 114.92,57.04 114.76,57 114.67,57.05 114.33,56.96 114.12,56.6 114.21,56.26 114.3,56.2 114.35,56.05 114.23,55.85 114.07,55.81 113.98,55.86 113.64,55.77 113.43,55.41 113.52,55.07 113.62,55.02 113.66,54.86 113.29,54.22 112.97,53.67 112.92,53.59 111.98,53.59 110.5,52.11 110.5,51.36 110.39,51.24 110.21,51.24 109.97,50.99 109.97,50.28 110.21,50.03 110.39,50.03 110.5,49.92 110.5,49.4 110.39,49.29 110.27,49.29 110.02,49.04 110.02,48.33 110.27,48.08 110.39,48.08 110.5,47.96 110.5,44.77 111.67,43.61 111.67,40.59 112.61,39.64 112.61,38.21 113.36,37.46 113.36,35.86 114.58,34.63 114.58,33.62 114.88,33.33 115.35,33.33 115.6,33.07 v2(115.6,32.84)
  BOTTOM w0.127: v2(120.21,76.24) 120.44,76.42 120.52,76.41 120.64,76.38 120.74,76.27 CPU1.BD48 ; DM1.104 115.27,31.37 114.91,31.73 114.91,32.79 115.24,33.12 115.33,33.12 v2(115.6,32.84)
M_A_CS#0: length 61.7
  TOP w0.203: v1(119.23,33.63) 118.86,33.26 v2(118.8,33.26)
  L4 w0.089: 122.52,74.54 122.59,74.7 122.59,75.18 122.62,75.24 122.62,75.44 122.59,75.51 122.59,77.96 121.87,79.96 121.87,80.67 121.35,81.2 121.35,81.82 121.23,81.93 120.7,81.93 120.58,81.82 120.58,81.19 v2(121.29,80.48)
  L4 w0.191: 122.52,74.54 122.52,73.01 124.51,67.56 125.23,66.83 125.95,64.86 126.11,64.86 126.31,64.3 126.39,64.08 127.7,60.48 127.7,60.48 127.92,59.89 128.18,59.2 129.19,56.18 129.09,55.8 127.74,50.04 120.51,42.81 120.51,39.46 119.62,38.57 119.62,34.09 v2(118.8,33.26)
  BOTTOM w0.152: DM1.114 118.27,32.71 117.94,33.03 117.94,33.23 118.1,33.38 118.67,33.38 v2(118.8,33.26)
  BOTTOM w0.203: CPU1.AR43 v2(121.29,80.48)
M_A_CS#1: length 60.5
  TOP w0.203: v2(120.76,36.71) v1(120.76,37.28)
  L4 w0.089: v2(122.86,78.75) 123.09,78.64 123.13,78.53 122.9,78.2 122.9,78.01 122.94,77.86 123.02,77.74 123.12,77.74 123.44,77.68 123.46,77.68 123.5,77.56 123.5,77.5 123.11,76.67 123.31,76.13 123.39,75.91 123.5,75.59 123.26,75.06 123.37,74.76
  L4 w0.191: v2(120.76,36.71) 120.86,36.81 120.86,37.61 122.49,39.24 123.21,39.24 123.33,39.35 123.33,39.95 123.21,40.06 122.39,40.06 122.2,40.25 122.2,40.7 122.39,40.89 124.03,40.89 124.14,41 124.14,41.6 124.03,41.71 122.39,41.71 122.2,41.9 122.2,42.45 122.74,42.99 123.01,42.99 123.56,42.44 123.72,42.44 124.14,42.87 124.14,43.03 123.59,43.57 123.59,43.84 128.84,49.09 130.41,56.05 130.41,56.27 129.22,59.57 129.12,59.82 129.12,59.83 129.07,59.98 128.89,60.46 128.66,61.11 128.63,61.12 128.59,61.22 128.58,61.27 128.35,61.91 127.98,62.99 127.43,64.53 127.29,64.89 127.21,65.09 127.25,65.19 127.24,65.24 127.07,65.69 126.68,65.87 126.03,67.65 125.5,67.89 123.16,74.32 123.37,74.76
  BOTTOM w0.152: v2(120.76,36.71) 120.76,36.68 120.65,36.57 120.24,36.57 120.13,36.68 120.13,37.61 120.37,37.85 DM1.121 ; v2(122.86,78.75) 122.79,78.59 122.97,78.12 123.17,78.02 123.34,78.09 123.49,78.41 CPU1.BA41
M_A_DQ0: length 57.8
  TOP w0.14: v1(93.76,36.27) 93.44,35.95 v2(93.28,35.95)
  L4 w0.127: v2(112.27,73.34) 112.7,72.15 112.27,71.23 112.1,71.17 111.8,71.06 106.65,60.03 106.55,59.81 106.32,59.39 103.87,58.53 103.65,58.45 103.6,58.43 103.15,58.27 99.94,57 94.74,51.8 94.74,51.08 94.61,50.95 93.95,50.95 93.82,50.83 93.82,50.57 93.95,50.45 94.61,50.45 94.74,50.32 94.74,50.06 94.61,49.94 94.06,49.94 93.95,49.82 93.95,49.54 94.06,49.43 94.61,49.43 94.74,49.3 94.74,42.54 93.87,41.66 93.87,41.28 93.99,41.16 94.41,41.16 94.52,41.04 94.52,40.76 94.41,40.65 93.99,40.65 93.87,40.52 93.87,37.47 93.87,35.77 93.73,35.64 93.6,35.64 v2(93.28,35.95)
  BOTTOM w0.089: CPU1.AY62 113.73,75.42 113.57,75.35 113.5,75.33 113.49,75.33 113.23,75.23 113.06,75.17 112.9,75.11 112.23,74.44 112.14,74.25 112.14,73.68 v2(112.27,73.34)
  BOTTOM w0.14: DM1.41 93.97,36.19 93.73,35.95 v2(93.28,35.95)
M_A_DQ1: length 58
  TOP w0.14: v2(93.39,33.52) 93.62,33.52 v1(93.89,33.78)
  L4 w0.127: v2(93.39,33.52) 94.25,34.38 94.25,37.29 94.25,38.66 94.37,38.79 94.86,38.79 94.98,38.9 94.98,39.18 94.86,39.3 94.37,39.3 94.25,39.43 94.25,39.81 95.18,40.74 95.18,51.42 100.51,56.74 103.78,58.1 106.56,59.05 106.92,59.69 109.79,65.85 109.8,65.85 110.11,66.52 112.08,70.74 112.54,70.91 113.4,72.75 113.06,73.69 v2(112.54,73.93)
  BOTTOM w0.089: CPU1.AY61 114.27,75.3 113.89,75.18 113.85,75.16 113.72,75.11 113.57,75.15 113.53,75.14 113.52,75.14 113.34,75.07 113.27,75.05 113.27,75.04 113.01,74.95 112.67,74.61 112.54,74.34 v2(112.54,73.93)
  BOTTOM w0.102: v2(93.39,33.52) 93.82,33.52 94.27,33.07 DM1.42
M_A_DQ2: length 56.7
  TOP w0.14: v2(96.57,35.17) 96.74,35.17 v1(97.06,35.49)
  L4 w0.127: v2(112.91,70.43) 113.16,70.31 113.97,68.09 112.2,64.29 111.15,63.91 108.25,57.39 108.12,57.27 103.99,55.74 102.26,55.09 98.58,51.41 98.58,46.91 98.7,46.78 99.33,46.78 99.45,46.66 99.45,46.15 99.33,46.02 98.7,46.02 98.58,45.89 98.58,45.39 98.7,45.26 99.33,45.26 99.45,45.13 99.45,44.62 99.33,44.5 98.76,44.5 98.65,44.38 98.65,43.85 98.76,43.73 99.33,43.73 99.45,43.61 99.45,39.72 97.66,37.93 97.66,37.36 97.66,36.26 v2(96.57,35.17)
  BOTTOM w0.102: CPU1.BE62 114.46,73.21 113.38,72.82 112.63,71.2 v2(112.91,70.43)
  BOTTOM w0.14: v2(96.57,35.17) 97.02,35.17 97.57,35.72 DM1.53
M_A_DQ3: length 56.5
  TOP w0.14: v2(96.46,34.05) 96.79,34.05 v1(96.98,34.24)
  L4 w0.127: v2(113.26,71.13) 114.46,68 112.61,64.04 111.47,63.61 108.57,57.17 108.34,56.94 102.91,54.93 99.03,51.05 99.03,50.67 99.16,50.54 99.71,50.54 99.83,50.42 99.83,49.91 99.71,49.78 99.16,49.78 99.03,49.65 99.03,49.15 99.16,49.02 99.71,49.02 99.83,48.89 99.83,48.38 99.71,48.26 99.16,48.26 99.03,48.13 99.03,47.62 99.16,47.49 99.71,47.49 99.83,47.37 99.83,39.18 99.68,39.02 99.38,39.02 98.5,38.15 98.07,37.71 98.07,35.66 v2(96.46,34.05)
  BOTTOM w0.102: CPU1.BG62 114.77,72.6 114.25,72.41 114.08,72.04 114.11,71.94 113.84,71.34 v2(113.26,71.13)
  BOTTOM w0.14: v2(96.46,34.05) 97.29,33.21 97.29,31.64 97.27,31.62 DM1.52
M_A_DQ4: length 56.5
  TOP w0.14: v1(97.06,36.76) 96.74,36.44 v2(96.57,36.44)
  L4 w0.127: v2(96.57,36.44) 97.22,37.09 97.22,38.24 98.19,39.22 98.19,40.55 98.32,40.68 98.95,40.68 99.07,40.81 99.07,41.32 98.95,41.44 98.32,41.44 98.19,41.57 98.19,42.08 98.32,42.21 98.95,42.21 99.07,42.33 99.07,42.84 98.95,42.97 98.32,42.97 98.19,43.09 98.19,46.34 98.06,46.47 97.9,46.47 97.78,46.58 97.78,46.86 97.9,46.98 98.06,46.98 98.19,47.1 98.19,47.36 98.06,47.48 97.6,47.48 97.48,47.61 97.48,47.87 97.6,47.99 98.06,47.99 98.19,48.12 98.19,48.5 98.06,48.63 97.6,48.63 97.48,48.75 97.48,49.26 97.6,49.39 98.06,49.39 98.19,49.52 98.19,50.02 98.06,50.15 97.6,50.15 97.48,50.28 97.48,50.79 97.6,50.91 98.06,50.91 98.19,51.04 98.19,51.57 102.05,55.42 102.11,55.44 107.89,57.59 107.95,57.72 109.86,62.05 110.88,64.23 111.89,64.59 113.54,68.14 113,69.63 v2(112.57,69.83)
  BOTTOM w0.102: v2(112.57,69.83) 112.22,70.8 113.31,73.15 113.74,73.3 CPU1.BD63
  BOTTOM w0.14: v2(96.57,36.44) 97.02,36.44 97.15,36.57 97.15,37.64 96.97,37.82 DM1.51
M_A_DQ5: length 58.6
  TOP w0.14: v2(93.28,37.22) v1(93.28,37.8)
  L4 w0.127: v2(111.97,72.75) 111.97,71.79 111.5,71.31 110.73,69.67 110.72,69.66 106.37,60.33 105.79,59.73 102.5,58.43 99.41,57.21 93.38,51.18 93.38,48.88 93.5,48.76 94.23,48.76 94.36,48.63 94.36,48.38 94.23,48.25 93.24,48.25 93.13,48.14 93.13,47.86 93.24,47.74 94.23,47.74 94.36,47.61 94.36,47.36 94.23,47.23 93.27,47.23 93.15,47.12 93.15,46.84 93.27,46.73 94.23,46.73 94.36,46.6 94.36,46.22 94.23,46.09 93.27,46.09 93.15,45.98 93.15,45.7 93.27,45.58 94.23,45.58 94.36,45.46 94.36,43.92 94.23,43.79 94.04,43.79 93.93,43.68 93.93,43.4 94.04,43.28 94.23,43.28 94.36,43.16 94.36,42.76 93.28,41.68 93.28,38.12 v2(93.28,37.22)
  BOTTOM w0.089: v2(111.97,72.75) 111.97,72.85 111.87,73.13 111.87,74.11 112.07,74.55 112.8,75.28 113.17,75.41 113.44,75.51 113.47,75.57 CPU1.AW62
  BOTTOM w0.14: DM1.39 93.37,37.31 v2(93.28,37.22)
M_A_DQ6: length 58.6
  TOP w0.14: v2(93.39,32.25) 93.62,32.25 v1(93.91,32.54)
  L4 w0.127: v2(111.5,72.23) 106.06,60.55 105.57,60.06 103.01,59.04 102.17,58.74 98.92,57.45 98.92,57.45 92.73,51.26 92.73,44.93 92.86,44.81 93.87,44.81 93.98,44.7 93.98,44.4 93.87,44.3 92.9,44.3 92.78,44.18 92.78,43.8 92.91,43.68 93.23,43.68 93.36,43.55 93.36,43.3 93.23,43.17 92.91,43.17 92.78,43.04 92.78,32.85 v2(93.39,32.25)
  BOTTOM w0.102: v2(93.39,32.25) 93.67,31.96 DM1.40 ; v2(111.5,72.23) 111.5,73.88 112.1,75.16 112.54,75.6 113.16,75.7 CPU1.AW63
M_A_DQ7: length 56.9
  TOP w0.14: v1(97.04,33.02) 96.77,32.75 v2(96.46,32.75)
  L4 w0.127: v2(112.28,69.27) 112.33,69.24 112.9,67.67 111.72,65.14 110.72,64.77 108.08,59.15 107.9,58.69 107.7,58.24 107.53,57.93 101.5,55.62 101.49,55.62 97.1,51.23 97.1,46.5 97.76,45.83 97.76,39.52 96.08,37.84 96.08,35.99 96.08,35.78 95.67,35.38 95.67,34.74 95.54,34.61 94.86,34.61 94.74,34.5 94.74,34.22 94.86,34.1 95.54,34.1 95.67,33.98 95.67,33.03 95.95,32.75 v2(96.46,32.75)
  BOTTOM w0.102: CPU1.BD62 114.16,73.81 113.24,73.48 111.84,70.47 v2(112.28,69.27)
  BOTTOM w0.14: DM1.50 96.67,31.62 96.9,31.85 96.9,32.31 v2(96.46,32.75)
M_A_DQ8: length 63.9
  TOP w0.14: v2(91.36,36.51) 91.58,36.51 v1(91.9,36.83)
  L4 w0.127: v2(91.36,36.51) 90.89,36.98 90.89,46.12 91.02,46.25 91.31,46.25 91.44,46.38 91.44,46.63 91.31,46.76 91.02,46.76 90.89,46.88 90.89,47.14 91.02,47.27 91.31,47.27 91.44,47.39 91.44,47.65 91.31,47.77 91.02,47.77 90.89,47.9 90.89,48.15 91.02,48.28 91.31,48.28 91.44,48.41 91.44,48.66 91.31,48.79 91.02,48.79 90.89,48.92 90.89,49.17 91.02,49.3 91.31,49.3 91.44,49.42 91.44,49.68 91.31,49.81 91.02,49.81 90.89,49.93 90.89,50.19 91.02,50.31 91.31,50.31 91.44,50.44 91.44,50.69 91.31,50.82 91.02,50.82 90.89,50.95 90.89,51.33 91.16,51.6 91.16,51.78 91.08,51.86 91.08,52.04 91.26,52.22 91.44,52.22 91.52,52.14 91.7,52.14 91.88,52.32 91.88,52.5 91.8,52.58 91.8,52.76 91.98,52.94 92.16,52.94 92.24,52.86 92.42,52.86 92.6,53.04 92.6,53.22 92.52,53.3 92.52,53.48 92.7,53.66 92.88,53.66 92.96,53.58 93.14,53.58 93.32,53.76 93.32,53.94 93.24,54.02 93.24,54.2 93.42,54.38 93.6,54.38 93.68,54.29 93.86,54.29 94.04,54.47 94.04,54.65 93.95,54.73 93.95,54.91 94.13,55.09 94.31,55.09 94.39,55.01 94.57,55.01 94.75,55.19 94.75,55.37 94.67,55.45 94.67,55.63 94.85,55.81 95.03,55.81 95.11,55.73 95.29,55.73 95.47,55.91 95.47,56.09 95.39,56.17 95.39,56.35 95.57,56.53 95.75,56.53 95.83,56.45 96.01,56.45 96.19,56.63 96.19,56.81 96.11,56.89 96.11,57.07 96.29,57.25 96.47,57.25 96.55,57.17 96.73,57.17 96.91,57.35 96.91,57.53 96.83,57.61 96.83,57.79 97.01,57.97 97.19,57.97 97.27,57.89 97.45,57.89 97.91,58.35 98.35,58.8 100.73,59.72 100.8,59.88 100.86,60.02 101.13,60.13 101.44,60 101.68,60.09 101.75,60.26 101.72,60.34 101.79,60.51 102.02,60.6 102.19,60.53 102.22,60.45 102.39,60.38 102.62,60.47 102.69,60.63 102.63,60.8 102.69,60.95 102.95,61.05 103.1,60.99 103.17,60.82 103.33,60.75 103.99,61.01 105.19,62.22 110.66,73.95 111.3,74.58 111.96,74.82 112.19,75.06 113.18,75.42 113.5,75.74 v2(114.61,76.14)
  BOTTOM w0.14: CPU1.AV59 v2(114.61,76.14) ; DM1.33 91.57,37.62 91.85,37.34 91.85,36.74 91.62,36.51 v2(91.36,36.51)
M_A_DQ9: length 63.1
  TOP w0.14: v1(89.36,33.12) 89.01,33.48 v2(88.9,33.48)
  L4 w0.127: v2(88.9,33.48) 89.32,33.9 89.32,34.32 88.56,35.08 88.46,35.18 88.46,37.96 88.59,38.08 89.03,38.08 89.15,38.21 89.15,38.47 89.03,38.59 88.59,38.59 88.46,38.72 88.46,38.97 88.59,39.1 89.01,39.1 89.12,39.21 89.12,39.49 89.01,39.61 88.59,39.61 88.46,39.74 88.46,39.99 88.59,40.12 88.76,40.12 88.88,40.23 88.88,40.51 88.76,40.62 88.59,40.62 88.46,40.75 88.46,53.83 89.71,55.08 90.93,55.08 95.16,59.31 95.48,59.75 98.53,60.69 99.76,61.51 100.28,61.86 100.43,61.98 100.77,62.32 105.57,67.08 106.31,68.59 108,72.22 108.01,72.24 108.96,73.92 110.06,75.17 111.01,75.51 111.46,75.68 v2(111.79,76.27)
  BOTTOM w0.102: CPU1.AU63 112.77,76.35 112.12,76.12 v2(111.79,76.27) ; v2(88.9,33.48) 88.9,33.48 88.77,33.61 88.28,33.61 88.15,33.48 88.15,31.83 88.27,31.71 DM1.22
M_A_DQ10: length 65.1
  TOP w0.14: v2(87.97,37.13) v1(87.97,37.7)
  L4 w0.127: v2(87.97,37.13) 88.05,37.21 88.05,53.96 89.6,55.52 90.81,55.52 91.01,55.71 91.01,55.87 90.65,56.24 90.65,56.4 90.84,56.6 91,56.6 91.35,56.25 91.51,56.25 91.71,56.45 91.71,56.61 91.3,57.03 91.3,57.21 91.48,57.39 91.65,57.39 92.08,56.96 92.25,56.96 92.44,57.15 92.44,57.32 92.01,57.75 92.01,57.93 92.19,58.1 92.37,58.1 92.81,57.67 92.97,57.67 93.17,57.87 93.17,58.03 92.73,58.46 92.73,58.64 93,58.91 93.18,58.91 93.61,58.48 93.79,58.48 93.97,58.66 93.97,58.84 93.54,59.27 93.54,59.45 93.76,59.67 94,59.74 94.32,59.47 94.62,59.5 94.84,59.71 95.24,60.07 95.25,60.08 98.17,60.98 98.51,61.14 99.14,61.56 99.54,61.83 99.55,61.83 100.06,62.17 104.09,66.15 105.21,67.26 105.21,67.27 106.63,70.32 107.53,72.25 108.93,74.53 110.8,76.4 111.09,76.5 111.24,76.48 111.29,76.44 111.31,76.32 v2(111.17,76.06)
  BOTTOM w0.102: CPU1.AU62 113.51,76.64 113.2,76.52 112.99,76.07 112.56,75.91 112.37,75.74 111.93,75.29 111.91,75.24 111.66,74.72 111.53,74.59 111.42,74.55 111.2,74.61 110.97,74.84 110.97,75.84 v2(111.17,76.06)
  BOTTOM w0.14: DM1.21 87.97,37.8 88.18,37.64 88.18,37.33 v2(87.97,37.13)
M_A_DQ11: length 64
  TOP w0.14: v2(91.36,35.24) 91.58,35.24 v1(91.85,35.51)
  L4 w0.127: v2(91.36,35.24) 91.81,35.68 91.81,37.34 91.39,37.76 91.39,38.14 91.52,38.26 91.69,38.26 91.82,38.39 91.82,38.65 91.69,38.77 91.4,38.77 91.28,38.89 91.28,39.17 91.4,39.28 91.69,39.28 91.82,39.41 91.82,39.66 91.69,39.79 91.39,39.79 91.28,39.9 91.28,40.18 91.39,40.3 91.69,40.3 91.82,40.42 91.82,40.68 91.69,40.8 91.39,40.8 91.28,40.92 91.28,41.2 91.39,41.31 91.69,41.31 91.82,41.44 91.82,41.69 91.69,41.82 91.39,41.82 91.27,41.93 91.27,42.21 91.39,42.33 91.69,42.33 91.82,42.46 91.82,42.71 91.69,42.84 91.39,42.84 91.27,42.95 91.27,43.23 91.39,43.34 91.69,43.34 91.82,43.47 91.82,43.73 91.69,43.85 91.39,43.85 91.27,43.97 91.27,44.25 91.39,44.36 91.69,44.36 91.82,44.49 91.82,44.74 91.58,44.98 91.58,45.27 91.82,45.5 91.82,51.71 98.57,58.46 98.58,58.46 100.65,59.27 100.54,59.23 101.71,59.66 104.66,60.75 105.26,61.35 110.03,71.58 110.88,73.41 112.35,74.87 112.58,74.96 114.84,75.78 115.24,76.18 v2(115.28,76.38)
  BOTTOM w0.14: DM1.35 92.17,37.62 92.26,37.53 92.26,36.28 92.51,36.02 92.51,35.41 92.34,35.24 v2(91.36,35.24) ; CPU1.AV58 115.29,76.85 115.2,76.66 115.2,76.46 v2(115.28,76.38)
M_A_DQ12: length 62.1
  TOP w0.14: v2(91.9,32.16) 91.73,32.16 91.37,32.51 v1(91.37,32.59)
  L4 w0.127: v2(91.9,32.16) 90.82,33.24 90.82,35.92 90.44,36.3 90.44,39.09 90.44,40.93 90.44,51.94 97.31,58.81 99.17,59.52 101.36,61.03 102.88,62.55 103.06,62.55 103.3,62.3 103.48,62.3 103.66,62.48 103.66,62.66 103.42,62.91 103.42,63.09 103.6,63.27 103.78,63.27 104.02,63.02 104.2,63.02 104.38,63.2 104.38,63.38 104.14,63.62 104.14,63.8 106.69,66.36 107.4,67.88 109.18,71.69 110.34,74.19 110.81,74.66 111.85,75.04 112.1,75.29 113.04,75.63 113.7,76.29 115.11,76.8 115.57,76.8 v2(115.95,76.63)
  BOTTOM w0.102: DM1.34 91.87,31.6 91.9,31.63 v2(91.9,32.16)
  BOTTOM w0.14: CPU1.AV57 v2(115.95,76.63)
M_A_DQ13: length 65.4
  TOP w0.14: v1(87.48,36.15) 87.83,35.8 v2(87.93,35.8)
  L4 w0.127: v2(87.93,35.8) 87.52,36.21 87.52,37.85 87.67,37.99 87.67,38.36 87.52,38.5 87.52,38.86 87.67,39.01 87.67,39.37 87.52,39.52 87.52,39.88 87.67,40.03 87.67,40.39 87.52,40.53 87.52,40.9 87.67,41.04 87.67,41.4 87.52,41.55 87.52,41.91 87.67,42.06 87.67,42.42 87.52,42.57 87.52,42.93 87.67,43.07 87.67,43.44 87.52,43.58 87.52,43.94 87.67,44.09 87.67,44.45 87.52,44.6 87.52,44.96 87.67,45.11 87.67,45.47 87.52,45.61 87.52,45.98 87.67,46.12 87.67,46.48 87.52,46.63 87.52,46.99 87.67,47.14 87.67,47.5 87.52,47.65 87.52,48.01 87.67,48.15 87.67,48.52 87.52,48.66 87.52,49.02 87.67,49.17 87.67,49.53 87.52,49.68 87.52,50.91 87.67,51.05 87.67,51.41 87.52,51.56 87.52,51.92 87.67,52.07 87.67,52.43 87.52,52.58 87.52,52.94 87.67,53.08 87.67,53.45 87.52,53.59 87.52,53.97 94.08,60.53 94.44,60.63 94.74,60.47 95.02,60.55 95.09,60.69 95.18,60.84 99.04,61.95 99.33,62.15 99.34,62.15 99.6,62.32 99.81,62.47 103.82,66.42 104.9,67.49 105.36,68.54 105.74,69.36 107.12,72.34 107.28,72.58 108.51,74.43 110.67,76.59 110.95,76.7 111.88,77.04 112.62,77.78 112.76,78.05 113.07,78.71 113.47,79.11 113.63,79.17 116.04,79.17 v2(116.62,78.9)
  BOTTOM w0.14: CPU1.AT55 v2(116.62,78.9) ; v2(87.93,35.8) 88.09,35.8 88.57,36.28 DM1.23
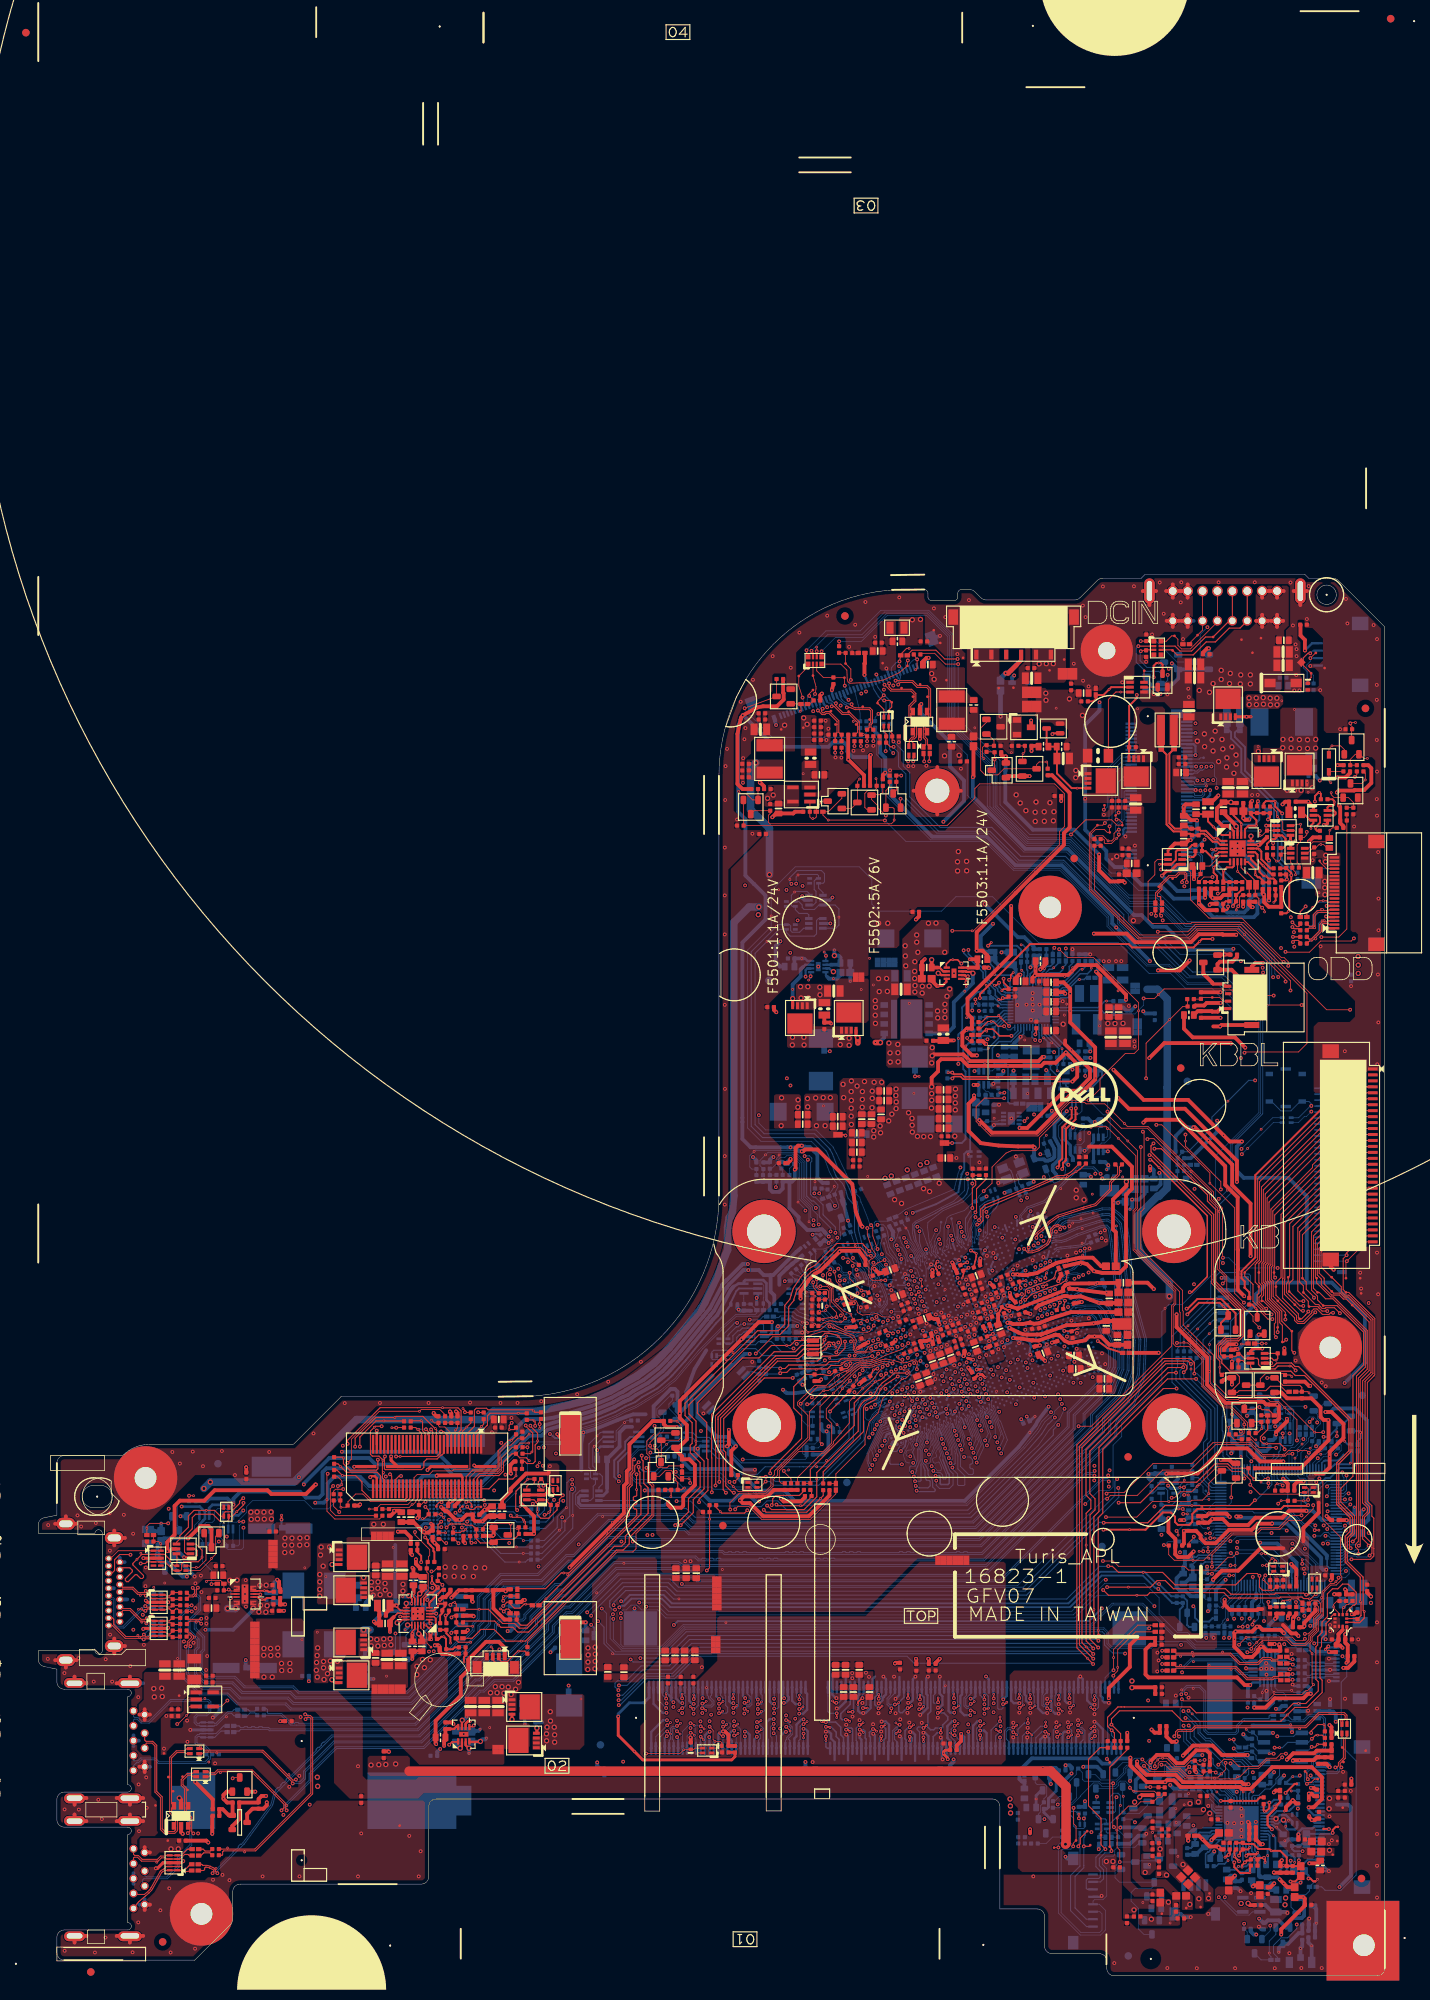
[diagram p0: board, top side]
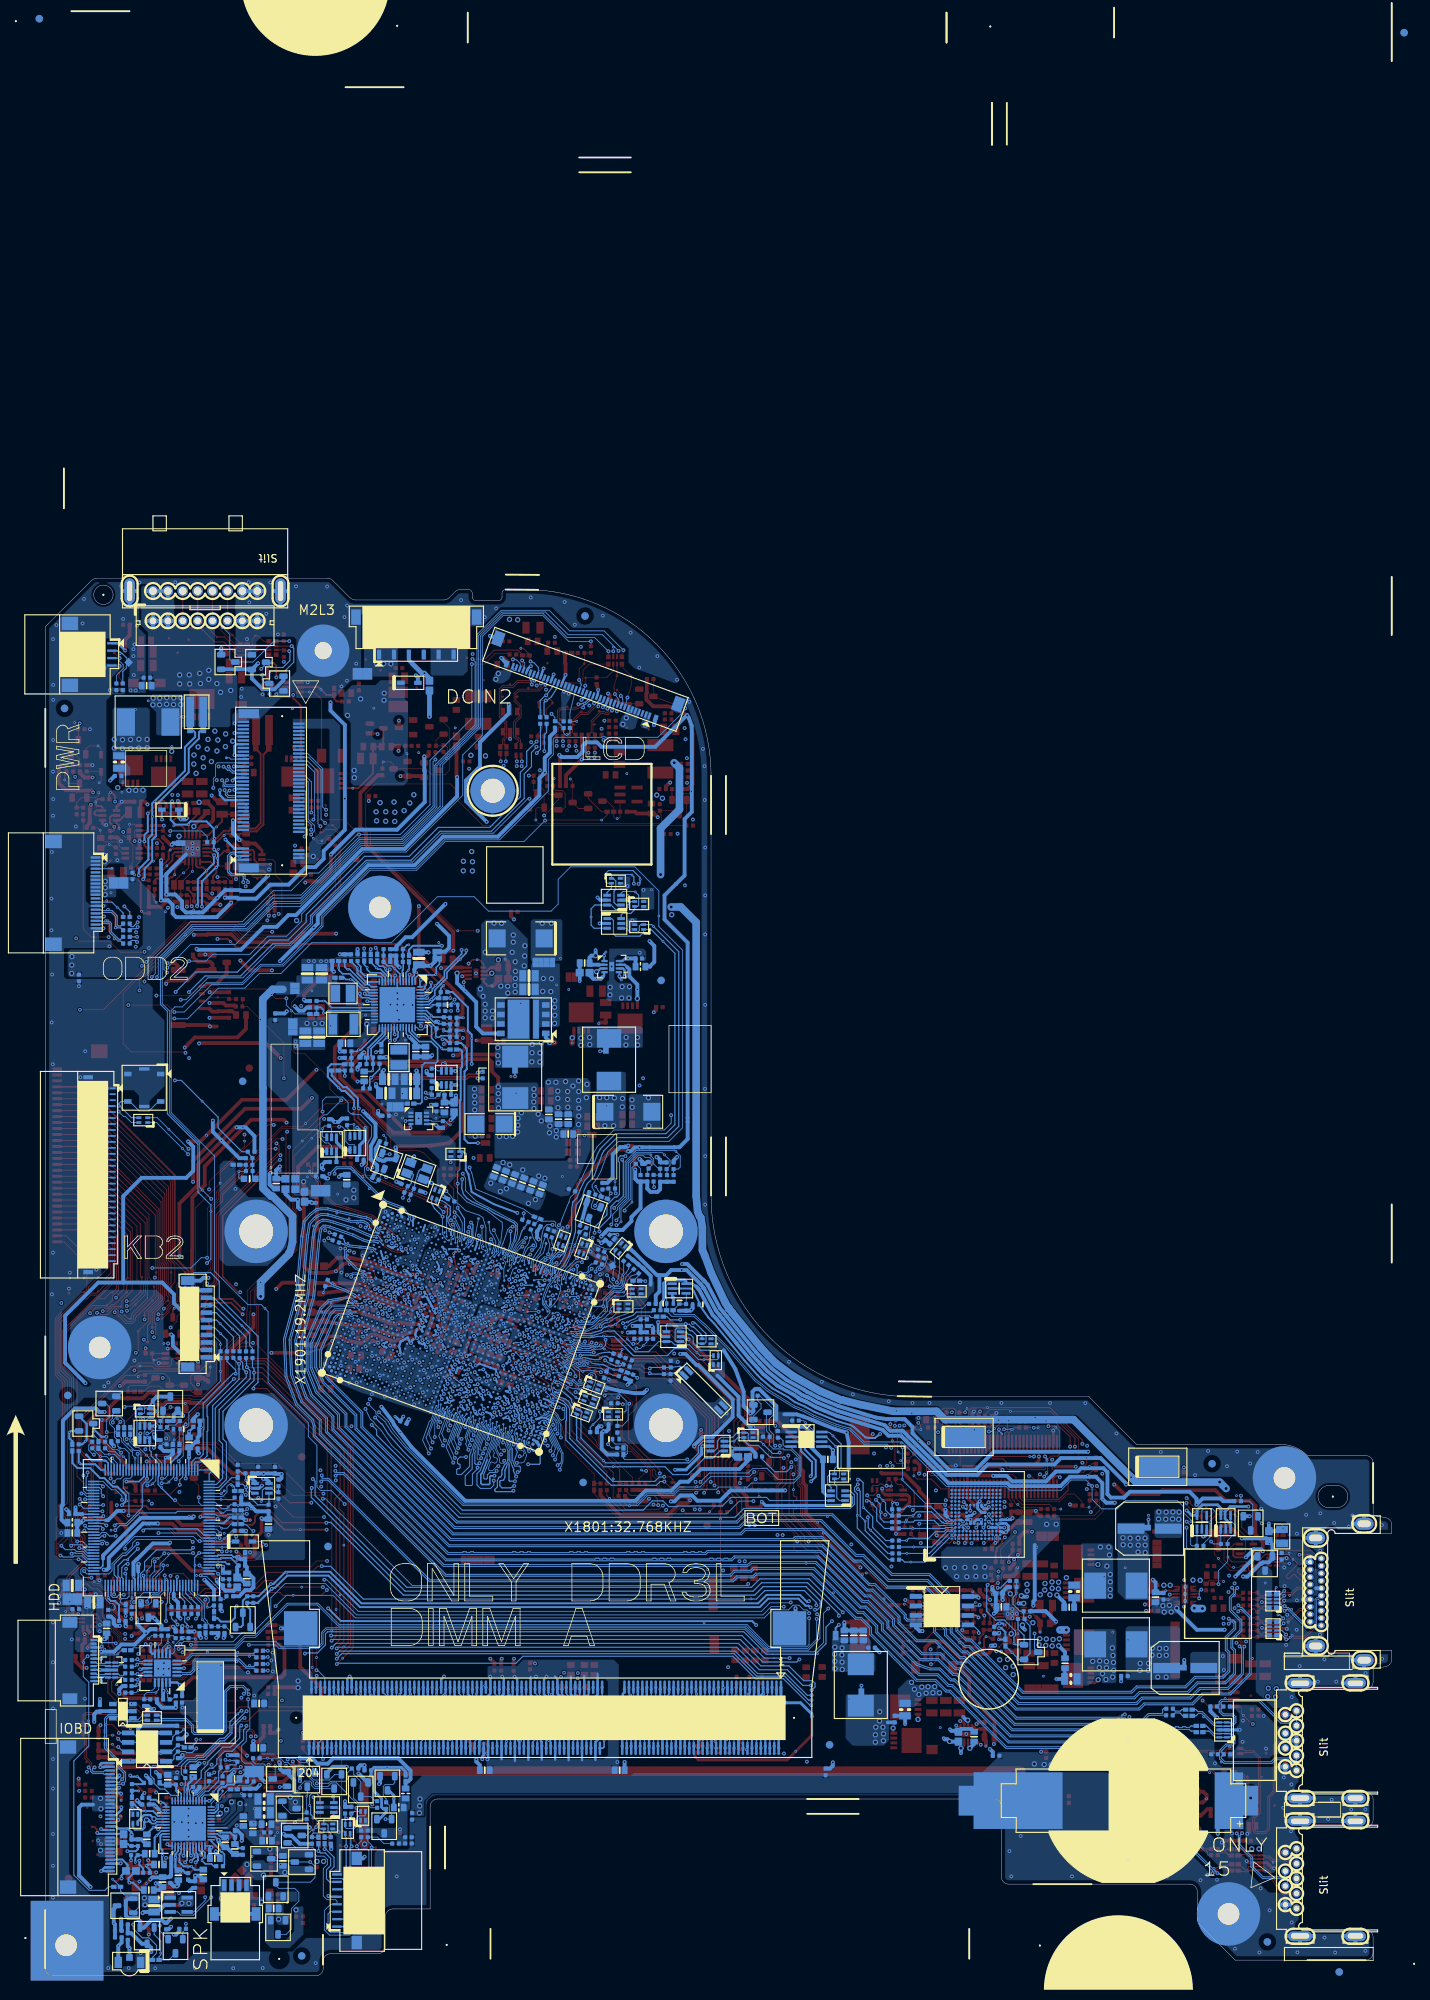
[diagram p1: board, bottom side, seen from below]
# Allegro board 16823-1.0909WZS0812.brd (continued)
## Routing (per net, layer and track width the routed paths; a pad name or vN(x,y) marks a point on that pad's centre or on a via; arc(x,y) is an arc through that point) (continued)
M_A_DQ14: length 67.1
  TOP w0.14: v1(89.29,31.65) 89.29,31.69 v2(88.9,32.08)
  L4 w0.127: v2(88.9,32.08) 88.05,32.93 88.05,34.04 87.14,34.95 87.14,54.13 92.84,59.83 93.9,60.89 98.86,62.31 99.15,62.51 104.6,67.78 105.39,69.53 106.13,71.12 106.81,72.56 107.78,74.03 110.61,76.86 111.82,77.3 112.44,77.91 112.55,78.15 112.9,78.87 112.9,78.87 113.33,79.31 113.34,79.31 113.35,79.31 113.59,79.4 116.1,79.4 116.12,79.39 116.66,79.39 v2(117.32,79.08)
  BOTTOM w0.14: v2(88.9,32.08) 88.87,32.05 DM1.24 ; CPU1.AT54 v2(117.32,79.08)
M_A_DQ15: length 63.4
  TOP w0.14: v1(92.39,33.73) 92.08,33.43 v2(91.9,33.43)
  L4 w0.127: v2(91.9,33.43) 91.45,33.87 91.45,34.7 92.2,35.45 92.2,51.49 98.85,58.14 99.37,58.34 99.37,58.34 100.93,58.92 104.86,60.35 105.68,61.17 111.37,73.35 112.81,74.8 113.05,74.88 113.46,74.96 113.61,74.86 113.98,72.91 114.12,72.82 114.42,72.88 114.51,73.01 114.13,74.96 114.23,75.11 v2(114.92,75.24)
  BOTTOM w0.102: v2(91.9,33.43) 92.39,33.91 92.82,33.91 92.9,33.84 92.9,33.48 92.5,33.08 92.35,32.93 92.35,31.67 92.47,31.55 DM1.36
  BOTTOM w0.14: CPU1.AY59 v2(114.92,75.24)
M_A_DQ16: length 63.9
  TOP w0.14: v2(84.4,32.79) 84.49,32.79 v1(84.84,32.44)
  L3 w0.127: v2(116.26,75.73) 115.72,75.98 114.62,75.58 113.71,76 112.19,75.45 111.76,75.02 110.43,74.54 110.05,74.15 109.83,73.73 109.66,73.36 109.57,73.17 109.29,72.57 107.95,69.69 107.81,69.41 107.11,68.71 106.37,67.97 103.35,61.48 103.35,58.91 103.26,58.73 103.01,58.19 102.76,57.65 102.68,57.47 96.04,50.83 96.04,46.16 92.39,42.51 89.36,42.51 88.77,41.91 84.79,37.94 84.79,35.78 85.13,35.45 85.13,33.3 84.62,32.79 v2(84.4,32.79)
  BOTTOM w0.14: DM1.6 83.47,32.05 84.21,32.79 v2(84.4,32.79) ; CPU1.AY57 v2(116.26,75.73)
M_A_DQ17: length 66.1
  TOP w0.14: v2(86.41,37.22) v1(86.41,37.8)
  L3 w0.089: 114.98,73.75 115.21,73.83 115.25,73.91 116.29,74.29 v2(116.58,74.9)
  L3 w0.127: v2(86.41,37.22) 86.54,37.35 86.54,37.53 88.26,39.25 88.71,39.25 88.84,39.37 88.84,39.81 88.96,39.93 89.24,39.93 89.37,39.81 89.37,39.1 89.59,38.88 91.01,38.88 91.12,38.99 91.12,39.27 91,39.4 90.18,39.4 90.06,39.53 90.06,39.81 90.18,39.93 91.5,39.93 91.63,39.81 91.63,39.27 91.76,39.15 92.01,39.15 92.14,39.27 92.14,39.73 92.34,39.93 92.88,39.93 93,40.06 93,40.69 93.13,40.82 93.38,40.82 93.51,40.69 93.51,40.06 93.64,39.93 93.89,39.93 94.02,40.06 94.02,40.82 94.15,40.95 94.42,40.95 94.55,40.82 94.55,40.06 94.68,39.93 95.03,39.93 95.2,40.1 95.35,40.1 95.52,39.93 95.62,39.93 95.89,40.2 95.89,40.38 95.69,40.58 95.69,40.76 95.88,40.96 96.06,40.96 96.27,40.76 96.45,40.76 97.95,42.26 97.95,50.23 102.82,55.1 103.31,55.67 104.34,57.95 110.63,71.44 112.08,71.97 112.29,72.41 112.48,72.84 114.98,73.75
  BOTTOM w0.14: v2(86.41,37.22) 86.17,37.46 DM1.15 ; CPU1.BB57 v2(116.58,74.9)
M_A_DQ18: length 65.4
  TOP w0.14: v1(85.96,35.59) 86.29,35.92 v2(86.44,35.92)
  L3 w0.127: v2(86.44,35.92) 86.75,35.92 86.88,36.04 86.98,36.14 86.98,37.39 88.35,38.76 88.5,38.76 88.94,38.76 89.22,38.49 94.98,38.49 95.11,38.61 95.11,38.87 94.98,38.99 92.8,38.99 92.67,39.12 92.67,39.37 92.8,39.5 95.52,39.5 95.64,39.37 95.64,38.61 95.77,38.49 96.15,38.49 96.33,38.66 96.33,40.03 96.58,40.29 98.38,42.08 98.38,50.06 103.12,54.8 103.65,55.29 103.96,55.95 111.16,71.39 112.25,71.78 112.46,72.24 112.65,72.65 115.44,73.67 v2(115.57,73.61)
  BOTTOM w0.14: v2(86.44,35.92) 86.55,35.92 86.89,36.25 86.89,37.5 86.77,37.62 DM1.17 ; CPU1.BD59 v2(115.57,73.61)
M_A_DQ19: length 65.1
  TOP w0.14: v1(88.02,33.61) 87.74,33.89 v2(87.53,33.89)
  L3 w0.089: v2(116.13,72.85) 115.8,72.3 115.5,72.19 114.9,72.48
  L3 w0.127: v2(87.53,33.89) 87.69,33.89 88.61,34.8 88.61,37.57 88.76,37.72 89.98,37.72 90.11,37.6 90.11,35.61 90.23,35.49 90.51,35.49 90.64,35.61 90.64,37.6 90.77,37.72 96.77,37.72 97.29,38.25 97.29,38.32 97.29,39.75 99.31,41.77 99.31,49.68 104.22,54.59 104.64,55.49 111.78,70.79 111.78,70.79 112.47,71.04 113.05,72.3 114.3,72.75 114.9,72.48
  BOTTOM w0.102: v2(87.53,33.89) 87.53,33.85 87.36,33.68 87.36,33.68 87.11,33.43 87.11,33.43 86.47,32.79 86.47,31.69 DM1.16
  BOTTOM w0.14: CPU1.BF59 v2(116.13,72.85)
M_A_DQ20: length 69.6
  TOP w0.14: v2(117.28,77.11) v1(116.75,78.08)
  L3 w0.127: v2(117.28,77.11) 116.93,76.99 115.56,77.63 114.72,77.32 113.96,77.68 110.98,76.59 109.71,75.33 109.13,74.08 108.79,73.35 108.64,73.03 107.21,69.95 107.18,69.9 106.35,69.07 106.23,68.91 105.61,68.28 102.59,61.81 102.59,59.41 95.16,51.98 95.16,47.8 94.17,46.82 93.99,46.82 93.67,47.13 93.49,47.13 93.31,46.95 93.31,46.77 93.63,46.46 93.63,46.28 93.45,46.1 93.27,46.1 92.95,46.42 92.77,46.42 92.59,46.24 92.59,46.06 92.91,45.74 92.91,45.56 91.16,43.81 88.62,43.81 87.23,42.42 87.23,42.25 87.39,42.09 87.39,41.91 87.21,41.73 87.03,41.73 86.87,41.89 86.69,41.89 86.42,41.62 86.42,41.44 86.59,41.27 86.59,41.09 86.41,40.91 86.23,40.91 86.06,41.08 85.88,41.08 85.7,40.9 85.7,40.72 85.87,40.55 85.87,40.37 85.69,40.19 85.51,40.19 85.34,40.36 85.16,40.36 84.98,40.18 84.98,40 85.15,39.83 85.15,39.65 84.97,39.47 84.79,39.47 84.62,39.64 84.44,39.64 84.17,39.37 84.17,39.25 84.37,39.05 84.37,38.88 83.58,38.08 83.58,37.23 83.58,36.61 v2(84.27,35.92)
  BOTTOM w0.14: CPU1.AV54 v2(117.28,77.11) ; DM1.5 83.17,37.02 v2(84.27,35.92)
M_A_DQ21: length 68.2
  TOP w0.14: v2(84.27,37.19) v1(84.27,37.85)
  L3 w0.127: v2(116.93,75.97) 116.63,76.79 115.5,77.32 114.89,77.1 114.74,76.78 113.02,76.15 112.95,75.99 111.8,75.57 111.72,75.41 110.22,74.86 109.65,74.29 109.51,74 109.32,73.57 109.14,73.19 108.99,72.87 107.57,69.82 107.5,69.68 107.46,69.59 106.04,68.17 102.97,61.59 102.97,59 102.92,58.89 102.67,58.35 102.65,58.3 102.24,57.9 102.16,57.83 95.64,51.3 95.64,46.3 95.37,46.03 95.19,46.03 94.65,46.56 94.47,46.56 94.29,46.38 94.29,46.2 94.83,45.67 94.83,45.49 94.65,45.31 94.47,45.31 93.94,45.84 93.76,45.84 93.58,45.66 93.58,45.48 94.11,44.95 94.11,44.77 93.93,44.59 93.75,44.59 93.22,45.12 93.04,45.12 92.86,44.94 92.86,44.76 93.39,44.23 93.39,44.05 93.21,43.87 93.03,43.87 92.5,44.4 92.32,44.4 92.14,44.22 92.14,44.04 92.67,43.51 92.67,43.33 92.26,42.93 91.12,42.93 91,43.05 91,43.18 90.87,43.31 90.62,43.31 90.49,43.18 90.49,43.05 90.36,42.93 90.11,42.93 89.98,43.05 89.98,43.18 89.85,43.31 89.6,43.31 89.47,43.18 89.47,43.05 89.35,42.93 88.97,42.93 88.36,42.32 87.02,40.98 86.9,40.87 86.3,40.26 85.38,39.34 84.27,38.23 v2(84.27,37.19)
  BOTTOM w0.14: CPU1.AY55 v2(116.93,75.97) ; v2(84.27,37.19) 83.77,37.69 DM1.7
M_A_DQ22: length 69.4
  TOP w0.14: v1(84.84,33.99) 84.47,33.61 v2(84.4,33.61)
  L3 w0.127: v2(117.95,77.36) 116.31,78.23 114.66,77.63 113.99,77.94 110.34,76.61 108.47,74.75 107.75,73.19 107.48,72.6 105.97,69.37 105.81,69.02 105.18,68.39 102.21,62.02 102.21,59.59 94.7,52.08 94.7,48.89 91.89,46.08 91.89,45.9 92.01,45.78 92.01,45.6 91.83,45.42 91.66,45.42 91.53,45.54 91.35,45.54 91.17,45.36 91.17,45.18 91.34,45.01 91.34,44.83 91.16,44.65 90.98,44.65 90.81,44.82 90.63,44.82 90.01,44.2 88.46,44.2 83.2,38.94 83.2,37.39 83.2,36.63 83.2,36.23 83.63,35.8 83.63,33.73 83.75,33.61 v2(84.4,33.61)
  BOTTOM w0.102: v2(84.4,33.61) 82.87,32.08 82.87,31.69 DM1.4
  BOTTOM w0.14: CPU1.AV52 v2(117.95,77.36)
M_A_DQ23: length 65.6
  TOP w0.14: v1(88.04,32.29) 88.04,32.29 87.72,32.62 v2(87.55,32.62)
  L3 w0.089: v2(116.35,73.78) 116.17,73.4 115.32,73.09
  L3 w0.127: v2(87.55,32.62) 87.43,32.62 86.74,31.92 86.41,31.92 86.16,32.16 86.16,32.52 87.02,33.38 87.02,34.21 87.15,34.33 87.53,34.33 87.69,34.5 87.69,34.8 87.51,34.98 87.05,34.98 86.88,35.16 86.88,35.46 87.05,35.64 87.33,35.64 87.46,35.77 87.46,36.06 87.36,36.15 87.36,37.07 87.36,37.21 88.26,38.1 96.55,38.1 96.91,38.46 96.91,39.96 98.85,41.89 98.85,49.86 103.45,54.47 103.9,54.93 103.94,55 104.22,55.6 111.5,71.22 112.42,71.56 112.66,72.05 112.86,72.48 114.72,73.16 115.07,73 115.32,73.09
  BOTTOM w0.102: DM1.18 87.07,32.16 87.52,32.61 87.55,32.61 v2(87.55,32.62)
  BOTTOM w0.14: CPU1.BD58 v2(116.35,73.78)
M_A_DQ24: length 55.9
  L3 w0.089: v2(117.82,73.79) 117.52,73.14 117.06,72.98 116.6,71.98 115.3,71.51 115,71.65 114.01,71.29 113.73,70.68
  L3 w0.127: 113.73,70.68 113.87,70.28 111.26,64.68 110.75,64.5 107.13,56.75 106.91,56.67 106.7,56.23 106.76,56.06 107.02,55.94 107.07,55.79 106.89,55.4 106.74,55.34 106.51,55.45 106.31,55.38 105.64,53.95 101.49,49.78 101.03,49.32 101.03,41.57 99.46,40 99.46,39.83 99.64,39.65 99.82,39.65 100.99,40.81 101.17,40.81 101.33,40.64 101.33,40.44 100.61,39.72 100.61,39.54 101.02,39.13 101.01,38.98 100.8,38.77 100.66,38.77 100.25,39.18 100.07,39.18 99.8,38.91 99.61,38.91 99.05,39.47 98.92,39.47 98.69,39.24 98.69,39.11 98.79,39.01 98.79,38.66 98.63,38.5 98.63,38.29 98.84,38.08 99.02,38.08 99.34,38.39 99.52,38.39 99.7,38.21 99.7,38.03 99.26,37.59 99.2,37.53 99.2,37.27 99.11,37.17 v2(98.74,37.17)
  BOTTOM w0.14: 117.41,74.14 v2(117.82,73.79) ; DM1.57 98.77,37.2 v2(98.74,37.17)
M_A_DQ25: length 54.8
  L3 w0.089: 114.86,71.15 115.06,71.22 115.27,71.3 116.74,71.83 117.19,72.79 117.94,73.07 118.26,73.75 118.07,74.26 117.8,74.39 v2(117.74,74.55)
  L3 w0.127: v2(98.75,35.87) 98.85,35.77 99.28,35.77 99.58,36.07 99.58,37.37 99.64,37.43 99.91,37.69 100.5,38.28 100.85,38.28 101.65,39.08 101.65,39.34 101.31,39.68 101.31,39.86 101.71,40.26 101.71,41.26 101.59,41.39 101.54,41.39 101.41,41.52 101.41,41.8 101.54,41.92 101.59,41.92 101.71,42.05 101.71,49.34 101.78,49.4 105.89,53.56 106,53.79 106.24,54.34 106.48,54.85 106.65,54.91 106.9,54.79 107.07,54.85 107.67,56.15 107.52,56.58 107.66,56.89 107.83,56.95 107.91,56.91 108.08,56.97 108.19,57.2 108.13,57.37 108.04,57.41 107.98,57.58 108.36,58.39 108.53,58.45 108.62,58.41 108.79,58.47 108.89,58.7 108.83,58.87 108.75,58.91 108.68,59.08 108.79,59.31 108.96,59.37 109.05,59.33 109.21,59.4 109.32,59.63 109.26,59.79 109.17,59.83 109.11,60 109.22,60.23 109.39,60.3 109.48,60.26 109.64,60.32 109.75,60.55 109.69,60.72 109.6,60.76 109.54,60.92 109.65,61.15 109.82,61.22 109.9,61.18 110.07,61.24 110.18,61.47 110.12,61.64 110.03,61.68 109.97,61.84 110.08,62.08 110.25,62.14 110.33,62.1 110.5,62.16 110.61,62.39 110.55,62.56 110.46,62.6 110.4,62.77 110.51,63 110.68,63.06 110.76,63.02 110.93,63.08 111.04,63.31 110.98,63.48 110.89,63.52 110.83,63.69 110.98,64.01 111.47,64.19 114.35,70.37 114.53,70.43 114.86,71.15
  BOTTOM w0.14: v2(98.75,35.87) 99.21,35.87 99.37,36.03 DM1.59 ; 118.07,75.13 v2(117.74,74.55)
M_A_DQ26: length 54.5
  L3 w0.089: v2(117.02,73.61) 116.91,73.57 116.31,72.28 115.42,71.96 114.89,72.2
  L3 w0.127: 114.89,72.2 114.28,72.49 113.26,72.11 112.64,70.79 112.44,70.72 104.99,54.73 104.88,54.49 104.51,54.12 99.85,49.46 99.85,41.56 97.87,39.57 97.87,37.34 97.09,36.56 97.09,32.29 97.2,32.18 98.58,32.18 98.69,32.29 v2(98.69,32.54)
  BOTTOM w0.14: v2(98.69,32.54) 99.07,32.16 DM1.58 ; v2(117.02,73.61) CPU1.BF58
M_A_DQ27: length 54
  TOP w0.14: v2(102.7,32.5) v1(102.7,31.93)
  L3 w0.127: v2(120.41,75.62) 120.07,74.88 120.19,74.54 118.74,71.43 118.89,70.99 117.58,68.18 116.31,67.72 112.99,60.58 113.05,60.42 113.21,60.34 113.27,60.17 113.15,59.92 112.98,59.86 112.82,59.93 112.65,59.87 112.54,59.62 112.2,58.9 110.57,55.4 108.76,51.79 107.79,50.74 104.88,47.82 104.88,38.58 103.5,37.2 103.5,36.87 103.37,36.74 103.2,36.74 103.07,36.61 103.07,36.36 103.2,36.23 103.37,36.23 103.49,36.1 103.49,35.85 103.37,35.72 103.21,35.72 103.08,35.6 103.08,35.34 103.21,35.22 103.37,35.22 103.5,35.09 103.5,32.86 103.14,32.5 v2(102.7,32.5)
  BOTTOM w0.14: v2(102.7,32.5) 102.67,32.47 DM1.70 ; CPU1.BE50 v2(120.41,75.62)
M_A_DQ28: length 54.4
  TOP w0.14: v2(102.7,33.77) 102.84,33.77 v1(103.18,34.11)
  L3 w0.127: v2(102.7,33.77) 102.02,33.09 101.86,33.09 101.43,33.52 101.43,33.68 102.15,34.4 102.15,34.55 102.62,35.02 102.62,37.02 104.4,38.81 104.4,47.91 107.34,50.84 108.55,52.25 115.31,66.84 115.92,68.19 116.77,68.5 117.1,69.21 117.57,69.38 118.43,71.22 118.38,71.35 119.87,74.53 v2(119.58,75.3)
  BOTTOM w0.14: DM1.68 102.07,31.56 102.25,31.74 102.25,33.47 102.55,33.77 v2(102.7,33.77) ; CPU1.BD50 v2(119.58,75.3)
M_A_DQ29: length 54.6
  TOP w0.14: v2(102.15,37.09) v1(102.15,37.67)
  L3 w0.089: 117.17,71.05 117.32,71.1 117.66,71.84 118.48,72.13 119.51,74.34 119.13,75.39 v2(119.26,76.03)
  L3 w0.127: v2(102.15,37.09) 102.15,37.21 104.02,39.08 104.02,44.44 103.89,44.57 103.77,44.57 103.65,44.7 103.65,44.98 103.77,45.1 103.89,45.1 104.02,45.23 104.02,45.61 103.89,45.74 103.6,45.74 103.47,45.87 103.47,46.15 103.6,46.27 103.89,46.27 104.02,46.4 104.02,46.68 103.89,46.81 103.6,46.81 103.47,46.93 103.47,47.21 103.6,47.34 103.89,47.34 104.02,47.47 104.02,47.75 103.89,47.87 103.6,47.87 103.47,48 103.47,48.38 104.03,48.94 104.21,48.94 104.46,48.69 104.64,48.69 104.84,48.89 104.84,49.07 104.59,49.32 104.59,49.5 104.79,49.7 104.97,49.7 105.21,49.45 105.39,49.45 105.59,49.65 105.59,49.83 105.34,50.07 105.34,50.25 105.54,50.45 105.72,50.45 105.96,50.22 106.14,50.22 106.34,50.41 106.34,50.59 106.1,50.83 106.1,51.01 106.3,51.21 106.48,51.21 106.66,51.02 106.84,51.02 107.04,51.22 107.04,51.4 106.85,51.58 106.85,51.76 107.05,51.96 107.23,51.96 107.41,51.78 107.59,51.78 107.79,51.98 107.79,52.16 107.61,52.34 107.61,52.52 108.33,53.24 114.71,67.02 114.71,67.12 114.72,67.13 115.62,69.07 116.38,69.35 117.17,71.05
  BOTTOM w0.102: DM1.67 101.77,37.47 v2(102.15,37.09)
  BOTTOM w0.14: CPU1.BB50 v2(119.26,76.03)
M_A_DQ30: length 55.5
  TOP w0.14: v2(102.12,35.81) 102.34,35.81 v1(102.62,36.1)
  L3 w0.089: v2(119.02,76.7) 118.7,76.01 119.29,74.38 118.37,72.4 117.58,72.11 117.19,71.29 116.81,71.14 116.57,70.64
  L3 w0.127: 116.57,70.64 116.08,69.58 115.35,69.31 107.92,53.4 107.92,53.4 103.07,48.55 103.07,43.94 103.2,43.82 103.45,43.82 103.58,43.69 103.58,43.41 103.45,43.28 103.2,43.28 103.07,43.16 103.07,38.69 101.53,37.15 101.53,36.15 100.74,35.36 100.74,35.22 101.05,34.91 101.23,34.91 v2(102.12,35.81)
  BOTTOM w0.102: DM1.69 102.37,37.5 102.73,37.14 102.73,35.89 102.55,35.72 102.21,35.72 v2(102.12,35.81)
  BOTTOM w0.14: 119.37,77.12 v2(119.02,76.7)
M_A_DQ31: length 55.7
  L3 w0.089: v2(117.56,75.17) 117.26,74.54 117.37,74.26 117.28,74.08 117.46,73.6 117.31,73.28 116.93,73.14 116.46,72.13 115.37,71.74 115.07,71.88 113.84,71.44 113.44,70.58
  L3 w0.127: 113.44,70.58 113.48,70.47 111.06,65.27 110.38,65.02 105.38,54.32 105.32,54.27 101.24,50.17 100.57,49.5 100.57,41.73 98.25,39.4 98.25,36.4 97.67,35.81 97.55,35.69 97.55,33.33 97.69,33.19 98.12,33.19 98.25,33.31 98.25,33.45 98.61,33.81 v2(98.69,33.81)
  BOTTOM w0.102: DM1.56 98.47,31.91 98.25,32.13 98.25,33.37 v2(98.69,33.81)
  BOTTOM w0.14: CPU1.BB54 v2(117.56,75.17)
M_A_DQ32: length 56.3
  TOP w0.14: v2(122.87,37.26) v1(122.87,37.82)
  L3 w0.089: v2(123.65,82.04) 123.35,81.66 123.16,81.57 122.93,81.44 122.52,81.15 122.04,80.3 122.04,80.07 122.15,79.78 122.15,79.54 122.53,78.5 122.6,78.43 122.63,78.41 122.64,78.38 122.76,78.06 122.78,78 122.78,77.46 121.84,76.51
  L3 w0.127: v2(122.87,37.26) 122.19,37.26 122.03,37.41 122.03,39.23 122.16,39.35 122.9,39.35 123.03,39.48 123.03,39.76 122.9,39.89 122.16,39.89 122.03,40.01 122.03,40.29 122.16,40.42 122.66,40.42 122.82,40.58 122.82,40.8 122.66,40.95 122.16,40.95 122.03,41.08 122.03,41.36 122.16,41.49 122.48,41.49 122.64,41.64 122.64,41.86 122.48,42.02 122.16,42.02 122.03,42.15 122.03,50.25 122.95,52.22 122.89,52.39 122.8,52.43 122.74,52.6 122.86,52.85 123.03,52.92 123.12,52.87 123.29,52.94 123.41,53.19 123.34,53.36 123.17,53.44 123.11,53.61 123.23,53.86 123.4,53.92 123.57,53.84 123.74,53.9 124.11,54.71 124.11,56.39 120.85,65.35 120.85,65.54 121.17,66.21 121.17,67.38 120.64,68.81 119.95,70.73 119.95,71.64 119.78,72.1 119.78,72.55 120.28,73.62 121.09,74.44 121.38,75.05 121.38,76.19 121.64,76.45 121.79,76.51 121.84,76.51
  BOTTOM w0.102: v2(122.87,37.26) 122.77,37.36 122.77,38.72 DM1.129
  BOTTOM w0.14: CPU1.AR39 123.65,82.04 v2(123.65,82.04)
M_A_DQ33: length 55.8
  TOP w0.14: v2(126.98,35.8) 127.43,35.8 v1(127.54,35.92)
  L3 w0.089: 126.49,76.23 126.64,76.56 126.77,76.61 126.95,76.98 126.75,77.51 126.51,78.21 126.42,78.52 126.4,78.62 126.35,78.69 126.33,78.76 126.3,78.82 126.21,79.06 126.21,79.07 126.19,79.13 126.18,79.15 126.18,79.16 126.14,79.31 126.12,79.37 126.1,79.43 126.06,79.47 126.02,79.57 125.8,79.78 125.74,79.94 v2(124.12,80.7)
  L3 w0.127: v2(126.98,35.8) 126.57,35.8 126.42,35.95 126.42,37.94 126.33,38.03 126.33,49.23 127.33,51.37 128.29,53.44 124.12,64.92 123.57,66.43 123.46,66.71 123.46,66.77 123.84,67.58 123.84,67.59 122.66,70.84 122.78,71.08 122.44,72.03 122.14,72.86 122.49,73.61 122.5,73.62 122.52,73.66 125.23,74.64 125.27,74.69 125.49,75.14 125.53,75.19 126.06,75.38 126.11,75.42 126.49,76.23
  BOTTOM w0.14: DM1.143 126.97,38.05 127.51,37.51 127.51,36.19 127.12,35.8 v2(126.98,35.8) ; CPU1.AV37 v2(124.12,80.7)
M_A_DQ34: length 56.3
  TOP w0.14: v2(126.41,33.54) 126.64,33.54 v1(126.93,33.83)
  L3 w0.089: v2(124.34,80.05) 124.72,79.88 125.28,79.32 125.34,79.15 125.39,79 125.44,78.86 125.46,78.84 125.55,78.6 125.55,78.56 125.63,78.33 125.74,78.05 125.74,77.55 126.11,76.54 126.11,76.21 125.87,75.7 125.65,75.49 125.46,75.42 125.27,75.22 125.12,74.91
  L3 w0.127: v2(126.41,33.54) 126.32,33.54 125.96,33.9 125.96,34.42 126.38,34.84 126.38,35.42 126.04,35.76 126.04,37.73 125.95,37.82 125.95,49.34 127.86,53.44 123.24,66.15 123.24,66.9 123.51,67.48 123.51,67.84 122.42,70.84 122.42,71.4 122.25,71.85 121.92,72.75 121.92,72.77 121.89,72.87 122.3,73.74 122.31,73.76 122.35,73.84 122.42,73.86 122.42,73.87 125.03,74.82 125.12,74.91
  BOTTOM w0.14: CPU1.AW37 v2(124.34,80.05) ; v2(126.41,33.54) 126.27,33.54 125.95,33.22 125.95,31.77 126.07,31.66 DM1.140
M_A_DQ35: length 57.1
  TOP w0.14: v2(126.98,37.07) v1(126.98,37.63)
  L3 w0.089: 127.16,77.09 127.14,77.11 126.99,77.52 126.95,77.56 126.71,78.23 126.61,78.54 126.56,78.69 126.53,78.78 126.38,79.12 126.38,79.13 126.36,79.19 126.29,79.42 126.24,79.59 126.2,79.71 125.92,79.98 125.3,81.7 125.18,82.03 v2(124.58,82.31)
  L3 w0.127: 127.16,77.09 127.16,76.94 126.47,75.46 126.13,75.12 125.85,75.02 125.64,74.81 125.57,74.66 125.34,74.43 122.77,73.49 122.63,73.36 122.57,73.23 122.57,72.34 123.02,71.1 123.02,70.81 123.01,70.77 123.01,70.57 123.35,69.63 124.07,67.65 124.07,67.23 124.05,67.17 124.05,66.5 124.39,65.55 129.27,52.16 129.27,52.14 129.1,51.79 128.94,51.73 128.29,52.03 128.12,51.97 128.01,51.71 128.07,51.55 128.71,51.25 128.77,51.08 128.65,50.82 128.28,50.03 127.69,48.75 126.73,46.71 126.73,46.33 126.86,46.2 126.99,46.2 127.11,46.07 127.11,45.79 126.91,45.58 126.91,45.21 127.11,45.01 127.11,44.73 126.99,44.6 126.86,44.6 126.73,44.47 126.73,44.19 126.86,44.07 126.99,44.07 127.11,43.94 127.11,43.66 126.99,43.53 126.86,43.53 126.73,43.41 126.73,43.13 126.86,43 126.99,43 127.11,42.87 127.11,42.59 126.99,42.47 126.86,42.47 126.73,42.34 126.73,42.06 126.86,41.93 126.99,41.93 127.11,41.8 127.11,41.53 126.99,41.4 126.86,41.4 126.73,41.27 126.73,38.23 126.98,37.99 v2(126.98,37.07)
  BOTTOM w0.14: CPU1.AR37 v2(124.58,82.31) ; v2(126.98,37.07) 126.66,37.39 126.37,37.68 DM1.141
M_A_DQ36: length 56.4
  TOP w0.14: v1(122.44,32.59) 122.75,32.28 v2(122.98,32.28)
  L3 w0.089: v2(123.9,81.36) 123.33,80.13 123.26,80.05 123.18,79.88 123.18,79.71 123.34,79.26 123.34,79.19 123.48,78.8 123.48,77.76 123.38,77.65
  L3 w0.127: v2(122.98,32.28) 123.8,33.1 123.8,42.09 122.8,43.1 122.8,49.6 124.87,54.06 124.87,56.22 124.94,56.36 124.87,56.53 124.87,56.54 121.58,65.6 121.58,65.89 121.66,66.08 121.66,67.58 121.24,68.75 120.46,70.88 120.46,71.56 120.24,72.17 120.24,72.33 120.71,73.34 121.47,74.11 121.63,74.43 121.79,74.59 121.8,74.6 122.17,74.73 122.86,74.98 122.88,74.98 123.44,75.54 123.44,76.34 123.2,76.59 123.2,76.93 123.38,77.11 123.38,77.65
  BOTTOM w0.14: v2(122.98,32.28) 123.67,31.59 DM1.132 ; CPU1.AT37 v2(123.9,81.36)
M_A_DQ37: length 57.1
  TOP w0.14: v1(123.45,33.86) 123.14,33.55 v2(122.98,33.55)
  L3 w0.089: v2(123.06,81.01) 123.01,80.7 123.01,79.98 122.99,79.92 122.99,79.68 123.01,79.61 123.01,79.61 123.13,79.26 123.13,79.19 123.29,78.76 123.29,78.34 123.14,78.19
  L3 w0.127: 123.14,78.19 123.14,77.51 122.39,76.76 122.39,75.62 122.42,75.6 122.42,75.24 122.13,74.96 121.75,74.82 121.75,74.82 121.66,74.79 121.41,74.53 121.26,74.21 120.48,73.44 120.48,73.42 120.45,73.39 120.01,72.44 120.01,72.14 120.22,71.57 120.22,70.82 121.44,67.47 121.44,66.21 121.27,65.85 121.23,65.81 121.19,65.74 121.19,65.53 121.24,65.41 121.25,65.37 121.32,65.19 124.52,56.38 124.49,56.31 124.49,54.53 122.42,50.08 122.42,42.89 123.42,41.88 123.42,38.96 123.3,38.83 122.62,38.83 122.5,38.71 122.5,38.43 122.62,38.3 123.3,38.3 123.42,38.17 123.42,33.99 v2(122.98,33.55)
  BOTTOM w0.14: DM1.130 123.07,31.44 122.51,32 122.51,33.08 122.98,33.55 v2(122.98,33.55) ; CPU1.AT41 v2(123.06,81.01)
M_A_DQ38: length 55.8
  TOP w0.14: v2(122.9,35.95) 123.22,35.95 v1(123.5,36.22)
  L3 w0.089: v2(121.9,81.35) 121.9,80.57 121.85,80.46 121.85,79.96 121.89,79.83 121.89,79.69 122.37,78.39 122.48,78.27 122.59,77.96 122.59,77.8 122.53,77.66 122.03,77.16 122,77.09
  L3 w0.127: 122,77.09 121.89,77.05 121.14,76.3 121.14,75.11 120.98,74.75 120.18,73.96 119.55,72.6 119.55,71.99 119.68,71.64 119.68,70.78 120.28,69.12 120.93,67.33 120.93,66.34 120.49,65.4 120.49,65.22 123.73,56.33 123.73,55.97 123.18,54.79 121.65,51.51 121.65,46.43 121.53,46.31 121.06,46.31 120.93,46.18 120.93,45.9 121.06,45.77 121.53,45.77 121.65,45.65 121.65,45.37 121.53,45.24 121.2,45.24 121.07,45.11 121.07,44.83 121.2,44.71 121.53,44.71 121.65,44.58 121.65,44.3 121.53,44.17 121.27,44.17 121.14,44.05 121.14,43.77 121.27,43.64 121.53,43.64 121.65,43.51 121.65,37.19 v2(122.9,35.95)
  BOTTOM w0.127: 123.37,36.1 123.22,35.95 v2(122.9,35.95)
  BOTTOM w0.14: CPU1.AR41 v2(121.9,81.35) ; DM1.131 123.37,36.1
M_A_DQ39: length 58.2
  TOP w0.14: v2(126.4,32.27) v1(126.4,31.71)
  L3 w0.089: v2(124.63,79.4) 124.88,79.28 125.23,78.94 125.27,78.8 125.33,78.65 125.36,78.57 125.36,78.53 125.45,78.29 125.47,78.27 125.51,78.16 125.52,78.11 125.52,77.51 125.8,76.75 125.8,76.12 125.77,76.05 125.11,75.39 124.99,75.14 124.83,74.97 123.04,74.32 122.35,74.07 122.34,74.06 122.24,74.02 122.16,73.95 122.11,73.83 121.58,72.71
  L3 w0.127: 121.58,72.71 121.94,71.74 122.15,71.16 122.15,70.91 123.1,68.29 123.1,67.36 122.86,66.84 122.86,66 127.01,54.61 127.01,53.98 125.57,50.9 125.57,37.55 125.62,37.5 125.62,35.64 125.95,35.32 125.95,34.95 125.44,34.44 124.51,34.44 124.31,34.24 124.31,33.43 124.47,33.28 125.74,33.28 125.94,33.07 125.94,32.64 126.31,32.27 v2(126.4,32.27)
  BOTTOM w0.127: 126.65,32.03 v2(126.4,32.27)
  BOTTOM w0.14: v2(124.63,79.4) 125.11,79.63 CPU1.AW35 ; DM1.142 126.67,32.01 126.65,32.03
M_A_DQ40: length 50.6
  TOP w0.14: v2(128.22,37.22) v1(128.22,37.77)
  L3 w0.089: 124.19,68.98 124.19,68.99 124,69.08 123.72,69.85 123.46,70.64 v2(123.71,71.19)
  L3 w0.127: v2(128.22,37.22) 128.22,43.69 128.83,44.3 128.83,44.48 128.15,45.17 128.15,45.33 128.36,45.54 128.52,45.54 129.21,44.86 129.39,44.86 129.59,45.06 129.59,45.24 128.2,46.62 128.2,46.78 128.42,47 128.58,47 129.96,45.61 130.14,45.61 130.41,45.88 130.41,46.95 130.29,47.08 129.06,47.08 128.94,47.19 128.94,47.5 129.06,47.61 130.29,47.61 130.41,47.74 130.41,52 130.28,52.35 125.04,66.65 124.19,68.98
  BOTTOM w0.102: v2(123.71,71.19) 123.66,71.33 124.12,72.32 123.81,73.17 123.55,73.9 123.56,74.3 CPU1.BJ44
  BOTTOM w0.14: v2(128.22,37.22) 128.17,37.26 DM1.147
M_A_DQ41: length 51.3
  TOP w0.14: v2(132.81,33.91) v1(132.81,34.49)
  L3 w0.127: v2(132.81,33.91) 132.43,33.91 131.21,35.13 131.21,35.29 130.84,35.66 130.84,42.08 132.95,44.19 132.95,52.33 127.99,65.94 127.45,66.48 127.03,67.64 126.95,67.85 v2(125.94,68.86)
  BOTTOM w0.089: CPU1.BG39 125.33,76.22 125.43,75.92 125.3,75.64 125.29,75.59 125.3,75.46 125.37,75.28 125.49,75.22 125.6,74.93 125.56,74.6 125.57,74.58 125.56,74.57 125.68,74.23 125.72,74.21 125.81,73.98
  BOTTOM w0.102: 125.81,73.98 126.91,70.94 v2(125.94,68.86)
  BOTTOM w0.14: DM1.158 131.47,33.06 132.32,33.91 132.36,33.91 v2(132.81,33.91)
M_A_DQ42: length 50.4
  TOP w0.14: v2(131.66,37.26) v1(131.66,37.82)
  L3 w0.127: v2(125.51,70.18) 126.8,69.52 127.28,68.23 127.79,67.99 128.23,66.78 128.68,66.57 134.28,51.17 134.28,44.25 133.92,43.88 133.92,43.55 134.28,43.19 134.28,42.96 133.51,42.19 133.27,42.19 132.78,42.68 132.62,42.68 132.4,42.46 132.4,42.3 132.92,41.78 132.92,41.62 132.7,41.41 132.54,41.41 132,41.95 131.84,41.95 131.62,41.74 131.62,41.57 131.95,41.25 131.95,41.07 131.66,40.78 131.66,40.53 131.79,40.4 131.98,40.4 132.11,40.27 132.11,39.99 131.98,39.87 131.79,39.87 131.66,39.74 131.66,39.46 131.79,39.33 131.98,39.33 132.11,39.21 132.11,38.93 131.98,38.8 131.79,38.8 131.66,38.67 131.66,38.32 131.79,38.19 132.03,38.19 132.1,38.12 132.1,37.67 131.69,37.26 v2(131.66,37.26)
  BOTTOM w0.089: 125.02,75.71 125.12,75.41 125.04,75.24 124.97,75.03 125.14,74.59 125.16,74.44 125.34,73.94 125.36,73.94 125.59,73.31 125.6,73.31
  BOTTOM w0.102: v2(125.51,70.18) 126.2,71.66 125.6,73.31 ; DM1.157 131.17,37.15 131.24,37.07 131.48,37.07 v2(131.66,37.26)
M_A_DQ43: length 50.7
  TOP w0.14: v2(131.69,35.94) 131.81,35.94 v1(132.21,36.35)
  L3 w0.127: v2(131.69,35.94) 131.67,35.94 131.22,36.4 131.22,41.88 133.9,44.57 133.9,45.26 133.78,45.39 133.59,45.39 133.46,45.52 133.46,45.8 133.59,45.92 133.78,45.92 133.9,46.05 133.9,46.43 133.78,46.56 133.45,46.56 133.34,46.67 133.34,46.98 133.45,47.09 133.78,47.09 133.9,47.22 133.9,47.5 133.78,47.62 133.46,47.62 133.35,47.74 133.35,48.04 133.46,48.16 133.78,48.16 133.9,48.28 133.9,48.56 133.78,48.69 133.47,48.69 133.35,48.81 133.35,49.11 133.47,49.22 133.78,49.22 133.9,49.35 133.9,49.63 133.78,49.76 133.45,49.76 133.33,49.87 133.33,50.18 133.45,50.29 133.78,50.29 133.9,50.42 133.9,50.7 133.78,50.82 133.61,50.82 133.49,50.95 133.49,52.21 133.45,52.31 128.43,66.09 128.13,66.39 128.02,66.45 127.88,66.58 127.5,67.63 127.07,68.06 126.87,68.62 126.2,69.28 v2(125.74,69.5)
  BOTTOM w0.102: v2(125.74,69.5) 126.56,71.26 125.54,74.08 125.5,74.1 125.37,74.44 125.35,74.58 125.35,74.59 125.3,74.94 CPU1.BJ40 ; DM1.159 131.77,37.87 131.77,37.79 132.09,37.47 132.09,36.35 v2(131.69,35.94)
M_A_DQ44: length 50.5
  TOP w0.14: v2(129.07,34.17) v1(129.07,34.73)
  L3 w0.089: 124.53,69.24 124.64,69.47 124.68,69.56 124.64,69.68 124.53,69.97 v2(123.91,70.59)
  L3 w0.127: v2(129.07,34.17) 129.07,35.76 128.66,36.17 128.66,42.82 129.18,43.33 129.18,43.51 128.98,43.71 128.98,43.88 129.2,44.09 129.36,44.09 129.56,43.89 129.74,43.89 129.94,44.09 129.94,44.27 129.8,44.41 129.8,44.57 130.01,44.78 130.17,44.78 130.31,44.64 130.49,44.64 130.82,44.97 130.82,51.97 130.83,51.97 130.88,52.07 125.43,67.03 125.2,67.14 124.48,69.12 124.53,69.24
  BOTTOM w0.089: 124.05,73.11 123.86,73.64 123.8,74.06 123.85,74.29 123.75,74.59 123.67,74.62 123.62,74.66 123.53,74.9 123.61,75.06 CPU1.BG43
  BOTTOM w0.102: v2(123.91,70.59) 124.27,71.36 124.12,71.77 124.36,72.27 124.05,73.11
  BOTTOM w0.14: v2(129.07,34.17) 127.87,32.97 DM1.146
M_A_DQ45: length 52.1
  TOP w0.14: v2(129.1,32.79) 128.81,32.79 v1(128.53,33.07)
  L3 w0.089: 123.99,68.59 123.94,68.64 123.59,69.62 123.25,70.55 123.25,71.45 v2(123.45,71.88)
  L3 w0.127: 123.99,68.59 124.34,67.6 124.34,67.26 129.8,52.27 129.8,52.27 129.8,51.82 129.39,50.94 129.45,50.77 129.86,50.57 129.92,50.41 129.81,50.15 129.64,50.09 129.22,50.28 129.05,50.22 128.94,49.97 129,49.8 129.57,49.53 129.63,49.38 129.5,49.1 129.35,49.05 128.77,49.32 128.6,49.25 128.49,49 128.55,48.83 129.18,48.54 129.23,48.39 129.11,48.11 128.95,48.05 128.32,48.35 128.15,48.29 127.76,47.44 127.76,34.13 v2(129.1,32.79)
  BOTTOM w0.089: CPU1.BG44 123.27,74.87 123.27,74.66 123.25,74.47 123.24,74.28 123.24,74.16 123.43,73.63 123.44,73.63 123.84,72.53 123.55,71.92 v2(123.45,71.88)
  BOTTOM w0.14: DM1.148 128.47,32.17 v2(129.1,32.79)
M_A_DQ46: length 50
  TOP w0.14: v2(129.48,36.45) 129.73,36.45 v1(129.98,36.71)
  L3 w0.089: v2(123.2,72.52) 123.93,72.19 124.31,71.13 124.91,69.5 124.95,69.39 124.82,69.12 125.14,68.26
  L3 w0.127: v2(129.48,36.45) 129.05,36.87 129.05,37.78 129.18,37.9 129.19,37.9 129.32,38.03 129.32,38.31 129.19,38.44 129.18,38.44 129.05,38.56 129.05,38.84 129.18,38.97 129.19,38.97 129.32,39.1 129.32,39.38 129.19,39.5 129.18,39.5 129.05,39.63 129.05,40.01 129.18,40.14 129.29,40.14 129.42,40.27 129.42,40.55 129.29,40.67 129.18,40.67 129.05,40.8 129.05,41.08 129.18,41.21 129.29,41.21 129.42,41.33 129.42,41.61 129.29,41.74 129.18,41.74 129.05,41.87 129.05,42.22 129.63,42.8 129.63,43.21 129.77,43.34 130.18,43.34 130.39,43.55 130.39,43.95 130.54,44.09 131.03,44.09 131.2,44.27 131.2,48.3 131.33,48.43 131.54,48.43 131.67,48.56 131.67,48.83 131.54,48.96 131.33,48.96 131.2,49.09 131.2,49.37 131.33,49.5 131.54,49.5 131.67,49.62 131.67,49.9 131.54,50.03 131.33,50.03 131.2,50.16 131.2,50.44 131.33,50.56 131.54,50.56 131.67,50.69 131.67,50.97 131.54,51.1 131.33,51.1 131.2,51.22 131.2,51.6 131.38,51.78 131.38,52.25 126.68,65.16 126.56,65.16 125.68,67.59 125.32,67.75 125.14,68.26
  BOTTOM w0.089: CPU1.BH45 123.01,74.38 123.03,74.17 123.28,73.49 123.29,73.49 123.46,73 123.25,72.54 v2(123.2,72.52)
  BOTTOM w0.127: v2(129.48,36.45) 129.48,35.95 129.3,35.77 128.9,35.77 128.77,35.89
  BOTTOM w0.14: DM1.149 128.77,35.89
M_A_DQ47: length 52.3
  TOP w0.14: v1(133.36,32.31) 133.03,32.64 v2(132.75,32.64)
  L3 w0.127: v2(125.29,70.79) 126.36,70.32 127.25,69.42 127.52,68.69 128.21,67.99 128.5,67.19 128.72,66.97 128.9,66.89 129.02,66.77 134.66,51.26 134.66,42.8 132.49,40.62 132.49,34.87 132.98,34.37 133.54,33.81 133.97,33.38 134.29,33.38 134.41,33.27 134.41,32.76 134.29,32.64 v2(132.75,32.64)
  BOTTOM w0.089: 125.35,73.37 124.95,74.46 124.93,74.6 124.78,75.02 CPU1.BH41
  BOTTOM w0.102: v2(125.29,70.79) 125.32,70.8 125.86,71.96 125.35,73.37
  BOTTOM w0.14: DM1.160 132.07,32.15 132.56,32.64 v2(132.75,32.64)
M_A_DQ48: length 54.3
  TOP w0.14: v1(137.17,32.44) 136.79,32.06 v2(136.74,32.06)
  L4 w0.089: v2(126.71,79.43) 126.72,79.42 126.74,79.42 127.01,79.35 128.05,78.31 128.16,77.99 128.21,77.86
  L4 w0.127: v2(136.74,32.06) 136.74,32.16 137.7,33.12 137.7,34.16 138.36,34.82 138.58,34.82 138.94,35.18 138.94,51.46 138.35,53.09 133.53,66.31 133.53,67.31 132.93,69.1 132.1,71.39 130.32,73.17 128.85,77.22 128.21,77.86
  BOTTOM w0.14: DM1.176 136.87,31.93 v2(136.74,32.06) ; CPU1.BA34 v2(126.71,79.43)
M_A_DQ49: length 52.7
  TOP w0.14: v1(137.42,35.51) 137.12,35.82 v2(136.95,35.82)
  L4 w0.127: v2(127.48,77.37) 128.92,73.43 131.19,71.16 132.08,68.69 132.64,67.31 132.64,66.18 137.39,53.13 138.18,50.98 138.18,44.05 138.05,43.92 137.61,43.92 137.49,43.8 137.49,43.54 137.61,43.42 138.05,43.42 138.18,43.29 138.18,43.03 138.05,42.91 137.45,42.91 137.33,42.78 137.33,42.53 137.45,42.4 138.05,42.4 138.18,42.27 138.18,42.02 138.05,41.89 137.45,41.89 137.33,41.76 137.33,41.51 137.45,41.38 138.05,41.38 138.18,41.26 138.18,40.88 137.39,40.09 137.39,36.26 136.95,35.82 v2(136.95,35.82)
  BOTTOM w0.127: v2(136.95,35.82) 136.45,36.32 136.45,37.58 136.57,37.7
  BOTTOM w0.14: DM1.175 136.57,37.7 ; CPU1.BE34 v2(127.48,77.37)
M_A_DQ50: length 54.9
  TOP w0.14: v2(136.95,37.09) v1(136.95,37.67)
  L4 w0.127: v2(127.2,78.06) 127.06,77.78 127.06,77.29 129.03,71.9 131.33,69.59 131.79,68.34 132.05,67.62 132.05,66.59 135.23,57.84 136.96,53.11 136.96,53.1 136.99,53.02 137.8,50.79 137.8,50.25 137.67,50.12 137,50.12 136.87,50 136.87,49.74 137,49.62 137.67,49.62 137.8,49.49 137.8,49.24 137.67,49.11 137,49.11 136.87,48.98 136.87,48.73 137,48.6 137.67,48.6 137.8,48.47 137.8,48.09 137.67,47.97 137.02,47.97 136.89,47.84 136.89,47.58 137.02,47.46 137.67,47.46 137.8,47.33 137.8,47.08 137.67,46.95 137.02,46.95 136.89,46.82 136.89,46.57 137.02,46.44 137.67,46.44 137.8,46.31 137.8,46.06 137.67,45.93 137.02,45.93 136.89,45.81 136.89,45.55 137.02,45.43 137.67,45.43 137.8,45.3 137.8,44.92 136.95,44.07 136.95,39.71 136.82,39.58 136.73,39.58 136.61,39.45 136.61,39.2 136.73,39.07 136.82,39.07 136.95,38.94 136.95,38.56 136.82,38.44 136.79,38.44 136.66,38.31 136.66,38.06 136.79,37.93 136.82,37.93 136.95,37.8 v2(136.95,37.09)
  BOTTOM w0.102: v2(136.95,37.09) 137.17,37.31 DM1.177
  BOTTOM w0.14: CPU1.BD34 v2(127.2,78.06)
M_A_DQ51: length 54
  TOP w0.14: v2(135.19,33.48) v1(135.19,34.06)
  L4 w0.089: 125.77,74.15 125.76,74.19 125.62,74.32 125.59,74.43 125.59,76.22 125.11,77.54 v2(125.11,78.06)
  L4 w0.127: 125.77,74.15 126.94,70.95 127.76,70.13 128.04,69.34 129.41,67.98 129.43,67.98 129.89,67.52 129.9,67.49 134.14,55.85 134.14,52.33 133.86,52.05 133.86,51.67 133.99,51.54 134.16,51.54 134.29,51.41 134.29,51.13 134.16,51.01 133.99,51.01 133.86,50.88 133.86,50.6 133.99,50.47 134.16,50.47 134.29,50.35 134.29,50.07 134.16,49.94 133.99,49.94 133.86,49.81 133.86,38.26 134.3,37.82 134.3,34.37 v2(135.19,33.48)
  BOTTOM w0.14: DM1.164 133.27,32.24 134.52,33.48 v2(135.19,33.48) ; CPU1.BD37 v2(125.11,78.06)
M_A_DQ52: length 54.7
  TOP w0.14: v2(135.14,32.74) 135.29,32.74 v1(135.62,32.41)
  L4 w0.089: v2(124.88,78.7) 125.18,78.56 125.6,78.13 125.67,77.96
  L4 w0.127: 125.67,77.96 125.57,77.75 125.57,77.2 125.54,77.13 125.57,77.04 126.6,74.22 126.68,74.13 127.74,71.23 127.74,71 128.29,69.49 128.67,69.1 129.3,68.81 130.13,67.98 134.67,55.5 134.67,48.35 134.8,48.23 134.94,48.23 135.07,48.1 135.07,47.82 134.94,47.69 134.8,47.69 134.67,47.57 134.67,46.94 134.8,46.81 134.97,46.81 135.1,46.68 135.1,46.41 134.97,46.28 134.8,46.28 134.67,46.15 134.67,44.34 134.24,42.62 134.24,38.42 134.87,37.79 134.87,34.46 135.64,33.7 135.64,33.24 v2(135.14,32.74)
  BOTTOM w0.14: CPU1.BB37 v2(124.88,78.7) ; DM1.166 133.87,31.93 134.69,32.74 v2(135.14,32.74)
M_A_DQ53: length 53.9
  TOP w0.14: v2(133.12,37.2) v1(133.12,37.76)
  L4 w0.089: 126.63,70.38 125.46,73.6 125.41,73.73 125.41,73.76 125.38,73.83 125.32,73.89 125.24,74.11 125.24,74.16 124.89,75.12 124.68,75.7 124.7,75.75 124.67,75.85 124.48,76.37 124.48,76.98 v2(124.54,77.11)
  L4 w0.127: v2(133.12,37.2) 132.61,37.2 132.42,37.39 132.42,42.38 132.54,42.51 132.97,42.51 133.1,42.64 133.1,42.92 132.97,43.04 132.54,43.04 132.42,43.17 132.42,43.45 132.54,43.58 132.97,43.58 133.1,43.7 133.1,43.98 132.97,44.11 132.54,44.11 132.42,44.24 132.42,44.52 132.54,44.64 132.97,44.64 133.1,44.77 133.1,45.05 132.97,45.18 132.54,45.18 132.42,45.3 132.42,45.58 132.54,45.71 132.97,45.71 133.1,45.84 133.1,46.12 132.97,46.24 132.54,46.24 132.42,46.37 132.42,46.65 132.54,46.78 132.97,46.78 133.1,46.9 133.1,47.18 132.97,47.31 132.54,47.31 132.42,47.44 132.42,47.72 132.54,47.84 132.97,47.84 133.1,47.97 133.1,48.25 132.97,48.38 132.54,48.38 132.42,48.5 132.42,48.78 132.54,48.91 132.97,48.91 133.1,49.04 133.1,49.32 132.97,49.44 132.54,49.44 132.42,49.57 132.42,49.85 132.54,49.98 132.97,49.98 133.1,50.1 133.1,50.38 132.97,50.51 132.54,50.51 132.42,50.64 132.42,51.02 133.28,55.05 133.28,55.73 130.34,63.83 129.11,67.2 128.83,67.48 128.72,67.77 127.58,68.91 127.29,69.71 126.63,70.38
  BOTTOM w0.14: DM1.163 132.97,37.93 133.04,37.87 133.04,37.77 133.12,37.68 v2(133.12,37.2) ; CPU1.BE39 v2(124.54,77.11)
M_A_DQ54: length 55
  TOP w0.14: v1(133.76,36.22) 133.46,35.92 v2(133.13,35.92)
  L4 w0.089: v2(124.16,77.76) 124.67,77.56 125.03,77.19 125.21,76.69 125.22,76.67 125.28,76.51 125.28,74.67 125.47,74.13
  L4 w0.127: v2(133.13,35.92) 132.69,35.48 132.69,35.1 132.95,34.84 133.32,34.84 133.58,35.1 133.58,37.86 133.48,37.96 133.48,38.49 133.35,38.61 133.02,38.61 132.89,38.74 132.89,39.02 133.02,39.15 133.35,39.15 133.48,39.27 133.48,39.55 133.35,39.68 132.97,39.68 132.85,39.81 132.85,40.09 132.97,40.21 133.35,40.21 133.48,40.34 133.48,40.62 133.35,40.75 132.92,40.75 132.8,40.87 132.8,41.15 132.92,41.28 133.35,41.28 133.48,41.41 133.48,53.44 133.66,54.27 133.66,56.03 129.56,67.31 127.88,68.99 127.77,69.28 127.59,69.78 127.5,70.03 126.76,70.77 125.6,73.96 125.5,74.06 125.47,74.13
  BOTTOM w0.14: DM1.165 133.57,37.62 133.67,37.52 133.67,36.2 133.39,35.92 v2(133.13,35.92) ; CPU1.BD39 v2(124.16,77.76)
M_A_DQ55: length 55.4
  TOP w0.14: v1(137.12,33.66) 136.84,33.38 v2(136.62,33.38)
  L4 w0.089: 128.12,77.31 127.89,77.93 127.16,78.66 v2(126.96,78.75)
  L4 w0.127: 128.12,77.31 128.12,76.76 129.23,73.72 131.71,71.24 132.56,68.89 132.74,68.39 132.98,67.7 133.06,67.47 133.06,66.39 137.77,53.45 138.56,51.29 138.56,40.25 138.43,40.12 138.08,40.12 137.95,39.99 137.95,39.74 138.08,39.61 138.43,39.61 138.56,39.49 138.56,39.23 138.43,39.11 137.9,39.11 137.77,38.98 137.77,38.72 137.9,38.6 138.43,38.6 138.56,38.47 138.56,38.09 137.77,37.3 137.77,35.38 137.43,35.04 137.32,34.93 137.32,34.07 136.82,33.57 136.81,33.57 v2(136.62,33.38)
  BOTTOM w0.14: CPU1.BB34 v2(126.96,78.75) ; v2(136.62,33.38) 136.22,32.97 136.22,31.67 136.27,31.62 DM1.174
M_A_DQ56: length 52.4
  TOP w0.14: v2(138.39,37.26) v1(138.39,37.82)
  L3 w0.127: v2(138.39,37.26) 138.02,37.63 133.35,37.63 133.24,37.74 133.24,39.13 133.35,39.25 134.53,39.25 134.66,39.37 134.66,39.65 134.53,39.78 133.18,39.78 133.07,39.89 133.07,40.2 133.18,40.31 134.53,40.31 134.66,40.44 134.66,40.72 134.53,40.85 134.15,40.85 134.02,40.97 134.02,41.35 135.2,42.53 135.2,51.36 129.45,67.16 128.89,67.72 128.73,68.16 128.71,68.18 128.67,68.29 128.52,68.43 128.47,68.46 127.58,69.35 127.33,70.03 126.6,70.76 126.17,71.95 126.17,73.47 v2(126.34,73.84)
  BOTTOM w0.089: v2(126.34,73.84) 126.53,74.24 126.23,75.06 CPU1.BJ38
  BOTTOM w0.14: v2(138.39,37.26) 138.37,37.28 DM1.181
M_A_DQ57: length 52.3
  TOP w0.14: v2(141.75,33.46) 141.54,33.46 v1(141.26,33.17)
  L3 w0.127: v2(141.75,33.46) 142.14,33.85 142.57,34.99 142.57,39.19 140.48,41.28 140.48,48.83 133.84,67.07 132.98,69.44 131.62,70.8 v2(128.43,72.29)
  BOTTOM w0.089: CPU1.BG34 127.62,76.17 127.59,75.99 127.7,75.69 127.72,75.68 127.72,75.67 127.94,75.57 128.34,74.48 128.34,74.47 128.43,74.24 v2(128.43,72.29)
  BOTTOM w0.102: DM1.194 142.27,32.94 v2(141.75,33.46)
M_A_DQ58: length 51.7
  TOP w0.14: v2(141.75,37.01) v1(141.75,37.59)
  L3 w0.127: v2(141.75,37.01) 141.75,38.91 138.82,41.85 138.82,46.07 138.94,46.19 139.26,46.19 139.38,46.31 139.38,46.61 139.26,46.73 138.94,46.73 138.82,46.85 138.82,47.13 138.94,47.26 139.52,47.26 139.64,47.37 139.64,47.68 139.52,47.79 138.94,47.79 138.82,47.92 138.82,48.2 138.94,48.33 139.53,48.33 139.65,48.44 139.65,48.75 139.53,48.86 138.94,48.86 138.82,48.99 138.82,49.27 138.94,49.39 139.12,49.39 139.24,49.51 139.24,49.81 139.12,49.93 138.94,49.93 138.82,50.05 138.82,51.02 132.99,67.04 132.36,68.77 131.48,69.65 129.13,70.74 v2(128.94,70.74)
  BOTTOM w0.089: 128.81,74.36 128.69,74.69 128.31,75.73 128.15,76.17 128.01,76.23 127.96,76.29 127.9,76.4 127.9,76.54 127.92,76.65 127.94,76.85 CPU1.BG33
  BOTTOM w0.102: 128.81,74.36 129.6,72.18 v2(128.94,70.74) ; v2(141.75,37.01) 141.37,37.39 DM1.191
M_A_DQ59: length 51.5
  TOP w0.14: v2(141.81,32.17) 141.7,32.17 v1(141.36,31.83)
  L3 w0.127: v2(129.23,70.09) 129.56,70.09 131.31,69.28 131.85,68.74 131.93,68.5 132.5,66.94 138.32,50.95 138.32,40.95 141.07,38.2 141.07,32.87 141.77,32.17 v2(141.81,32.17)
  BOTTOM w0.089: CPU1.BH33 128.38,76.2 128.46,75.87 128.96,74.51 129.14,74.43 129.16,74.37
  BOTTOM w0.102: v2(129.23,70.09) 130.06,71.89 129.16,74.37
  BOTTOM w0.14: v2(141.81,32.17) 141.67,32.03 DM1.192
M_A_DQ60: length 51.4
  TOP w0.14: v2(138.23,32.01) 138.37,32.01 v1(138.69,32.34)
  L3 w0.102: 127.85,71.06 127.85,71.16 127.43,72.32 v2(126.58,73.17)
  L3 w0.127: 127.85,71.06 128.4,69.56 128.65,69.31 129.47,68.93 130.49,67.91 130.52,67.84 136.59,51.14 136.59,40.85 139.6,37.85 139.6,35.11 139.01,34.52 139.01,34.4 139.01,32.79 139.01,32.16 138.86,32.01 v2(138.23,32.01)
  BOTTOM w0.089: 126.82,73.67 126.89,73.82 126.43,75.07 126.49,75.19 126.41,75.39 126.35,75.55 126.12,75.66 CPU1.BG38
  BOTTOM w0.102: v2(126.58,73.17) 126.82,73.67
  BOTTOM w0.14: v2(138.23,32.01) 138.07,31.85 DM1.180
M_A_DQ61: length 53.4
  TOP w0.14: v1(138.95,36.27) 138.64,35.97 v2(138.47,35.97)
  L3 w0.127: v2(138.47,35.97) 138.84,36.34 138.84,37.44 137.95,38.33 137.77,38.33 137.47,38.03 137.31,38.03 137.1,38.25 137.1,38.41 137.4,38.71 137.4,38.88 137.2,39.08 137.02,39.08 136.24,38.31 136.08,38.31 135.87,38.52 135.87,38.69 136.64,39.46 136.64,39.64 136.44,39.84 136.26,39.84 135.45,39.02 135.28,39.02 135.07,39.23 135.07,39.4 135.89,40.21 135.89,40.39 135.58,40.7 135.58,51.44 129.74,67.47 129.19,68.02 129.08,68.33 128.91,68.51 128.6,68.65 127.88,69.36 127.52,70.37 126.9,70.99 126.9,71.46 v2(127.07,71.84)
  BOTTOM w0.089: CPU1.BH37 126.51,75.69 126.51,75.69 126.59,75.46 126.69,75.18 126.64,75.07 126.66,75.03 127.13,73.74
  BOTTOM w0.102: 127.13,73.74 127.49,72.74 v2(127.07,71.84)
  BOTTOM w0.14: DM1.183 138.97,36.47 v2(138.47,35.97)
M_A_DQ62: length 52.3
  TOP w0.14: v2(138.24,33.38) 138.31,33.38 v1(138.69,33.76)
  L3 w0.127: v2(138.24,33.38) 137.89,33.38 137.74,33.53 137.74,34.53 137.92,34.71 138.47,34.71 139.22,35.46 139.22,37.67 138.16,38.72 136.15,40.74 136.15,51.07 130.08,67.74 129.49,68.33 129.44,68.48 129.24,68.67 128.73,68.91 128.13,69.51 127.65,70.83 v2(127.31,71.17)
  BOTTOM w0.089: CPU1.BG37 126.47,76.17 126.7,76.03 126.77,75.83 126.72,75.66 126.77,75.52 126.92,75.12 126.87,75.02 126.92,74.9 127,74.67 127.08,74.64 127.35,73.9
  BOTTOM w0.102: v2(127.31,71.17) 127.89,72.4 127.35,73.9
  BOTTOM w0.14: v2(138.24,33.38) 138.43,33.2 138.69,32.93 138.69,31.83 138.67,31.81 DM1.182
M_A_DQ63: length 54.2
  TOP w0.14: v1(141.23,36.02) 141.51,35.74 v2(141.75,35.74)
  L3 w0.127: v2(141.75,35.74) 142.19,36.19 142.19,39.03 140.09,41.13 140.09,41.87 139.97,41.99 139.46,41.99 139.34,42.12 139.34,42.4 139.46,42.53 139.97,42.53 140.09,42.65 140.09,42.93 139.97,43.06 139.46,43.06 139.34,43.19 139.34,43.47 139.46,43.59 139.97,43.59 140.09,43.72 140.09,44 139.97,44.13 139.46,44.13 139.34,44.25 139.34,44.53 139.46,44.66 139.97,44.66 140.09,44.79 140.09,45.07 139.97,45.19 139.46,45.19 139.34,45.32 139.34,45.6 139.46,45.73 139.97,45.73 140.09,45.85 140.09,48.65 133.4,67.03 132.69,69.01 132.59,69.29 131.69,70.19 v2(128.71,71.58)
  BOTTOM w0.089: 129.21,72.66 128.49,74.65 128.49,74.65
  BOTTOM w0.102: 128.49,74.65 128.05,75.86 CPU1.BJ34 ; v2(128.71,71.58) 129.21,72.66
  BOTTOM w0.14: DM1.193 141.97,37.43 142.29,37.11 142.29,36.04 142,35.74 v2(141.75,35.74)
M_A_DQS_DN0: length 57.5
  TOP w0.127: v1(95.33,36.86) 95.1,36.62 v2(94.78,36.62)
  L4 w0.114: v2(111.64,67.91) 111.86,67.69 111.86,67.34 111.83,67.27 111.13,65.77 110.18,65.43 107.3,59.25 106.99,58.59 104.44,57.67 104.43,57.66 102.74,57.02 101.75,56.64 101,56.35 100.93,56.31 100.75,56.14 99.59,54.98 96.16,51.54 96.16,45 96.6,44.55 96.79,44.55 96.79,44.56 96.88,44.56 96.99,44.44 96.99,43.92 96.88,43.81 95.9,43.81 95.71,43.62 95.71,42.79 95.9,42.6 96.91,42.6 97,42.5 97,41.95 96.91,41.85 95.98,41.85 95.73,41.6 95.73,40.89 95.98,40.64 96.88,40.64 97,40.53 97,40.01 96.88,39.89 96.41,39.89 96.16,39.65 96.16,39.02 95.31,38.17 95.31,37.07 94.86,36.62 v2(94.78,36.62)
  BOTTOM w0.102: v2(111.64,67.91) 111.33,68.75 111.23,69.08 111.23,70.12 111.54,70.78 112.92,73.75 112.99,73.9 113.07,73.92 113.11,73.94 113.18,73.96 113.18,73.96 113.28,74 113.4,74.27 113.5,74.47 113.64,74.53 113.78,74.57 114.24,74.39 114.31,74.21 CPU1.BC62
  BOTTOM w0.127: v2(94.78,36.62) 95.06,36.34 95.38,36.34 95.53,36.49 95.53,37.48 95.17,37.84 DM1.45
M_A_DQS_DN1: length 64.3
  TOP w0.127: v2(89.12,36.53) 89.34,36.53 v1(89.64,36.83)
  L4 w0.114: v2(89.12,36.53) 89.26,36.39 89.58,36.39 89.68,36.49 89.68,38.77 89.68,41.2 89.68,41.2 89.68,42.31 89.56,42.43 89.24,42.44 88.99,42.68 88.99,43.16 89.24,43.41 89.54,43.41 89.66,43.53 89.66,43.82 89.54,43.93 89.24,43.93 88.99,44.18 88.99,44.66 89.24,44.91 89.54,44.91 89.66,45.03 89.66,45.32 89.54,45.43 89.24,45.43 88.99,45.68 88.99,46.16 89.24,46.41 89.54,46.41 89.66,46.52 89.66,46.82 89.54,46.93 89.24,46.93 88.99,47.18 88.99,47.66 89.24,47.91 89.54,47.91 89.66,48.02 89.66,48.54 89.54,48.66 89.45,48.66 89.2,48.91 89.2,49.39 89.45,49.64 89.54,49.64 89.66,49.75 89.66,53.06 95.7,59.1 95.73,59.16 97.22,59.67 98.6,60.15 98.77,60.22 100.6,61.44 100.78,61.59 101.14,61.94 106,66.77 106.15,67.08 106.72,68.23 108.48,72 108.57,72.2 108.6,72.25 108.6,72.26 108.62,72.3 109.13,73.39 109.23,73.62 109.29,73.73 109.3,73.75 109.57,74.12 109.89,74.57 110.15,74.84 110.33,75.03 111.12,75.32 111.66,75.52 111.72,75.65 112.08,75.78 112.44,75.92 113.43,78.04 113.46,78.11 114.14,78.47 114.42,78.57 114.45,78.58 114.72,78.58 115.08,78.41 v2(115.28,78.41)
  BOTTOM w0.127: CPU1.AT58 v2(115.28,78.41) ; v2(89.12,36.53) 89.34,36.31 90.27,36.31 90.44,36.47 90.44,36.77 89.95,37.26 89.95,37.49 89.77,37.66 DM1.27
M_A_DQS_DN2: length 66.2
  TOP w0.127: v1(86.19,33.89) 85.83,33.53 v2(85.71,33.53)
  L3 w0.114: v2(115.94,74.6) 115.83,74.56 115.45,74.74 115.45,74.74 115.14,74.88 114.61,74.69 114.61,74.69 114.3,74.69 113.78,75.21 112.96,75.21 112.27,74.96 112.15,74.7 111.59,74.5 110.86,73.77 110.84,73.73 103.74,58.51 103.49,57.97 103.24,57.43 103.02,56.96 102.97,56.86 96.69,50.58 96.69,43.46 94.99,41.76 92.42,41.76 92.16,41.5 92.16,40.8 92.05,40.69 91.35,40.69 91.17,40.87 91.17,41.71 90.91,41.98 90.31,41.98 90.05,41.72 90.05,40.93 89.97,40.84 88.53,40.84 85.71,38.03 85.71,34.97 86.27,34.41 86.27,34.09 v2(85.71,33.53)
  BOTTOM w0.127: v2(85.71,33.53) 85.64,33.46 85.12,33.46 84.85,33.19 84.85,31.75 84.67,31.57 DM1.10 ; CPU1.BB58 v2(115.94,74.6)
M_A_DQS_DN3: length 55.5
  TOP w0.127: v1(100.9,32.84) 100.9,32.89 v2(100.37,33.42)
  L3 w0.089: v2(118.16,76.3) 117.93,76.08 117.93,75.51 117.99,75.46 117.99,75.04 118,75.01 118.03,74.93 118.16,74.55 118.19,74.48 118.19,74.48 118.2,74.46 118.23,74.44
  L3 w0.114: 118.23,74.44 118.49,73.74 118.22,73.17 118.15,73 118.07,72.84 118.05,72.83 117.69,72.7 117.31,72.56 116.87,71.63 115.75,71.23 115.75,71.23 115.33,71.07 115.31,71.07 107.21,53.76 103.45,50 102.32,48.86 102.32,39 101.55,38.23 100.78,37.46 100.78,36.5 99.48,35.2 99.48,34 99.6,33.88 99.87,33.61 100.18,33.61 v2(100.37,33.42)
  BOTTOM w0.127: CPU1.BB52 v2(118.16,76.3) ; DM1.62 100.27,31.57 100.45,31.75 100.45,31.98 100.94,32.47 100.94,33.28 100.81,33.42 v2(100.37,33.42)
M_A_DQS_DN4: length 59.3
  TOP w0.127: v2(125.13,35.6) 125.39,35.6 v1(125.69,35.31)
  L3 w0.089: v2(123.79,79.12) 123.98,79.18 124.09,79.13 124.1,79.1 124.62,77.67 124.65,77.6 125.04,77.42 125.22,76.92 125.4,76.43 125.24,76.08 125.03,76 124.86,75.94 124.83,75.87
  L3 w0.114: v2(125.13,35.6) 125.1,35.6 124.43,36.26 124.43,37.58 124.51,37.65 124.51,42.93 124.39,43.05 124.12,43.05 123.86,43.31 123.86,43.76 124.12,44.02 124.39,44.02 124.51,44.14 124.51,44.43 124.39,44.54 123.97,44.54 123.72,44.79 123.72,45.27 123.97,45.52 124.39,45.52 124.51,45.64 124.51,45.93 124.39,46.04 123.97,46.04 123.72,46.29 123.72,46.77 123.97,47.02 124.39,47.02 124.51,47.13 124.51,47.43 124.39,47.54 124.04,47.54 123.76,47.83 123.76,48.23 124.04,48.52 124.39,48.52 124.51,48.63 124.51,48.93 124.39,49.04 123.97,49.04 123.72,49.29 123.72,49.77 123.97,50.02 124.39,50.02 124.51,50.13 124.51,50.65 125.37,52.51 126.23,54.36 126.12,54.68 121.96,66.09 122.26,66.72 122.08,67.22 121.89,67.72 121.89,67.72 121.47,68.9 121.51,69 121.14,70.03 120.7,71.24 120.76,71.39 120.46,72.21 120.46,72.28 120.9,73.22 120.94,73.26 121.1,73.32 121.13,73.33 121.45,73.45 121.88,74.37 122.49,74.59 123.08,74.8 123.46,74.94 123.83,75.08 124.59,75.35 124.83,75.87
  BOTTOM w0.127: v2(125.13,35.6) 124.84,35.89 124.55,35.89 124.23,36.2 124.23,37.28 124.57,37.61 DM1.135 ; CPU1.AW39 v2(123.79,79.12)
M_A_DQS_DN5: length 52.5
  TOP w0.127: v2(130.85,33.32) 131.01,33.32 v1(131.33,33.63)
  L3 w0.089: v2(125.07,71.39) 124.95,71.12 124.91,71.05 124.82,70.85 125.37,69.34 125.37,69.34 125.45,69.12 125.42,69.06 125.48,68.9
  L3 w0.114: v2(130.85,33.32) 130.45,33.32 130.01,33.32 129.88,33.44 129.88,34.19 130.01,34.32 130.32,34.32 130.57,34.57 130.57,35.11 130.32,35.36 130.06,35.36 129.93,35.49 129.93,35.83 130.18,36.08 130.18,42.17 132.42,44.41 132.42,45.12 132.18,45.37 132.07,45.37 131.96,45.48 131.96,45.78 132.07,45.89 132.18,45.89 132.42,46.14 132.42,46.62 132.18,46.87 132.07,46.87 131.96,46.98 131.96,47.27 132.07,47.39 132.18,47.39 132.42,47.64 132.42,52.13 127.51,65.62 127.14,65.79 126.35,67.94 126.11,68.06 125.72,68.24 125.48,68.89 125.48,68.9
  BOTTOM w0.089: CPU1.BG42 124.32,75.18 124.49,74.97 124.61,74.91 124.62,74.9 124.7,74.67 124.71,74.44
  BOTTOM w0.102: 124.71,74.44 124.83,74.12 124.88,73.97 125.08,73.41 125.14,73.27 125.14,73.27 125.34,72.73 125.42,72.5 125.45,72.43 125.26,71.94 v2(125.07,71.39)
  BOTTOM w0.127: v2(130.85,33.32) 130.82,33.29 130.09,33.29 129.67,32.87 DM1.152
M_A_DQS_DN6: length 55.2
  TOP w0.127: v2(135.4,35.89) 135.57,35.89 v1(135.87,35.59)
  L4 w0.114: v2(126.28,77.65) 126.16,77.39 126.02,77.11 126.99,74.47 127.27,74.18 127.57,73.35 127.83,72.65 128.1,71.9 128.38,71.12 128.38,70.66 128.55,70.2 128.71,69.76 130,69.16 130.01,69.15 130.07,69.13 130.61,68.87 136.03,53.98 136.04,53.96 136.08,53.8 136.08,44.43 135.76,44.11 135.76,43.78 136.08,43.46 136.08,42.75 135.83,42.5 135.11,42.5 135,42.39 135,42.09 135.11,41.98 135.99,41.98 136.25,41.72 136.25,41.26 135.99,41 135.11,41 135,40.89 135,40.59 135.11,40.48 135.83,40.48 136.08,40.23 136.08,39.75 135.83,39.5 135.11,39.5 135,39.39 135,39.1 135.11,38.98 135.83,38.98 136.08,38.73 136.08,36.56 135.41,35.89 v2(135.4,35.89)
  BOTTOM w0.127: v2(126.28,77.65) CPU1.BD35 ; DM1.169 134.77,37.79 134.69,37.71 134.69,36.31 134.9,36.1 135.19,36.1 v2(135.4,35.89)
M_A_DQS_DN7: length 53.6
  TOP w0.127: v2(139.54,32.9) 139.73,32.9 v1(140.04,32.59)
  L3 w0.114: v2(139.54,32.9) 139.54,33.03 139.54,33.08 139.67,33.21 140.13,33.21 140.54,33.63 140.54,37.97 137.51,41 137.51,43.16 137.79,43.44 137.79,44 137.51,44.29 137.51,44.81 137.79,45.08 137.79,45.62 137.51,45.9 137.51,46.42 137.79,46.7 137.79,47.26 137.51,47.54 137.51,47.92 137.79,48.2 137.79,48.76 137.51,49.04 137.51,49.42 137.79,49.7 137.79,50.26 137.51,50.54 137.51,51.06 137.5,51.07 136.88,52.8 134.29,59.9 134.26,59.98 134.26,59.98 131.06,68.78 128.81,69.83 127.56,73.25 127.69,73.54 v2(127.94,73.63)
  BOTTOM w0.089: CPU1.BH35 127.33,76.15 127.38,76 127.39,75.98 127.39,75.97 127.55,75.54 127.55,75.54 127.56,75.53 127.6,75.51 127.78,75.42 127.94,75.01 128.08,74.62 128.1,74.55 128.13,74.48 128.13,74.02 v2(127.94,73.63)
  BOTTOM w0.127: v2(139.54,32.9) 139.73,33.09 139.96,33.09 140.23,32.82 140.23,31.67 139.87,31.32 DM1.186
M_A_DQS_DP0: length 57.4
  TOP w0.127: v1(95.23,35.49) 94.9,35.82 v2(94.78,35.82)
  L4 w0.114: v2(94.78,35.82) 94.78,35.95 95.23,36.4 95.23,36.68 95.54,36.98 95.54,38.08 96.39,38.93 96.39,39.55 96.5,39.67 96.98,39.67 97.23,39.91 97.23,40.62 96.98,40.87 96.07,40.87 95.96,40.99 95.96,41.51 96.07,41.62 97,41.62 97.23,41.85 97.23,42.6 97,42.83 95.99,42.83 95.94,42.88 95.94,43.52 95.99,43.58 96.97,43.58 97.22,43.83 97.22,44.54 96.97,44.78 96.7,44.78 96.39,45.09 96.39,51.45 100.91,55.97 101.08,56.14 101.08,56.14 101.83,56.42 102.82,56.8 104.43,57.42 104.51,57.45 104.52,57.45 107.16,58.41 107.51,59.15 110.35,65.24 111.05,65.5 111.3,65.59 112.04,67.17 112.09,67.28 112.09,68.1 111.94,68.25 v2(111.94,68.53)
  BOTTOM w0.102: v2(111.94,68.53) 111.52,68.8 111.52,68.82 111.43,69.11 111.43,70.08 111.72,70.7 113.14,73.73 113.17,73.74 113.43,73.84 113.6,73.9 CPU1.BB63
  BOTTOM w0.127: v2(94.78,35.82) 95.07,36.1 95.48,36.1 95.77,36.39 95.77,38.72 DM1.47
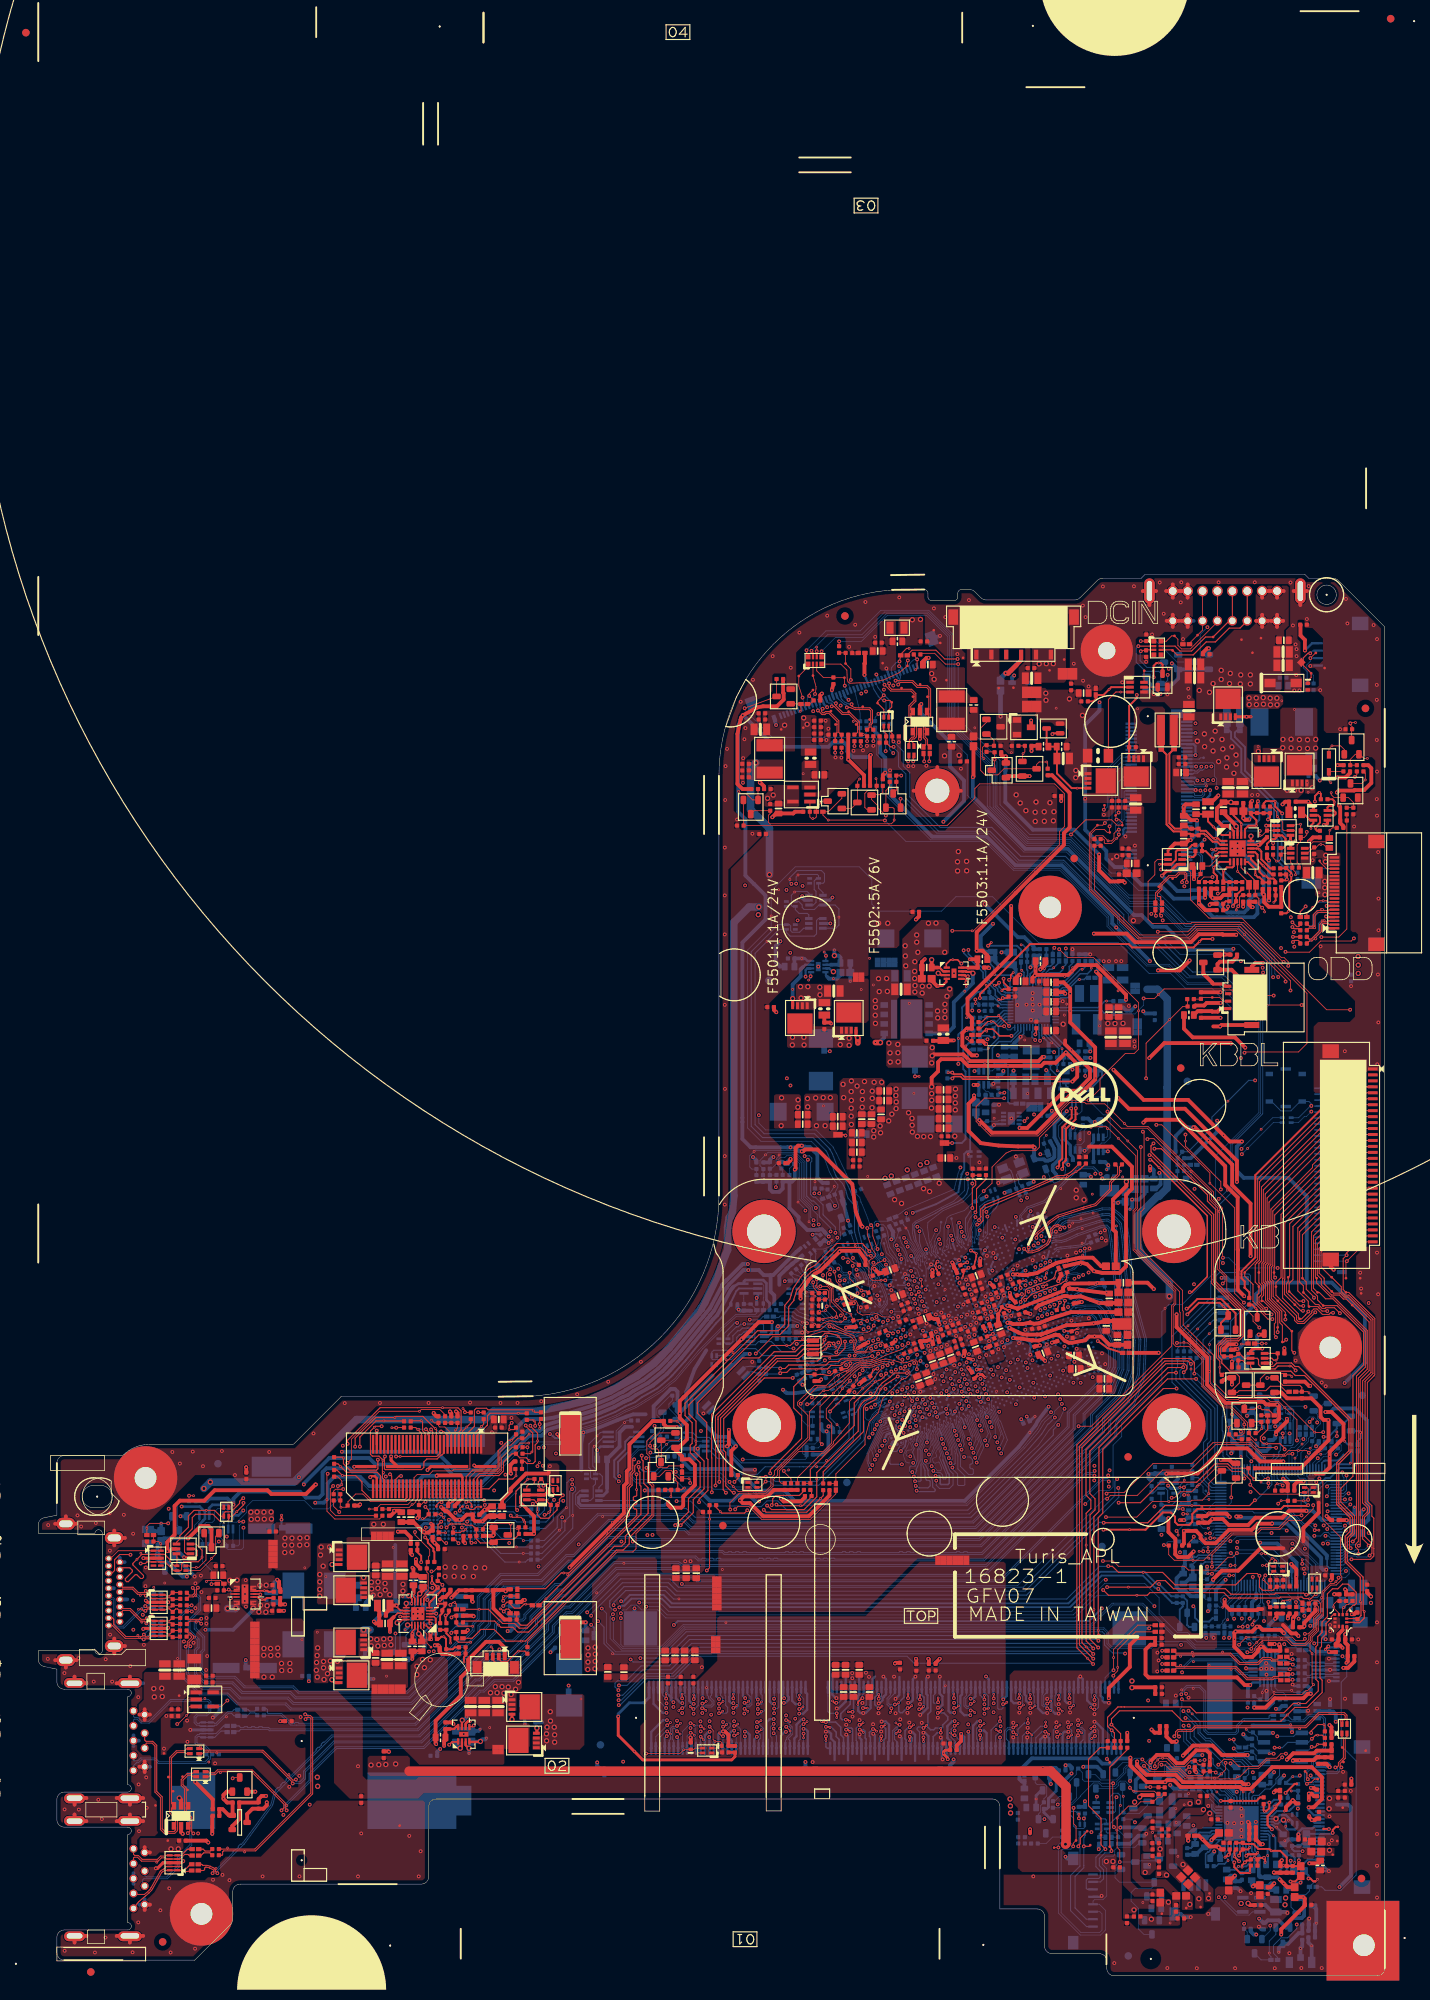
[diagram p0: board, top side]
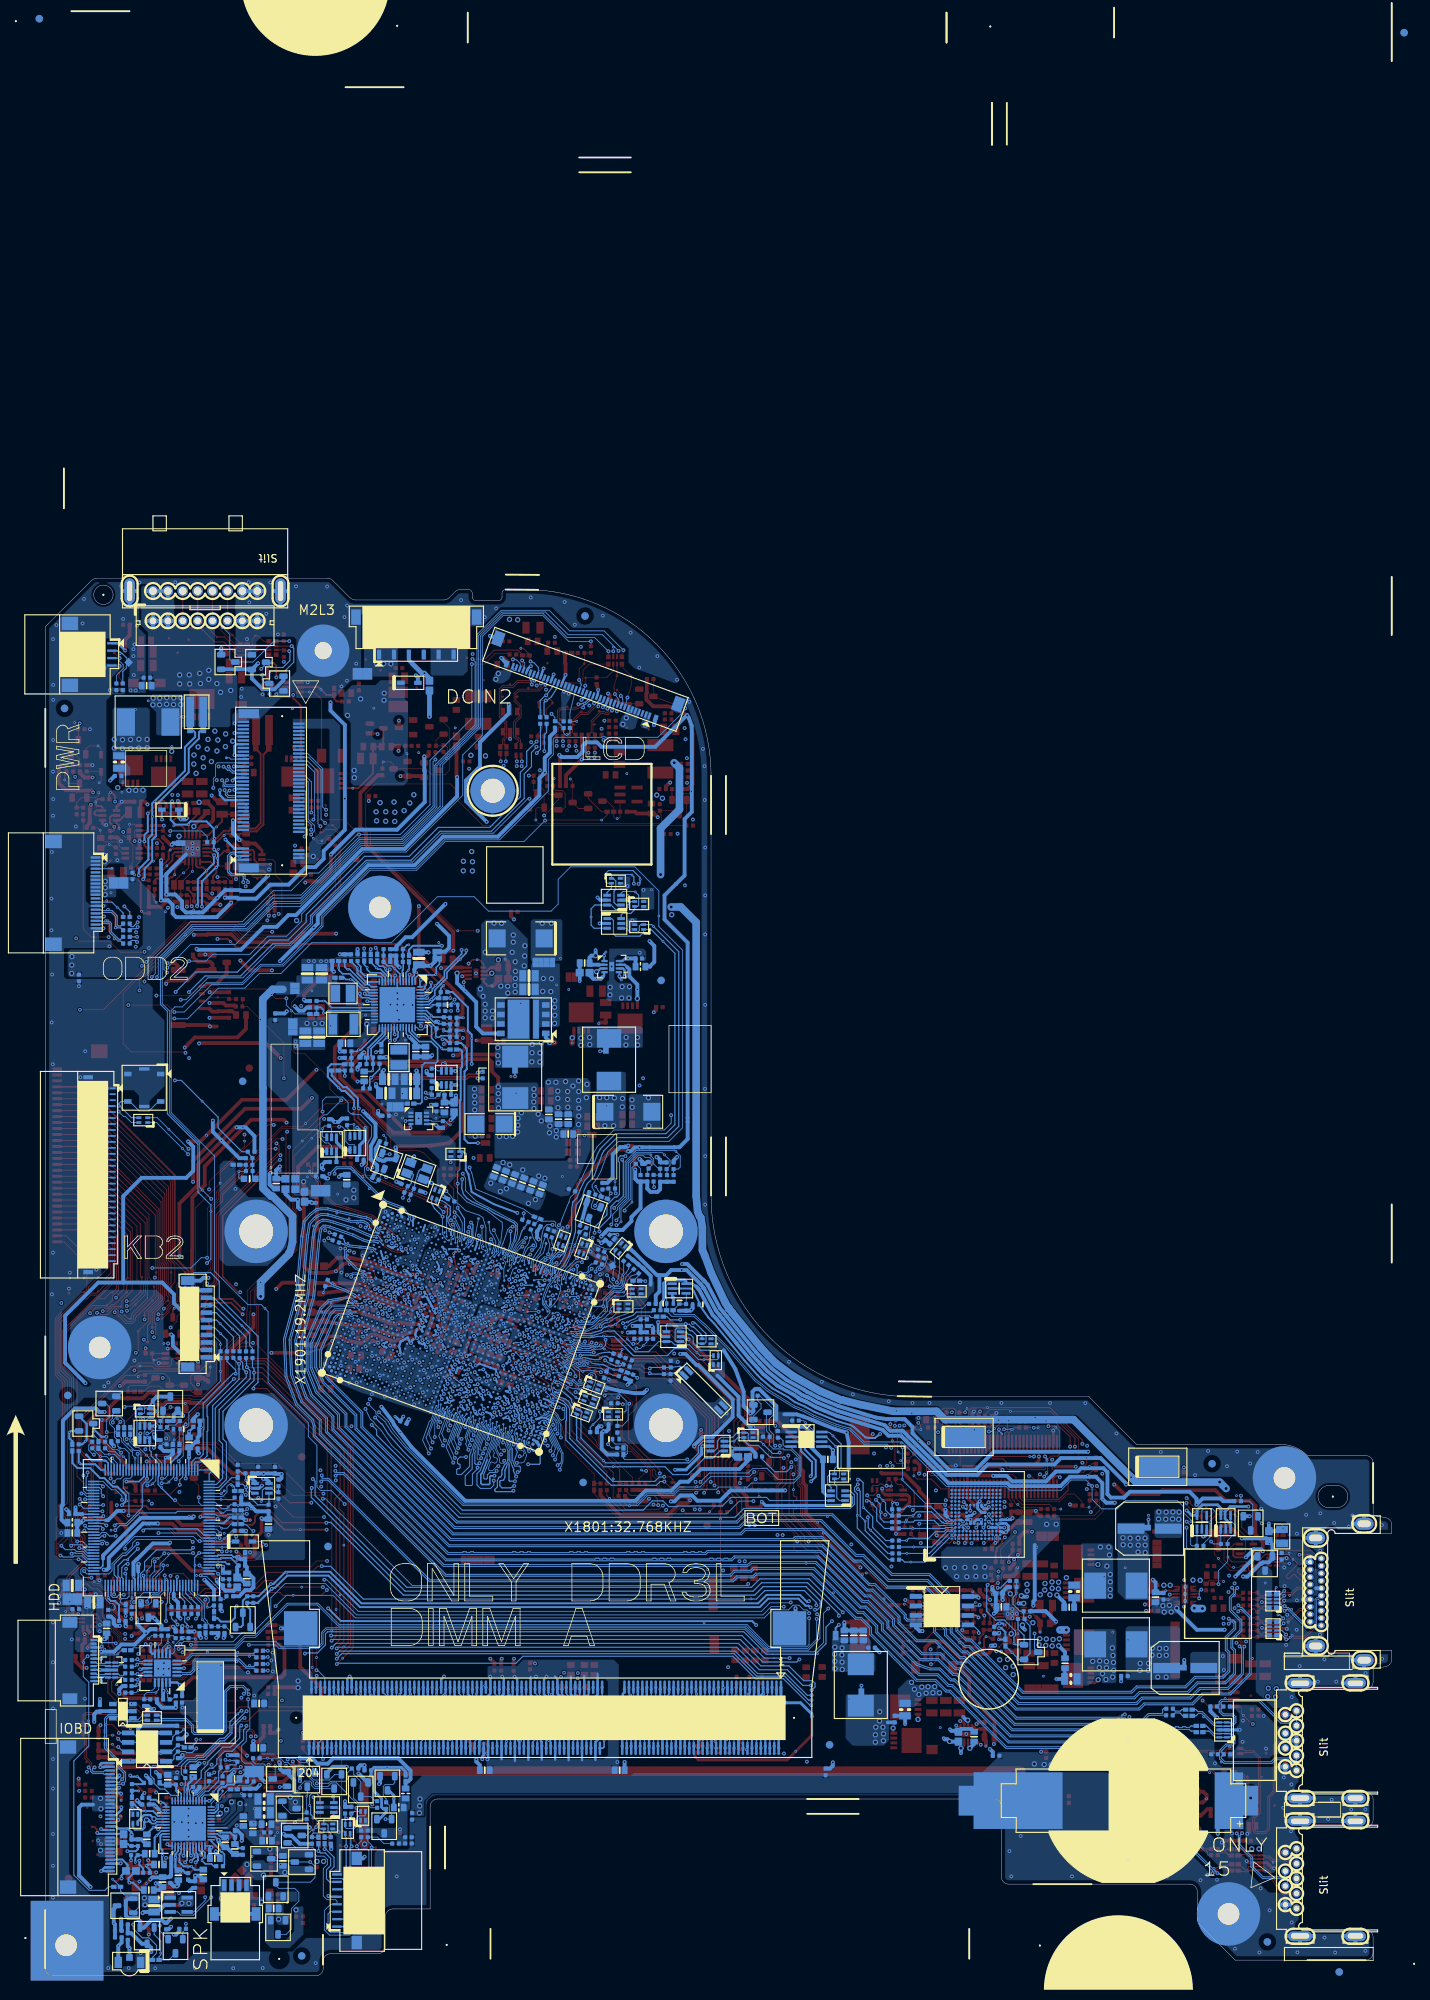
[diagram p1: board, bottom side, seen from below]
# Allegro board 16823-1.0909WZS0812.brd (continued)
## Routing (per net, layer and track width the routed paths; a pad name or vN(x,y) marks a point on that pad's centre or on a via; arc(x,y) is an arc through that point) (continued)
M_A_DQS_DP1: length 64.2
  TOP w0.127: v1(89.59,35.61) 89.31,35.89 v2(89.09,35.89)
  L4 w0.114: v2(114.62,78.17) 114.59,78.24 114.41,78.32 114.23,78.26 113.64,77.94 112.61,75.73 112.19,75.58 111.89,75.47 111.85,75.38 111.85,75.38 111.82,75.33 111.2,75.1 110.46,74.84 110.07,74.42 109.49,73.62 108.83,72.2 108.83,72.2 108.79,72.11 108.69,71.9 107.84,70.09 106.93,68.13 106.36,66.97 106.26,66.77 106.19,66.63 101.69,62.18 101.3,61.78 100.93,61.42 100.74,61.26 99.94,60.72 98.87,60.01 98.68,59.94 95.89,58.97 95.87,58.92 95.83,58.9 89.89,52.96 89.89,49.66 89.64,49.41 89.55,49.41 89.43,49.29 89.43,49 89.55,48.89 89.64,48.89 89.89,48.64 89.89,47.93 89.64,47.68 89.33,47.68 89.22,47.57 89.22,47.27 89.33,47.16 89.64,47.16 89.89,46.91 89.89,46.43 89.64,46.18 89.33,46.18 89.22,46.07 89.22,45.78 89.33,45.66 89.64,45.66 89.89,45.41 89.89,44.93 89.64,44.68 89.33,44.68 89.22,44.57 89.22,44.28 89.33,44.16 89.64,44.16 89.89,43.91 89.89,43.43 89.64,43.18 89.33,43.18 89.22,43.07 89.22,42.78 89.33,42.66 89.65,42.66 89.79,42.53 89.79,42.53 89.91,42.41 89.91,41.15 89.91,38.87 89.91,36.4 89.67,36.16 89.36,36.16 v2(89.09,35.89)
  BOTTOM w0.127: DM1.29 90.37,37.66 90.19,37.49 90.19,37.36 90.68,36.87 90.68,36.37 90.37,36.07 89.27,36.07 v2(89.09,35.89) ; v2(114.62,78.17) 114.62,77.77 CPU1.AT59
M_A_DQS_DP2: length 66
  TOP w0.127: v1(86.14,32.44) 85.76,32.82 v2(85.71,32.82)
  L3 w0.114: v2(115.27,74.36) 115.32,74.45 115.27,74.57 115.13,74.63 114.69,74.47 114.68,74.47 114.64,74.46 114.21,74.46 113.69,74.98 113,74.98 112.44,74.78 112.32,74.52 111.71,74.3 111.05,73.64 103.95,58.41 103.45,57.33 103.23,56.86 103.19,56.79 103.16,56.72 96.92,50.48 96.92,43.37 95.09,41.53 92.51,41.53 92.39,41.41 92.39,40.71 92.14,40.47 91.26,40.47 90.94,40.78 90.94,41.62 90.82,41.75 90.41,41.75 90.28,41.62 90.28,40.84 90.06,40.62 88.62,40.62 85.94,37.94 85.94,35.06 86.5,34.51 86.5,33.99 86.16,33.65 86.16,33.34 85.71,32.93 v2(85.71,32.82)
  BOTTOM w0.127: CPU1.BB59 115.5,74.84 115.5,74.45 115.41,74.36 v2(115.27,74.36) ; v2(85.71,32.82) 85.43,33.17 85.41,33.2 85.39,33.2 85.38,33.22 85.22,33.22 85.09,33.09 85.09,31.75 85.27,31.57 DM1.12
M_A_DQS_DP3: length 55.4
  TOP w0.127: v1(100.87,34.06) 100.63,34.31 v2(100.36,34.31)
  L3 w0.089: v2(118.34,75.67) 118.18,75.51 118.18,75.07 118.21,74.99 118.22,74.96 118.34,74.62 118.42,74.58 118.43,74.54 118.44,74.54 118.45,74.52
  L3 w0.114: 118.45,74.52 118.74,73.73 118.43,73.07 118.24,72.66 117.77,72.49 117.62,72.43 117.47,72.38 117.04,71.45 115.98,71.07 115.98,71.07 115.48,70.88 107.4,53.63 105.49,51.72 103.62,49.83 102.55,48.76 102.55,38.91 101.01,37.37 101.01,36.41 99.71,35.11 99.71,34.09 99.97,33.83 100.23,33.83 100.36,33.97 100.36,34.15 v2(100.36,34.31)
  BOTTOM w0.127: v2(100.36,34.31) 100.36,34.2 101.18,33.38 101.18,32.37 100.69,31.88 100.69,31.75 100.87,31.57 DM1.64 ; CPU1.BD52 v2(118.34,75.67)
M_A_DQS_DP4: length 59.2
  TOP w0.127: v2(125.13,36.47) 125.28,36.47 v1(125.61,36.81)
  L3 w0.089: 125.03,75.77 125.05,75.81 125.11,75.83 125.38,75.93 125.61,76.42 125.19,77.56 124.8,77.74 124.54,78.44 124.28,79.17 124.28,79.17 124.27,79.2 124.2,79.4 123.62,79.67 v2(123.58,79.79)
  L3 w0.114: 125.03,75.77 124.77,75.2 124.73,75.16 123.91,74.86 123.53,74.73 123.16,74.59 122.57,74.38 122.05,74.19 121.62,73.26 121.21,73.12 121.08,73.07 120.7,72.24 121.01,71.38 120.94,71.23 121.76,68.99 121.71,68.89 122.11,67.8 122.5,66.71 122.21,66.08 126.33,54.75 126.48,54.35 125.58,52.41 124.73,50.6 124.73,50.04 124.49,49.79 124.07,49.79 123.95,49.67 123.95,49.38 124.07,49.27 124.49,49.27 124.73,49.02 124.73,48.54 124.49,48.29 124.14,48.29 123.98,48.14 123.98,47.92 124.14,47.77 124.49,47.77 124.73,47.52 124.73,47.04 124.49,46.79 124.07,46.79 123.95,46.68 123.95,46.39 124.07,46.27 124.49,46.27 124.73,46.02 124.73,45.54 124.49,45.29 124.07,45.29 123.95,45.18 123.95,44.89 124.07,44.77 124.49,44.77 124.73,44.52 124.73,44.04 124.49,43.79 124.22,43.79 124.09,43.67 124.09,43.4 124.22,43.27 124.49,43.27 124.73,43.03 124.73,37.55 124.66,37.48 124.66,36.36 124.77,36.25 124.9,36.25 v2(125.13,36.47)
  BOTTOM w0.127: v2(125.13,36.47) 124.79,36.13 124.65,36.13 124.48,36.3 124.48,37.18 125.17,37.87 DM1.137 ; CPU1.AV39 v2(123.58,79.79)
M_A_DQS_DP5: length 52.4
  TOP w0.127: v2(130.85,32.68) 130.95,32.68 v1(131.3,32.34)
  L3 w0.089: 125.27,68.79 125.27,68.81 ; 125.26,68.82 125.26,68.83 125.19,69.03 125.24,69.15 125.19,69.27 124.61,70.86 124.74,71.13 124.6,71.51 v2(124.84,72.04)
  L3 w0.114: 125.27,68.79 125.39,68.48 125.44,68.32 125.53,68.07 126.01,67.85 126.17,67.78 126.95,65.63 127.33,65.45 132.2,52.09 132.2,47.73 132.08,47.62 131.98,47.62 131.73,47.37 131.73,46.89 131.98,46.64 132.08,46.64 132.2,46.53 132.2,46.23 132.08,46.12 131.98,46.12 131.73,45.87 131.73,45.39 131.98,45.14 132.08,45.14 132.2,45.03 132.2,44.51 129.95,42.27 129.95,40.41 129.95,39.31 129.84,39.2 129.84,38.86 129.95,38.74 129.95,38.4 129.84,38.29 129.84,37.95 129.95,37.83 129.95,36.18 129.71,35.93 129.71,35.39 129.97,35.13 130.23,35.13 130.34,35.02 130.34,34.66 130.23,34.55 129.92,34.55 129.65,34.29 129.65,33.35 129.92,33.09 130.45,33.09 130.85,32.69 v2(130.85,32.68) ; 125.26,68.82 125.27,68.81
  BOTTOM w0.102: CPU1.BJ42 124.49,74.45 124.49,74.45 124.64,74.05 124.69,73.9 124.89,73.34 125.02,73.01 125.15,72.66 125.23,72.43 125.1,72.11 v2(124.84,72.04)
  BOTTOM w0.127: v2(130.85,32.68) 130.48,33.05 130.19,33.05 129.91,32.77 129.91,31.77 130.27,31.41 DM1.154
M_A_DQS_DP6: length 55.2
  TOP w0.127: v1(135.87,36.86) 135.54,36.53 v2(135.4,36.53)
  L4 w0.114: v2(135.4,36.53) 135.72,36.53 135.85,36.65 135.85,38.64 135.74,38.75 135.02,38.75 134.77,39 134.77,39.48 135.02,39.73 135.74,39.73 135.85,39.85 135.85,40.14 135.74,40.25 135.02,40.25 134.77,40.5 134.77,40.98 135.02,41.23 135.9,41.23 136.02,41.36 136.02,41.62 135.9,41.75 135.02,41.75 134.77,42 134.77,42.48 135.02,42.73 135.74,42.73 135.85,42.84 135.85,43.36 135.53,43.68 135.53,44.21 135.85,44.53 135.85,53.77 135.82,53.9 130.43,68.7 129.97,68.92 129.91,68.95 129.91,68.95 128.53,69.59 128.34,70.13 128.16,70.62 128.16,71.08 127.07,74.05 126.79,74.34 125.78,77.12 125.91,77.4 125.81,77.67 126.09,78.27 v2(126.03,78.41)
  BOTTOM w0.127: CPU1.BB35 v2(126.03,78.41) ; v2(135.4,36.53) 135.21,36.34 135,36.34 134.93,36.41 134.93,37.61 135.37,38.05 DM1.171
M_A_DQS_DP7: length 53.7
  TOP w0.127: v2(139.54,33.63) 139.68,33.63 v1(140.01,33.96)
  L3 w0.114: v2(127.7,74.29) 127.74,74.18 127.53,73.72 127.31,73.26 128.62,69.66 130.88,68.61 134.05,59.9 134.06,59.85 134.07,59.85 134.08,59.81 136.66,52.72 137.28,51.01 137.28,50.45 137.57,50.17 137.57,49.79 137.28,49.51 137.28,48.95 137.57,48.67 137.57,48.29 137.28,48.01 137.28,47.45 137.57,47.17 137.57,46.8 137.28,46.51 137.28,45.8 137.56,45.53 137.56,45.18 137.28,44.9 137.28,44.19 137.57,43.91 137.57,43.54 137.28,43.25 137.28,40.91 140.32,37.88 140.32,33.72 140.04,33.44 139.73,33.44 v2(139.54,33.63)
  BOTTOM w0.089: v2(127.7,74.29) 127.87,74.36 127.92,74.48 127.9,74.55 127.83,74.75 127.74,75 127.63,75.28 127.52,75.34 127.41,75.39 127.4,75.4 127.39,75.4 127.23,75.85 127.23,75.85 127.23,75.86 127.03,75.99
  BOTTOM w0.102: 127.03,75.99 CPU1.BG36
  BOTTOM w0.127: DM1.188 140.47,32.92 140.06,33.33 139.84,33.33 v2(139.54,33.63)
M_A_ODT0: length 62.5
  TOP w0.203: v2(118.8,31.99) v1(118.8,31.43)
  L4 w0.089: 121.86,73.71 121.86,74.08 121.88,74.09 122.43,75.28 122.43,75.41 122.4,75.48 122.4,75.87 122.11,76.67 122,76.72 121.22,76.43 121.11,76.49 120.95,76.92 120.05,77.82 120.05,79.19 120.15,79.29 120.51,79.29 120.63,79.16 120.63,78.83 120.74,78.73 121.02,78.73 121.09,78.81 121.09,79.21 121.17,79.29 121.73,79.29 121.9,79.12 v2(121.9,78.46)
  L4 w0.191: 121.86,73.71 122.47,72.04 122.36,71.79 122.09,71.7 121.98,71.45 122.13,71.03 122.37,70.92 122.64,71.02 122.79,70.95 123.86,68 123.89,67.98 124.25,67 124.82,66.74 127.24,60.08 128.59,56.07 127.24,50.36 119.95,43.07 119.95,40.63 119.95,39.74 119.08,38.87 119.08,37.46 119.08,34.64 118.94,34.5 118.25,34.5 118.05,34.29 118.05,32.21 118.27,31.99 v2(118.8,31.99)
  BOTTOM w0.203: v2(118.8,31.99) 118.83,31.96 118.83,30.56 DM1.116 ; CPU1.AW43 v2(121.9,78.46)
M_A_ODT1: length 57.6
  TOP w0.203: v2(121.12,32.62) v1(121.12,33.18)
  L4 w0.089: 125.13,73.74 124.45,75.65 124.5,75.76 123.93,77.31 123.79,77.38 123.41,78.42 123.47,78.54 123.2,79.28 123,79.38 v2(122.67,79.38)
  L4 w0.191: v2(121.12,32.62) 122.5,34 122.5,34.38 122.78,34.66 122.95,34.66 124.23,35.94 124.23,36.98 125.87,38.63 125.87,43.38 130.85,48.36 132.49,55.59 129.7,63.25 127.9,68.2 127.41,68.43 126.98,69.61 126.56,69.81 125.13,73.74
  BOTTOM w0.152: v2(122.67,79.38) 123.02,79.21 CPU1.AW41
  BOTTOM w0.203: DM1.120 120.11,30.56 120.11,32.09 120.64,32.62 v2(121.12,32.62)
M_A_RAS#: length 64.4
  TOP w0.203: v2(116.95,32.07) v1(116.95,31.51)
  L4 w0.089: v2(122.43,68.79) 122.47,68.68 122.25,68.22 122.39,67.83 122.89,67.59 122.93,67.5
  L4 w0.191: v2(116.95,32.07) 117.06,32.07 117.32,32.07 117.5,32.25 117.5,34.52 117.69,34.71 117.69,35.27 117.23,35.73 117.23,43.22 117.36,43.35 117.64,43.35 117.76,43.47 117.76,44.15 117.64,44.28 117.36,44.28 117.23,44.4 117.23,44.83 120.15,47.74 120.15,48.02 119.74,48.43 118.98,48.43 118.83,48.58 118.83,49.78 119.11,50.05 119.29,50.05 120.73,48.61 121.02,48.61 123.25,50.84 124.19,54.14 124.19,54.98 124,55.17 123.17,55.17 123.05,55.3 123.05,55.87 123.17,56 124.57,56 124.7,56.13 124.7,56.7 124.57,56.82 123.38,56.82 123.25,56.95 123.25,57.52 123.38,57.65 124.24,57.65 124.37,57.78 124.37,58.53 124.24,58.66 124.06,58.66 123.16,59.07 123.1,59.24 123.32,59.7 123.48,59.76 123.98,59.53 124.23,59.62 124.39,59.97 124.3,60.22 123.82,60.45 123.76,60.61 123.98,61.08 124.15,61.14 124.62,60.91 124.88,61.01 125.01,61.3 124.04,63.98 124.1,64.11 124.09,64.14 124.09,64.38 122.95,67.5 122.93,67.5
  BOTTOM w0.089: CPU1.BG47 121.96,74.84 121.96,74.68 121.85,74.57 121.85,74.44 121.78,74.24 121.86,74.03 122,73.96 122.07,73.77 122.13,73.61 122.04,73.42 123.07,70.59 122.97,70.36 123.05,70.13
  BOTTOM w0.127: v2(122.43,68.79) 122.43,68.75 122.55,68.62 122.92,68.62 123.05,68.75 123.05,70.13
  BOTTOM w0.203: v2(116.95,32.07) 117.14,32.07 117.26,31.95 117.26,31.82 117.26,31.54 117.07,31.36 DM1.110
M_A_VREFCA_CPU: length 1.3
  TOP w0.381: v2(125.45,82.68) 125.18,82.74 TP509.1
  BOTTOM w0.254: v2(125.45,82.68) 125.24,82.41 CPU1.AR35
M_A_VREFDQ_CPU: length 1.3
  TOP w0.305: v2(125.94,81.34) 126.24,81.37 TP510.1
  BOTTOM w0.254: CPU1.AT34 v2(125.94,81.34)
M_A_WE#: length 65.2
  TOP w0.203: v2(118.33,37.09) v1(118.33,37.68)
  L4 w0.191: v2(118.33,37.09) 118.33,37.3 118.5,37.48 118.5,38.35 118.35,38.5 118.35,38.98 118.86,39.49 118.86,40.87 119.05,41.06 119.26,41.06 119.39,41.18 119.39,41.75 119.26,41.88 119.05,41.88 118.86,42.07 118.86,42.77 120.58,44.49 123.72,47.63 124.62,48.53 124.62,48.8 123.83,49.59 123.83,49.86 124.15,50.18 124.42,50.18 125.21,49.39 125.48,49.39 126.51,50.43 126.61,50.99 126.5,51.14 125.33,51.33 125.18,51.54 125.25,51.98 125.47,52.14 126.9,51.91 127.05,52.01 127.14,52.58 127.04,52.72 125.6,52.96 125.44,53.17 125.51,53.61 125.73,53.77 127.28,53.52 127.43,53.62 127.52,54.19 127.41,54.33 125.86,54.59 125.7,54.8 125.78,55.24 125.99,55.4 127.68,55.13 127.83,55.23 127.92,55.8 127.81,55.94 126.13,56.22 125.97,56.43 126.04,56.87 126.26,57.03 127.26,56.87 127.41,56.97 127.5,57.54 127.39,57.68 126.39,57.85 126.23,58.06 126.28,58.38 126.13,58.6 125.55,58.7 125.44,58.84 125.54,59.41 125.68,59.51 126.53,59.37 126.69,59.48 126.74,59.82 126.21,61.28 126.12,61.53 126.04,61.74 125.33,63.7 125.25,63.92 125.18,64.12 125.1,64.33 124.27,66.64 124.03,66.75 123.66,67.77 123.41,67.89 122.69,69.86 122.57,70.22 122.49,70.43 122.31,70.48 122.16,70.43 v2(121.94,70.11)
  BOTTOM w0.089: CPU1.BG48 121.48,74.14 121.55,73.96 121.55,73.9 121.49,73.77 121.63,73.37 122.27,71.62 122.55,70.83 122.55,69.98 122.44,69.87 122.18,69.87 v2(121.94,70.11)
  BOTTOM w0.203: DM1.113 117.97,37.23 118.11,37.09 v2(118.33,37.09)
MCSI_RCOMP_1: length 2.4
  TOP w0.203: v2(124.85,95) 124.8,94.95 124.12,94.62 124.19,94.29 124.09,93.88 v1(123.98,93.63)
  BOTTOM w0.203: CPU1.H27 v2(124.85,95)
MCSI_RCOMP_2: length 1.5
  TOP w0.203: v2(124.67,95.73) 124.2,95.54 123.74,95.35
  BOTTOM w0.203: v2(124.67,95.73) CPU1.F27
MDSI_RCOMP: length 2.5
  TOP w0.203: v2(137.69,86.52) 138.66,86.47 139.38,86.79 v1(139.55,86.82)
  BOTTOM w0.203: v2(137.69,86.52) 137.65,86.64 CPU1.AP7
ME_FWP_EC_CPU: length 203.6
  TOP w0.102: v1(164.17,56.64) 164.23,56.69 v2(164.73,56.69)
  L3 w0.127: v2(164.73,56.69) 163.82,55.79 163.82,54.23 163.44,53.86 163.44,52.73 158.19,47.48 158.19,43.71 157.06,42.58 157.06,32.02 157.02,31.98 157.02,31.86 151.98,26.82 149.26,26.82 145.73,23.29 144.86,23.29 144.29,22.72 140.38,22.72 139.35,23.75 134.9,23.75 133.17,25.49 79.16,25.49 75.09,29.55 75.09,40.73 75.31,40.94 75.31,41.45 75.31,43.38 75.31,43.38 75.31,44.3 74.96,44.64 74.68,44.92 74.68,47.39 74.68,47.39 74.68,47.76 74.68,47.77 74.68,49.48 72.4,51.77 72.4,55.45 71.75,56.1 71.75,59.14 72.28,59.67 72.28,62.71 73.79,64.22 73.79,66.53 78.97,71.71 81.12,71.71 81.69,72.28 83.26,72.28 84.44,73.45 84.44,73.56 85.9,75.02 86.61,75.02 86.98,75.39 86.98,76.57 95.32,84.91 95.32,87.54 95.03,87.84 95.03,88.27 96.76,90 96.89,90 98.55,91.66 99.25,92.36 99.34,92.36 v2(100.18,93.2)
  BOTTOM w0.102: R1909.2 100.31,93.27 100.24,93.2 v2(100.18,93.2) ; KBC24.79 167.05,54.4 166.45,55 166.45,55.77 166.16,56.06 165.36,56.06 v2(164.73,56.69)
MIC2_VREFO: length 13.5
  TOP w0.305: v1(163.66,16.54) 163.43,16.31 162.34,16.31 v2(162.14,16.11)
  L4 w1.016: v2(162.14,16.11) 162.57,16.11 163.23,16.77 164.93,16.77 168.61,20.45 168.61,22 v2(169.04,22.43)
  BOTTOM w0.203: HDA27.29 162.06,16.18 v2(162.14,16.11)
MIC_CAP: length 3.2
  BOTTOM w0.203: HDA27.19 165.66,20.25 165.77,20.14
  BOTTOM w0.254: 165.77,20.14 165.98,19.93 166.2,19.93 ; C2713.1 167.06,19.05 166.2,19.91 166.2,19.93 ; 166.2,19.93 v1(166.2,19.94)
MIC_GND: length 4.3
  TOP w0.508: v2(110.88,174.55) 110.88,176.07 AFTP5512.1 110.94,176.11 R5517.1
  BOTTOM w0.305: LCD1.26 111.08,174.07 v2(110.88,174.55)
NCT_CLK: length 12.5
  BOTTOM w0.14: Q2603.1 74.11,63.77 74.48,64.14 74.48,65.69 74.77,65.98 RN2601.4 74.3,66.68 74.1,66.88 74.1,67.97 73.9,68.17 73.9,71.36 v1(74.99,72.44) 75.42,72.88 75.69,72.96 U2601.8
NCT_DATA: length 9.5
  BOTTOM w0.14: U2601.7 75.88,72.31 v1(74.62,71.05) 74.42,70.86 74.42,68.39 74.77,68.03 RN2601.3 75.37,67.33 75.7,67.01 75.7,65.99 75.24,65.53 Q2603.4
NMI_SMI_DBG#_CPU: length 29.7
  L4 w0.102: v2(104.15,104.98) 104.58,105.41 108.2,105.41 108.83,104.78 109.75,104.78 110.11,104.78 110.66,104.23 111.91,104.23 113.69,104.23 115.07,102.85 116.2,102.85 116.21,102.83 116.58,102.83 116.92,102.49 116.92,102.18 118.6,100.51 119.17,99.49 119.57,98.7 119.57,97.29 119.51,97.23 119.38,95.48 119.38,94.65 119.78,92.7 119.78,91.79 119.33,91.34 118.99,91.27 v2(118.37,91.15)
  BOTTOM w0.102: CPU1.M41 v2(118.37,91.15) ; v1(104.24,106.56) R1805.1 104.24,105.15 104.15,105.06 v2(104.15,104.98)
ODD_PWR_5V:
  vias: v1(171.88,145.33) v3(172.65,146.84) v3(172.65,146) v3(172.68,145.06)
ODD_SATA_RX_C_N: length 5.7
  TOP w0.127: v1(171.3,140.62) 171.2,140.72 ; 171.2,140.72 171.36,140.87 171.36,142.29 171.74,142.68 173.1,142.68 173.23,142.55 ODD1.5 ; 171.2,140.72 171.05,140.57 170.53,140.57 C6003.1
ODD_SATA_RX_C_N2: length 5.6
  BOTTOM w0.127: 171.13,140.74 171.28,140.9 171.28,142.12 171.84,142.68 173.1,142.68 173.23,142.55 ODD2.16 ; 171.13,140.74 171,140.62 170.58,140.62 C6005.1 ; 171.13,140.74 v1(171.23,140.64)
ODD_SATA_RX_C_P: length 5.7
  TOP w0.127: 172.17,142.92 173.13,142.92 173.26,143.05 ODD1.6 ; 172.17,142.92 171.64,142.92 171.11,142.39 171.11,140.97 170.95,140.81 170.62,140.81 C6001.1 ; 172.17,142.92 v1(172.17,143.05)
ODD_SATA_RX_C_P2: length 5.6
  BOTTOM w0.127: C6007.1 170.57,140.86 170.9,140.86 171.04,141 171.04,142.22 171.74,142.92 172.35,142.92 ; v1(172.35,143.05) 172.35,142.92 ; 172.35,142.92 173.13,142.92 173.26,143.05 ODD2.15
ODD_SATA_RX_N: length 73.6
  TOP w0.127: C6003.2 169.16,140.49 168.54,140.49 v2(168.31,140.72)
  L4 w0.114: v2(168.31,140.72) 163.01,140.72 162.75,140.46 162.1,140.46 161.86,140.71 161.86,142.12 161.74,142.24 161.29,142.24 161.17,142.12 161.17,140.71 160.92,140.46 160.33,140.46 156.42,136.55 156.42,110.03 144.33,97.94 143.89,97.84 143.47,97.74 141.36,98.4 140.5,98.31 139.95,98.01 138.67,97.39 137.83,96.99 137.82,96.98 137.78,96.97 136.57,95.91 136.43,95.79 136.31,95.7 136.19,95.61 136.11,95.56 135.97,95.49 135.89,95.45 135.74,95.45 135.6,95.47 135.52,95.5 v2(135.16,95.69)
  BOTTOM w0.127: C6003.2 169.16,140.49 168.54,140.49 v2(168.31,140.72) ; CPU1.T6 v2(135.16,95.69)
ODD_SATA_RX_P: length 73.9
  TOP w0.127: C6001.2 169.36,140.98 169.15,140.77 168.89,140.77 v2(168.31,141.35)
  L4 w0.114: v2(168.31,141.35) 168.31,141.34 167.92,140.95 162.91,140.95 162.66,140.69 162.2,140.69 162.08,140.81 162.08,142.21 161.83,142.46 161.2,142.46 160.94,142.21 160.94,140.81 160.83,140.69 160.24,140.69 156.19,136.65 156.19,110.13 144.21,98.15 143.48,97.98 141.56,98.58 141.38,98.64 140.43,98.53 139.85,98.21 138.57,97.6 137.73,97.2 137.69,97.2 136.42,96.08 136.42,96.08 136.29,95.97 136.28,95.97 136.06,95.8 135.88,95.8 v2(135.79,95.89)
  BOTTOM w0.127: v2(168.31,141.35) 168.89,140.77 169.15,140.77 169.36,140.98 C6001.2 ; v2(135.79,95.89) 135.58,95.68 135.58,95.41 CPU1.T5
ODD_SATA_TX_C_N: length 5.5
  TOP w0.127: 172.57,141.42 172.3,141.42 171.98,141.1 171.98,140.25 170.82,139.09 170.56,139.09 C6002.1 ; 172.57,141.42 173.1,141.42 173.23,141.55 ODD1.3 ; 172.57,141.42 v1(172.57,141.58)
ODD_SATA_TX_C_N2: length 5.7
  BOTTOM w0.127: v1(172.3,141.56) 172.3,141.42 ; 172.3,141.42 172.02,141.42 171.8,141.2 171.8,140.06 170.82,139.08 170.57,139.08 C6006.1 ; 172.3,141.42 173.1,141.42 173.23,141.55 ODD2.18
ODD_SATA_TX_C_P: length 5.5
  TOP w0.127: v1(171.41,139.12) 171.3,139.23 ; 171.3,139.23 170.92,138.85 170.59,138.85 C6004.1 ; 171.3,139.23 172.22,140.15 172.22,141 172.4,141.18 173.08,141.18 173.21,141.05 ODD1.2
ODD_SATA_TX_C_P2: length 5.7
  BOTTOM w0.127: v1(171.46,139.17) 171.36,139.27 ; 171.36,139.27 170.92,138.84 170.58,138.84 C6008.1 ; 171.36,139.27 172.04,139.96 172.04,141.1 172.12,141.18 173.06,141.18 173.18,141.05 ODD2.19
ODD_SATA_TX_N: length 72.5
  TOP w0.127: C6002.2 v2(168.38,139.4)
  L4 w0.114: v2(140.44,97.59) 140.44,97.56 140.93,97.08 143.72,97.08 144.77,97.53 145.4,97.99 156.98,109.57 156.98,136.35 159.75,139.12 161.31,139.12 161.42,139.23 161.42,139.72 161.67,139.97 162.32,139.97 162.57,139.72 162.57,138.71 162.69,138.58 163.12,138.58 163.25,138.71 163.25,139.92 163.51,140.18 164.13,140.18 164.39,139.92 164.39,139.52 164.52,139.4 v2(168.38,139.4)
  BOTTOM w0.089: 139.02,94.79 138.74,94.68 138.74,94.68 138.45,94.56 138.45,94.56 138.36,94.53 138.31,94.5 138,94.3 137.99,94.3 137.88,94.26 137.75,94.26 137.62,94.29 CPU1.W2
  BOTTOM w0.127: v1(139.89,95.46) 139.79,95.56 ; 139.79,95.56 139.02,94.79 ; 139.79,95.56 140.56,96.33 140.56,97.47 v2(140.44,97.59) ; C6002.2 v2(168.38,139.4)
ODD_SATA_TX_P: length 72.8
  TOP w0.127: v2(168.38,138.71) 168.6,138.93 169.11,138.93 169.36,138.67 C6004.2
  L4 w0.114: v2(168.38,138.71) 168.38,138.78 167.99,139.17 164.43,139.17 164.17,139.43 164.17,139.83 164.04,139.96 163.61,139.96 163.48,139.83 163.48,138.61 163.22,138.35 162.6,138.35 162.34,138.61 162.34,139.63 162.22,139.74 161.77,139.74 161.65,139.63 161.65,139.14 161.4,138.89 159.84,138.89 157.21,136.25 157.21,109.48 145.55,97.82 145.02,97.43 144.88,97.33 143.77,96.85 140.83,96.85 140.54,97.15 140.21,97.15 140.07,97.28 v2(139.86,97.28)
  BOTTOM w0.089: CPU1.W1 138.06,94.57 138.27,94.7 138.38,94.74 138.38,94.74 138.67,94.85 138.79,94.9 138.85,94.96
  BOTTOM w0.127: v2(139.86,97.28) 140.16,97.28 140.32,97.12 140.32,96.7 ; C6004.2 169.36,138.67 169.11,138.93 168.6,138.93 v2(168.38,138.71) ; 138.85,94.96 140.32,96.43 140.32,96.7 ; v1(140.16,96.7) 140.32,96.7
P2800_DXN: length 162.4
  TOP w0.254: v2(154.11,89.51) 154.25,89.51 155.55,90.81 v1(158.12,90.81) 158.77,90.81 160.68,88.9 Q2604.E
  L3 w0.254: v2(77.99,49.43) 77.99,49.76 77.55,50.19 77.55,50.68 74.91,53.33 74.91,61.84 76.27,63.2 76.27,65.5 77.76,66.98 77.93,66.98 v2(77.99,67.03)
  L4 w0.254: v2(154.11,89.51) 153.63,89.03 153.63,88.44 148.52,83.34 148.52,77.59 147.23,76.3 147.23,71.21 150.32,68.11 150.32,62.64 149.72,62.04 149.72,61.62 149.72,52.52 150.31,51.93 v2(150.31,51.91)
  BOTTOM w0.254: Q2601.E 153.2,49.16 153.6,49.56 153.6,50.03 C2603.2 C2604.2 152.13,50.03 152.13,50.09 151.27,50.95 v2(150.31,51.91) 150.16,52.06 149.87,52.06 148.23,53.7 142.7,53.7 138.47,49.47 84.82,49.47 83.69,50.6 79.61,50.6 78.67,49.66 78.27,49.66 78.04,49.43 v2(77.99,49.43) ; U2601.3 79.49,71.66 79.28,71.46 79.28,70.42 77.81,68.94 77.81,67.21 v2(77.99,67.03)
P2800_DXP: length 161.2
  TOP w0.254: v2(154.21,88.75) 155.76,90.3 158.56,90.3 v1(159.02,89.84) 159.7,89.16 Q2604.C 158.71,87.6 Q2604.B
  L3 w0.254: v2(77.91,66.35) 77.84,66.35 76.78,65.29 76.78,62.99 75.42,61.63 75.42,53.54 78.24,50.72 78.24,50.28 v2(78.22,50.26)
  L4 w0.254: v2(154.21,88.75) 154.13,88.67 154.13,88.23 149.03,83.13 149.03,77.38 147.73,76.09 147.73,71.42 150.83,68.32 150.83,62.43 150.23,61.83 150.23,52.73 150.39,52.57 v2(150.41,52.57)
  BOTTOM w0.254: U2601.2 79.42,72.31 78.77,71.67 78.77,70.63 77.3,69.16 77.3,66.96 v2(77.91,66.35) ; v2(78.22,50.26) 78.32,50.16 78.46,50.16 79.4,51.11 83.9,51.11 85.03,49.98 138.26,49.98 142.49,54.21 148.44,54.21 150.08,52.57 v2(150.41,52.57) 152.06,50.92 C2604.1 C2603.1 154.19,50.33 Q2601.C 154.19,47.06 154.44,46.8 Q2601.B
PANEL_BKEN_EC: length 173.4
  TOP w0.102: v2(174.28,72.42) v1(174.28,72.98) ; v2(176.56,139.19) 176.21,138.84 172.09,138.84 170.6,137.34 167.43,137.34 v2(167.38,137.39) ; R5519.1 v2(107.47,179.05)
  L4 w0.102: v2(161.4,136.15) 162.26,136.15 163.34,137.23 167.22,137.23 v2(167.38,137.39) ; v2(174.28,72.42) 174.56,72.7 174.56,82.85 175.62,83.92 175.62,92.9 174.77,93.75 174.77,125.01 175.57,125.81 175.57,133.94 176.35,134.71 176.35,138.98 v2(176.56,139.19)
  BOTTOM w0.102: v2(107.47,179.05) 110.47,179.05 113.94,182.53 119.22,182.53 122.05,179.7 122.05,166.42 124.67,163.81 124.67,158.4 132.29,150.78 137.98,150.78 146.29,142.47 146.29,141.51 148.32,139.48 150.82,139.48 153.05,137.25 153.25,137.06 158.22,137.06 159.14,136.15 v2(161.4,136.15) ; v2(174.28,72.42) 174.05,72.42 173.57,71.93 R2414.1
PANEL_BKEN_EC_KBC: length 4.9
  BOTTOM w0.102: R2414.2 172.77,69.98 v1(172.12,69.98) 171.43,69.98 170.65,69.2 KBC24.27
PANEL_SIZE_ID: length 111
  TOP w0.102: v2(106.18,93.35) 106.93,92.6 107.04,92.33 108.36,91.34 108.55,91 108.9,90.65 109.57,90.65 109.73,90.57 109.81,90.49 110.01,90.05 110.01,89.94 109.86,89.26 109.96,88.98 110.6,88.65 111.59,88.75 112.4,88.85 112.73,88.75 113.24,88.42 114.15,88.39 v2(114.71,88.24)
  L3 w0.102: v2(100.95,119.46) 100.95,119.1 101.4,118.65 101.4,113.31 101.45,113.26 101.68,112.94 103.01,111.61 103.74,109.5 103.74,109.4 103.94,107.93 105.01,106.43 105.65,104.88 105.87,104.4 106.33,102.62 106.38,102.47 106.66,102.11 107.27,101.02 107.7,100.45 107.93,99.74 108.06,99.01 108.06,98.76 108.54,96.72 108.54,96.34 108.36,96.07 108.25,95.95 108.16,95.02 107.88,94.59 107.47,94.41 107.27,94.26 v2(106.18,93.35)
  L4 w0.102: v2(112.76,169.32) 112.4,168.96 109.66,168.96 101.35,160.66 98.13,160.66 96.3,158.83 96.3,147.53 95.61,146.84 94.6,146.84 94.39,146.64 94.39,145.39 95.51,144.27 95.51,124.28 100.34,119.46 v2(100.95,119.46)
  BOTTOM w0.102: R5538.2 110.29,166.75 110.51,166.53 v1(110.73,166.53) 110.91,166.53 111.13,166.75 R5537.1 112.05,168.34 R5536.2 112.3,168.86 v2(112.76,169.32) ; v2(114.71,88.24) CPU1.T52
PANEL_SIZE_ID_CONN: length 5.3
  BOTTOM w0.102: LCD1.22 109.71,171.87 110.29,169.42 R5538.1 v1(109.38,168.32)
PBAT_PRES1#: length 14.7
  TOP w0.102: BATT1.5 BATT2.5 158.25,181.66 154.62,178.03 153.42,178.03 152.94,178.51 152.94,179.33 AFTP4303.1 152.1,179.78 151.38,179.06 RN4302.8
PBAT_PRES#: length 192.1
  TOP w0.102: v2(172.19,139.37) 174.53,139.37 175.61,140.45 PR4472.2 175.61,155.83 PC4433.1 ; v2(147.96,179.08) EC4306.2 149.68,179.08 RN4302.1 ; v2(166.02,55.59) 166.02,55.78 165.79,56.01 v1(165.59,56.01) 165.29,55.7 165.29,55.09 165.44,54.94 RN2402.3
  L3 w0.102: v2(156.9,180.95) 157.11,180.75 172.06,180.75 179,173.81 179,157.3 174.78,153.09 174.78,140.41 173.74,139.37 v2(172.19,139.37)
  L4 w0.102: v2(172.19,139.37) 172.19,138.69 172.65,138.23 172.65,137.42 167.62,132.39 167.62,97.23 167.06,96.67 167.06,93.44 167.06,93.44 167.06,92.84 167.06,92.84 167.06,90.58 166.3,89.82 166.3,87.83 165.44,86.97 165.44,82.79 165.03,82.39 165.03,82.03 165.56,81.49 165.56,73.4 165.66,73.31 165.66,68.64 166,68.29 166,65.29 165.72,65 165.72,61.64 166.28,61.08 166.28,56.85 166.02,56.59 v2(166.02,55.59)
  BOTTOM w0.102: v2(166.02,55.59) 166.02,54.3 166.65,53.67 KBC24.80 ; v2(156.9,180.95) 155.94,179.98 155.94,176.58 155.63,176.28 D4304.3 152.81,176.28 150.01,179.08 v2(147.96,179.08)
PBAT_SMBCLK1: length 17.7
  TOP w0.14: RN4302.6 152.15,177.91 AFTP4304.1 152.83,177.23 155,177.23 156.74,178.97 157.97,178.97 159.82,180.82 161.27,180.82 BATT2.3 BATT1.3
PBAT_SMBDAT1: length 15.5
  TOP w0.14: RN4302.7 150.69,178.41 152.56,178.41 153.22,177.75 154.77,177.75 156.65,179.63 AFTP4308.1 159.83,181.8 BATT2.4 BATT1.4
PCB_VER_AD: length 4.6
  TOP w0.102: v2(157.52,53.95) v1(156.95,53.95)
  BOTTOM w0.102: KBC24.98 157.89,54.32 v2(157.52,53.95) 156.85,53.28 C2417.1 R2438.1 156.01,52.39 R2437.2
PCH_SMB_CLK: length 233.6
  TOP w0.14: U7001.1 175.62,48.9 176.46,49.74 176.66,49.74 176.88,49.96 176.88,51.45 175.77,52.55 175.04,52.55 174.41,51.93 173.68,51.93 173,51.24 173,48.18 172.29,47.47 172.29,46.36 172.28,46.35 172.28,46.14 172.28,46.14 172.28,46.07 171.7,45.49 171.7,44.39 171.46,44.15 171.46,39.78 171.78,39.45 171.78,38.22 170.09,36.53 v1(169.12,36.53) 168.42,36.53 167.17,35.29 155.4,35.29 154.62,36.07 145.76,36.07 145.33,36.07 145.32,36.07 144.89,36.07 143.5,34.69 143.5,33.49 v2(144.05,32.95) 144.42,32.58 EC6505.1 R6515.1
  L3 w0.127: v2(94.75,87.45) 94.75,86.95 94.81,86.88 94.81,85.12 83.93,74.24 83.93,73.66 83.05,72.79 81.48,72.79 80.91,72.22 78.76,72.22 73.29,66.74 73.29,64.43 71.78,62.92 71.78,59.88 71.24,59.35 71.24,55.64 71.75,55.13 71.75,51.58 74.18,49.15 74.18,48.34 v2(74.2,48.31)
  L4 w0.127: v2(144.05,32.95) 142.72,34.28 142.72,37.65 142.79,37.73 142.79,46.55 141.78,47.57 141.78,49.78 144.04,52.04 144.04,64.11 144.94,65.01 v2(144.94,65.46)
  BOTTOM w0.14: v2(144.05,32.95) 144.05,32.24 144.67,31.62 DM1.202 ; v2(144.94,65.46) 145.01,65.39 145.01,64.2 132.41,51.61 85.71,51.61 84.57,52.74 78.39,52.74 74.2,48.55 v2(74.2,48.31) ; RN1704.3 92.55,85.89 92.7,86.04 92.7,86.09 93.68,87.07 93.73,87.07 93.73,87.07 93.93,87.07 94.28,87.42 94.72,87.42 v2(94.75,87.45) 97.23,87.45 97.34,87.34 Q1701.4
PCH_SMB_DATA: length 229.6
  TOP w0.14: U7001.4 173.82,48.49 173.52,48.19 173.52,47.96 172.81,47.25 172.81,46.14 172.8,46.13 172.8,45.86 172.22,45.27 172.22,44.17 172.02,43.97 172.02,39.96 172.3,39.67 172.3,38 170.31,36.01 168.63,36.01 v1(167.62,35) 166.76,34.15 153.57,34.15 152.16,35.55 145.11,35.55 144.03,34.47 v2(144.03,33.71) 145.26,32.48 EC6506.1 R6511.1
  L3 w0.127: v2(73.67,48.77) 71.18,51.26 71.18,54.13 70.73,54.57 70.73,59.56 71.27,60.09 71.27,63.13 72.78,64.65 72.78,66.95 78.55,72.72 80.7,72.72 81.27,73.29 82.84,73.29 83.42,73.87 83.42,74.45 93.78,84.81 v2(93.78,87.61)
  L4 w0.127: v2(144.03,33.71) 143.23,34.51 143.23,37.44 143.3,37.52 143.3,46.76 142.29,47.78 142.29,49.57 144.55,51.83 144.55,63.9 145.45,64.8 145.45,65.99 v2(144.79,66.65)
  BOTTOM w0.14: v2(93.78,87.61) 93.75,87.64 93.51,87.64 92.03,86.16 92.03,85.02 92.23,84.82 RN1704.4 92.95,84.82 93.22,85.09 93.22,85.87 93.9,86.55 94.14,86.55 94.49,86.9 95.22,86.9 95.24,86.92 95.93,86.92 96.17,86.68 96.17,85.24 96.03,85.1 Q1701.1 ; DM1.200 144.07,31.19 143.53,31.73 143.53,33.39 143.85,33.71 v2(144.03,33.71) ; v2(144.79,66.65) 144.49,66.35 144.49,64.42 132.2,52.13 85.92,52.13 84.79,53.26 78.18,53.26 73.69,48.77 v2(73.67,48.77)
PCIE_CLKREQ1_CPU#: length 5.9
  BOTTOM w0.102: CPU1.AH62 111.63,80.44 110.13,79.84 109.58,79.5 109.14,79.15 109.07,79.15 108.51,79.27 108.02,79.71 107.98,79.75 107.84,79.78 RN1606.1 107.4,79.99 v1(107.4,80.57)
PCIE_OBSN_CPU: length 17
  TOP w0.127: 145.09,107.95 145.09,107.47 144.03,106.4 144.03,105.44 141.94,103.35 141.28,103.17 140.5,102.95 140.22,102.87 140.19,102.86 140.19,102.86 136.88,101.81 136.86,101.8 135.85,101.08 135.82,101.06 134.86,100.07 134.82,100.05 134.24,99.59 134.05,99.36 v2(133.95,99.01) ; 145.09,107.95 v1(145.22,107.95) ; 145.09,107.95 145.09,108.52 R1601.1
  BOTTOM w0.127: CPU1.F5 v2(133.95,99.01)
PCIE_OBSP_CPU: length 17.4
  TOP w0.127: 144.25,106.97 144.85,107.57 144.85,108.56 R1601.2 ; 144.25,106.97 143.78,106.5 143.78,105.54 141.82,103.57 141.21,103.4 141.03,103.35 140.43,103.18 140.26,103.13 140.25,103.13 140.12,103.09 140.12,103.09 139.97,103.04 138.99,102.73 136.77,102.03 136.78,102.03 136.74,102.01 135.71,101.28 135.66,101.25 134.71,100.26 134.69,100.25 134.06,99.76 133.88,99.53 133.49,99.23 v2(133.28,98.79) ; 144.25,106.97 v1(144.15,107.06)
  BOTTOM w0.127: CPU1.F6 v2(133.28,98.79)
PCIE_REF_CLK_RCOMP: length 4.2
  TOP w0.203: R2001.2 125.72,95.85 125.79,96.06 125.89,96.6 v1(125.89,96.9) v2(125.16,97.31)
  BOTTOM w0.203: v2(125.16,97.31) 125.36,97.51 125.49,97.51 125.5,97.52 126.47,97.52 CPU1.E21
PCIE_WAKE0_CPU: length 7.6
  BOTTOM w0.102: RN1608.2 103.71,89.27 104.62,88.36 v1(105.31,88.04) 105.65,87.92 106.19,87.55 106.35,87.55 106.96,86.93 108.18,86.39 108.22,86.37 108.94,86.37 109.18,86.46 109.5,86.46 109.53,86.45 110.09,86.45 CPU1.R62
PCIE_WAKE0_CPU#: length 2.3
  BOTTOM w0.102: WLAN1.55 155.81,163.25 155.99,163.43 TP6103.1
PCIE_WAKE1_CPU: length 7.6
  BOTTOM w0.102: RN1608.1 104.23,90.14 104.83,89.54 v1(104.83,89.16) 104.83,89.05 105.7,88.19 106.02,87.99 106.26,87.99 107.04,87.21 108.25,86.57 108.87,86.57 109.35,86.74 CPU1.P62
PCIE_WAKE2_CPU: length 10.9
  BOTTOM w0.102: CPU1.P61 109.8,87.01 109.78,87.02 109.7,87.03 109.42,87.21 109.12,87.38 107.26,87.38 106.32,88.32 106.15,88.32 105.23,89.24 105.23,89.69 105.2,89.78 105.2,90.41 104.43,91.19 v1(104.22,91.19) 103.03,91.19 102.69,91.52 RN1607.2
PCIE_WAKE3_CPU: length 10.8
  BOTTOM w0.102: RN1607.1 102.63,92.17 v1(103.07,91.74) 103.13,91.67 104.4,91.67 105.41,90.66 105.41,89.76 105.5,89.53 106.69,88.34 106.69,88.24 106.7,88.21 107.3,87.62 108.77,87.62 108.96,87.69 109.03,87.76 109.04,87.77 109.13,87.87 109.24,87.9 109.36,87.9 109.52,87.83 CPU1.N62
PD4404_A: length 3.9
  TOP w0.102: PQ4409.B 175.27,164.54 174.78,165.03 v1(173.62,165.03) 173.21,164.62 PD4404.A
PD4404_K: length 3.5
  TOP w0.102: v1(173.46,160.07) 173.21,160.33 PD4404.K 173.26,161.6 PR4468.2
PD#: length 4.2
  BOTTOM w0.102: HDA27.47 158.04,22.25 157.77,22.52 157.77,23.19 157.23,23.73 157.23,23.88 156.09,25.02 R2722.2
PEG_CLKREQ_WLAN#: length 260.6
  TOP w0.102: R1607.1 R1606.2 84.63,68.42 84.39,68.18 83.24,68.18 82.96,68.45 82.96,69.52 83.27,69.83 83.27,70.51 83.09,70.69 82.37,70.69 82.24,70.82 82.24,70.98 v2(82.1,71.12) 82.1,71.56 83.38,72.84 Q1601.S ; v2(153.96,112.88) v1(153.96,111.99) 153.96,111.32 157.46,107.82 157.46,107.8 158.71,106.56 v2(158.71,105.51)
  L3 w0.102: v2(82.1,71.12) 81.78,70.81 81.5,70.81 79.35,70.81 74.7,66.15 74.7,63.85 73.34,62.49 73.34,52.67 75.5,50.51 75.5,49.41 v2(75.62,49.28)
  L4 w0.102: v2(153.96,112.88) 153.7,113.13 153.7,143.61 156.99,146.9 156.99,156.91 157.49,157.41 157.49,158.6 158.15,159.26 v2(158.15,159.39) ; v2(158.71,105.51) 158.86,105.36 158.86,102.6 147.96,91.71 147.96,77.82 146.67,76.53 146.67,70.97 148.48,69.17 149.77,67.88 149.77,64.54 149.32,64.1 149.32,62.43 149.16,62.27 149.16,50.95 153.37,46.74 v2(153.37,44.4)
  BOTTOM w0.102: v2(75.62,49.28) 76.25,48.65 76.25,44.7 77.48,43.47 83.81,43.47 86.83,46.49 142.93,46.49 143.42,46 143.42,44.53 144.01,43.94 149.36,43.94 149.82,44.4 v2(153.37,44.4) ; v2(158.15,159.39) 158.15,160.63 157.87,160.91 157.87,162.51 157.63,162.75 WLAN1.53
PLT_RST#: length 399
  TOP w0.102: v2(138.59,153.14) 140.55,155.1 144.05,155.1 144.76,154.38 AFTP6104.1 145.47,154.71 145.07,155.12 144.74,155.12 144.72,155.13 v2(144.71,155.13) ; v2(123.45,176) 121.74,176 120.29,177.45 118.54,177.45 R5533.1 ; R6312.2 59.68,60.16 60.22,60.7 63.36,60.7 v2(63.41,60.66) 63.41,59.55 Q6301.D ; v2(39.57,65.72) 39.2,65.34 39.2,62.46 39.92,61.74 R9926.2
  L3 w0.127: v2(94.54,69.28) 94.53,69.28 92.97,67.72 88.46,67.72 87.04,66.3 87.04,64.08 82.43,59.47 v2(82.43,59.16) 82.43,58.42 81.57,57.56 81.57,51.57 81.59,51.55 v2(81.59,49.53)
  L4 w0.127: v2(39.57,65.72) 40.82,66.97 43.23,66.97 44.24,65.95 46.65,65.95 47.65,64.95 49.82,64.95 50.59,64.18 50.59,63.05 50.62,63.03 50.62,62.92 51.5,62.04 53.46,62.04 53.88,62.46 54.24,62.46 54.8,63.02 55.51,63.02 56.51,64.02 58.01,64.02 59.01,63.02 59.01,62.19 59.87,61.33 62.73,61.33 v2(63.41,60.66) 67.1,60.66 68.95,58.8 80.39,58.8 80.53,58.66 81.94,58.66 v2(82.43,59.16) ; v2(162.57,44.5) 164,45.94 164,48.51 162.44,50.07 162.44,53.79 162.97,54.33 162.97,56.67 163.39,57.09 163.39,60.99 163.8,61.4 163.8,63.08 163.72,63.16 163.72,65.22 163.1,65.84 163.1,66.07 162.73,66.44 162.73,66.81 162.83,66.91 162.83,69 v2(162.8,69.04) 162.8,73.05 163.18,73.44 163.18,73.72 163.29,73.83 163.29,79.32 163.14,79.47 163.14,81.84 163.14,81.84 163.14,83.43 162.96,83.61 162.96,84.25 162.91,84.3 162.91,88.78 163.52,89.39 163.52,89.8 163.77,90.05 163.77,95.35 166.24,97.82 166.24,133.85 v2(166.4,134.01)
  BOTTOM w0.102: KBC24.7 162.65,68.9 v2(162.8,69.04) 162.8,69.14 162.19,69.75 162.19,73.23 161.86,73.56 161.67,73.56 161.42,73.81 161.42,74.17 161.44,74.19 161.44,75.55 157.18,79.8 v1(157.18,81.1) R9914.1 ; v2(162.57,44.5) 162.44,44.5 162.1,44.85 160.97,44.85 160.93,44.81 155.51,44.81 154.26,46.05 152.87,46.05 150.43,48.49 150.43,50.72 148.49,52.66 143.13,52.66 138.9,48.43 84.39,48.43 83.28,49.53 v2(81.59,49.53) ; WLAN1.52 145.57,162.5 144.56,161.49 144.56,155.29 v2(144.71,155.13) ; ED1807.1 104.57,71.69 104.22,71.35 102.83,71.35 102.6,71.12 102.6,70.08 102.74,69.94 R1829.2 103.11,69.45 102.93,69.28 v2(94.54,69.28) ; v2(166.4,134.01) 165.95,134.47 165.95,136.69 161.2,141.43 154.25,141.43 150.09,145.6 147.7,145.6 145.34,147.96 144,147.96 138.87,153.09 138.64,153.09 v2(138.59,153.14) 133.05,153.14 129.06,157.13 129.06,163.08 123.45,168.7 v2(123.45,176)
PLT_RST#_DEBUG: length 3.5
  BOTTOM w0.102: DB1.4 158.15,85.98 157.18,85.02 v1(157.18,84.71) R9914.2
PLTRST#_CPU: length 19.3
  TOP w0.102: v2(113.99,81.93) 113.34,82.17 112.33,81.86 112.27,81.85 111.93,81.69 111.18,81.61 110.57,81.66 110.5,81.65 110.36,81.62 109.65,81.11 106.72,78.18 v1(106.71,78.18) 106.71,78.17 104.91,76.37 104.91,71.58 v2(105.16,71.33)
  BOTTOM w0.102: v2(105.16,71.33) 104.67,70.83 R1832.2 R1829.1 ; CPU1.AG57 114.08,82.19 113.98,81.94 v2(113.99,81.93)
PM_BATLOW#: length 28.9
  TOP w0.102: v2(100.06,67.74) 100.06,67.64 101.02,66.68 R1823.2
  L4 w0.127: v2(117.56,82.22) 117.42,82.36 117.35,82.39 116.72,82.39 116.34,82.26 116.31,82.23 115.79,82.23 115.46,82.56 115.4,82.59 114.51,82.59 113.75,82.34 112.69,81.96 112.36,81.96 112.12,81.71 112.12,81.52 111.4,80.65 109.81,80.06 106.42,76.67 105.86,76.67 105.56,76.37 105.39,76.37 103.73,74.72 103.47,74.46 103.47,73.57 103.1,72.06 103.1,71.5 103.1,71.47 100.06,68.43 v2(100.06,67.74)
  BOTTOM w0.102: v2(100.06,67.74) 100.57,67.74 v1(100.7,67.87) ; v2(117.56,82.22) CPU1.AH51
PM_CLKRUN#_EC: length 13.4
  L3 w0.127: v2(107.38,84.97) 107.38,85.18 106.58,85.98 106.03,86.37 105.86,86.37 105.46,86.77 104.25,87.62 103.22,87.62 v2(103.16,87.56)
  BOTTOM w0.089: 109.56,84.75 109.54,84.71 109.36,84.53 109.16,84.46
  BOTTOM w0.102: 109.16,84.46 108.92,84.51 108.54,84.65 107.79,84.65 107.69,84.7 107.42,84.97 v2(107.38,84.97) ; 109.56,84.75 CPU1.V62
  BOTTOM w0.14: R1924.2 98.78,88.32 99.37,88.32 99.6,88.54 101.16,88.54 101.3,88.39 101.5,88.19 102.19,87.91 v1(102.55,87.71) v2(103.16,87.56)
PM_PWRBTN#: length 231.6
  TOP w0.102: v2(93.53,62.59) 93.56,62.61 93.56,62.64 93.91,62.99 95.33,62.99 97.11,61.22 103.59,61.22 107.04,64.67 R1804.2 ; R9929.1 39.64,62.98 v2(40.39,62.23) ; v2(153.65,61.98) v1(154.21,61.98)
  L3 w0.127: v2(93.53,62.59) 93.53,62.56 93.5,62.54 93.5,59.87 87.51,53.88 87.51,47.13 87.51,47.13 80.35,39.97 80.35,37.29 78.67,35.62 78.67,33.71 83.77,28.61 101.73,28.61 102.53,29.42 104.33,29.42 105.09,28.65 119.51,28.65 119.51,28.65 120.35,28.65 121.2,29.5 123.36,29.5 124.08,28.78 142.35,28.78 142.83,28.3 143.89,28.3 148.18,32.59 154.37,32.59 154.91,33.13 154.91,39.99 152.67,42.22 152.67,58.8 153.31,59.43 153.31,60.07 154.2,60.96 154.2,61.43 v2(153.65,61.98)
  L4 w0.127: v2(93.53,62.59) 92.51,61.57 90.64,61.57 83.41,54.35 65.45,54.35 63.76,56.03 52.24,56.03 51.42,56.85 51.24,56.85 49.31,58.78 48.45,58.78 47.12,60.1 47.12,60.54 46.32,61.34 41.28,61.34 v2(40.39,62.23)
  BOTTOM w0.102: KBC24.117 157.81,61.92 157.59,61.7 156.47,61.7 156.22,61.95 153.66,61.95 153.65,61.97 v2(153.65,61.98)
PM_PWRBTN#_CPU: length 22
  TOP w0.102: v2(115.73,81.55) 116.19,81.29 116.75,81.29 116.99,81.05 116.99,80.71 116.39,80.11 v1(115.98,80.11) 113.34,77.47 112.7,75.5 111.53,74.34 110.96,72.16 110.96,71.25 107.04,67.34 R1804.1 R1824.1
  BOTTOM w0.102: CPU1.AK55 v2(115.73,81.55)
PM_RSMRST#: length 196.2
  TOP w0.102: v2(96.3,83.49) 98.55,85.74 102.06,85.74 103.06,85.8 105.18,86.43 107.26,86.43 108.97,85.79 109.45,85.3 109.48,85.21 109.48,84.94 109.41,84.53 109.37,84.42 109.37,84.06 109.41,84.02 109.58,83.72 109.67,83.63 109.79,83.58 111.02,83.58 111.14,83.7 111.82,83.7 111.93,83.74 112,83.81 112.17,83.89 113.03,83.89 v2(113.34,83.75) ; R9912.2 40.18,66.97 40.73,66.41 v1(40.73,65.9) 40.54,65.71 v2(40.21,65.71)
  L3 w0.127: v2(72.52,57.89) 72.52,58.04 73.05,58.56 73.05,62.54 74.45,63.95 74.45,66.25 79.25,71.05 81.4,71.05 81.97,71.62 84.42,71.62 87.7,74.9 87.7,75.59 87.7,75.59 87.7,75.87 87.7,75.87 87.7,76.36 94.32,82.97 95.78,82.97 v2(96.3,83.49)
  L4 w0.127: v2(40.21,65.71) 41.03,66.53 43.02,66.53 44.04,65.52 46.47,65.52 47.47,64.52 49.49,64.52 50.16,63.84 50.16,62.87 50.19,62.85 50.19,62.74 51.32,61.61 52.39,61.61 52.51,61.49 54.31,61.49 54.46,61.64 58.26,61.64 60.14,59.76 67.3,59.76 69.17,57.89 v2(72.52,57.89)
  BOTTOM w0.102: U4004.2 25.48,60.86 ; 25.48,60.86 26.65,60.86 27.95,62.16 27.95,62.94 28.76,63.76 35.72,63.76 36.82,62.65 38.93,62.65 40.21,63.93 v2(40.21,65.71) 41.02,66.52 43.01,66.52 44.38,65.15 51.25,65.15 51.75,65.66 59.77,65.66 65.74,71.63 70.8,71.63 72.51,73.34 72.83,73.51 74.58,74.02 77.57,75.23 78.71,75.87 80.13,76.45 83.56,78.58 84.62,79.47 85.41,80.1 88.65,83.94 91.95,87.24 93.61,88.72 96.22,88.72 96.44,88.94 R1830.2 ED1805.1 R1826.1 94.68,90.88 94.68,91.53 U1801.4 ; 25.48,60.86 25.48,62.38 25.15,62.71 24.11,62.71 23.63,62.23 23.63,61.11 23.35,60.84 22.54,60.84 22.28,60.58 U4003.2 ; CPU1.AC57 v2(113.34,83.75)
PM_RSTBTN#: length 96.8
  TOP w0.102: R9913.1 v2(65.64,70.92) ; v2(108.95,79.83) v1(107.91,78.77) 107.69,78.42 107.31,77.88 105.75,76.06 105.75,74.85 106.48,74.12 106.48,71.49 105.36,70.36 102.06,70.36 99.88,68.18 99.88,68.18 99.45,67.75 99.45,66.35 99.7,66.09 100.17,66.09 R1836.2
  L4 w0.127: v2(59.93,63.18) 60.38,63.18 61.04,62.51 63.43,62.51 63.91,62.99 65.04,62.99 65.73,62.31 68.12,62.31 68.4,62.04 68.4,62.03 69.3,61.13 69.3,60.96 69.76,60.5 70.74,60.5 83.27,60.5 84.47,61.7 87.85,61.7 91.95,65.8 93.64,65.8 94.92,67.08 96.38,67.08 97.48,68.19 99.41,68.19 99.53,68.3 102.85,71.62 102.85,72.18 102.85,72.18 102.95,72.52 103.22,73.6 103.22,74.56 103.63,74.97 103.63,74.97 105.29,76.63 105.46,76.63 105.76,76.93 108.31,79.83 v2(108.95,79.83)
  BOTTOM w0.089: 109.18,81.24 109.47,81.35 109.97,81.85 110.5,82.04 110.58,82.13 110.63,82.18 CPU1.AD62
  BOTTOM w0.102: v2(65.64,70.92) 65.64,66.47 62.54,63.38 60.13,63.38 v2(59.93,63.18) ; 109.18,81.24 109.01,81.07 109.01,80.44 v2(108.95,79.83)
PM_SLP_S0#: length 248.2
  TOP w0.102: v2(160.87,56.72) 160.31,56.16 159.67,56.16 157.94,54.43 154.36,54.43 153.86,54.94 144.97,54.94 144.25,55.65 v2(142.88,55.65) ; v2(161.81,90.32) 160.54,91.59 160.54,103.05 v1(157.23,106.35) 157.23,107.72 150.78,114.18 v2(150.05,114.18)
  L3 w0.127: v2(109.56,80.44) 108.93,80.44 102.59,74.11 102.59,72.68 102.04,72.12 102.04,71.17 100.59,69.72 94.36,69.72 92.79,68.15 88.28,68.15 86.61,66.48 86.61,64.63 v2(85.67,63.69)
  L4 w0.127: v2(150.05,114.18) 150.05,121.19 149.66,121.57 149.66,136.29 149.35,136.6 137.53,136.6 136.35,137.78 v2(136.35,137.92) ; v2(160.87,56.72) 161.7,57.56 161.7,60.83 162,61.12 162,62.12 161.18,62.94 161.18,67.01 161.89,67.72 161.89,73.41 162.29,73.81 162.29,74.18 162.24,74.23 162.24,74.51 162.03,74.72 161.84,74.72 161.69,74.87 161.69,75.58 161.69,76.94 161.39,77.25 161.39,89.67 161.81,90.09 v2(161.81,90.32) ; v2(137.73,76.08) 138.23,75.57 138.23,68.23 142.2,64.26 142.2,56.34 v2(142.88,55.65)
  BOTTOM w0.089: CPU1.AD61 111.61,82.35 111.53,82.32 111.35,82.14 111.25,82.1 111.08,82.1 111.03,82.12 110.97,82.1 110.96,82.1 110.77,82.03 110.74,82.02 110.28,81.55 110.17,81.52
  BOTTOM w0.102: v2(109.56,80.44) 109.56,80.65 109.78,81.13 110.17,81.52 ; v2(136.35,137.92) 136.15,137.72 PR5038.2 ; KBC24.81 166.25,53.54 165.29,54.51 165.29,55.25 163.9,56.64 160.95,56.64 v2(160.87,56.72) ; v2(85.67,63.69) 87.55,63.69 89.26,61.98 124.95,61.98 133.2,70.23 134.2,71.15 135.64,73.2 136.33,73.89 136.63,74.32 137.09,74.7 v2(137.73,76.08)
PM_SLP_S3#: length 415.5
  TOP w0.102: v2(137.01,137.75) 138.15,136.62 141.63,136.62 147.66,130.58 v1(147.66,129.47) 147.66,124.32 147.09,123.75 145.88,123.75 142.49,120.36 142.49,118.99 v2(140.98,117.48) 138.39,117.48 137.09,116.18 137.09,115.61 134.17,112.69 127.81,112.69 125.86,114.63 125.86,116.64 126.98,117.76 v2(129.62,117.76) ; v2(23.25,52.55) 23.3,52.61 R4004.1 ; v2(176.05,129.62) 172.91,129.62 161.45,141.07 155.28,141.07 154.28,140.08 v2(150.25,140.08)
  L3 w0.127: v2(160.92,58.22) 161.31,57.83 161.31,56.54 160.43,55.66 159.96,55.66 158.6,54.3 158.6,53.4 156.31,51.1 156.31,43.54 156.51,43.34 156.51,31.8 151.79,27.08 149.11,27.08 146.52,24.49 142.67,24.49 142.11,25.05 135.44,25.05 133.73,26.76 132.89,26.76 132.88,26.76 81.41,26.76 79.43,28.73 v2(78.49,28.73)
  L4 w0.127: v2(23.25,52.55) 23.25,50.83 24.06,50.01 24.06,36.68 25.62,35.12 25.62,25.97 25.76,25.83 32.29,25.83 33.94,27.48 49.08,27.48 49.77,28.17 67.62,28.17 69.35,29.9 76.36,29.9 77.53,28.73 v2(78.49,28.73) ; v2(175.49,54.32) 174.47,55.34 174.47,58.68 174.29,58.86 174.29,60.85 174.47,61.03 174.47,63.29 174.28,63.48 174.28,68.78 175.79,70.29 175.79,75.61 174.8,76.6 174.8,82.75 176,83.96 176,92.86 175.01,93.85 175.01,121.92 176.05,122.96 v2(176.05,129.62) ; v2(137.01,137.75) 137.46,137.3 139.85,137.3 140.29,137.75 147.91,137.75 v2(150.25,140.08)
  BOTTOM w0.102: v2(23.25,52.55) 23.25,54.36 22.04,55.56 R4008.2 22.04,58.41 20.99,59.46 20.99,60.45 21.63,61.1 U4003.4 ; v2(175.49,54.32) 175.49,54.28 175.14,53.92 KBC24.64 172.17,53.92 171.74,54.35 171.74,55.29 170.31,56.72 169.93,56.72 168.97,57.69 168.97,58.06 168.48,58.55 161.25,58.55 v2(160.92,58.22) ; Q4003.2 126.88,118.98 127.19,118.67 127.48,118.67 R4005.1 128.39,117.76 v2(129.62,117.76) ; 142.27,110.62 142.27,111.33 142.69,111.74 143.13,111.74 143.85,112.46 143.85,114.99 143.32,115.52 142.93,115.52 v2(140.98,117.48) ; PR5039.2 v2(137.01,137.75)
PM_SLP_S4#: length 287.9
  TOP w0.102: v2(139.61,73.74) 141.33,73.74 152.08,84.48 152.08,89.89 152.43,90.24 152.43,91.87 146.93,97.37 146.93,102.68 147.3,103.05 147.3,110.01 v1(144.93,112.38) 143.39,113.92 v2(141.26,113.92) ; v2(168.31,70.04) 168.27,70 167.63,70 167.35,69.73 164.19,69.73 162.62,71.3 158.04,71.3 154.6,67.86 150.9,67.86 147.51,64.47 143.9,64.47 v2(143.44,64.01)
  L3 w0.127: v2(141.26,113.92) 141.46,113.72 144.35,113.72 150.83,120.2 150.83,134.97 150.19,135.61 149.08,135.61 146.5,138.19 138.25,138.19 v2(137.9,137.85)
  L4 w0.127: v2(86.37,52.58) 86.37,47.06 85.67,46.37 80.89,46.37 79.26,48.01 79.26,49.86 75.36,53.75 64.32,53.75 62.57,55.5 52.05,55.5 51.32,56.24 51.09,56.24 49.18,58.14 48.32,58.14 47.31,59.15 40.18,59.15 37.59,61.74 32.54,61.74 32.1,61.3 32.1,60.52 31,59.41 28.25,59.41 v2(27.54,60.12) ; v2(139.61,73.74) 139.61,67.51 143.11,64.01 v2(143.44,64.01)
  BOTTOM w0.102: U4004.4 24.83,61.1 24.39,60.66 24.39,58.85 25.27,57.98 R4010.2 25.27,57.39 25.46,57.2 27.29,57.2 27.54,57.46 v2(27.54,60.12) ; KBC24.21 168.25,69.98 v2(168.31,70.04) ; PR5037.2 v2(137.9,137.85) ; Q4002.2 139.15,111.41 139.25,111.51 139.94,111.51 140.36,111.93 140.36,113.43 140.85,113.92 v2(141.26,113.92) ; v2(86.37,52.58) 86.57,52.38 131.45,52.38 143.09,64.01 v2(143.44,64.01)
PM_SUS_STAT#: length 21
  TOP w0.102: v2(113.32,81.71) 113.32,81.67 113.25,81.53 113.07,81.35 112.76,81.02 112.11,80.09 111.65,79.61 v1(110.65,78.86) 108.87,77.08 108.87,74.18 106.9,71.87 106.71,71.69 106.71,71.39 105.45,70.13 105.16,70.13 101.89,66.86 R1811.1
  BOTTOM w0.102: CPU1.AG58 113.32,81.67 v2(113.32,81.71)
PM_SUSCLK: length 4.1
  TOP w0.102: v2(110.24,80.75) 109.98,80.28 v1(109.84,79.94) R1803.1
  BOTTOM w0.102: v2(110.24,80.75) 110.71,80.75 110.99,81.03 111.03,81.11 111.19,81.27 111.19,81.59 111.24,81.64 111.25,81.66 111.4,81.81 CPU1.AE62
PM_WAKE#: length 14.9
  TOP w0.102: v2(103.18,76.68) 103.49,76.68 105.32,78.51 v1(105.44,78.51) 105.99,78.51 107.88,79.78 109.32,81.18 109.63,81.42 110.13,81.8 110.44,81.87 110.51,81.89 110.64,81.89 111.1,81.85 111.16,81.84 111.92,81.94 112.24,82.09 112.48,82.15 113,82.33 113.14,82.36 113.55,82.48 114.37,82.31 v2(114.66,82.17)
  BOTTOM w0.102: v2(114.66,82.17) 114.65,82.2 CPU1.AG55 ; R1835.2 103.31,76.81 v2(103.18,76.68)
PMIC_EN_KBC: length 97.5
  TOP w0.102: v2(157.23,59.36) v1(156.67,59.36) ; v2(158.96,92.89) 159.27,93.19 159.27,93.81 158.27,94.8 158.27,103.01 157.21,104.08 157.21,104.84 149.73,112.32 148.9,112.32 v2(148.85,112.27)
  L4 w0.102: v2(148.85,112.27) 149.11,112.52 149.11,120.6 147.15,122.56 136.53,122.56 134.88,124.21 134.4,124.21 129.14,129.47 v2(126.25,129.47) ; v2(157.23,59.36) 157.23,59.97 157.12,60.08 157.12,62.15 158.22,63.25 158.22,70.38 158.87,71.02 158.87,77.22 158.4,77.69 158.4,81.06 157.98,81.48 157.98,85.4 158.57,85.99 158.96,86.38 v2(158.96,92.89)
  BOTTOM w0.102: KBC24.112 157.69,59.92 157.23,59.46 v2(157.23,59.36) ; PR5045.2 v2(126.25,129.47)
PMIC_I2C_SCL: length 80.6
  TOP w0.14: PR5016.2 126.5,127.1 127.44,128.04 v1(127.9,128.04) 128.18,128.04 128.81,127.41 v2(129.62,127.41)
  L4 w0.127: v2(102.85,109.98) 102.92,110.05 110.09,110.05 110.39,109.74 119.19,109.74 119.21,109.72 121.03,109.72 121.16,109.84 122.63,109.84 126.91,114.12 126.91,123.55 126.17,124.28 124.72,124.28 123.7,125.3 123.7,126.57 124.36,127.23 129.45,127.23 v2(129.62,127.41) ; v2(117.02,92.11) 116.79,92.22 116.73,92.22 116.23,92.45 115.53,93.15 114.74,94.93 114.17,97.14 114.09,97.34 114.06,97.44 113.98,97.67 113.91,97.74 113.41,98.24 109.42,98.24 108.73,98.24 107.27,99.7 v2(106.98,99.7)
  BOTTOM w0.14: PU5001.39 130.84,127.25 130.51,126.93 130.11,126.93 v2(129.62,127.41) ; v2(106.98,99.7) 106.98,100.45 105.36,102.06 105.32,102.17 105.32,103.43 104.27,104.48 104.01,104.48 103.65,104.84 103.65,109.13 103.8,109.29 103.8,109.72 103.5,110.02 103.07,110.02 103.03,109.99 102.85,109.99 v2(102.85,109.98) ; v2(117.02,92.11) CPU1.H45
PMIC_I2C_SDA: length 81.8
  TOP w0.14: PR5025.2 126.63,127.97 127.36,128.7 129.01,128.7 v1(129.19,128.53) v2(130.28,127.43)
  L4 w0.127: v2(116.78,92.75) 116.52,92.88 116.12,93.28 116.05,93.47 116.05,93.55 115.2,95.88 115.14,96.04 115.07,96.24 115.02,96.3 115.01,96.31 114.43,97.9 114.42,97.94 114.42,97.95 113.62,98.74 108.94,98.74 107.45,100.24 106.63,100.24 106.33,99.94 v2(106.33,99.87) ; v2(103.28,109.5) 109.92,109.5 110.18,109.23 117.06,109.23 118.03,108.27 122.39,108.27 127.25,113.13 127.25,113.74 127.41,113.91 127.41,123.26 127.41,123.26 127.41,123.76 126.38,124.79 125.88,124.79 124.93,124.79 124.21,125.52 124.21,126.03 124.91,126.72 130.11,126.72 130.28,126.9 v2(130.28,127.43)
  BOTTOM w0.14: v2(103.28,109.5) 103.13,109.35 103.13,104.63 103.8,103.96 104.05,103.96 104.8,103.21 104.8,101.99 104.86,101.83 104.91,101.78 104.92,101.76 106.33,100.34 v2(106.33,99.87) ; v2(116.78,92.75) 116.41,92.73 116.33,92.65 116.06,92.65 116.05,92.66 115.34,92.66 ; PU5001.40 130.41,127.56 v2(130.28,127.43)
PMIC_IRQ: length 36.4
  L4 w0.254: v2(117.36,102.36) 118.95,100.77 119.48,99.81 120.25,98.65 120.32,98.58 120.74,97.44 121.17,96.25 121.2,96.22 121.2,95.59 121.16,95.56 v2(120.95,95.1)
  BOTTOM w0.203: CPU1.F34 120.99,95.06 v2(120.95,95.1)
  BOTTOM w0.254: v2(117.36,102.36) 120.48,103.53 123.47,105.16 123.92,107.55 123.92,107.55 124.26,108.16 124.26,110.26 124.59,110.59 RN2101.2 125.06,117.4 124.95,117.51 124.95,121.74 124.77,121.92 v1(124.77,122.85) 124.77,124.06 125,124.28 PR5043.2
PMIC_PWRGD: length 128.2
  TOP w0.102: v2(143.26,114.97) v1(146.22,112.01) 147.53,110.7 147.53,102.96 147.16,102.59 147.16,97.47 152.66,91.97 152.66,90.14 152.31,89.79 152.31,84.81 152.66,84.46 154.42,84.46 155.68,83.19 156.17,82.71 156.17,79.09 159.06,76.2 159.98,76.2 161.85,74.33 v2(161.85,73.99) 161.85,73.94 161.83,73.92 161.83,72.82 161.58,72.57 161.53,72.57 161.48,72.52 160.83,72.52 R2609.2 ; v2(169.98,45.87) 170.44,45.87 170.56,45.99 171.12,46.55 171.12,46.83 171.13,46.84 171.13,47.2 171.12,47.2 171.12,48.05 171.84,48.77 171.84,49.49 R2014.2 ; PR5042.2 125.29,125.43 PR5030.2 124.92,125.4 124.65,125.67 v2(124.65,125.84)
  L3 w0.102: v2(161.85,73.99) 161.98,73.86 161.98,73.85 162.58,73.26 169.25,73.26 169.78,72.72 v2(169.78,72.01)
  L4 w0.102: v2(169.78,72.01) 169.78,69.42 170.57,68.63 170.57,65.64 171.69,64.52 171.69,62.09 170.29,60.69 170.29,58.12 170.87,57.53 170.87,55.82 171.05,55.64 171.24,55.45 171.24,53.98 172.39,52.83 172.39,46.49 171.71,45.81 170.08,45.81 170.02,45.87 v2(169.98,45.87) ; v2(143.26,114.97) 143.21,115.02 143.21,115.57 142.76,116.03 140.49,116.03 139.76,115.29 137.81,115.29 135.8,117.31 135.8,118.67 131,123.47 130.46,123.47 129.34,124.59 126.92,124.59 126.48,125.03 125.78,125.03 125.21,125.03 124.65,125.59 v2(124.65,125.84)
  BOTTOM w0.102: R2422.1 162.72,71.34 162.72,73.24 EC2401.1 162.59,73.37 162.59,73.42 162.02,73.99 v2(161.85,73.99)
PMIC_PWROK_KBC: length 3
  BOTTOM w0.203: v1(163.15,69.5) 163.18,69.5 163.85,68.82 KBC24.10
  BOTTOM w0.254: R2422.2 162.69,69.95 v1(163.15,69.5)
PMIC_RSMRST#: length 316
  TOP w0.203: v2(149.22,109.48) 149.38,109.48 v1(150.41,108.45) 156.88,101.97 156.88,93.81 154.79,91.72 v2(154.54,91.72)
  TOP w0.254: v2(51.92,58.83) 52.28,58.47 52.28,58.11 52.66,57.73 52.66,57.71 53.03,57.34 53.03,56.99 53.16,56.86 PR5046.1
  L3 w0.254: v2(61.88,43.79) 63.58,45.49 63.58,57.69 v2(63.2,58.07) 63.2,59.24 63.91,59.95 63.91,62.12 63.76,62.28 63.76,63.67 64.6,64.51 64.6,69 68.3,72.7 v2(68.67,72.7)
  L4 w0.254: v2(149.22,109.48) 149.34,109.6 149.34,109.6 150.3,110.56 150.3,111.77 149.54,112.53 149.54,120.78 145.78,124.54 136.94,124.54 v2(136.33,123.93) ; v2(63.2,58.07) 60.05,58.07 59.34,58.78 53.72,58.78 53.67,58.83 v2(51.92,58.83) ; v2(154.54,91.72) 154.54,90.55 155.13,89.97 155.13,87.82 153.96,86.66 153.93,86.63 153.93,84.33 152.18,82.58 152.18,77.5 149.68,75.01 149.68,72.75 151.27,71.16 151.47,71.16 153.25,69.39 153.25,66.75 152.79,66.29 152.79,63.41 152.48,63.1 152.48,62.18 152.53,62.12 152.53,60.29 152.25,60.01 152.25,52.63 155.01,49.88 v2(155.01,49.58) 155.01,49.18 154.87,49.04 154.87,42.22 155.25,41.84 155.25,32.02 154.13,30.9 154.13,28.97 151.78,26.62 146.76,26.62 146.73,26.65 146.31,26.65 146.29,26.62 135.83,26.62 134.34,28.12 80.11,28.12 75.37,32.86 75.37,44.32 74.99,44.71 65.44,44.71 64.52,43.79 v2(61.88,43.79)
  BOTTOM w0.203: PR5040.2 136.21,124.04 v2(136.33,123.93)
  BOTTOM w0.254: R2415.1 157.58,47.97 157.13,47.53 155.76,47.53 155.23,48.06 155.23,49.3 155.01,49.52 v2(155.01,49.58) ; U1801.2 94.02,92.21 93.67,91.86 92.94,90.34 ED1808.1 91.72,88.34 90.93,87.52 86.94,82.65 86.94,82.62 86.76,82.43 85.14,80.62 84.57,80.05 83.13,78.83 81.01,77.65 80.11,76.97 78.78,76.4 77.46,75.66 74.49,74.45 72.67,73.91 72.44,73.8 72.19,73.66 70.62,72.24 70.24,72.19 70.21,72.16 69.37,72.16 69.34,72.19 v2(68.67,72.7)
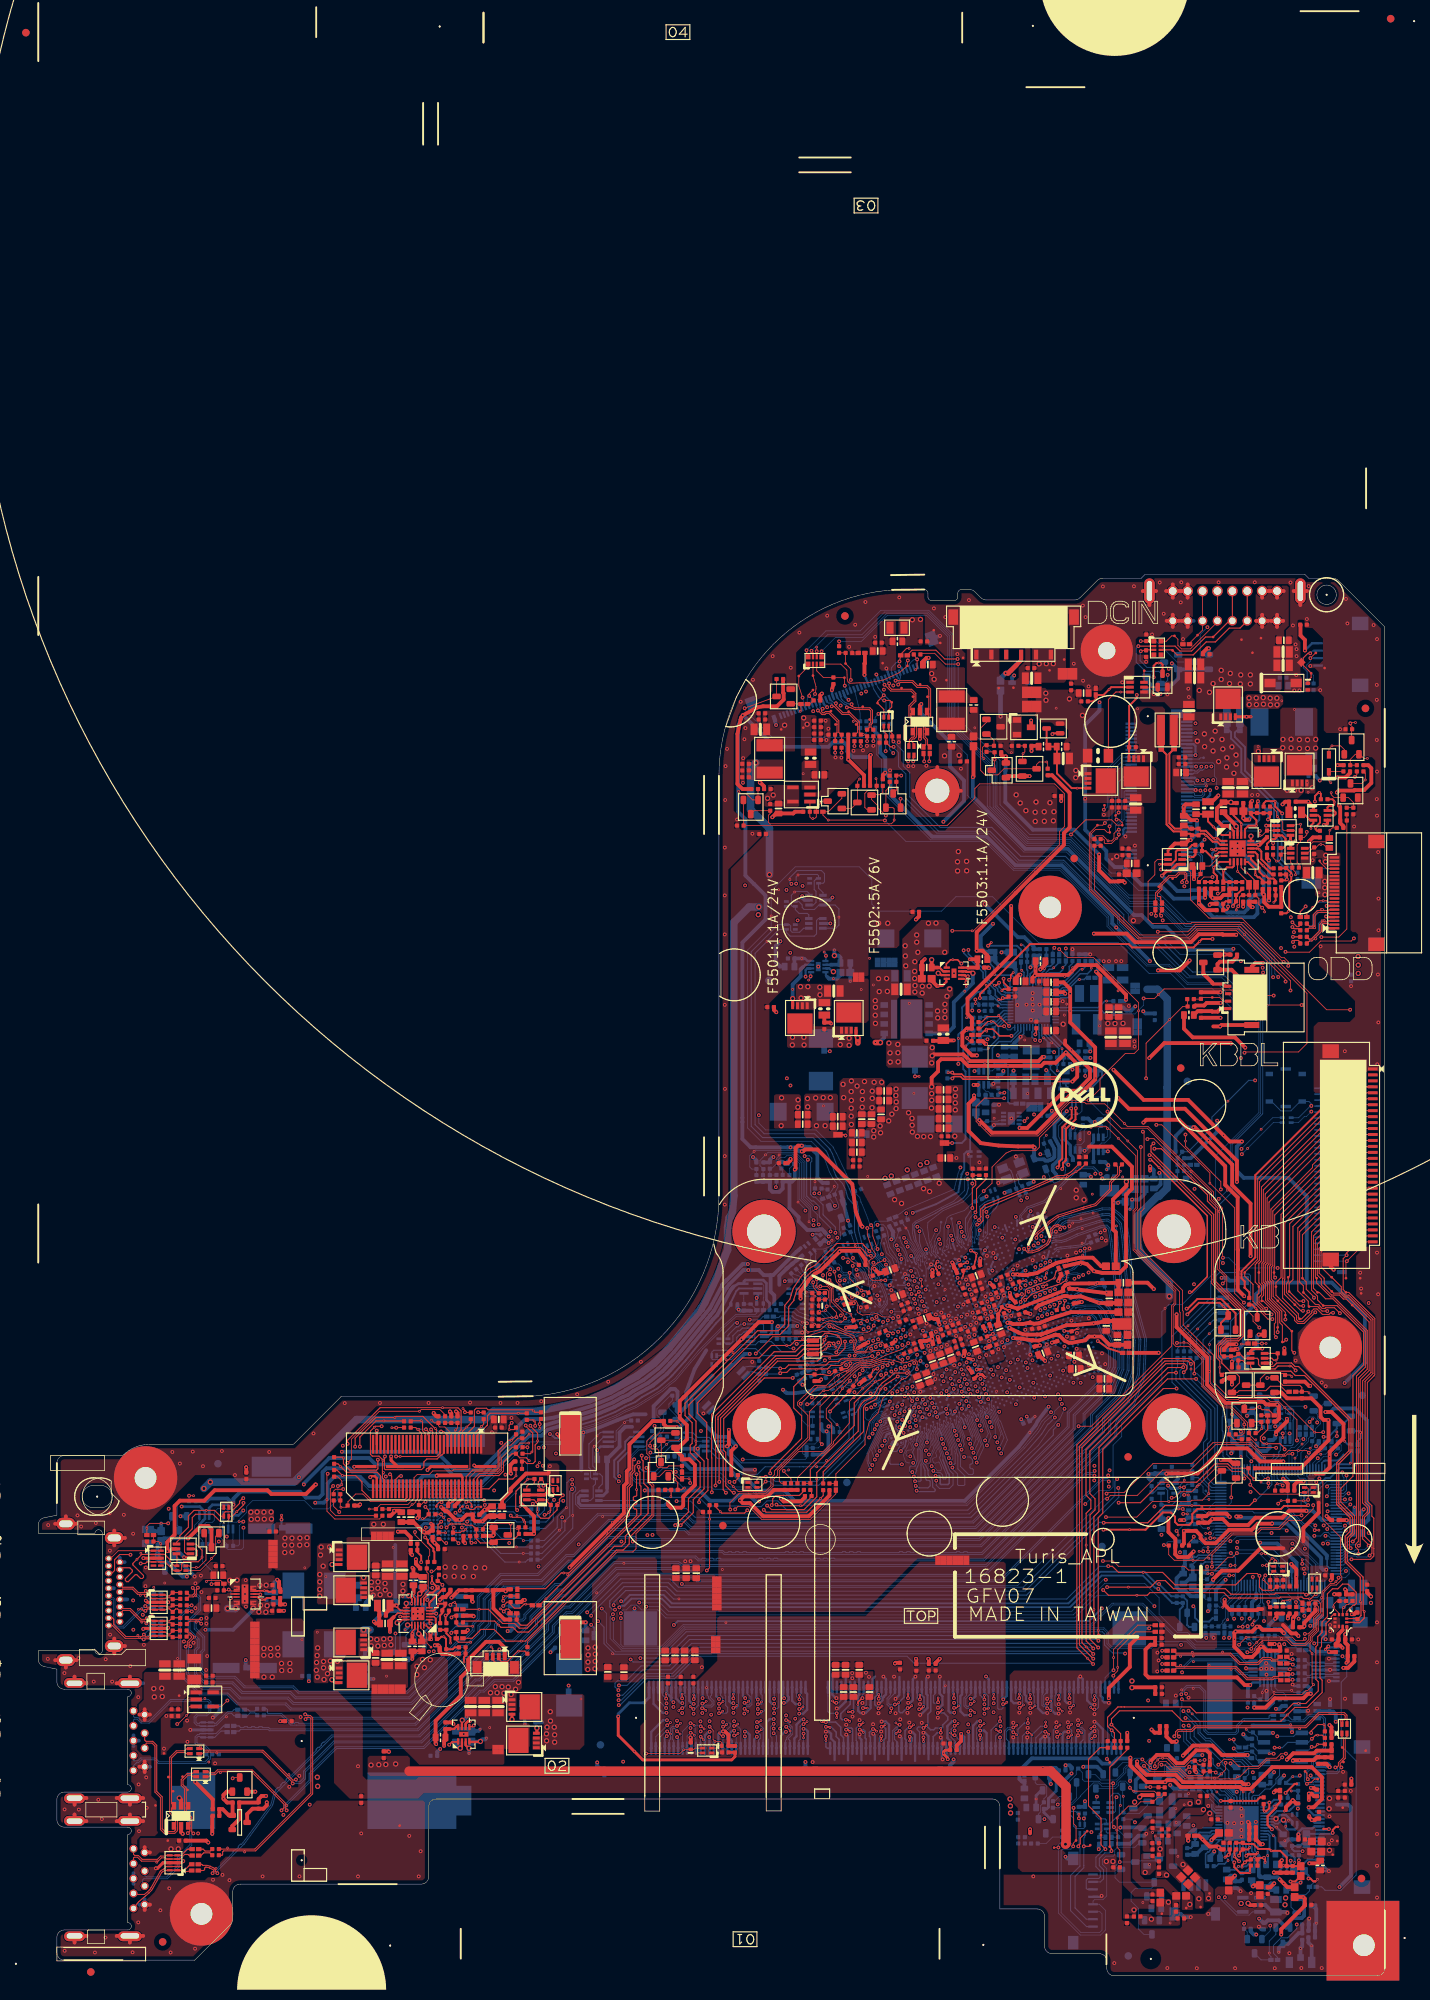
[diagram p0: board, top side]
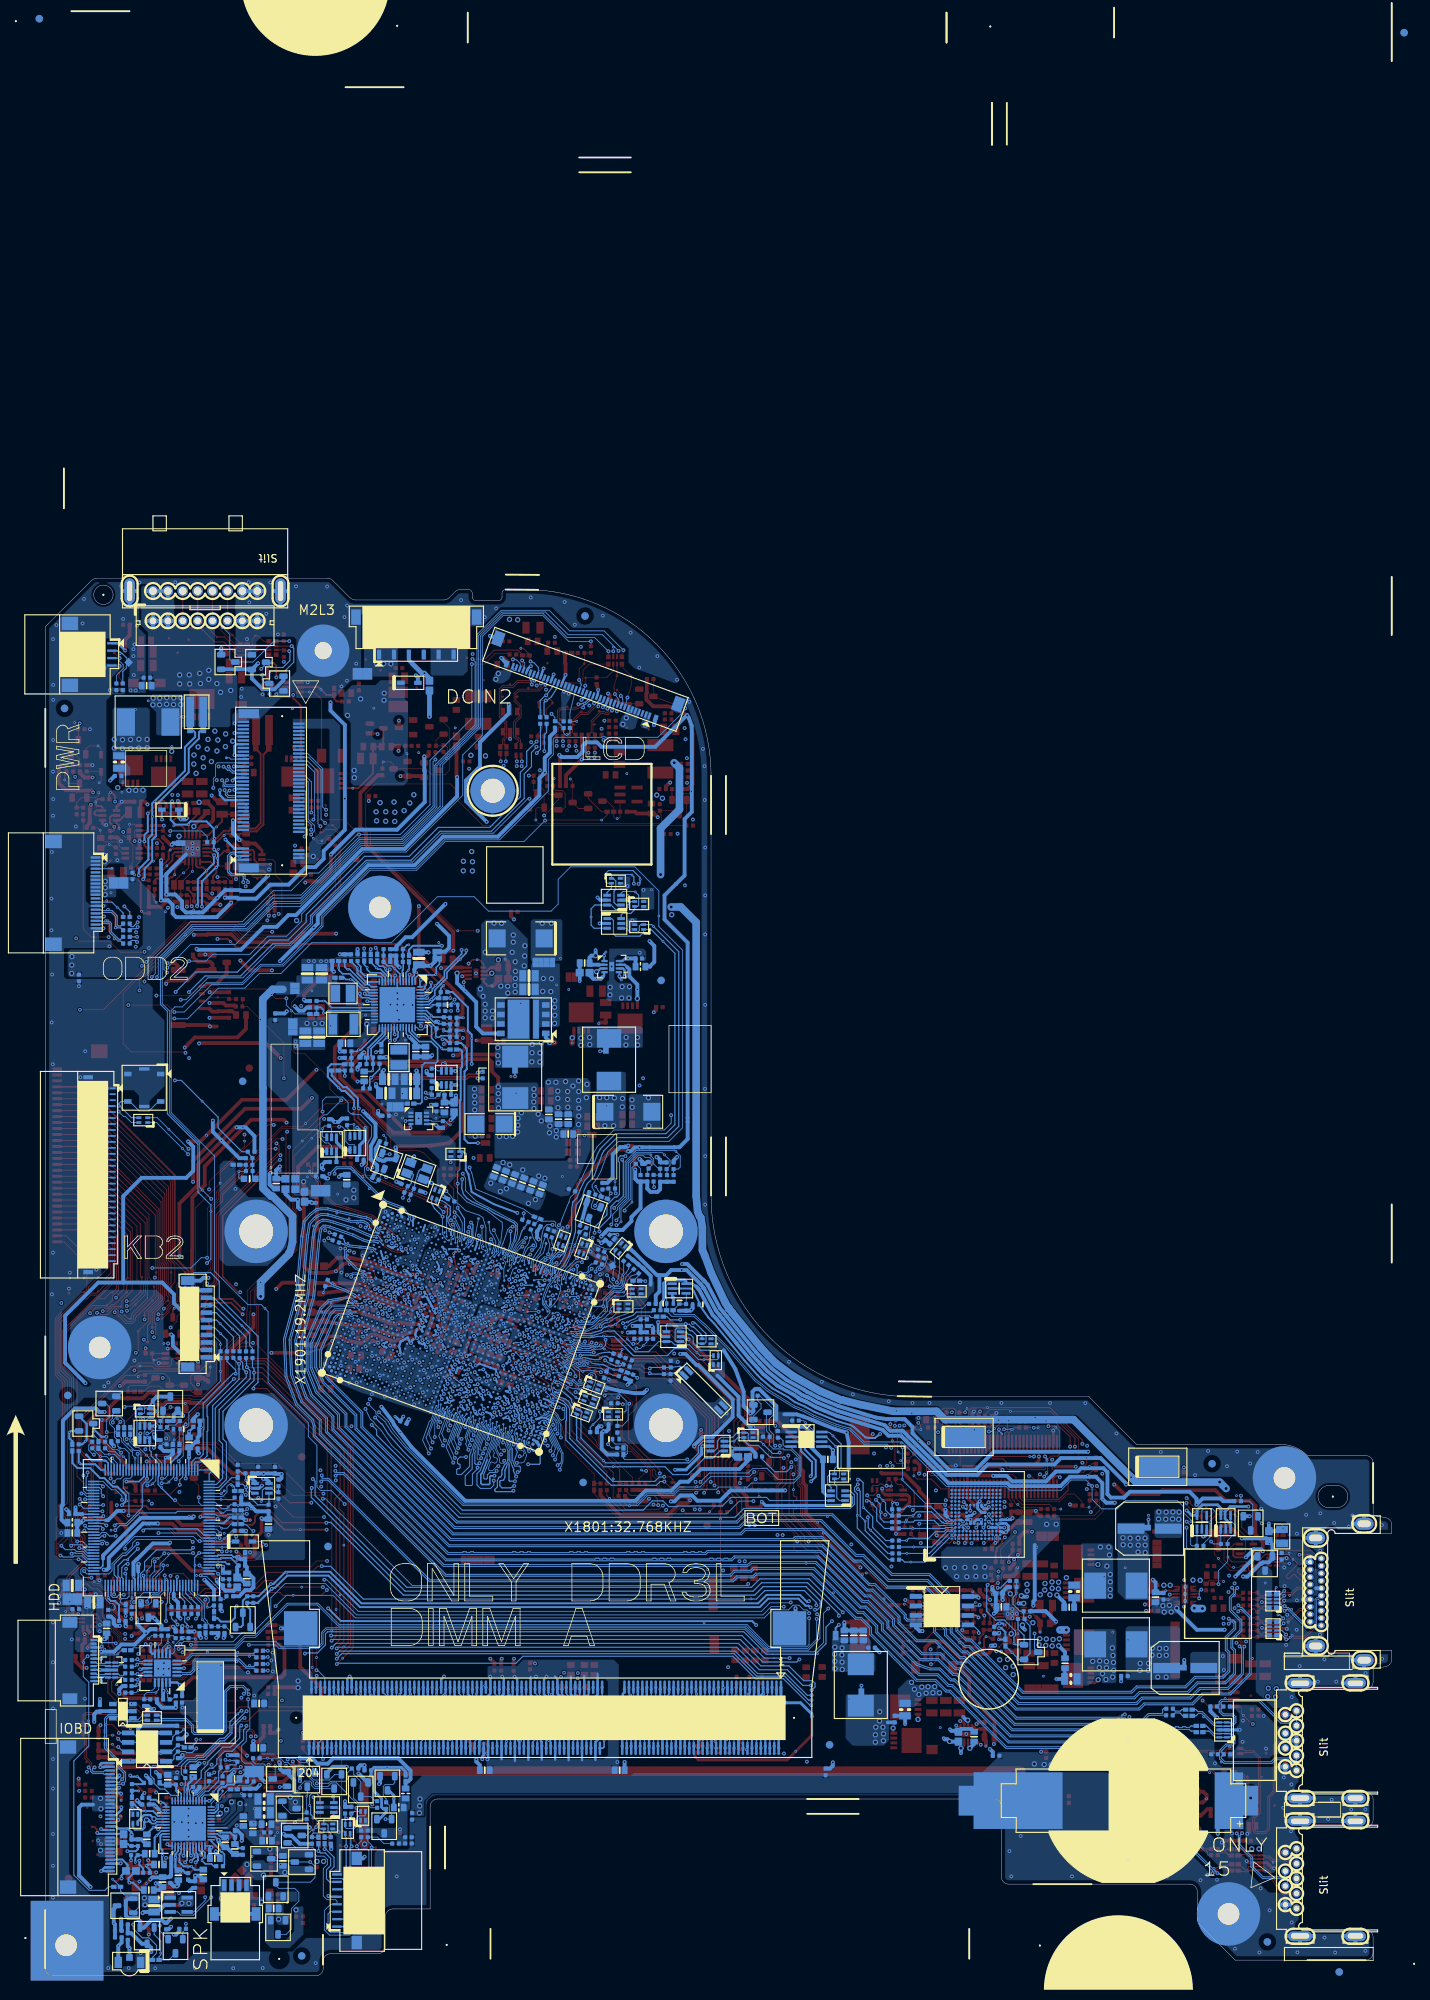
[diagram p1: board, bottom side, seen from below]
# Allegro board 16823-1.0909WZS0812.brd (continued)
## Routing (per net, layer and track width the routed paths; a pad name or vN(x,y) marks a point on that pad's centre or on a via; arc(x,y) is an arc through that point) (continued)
PMIC_THERMTRIP#: length 234.1
  TOP w0.102: v2(148.34,131.14) 149.82,131.14 v1(150.31,131.63) 151.09,132.41 158.93,132.41 159.09,132.26 160.25,132.26 160.97,131.55 165.77,131.55 v2(165.79,131.52) ; v2(108.01,96.32) 108.03,96.29 108.75,96.29 109.15,95.89 109.2,95.89 109.46,95.63 109.95,95.63 R1819.1
  L3 w0.102: v2(108.01,96.32) 108.01,97 107.83,98.36 107.83,98.97 107.68,99.77 107.62,99.96 107.54,100.17 107.45,100.26 107.12,100.82 107.12,100.82 107.08,100.89 107.03,100.95 106.77,101.44 106.47,101.98 106.31,102.19 106.15,102.35 105.68,104.16 105.51,104.6 104.8,106.23 104.66,106.37 103.69,107.76 102.57,109.38 102.22,110.26 102.04,110.44 101.58,111.9 101.18,112.31 101.18,118.52 100.46,119.23 v2(100.46,120.42)
  L4 w0.102: v2(108.01,96.32) 108.11,96.22 108.82,96.22 109.15,95.89 109.63,95.89 110.25,95.27 111.83,94.31 112.58,94.31 113.8,94 116.31,91.49 v2(117.2,91.49) ; v2(165.79,131.52) 165.79,98 163.36,95.57 163.35,95.53 163.35,90.23 163.1,89.97 163.1,89.57 162.49,88.96 162.49,84.12 162.54,84.07 162.54,83.44 162.72,83.26 162.72,82.02 162.72,79.3 162.87,79.15 162.87,74 162.76,73.89 162.76,73.61 162.36,73.21 162.36,67.03 162.31,66.98 162.31,66.27 162.22,66.18 162.22,64.71 162.45,64.48 162.45,62.33 162.47,62.32 162.47,60.93 162.17,60.64 162.17,57.18 161.86,56.86 161.86,54.52 161.51,54.18 161.51,48.22 161.53,48.21 v2(161.53,47.93) ; v2(100.46,120.42) 100.36,120.42 95.99,124.79 95.99,143.94 96.27,144.22 125.97,144.22 131.12,139.07 132.82,139.07 135.82,136.07 142.22,136.07 145.12,133.17 146.31,133.17 v2(148.34,131.14)
  BOTTOM w0.102: v2(148.34,131.14) 148.34,130.23 147.18,129.06 PR5041.2 ; v2(161.53,47.93) 161.09,48.36 R2412.2 ; v2(117.2,91.49) 117.03,91.32 CPU1.J47
PMIC_THERMTRIP#_KBC: length 3.4
  BOTTOM w0.102: R2412.1 161.09,49.86 162.25,51.02 KBC24.91
PMU_RCOMP: length 2.1
  TOP w0.203: v2(112.62,81.47) v1(112.08,81.31) R2002.2
  BOTTOM w0.203: CPU1.AG59 112.65,81.54 112.62,81.5 v2(112.62,81.47)
PQ3802_1: length 3.1
  TOP w0.102: PQ4302.B 132.07,163.9 v1(132.16,163.98) 132.4,164.23 PR4302.1 PR4309.2
PQ3809_D: length 10.9
  TOP w0.127: PQ4306.3 v1(145.28,172.25) 144.62,172.25 143.62,171.25 143.62,163.71
PQ4408_2: length 9.2
  TOP w0.102: PQ4408.2 164.92,153.67 PC4425.1 164.23,152.99 v1(163.99,152.99) 163.86,153.11 163.86,153.55 v2(163.93,153.61)
  BOTTOM w0.102: v2(163.93,153.61) 159.74,153.61 158.97,152.85 PR4437.2
PQ4408_6: length 2.3
  TOP w0.102: PQ4408.6 168.53,154.32 168.71,154.51 v1(169.4,154.51) 169.43,154.48 PR4426.1
PQ4409_C: length 26.7
  TOP w0.102: PQ4409.C 176.26,167.2 PR4464.1 176.32,167.6 176.08,167.85 v2(176.08,168.05) 176.18,168.15 v1(176.77,168.15) ; PR4475.1 v2(165.72,151.97)
  L3 w0.102: v2(165.72,151.97) 167.06,153.32 169.2,153.32 171.2,155.32 173.46,155.32 175.8,157.67 175.8,167.77 v2(176.08,168.05)
PQ4409_E: length 4.5
  TOP w0.102: PR4469.2 PR4470.1 176.07,163.21 176.75,163.9 PQ4409.E 177.34,163.9 177.88,163.35 v1(178.37,163.35)
PQ4410_2: length 3.8
  TOP w0.102: PR4475.2 165.72,150.01 v1(166.17,149.56) 166.48,149.56 166.73,149.81 PR4476.2 166.92,150.62 PQ4410.2
PQ4410_3: length 2.5
  TOP w0.102: PQ4410.3 168.08,149.4 168.3,149.19 PR4466.1 168.3,148.5 168.71,148.08 v1(168.71,147.73)
PQ4410_5: length 4
  TOP w0.102: PQ4410.5 170.35,150.62 171.13,151.4 PR4471.2 171.5,151.4 171.89,151.79 v1(172.12,151.79) 172.47,151.79 172.93,151.34 PC4434.1
PQ4410_6: length 6.2
  TOP w0.102: PR4473.1 173.65,154.03 v1(173.34,153.71) 173.26,153.63 PC4434.2 173.26,152.61 172.8,152.15 171.08,152.15 170.77,151.84 170.77,151.59 170.46,151.27 PQ4410.6
PQ4414_D: length 3.4
  TOP w0.102: PR4465.2 178.09,161.36 v1(178.09,160.45) 177.62,159.98 PQ4414.D
PQ4414_G: length 5.3
  TOP w0.102: v1(173.51,158.75) 173.51,158.47 173.91,158.08 PQ4414.G 175.84,158.08 176.51,157.41 176.51,156.76 PR4474.1 PC4433.2
PRO_SP: length 38.5
  TOP w0.102: v2(145.14,15.27) 145.14,16.87 144.79,17.22 v1(144.79,21.16) 144.79,21.26 146.3,22.77 147.35,22.77 147.93,23.35 R2926.1 149.64,23.35 150.26,23.96 150.74,23.96 R2924.1
  BOTTOM w0.102: Q2904.C 148.38,5.55 147.68,6.25 147.68,6.26 147.68,9.01 146.67,10.02 146.67,11.18 147.23,11.74 149.36,11.74 149.77,12.14 Q2905.C 145.1,12.56 144.51,13.16 144.51,14.68 145.09,15.27 v2(145.14,15.27) Q2903.C 147.37,15.42 150.11,15.42 Q2902.C
PROCHOT#_CPU_R: length 15.9
  TOP w0.102: v2(113.67,93.32) v1(113.11,93.32) 111.92,93.32 111.61,93.63 111.48,94 111.48,95.88 111.79,96.2 111.94,96.2 112.33,96.58 112.33,96.91 111.88,97.58 111.26,99.4 v2(111.26,100.33)
  BOTTOM w0.102: v2(113.67,93.32) 114.39,93.42 114.54,93.42 114.69,93.4 CPU1.E47 ; v2(111.26,100.33) 111.31,100.28 111.91,100.28 111.96,100.3 112.2,100.53 112.2,101.06 112.38,101.25 113.94,101.25 R1809.2 R1815.1
PROJECT_ID1: length 18.2
  L4 w0.102: v2(101.79,84.79) 101.99,84.99 102.49,84.99 103.68,86.18 103.68,86.24 105.26,87.82 108.45,87.82 109.65,89.02 112.74,89.02 113.37,88.38 v2(113.38,87.73)
  BOTTOM w0.102: v1(102.57,85.47) 102.57,85.4 101.96,84.79 v2(101.79,84.79) 101.23,84.79 100.8,85.21 R2019.2 R2020.1 ; v2(113.38,87.73) CPU1.T55
PROJECT_ID2: length 10.3
  BOTTOM w0.102: v1(155.63,45.49) 155.96,45.82 155.96,46.36 156.48,46.88 R2441.2 R2443.1 C2418.1 158.44,46.88 158.96,47.4 158.96,47.61 159.35,48.01 159.35,49.95 161.05,51.65 KBC24.94
PS_ID: length 5.3
  TOP w0.102: PQ4301.S 127.41,166.61 128.26,165.75 PR4306.2 127.34,165.03 PR4305.1 127.02,165.11 126.73,164.82 126.73,163.5 v1(126.91,163.32)
PS_ID_R: length 8.4
  TOP w0.508: DCIN1.4 131.9,176.5 131.25,175.85
  TOP w0.635: v2(129.83,174.78) 130.18,174.78 AFTP4312.1 131.25,175.85
  BOTTOM w0.508: 131.48,176.1 131.9,176.52 DCIN1.4
  BOTTOM w0.635: 131.48,176.1 130.16,174.78 v2(129.83,174.78) 129.14,174.09 PR4317.1
PS_ID_R2: length 3.5
  BOTTOM w0.635: PR4317.2 v2(129.14,168.96)
  vias: v1(130.59,164.11)
PSID: length 142.5
  TOP w0.102: PD4302.3 128.34,162.13 v2(128.34,163.2) PR4304.2 128.28,164.23 PR4305.2 ; v2(160,55.07) v1(160.61,55.07)
  L4 w0.102: v2(160,55.07) 160.32,55.07 161.63,56.38 161.63,56.96 161.95,57.28 161.95,60.73 162.24,61.02 162.24,62.22 162.22,62.24 162.22,63.9 161.42,64.7 161.42,66.91 162.14,67.62 162.14,73.31 162.54,73.71 162.54,73.99 162.64,74.1 162.64,79.05 162.49,79.2 162.49,82.11 162.49,83.16 162.31,83.34 162.31,83.98 162.26,84.03 162.26,89.05 162.87,89.66 162.87,90.07 163.13,90.32 163.13,95.66 165.36,97.89 165.36,133.63 v2(165.72,133.99)
  BOTTOM w0.102: KBC24.99 159.66,54.72 v2(160,55.07) ; v2(165.72,133.99) 165.72,134.12 165.54,134.3 165.54,136.52 161.03,141.02 154.09,141.02 150.11,145 146.38,145 138.7,152.68 132.93,152.68 128.66,156.96 128.66,162.88 v2(128.34,163.2)
PSID_DISABLE#_R_C: length 18.3
  TOP w0.102: PR4303.2 135.47,162.74 v1(135.34,162.87) 134.32,162.87 133.98,162.52 PQ4302.C 129.6,161.95 128.79,161.14 127.06,161.14 126.47,161.72 126.47,167.41 127.25,168.19 PQ4301.G
PSL_IN1#: length 4
  BOTTOM w0.102: KBC24.73 169.45,50.93 169.75,50.63 170.54,50.63 v1(170.59,50.58) 170.59,50.14 170.27,49.82 R2500.2
PSL_IN2#: length 7.2
  BOTTOM w0.102: R2489.1 R2499.2 159.19,47.34 v1(159.62,47.77) 159.67,47.82 159.67,49.89 161.45,51.67 KBC24.93
PSL_OUT#: length 3
  BOTTOM w0.102: R2493.1 169.1,49.79 169.22,49.91 169.22,50.32 169.05,50.49 v1(169.05,50.7) KBC24.74
PTP_DIS#: length 107.5
  TOP w0.102: v2(167.44,29.8) 167.43,29.79 166.76,29.79 166.16,29.19 164.81,29.19 163.69,28.07 161.14,28.07 160.16,29.05 159.11,29.05 v2(158.38,28.32) ; v2(138.89,17.38) 138.89,17.78 AFTP6526.1 139.28,20.07 138.95,20.4 v2(138.95,22.53)
  L4 w0.102: v2(158.38,28.32) 156.98,28.32 155.48,26.82 154.11,26.82 149.69,22.41 139.07,22.41 v2(138.95,22.53) ; v2(167.44,29.8) 167.44,30.12 167.65,30.32 167.65,33.23 169.17,34.75 169.17,37.82 172.19,40.85 172.55,40.85 174.15,42.45 175.2,42.45 175.46,42.7 175.46,43.64 174.95,44.15 174.95,52.03 175.45,52.53 175.45,53.72 174.16,55 174.16,58.64 174.05,58.76 174.05,60.95 174.12,61.03 174.12,63.29 174.04,63.38 174.04,69.79 v2(174.18,69.93)
  BOTTOM w0.102: R6509.2 138.3,18.07 138.89,17.48 v2(138.89,17.38) 138.89,17.3 138.59,16.99 137.47,16.99 137.27,16.79 137.27,8.46 139.94,5.79 142.43,5.79 142.76,6.12 142.76,8.31 142.46,8.6 TP1.3 ; R2494.1 174.86,71.21 174.86,70.5 174.29,69.93 v2(174.18,69.93)
PURE_HW_SHUTDOWN#: length 170
  TOP w0.14: v2(165.08,50.17) 165.06,50.14 165.06,49.72 R2405.2 166.15,49.47 EC2403.1 ; Q2602.D 161.91,76.01 163.22,76.01 163.53,76.31 v2(163.88,76.31) 164.24,75.95 164.87,75.95 164.89,75.93 165.14,75.93 R2603.1 ; v2(143.59,54.97) 143.62,54.94 144.15,54.94 144.97,54.13 v1(148.29,54.13) 150.89,54.13 152.56,52.45 160.69,52.45 162.21,53.97 163.59,53.97 v2(163.89,53.67) 163.89,52.15 164.31,51.72 165.7,51.72 166.17,52.2 R2404.1 167.05,52.2 C2605.1
  L4 w0.127: v2(77.22,49.73) 74.38,52.57 62.31,52.57 60.87,51.12 60.87,48.98 57.09,45.21 48.65,45.21 v2(47.94,45.93) ; v2(163.88,76.31) 163.8,76.23 163.8,74.64 163.8,74.06 163.8,73.62 163.69,73.51 163.69,73.23 163.3,72.84 163.3,71.54 163.34,71.51 163.34,69.51 163.35,69.5 163.35,68.59 163.8,68.14 163.8,65.86 164.23,65.43 164.23,63.42 164.23,63.37 164.31,63.3 164.31,61.19 164.3,61.18 164.3,60.83 164.31,60.49 164.31,58.68 164.8,58.19 164.8,57.82 164.23,57.25 164.23,55.95 163.61,55.33 163.61,53.81 163.75,53.67 v2(163.89,53.67) 163.89,51.36 v2(165.08,50.17)
  BOTTOM w0.14: v2(77.22,49.73) 77.22,49.74 77.22,50.08 78.83,51.68 84.14,51.68 85.27,50.55 138.02,50.55 142.41,54.94 143.57,54.94 v2(143.59,54.97) ; Q2401.B 165.69,50.17 v2(165.08,50.17) ; v2(47.94,45.93) 47.94,43.93 D4001.3
PWR_1D05V: length 8.1
  TOP w0.508: 142.55,128.4 142.55,134.14 v2(141.97,134.72)
  BOTTOM w0.508: PR5023.2 142.21,134.96 v2(141.97,134.72)
  vias: v1(142.43,127.46) v3(143.54,127.78) v3(144.51,127.76) v3(145.57,127.79)
PWR_1D8V:
  vias: v1(135.52,116.97)
PWR_1D8V_FB: length 15.5
  BOTTOM w0.203: PR5010.1 130.36,117.02 130.14,117.24 v1(130.14,122.11) 130.14,122.11 129.77,122.48 128.28,122.48 128.05,122.71 128.05,124.49 128.91,125.35 130.51,125.35 131.86,126.7 PU5001.37
PWR_1D8V_PH:
  vias: v1(132.39,125.55)
PWR_1D24V:
  vias: v1(144.91,132.16)
PWR_1D24V_FB: length 5.3
  BOTTOM w0.203: PU5001.16 137.27,131.9 137.6,132.23 137.6,132.23 137.63,132.26 138.11,132.26 139.53,133.68 v1(139.73,133.68) 140.37,133.68 140.6,133.91 PR5017.1
PWR_1D24V_PH:
  vias: v1(138.03,130.38)
PWR_3D3V_CS2: length 3.3
  TOP w0.203: 52.49,49.74 PU4503.5
  TOP w0.254: PR4517.1 54.19,51.79 53.62,51.22 v1(53.62,51.18) 52.69,50.25 52.69,50.23 52.49,50.03 52.49,49.74
PWR_3D3V_DRVH2: length 16.3
  TOP w0.203: PU4503.10 50.13,50.59 v3(49.72,51.01)
  TOP w0.406: PU4504.4 v3(39.43,55.19)
  L3 w0.762: v3(49.72,51.01) 49.87,51.16 49.87,52.84 47.26,55.45 39.69,55.45 v3(39.43,55.19)
  BOTTOM w0.508: v3(49.72,51.01) 49.59,50.88 v1(48.93,50.88)
PWR_3D3V_DRVL2: length 9.5
  TOP w0.203: v3(49.38,49.96) 49.38,49.96 PU4503.11
  L3 w0.762: v3(49.38,49.96) 49,49.96 48.08,50.89 48.08,52.34 46.69,53.72 43.97,53.72 v3(43.67,53.42)
  BOTTOM w0.508: v1(50.1,49.96) v3(49.38,49.96)
PWR_3D3V_EN2: length 12.1
  TOP w0.203: 52.26,51.11 52.15,51.01 52.01,50.89 51.73,50.61 PU4503.6
  TOP w0.254: 52.26,51.11 52.56,51.41 52.97,51.41 53.6,52.05 PR4503.2 52.98,52.71 v2(52.84,52.71) v1(52.84,53.6) ; PR4506.2 PC4501.1 50.87,56.86 51.39,56.34 v2(51.39,55.5)
  L3 w0.254: v2(51.39,55.5) 52.74,55.5 53.3,54.94 53.3,54.07 52.84,53.61 v2(52.84,52.71)
PWR_3D3V_FB2: length 5.6
  TOP w0.203: PU4503.4 53.06,48.99 53.2,49.12
  TOP w0.254: PC4523.2 53.93,48.36 54.22,48.66 PR4512.2 54.22,49.19 54.62,49.58 PR4523.1 53.77,49.93 v1(53.65,49.81) 53.65,49.58 53.2,49.12
PWR_3D3V_FB2_R: length 2.8
  TOP w0.254: v1(55.32,44.65) 55.32,45.4 54.77,45.94 PR4535.2 PC4523.1
PWR_3D3V_LL2: length 19.4
  TOP w0.203: PU4503.8 50.93,51.01 v3(51.19,51.26)
  TOP w0.508: v3(51.19,51.26) 51.19,51.34 51.65,51.8 PC4535.2
  L3 w0.762: v3(51.19,51.26) 51.01,51.44 51.01,53.14 47.63,56.52 39.32,56.52 38.23,55.43 v3(38.23,54.97)
  vias: v1(38.59,53.55) v3(37.78,53.85) v3(37.78,52.86) v3(37.78,51.84) v3(37.78,50.95) v3(37.88,56.47) v3(37.97,57.52) v3(39.1,57.53)
PWR_3D3V_SNUB: length 1.3
  BOTTOM w0.508: PR4533.2 PC4520.1
PWR_3D3V_VBST2: length 2.3
  TOP w0.203: PU4503.9 50.53,50.67 50.38,50.83 v1(50.38,51.34)
  TOP w0.508: v1(50.38,51.34) 50.38,52.38 PR4528.2
PWR_3D3V_VBST2_1: length 2.5
  TOP w0.508: PC4535.1 51.16,53.52 50.96,53.72 PR4528.1 50.35,54.6 v1(50.2,54.75)
PWR_5V_CS1: length 2.2
  TOP w0.203: PU4503.1 52.49,47.42 v2(52.64,47.27)
  BOTTOM w0.254: v1(51.98,47.07) 52.18,47.27 v2(52.64,47.27) 52.64,47.27 52.9,47.27 PR4531.1
PWR_5V_DRVH1: length 16.8
  TOP w0.203: v3(49.56,47.07) 49.59,47.04 PU4503.16
  TOP w0.406: v3(39.4,39.73) 39.43,39.73 39.82,39.34 PU4501.4
  L3 w0.762: v3(49.56,47.07) 49.56,45.21 46.9,42.55 43.14,42.55 40.32,39.73 v3(39.4,39.73)
  BOTTOM w0.508: v3(49.56,47.07) 49.56,46.76 v1(49.23,46.43)
PWR_5V_DRVL1: length 7.2
  TOP w0.203: PU4503.15 48.86,47.79 48.55,47.47 48.27,47.47 v3(48.17,47.37)
  L3 w0.762: v3(43.67,46.41) 47.2,46.41 v3(48.17,47.37)
  BOTTOM w1.016: v3(43.67,46.41) v1(44.53,46.41)
PWR_5V_EN1: length 4.1
  TOP w0.203: PU4503.20 52.03,47.04 52.43,46.64 v2(52.69,46.64)
  BOTTOM w0.254: v2(52.69,46.64) 52.36,46.64 51.85,46.13 PR4502.2 51.89,45.11 v1(52.76,45.11)
PWR_5V_FB1: length 8.4
  TOP w0.203: 53.35,47.93 53.09,48.19 PU4503.2
  TOP w0.254: 53.35,47.93 53.35,45.35 PR4526.1 53.78,45.19 54.08,45.49 v1(54.44,45.49) 54.72,45.21 54.72,43.86 PR4527.2 55.63,43.82 55.89,44.07 PC4522.2
PWR_5V_FB1_R: length 2.1
  TOP w0.254: v1(57.13,42.09) 57.13,42.75 57.35,42.97 PR4525.2 PC4522.1
PWR_5V_LL1: length 19.1
  TOP w0.203: PU4503.18 50.93,46.26 51.06,46.13 v3(51.06,45.9)
  TOP w0.508: PC4516.2 51.47,45.47 51.26,45.67 51.26,45.7 v3(51.06,45.9)
  L3 w0.762: v3(51.06,45.9) 50.6,45.44 50.6,44.82 47.32,41.53 43.56,41.53 40.74,38.71 38.98,38.71 38.36,39.34 v3(38.36,39.75)
  vias: v1(37.45,46.1) v3(37.35,42.04) v3(37.32,41) v3(37.42,42.98) v3(37.45,40.08) v3(37.5,43.99) v3(38.29,42.17) v3(38.29,41.33) v3(38.82,40.54) v3(39.2,42.24) v3(39.25,41.35) v3(40.14,42.19)
PWR_5V_SNUB: length 2.6
  BOTTOM w0.508: v1(45.02,39.83) PR4529.2 43.9,41.23 PC4536.1
PWR_5V_VBST1: length 2.3
  TOP w0.203: v1(50.2,45.9) 50.2,46.2 50.53,46.54 PU4503.17
  TOP w0.508: v1(50.2,45.9) PR4524.1
PWR_5V_VBST1_1: length 2.3
  TOP w0.508: PC4516.1 PR4524.2 v1(50.2,42.5)
PWR_5V_VCLK: length 3.5
  TOP w0.102: TP4501.1 52.15,44.66 52.15,45.33 52.15,45.33 52.15,45.85 51.33,46.67 PU4503.19
PWR_5V_VO1: length 62.1
  TOP w0.203: PU4503.14 v2(48.57,48.19)
  TOP w0.508: PR4525.1 55.94,43.23 55.86,43.16 54.21,43.16 53.87,43.5 PR4527.1 53.87,44.13 53.65,44.35 v2(53.22,44.35)
  L4 w0.508: v2(53.22,44.35) 51.11,44.35 44.64,37.87 30.49,37.87 27.85,40.52 v2(27.85,42.37) 27.85,44.6 31.53,48.29 48.48,48.29 v2(48.57,48.19)
  BOTTOM w0.508: PG4532.2 v2(27.85,42.37) ; v2(53.22,44.35) 53.27,44.3 v1(53.8,44.3)
PWR_CHG_ACDET: length 6.3
  TOP w0.254: PU4404.6 158.51,149.46 v1(157.74,148.69) 157.74,148.01 158.2,147.55 PR4431.1 PC4412.1 PR4407.2
PWR_CHG_ACN: length 18.9
  TOP w0.254: PG4403.2 151.8,163.98 151.8,154.64 152.51,153.93 153.32,153.93 PC4403.1 154.06,154.33 154.48,153.91 PC4402.2 PR4406.1 155.99,153.63 156.69,153.63 157.72,152.61 v1(157.97,152.61) 158.32,152.61 158.67,152.26 PU4404.1
PWR_CHG_ACOK: length 22.2
  TOP w0.254: PR4436.1 171.62,153.63 171.43,153.82 v2(171.43,154.15) 172.02,154.74 172.02,155.45 171.76,155.7 PQ4402.2 ; PR4439.2 164.45,157.3 164.75,157.61 165.97,157.61 v1(166,157.58) 166,156.9 v2(166.94,155.96) ; PR4476.1 167.05,151.32 167.4,151.67 v2(167.4,152.2) 167.4,152.55 166.94,153.01 166.18,153.01 PQ4408.3 166.17,152.73 165.95,152.5 165.51,152.5 164.9,151.89 PR4419.2
  L3 w0.254: v2(167.4,152.2) 167.4,152.34 167.82,152.76 170.23,152.76 171.43,153.96 v2(171.43,154.15)
  BOTTOM w0.254: v2(166.94,155.96) 166.94,153.52 167.4,153.06 v2(167.4,152.2)
PWR_CHG_ACP: length 19.4
  TOP w0.254: PG4402.2 151.42,163.86 151.42,154.48 152.35,153.55 153.42,153.55 PC4404.1 154.6,153.24 PC4402.1 PR4406.2 155.93,153.25 156.46,153.25 v1(156.69,153.02) 156.77,153.02 157.61,152.17 158.22,152.17 158.63,151.76 PU4404.2
PWR_CHG_BAT_SCL: length 3.7
  TOP w0.14: PG4407.1 163.43,146.81 162.27,147.98 162.15,147.98 v1(162.14,147.98) 161.44,148.68 PU4404.9
PWR_CHG_BAT_SDA: length 3.5
  TOP w0.14: PU4404.8 v1(160.94,148.19) 162.44,146.69 PG4408.1
PWR_CHG_BTST: length 3.7
  TOP w0.254: PU4404.17 v1(161.44,154.48) 161.44,154.67 160.41,155.7 PR4409.1
PWR_CHG_BTST_R: length 5.1
  TOP w0.508: v1(162.52,155.09) 161.96,155.09 v2(161.73,155.32) PR4409.2 161.72,156.28 PC4411.1
  BOTTOM w0.508: v2(161.73,155.32) 161.83,155.22 162.49,155.22 v1(162.52,155.25) 162.77,155.5 PD4401.K
PWR_CHG_CMPIN: length 15.2
  TOP w0.254: v2(160.33,143.51) 160.38,143.56 160.38,143.69 160.75,144.06 PR4414.2 PR4413.1 160.79,145.01 161.58,145.8 PR4411.2 ; PU4404.4 158.46,150.76 v2(158.05,150.34) v1(157.64,149.94) 156.67,150.9 PR4429.1 156.17,150.91 PR4427.2
  BOTTOM w0.254: v2(158.05,150.34) 158.07,150.32 158.07,149.28 160.23,147.12 160.23,143.64 160.33,143.54 v2(160.33,143.51)
PWR_CHG_CMPIN_R: length 2.6
  TOP w0.254: PQ4407.3 154.14,150.44 154.46,150.12 v1(154.63,150.12) 155.02,150.12 155.29,150.38 PR4429.2
PWR_CHG_CMPIN_RR: length 6.5
  TOP w0.254: v1(150.48,149.14) PQ4407.6 152.06,149.14 152.66,149.74 152.66,150.83 152.86,151.03 154.16,151.03 154.87,151.74 PR4427.1
PWR_CHG_CMPOUT: length 26.2
  TOP w0.254: PR4414.1 159.35,144.17 PR4432.1 PR4438.1 159.47,142.98 159.67,143.18 v2(159.67,143.46) ; v1(157.46,151.16) 157.51,151.11 v2(158.02,151.11) 158.17,151.26 PU4404.3 ; v2(163.68,157.61) 163.56,157.48 PR4430.2
  BOTTOM w0.254: v2(163.68,157.61) 163.86,157.43 163.86,155.09 163.23,154.46 161.65,154.46 161.22,154.89 159.06,154.89 158.08,153.91 PR4437.1 158.08,151.17 v2(158.02,151.11) 157.54,150.62 157.54,148.97 159.67,146.84 v2(159.67,143.46)
PWR_CHG_CSON_1: length 25.8
  TOP w0.254: PR4420.2 166.68,147.77 PC4421.2 167.6,147.64 167.6,147.14 v2(167.57,147.12) 167.43,146.98 PC4423.1
  BOTTOM w0.254: v2(167.57,147.12) 167.57,147.14 167.37,147.35 167.37,148.54 166.35,149.56 166.35,152.4 165.84,152.91 165.84,157.08 v1(162.36,160.56) 161.45,161.47 161.45,164.64 160.08,166.01 160.08,166.85 159.87,167.06 PG4410.1
PWR_CHG_CSOP_1: length 31.2
  TOP w0.254: PR4421.2 167.41,148.59 PC4421.1 168.16,147.97 v2(168.16,147.68) 168.16,146.98 167.89,146.72 167.89,142.94 v1(167.77,142.83) 167.51,142.56 PC4420.1
  BOTTOM w0.254: v2(168.16,147.68) 168.16,148.08 168.13,148.11 168.13,148.5 166.87,149.76 166.87,152.61 166.35,153.12 166.35,157.29 161.96,161.68 161.96,164.84 160.59,166.22 160.59,166.8 160.84,167.06 PG4409.1
PWR_CHG_HIDRV: length 15.2
  TOP w0.305: v3(160.76,154.21) 160.94,154.03 PU4404.18
  TOP w0.508: v3(160.76,154.21) 160.76,154.31 159.06,156.01 PC4413.2
  L4 w0.508: v3(163.74,164.29) 163.48,164.04 163.48,159.95 160.76,157.23 v3(160.76,154.21)
  vias: v1(163.71,164.95)
PWR_CHG_IFAULT: length 5.5
  TOP w0.254: PR4418.2 166,146.99 165.77,147.22 165.11,147.22 v1(164.75,147.58) 164.43,147.58 163.89,148.12 163.89,148.67 162.74,149.81 PU4404.11
PWR_CHG_ILIM: length 5
  TOP w0.254: PR4417.2 PR4423.1 164.32,146.97 163.9,147.39 163.69,147.39 v1(163.34,147.74) 163.34,148.46 162.34,149.46 PU4404.10
PWR_CHG_IOUT: length 6.3
  TOP w0.254: PR4411.1 PR4424.1 PC4422.1 PR4422.1 159.04,148.24 v1(159.06,148.26) 159.52,148.72 160.26,148.72 160.44,148.9 PU4404.7
PWR_CHG_LODRV: length 11.8
  TOP w0.305: v3(162.75,152.91) 162.75,152.76 162.74,152.76 PU4404.15
  L4 w0.508: v3(170.97,159.41) 170.97,159.08 164.8,152.91 v3(162.75,152.91)
  vias: v1(170.42,158.8)
PWR_CHG_PHASE: length 20.7
  TOP w0.305: PU4404.19 160.44,153.56 160.02,153.99
  TOP w0.508: 160.02,153.99 159.72,154.28 158.94,154.28 158.17,155.04 158.17,156.64 158.99,157.46 PC4413.1 v3(160.05,157.46) 160.15,157.36 PC4411.2
  L4 w0.508: v3(160.05,157.46) 162.85,160.25 162.85,164.44 163.43,165.03 166.76,165.03 v3(167.01,164.77)
  vias: v1(168.59,169.93) v3(167.04,165.89) v3(168.13,165.91) v3(168.13,164.75) v3(169.25,165.86) v3(169.25,164.67) v3(170.34,165.84) v3(170.34,164.67) v3(171.43,165.89) v3(171.43,164.72)
PWR_CHG_REGN: length 9.4
  TOP w0.254: v2(165.03,155.15) 165.31,155.42 PR4425.1 PR4439.1 163.58,156 PR4430.1 PC4407.1 162.72,155.81 163.48,155.04 163.48,154.33 v1(163.46,154.31) 162.41,154.31 161.94,153.83 PU4404.16
  BOTTOM w0.254: v2(165.03,155.15) 165.06,155.17 PD4401.A
PWR_CHG_SRN: length 4.7
  TOP w0.254: PR4420.1 165.54,147.78 v1(164.39,148.93) 163.63,149.68 163.63,150.42 163.3,150.76 PU4404.12
PWR_CHG_SRP: length 4.8
  TOP w0.254: PU4404.13 163.5,151.26 163.51,151.25 163.74,151.25 v1(163.94,151.06) 164.14,150.85 164.14,149.81 165.36,148.59 PR4421.1
PWR_CHG_VCC: length 6.3
  TOP w0.254: PU4404.20 158.81,153.06 v1(157.72,154.15) 156.98,154.89 PR4408.2 PC4410.1
PWR_COMP2: length 4.4
  BOTTOM w0.203: PU5001.44 129.53,129.5 v1(128.91,128.88) 128.65,128.61 PC5033.2 126.45,128.61 PC5016.2
PWR_CSDIS1: length 5.4
  BOTTOM w0.203: PR5021.1 138.79,135.84 138.36,135.41 138.36,134.7 v1(137.75,134.09) 135.67,134.09 135.46,133.88 PU5001.12
PWR_CSDIS2: length 5.4
  BOTTOM w0.203: PU5001.13 137.68,133.35 138.83,134.51 v1(138.83,135.26) 139.66,136.08 PR5036.1
PWR_DCBATOUT_3D3V:
  vias: v1(47.63,57.48)
PWR_DCBATOUT_5V:
  vias: v1(46.74,40.21)
PWR_DCBATOUT_VCCGI:
  vias: v1(112.07,132.95) v3(112.33,130.84) v3(112.33,128.88) v3(112.35,129.95) v3(112.35,127.79) v3(112.76,133.78) v3(112.86,132.06) v3(113.85,133.81) v3(113.95,132.08)
PWR_DCBATOUT_VDDQ:
  vias: v1(60.59,33.3)
PWR_DCBATOUT_VNN:
  vias: v1(110.45,132.34)
PWR_DDRSEL: length 8.1
  BOTTOM w0.203: PR5029.2 v1(143.36,130.79) 143.14,130.79 142.25,129.9 PU5001.21
PWR_FB2: length 6.4
  BOTTOM w0.203: PU5001.43 129.69,129.1 129.69,129.09 129.08,128.48 129.06,128.48 128.59,128.01 PR5032.2 127.92,127.73 PC5033.1 126.45,127.73 PR5020.1 PC5014.2 126.46,126.75 v1(127.29,126.75)
PWR_IRQ#: length 6.6
  BOTTOM w0.203: PU5001.41 129.83,128.3 128.86,127.33 128.86,125.81 v1(127.49,124.44) 127.34,124.28 PR5043.1
PWR_ISENSEN2: length 5.8
  BOTTOM w0.203: PU5001.28 135.46,126.72 135.42,126.68 135.42,126.42 136.25,125.6 137.4,124.45 v1(137.4,124.39) 137.4,123.41 PR5113.2 PC5029.1
PWR_ISENSEP2: length 7.9
  BOTTOM w0.203: PU5001.29 135.06,126.7 135.09,126.66 135.09,126.29 136.01,125.37 136.96,124.42 136.96,123.46 PR5110.2 PR5111.1 136.72,121.48 v1(136.76,121.44) 136.86,121.34 PC5106.1
PWR_OCSET6: length 5.9
  BOTTOM w0.203: PU5001.14 136.95,132.7 137.24,133 137.8,133 139.86,135.05 v1(140.09,135.05) 140.19,135.05 140.52,135.38 PR5024.1
PWR_PMIC_EN: length 3.5
  BOTTOM w0.203: PR5045.1 PR5033.1 128.63,130.3 v1(128.81,130.13) 129.04,129.9 129.44,129.9 129.44,129.9 PU5001.45
PWR_PWROK: length 6.7
  TOP w0.203: v2(130.59,126.11) 129.02,126.11 128.11,127.02 v1(127.23,127.02) 127.2,127.02 126.42,126.24 PR5042.1
  BOTTOM w0.203: v2(130.59,126.11) 130.81,126.11 131.46,126.76 PU5001.38
PWR_RSMEST#: length 2.7
  BOTTOM w0.203: PR5040.1 135.59,125.2 v1(134.93,125.86) 134.66,126.13 PU5001.30
PWR_SLP_S0#: length 3.9
  BOTTOM w0.203: PR5038.1 136.15,135.77 135.85,135.46 135.36,135.46 v1(135.03,135.13) 135.03,134.9 134.26,134.13 PU5001.9
PWR_SLP_S3#: length 4
  BOTTOM w0.203: PR5039.1 137.01,135.99 v1(136.28,135.25) 136.08,135.05 135.7,135.05 134.66,134.01 PU5001.10
PWR_SLP_S4#: length 4.8
  BOTTOM w0.203: PR5037.1 137.9,135.69 v1(137.5,135.28) 137.5,135 137.07,134.57 135.69,134.57 135.06,133.94 PU5001.11
PWR_THERMTRIP#: length 9.4
  BOTTOM w0.203: PR5041.1 PR5044.2 144.27,129.95 143.72,129.95 143.36,129.59 v1(143.36,129.16) 143.09,129.16 142.74,129.5 PU5001.22
PWR_VCC: length 19.8
  TOP w0.508: PC5028.1 133.42,133.9 v2(133.74,134.22) ; v2(145.98,130.96) 145.98,131.65 142.02,135.61 139.53,135.61 v1(138.73,134.81) 138.21,134.29 133.86,134.29 133.79,134.22 v2(133.74,134.22) ; PR5031.2 133.84,134.32 v2(133.74,134.22)
  BOTTOM w0.203: PU5001.8 133.86,134.09 v2(133.74,134.22)
  BOTTOM w0.508: v2(145.98,130.96) 145.8,130.79 PR5029.1
PWR_VCCGI_BOOT: length 3.1
  TOP w0.305: PU5107.4 121.86,133.36 121.32,132.82 v1(120.76,132.82)
  TOP w0.508: PR5109.1 119.9,133.53 120.61,132.82 v1(120.76,132.82)
PWR_VCCGI_BOOT_A: length 2.8
  TOP w0.508: v1(118.98,136.43) 118.57,136.02 PC5121.1 PR5109.2
PWR_VCCGI_EN: length 23.4
  TOP w0.203: v2(123.88,135.82) 123.38,136.32 v1(122.74,136.32) 122.44,136.32 121.86,135.75 PU5107.1
  L4 w0.203: v2(133.79,125.55) 134.3,126.06 134.3,126.52 133.48,127.33 132.61,127.33 130.51,129.43 130.51,131.85 130.08,132.29 124.59,132.29 123.88,133 v2(123.88,135.82)
  BOTTOM w0.203: PU5001.33 133.46,126.72 133.36,126.62 133.36,125.99 v2(133.79,125.55)
PWR_VCCGI_HG: length 18.3
  TOP w0.305: PU5107.3 121.19,134.27 120.94,134.52 v3(120.78,134.52)
  TOP w0.762: v3(113.01,125.22) v1(112.35,125.22)
  L3 w0.762: v3(120.78,134.52) 120.5,134.24 120.5,132.46 118.98,130.94 114.76,130.94 113.37,129.54 113.37,125.73 113.01,125.38 v3(113.01,125.22)
  BOTTOM w0.508: PU5105.1 113.53,125.9 113.01,125.38 v3(113.01,125.22)
PWR_VCCGI_ISEN: length 19.7
  TOP w0.203: v2(136.99,120.5) 136.86,120.63 128.85,120.63 124.27,120.63 123.92,120.98 122.87,120.98 v2(122.66,121.19) v1(122.11,121.19)
  BOTTOM w0.203: PR5108.1 137.15,120.33 v2(136.99,120.5) 135.83,121.66 PR5111.2 ; v2(122.66,121.19) 122.55,121.3 PR5107.1
PWR_VCCGI_LG: length 13.5
  TOP w0.305: PU5107.7 124.5,134.77 124.57,134.7 125.25,134.7 v3(125.43,134.52)
  BOTTOM w0.508: v3(125.43,134.52) 125.43,133.2 v1(124.34,132.11) 122.87,130.63 122.87,127.33 121.98,126.44 PU5105.8
PWR_VCCGI_PH: length 37.5
  TOP w0.305: 120.73,135.28 120.94,135.28 121.45,134.77 PU5107.2
  TOP w0.508: 120.73,135.28 PC5121.2 v3(119.9,136.32) ; v3(119.97,123.45) 120.15,123.62 124.15,123.62 125.05,122.72 134.23,122.72 134.81,123.29 v2(134.96,123.29)
  L3 w0.762: v3(119.9,136.32) 120.23,136.32 121.14,135.41 121.15,135.41 121.67,134.89 121.67,134.11 121.39,133.83 121.39,132.09 119.35,130.05 115.13,130.05 114.31,129.22 114.31,125.3 v3(114.15,125.15)
  BOTTOM w0.508: v2(134.96,123.29) 135.03,123.22 PR5110.1
  vias: v1(116.9,130.48) v3(114.31,123.83) v3(114.33,122.61) v3(115.35,124.97) v3(115.37,123.85) v3(115.4,122.63) v3(119.9,122.48) v3(119.97,124.54)
PWR_VCCGI_PHA: length 24.5
  TOP w0.203: v2(117.66,120.68) v1(118.22,120.68) ; PC5026.1 133.94,126.44 v2(133.81,126.32)
  L3 w0.203: v2(133.81,126.32) 134.68,126.32 135.06,125.94 135.06,125.22 134.37,124.54 124.07,124.54 124.05,124.55 123.1,124.55 119.23,120.68 v2(117.66,120.68)
  BOTTOM w0.203: PG5111.1 v2(117.66,120.68) ; PU5001.32 133.86,126.36 v2(133.81,126.32)
PWR_VCCGI_PWM: length 19.1
  TOP w0.203: v1(124.54,132.74) v2(124.54,133.3) 124.54,133.53 124.3,133.77 PU5107.5
  L4 w0.203: v2(124.54,133.3) 124.54,132.97 124.9,132.62 130.21,132.62 130.87,131.96 130.87,129.54 132.72,127.69 133.59,127.69 134.63,126.65 134.63,125.63 v2(134.45,125.45)
  BOTTOM w0.203: v2(134.45,125.45) 134.32,125.58 134.32,126.56 134.26,126.62 PU5001.31
PWR_VCCGI_SNUB: length 2.8
  TOP w0.508: PC5105.2 121.42,125.45 PR5102.1 v1(122.88,125.5)
PWR_VCCGI_VCC: length 4.3
  TOP w0.305: PU5107.8 124.79,135.27
  TOP w0.508: 124.79,135.27 124.8,135.28 PC5103.1 126.05,136.39 PR5101.2 v1(125.01,136.4)
PWR_VCCRAM_FB: length 7.1
  BOTTOM w0.203: PR5023.1 v1(141.32,135.21) 141.32,134.96 140.8,134.44 139.82,134.44 137.97,132.59 137.47,132.59 137.19,132.3 PU5001.15
PWR_VCCRAM_PH:
  vias: v1(137.7,128.91)
PWR_VDDQ:
  vias: v1(74.94,51.39) v1(77.07,43.21) v1(78.59,55.35) v1(85.99,50.57) v3(73.74,41.1) v3(73.77,43.99) v3(73.79,43.06) v3(73.77,42.09) v3(74.73,44.1) v3(74.73,42.19) v3(74.71,41.2) v3(74.76,43.16)
PWR_VDDQ_BOOT: length 3.7
  TOP w0.305: v3(59.34,31.45) 59.28,31.38 PU5108.4
  BOTTOM w0.508: PR5106.1 59.32,31.42 v3(59.34,31.45) 59.62,31.73 59.98,31.73 v1(60.13,31.88)
PWR_VDDQ_BOOT_A: length 3.7
  BOTTOM w0.508: PC5115.1 56.42,33.12 57.77,33.12 PR5106.2 58.54,32.74 58.66,32.87 59.09,32.87 v1(59.29,33.07)
PWR_VDDQ_EN: length 181.2
  TOP w0.203: v2(55.15,31) 55.53,31.38 PU5108.1 ; v1(128.33,132.89) 128.58,132.89 v2(128.94,133.25)
  L3 w0.203: v2(55.15,31) 55.15,33.91 62.06,40.82 62.24,40.82 67.65,46.23 67.65,60.25 67.47,60.43 67.47,62.05 67.49,62.07 67.49,64.51 67.32,64.68 67.32,65.95 67.65,66.29 68.22,66.29 77.4,75.47 79.15,75.47 79.84,76.15 80.97,76.15 90.85,86.03 90.85,88.77 96.47,94.39 97.42,94.39 98.12,95.09 98.12,95.09 98.72,95.69 99.02,95.99 99.12,95.99 101.36,98.24 101.36,101.62 97.82,105.16 97.82,117.57 97.26,118.13 97.26,118.4 97.26,134.02 97.26,134.9 103.17,140.8 103.17,141.95 106.39,145.16 122.98,145.16 123.61,144.53 127.48,140.67 128.79,140.67 131.05,138.41 131.05,133.48 130.41,132.84 129.34,132.84 v2(128.94,133.25)
  BOTTOM w0.203: PU5001.50 129.82,131.9 129.71,132.01 129.64,132.01 128.94,132.71 v2(128.94,133.25)
PWR_VDDQ_FB: length 2.9
  BOTTOM w0.203: PR5001.1 131.88,135 v1(131.99,134.9) 132.29,134.6 132.29,134.12 132.26,134.09 PU5001.4
PWR_VDDQ_HG: length 12.7
  TOP w0.305: v3(57.82,30.53) 57.77,30.53 57.36,30.94 PU5108.3
  TOP w0.406: PU5103.4 66.92,32.63 v3(66.92,33.24)
  L4 w0.762: v3(57.82,30.53) 63.15,30.53 65.84,33.23 66.91,33.23 v3(66.92,33.24)
  BOTTOM w0.508: v1(57.82,29.87) v3(57.82,30.53)
PWR_VDDQ_LG: length 9.5
  TOP w0.305: PU5108.7 56.86,34.1 56.9,34.14 v3(56.9,34.29)
  TOP w0.406: v3(63.57,34.39) PU5104.4
  L4 w0.762: v3(63.57,34.39) 63.03,34.94 57.55,34.94 v3(56.9,34.29)
  BOTTOM w0.508: v3(56.9,34.29) 57.08,34.29 v1(57.51,34.72)
PWR_VDDQ_PH: length 16.4
  TOP w0.305: PU5108.2 56.86,30.77 v3(56.62,30.53)
  L4 w0.762: v3(56.62,30.53) 56.62,30.41 57.64,29.39 63.63,29.39 66.32,32.08 67.38,32.08 67.78,32.48 68.19,32.48 v3(68.21,32.46)
  BOTTOM w0.508: v3(56.62,30.53) 56.04,31.12 PC5115.2 ; PC5122.1 67.63,34
  vias: v1(72.83,37.14) v3(68.22,31.53) v3(68.28,33.35) v3(68.71,35.44) v3(68.74,34.19) v3(69.25,33.35) v3(69.3,32.34) v3(69.3,31.35)
PWR_VDDQ_PHA: length 160.8
  TOP w0.203: v2(129.55,133.78) 129.55,133.28 130.22,132.6 PC5027.1 129.52,132.39 v1(129.32,132.18)
  L3 w0.203: v2(71.18,38.94) 70.92,38.94 69.27,40.59 69.27,60.33 69.4,60.45 69.4,62.59 69.83,63.02 69.83,66.06 77.93,74.16 79.7,74.16 80.31,74.77 81.42,74.77 92.15,85.49 92.15,88.23 97.01,93.09 97.95,93.09 98.1,93.24 98.53,93.67 98.53,93.67 99.56,94.7 99.65,94.7 102.66,97.7 102.66,102.16 99.55,105.26 99.55,106.06 99.32,106.29 99.32,106.61 99.25,106.69 99.25,109.15 99.32,109.23 99.32,110.67 99.12,110.87 99.12,118.11 98.56,118.67 98.56,133.48 98.58,133.51 98.58,134.16 107.66,143.23 109.13,143.23 123.08,143.23 125.74,140.57 126.23,140.08 127.09,139.22 128.4,139.22 129.75,137.87 129.75,135.66 129.55,135.46 v2(129.55,133.78)
  BOTTOM w0.203: PG5112.1 v2(71.18,38.94) ; v2(129.55,133.78) 129.57,133.76 129.57,132.95 129.75,132.77 129.75,132.52 129.96,132.3 PU5001.51
PWR_VDDQ_PWM: length 170.4
  TOP w0.203: v2(58.45,33.58) 58.31,33.44 PU5108.5 ; v2(130.28,133.63) 130.51,133.86 130.51,134.27 v1(130.84,134.6)
  L3 w0.203: v2(130.28,133.63) 130.51,133.63 130.72,133.83 130.72,138.27 128.65,140.34 127.34,140.34 123.48,144.2 109.83,144.2 107.17,144.2 97.59,134.62 97.59,133.88 97.59,133.88 97.59,133.08 97.59,118.27 97.62,118.24 98.15,117.71 98.15,105.29 101.69,101.75 101.69,98.1 99.25,95.66 99.16,95.66 98.25,94.76 97.56,94.06 96.61,94.06 91.18,88.63 91.18,85.89 81.11,75.82 80,75.82 79.3,75.12 77.53,75.12 68.87,66.46 68.87,65.13 68.4,64.66 68.4,63.08 68.43,63.04 68.43,61.24 68.31,61.11 68.31,46.42 61.78,39.89 61.6,39.89 58.5,36.79 58.5,33.63 v2(58.45,33.58)
  BOTTOM w0.203: v2(130.28,133.63) 130.28,133.58 130.41,133.46 PU5001.52
PWR_VDDQ_SNUB: length 2.5
  BOTTOM w0.508: v1(65.31,33.77) PR5112.1 65.32,34.89 PC5122.2
PWR_VDDQ_VCC: length 4.2
  TOP w0.305: 55.28,33.12 55.8,33.12 56.12,33.44 PU5108.8
  TOP w0.508: 55.28,33.12 54.66,33.12 PC5109.1 PR5104.2 54.64,31.63 54.46,31.45 v1(54.46,30.84)
PWR_VIN_CT: length 5.5
  BOTTOM w0.203: v1(131.91,138.33) 132.13,138.33 PR5008.2 PC5021.1 PR5018.2 132.66,135.99 132.66,135 132.77,134.88 132.77,134.21 132.66,134.09 PU5001.5
PWR_VNN_BOOT: length 3.1
  BOTTOM w0.305: PU5106.4 105.71,134.2 105.87,134.04
  BOTTOM w0.508: PR5105.1 107.65,134.27 107.17,133.78 v1(106.7,133.78) 106.13,133.78 105.87,134.04
PWR_VNN_BOOT_A: length 2.4
  BOTTOM w0.508: PC5116.1 PR5105.2 v1(108.97,133.45)
PWR_VNN_EN: length 33.1
  L4 w0.203: v2(105.71,136.86) 105.71,137.53 107.37,139.19 115.83,139.19 116.87,140.24 120.81,140.24 122.01,139.03 123.28,139.03 124.19,138.12 v2(124.19,137.59)
  BOTTOM w0.203: v2(124.19,137.59) 124.19,137.25 126.8,134.64 126.8,133.89 127.38,133.31 127.38,133.31 127.62,133.08 127.62,133.07 128.43,132.26 128.43,131.55 129.27,130.7 PU5001.47 ; v1(105.47,137.37) 105.71,137.12 v2(105.71,136.86) PU5106.1
PWR_VNN_FB: length 4.9
  BOTTOM w0.203: PU5001.46 129.21,130.3 128.34,131.17 PR5035.1 127.91,131.43 127.63,131.71 PR5034.1 127.63,132.49 v1(127.21,132.91)
PWR_VNN_HG: length 13.2
  TOP w0.406: v3(109.96,125.86) 109.75,126.08 PU5102.4
  TOP w0.762: v1(109.99,125.17) 109.99,125.83 v3(109.96,125.86)
  L3 w0.762: v3(106.71,134.72) 106.71,134.34 109.13,131.93 109.13,126.78 109.96,125.94 v3(109.96,125.86)
  BOTTOM w0.305: v3(106.71,134.72) 106.61,134.72 106.18,135.16 PU5106.3
PWR_VNN_LG: length 6.9
  TOP w0.406: PU5101.4 v3(101.24,131.12)
  BOTTOM w0.305: PU5106.7 102.93,135.66 102.61,135.34
  BOTTOM w0.508: v3(101.24,131.12) v1(101.24,132.35) 101.24,133.01 102.32,134.09 102.32,135.05 102.61,135.34
PWR_VNN_PH: length 17
  L3 w0.762: v3(107.65,125.91) 108.21,126.47 108.21,131.59 105.82,133.97 105.82,135.09 106.84,136.11 v3(106.84,136.88)
  BOTTOM w0.305: 106.38,135.66 PU5106.2
  BOTTOM w0.508: 106.38,135.66 106.38,135.66 107.42,135.66 PC5116.2 107.65,136.63 107.4,136.88 v3(106.84,136.88) v1(106.84,137.62)
  vias: v3(101.23,125.91) v3(101.2,124.89) v3(102.75,125.91) v3(102.78,124.89) v3(107.63,124.94) v3(108.82,125.81) v3(108.82,124.84)
PWR_VNN_PHA: length 32
  TOP w0.203: v1(128.89,130.99) 129.24,130.99 v2(129.45,131.19) 130.02,131.19 PC5011.1
  L3 w0.203: v2(106.23,124.06) 108.39,121.9 116.19,121.9 122.14,127.85 127.35,127.85 129.45,129.95 v2(129.45,131.19)
  BOTTOM w0.203: v2(129.45,131.19) 129.53,131.1 PU5001.48 ; PG5110.1 v2(106.23,124.06)
PWR_VNN_PWM: length 36.5
  L4 w0.203: v2(124.82,137.64) 124.52,137.95 124.52,138.26 123.42,139.36 123.14,139.36 122.15,139.36 120.95,140.57 116.74,140.57 115.69,139.52 107.24,139.52 105.48,137.76 103.65,135.94 v2(103.65,134.11)
  BOTTOM w0.203: v2(124.82,137.64) 124.82,137.11 127.13,134.8 127.13,134.02 127.51,133.64 127.52,133.64 127.95,133.21 127.95,133.21 128.76,132.4 128.76,132.16 129.27,131.65 129.66,131.65 129.81,131.5 PU5001.49 ; v1(103.39,133.61) 103.65,133.87 v2(103.65,134.11) PU5106.5
PWR_VNN_SNUB: length 2
  TOP w0.508: PR5114.1 PC5125.2 106.27,127.9 v1(106.41,127.76)
PWR_VNN_VCC: length 3.4
  BOTTOM w0.305: PU5106.8 103.24,136.16 102.9,136.5 102.67,136.5
  BOTTOM w0.508: 102.67,136.5 v1(102.47,136.5) PC5124.1 101.48,136.49 PR5103.2
PWR_VO2: length 24.9
  L4 w0.203: v2(127.39,125.66) 130.08,125.66 131.35,124.39 131.37,124.39 134.78,120.98 140.27,120.98 v2(140.51,120.74)
  BOTTOM w0.203: v2(140.51,120.74) PC5012.1 PR5005.2 ; v2(127.39,125.66) 127.03,125.66 126.52,125.15 PR5004.2 PR5019.1 126.54,126.14 127.59,126.14 127.79,125.94 v1(128.28,125.94) 128.28,126.72 128.2,126.8 PR5032.1 128.2,127.14 129.21,128.15 129.22,128.15 129.78,128.7 PU5001.42
PWR_VSS: length 8
  BOTTOM w0.203: PU5001.27 135.86,126.74 138.36,124.23 v1(138.67,124.23) 138.87,124.03 PR5012.2 PC5013.1 PR5013.2 PC5012.2
PWR_VSYS: length 5.7
  BOTTOM w0.203: PU5001.6 133.06,134.03 133.1,134.07 133.1,134.42 v1(133.79,135.1) 134.22,135.54 134.79,135.54 PC5015.1 PR5014.2 PR5007.2
PWR_VTT: length 6.5
  BOTTOM w0.203: 131.17,134.7 131.17,134.24 131.46,133.96 PU5001.2
  BOTTOM w0.508: 131.17,134.7 131.17,135.05 PC5019.1 129.9,135.66 129.75,135.51 v1(128.99,135.51) 128.4,136.1 PG5016.1 PG5014.2
PWR_VTT_SEN: length 5.8
  BOTTOM w0.203: PG5016.2 127.79,135.74 128.23,135.31 128.23,134.44 v1(128.3,134.37) 128.4,134.27 130.64,134.27 131.06,133.85 PU5001.1
Q6205_Q: length 2.8
  BOTTOM w0.381: Q6505.D 134.61,24.88 133.92,24.18 v1(133.92,23.73) R6522.2
RING2: length 11.4
  TOP w0.508: EC2905.1 166.7,15.31 v2(166.89,15.5)
  L3 w1.016: v3(166.11,21.07) 166.11,20.49 166.89,19.71 v2(166.89,15.5)
  BOTTOM w0.203: v3(166.11,21.07) 166.09,21.05 HDA27.17
  BOTTOM w0.305: v3(166.11,21.07) 166.61,21.57 167.43,21.57 168.29,20.71 RN2901.4
  vias: v1(167.29,18.11)
RING2_R:
  vias: v3(173.29,16.84)
RSMRST#_KBC: length 244.6
  TOP w0.102: R2440.2 165.98,65.83 166.17,66.02 v1(166.28,66.02) 166.78,66.02 v2(167.01,65.79)
  L3 w0.102: v2(67.16,70.84) 67.16,70.19 65.03,68.05 65.03,64.33 64.88,64.17 64.88,60.3 64.02,59.44 64.02,45.23 61.17,42.39 61.17,41.72 52.74,33.29 52.74,30.57 58.8,24.51 132.75,24.51 135.69,21.57 139.84,21.57 139.86,21.54 150.06,21.54 154.95,26.42 154.95,29.09 157.61,31.76 157.61,42.24 158.68,43.31 158.68,46.76 165.59,53.67 165.59,57.25 166.33,57.99 166.33,62.36 167.01,63.04 v2(167.01,65.79)
  BOTTOM w0.102: v2(167.01,65.79) 166.98,65.82 166.48,65.82 165.85,66.44 KBC24.15 ; U1801.1 97.14,92.86 97.37,92.64 97.37,91.02 97.3,90.96 ED1804.1 R1830.1 97.33,89.19 96.63,88.5 93.7,88.5 92.05,87.01 89.17,84.13 87.53,82.25 85.52,79.87 84.77,79.3 83.79,78.44 80.24,76.25 80.16,76.22 78.8,75.66 77.63,75 74.6,73.78 72.91,73.29 72.59,73.1 70.82,71.33 67.7,71.33 67.21,70.84 v2(67.16,70.84)
RSMRST_IN_PMIC: length 6
  BOTTOM w0.102: KBC24.96 160.25,51.23 160.04,51.02 159.1,51.02 158.71,50.62 158.71,50.17 158.96,49.91 v1(158.96,49.46) 158.53,49.46 158.3,49.68 R2439.2 158.06,48.87 R2415.2
RTC_AUX_S5: length 356.4
  TOP w0.508: v2(30.67,23.27) 30.67,22.86 30.22,22.42 R2515.1 28.75,22.42 28.03,21.7 Q2501.3 ; v2(160.76,139.68) 158.98,139.68 158.91,139.75 155.75,139.75 154.68,138.69 147.21,138.69 146.07,139.83 v2(141.66,139.83) ; v2(153.75,61.14) v1(153.19,61.14)
  L3 w0.508: v2(153.75,61.14) 153.59,61.14 150.76,63.98 150.76,67.63 151.26,68.12 153.2,68.12 157.31,72.23 157.31,89.33 160.94,92.96 161.07,93.09 161.17,93.19 164.02,96.04 164.02,132.64 162.29,134.37 162.29,138.15 v2(160.76,139.68) ; v2(141.66,139.83) 132.95,139.83 127.13,145.65 106.19,145.65 102.66,142.12 102.66,140.98 96.78,135.1 96.78,134.22 96.78,119.18 96.78,117.93 96.81,117.9 97.34,117.37 97.34,104.96 100.88,101.42 100.88,98.44 98.92,96.48 98.82,96.48 98.82,96.47 97.92,95.57 97.92,95.57 97.22,94.87 95.56,94.87 95.38,94.69 v2(95.28,94.69)
  L4 w0.508: v2(35.64,65.93) 35.61,65.89 26.98,65.89 23.45,62.36 23.45,55.53 22.59,54.66 22.59,50.75 23.58,49.76 23.58,36.32 25.18,34.72 25.18,25.25 27.16,23.27 v2(30.67,23.27)
  BOTTOM w0.508: 98.28,94.01 97.37,94.01 96.71,94.67 96.71,94.69 v2(95.28,94.69) 94.64,94.69 92.72,92.77 92.42,92.39 92.3,92.24 90.67,89.22 90.19,88.62 90.17,88.6 89.76,88.1 89.76,88.1 85.81,83.28 84.8,82.19 84.79,82.18 83.78,81.11 81.86,79.58 79.87,78.46 79.14,77.94 78.48,77.66 78.25,77.56 77.13,76.93 74.36,75.79 68.06,73.89 67.56,73.38 67.55,73.38 67.3,73.13 65.62,73.13 59.71,67.21 55.62,67.21 54.23,68.61 45.27,68.61 44.41,69.47 39.06,69.47 35.64,66.05 v2(35.64,65.93) ; 98.28,94.01 98.61,94.01 101.73,97.13 102.04,97.37 102.32,97.64 ; 98.28,94.01 98.28,91.8 98.78,91.3 R1817.1 ; R2425.2 154.24,61.5 153.88,61.14 v2(153.75,61.14)
RTC_DET#: length 212.1
  TOP w0.102: v2(26.09,26.49) 26.21,26.61 Q2502.D ; v2(152.1,64.14) 152.48,64.14 153.3,64.95 154.79,64.95 v1(155.53,65.69) 155.56,65.69 158.24,68.37 159.5,68.37 160.2,67.67 161.53,67.67 162.65,66.54 v2(162.65,65.89) 163.92,64.62 169.15,64.62 169.38,64.85 RN2404.4
  L4 w0.102: v2(152.1,64.14) 152.1,63.76 152.05,63.71 152.05,62 152.1,61.95 152.1,60.47 151.82,60.19 151.82,52.45 154.44,49.84 154.44,42.04 154.82,41.66 154.82,32.77 152.31,30.25 152.31,28.65 151.47,27.82 150.22,27.82 150.09,27.69 148.7,27.69 148.67,27.71 147.1,27.71 146.97,27.84 141.99,27.84 141.36,28.48 139.3,28.48 138.36,27.54 135.53,27.54 134.52,28.55 106.15,28.55 105.58,29.12 102.2,29.12 101.79,28.7 80.13,28.7 75.8,33.04 75.8,44.5 75.17,45.14 63.91,45.14 63.05,44.27 60.49,44.27 51.04,34.83 40.16,34.83 31.83,26.49 v2(26.09,26.49)
  BOTTOM w0.102: v2(162.65,65.89) 162.65,66.54 162.25,66.94 KBC24.6
RTC_DET#_G: length 8
  TOP w0.508: Q2502.G 25.29,24.7 24.85,24.26 v1(24.85,23.75) 25.36,23.24 R2518.2 26.08,21.57 Q2501.1 25.58,21.53 24.75,22.35 R2516.1 R2527.1
RTC_RST#: length 35.2
  TOP w0.102: v2(104.48,93.46) 104.5,93.45 104.5,92.81 v1(104.4,92.51) 104.55,92.37 104.55,92.34 104.79,92.1 104.93,92.1 105.82,92.1 106.05,91.87 106.05,90.98 105.81,90.74 R1818.1 C1802.1 ED1809.1
  L3 w0.127: v2(104.48,93.46) 104.5,93.45 104.5,93.34 104.5,93.33 104.5,92.43 104.58,92.27 104.76,92.06 105.29,91.81 106.69,91.81 106.78,91.79 107.51,91.07 107.75,90.82 108.17,89.98 108.45,89.48 108.51,89.4 108.9,88.59 108.9,87.71 109.12,86.55 109.12,86.52 109.2,86.43 110.01,85.61 110.06,85.47 110.4,84.3 110.63,83.67 111.26,83.03 111.34,83.03 112.06,82.32 113.62,82.81 v2(114.01,83.94)
  BOTTOM w0.102: CPU1.AC55 v2(114.01,83.94) ; Q1801.D 107.59,101.52 107.52,101.03 107.52,100.17 107.63,99.77 107.63,99.75 107.67,99.36 107.67,98.92 107.67,98.9 107.65,98.89 107.64,98.86 106.91,98.13 106.9,98.13 106.77,98.08 106.42,97.94 106.4,97.94 106.33,97.86 105.77,97.65 105.37,97.5 104.31,97.5 104.29,97.5 RN1804.3 104.35,96.92 104.37,96.86 104.24,95.71 G1801.2 104.5,94.28 104.5,93.48 v2(104.48,93.46)
RTC_TEST#: length 179
  TOP w0.102: Q1802.D 158.78,67.77 157.09,66.08 v1(157.09,64.68) 156.22,63.81 154.81,63.81 154.66,63.65 149.54,63.65 147.43,61.55 v2(143.29,61.55) ; R1818.2 C1801.1 104.47,91.86 104.16,92.19 104,92.5 104,92.99 103.99,92.99 v2(103.99,93.05)
  L3 w0.127: v2(80.65,50.09) 80.65,51.16 77.57,54.24 77.57,59.99 82.86,65.28 83.15,65.57 83.15,67.55 83.21,67.6 83.21,68.41 83.33,68.53 83.33,68.54 88.56,73.76 90.24,73.76 97.95,81.47 97.95,87.86 101.91,91.81 102.76,91.81 v2(103.99,93.05) 103.99,93.12 103.99,93.13 103.99,93.24 103.97,93.25 103.97,93.68 104.27,93.97 104.69,93.97 105.25,93.41 105.25,92.96 105.7,92.52 106.01,92.34 106.07,92.32 106.73,92.32 107.08,92.26 108.33,91.01 108.84,90.21 109.28,89.77 109.64,88.58 110.14,86.29 110.46,85.86 111.08,84.21 111.58,83.71 111.75,83.7 111.96,83.7 112.35,83.85 113.34,84.23 114.72,84.89 115.22,84.89 115.48,84.97 115.92,85.12 116.54,85.33 116.87,85.33 116.97,85.29 117.22,85.05 117.27,84.5 117.4,83.98 117.5,83.8 v2(117.94,83.33)
  L4 w0.127: v2(143.26,53.14) 142.92,53.48 142.92,54.97 143.43,55.48 143.43,61.41 v2(143.29,61.55)
  BOTTOM w0.102: v2(143.26,53.14) 142.93,53.14 138.7,48.91 84.59,48.91 83.46,50.04 80.7,50.04 v2(80.65,50.09) ; CPU1.AH49 v2(117.94,83.33) ; RN1804.4 103.65,94.37 103.72,94.01 103.73,93.88 v2(103.99,93.05)
RTCRST_ON: length 205.8
  TOP w0.102: v2(160.1,64.19) 160.1,65.79 160.75,66.44 Q1802.G
  L4 w0.127: v2(163.38,128.45) 163.32,128.39 163.32,121.44 162.8,120.92 162.8,114.33 164.33,112.8 164.33,100.49 161.03,97.18 161.03,94.69 160.29,93.95 160.29,86.63 160.29,85.93 159.24,84.88 159.24,82.02 159.75,81.51 159.75,78.13 160.21,77.67 160.21,76.99 160.68,76.52 160.68,75.15 160.41,74.89 160.41,71.99 160.65,71.75 160.65,68.75 160.13,68.23 160.13,64.21 v2(160.1,64.19)
  BOTTOM w0.102: v2(160.1,64.19) 160.1,63.5 159.73,63.12 KBC24.120 ; v2(163.38,128.45) 163.33,128.4 161.6,128.4 157.49,132.51 153.93,132.51 151.98,134.47 149.09,134.47 144.95,138.61 134.25,138.61 128.07,144.78 123.15,144.78 121.22,142.85 112.81,142.85 111.87,143.79 111.87,147.12 110.19,148.8 101.58,148.8 98.36,145.57 v1(98.36,142.2) 98.36,140.79 95.18,137.62 95.18,113.77 96.99,111.97 103.75,111.97 104.42,111.3 105.24,110.48 105.24,110.42 106.17,107.87 106.59,107.1 106.63,107.04 106.94,106.61 107.31,106.13 107.31,105.78 107.08,105.4 R1814.1 107.07,104.27 107.4,103.46 107.42,103.05 106.92,102.8 Q1801.G
RUN_ON#: length 4.4
  BOTTOM w0.102: Q4001.5 142.27,113.71 R4002.2 143.23,114.04 143.49,113.77 v1(143.49,113.67) 143.49,112.65 143.34,112.5 Q4001.6
RUN_ON_R: length 7.5
  TOP w0.102: U4001.5 26.02,50.83 v2(25.84,50.65) ; v1(22.56,52.91) 22.71,53.06 24.45,53.06 R4004.2 C4010.1 25.46,51.72 v2(25.56,51.82) 25.71,51.82 25.9,51.63 U4001.3
  BOTTOM w0.102: v2(25.84,50.65) 25.84,51.54 v2(25.56,51.82)
S5_ENABLE: length 153.7
  TOP w0.152: v2(142.98,60.78) 148.89,60.78 151.2,63.1 v1(154.82,63.1) 162.57,63.1 v2(163.28,63.81)
  L3 w0.152: v2(53.07,43.54) 52.76,43.85 52.76,44.55 53.4,45.18 53.4,47.91 52.89,48.41 52.89,52.05 v2(52.89,52.05)
  L4 w0.152: v2(77.4,49.13) 77.32,49.2 76.92,49.2 74.07,52.05 62.53,52.05 61.39,50.91 61.39,48.53 59.21,46.36 59.21,45.39 57.36,43.54 v2(53.07,43.54)
  BOTTOM w0.152: v2(163.28,63.81) 163.45,63.81 165.55,65.91 165.55,66.96 165.45,67.05 KBC24.14 165.45,68.73 166.48,69.75 166.48,70.3 166.69,70.51 166.69,71.12 ; RN2406.1 168.33,76.07 168.48,75.92 168.48,74.63 168.4,74.55 168.4,71.29 168.25,71.15 168.06,71.15 168.03,71.12 166.69,71.12 ; v2(52.89,52.05) 52.51,52.05 51.57,52.99 R4007.2 ; v2(77.4,49.13) 77.08,49.13 76.69,49.52 76.69,49.95 76.7,49.96 76.7,50.3 78.61,52.21 84.36,52.21 85.49,51.08 132.63,51.08 142.39,60.84 142.93,60.84 v2(142.98,60.78) ; 166.69,71.12 Q2403.3
SATA3_DE1_HDD: length 4.5
  BOTTOM w0.102: U6001.9 165.48,44.33 165.11,44.71 R6024.2 R6007.1 166.45,45.63 v1(166.85,45.24)
SATA3_DE2_HDD: length 3.9
  BOTTOM w0.102: R6014.1 163.53,45.63 R6008.2 164.23,45.62 v1(164.23,44.73) 164.98,43.98 U6001.8
SATA3_DRX_CTX_N0: length 3.3
  TOP w0.127: v2(168.36,41.76) 168.21,41.91 R6018.2
  BOTTOM w0.127: U6001.12 167.5,41.78 167.65,41.92 168.19,41.92 v2(168.36,41.76) 168.64,41.48 C6019.1
SATA3_DRX_CTX_N0_R: length 15.6
  TOP w0.127: R6018.1 166.35,42.24 165.55,42.24 165.34,42.45 164.4,42.45 163.74,41.79 161.19,41.79 159.93,43.05 155,43.05 ; R6015.2 152.69,43.05 155,43.05 ; 155,43.05 v1(155,42.9)
SATA3_DRX_CTX_P0: length 3.3
  TOP w0.127: R6009.2 167.88,42.48 v2(168.34,42.48)
  BOTTOM w0.127: U6001.11 167.54,42.28 167.65,42.17 168.03,42.17 v2(168.34,42.48) 168.45,42.37 C6016.1
SATA3_DRX_CTX_P0_R: length 15.6
  TOP w0.127: v1(158.94,43.44) 158.94,43.29 ; 158.94,43.29 152.69,43.29 R6023.2 ; 158.94,43.29 160.03,43.29 161.29,42.03 163.64,42.03 164.3,42.69 165.44,42.69 165.65,42.48 166.35,42.48 R6009.1
SATA3_DTX_CRX_N0: length 3.2
  TOP w0.127: v2(168.33,40.49) 168.31,40.46 R6019.2
  BOTTOM w0.127: U6001.14 167.49,40.78 167.93,40.34 168.18,40.34 v2(168.33,40.49) 168.36,40.46 168.96,40.46 C6011.1
SATA3_DTX_CRX_N0_R: length 15.5
  TOP w0.127: R6019.1 166.45,40.17 165.79,40.17 165.59,39.97 162.29,39.97 160.74,41.51 157.13,41.51 ; 157.13,41.51 152.69,41.51 R6010.2 ; 157.13,41.51 v1(157.13,41.66)
SATA3_DTX_CRX_P0: length 3.1
  TOP w0.127: v2(168.33,39.73) 168.26,39.65 R6006.2
  BOTTOM w0.127: U6001.15 167.65,40.28 167.83,40.1 167.96,40.1 v2(168.33,39.73) 168.36,39.7 C6017.1
SATA3_DTX_CRX_P0_R: length 15.5
  TOP w0.127: v1(160.08,41.12) 160.08,41.27 ; 160.08,41.27 152.69,41.27 R6011.2 ; 160.08,41.27 160.64,41.27 162.19,39.73 165.69,39.73 165.89,39.93 166.47,39.93 R6006.1
SATA3_EQ1_HDD: length 4.6
  BOTTOM w0.102: R6005.1 167.41,37.09 R6017.2 167.42,37.67 167.06,38.03 v1(165.84,38.03) 165.48,38.39 U6001.17
SATA3_EQ2_HDD: length 3.5
  BOTTOM w0.102: U6001.19 164.48,38.51 164.27,38.3 v1(164.27,38) 164.27,37.35 R6021.2 163.71,37.09 163.27,37.53 R6013.1
SATA3_PRX_DTX_N0_L: length 11.5
  BOTTOM w0.127: v1(153.3,42.88) 153.3,43.02 ; 153.3,43.02 160.92,43.02 161.99,41.94 162.34,41.94 162.5,41.78 U6001.4 ; 153.3,43.02 152.66,43.02 C6018.1
SATA3_PRX_DTX_P0_L: length 11.5
  BOTTOM w0.127: v1(154.87,43.41) 154.87,43.26 ; 154.87,43.26 161.02,43.26 162.09,42.18 162.37,42.18 162.47,42.28 U6001.5 ; 154.87,43.26 152.72,43.26 C6015.1
SATA3_PTX_DRX_N0_R: length 12.9
  BOTTOM w0.127: v1(153.3,41.66) 153.3,41.51 ; 153.3,41.51 153.65,41.51 154.65,42.51 160.6,42.51 160.87,42.25 160.87,41.06 161.25,40.67 162.34,40.67 162.45,40.78 U6001.2 ; 153.3,41.51 152.69,41.51 C6014.2
SATA3_PTX_DRX_P0_R: length 12.9
  BOTTOM w0.127: U6001.1 162.42,40.28 162.27,40.43 161.15,40.43 160.62,40.96 160.62,42.15 160.5,42.27 155.02,42.27 ; 155.02,42.27 154.75,42.27 153.75,41.27 152.69,41.27 C6013.2 ; 155.02,42.27 v1(155.02,42.14)
SATA_DEVSLP_HDD_CPU: length 27.4
  L4 w0.102: v2(134.47,110.24) 132.45,110.56 130.08,110.56 128.47,108.96 128.44,108.92 128.36,108.81 128.23,108.65 128.23,108.58 128.23,108.51 128.23,108.5 128.24,108.4 128.25,108.26 128.25,104.41 128.22,104.37 128.21,101.72 128.03,101.41 128,101.35 127.4,100.56 127.16,99.96 127.15,99.94 127.14,99.92 127.13,99.91 127.11,99.85 127.11,99.78 126.64,99.31 125.25,99.31 124.1,100.46 v2(123.79,100.46)
  BOTTOM w0.089: 123.95,98.39 123.95,98.38 123.93,98.34 123.93,98.13 124.24,97.82 124.27,97.74 CPU1.C25
  BOTTOM w0.102: v1(135.29,112.78) 134.97,112.46 R2115.2 Q2101.S 135.34,110.24 v2(134.47,110.24) ; 123.95,98.39 123.95,98.44 123.87,98.66 123.6,98.93 123.53,99.13 123.53,100.19 v2(123.79,100.46)
SATA_LED: length 93
  TOP w0.102: v2(171.1,63.15) 171.1,62.66 169.53,61.09 167.8,61.09 166.63,59.92 164.17,59.92 163.41,59.16 160.18,59.16 157.51,56.49 v1(157.51,55.45) v2(157.51,54.89)
  L3 w0.102: v2(161.83,6.99) 161.96,7.11 164.5,7.11 164.93,7.55 168.12,7.55 168.31,7.55 174.81,14.05 175.08,14.31 175.08,25.03 172.37,27.74 172.37,38.3 171.75,38.92 171.75,49.7 175.17,53.11 175.17,53.98 174.94,54.21 174.94,55.13 173.56,56.51 171.81,56.51 170.34,57.98 170.34,61.6 171.1,62.36 v2(171.1,63.15)
  BOTTOM w0.102: v2(157.51,54.89) 157.51,54.9 157.74,55.12 KBC24.100 ; v2(161.83,6.99) 161.83,6.31 R6408.1 162.24,5.88 Q6401.G
SATA_LED#_CPU: length 185.3
  TOP w0.102: v2(158.99,96.34) 158.94,96.4 158.94,103 157.72,104.22 157.72,105.18 148.94,113.95 146.17,113.95 v1(145.76,114.36) 145.22,114.91 143.13,116.99 140.62,116.99 140.44,117.17 138.41,117.17 137.32,116.09 137.32,115.42 134.35,112.45 134.35,111.17 133.88,110.71 130.6,110.71 129.88,110.39 128,108.51 128,106.34 127.08,105.49 v2(126.88,105.29)
  L3 w0.127: v2(165.34,6.73) 165.91,7.3 168.41,7.3 175.32,14.21 175.32,25.13 172.61,27.84 172.61,38.42 171.99,39.04 171.99,48.16 174.53,50.7 174.53,51.99 175.94,53.4 175.94,54.5 173.66,56.78 171.88,56.78 170.58,58.08 170.58,61.38 172.04,62.84 172.04,66.14 172.55,66.65 172.55,70.06 173.55,71.06 173.55,75.47 172.14,76.89 171.96,76.89 165.51,83.34 164.45,83.34 160.73,87.07 160.73,91.61 164.09,94.97 v2(166.33,94.97)
  BOTTOM w0.102: v2(166.33,94.97) 161.14,94.97 159.77,96.34 v2(158.99,96.34) ; Q6401.S 165.34,6.04 v2(165.34,6.73) ; CPU1.C31 121.84,96.66 121.47,97.02 121.45,97.03 121.35,97.13 121.31,97.24 121.31,97.36 121.56,97.9 121.56,100.36 121.98,101.75 122.45,102.05 124.31,102.69 124.63,103.01 125.12,103.47 R2106.1 126.32,104.69 126.88,105.25 v2(126.88,105.29)
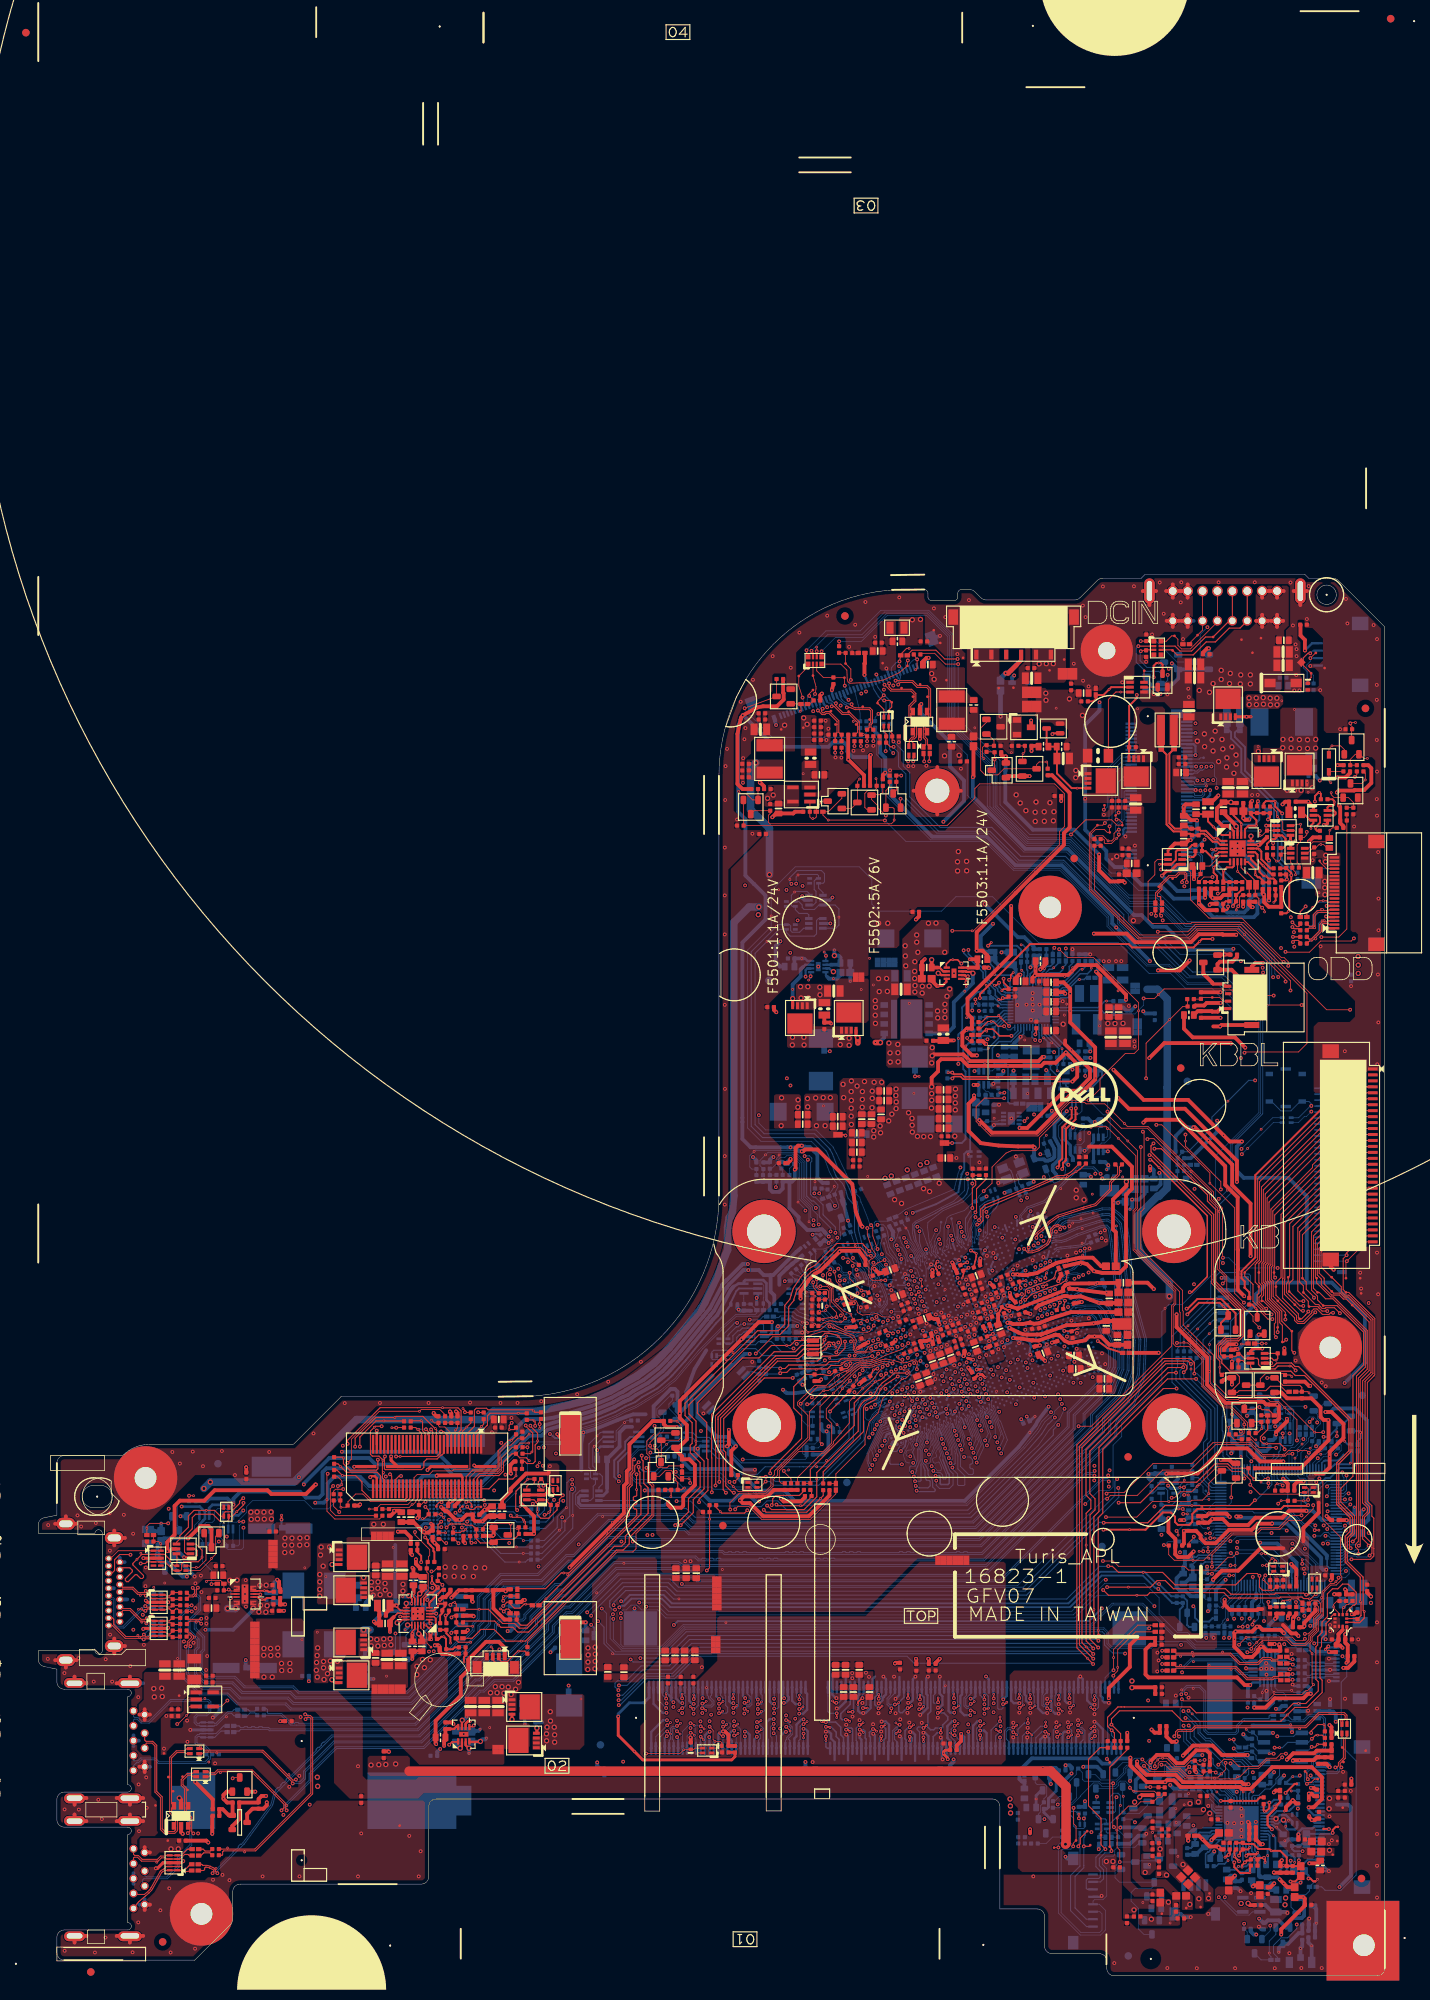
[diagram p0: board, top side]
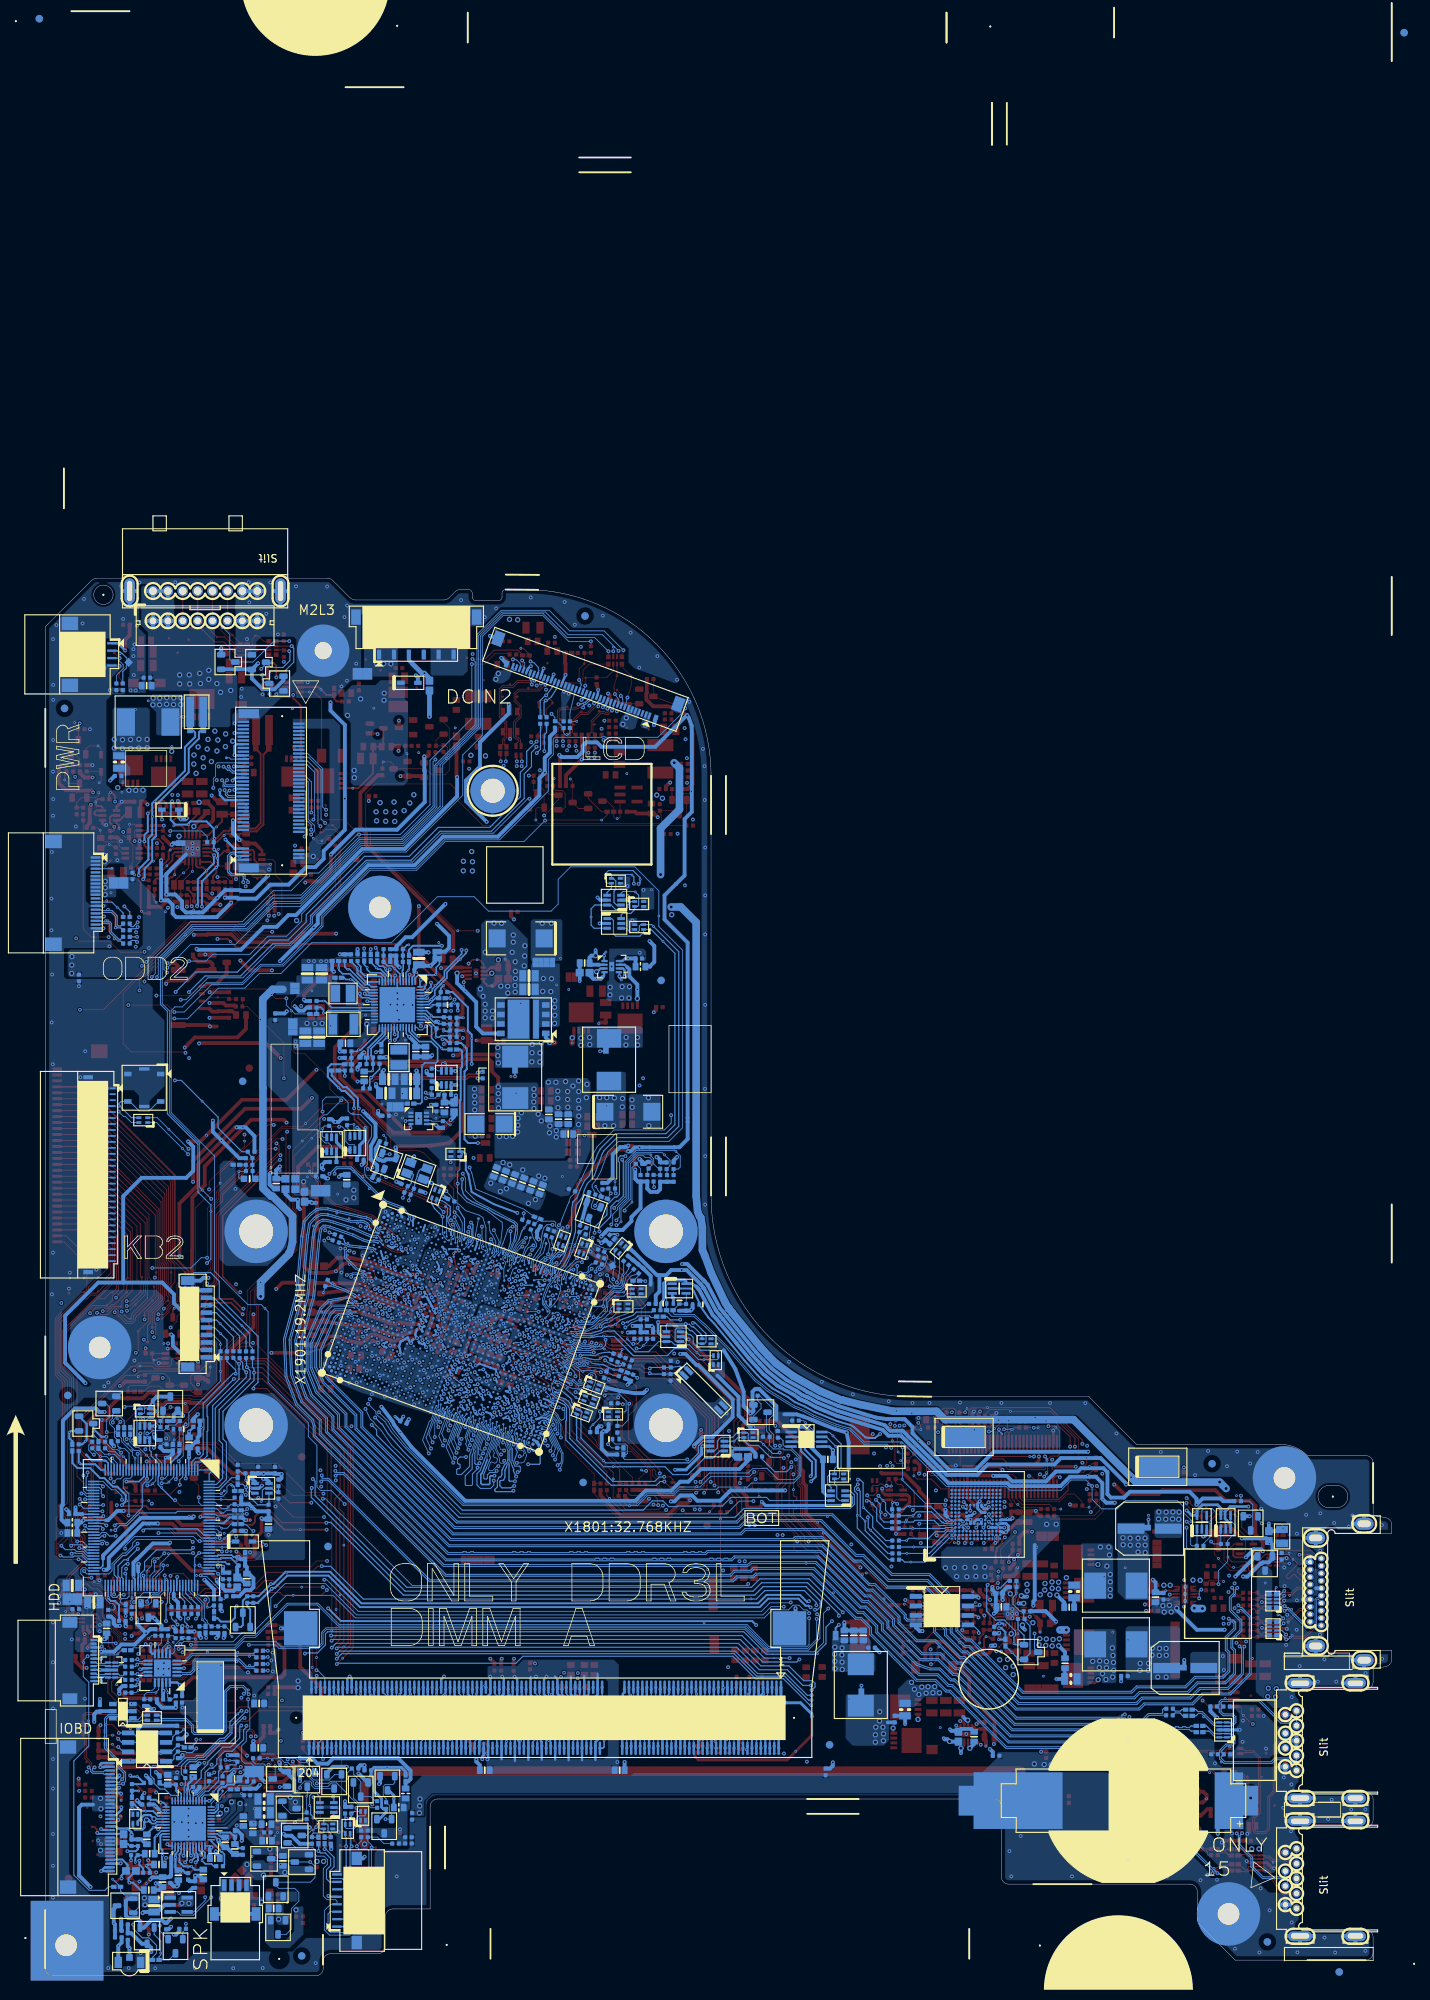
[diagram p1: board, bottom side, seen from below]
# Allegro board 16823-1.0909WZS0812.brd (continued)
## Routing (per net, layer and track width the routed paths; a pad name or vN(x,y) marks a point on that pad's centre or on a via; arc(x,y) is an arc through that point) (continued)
SATA_ODD_DA#_C: length 2.5
  TOP w0.127: TP6001.1 171.97,149.48 172.9,148.55 ODD1.17
SATA_ODD_DA#_C2: length 2.2
  BOTTOM w0.127: TP6002.1 171.8,148.55 ODD2.4
SATA_ODD_PRSNT#: length 78.3
  TOP w0.127: R2126.2 170.38,78.37 v1(170.54,78.21) ; R2126.2 169.57,78.36 R2129.1 ; R2126.2 169.58,78.96 169.31,79.22 167.04,79.22 166.03,80.23 Q2103.S 164.95,80.23 v2(164.93,80.22) ; v2(170.09,143.49) 169.36,142.76 R6002.2
  L4 w0.127: v2(164.93,80.22) 164.93,81.52 164.9,81.56 164.79,81.67 164.79,83.36 165.2,83.77 165.2,87.07 166.06,87.93 166.06,89.57 165.55,90.07 165.55,95.5 167.38,97.33 167.38,132.71 171.65,136.98 171.65,141.92 v2(170.09,143.49)
  BOTTOM w0.127: R6002.2 169.36,142.76 v2(170.09,143.49)
SATA_ODD_PRSNT#_CPU: length 82.9
  TOP w0.127: v2(149.13,110.11) 149.34,110.11 157.47,101.98 157.47,92.91 161.25,89.13 161.25,86.15 160.91,85.8 159.37,85.8 158.59,85.02 158.56,85.02 158.12,84.58 158.12,82.93 158.57,82.48 v1(158.57,81.66) 158.57,80.9 R2120.2 159.05,80.85 160.74,80.85 161.2,80.39 161.2,79.55 160.19,78.55 Q2102.S 160.92,78.27 161.17,78.51 164.75,78.51 165.34,79.1 166.76,79.1 167.49,78.36 R2129.2
  L4 w0.127: v2(149.13,110.11) 148.9,109.88 137.21,109.88 135.2,108.93 128.64,102.37 128.64,101.89 128.58,101.7 127.86,100.64 127.37,99.84 127.37,99.7 126.74,99.07 125.46,99.07 125.45,99.06 124.98,99.06 124.38,99.66 124.29,99.66 v2(123.93,99.82)
  BOTTOM w0.089: v2(123.93,99.82) 123.8,99.69 123.8,99.05 123.81,99.01 123.97,98.85 124.04,98.74 124.12,98.5 124.16,98.4 124.16,98.38 CPU1.B25
SATA_ODD_PRSNT#_D: length 7.4
  TOP w0.127: v1(168.23,80.39) 168.02,80.61 R2124.2 167.12,80.81 164.71,80.81 164,80.1 Q2103.D Q2102.D
SATA_ODD_PRSNT#_R: length 5
  TOP w0.127: R6002.1 170.25,142.56 171.94,144.25 v1(172.45,144.25) 172.88,144.25 173.08,144.05 ODD1.8
SATA_ODD_PRSNT#_R2: length 4.8
  BOTTOM w0.127: R6003.1 170.25,142.61 171,143.36 v1(171.05,143.36) 171.74,144.05 ODD2.13
SATA_RXN0_C: length 4.5
  BOTTOM w0.127: C6019.2 170.2,41.71 170.72,41.71 170.89,41.54 EU6001.4 EU6001.7 172.57,41.54 172.69,41.66 173.76,41.66 173.88,41.55 HDD1.8
SATA_RXP0_C: length 4.6
  BOTTOM w0.127: C6016.2 170.39,41.95 170.65,41.95 170.72,42.02 EU6001.5 EU6001.6 172.58,42.02 172.7,41.9 173.74,41.9 173.88,42.05 HDD1.7
SATA_TXN0_C: length 4.6
  BOTTOM w0.127: C6011.2 170.3,40.26 170.67,40.26 170.91,40.5 EU6001.2 EU6001.9 172.65,40.5 172.73,40.42 173.75,40.42 173.88,40.55 HDD1.10
SATA_TXP0_C: length 4.5
  BOTTOM w0.127: C6017.2 170.29,40.02 EU6001.1 EU6001.10 172.62,40.02 172.77,40.18 173.77,40.18 173.9,40.05 HDD1.11
SD_AMP: length 14.9
  TOP w0.102: v2(149.84,28.12) 149.86,28.14 149.86,28.58 v1(150.24,28.96) 150.48,29.2 151.45,29.2 152.56,28.09 153.9,28.09 154.68,28.87 R2928.1 155.75,28.32 R2929.1
  BOTTOM w0.102: R2927.2 152.82,28.76 152.48,28.42 151.34,28.42 151.18,28.26 151.18,27.01 150.57,26.41 Q2907.C 149.84,26.74 v2(149.84,28.12)
SD_AMP#: length 7.8
  BOTTOM w0.102: Q2701.G 148.88,22.89 147.76,21.77 145.77,21.77 R2726.2 145.62,21.92 v1(145.62,24.08) 145.62,24.23 145.54,24.31 Q2908.C
SD_AMP_R: length 12.8
  BOTTOM w0.102: R2927.1 v1(150.88,29.19) 149.16,29.19 148.57,28.6 148.11,28.6 147.77,28.26 146.09,28.26 145.68,27.84 145.68,27.32 144.64,26.28 142.58,26.28 141.83,27.03 Q2906.B
SERIRQ: length 188.3
  TOP w0.14: v2(101.25,80.22) 97.44,80.22 91.99,74.76 91.99,70.51 92.26,70.24 92.26,65.74 93.15,64.85 93.33,64.85 v2(93.35,64.82) ; v1(153.19,65.53) v2(153.75,65.53)
  L3 w0.127: v2(153.75,65.53) 154,65.29 154.1,65.29 155.52,63.87 155.52,58.75 154.06,57.28 154.06,43.4 154.27,43.18 154.27,41.45 155.49,40.23 155.49,32.89 152.37,29.77 147.85,29.77 144.5,26.42 138.16,26.42 137.67,26.9 135.34,26.9 134.48,27.77 132.46,27.77 82.37,27.77 77.39,32.76 77.39,35.17 79.76,37.55 79.76,40.21 86.93,47.37 86.93,48.13 86.93,54.38 88.05,55.5 88.05,56.79 92.27,61.01 92.27,62.61 93.35,63.69 v2(93.35,64.82)
  BOTTOM w0.14: U2404.4 150.68,63.26 R1922.1 152.19,63.21 153.33,64.34 153.33,64.7 153.75,65.13 v2(153.75,65.53) 154.17,65.95 R2508.1 ; v2(101.25,80.22) 101.25,80.23 R1923.1 R1919.1
SIO_EXT_SCI#: length 6.2
  BOTTOM w0.102: KBC24.17 166.65,69.39 v1(167.14,69.87) 168.16,70.89 168.59,70.89 169.35,71.65 169.35,72.01 169.3,72.06 R2501.1
SIO_EXT_SMI#: length 3.8
  BOTTOM w0.102: R2503.1 156.4,62.46 156.75,62.11 v1(157.11,62.11) 157.72,62.72 KBC24.119
SIO_SLP_S3: length 4.2
  BOTTOM w0.102: Q4003.5 126.88,122.38 v1(127.06,122.56) 127.39,122.56 127.53,122.41 Q4003.6 128.02,121.41 128.34,121.73 R4011.2
SIO_SLP_S3#: length 118.4
  L3 w0.127: v2(106.13,81) 106.13,79.2 105.02,78.09 105.02,77.12 102.34,74.44 102.34,72.78 101.78,72.23 101.78,71.28 100.48,69.97 94.25,69.97 92.9,68.62 88.39,68.62 86.34,66.57 86.33,66.56 86.33,65.41 85.13,64.21 85.13,62.86 81.74,59.47 v2(81.74,59.14)
  L4 w0.127: v2(81.74,59.14) 81.65,59.23 71.26,59.23 69.13,59.23 67.1,61.27 66.74,61.27 66.74,61.27 64.77,61.27 63.84,62.19 60.19,62.19 60.08,62.09 59.72,62.09 59.46,62.35 59.46,63.21 58.22,64.45 53.38,64.45 52.71,63.78 52.71,62.96 52.22,62.47 51.68,62.47 51.05,63.1 51.05,63.21 51.02,63.23 51.02,64.68 50.33,65.38 47.83,65.38 46.83,66.38 46.7,66.38 46.7,66.39 46.33,66.39 45.32,67.4 39.61,67.4 38.58,66.37 36.91,66.37 35.97,65.43 27.36,65.43 24.21,62.28 24.21,58.3 v2(24.24,58.27)
  BOTTOM w0.089: 109.21,81.59 109.36,81.64 109.68,81.96 110.24,82.17 110.34,82.2 110.45,82.32 110.78,82.44 110.86,82.47 110.93,82.53 110.96,82.55 111.08,82.67 111.1,82.67 CPU1.AC62
  BOTTOM w0.102: v2(106.13,81) 107.46,81.23 108.29,81.23 108.41,81.1 v1(108.57,81.1) 108.64,81.1 109.21,81.59 ; U4003.1 22.93,59.94 R4008.1 23.91,57.94 v2(24.24,58.27)
SIO_SLP_S4: length 4.2
  BOTTOM w0.102: Q4002.6 139.8,113.39 140.19,113.78 R4009.1 140.08,114.24 v1(139.28,114.24) 139.28,113.61 139.15,113.49 Q4002.5
SIO_SLP_S4#: length 131
  TOP w0.102: v2(27.52,60.94) v1(26.96,60.94)
  L4 w0.127: v2(116.34,81.74) 116.34,81.43 115.74,80.84 114.88,80.84 114.44,80.4 113.82,80.4 113.29,80.19 112.38,79.94 110.78,78.77 110.07,78.06 109.2,77.73 108.64,77.32 107.58,76.37 106.89,75.54 106.61,75.16 106.36,75.06 105.57,75.01 104.4,73.87 104.4,72.29 104.36,72.22 104.2,71.93 104.07,71.69 104.02,71.6 103.95,71.2 103.94,71.11 103.92,71 103.66,70.21 101.48,67.92 101.06,67.42 101.06,67.4 100.27,66.61 99.38,66.61 98.08,65.31 96.11,65.31 95.26,64.45 95.26,63.38 94.48,62.61 94.48,62.17 92.86,60.54 90.87,60.54 84.07,53.74 84.07,50.08 86.06,48.08 86.06,47.12 85.57,46.62 81,46.62 79.57,48.05 79.57,51.83 77.4,54 64.43,54 62.65,55.78 52.13,55.78 51.37,56.54 51.17,56.54 49.26,58.45 48.37,58.45 47.93,58.89 47.42,59.4 40.28,59.4 37.17,62.51 32.87,62.51 31.85,61.49 31.85,60.62 30.89,59.67 29.12,59.67 27.85,60.94 v2(27.52,60.94)
  BOTTOM w0.102: U4004.1 26.13,57.71 R4010.1 26.8,57.69 26.98,57.86 26.98,60.4 v2(27.52,60.94) ; CPU1.AK54 v2(116.34,81.74)
SLEEVE: length 6.4
  BOTTOM w0.203: HDA27.18 165.73,20.65 165.96,20.42 166.39,20.42 166.64,20.67
  BOTTOM w0.305: RN2901.3 168.94,19.91 168.66,19.64 167.65,19.64 167.42,19.87 v1(167.42,20.07) 167.42,20.6 v3(167.11,20.91)
  BOTTOM w0.356: v3(167.11,20.91) 166.88,20.91 166.64,20.67
  vias: v1(167.77,20.88)
SLEEVE_R:
  vias: v2(173.21,17.68) v2(173.6,18.18)
SM_RCOMP_0: length 2.5
  TOP w0.381: R2011.2 v2(126.17,80.67) 126.66,80.67 v1(127.06,80.27)
  BOTTOM w0.305: v2(126.17,80.67) 126.21,80.68 CPU1.AV34
SM_RCOMP_1: length 10.7
  L4 w0.381: v2(132.65,75.04) 131.86,77.22 129.41,79.66 129.14,79.66 128.74,80.07 128.74,80.63 128.63,80.93 128.32,81.24 128.08,81.24 v2(127.88,81.33)
  BOTTOM w0.305: v2(127.88,81.33) 127.84,81.31 CPU1.AV30
  BOTTOM w0.381: v2(132.65,75.04) R2010.2 v1(133.76,75.06)
SMB_ALERT#_CPU: length 11.3
  BOTTOM w0.14: R1701.2 99.28,89.06 101.37,89.06 101.8,88.63 102.38,88.41 103.51,87.99 v1(104.17,87.42) 104.75,87.19 105.04,87.19 105.36,87.11 105.37,87.1 105.52,87.04 105.68,87.04 106.1,86.62 107.37,86.2 107.5,86.17 109.01,86.17 109.02,86.17 109.39,86.17
SMB_CLK: length 29.3
  BOTTOM w0.14: Q1701.3 95.44,86.38 94.71,86.38 94.35,86.03 94.11,86.03 93.74,85.66 93.74,84.87 92.8,83.93 90.65,83.93 90.39,83.67 RN1703.3 90.39,82.8 90.51,82.68 v1(92.3,82.68) 93.02,82.68 94.49,84.15 96.28,84.15 97.22,83.21 101.76,83.21 104.35,85.8 106.63,85.8 107.2,85.67 109.53,85.67 CPU1.T62
SMB_CLK_CPU: length 126.9
  TOP w0.14: RN2401.3 170.95,51.61 170.49,51.15 170.49,51.13 v2(170.16,51.13) 170.03,51.13 169.82,51.34 166.05,51.34 165.91,51.2 160.06,51.2 159.33,51.93 152.35,51.93 151.26,53.02 150.15,53.02 149.28,52.15 v1(146.29,52.15) v2(143.44,52.15)
  L4 w0.127: v2(136.43,74.91) 136.84,74.91 137.68,74.07 137.68,68.02 141.47,64.23 141.47,53.9 143.22,52.15 v2(143.44,52.15)
  BOTTOM w0.14: v2(136.43,74.91) 135.65,74.1 135.49,74.02 134.66,72.68 132.75,70.49 124.74,62.48 100.47,62.48 99.23,63.72 97.8,63.72 97.03,62.95 95.96,62.95 95.87,63.04 89.83,63.04 88.68,64.19 83.91,64.19 83.48,63.76 75.61,63.76 75.6,63.77 Q2603.6 ; v2(170.16,51.13) 170.77,51.13 171.15,50.76 171.63,50.76 171.88,51.01 171.88,51.4 171.85,51.42 KBC24.67
SMB_DATA: length 22.3
  BOTTOM w0.102: 105.29,86.5 105.49,86.5 106.69,86.04 106.99,85.95 108.58,85.92 109.24,85.87 109.48,85.87 109.56,85.92 109.68,86.04 109.68,86.04 109.75,86.1 109.82,86.15 109.91,86.16 110,86.16 110.07,86.13 CPU1.T61
  BOTTOM w0.14: 105.29,86.5 104.32,86.5 101.54,83.73 99.75,83.73 98.38,85.1 Q1701.6 96.66,85.1 96.23,84.67 94.27,84.67 v1(93.24,83.63) 92.81,83.2 RN1703.4
SMB_DATA_CPU: length 130.2
  TOP w0.14: v2(142.91,51.77) 143.62,51.06 v1(147.43,51.06) 148.83,51.06 149.18,51.41 159.11,51.41 159.84,50.68 166.59,50.68 166.73,50.82 169.61,50.82 169.82,50.61 170.81,50.61 171.39,51.18 v2(171.45,51.18) 171.6,51.33 RN2401.4
  L4 w0.127: v2(136.89,73.92) 136.89,68.07 140.96,64 140.96,53.68 142.91,51.74 v2(142.91,51.77)
  BOTTOM w0.14: KBC24.68 v2(171.45,51.18) ; v2(136.89,73.92) 136.23,73.26 136.23,72.57 125.17,61.51 89.25,61.51 89.24,61.52 88.15,61.52 86.96,62.71 72.68,62.71 72.12,63.26 72.12,64.53 72.66,65.07 Q2603.3
SMBCLK1: length 188.4
  TOP w0.14: RN4302.3 148.74,177.91 EC4309.1 148.08,177.84 v2(147.96,177.73) ; PG4407.2 163.33,145.98 PR4415.2 163.81,144.52 163.81,143.75 v2(164.24,143.31) 164.57,142.98 v1(164.57,142.75)
  L3 w0.127: v2(151.72,175.36) 151.44,175.64 151.44,177.83 153.61,180 171.75,180 178.25,173.5 178.25,157.61 171.44,150.8 170.31,150.8 169.52,150.01 169.52,146.26 166.4,143.13 164.42,143.13 v2(164.24,143.31)
  L4 w0.127: v2(168.28,57.28) 167.85,57.71 167.85,58.68 168.55,59.37 168.55,69.56 168.76,69.77 168.76,70.58 167.47,71.86 167.47,73.84 166.87,74.44 166.87,76.67 166.53,77.01 166.53,84.49 166.78,84.75 166.78,86.19 167.81,87.22 167.81,88.31 167.79,88.34 167.79,93.14 168.35,93.7 168.35,131.74 173.39,136.78 173.39,139.02 172.24,140.16 172.24,142.09 170.14,144.2 166.99,144.2 166.28,143.49 164.42,143.49 v2(164.24,143.31)
  BOTTOM w0.14: v2(168.28,57.28) 169.73,55.83 170.11,55.83 170.94,55.01 170.94,53.64 170.65,53.36 KBC24.70 ; v2(147.96,177.73) 147.87,177.64 147.87,176.47 148.79,175.55 150.37,175.55 D4306.3 151.32,176 151.32,175.76 v2(151.72,175.36)
SMBDA1: length 204.3
  TOP w0.14: v1(160.79,143) 160.79,143.21 161.04,143.46 v2(161.04,143.51) 161.21,143.68 161.21,144.72 161.49,145 EC4310.1 PR4412.2 162.52,146.05 PG4408.2 ; RN4302.2 v2(147.63,178.41)
  L3 w0.127: v2(151.57,174.55) 150.93,175.19 150.93,178.04 153.4,180.5 171.96,180.5 178.76,173.71 178.76,157.4 171.65,150.29 170.62,150.29 170.03,149.71 170.03,146.05 166.61,142.62 161.48,142.62 161.04,143.05 v2(161.04,143.51)
  L4 w0.127: v2(161.04,143.51) 161.04,144.02 162.62,145.59 170.06,145.59 173.9,141.76 173.9,136.48 168.85,131.43 168.85,93.49 168.32,92.95 168.32,85.56 167.89,85.13 167.89,77.3 168.37,76.82 168.37,71.68 169.26,70.79 169.26,69.56 169.06,69.35 169.06,59.07 168.41,58.42 168.41,58.09 v2(168.31,57.99)
  BOTTOM w0.14: v2(151.57,174.55) 151.57,173.84 151.11,173.38 D4305.3 150.64,174.77 150.38,175.03 148.58,175.03 147.35,176.25 147.35,178.13 v2(147.63,178.41) ; v2(168.31,57.99) 169.91,56.39 170.29,56.39 171.46,55.22 171.46,53.8 171.05,53.4 KBC24.69
SOC_PWROK_CPU: length 189.5
  TOP w0.102: v2(162.8,43.87) 162.8,44.02 v1(163.53,44.76) 163.96,45.19 167.75,45.19 168.38,44.55 169.97,44.55 170.52,45.11 170.52,45.63 171.35,46.46 171.35,46.74 171.36,46.74 171.36,47.29 171.35,47.3 171.35,47.96 172.07,48.67 172.07,50 171.67,50.4 170.95,50.4 170.5,49.95 R2014.1 R2023.1 169.67,49.1 R2013.2
  L3 w0.127: v2(77.17,47.88) 77.53,47.53 79.56,47.53 81.15,49.11 81.15,49.71 81.16,49.73 81.16,51.37 81.13,51.39 81.13,52.99 79.34,54.78 79.34,60.08 84.3,65.03 84.3,67.07 84.35,67.12 84.35,67.93 84.48,68.06 84.48,68.06 86.68,70.27 90.33,70.27 93.43,73.37 93.43,74.88 96.73,78.18 100.12,78.18 100.81,78.87 100.81,80.45 100.91,80.55 100.91,86.86 102.05,88 106.24,88 107.04,87.2 108.69,86.12 109.61,85.2 110.12,83.46 111.05,82.53 111.13,82.53 112.17,81.49 112.17,81.29 112.43,81.03 112.86,81.03 116.13,82.18 116.55,82.6 v2(116.69,82.91)
  BOTTOM w0.102: CPU1.AG49 117.54,83.64 117,83.1 116.89,83.1 v2(116.69,82.91) ; v2(162.8,43.87) 162.47,43.87 162.35,43.98 155.31,43.98 153.87,45.42 152.48,45.42 148.14,49.76 144.2,49.76 141.36,46.92 86.65,46.92 83.64,43.91 78.4,43.91 77.17,45.14 v2(77.17,47.88)
SOC_RUNTIME_SCI#: length 97.2
  TOP w0.102: v2(168.92,71.83) 168.92,74.6 v1(167.3,76.22) 166.46,77.07 165.33,77.07 164.94,77.45 161.27,77.45 161.26,77.44 161.15,77.44 161.01,77.3 159.5,77.3 159.04,77.76 157.29,79.51 157.29,83.13 156.61,83.8 156.49,83.93 155.13,85.29 154.64,85.78 154.64,85.78 153.25,87.17 153.25,89.01 153.14,89.11 153.14,91.81 147.56,97.39 147.56,102.66 147.97,103.07 v2(147.97,111.2)
  L4 w0.127: v2(125.36,106.3) 127.36,109.59 129.08,111.31 129.56,111.72 134.06,111.72 134.53,111.25 147.92,111.25 v2(147.97,111.2)
  BOTTOM w0.102: RN2101.1 125.06,108.2 125.36,107.9 v2(125.36,106.3) 125.36,105.13 124.11,103.84 121.44,102.67 119.39,101.09 119.35,100.41 119.58,98.42 119.85,97.7 119.85,97.11 119.86,97.07 120.01,96.92 120.05,96.9 120.42,96.5 120.42,96.46 ; v2(168.92,71.83) 168.84,71.91 168.84,73.26 169.13,73.55 R2501.2
SPI1_HOLD_ROM_R: length 3.6
  TOP w0.14: v2(170.9,30.71) 170.92,30.69 171.36,30.69 171.52,30.85 171.52,30.9 v1(171.69,31.07) R2523.1
  BOTTOM w0.14: SPI252.7 170.24,30.05 v2(170.9,30.71)
SPI1_SO_ROM_R: length 5
  TOP w0.14: v1(165.18,29.8) v2(165.79,29.8)
  BOTTOM w0.14: R2528.2 162.02,30.67 162.28,30.93 EC2506.1 162.91,30.93 163.79,30.05 SPI252.2 165.54,30.05 v2(165.79,29.8)
SPI1_VCC_1D8V: length 6.6
  TOP w0.508: v2(168.37,28.86) 168.45,28.93 v1(169.27,28.93) 171.2,28.93 171.59,29.33 C2504.1 172.67,29.33 C2503.1 R2530.1
  BOTTOM w0.508: v2(168.37,28.86) 168.41,28.86 168.49,28.78 SPI252.8
SPI1_WP_ROM_R: length 3.3
  BOTTOM w0.14: SPI252.3 163.96,31.32 163.61,31.68 163.61,32.04 R2522.2 162.53,32.65 v1(162.11,33.07)
SPI_CLK_ROM: length 34.7
  TOP w0.14: v2(165.92,30.61) v1(166.58,30.61) ; v2(170.92,31.8) 171.41,32.29 v1(171.69,32.29) 172.31,32.29 EC2505.1
  L3 w0.127: v2(165.92,30.61) 165.79,30.74 162.19,30.74 161.45,30 160.21,30 158.94,31.27 158.94,42.19 159.67,42.93 159.67,44.29 161.12,45.73 161.12,47.27 v2(160.48,47.91)
  BOTTOM w0.14: v2(165.92,30.61) 166.96,30.61 167.67,31.32 SPI252.6 170.44,31.32 v2(170.92,31.8) ; v2(160.48,47.91) 160.21,48.19 R2418.2
SPI_CLK_ROM_CPU: length 85
  TOP w0.14: v2(80.98,69.8) 80.98,69.27 81.17,69.08 81.17,67.88 81.26,67.79 81.26,66.06 81.73,65.59 81.84,65.47 81.84,62.06 78.79,59 78.79,58.15 78.27,57.64 77.32,57.64 65.8,46.12 64.33,46.12 63.7,46.76 62.09,46.76 v1(61.79,47.05) 61.25,47.6 57.17,47.6 R2502.2
  L4 w0.127: v2(80.98,69.8) 80.98,70.33 81.31,70.65 83.54,70.65 83.73,70.85 84.16,71.27 85.09,72.19 85.51,72.62 88.37,75.48 88.37,77.02 94.51,83.16 94.52,83.16 98.01,86.65 98.01,87.89 105.88,95.76 107.22,95.76 108.21,94.76 109.07,94.76 109.1,94.74 v2(109.81,94.74)
  BOTTOM w0.102: CPU1.C56 110.82,93 110.82,93.58 110.54,94.36 110.48,94.42
  BOTTOM w0.14: v2(109.81,94.74) 110.15,94.74 110.48,94.42
SPI_CLK_ROM_R1: length 5.7
  TOP w0.14: v1(58.3,46.89) 58.27,46.92 56.37,46.92 56.1,47.18 R2502.1 EC2503.1 55.68,48.31 v2(55.46,48.08)
  BOTTOM w0.14: v2(55.46,48.08) 55.73,48.36 SPI251.6
SPI_CS_CPU_N0: length 72.6
  TOP w0.14: R2531.1 64.38,51.95 68.08,51.95 70.19,54.05 v1(70.52,54.05) 71.22,54.05 79.05,61.88 79.05,65.55 79.43,65.93 79.43,67.44 79.78,67.79 79.78,68.51 79.78,69.11 v2(79.97,69.29)
  L4 w0.127: v2(79.97,69.29) 80.17,69.5 80.17,70.23 81.51,71.58 83.61,71.58 85.24,73.21 85.24,73.95 85.87,74.58 86.43,74.58 87.84,75.99 87.84,77.22 94.29,83.67 94.31,83.67 97.51,86.86 97.51,88.1 105.67,96.27 107.43,96.27 108.4,95.3 109.2,95.3 v2(109.3,95.25)
  BOTTOM w0.089: 109.7,93.69 109.84,93.55 109.95,93.39 CPU1.B57
  BOTTOM w0.14: 109.7,93.69 109.55,93.84 109.54,93.87 109.34,94.07 109.32,94.19 109.32,95.24 v2(109.3,95.25)
SPI_CS_ROM_N0_R: length 25.2
  TOP w0.14: v2(161.63,46.84) v1(161.04,46.84)
  L3 w0.127: v2(161.63,46.84) 161.63,45.52 160.18,44.07 160.18,42.6 159.49,41.91 159.49,31.43 160.02,30.9 160.04,30.9 v2(160.43,30.51)
  BOTTOM w0.14: v2(161.63,46.84) 161.63,47.14 161.98,47.5 R2416.2 ; v2(160.43,30.51) 160.99,29.95 161.75,29.95 161.89,30.09 R2535.2 163.43,29.55 163.43,29.11 163.76,28.78 SPI252.1
SPI_CS_ROM_N0_R1: length 4.2
  TOP w0.14: v2(62.39,50.32) 62.34,50.37 62.34,50.8 v1(62.44,50.9) 62.5,50.97 R2532.2 R2531.2
  BOTTOM w0.14: SPI251.1 62.97,50.9 v2(62.39,50.32)
SPI_HOLD_ROM: length 85.6
  TOP w0.14: R2517.2 v1(59.19,49.18) 60.41,49.18 62.31,47.28 63.91,47.28 64.55,46.64 65.58,46.64 80.88,61.94 80.88,65.7 80.74,65.84 80.74,67.57 80.59,67.72 80.59,68.26 v2(80.57,68.28)
  L4 w0.127: v2(108.21,93.33) 108.21,94.01 108.1,94.13 107.79,94.43 107.42,94.43 107.11,94.12 106.82,93.6 106.73,93.26 106.24,92.78 105.86,92.78 105.08,92 104.43,92 102.59,90.16 101.87,90.16 99.72,88.01 99.72,86.97 97.25,84.5 97.25,83.46 96.51,82.72 96.51,81.47 91.78,76.73 91.78,76.73 91.45,76.4 91.02,75.98 89.77,74.73 88.7,74.73 85.59,71.62 84.18,70.22 84.17,70.2 82.6,68.63 81.4,68.63 81.04,68.28 v2(80.57,68.28)
  BOTTOM w0.089: v2(108.21,93.33) 108.34,93.04 108.4,92.91 108.4,92.86 CPU1.B61
  BOTTOM w0.14: v2(80.57,68.28) 81.2,67.64 82.81,67.64 84.5,69.33 R2534.1
SPI_HOLD_ROM_R: length 3.4
  TOP w0.14: v2(55.3,49.76) 55.63,50.09 v1(55.89,50.09) 56.1,49.87 R2517.1
  BOTTOM w0.14: v2(55.3,49.76) 55.44,49.63 SPI251.7
SPI_SI_ROM: length 34.3
  TOP w0.14: v2(170.82,32.59) 170.82,32.84 171.69,33.71 v1(172.55,33.71) 172.66,33.59 EC2504.1 ; v2(162.94,47.12) 162.94,47.4 v1(163.18,47.63)
  L3 w0.127: v2(162.94,47.12) 162.94,46.3 161.68,45.04 161.68,44.3 160.43,43.06 160.43,42.17 159.77,41.51 159.77,31.57 160.1,31.24 160.67,31.24 161.24,31.82 165.96,31.82 v2(166.28,32.13)
  BOTTOM w0.14: v2(166.28,32.13) 168.49,32.13 168.94,32.59 SPI252.5 v2(170.82,32.59) ; R2401.2 163.76,47.94 v2(162.94,47.12)
SPI_SI_ROM_CPU: length 81.4
  TOP w0.14: v2(81.63,68.15) 81.78,68 81.78,66.27 82.1,65.95 82.36,65.69 82.36,61.84 79.31,58.78 79.31,57.94 78.49,57.12 77.6,57.12 65.38,44.91 v1(64.85,44.91) 62.75,44.91 61.18,46.48 59.41,46.48 58.22,45.29 R2513.2
  L4 w0.127: v2(81.63,68.15) 82.14,68.15 82.37,68.38 82.7,68.38 84.01,69.68 84.05,69.72 84.13,69.81 84.44,70.11 85.77,71.44 88.81,74.48 89.88,74.48 91.27,75.87 91.62,76.21 92.03,76.62 92.03,76.63 96.77,81.36 96.77,82.61 97.59,83.44 97.59,84.49 99.97,86.86 99.97,87.9 101.98,89.91 102.7,89.91 104.53,91.75 105.19,91.75 105.96,92.52 106.35,92.52 107.06,93.23 107.06,93.51 107.41,93.86 107.49,93.86 v2(107.54,93.91)
  BOTTOM w0.102: CPU1.A58 109.11,93.49 108.98,93.55 108.83,93.55 108.44,93.94 107.63,93.94 107.6,93.91 v2(107.54,93.91)
SPI_SI_ROM_R1: length 5.9
  TOP w0.14: v2(55.43,46) 55.56,46.13 EC2501.1 R2513.1 56.1,45.05 56.4,44.76 v1(58.05,44.76)
  BOTTOM w0.14: SPI251.5 56.24,47.09 55.43,46.28 v2(55.43,46)
SPI_SO_ROM: length 69.2
  TOP w0.14: v2(80.58,68.91) 80.53,68.86 80.52,68.86 80.05,68.39 80.05,67.68 79.69,67.33 79.69,65.82 79.32,65.45 79.32,61.77 v1(68.13,50.57) 67.27,49.71 R2510.1
  L4 w0.127: v2(107.37,94.87) 106.99,95.25 106.11,95.25 105.79,94.92 105.79,93.72 105.25,93.18 104.83,93.18 102.75,91.1 102.75,90.68 102.48,90.42 101.77,90.42 98.9,87.55 98.9,87.52 98.81,87.44 98.81,86.72 96.89,84.8 96.89,83.46 96.26,82.83 96.26,81.57 91.52,76.84 91.52,76.83 91.26,76.57 90.77,76.09 89.67,74.99 88.6,74.99 85.41,71.8 84.16,70.55 84.09,70.49 83.93,70.32 82.52,68.91 v2(80.58,68.91)
  BOTTOM w0.089: CPU1.B58 109.67,92.96 109.67,93.39 109.52,93.53 109,93.78 108.87,93.78 108.52,94.13 108.04,94.13 108.03,94.13 107.73,94.43 107.73,94.43 107.37,94.79 107.37,94.87 v2(107.37,94.87)
SPI_SO_ROM_R1: length 6.4
  TOP w0.14: R2510.2 66.16,49.86 v1(65.41,49.86) 65.18,49.86 64.65,49.33 63.89,49.33 63.39,49.82 EC2502.1 62.91,50.14 v2(62.4,49.63)
  BOTTOM w0.14: SPI251.2 v2(62.4,49.63)
SPI_VCC_1D8V: length 6.6
  TOP w0.508: v2(55.46,50.75) v1(56.22,51.51) 56.43,51.73 C2501.1 C2502.1 60.18,51.73 R2529.1
  BOTTOM w0.508: SPI251.8 55.6,50.9 v2(55.46,50.75)
SPI_WP_ROM: length 73.9
  TOP w0.14: R2514.1 R2533.1 64.21,47.61 64.78,47.04 65.61,47.04 80.32,61.75 80.32,62.51 80.18,62.64 80,62.64 79.86,62.78 79.86,63.06 80,63.2 80.18,63.2 80.32,63.34 80.32,63.62 80.18,63.76 80,63.76 79.86,63.9 79.86,64.18 80,64.32 80.18,64.32 80.32,64.46 80.32,65.19 80.29,65.21 v1(80.29,65.24) v2(80.29,67.29)
  L4 w0.127: v2(80.29,67.29) 81.64,67.29 82.47,68.12 82.81,68.12 83.48,68.8 84.19,69.5 84.23,69.54 84.39,69.71 84.62,69.93 85.91,71.22 88.78,74.09 89.86,74.09 91.53,75.77 91.79,76.02 92.24,76.47 92.29,76.52 92.29,76.52 97.02,81.26 97.02,82.38 98.36,83.72 98.36,83.9 98.03,84.23 98.03,84.41 98.21,84.59 98.39,84.59 98.72,84.26 98.9,84.26 99.11,84.47 99.11,85.64 100.22,86.75 100.22,87.79 102.08,89.66 102.8,89.66 104.64,91.49 105.3,91.49 106.07,92.27 106.45,92.27 107.46,93.27 107.57,93.27 107.58,93.28 v2(107.58,93.28)
  BOTTOM w0.102: CPU1.B60 109.04,92.61 109.04,93.09 108.99,93.21 108.84,93.36 108.76,93.36 108.38,93.73 108,93.73 107.58,93.31 v2(107.58,93.28)
SPI_WP_ROM_R: length 3.7
  TOP w0.14: R2514.2 63.32,49.01 63.13,49.2 62.78,49.2 v2(62.47,48.89) 62.13,49.23 v1(62,49.23)
  BOTTOM w0.14: SPI251.3 63,48.36 v2(62.47,48.89)
SUS_PWR_ACK_R: length 4.9
  BOTTOM w0.102: R2411.2 172.26,70.36 171.33,70.36 170.72,69.75 170.31,69.75 v1(170.19,69.62) 169.85,69.29 KBC24.25
SUS_PWRDN_ACK: length 90.9
  TOP w0.102: v2(170.52,70.18) 170.23,70.47 v1(169.11,70.47) 167.78,70.47 167.26,69.95 164.29,69.95 162.71,71.53 157.64,71.53 154.83,68.72 149.6,68.72 145.73,64.85 143.52,64.85 v2(143.36,64.7)
  L3 w0.127: v2(137.14,77.37) 136.38,77.78 134.17,79.99 131.8,81.11 128.08,82.48 126.22,82.48 125.88,82.82 125.88,82.88 125.63,83.12 125.26,83.12 125.23,83.1 125.08,82.96 124.35,82.7 122.34,82.7 122.09,82.6 120.72,81.68 120.71,81.67 119.72,81.02 119.43,80.72 119.11,80.72 118.58,80.48 117.91,80.12 115.68,80.12 115.53,79.97 115.16,79.97 115.01,80.12 113.31,80.12 113.3,80.11 112.93,80.11 112.91,80.12 112.41,80.12 111.92,80.65 111.92,81.38 111.03,82.27 110.04,82.27 109.47,82.68 109.12,82.68 109.08,82.64 108.8,82.64 108.54,82.38 108.54,82.1 v2(108.4,81.95)
  L4 w0.127: v2(143.36,64.7) 142.78,64.7 140.54,66.94 140.54,74.61 137.78,77.37 v2(137.14,77.37)
  BOTTOM w0.102: CPU1.AC63 110.29,82.44 109.4,82.11 109.28,81.87 108.91,81.73 108.42,81.96 v2(108.4,81.95) 107.65,81.64 106.11,81.51 R1807.2 104.52,80.57 R1808.1 ; v2(170.52,70.18) 170.77,70.44 170.84,70.44 171,70.59 171.64,70.59 172.68,71.63 R2411.1
SUSCLK: length 192.1
  TOP w0.14: R1803.2 108.42,78 108.19,77.74 108.11,77.65 107.68,77.18 106.26,75.76 v2(106.26,75.72)
  L3 w0.127: v2(106.26,75.72) 105.16,74.63 105.16,74.2 102.78,71.81 102.78,70.87 100.72,68.81 97.08,68.81 96.87,68.6 96.25,68.6 94.39,66.74 91.14,66.74 83,58.61 83,57.24 82.07,56.31 82.07,51.78 82.1,51.76 82.1,49.33 76.88,44.11 76.88,32.54 82.16,27.26 132.67,27.26 134.26,27.26 135.19,26.34 137.17,26.34 137.6,25.91 141.97,25.91 142.78,25.1 145.75,25.1 146.32,25.67 146.98,25.67 148.9,27.59 150.91,27.59 156,32.68 156,42.17 154.57,43.61 154.57,53.23 158.76,57.43 v2(160.87,57.43)
  BOTTOM w0.14: EC1801.1 107.56,73.57 v1(107.2,73.94) 106.26,74.88 v2(106.26,75.72) ; KBC24.77 167.85,53.43 167.95,53.52 167.95,53.91 167.37,54.48 167.37,55.56 165.78,57.15 161.15,57.15 v2(160.87,57.43)
SYS_PRES1#: length 7.9
  TOP w0.102: R4301.2 154.5,178.81 AFTP4305.1 156.25,180.55 BATT2.6 BATT1.6
SYS_PWROK: length 33.7
  TOP w0.102: R2426.2 EC2402.1 v2(167.04,50.17) 167.27,50.4 v1(167.95,50.4) 167.98,50.4 168.16,50.57 169.08,50.57 R2013.1 ; R2607.2 162.75,71.99 163.84,70.89 166.07,70.89 v2(166.12,70.84)
  L4 w0.127: v2(166.12,70.84) 165.97,70.69 165.97,68.69 166.24,68.42 166.24,65.19 165.96,64.9 165.96,61.74 166.52,61.18 166.52,51.14 167.04,50.62 v2(167.04,50.17)
  BOTTOM w0.102: KBC24.84 165.05,51.65 165.5,51.21 166.24,51.21 167.04,50.41 v2(167.04,50.17)
SYS_PWROK_G: length 4.3
  TOP w0.102: Q2602.G 160.32,74.16 v1(159.75,73.59) 159.75,72.71 R2609.1 160.47,71.99 R2607.1
T_CRIT#: length 110.6
  TOP w0.102: v1(163.41,71.91) 163.25,71.91 162.48,72.68 R2601.1 162.48,73.22 162.28,73.41 162.28,74.22 160.07,76.44 159.14,76.44 157.84,77.73 156.4,79.18 156.4,82.8 155.87,83.32 154.28,84.91 v2(152.81,84.91)
  L3 w0.102: v2(137.37,76.74) 141.43,76.74 149.61,84.91 v2(152.81,84.91)
  BOTTOM w0.102: R2606.2 82.09,72.2 81.69,71.81 81.69,71.27 81.43,71.01 U2601.4 80.6,70.87 79.31,69.57 79.31,67.08 80.28,66.11 85.94,66.11 86.47,65.58 90.34,65.58 90.63,65.28 95.56,65.28 96.41,64.44 99.86,64.44 101.23,63.07 124.63,63.07 132.38,70.83 134.26,72.98 135.11,74.35 136.33,75.39 136.33,75.69 v2(137.37,76.74)
THERM_SYS_SHDN#: length 3.4
  TOP w0.14: Q2602.S 163.04,74.36 164.09,74.36 R2602.1 164.19,74.26 v1(164.19,73.41) 163.61,72.82 R2601.2
TOUCH_INT_CPU: length 4.2
  BOTTOM w0.102: TP2101.1 122.93,99.56 122.96,99.5 122.96,99.33 123.18,98.78 123.34,98.35 123.5,98.19 123.5,98.19 123.64,98.05 123.64,98 CPU1.C26
TOUCH_PANEL_EN: length 211.3
  TOP w0.102: v2(151.06,57.79) 151.11,57.74 R2427.2 151.71,56.5 152.46,55.76 v1(154.96,55.76) 156.42,55.76 157.94,57.28 157.94,57.28 160.08,59.41 163.28,59.41 164.02,60.15 166.48,60.15 168.1,61.77 v2(169.53,61.77) ; RN5501.5 v2(105.12,177.71)
  L4 w0.102: v2(164.32,135.26) 163.77,135.26 159.8,131.29 159.8,127.07 158.76,126.03 158.76,107.88 159.77,106.87 159.77,101.86 154.11,96.2 154.11,90.3 154.69,89.72 154.69,88 153.4,86.71 151.75,85.06 151.75,78.36 149.25,75.86 149.25,72.25 152.46,69.04 152.46,66.91 152.05,66.5 152.05,65.23 151.59,64.77 151.59,62.25 151.17,61.83 151.17,58.81 151.06,58.7 v2(151.06,57.79)
  BOTTOM w0.102: D2401.A 151.62,58.27 151.14,57.79 v2(151.06,57.79) ; v2(169.53,61.77) 169.47,61.83 169.47,64.67 170.24,65.43 170.24,66.5 169.98,66.76 169.3,66.76 169.05,67 KBC24.23 ; v2(105.12,177.71) 106.99,179.58 110.68,179.58 113.85,182.76 119.32,182.76 122.31,179.76 122.31,167.54 127.36,162.49 127.36,156.92 132.6,151.68 138.3,151.68 146.52,143.46 150.08,143.46 155.17,138.37 161.21,138.37 v2(164.32,135.26)
TOUCH_RST_CPU: length 5.3
  BOTTOM w0.102: CPU1.C33 120.99,96.31 120.59,96.72 120.58,96.72 120.44,96.86 120.44,97.06 120.45,97.09 120.45,97.27 120.24,97.84 120.24,98.5 120.68,99.43 120.89,99.64 121.03,99.93 121.07,100.4 TP2102.1
TP_CLK_C: length 17.5
  TOP w0.14: AFTP6527.1 139.83,18.47 139.83,17.71 139.58,17.45 v2(139.58,17.38)
  BOTTOM w0.14: RN6503.4 139.79,18.7 139.68,18.59 139.68,17.48 v2(139.58,17.38) 139.8,17.16 139.8,14.72 138.54,13.46 138.54,8.74 140.68,6.6 TP1.1
TP_DATA_C: length 14.5
  TOP w0.14: AFTP6528.1 141.03,17.38 v2(140.32,17.38)
  BOTTOM w0.14: RN6503.3 140.44,18.62 140.32,18.49 v2(140.32,17.38) 140.32,14.78 140.32,14.5 139.15,13.34 139.15,9.1 140.64,7.6 TP1.2
TP_DISABLE#_R: length 4.7
  BOTTOM w0.102: R2494.2 v1(173.31,69.69) 173.3,69.67 172.47,69.67 172.14,69.34 172.14,69.27 171.89,69.01 171.81,69.01 171.45,68.65 KBC24.29
TP_EN#: length 9.1
  TOP w0.102: RN2404.3 170.28,65.5 170.43,65.36 170.43,63.88 v2(170.41,63.86) 170.28,63.73 v1(169.78,63.73) R6516.1
  BOTTOM w0.102: v2(170.41,63.86) 170.41,64.38 171.23,65.2 171.81,65.2 172.93,66.32 KBC24.33
TP_I2C_CLK: length 5.9
  BOTTOM w0.14: R6518.1 EC6504.1 142.37,19.05 142.76,19.43 142.76,20.25 142.88,20.37 RN1906.1 143.33,20.92 143.19,21.06 142.35,21.06 141.97,21.44 Q1902.1
TP_I2C_CLK_C: length 25.7
  TOP w0.14: R6515.2 142.5,30.61 140.95,29.05 140.95,22.82 142.63,21.13 AFTP6524.1 142.63,17.58 v2(143.21,16.99)
  BOTTOM w0.14: R6518.2 v2(143.21,16.99) 143.03,16.99 141.94,15.9 141.94,14.63 142.53,14.05 142.53,13.26 142.32,13.06 140.85,13.06 140.65,12.85 140.65,11.74 140.78,11.6 TP1.6
TP_I2C_CLK_D: length 133.2
  L3 w0.127: v2(82.15,70.21) 82.11,70.25 79.49,70.25 75.19,65.94 75.19,63.64 73.83,62.29 73.83,52.88 76.07,50.64 76.07,45.34 75.86,45.14 75.86,30.01 79.88,25.99 133.38,25.99 135.09,24.28 140.57,24.28 141.28,23.57 141.81,23.57 141.86,23.52 142.28,23.52 142.33,23.57 144.3,23.57 v2(144.7,23.97)
  BOTTOM w0.14: Q1901.6 90.9,70.42 90.51,70.82 90.51,71.77 90.04,72.24 88.47,72.24 87.85,72.87 RN1907.1 86.49,72.87 86.36,72.74 86.36,71.98 86.07,71.69 84.69,71.69 v1(84.32,71.31) 83.08,70.08 82.28,70.08 v2(82.15,70.21) ; v2(144.7,23.97) 144.56,23.83 144.56,22.07 144.42,21.93 Q1902.6
TP_I2C_DATA: length 11.4
  BOTTOM w0.14: R6519.1 EC6502.1 144.91,18.95 144.71,19.15 143.47,19.15 143.33,19.29 RN1906.2 143.8,19.72 143.9,19.81 143.9,20.47 145.09,21.67 145.09,22.74 v1(145.22,22.86) 145.22,24.18 144.91,24.49 144.3,24.49 143.85,24.03 Q1902.4
TP_I2C_DATA_C: length 22.5
  TOP w0.14: v2(144.03,16.74) 144.03,17.05 143.8,17.27 AFTP6530.1 143.8,27.99 146.15,30.34 R6511.2
  BOTTOM w0.14: TP1.7 142.55,12.6 142.96,13.01 142.96,14.22 142.4,14.78 142.4,15.75 143.14,16.49 143.77,16.49 v2(144.03,16.74) 144.03,17.5 144.05,17.53 R6519.2
TP_I2C_DATA_D: length 123.5
  L3 w0.127: v2(81.57,69.46) 81.46,69.36 80.64,69.36 80.26,69.74 79.7,69.74 75.7,65.73 75.7,63.43 74.34,62.08 74.34,53.09 76.58,50.85 76.58,45.13 76.37,44.93 76.37,30.22 80.09,26.5 133.59,26.5 135.3,24.79 141.31,24.79 v2(142.07,24.03)
  BOTTOM w0.14: Q1901.3 v1(88.26,71.72) 87.76,72.22 RN1907.2 86.92,71.8 86.28,71.17 85.01,71.17 83.49,69.65 83.39,69.65 83.3,69.56 81.67,69.56 v2(81.57,69.46) ; Q1902.3 141.97,23.93 v2(142.07,24.03)
TP_IN#_CPU: length 213.1
  TOP w0.102: v2(66.99,68.38) 66.99,68.58 v1(67.27,68.86)
  L3 w0.127: v2(136.81,22.99) 134.94,22.99 132.95,24.98 60.19,24.98 54.45,30.71 54.45,33.98 61.84,41.37 62.02,41.37 65.73,45.08 65.73,51.4 65.67,51.46 65.67,63.62 65.76,63.7 65.76,67.15 v2(66.99,68.38)
  L4 w0.127: v2(119.09,92.07) 118.59,92.57 118.03,92.83 117.81,92.83 117.67,92.78 117.5,92.78 117.34,92.85 117.2,92.99 116.8,94.08 116.8,94.14 116.68,94.49 115.58,95.59 115.44,95.97 115.38,96.15 115.29,96.38 115.24,96.44 115.16,96.64 115.16,96.91 v2(115.39,97.39) 115.02,97.56 114.75,97.82 114.75,98.45 114.93,98.62 114.93,98.99 114.45,99.48 109.18,99.48 107.73,100.92 105.9,100.92 104.9,99.92 104.9,96.93 96.51,88.54 96.51,87.51 94.84,85.84 94.18,85.84 93.92,85.58 93.24,84.89 92.91,84.11 92.51,83.7 85.3,76.49 85.15,76.34 84.25,75.44 84.25,73.89 84.25,73.62 83.2,72.57 81.05,72.57 79.42,70.93 78.74,70.93 78.66,70.93 76.96,69.23 76.54,69.23 72.47,69.23 72.12,68.87 67.48,68.87 v2(66.99,68.38)
  BOTTOM w0.102: R2114.1 115.23,99.06 114.85,98.34 114.79,98.17 114.79,97.84 115.12,97.51 v2(115.39,97.39) ; CPU1.J39 v2(119.09,92.07) ; Q6508.S 139.35,23.87 138.64,23.17 136.99,23.17 v2(136.81,22.99)
TP_IN#_CPU_D: length 21.1
  TOP w0.102: v2(144.36,19.95) 144.36,20.04 144.2,20.2 144.2,25.78 v2(144.25,25.83)
  BOTTOM w0.102: Q6509.D 145.68,18.82 144.95,19.55 v1(144.74,19.55) 144.74,19.55 144.36,19.93 v2(144.36,19.95) ; R6523.1 136.4,23.44 137,24.04 Q6508.D 138.36,26.08 139.3,27.01 139.3,27.55 R6525.2 140.14,27.24 140.14,26.34 140.38,26.1 142.4,26.1 142.67,25.83 v2(144.25,25.83)
TP_INT#_EC: length 80.5
  TOP w0.102: v2(166.94,29.31) 166.56,28.93 164.88,28.93 163.79,27.84 162.4,27.84 161.27,26.72 v1(160.97,26.72) 160.67,26.42 153.91,26.42 152.92,27.41 149.16,27.41 v2(148.39,28.17)
  L4 w0.127: v2(166.94,29.31) 166.94,29.95 167.41,30.42 167.41,33.33 168.93,34.85 168.93,37.92 172.09,41.09 172.38,41.09 173.83,42.54 173.83,50.66 172.99,51.5 172.99,53 171.77,54.22 171.77,55.68 171.43,56.03 171.43,57.94 170.81,58.56 170.81,60.48 172.21,61.88 172.21,65.55 v2(171.51,66.25)
  BOTTOM w0.102: v2(171.51,66.25) 171.08,66.68 170.59,66.68 170.25,67.02 KBC24.26 ; v2(148.39,28.17) 148.25,28.03 146.19,28.03 145.96,27.8 145.96,27.28 144.75,26.07 144.75,25.72 144.43,25.4 142.77,25.4 142.31,25.87 141.6,25.87 139.86,24.14 139.86,24.06 138.74,22.94 137.4,22.94 137.01,22.55 R6523.2
TP_ON#_GATE: length 77.6
  TOP w0.102: R6516.2 167.7,63.74 v1(166.8,63.74) v2(166.4,63.35)
  L4 w0.102: v2(166.4,63.35) 166.77,62.98 166.77,51.23 167.47,50.53 167.47,49.99 167.27,49.78 167.27,46.49 167.65,46.1 167.65,44.31 167.01,43.68 165.97,42.64 165.97,38.51 165.87,38.41 163.79,36.33 163.79,34.03 163.51,33.75 163.51,30.23 162.16,28.88 161.12,28.88 157.89,25.66 153.57,25.66 149.87,21.95 146.34,21.95 146.29,21.9 136.79,21.9 135.91,21.02 v2(135.03,21.02)
  BOTTOM w0.102: Q6505.G 133.8,25.9 134.02,25.68 135.08,25.68 135.34,25.42 135.34,24.13 134.96,23.75 C6503.1 134.5,22.82 134.5,21.97 134.23,21.7 Q6504.G v2(135.03,21.02)
TP_RESET: length 4.2
  TOP w0.102: v1(117.74,175.23) 117.94,175.43 v2(117.94,176.63) R5533.2
  BOTTOM w0.102: v2(117.94,176.63) 117.65,176.63 117.42,176.54 116.99,176.11 116.89,175.88 LCD1.38
TP_VDD: length 16.1
  TOP w0.508: AFTP6529.1 v2(133.1,19.66)
  L3 w0.508: v2(145.22,19.89) 145.2,19.89 144.62,19.31 141.36,19.31 v2(141.33,19.28) 141.31,19.31 133.46,19.31 v2(133.1,19.66)
  BOTTOM w0.508: v2(145.22,19.89) 145.24,19.92 148.07,19.92 Q6509.G
TPAN_VDD:
  vias: v3(119.9,174.73) v3(120.23,173.96)
TPAN_VDD_F:
  vias: v1(125.69,167.44)
TPNL_EN: length 16.1
  TOP w0.102: RN5501.4 107.71,175.99 108.52,175.19 108.57,173.92 108.67,173.61 108.91,173.43 109.06,173.43 110.22,173.48 111.28,173.48 113.46,173.87 115.55,174.85 AFTP5520.1 116.67,175.8 116.67,176.46 v2(116.69,176.48)
  BOTTOM w0.102: LCD1.37 116.42,175.55 116.42,176.2 v2(116.69,176.48)
TRST_PD: length 13.3
  TOP w0.102: v1(65.87,72.7) 65.3,72.13 R9921.1 64.36,72.13 63.43,71.2 62.9,71.2 61.96,70.26 61.96,67.93 61.65,67.62 58.64,67.62 57.93,66.92 XDP1.8
TS#_DIMM0_1: length 2.1
  TOP w0.102: TP1201.1 143.8,28.72 v2(143.42,29.1)
  BOTTOM w0.102: DM1.198 143.47,29.17 143.42,29.11 v2(143.42,29.1)
TS_USB20_N: length 104.7
  TOP w0.127: R5506.2 119.58,163.93 v2(119.58,162.95)
  L3 w0.114: v2(119.58,162.95) 119.45,162.95 119.31,163.1 119.31,163.43 119.44,163.55 120.54,163.55 124.16,159.93 124.16,156.44 132.54,148.06 138.46,148.06 143.17,143.35 147.56,143.35 149.13,141.78 149.13,139.37 153.23,135.27 153.23,106.52 144.93,98.22 144.66,97.94 144.57,97.85 142,96.6 139.62,95.54 138.31,94.97 136.42,93.81 135.71,93.38 134.62,92.88 134.35,92.67 v2(134.16,92.27)
  BOTTOM w0.127: v2(134.16,92.27) 134.16,92.5 133.98,92.69 133.76,92.69 CPU1.Y10
TS_USB20_P: length 105.2
  TOP w0.127: v2(118.89,162.94) 118.89,163.91 R5516.2 ; v2(134.85,92.49) 135.12,92.61 v1(135.36,92.71)
  L3 w0.114: v2(134.85,92.49) 134.94,92.78 135.81,93.18 135.83,93.18 136.53,93.62 138.41,94.76 138.42,94.77 139.61,95.28 139.71,95.33 142.09,96.4 144.7,97.66 144.73,97.69 145.08,98.05 153.46,106.42 153.46,135.36 149.36,139.46 149.36,141.88 147.66,143.58 143.26,143.58 138.56,148.29 132.64,148.29 124.39,156.54 124.39,160.02 120.63,163.78 119.34,163.78 119.08,163.52 119.08,163.13 v2(118.89,162.94)
  BOTTOM w0.127: CPU1.Y9 v2(134.85,92.49)
UART2_RTS#: length 1.1
  TOP w0.102: v2(118.18,91.78) 118.17,91.78 TP1802.1
  BOTTOM w0.102: CPU1.L41 v2(118.18,91.78)
UART2_RXD: length 114.9
  TOP w0.14: v1(60.79,44.12) 61,43.91 DB3.3 61,42.39 61.58,41.81 v2(61.83,41.81)
  L3 w0.127: v2(69.48,70.08) 68.64,69.24 67.22,69.24 65.5,67.52 65.5,64.13 65.37,64.01 65.37,60.13 64.49,59.24 64.49,44.46 v2(61.83,41.81)
  L4 w0.127: v2(117.93,92.39) 118.44,92.15 118.65,91.94 118.65,91.89 118.83,91.7 118.99,91.63 119.25,91.63 119.39,91.74 119.46,91.81 119.54,91.97 119.54,92.52 119.02,94.67 118.84,95.97 117.88,98.63 117.88,99.52 117.87,99.53 115.85,101.55 115.69,101.55 115.4,101.84 114.65,101.84 113.27,103.23 112.33,103.23 110.24,103.23 109.69,103.78 109.33,103.78 108.41,103.78 107.9,104.29 106.03,104.29 105.28,103.54 102.84,103.54 102.26,102.96 102.26,102.38 102.57,102.07 102.57,97.74 95.51,90.67 95.51,89.69 95.24,89.43 95.24,89.3 94.07,88.13 93.68,88.13 93.34,87.79 93.34,87.69 93.34,86.79 92.73,86.18 91.98,85.43 91.88,85.33 91.8,85.2 91.58,84.58 82,74.99 81.87,74.86 78.55,71.95 78.5,71.95 74.76,71.95 73.06,70.25 72.05,70.25 71.89,70.08 v2(69.48,70.08)
  BOTTOM w0.14: CPU1.J41 v2(117.93,92.39)
UART2_TXD: length 5.1
  TOP w0.14: R1802.2 65.3,43.56 v1(64.47,43.56) 64.36,43.56 62.93,42.14 62.16,42.14 61.8,42.5 DB3.2
USB1_USB20_N: length 90.9
  L4 w0.114: v2(133.82,93.13) 133.68,93.27 133.68,93.4 133.77,93.56 133.82,93.66 133.91,93.68 133.91,93.68 134.04,93.73 134.56,93.89 134.72,93.94 135.09,94.06 135.24,94.06 135.33,94.03 135.43,93.97 135.68,93.72 136.15,92.94 136.78,92.45 136.85,92.39 137.16,91.92 137.33,91.65 138.1,90.88 139.22,89.87 139.26,89.85 141.41,88.57 142.3,88.06 144.62,85.74 144.62,78.8 144.31,78.49 143.46,77.64 143.46,69.8 146.71,66.55 146.71,63.32 146.13,62.74 146.13,50.14 147.18,49.09 147.18,41.96 149.12,40.03 152.19,40.03 153.6,38.61 153.6,37.98 v2(153.4,37.77)
  BOTTOM w0.127: 153.6,38.36 153.6,38.44 154.1,38.94 155.91,38.94 156.67,38.19 156.67,32.98 157.03,32.62 160.61,32.62 160.84,32.84 160.84,33.63 161.73,34.52 165.12,34.52 165.18,34.59 165.18,34.86 165.29,34.96 EL6601.2 ; 153.6,38.36 v1(153.45,38.36) ; 153.6,38.36 153.6,37.98 v2(153.4,37.77) ; CPU1.V10 v2(133.82,93.13)
USB1_USB20_P: length 91
  L4 w0.114: v2(133.15,92.89) 133.66,93.84 133.98,93.95 134.5,94.11 134.64,94.16 135.05,94.29 135.28,94.29 135.43,94.24 135.57,94.15 135.86,93.86 136.33,93.1 136.92,92.64 136.93,92.63 136.96,92.6 136.99,92.59 137.03,92.54 137.03,92.54 137.35,92.04 137.51,91.8 138.26,91.05 139.36,90.06 139.38,90.05 141.52,88.77 142.44,88.25 142.49,88.2 144.85,85.83 144.85,78.71 144.4,78.26 143.69,77.55 143.69,69.9 146.94,66.65 146.94,63.22 146.36,62.65 146.36,50.23 147.41,49.18 147.41,42.06 149.21,40.25 152.28,40.25 153.83,38.7 153.83,38.05 v2(154.03,37.85)
  BOTTOM w0.127: 155,38.7 154.2,38.7 153.84,38.34 153.84,38.04 v2(154.03,37.85) ; 155,38.7 155.81,38.7 156.43,38.09 156.43,32.88 156.93,32.37 160.71,32.37 161.08,32.74 161.08,33.53 161.83,34.28 EL6601.3 ; 155,38.7 v1(155,38.56) ; 132.67,93.14 v2(133.15,92.89)
USB1_USB30_RX_CON_N: length 20.7
  BOTTOM w0.127: R3502.2 25.2,32.84 24.53,32.84 23.68,32 EU3501.10 EU3501.1 21.79,32 21.66,32.12 21.46,32.12 21.29,31.96 21.29,31.29 21.5,31.09 22.26,31.09 23.07,30.28 23.07,30 FC3506.1 23.12,29.5 23.12,29.11 22.79,28.78 ; USB1.5 12.78,28.2 13.19,28.6 13.46,28.6 13.84,28.99 15.6,28.99 16.11,28.48 22.49,28.48 22.79,28.78 ; 22.79,28.78 v1(22.89,28.68)
USB1_USB30_RX_CON_P: length 20.7
  BOTTOM w0.127: v1(21.75,30.71) 21.75,30.85 ; 21.75,30.85 22.16,30.85 22.83,30.18 22.83,30 FC3505.1 22.88,29.39 22.88,29.21 22.39,28.72 16.21,28.72 15.7,29.23 13.74,29.23 13.36,28.84 12.84,28.84 12.78,28.9 USB1.6 ; 21.75,30.85 21.4,30.85 21.05,31.19 21.05,32.06 21.36,32.37 21.58,32.37 21.71,32.5 EU3501.2 EU3501.9 23.84,32.5 24.87,33.52 25.34,33.52 R3503.2
USB1_USB30_RX_N: length 182.7
  TOP w0.127: v2(132.3,97.54) 132.34,97.5 132.34,97.49 132.82,97.01 133.42,97.01 134.33,97.31 134.38,97.34 135.53,98.12 135.7,98.43 135.76,98.53 135.85,98.7 136.01,99.36 136.01,99.37 136.12,100.13 136.39,100.43 136.66,100.52 136.78,100.52 136.88,100.52 137.08,100.41 v2(137.14,100.15)
  BOTTOM w0.127: v1(139.94,101.58) 139.99,101.43 ; 139.99,101.43 141.75,101.94 142.17,102.07 142.68,102.21 142.81,102.22 143.29,102.26 143.57,102.26 143.75,102.26 144.35,101.96 144.49,101.85 144.48,101.86 144.72,101.67 145.36,100.95 145.59,99.42 145.6,99.38 145.64,99.09 146.34,91.38 147.97,85.34 147.77,80.65 146.39,76.98 146.36,76.94 143.92,74.51 143.92,72.65 126.96,55.68 88.55,55.68 88.15,56.08 77.03,56.08 71.06,50.1 70.35,50.1 67.74,47.49 67.74,46.66 63.41,42.34 60.92,42.34 58.91,40.33 58.42,40.33 50.98,32.88 31.01,32.88 30.83,33.06 27.17,33.06 26.95,32.84 26.38,32.84 R3502.1 ; 139.99,101.43 139.65,101.34 138.37,101.37 138.36,101.37 138.19,101.36 138.16,101.36 137.85,101.27 137.46,101.05 137.41,101.02 137.21,100.74 137.15,100.27 v2(137.14,100.15) ; CPU1.K10 v2(132.3,97.54)
USB1_USB30_RX_P: length 182.8
  TOP w0.127: v2(137.73,100.39) 137.34,100.55 136.94,100.76 136.88,100.76 136.78,100.76 136.62,100.76 136.26,100.63 136.22,100.59 135.89,100.24 135.88,100.16 135.77,99.42 135.62,98.78 135.35,98.29 134.22,97.53 133.38,97.25 132.92,97.25 132.83,97.34 132.83,97.64 v2(132.92,97.73)
  BOTTOM w0.127: 138.82,101.12 138.37,101.13 138.2,101.12 137.95,101.05 137.58,100.84 137.47,100.69 137.5,100.54 v2(137.73,100.39) ; 138.82,101.12 v1(138.82,100.99) ; 138.82,101.12 139.68,101.09 141.82,101.71 142.23,101.83 142.72,101.97 142.83,101.98 143.3,102.02 143.57,102.02 143.69,102.02 144.22,101.75 144.55,101.49 145.13,100.84 145.4,99.06 146.1,91.34 147.73,85.31 147.53,80.7 146.19,77.12 143.68,74.61 143.68,72.75 126.86,55.92 106.92,55.92 106.81,56.03 106.43,56.03 106.32,55.92 105.93,55.92 105.82,56.03 105.44,56.03 105.33,55.92 104.95,55.92 104.84,56.03 104.46,56.03 104.34,55.92 99.26,55.92 99.15,56.03 98.77,56.03 98.66,55.92 98.28,55.92 98.17,56.03 97.79,56.03 97.67,55.92 97.29,55.92 97.18,56.03 96.8,56.03 96.69,55.92 91.61,55.92 91.5,56.03 91.12,56.03 91,55.92 90.62,55.92 90.51,56.03 90.13,56.03 90.02,55.92 89.64,55.92 89.53,56.03 89.14,56.03 89.03,55.92 88.65,55.92 88.25,56.32 76.93,56.32 70.96,50.34 70.25,50.34 67.5,47.59 67.5,46.76 63.31,42.58 60.82,42.58 58.81,40.57 58.32,40.57 50.88,33.12 31.11,33.12 30.93,33.3 30.13,33.3 30.01,33.41 29.63,33.41 29.52,33.3 29.14,33.3 29.03,33.41 28.65,33.41 28.54,33.3 28.16,33.3 28.04,33.41 27.66,33.41 27.55,33.3 27.17,33.3 26.95,33.52 26.24,33.52 R3503.1 ; CPU1.K9 132.89,97.22 133.05,97.38 133.05,97.6 v2(132.92,97.73)
USB1_USB30_TX_CON_N: length 24
  BOTTOM w0.127: v1(25.25,34.75) 25.16,34.85 ; 25.16,34.85 25.53,35.22 25.92,35.22 26.27,34.88 ER3505.2 ; 25.16,34.85 23.93,33.62 23.71,33.62 23.58,33.5 EU3501.7 EU3501.4 21.72,33.5 21.6,33.63 21.25,33.63 20.92,33.96 20.92,34.75 21.3,35.14 22.53,35.14 22.91,35.51 22.91,35.82 FC3504.1 22.93,36.46 22.93,36.66 22.76,36.83 17.84,36.83 14.92,33.9 13.8,33.9 13.27,34.43 12.91,34.43 12.78,34.3 USB1.8
USB1_USB30_TX_CON_P: length 24
  BOTTOM w0.127: ER3506.2 26.28,35.71 26.04,35.47 25.43,35.47 23.83,33.87 23.67,33.87 23.54,34 EU3501.6 EU3501.5 21.72,34 21.6,33.87 21.35,33.87 21.16,34.06 21.16,34.65 21.4,34.9 22.63,34.9 23.15,35.41 23.15,35.84 FC3503.1 23.17,36.42 23.17,36.76 22.86,37.07 22.36,37.07 ; 22.36,37.07 17.74,37.07 14.82,34.15 13.9,34.15 13.37,34.67 12.91,34.67 12.78,34.8 USB1.9 ; 22.36,37.07 v1(22.36,37.21)
USB1_USB30_TX_N: length 169.9
  BOTTOM w0.089: CPU1.J2 135.95,99.23 136.07,99.33 136.28,99.38 136.61,99.36
  BOTTOM w0.127: 136.61,99.36 137.03,99.38 139.36,100.42 139.44,100.44 140.53,100.78 141.96,101.23 142.38,101.35 142.81,101.46 142.9,101.48 142.92,101.48 143.32,101.51 143.56,101.51 144.2,101.12 144.31,101 144.4,100.9 144.55,100.57 ; v1(144.69,100.61) 144.55,100.57 ; 144.55,100.57 144.72,100.18 144.72,100.15 144.87,99.16 144.89,99.02 145.61,91.13 147.22,85.27 147.19,84.95 147.01,80.96 145.77,77.46 143.06,74.75 143.06,72.9 126.7,56.54 92.04,56.54 91.75,56.83 76.72,56.83 70.75,50.85 70.04,50.85 66.99,47.8 66.99,46.97 63.1,43.09 60.61,43.09 58.6,41.08 58.11,41.08 50.67,33.63 33.89,33.63 32.57,34.95 C3502.1
USB1_USB30_TX_N_R: length 2
  BOTTOM w0.127: C3502.2 29.07,35.27 28.43,35.27 28.05,34.88 ER3505.1
USB1_USB30_TX_P: length 170
  BOTTOM w0.127: 140.05,100.38 139.45,100.19 137.09,99.15 137.04,99.14 136.59,99.12 CPU1.J1 ; 140.05,100.38 v1(140.09,100.26) ; 140.05,100.38 142.03,101 142.44,101.11 142.87,101.22 142.94,101.24 143.33,101.27 143.49,101.27 144.05,100.93 144.13,100.84 144.2,100.76 144.48,100.11 144.65,98.99 145.37,91.09 146.97,85.24 146.95,84.97 146.77,81 145.56,77.59 142.82,74.85 142.82,73 126.6,56.78 124.73,56.78 124.62,56.89 124.24,56.89 124.13,56.78 123.75,56.78 123.64,56.89 123.26,56.89 123.14,56.78 118.06,56.78 117.95,56.89 117.57,56.89 117.46,56.78 117.08,56.78 116.97,56.89 116.59,56.89 116.47,56.78 116.09,56.78 115.98,56.89 115.6,56.89 115.49,56.78 110.41,56.78 110.3,56.89 109.92,56.89 109.8,56.78 109.42,56.78 109.31,56.89 108.93,56.89 108.82,56.78 108.44,56.78 108.33,56.89 107.94,56.89 107.83,56.78 102.75,56.78 102.64,56.89 102.26,56.89 102.15,56.78 101.77,56.78 101.66,56.89 101.27,56.89 101.16,56.78 100.78,56.78 100.67,56.89 100.29,56.89 100.18,56.78 95.1,56.78 94.99,56.89 94.6,56.89 94.49,56.78 94.11,56.78 94,56.89 93.62,56.89 93.51,56.78 93.13,56.78 93.01,56.89 92.63,56.89 92.52,56.78 92.14,56.78 91.85,57.07 76.62,57.07 70.65,51.09 69.94,51.09 66.75,47.9 66.75,47.07 63,43.33 60.51,43.33 58.5,41.32 58.01,41.32 50.57,33.87 34.98,33.87 34.86,33.98 34.48,33.98 34.37,33.87 33.99,33.87 32.67,35.19 30.86,35.19 30.74,35.31 30.74,35.74 30.65,35.83 C3501.1
USB1_USB30_TX_P_R: length 1.9
  BOTTOM w0.127: ER3506.1 28.18,35.71 28.38,35.51 29.05,35.51 C3501.2
USB2_CON_USB20_N: length 30
  TOP w0.127: USB1.2 14.28,31.64 14.46,31.46 15.37,31.46 15.9,30.93 15.9,24.75 16.63,24.02 16.63,19.73 17.01,19.35 18.22,19.35 18.44,19.57 18.44,19.89 EU3502.1 18.44,20.35 18.44,21.07 17.65,21.86 17.65,26.67 ; AFTP3503.1 17.65,26.67 ; 17.65,26.67 17.65,29.31 18.53,30.19 19.65,30.19 19.96,30.49 EL3503.3
USB2_CON_USB20_P: length 29.6
  TOP w0.127: EL3503.2 19.88,29.81 19.74,29.95 18.63,29.95 17.89,29.21 17.89,24.77 ; 17.89,24.77 17.89,23.13 EU3502.6 17.89,22.49 17.89,21.96 18.68,21.17 18.68,19.47 18.32,19.11 16.91,19.11 16.39,19.63 16.39,23.92 15.66,24.65 15.66,30.83 15.27,31.22 14.54,31.22 14.28,30.96 USB1.3 ; 17.89,24.77 AFTP3502.1
USB2_OTG_ID: length 7.9
  TOP w0.14: v2(132.45,90.7) 132.74,90.89 133.28,91.43 134.34,91.84 135.34,92.21 135.47,92.3 136.81,92.71 137.23,92.87 137.55,93.09 v1(137.95,93.32) R1703.1
  BOTTOM w0.14: CPU1.AC15 v2(132.45,90.7)
USB2_USB20_N: length 175.1
  TOP w0.127: 33.53,26.89 34.17,26.25 34.49,26.25 v2(34.58,26.34) ; 33.53,26.89 30.15,30.27 22.24,30.27 22.02,30.49 EL3503.4 ; 33.53,26.89 v1(33.64,27)
  L4 w0.114: v2(141.77,67.74) 141.54,67.52 141.38,67.52 141.3,67.59 141.3,78.63 142.25,79.59 142.25,80.85 141.82,82.79 139.48,85.12 138.03,85.27 137.88,85.28 136.34,85.61 136.33,85.62 134.71,85.74 134.51,85.77 134.5,85.78 132.85,86.05 132.15,86.29 131.93,86.47 131.6,87.06 131.38,87.55 131.24,87.98 131.24,88.91 131.23,88.92 131.09,90.14 131.09,91.6 131.02,91.82 131.06,91.92 v2(131.15,92.16)
  BOTTOM w0.127: v2(141.77,67.74) 141.54,67.52 140.58,67.52 126.93,53.86 88.82,53.86 88.27,54.41 86.06,54.41 85.7,54.77 77.51,54.77 71.58,48.85 70.87,48.85 68.99,46.97 68.99,46.13 63.38,40.52 60.88,40.52 59.43,39.07 58.94,39.07 51.37,31.5 39.65,31.5 35.61,27.45 35.61,26.54 35.12,26.05 34.64,26.05 34.58,26.11 v2(34.58,26.34) ; CPU1.V15 v2(131.15,92.16)
USB2_USB20_P: length 175.7
  TOP w0.127: v1(23.96,29.9) 23.96,30.03 ; 23.96,30.03 22.24,30.03 22.02,29.81 EL3503.1 ; 23.96,30.03 30.05,30.03 34.14,25.94 v2(34.14,25.81)
  L4 w0.114: v2(141.74,67.11) 141.56,67.29 141.28,67.29 141.07,67.5 141.07,78.73 142.02,79.68 142.02,80.83 141.61,82.67 139.38,84.9 138.01,85.04 137.93,85.05 137.84,85.06 137.77,85.07 137.76,85.07 136.29,85.39 136.29,85.39 134.68,85.51 134.47,85.55 134.46,85.55 134.28,85.58 132.82,85.82 132.8,85.83 132.04,86.09 131.93,86.17 131.84,86.25 131.76,86.32 131.74,86.35 131.4,86.95 131.33,87.11 131.26,87.27 131.17,87.46 131.11,87.64 131.11,87.66 131.01,87.95 131.01,88.82 130.86,90.12 130.86,90.13 130.86,91.57 130.8,91.76 130.78,91.86 130.51,92.12 v2(130.13,92.27)
  BOTTOM w0.127: v2(141.74,67.11) 141.58,67.27 140.68,67.27 127.03,53.62 88.72,53.62 88.17,54.17 85.96,54.17 85.6,54.53 77.61,54.53 71.68,48.6 70.97,48.6 69.24,46.87 69.24,46.03 63.48,40.27 60.98,40.27 59.53,38.83 59.04,38.83 51.47,31.26 39.75,31.26 35.85,27.35 35.85,26.44 35.22,25.81 v2(34.14,25.81) ; CPU1.V16 v2(130.13,92.27)
USB2_USB30_RX_CON_N: length 10.4
  TOP w0.127: USB2.5 13.43,9.89 14.15,10.51 14.42,10.74 14.83,11.09 14.85,11.11 14.92,11.18 15.22,11.48 15.35,11.7 15.36,11.71 16.57,13.86 16.66,13.95 17,14.12 EU3504.10 EU3504.1 19.08,14.17 19.29,13.96 19.76,13.96 ER3511.2
USB2_USB30_RX_CON_P: length 10.4
  TOP w0.127: ER3512.2 20.43,14.96 19.66,14.2 19.39,14.2 19.26,14.33 19.26,14.56 19.15,14.67 EU3504.2 EU3504.9 17.19,14.67 16.83,14.31 16.51,14.15 16.4,14.03 16.37,14.01 15.15,11.83 15.14,11.82 15.03,11.63 14.91,11.51 14.67,11.27 14.26,10.92 12.91,10.92 USB2.6
USB2_USB30_RX_N: length 192.9
  TOP w0.127: v2(23.4,13.77) 23.56,13.93 23.56,14.08 23.46,14.24 23.02,14.47 23,14.47 22.61,14.58 22.46,14.58 22.33,14.45 22.33,14.27 22.19,14.12 ER3511.1
  BOTTOM w0.089: CPU1.G2 135.56,99.88 135.69,99.94 135.85,99.94 135.98,100 136.01,100.01 136.1,100.1 136.18,100.18 136.26,100.24
  BOTTOM w0.127: 136.26,100.24 137.14,101.36 137.62,101.58 138.44,101.73 138.76,101.82 141.53,102.46 ; 141.53,102.46 142.46,102.68 142.83,102.79 143.69,102.79 144.27,102.68 144.51,102.49 145.07,102.04 145.84,101.17 146.14,99.2 146.15,99.15 146.84,91.47 148.48,85.4 148.27,80.42 146.88,76.75 144.95,74.82 144.83,74.69 144.72,74.58 144.5,73.77 144.5,72.49 127.17,55.17 86.52,55.17 85.96,55.57 77.25,55.57 71.27,49.6 70.56,49.6 68.24,47.28 68.24,46.45 63.67,41.88 61.93,41.29 60.59,41.29 59.12,39.82 58.63,39.82 51.12,32.31 39.37,32.31 38.41,31.36 38.25,31.36 37.99,31.09 37.99,30.93 37.72,30.66 37.56,30.66 37.29,30.39 37.29,30.23 33.7,26.64 33.54,26.64 33.27,26.37 33.27,26.21 33,25.94 32.84,25.94 32.57,25.67 32.57,25.52 32.3,25.25 32.14,25.25 31.88,24.98 31.88,24.82 31.69,24.63 31.64,24.59 31.3,23.22 31.19,22.93 27.46,17.84 27.27,17.66 27.11,17.66 26.84,17.39 26.84,17.23 26.58,16.96 26.42,16.96 26.15,16.69 26.15,16.53 23.72,14.1 23.72,14.09 v2(23.4,13.77) ; 141.53,102.46 v1(141.56,102.34)
USB2_USB30_RX_P: length 193
  TOP w0.127: ER3512.1 21.94,14.96 22.08,14.82 22.65,14.82 23.06,14.7 23.11,14.69 23.44,14.52 23.48,14.5 23.63,14.43 23.71,14.3 ; 23.71,14.3 v1(23.86,14.4) ; 23.71,14.3 23.8,14.15 23.8,14 v2(24.04,13.77)
  BOTTOM w0.089: CPU1.F2 135.59,100.13 135.81,100.13 135.9,100.17 136.05,100.32 136.07,100.4
  BOTTOM w0.127: v2(24.04,13.77) 24.04,14.08 27.64,17.68 31.41,22.81 31.47,22.98 31.53,23.15 31.86,24.46 39.47,32.07 51.22,32.07 58.73,39.58 59.22,39.58 60.69,41.05 61.97,41.05 63.77,41.66 63.77,41.66 63.81,41.68 63.93,41.8 64.08,41.95 68.49,46.35 68.49,47.18 70.66,49.35 71.37,49.35 77.35,55.33 85.88,55.33 86.44,54.93 127.27,54.93 144.74,72.39 144.74,73.74 144.93,74.46 147.09,76.61 148.51,80.37 148.73,85.42 147.08,91.51 146.39,99.18 146.38,99.23 146.36,99.33 146.07,101.28 145.24,102.22 144.66,102.68 144.43,102.87 144.38,102.91 143.98,102.98 143.71,103.03 142.83,103.03 142.79,103.03 142.67,103 142.39,102.91 139.79,102.31 138.69,102.05 138.38,101.96 137.57,101.82 137.54,101.81 136.99,101.56 136.96,101.52 136.07,100.4
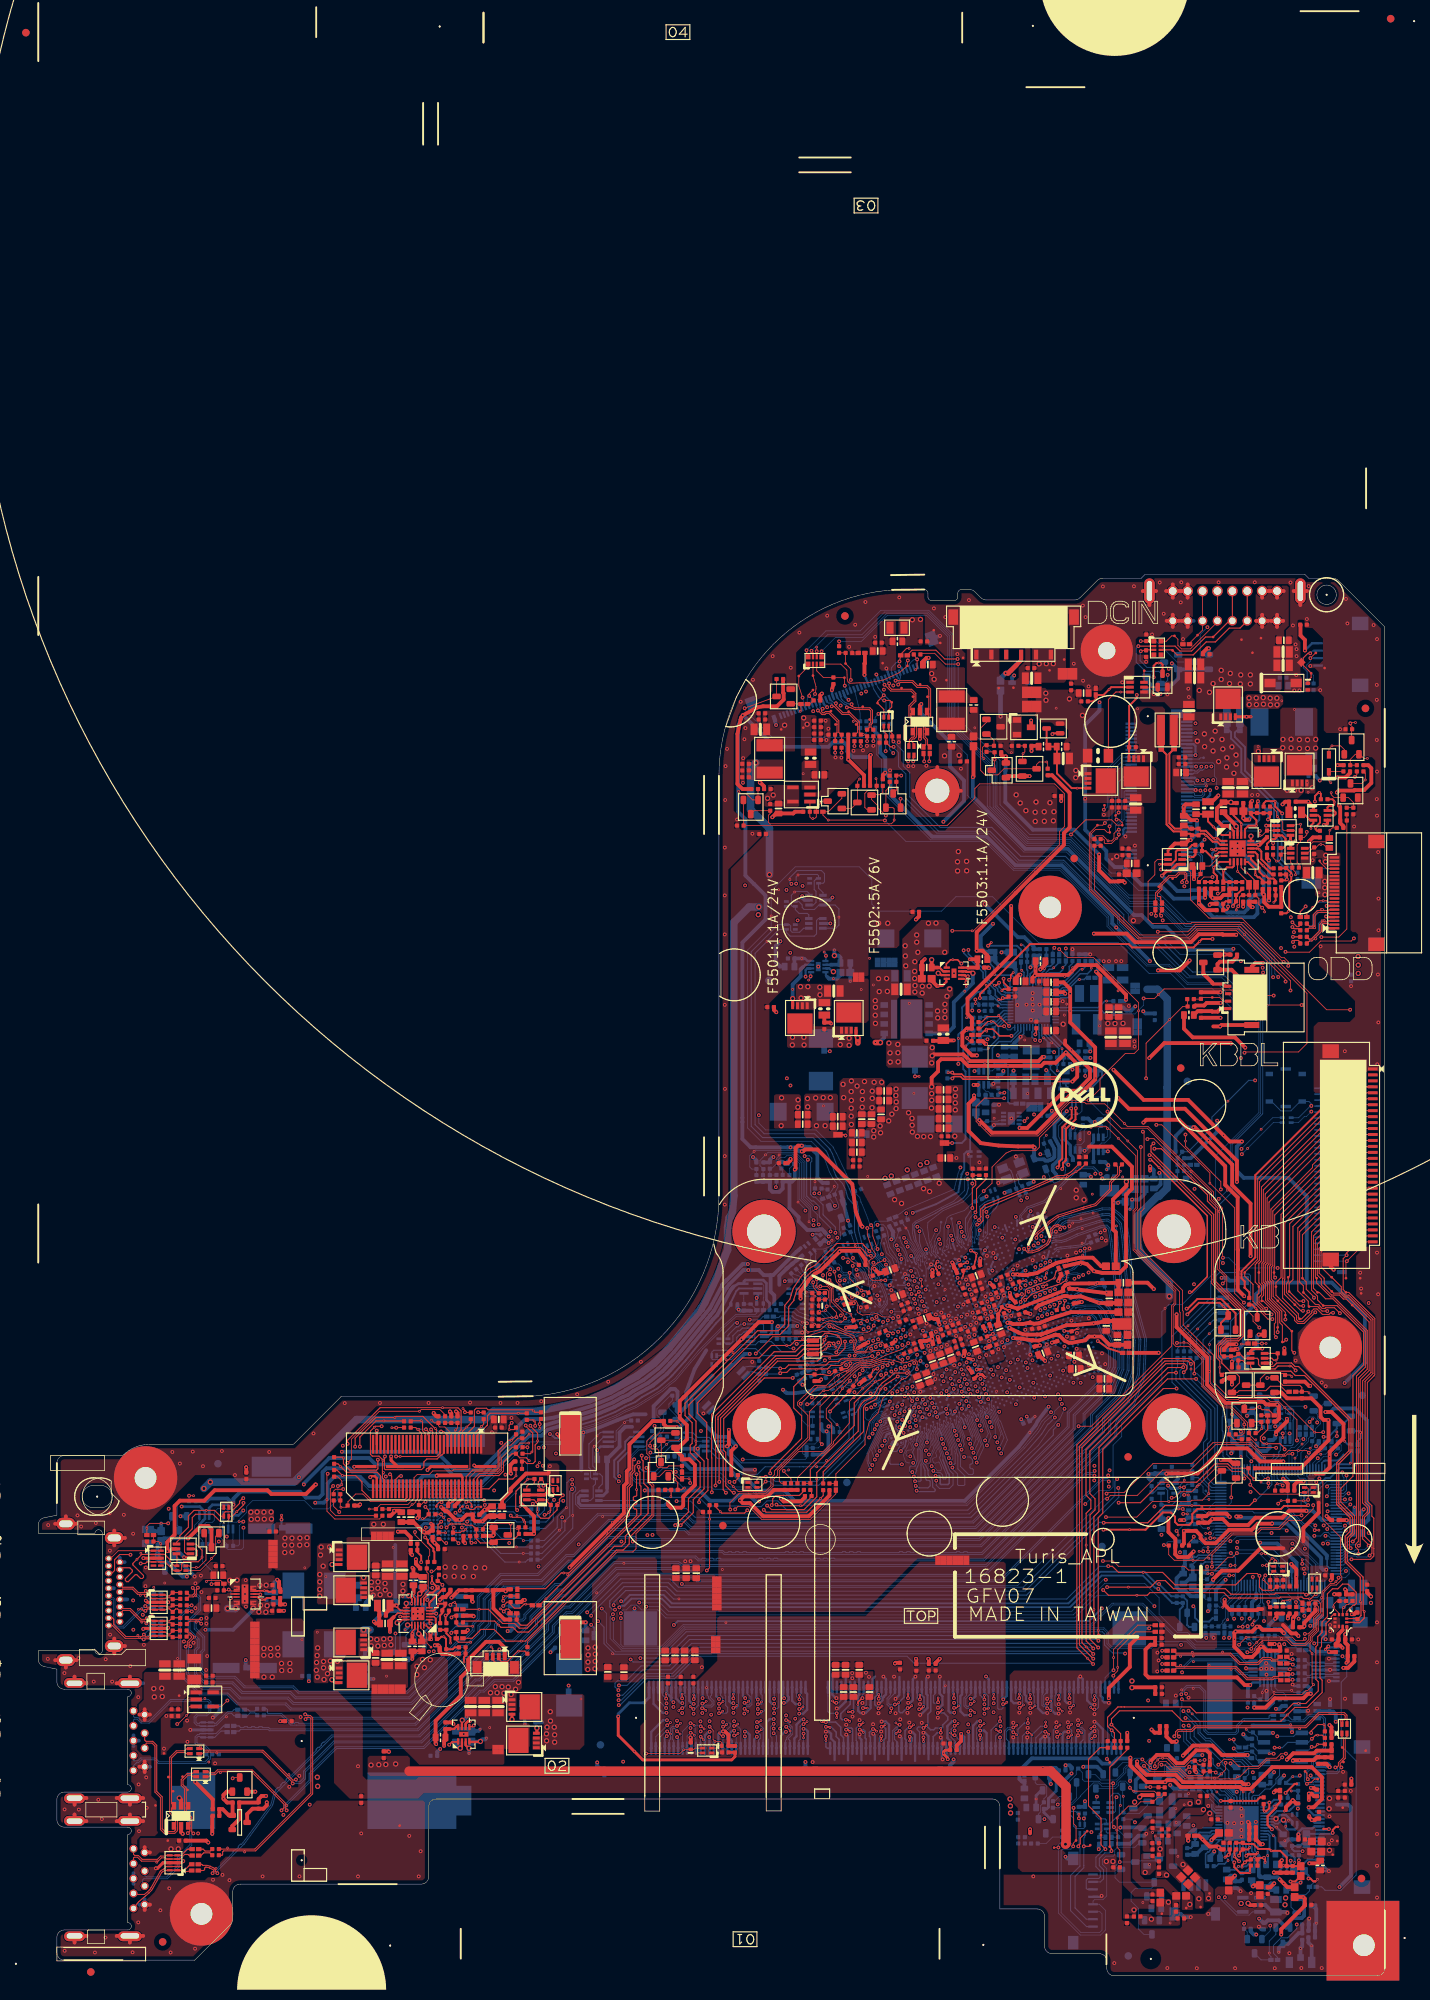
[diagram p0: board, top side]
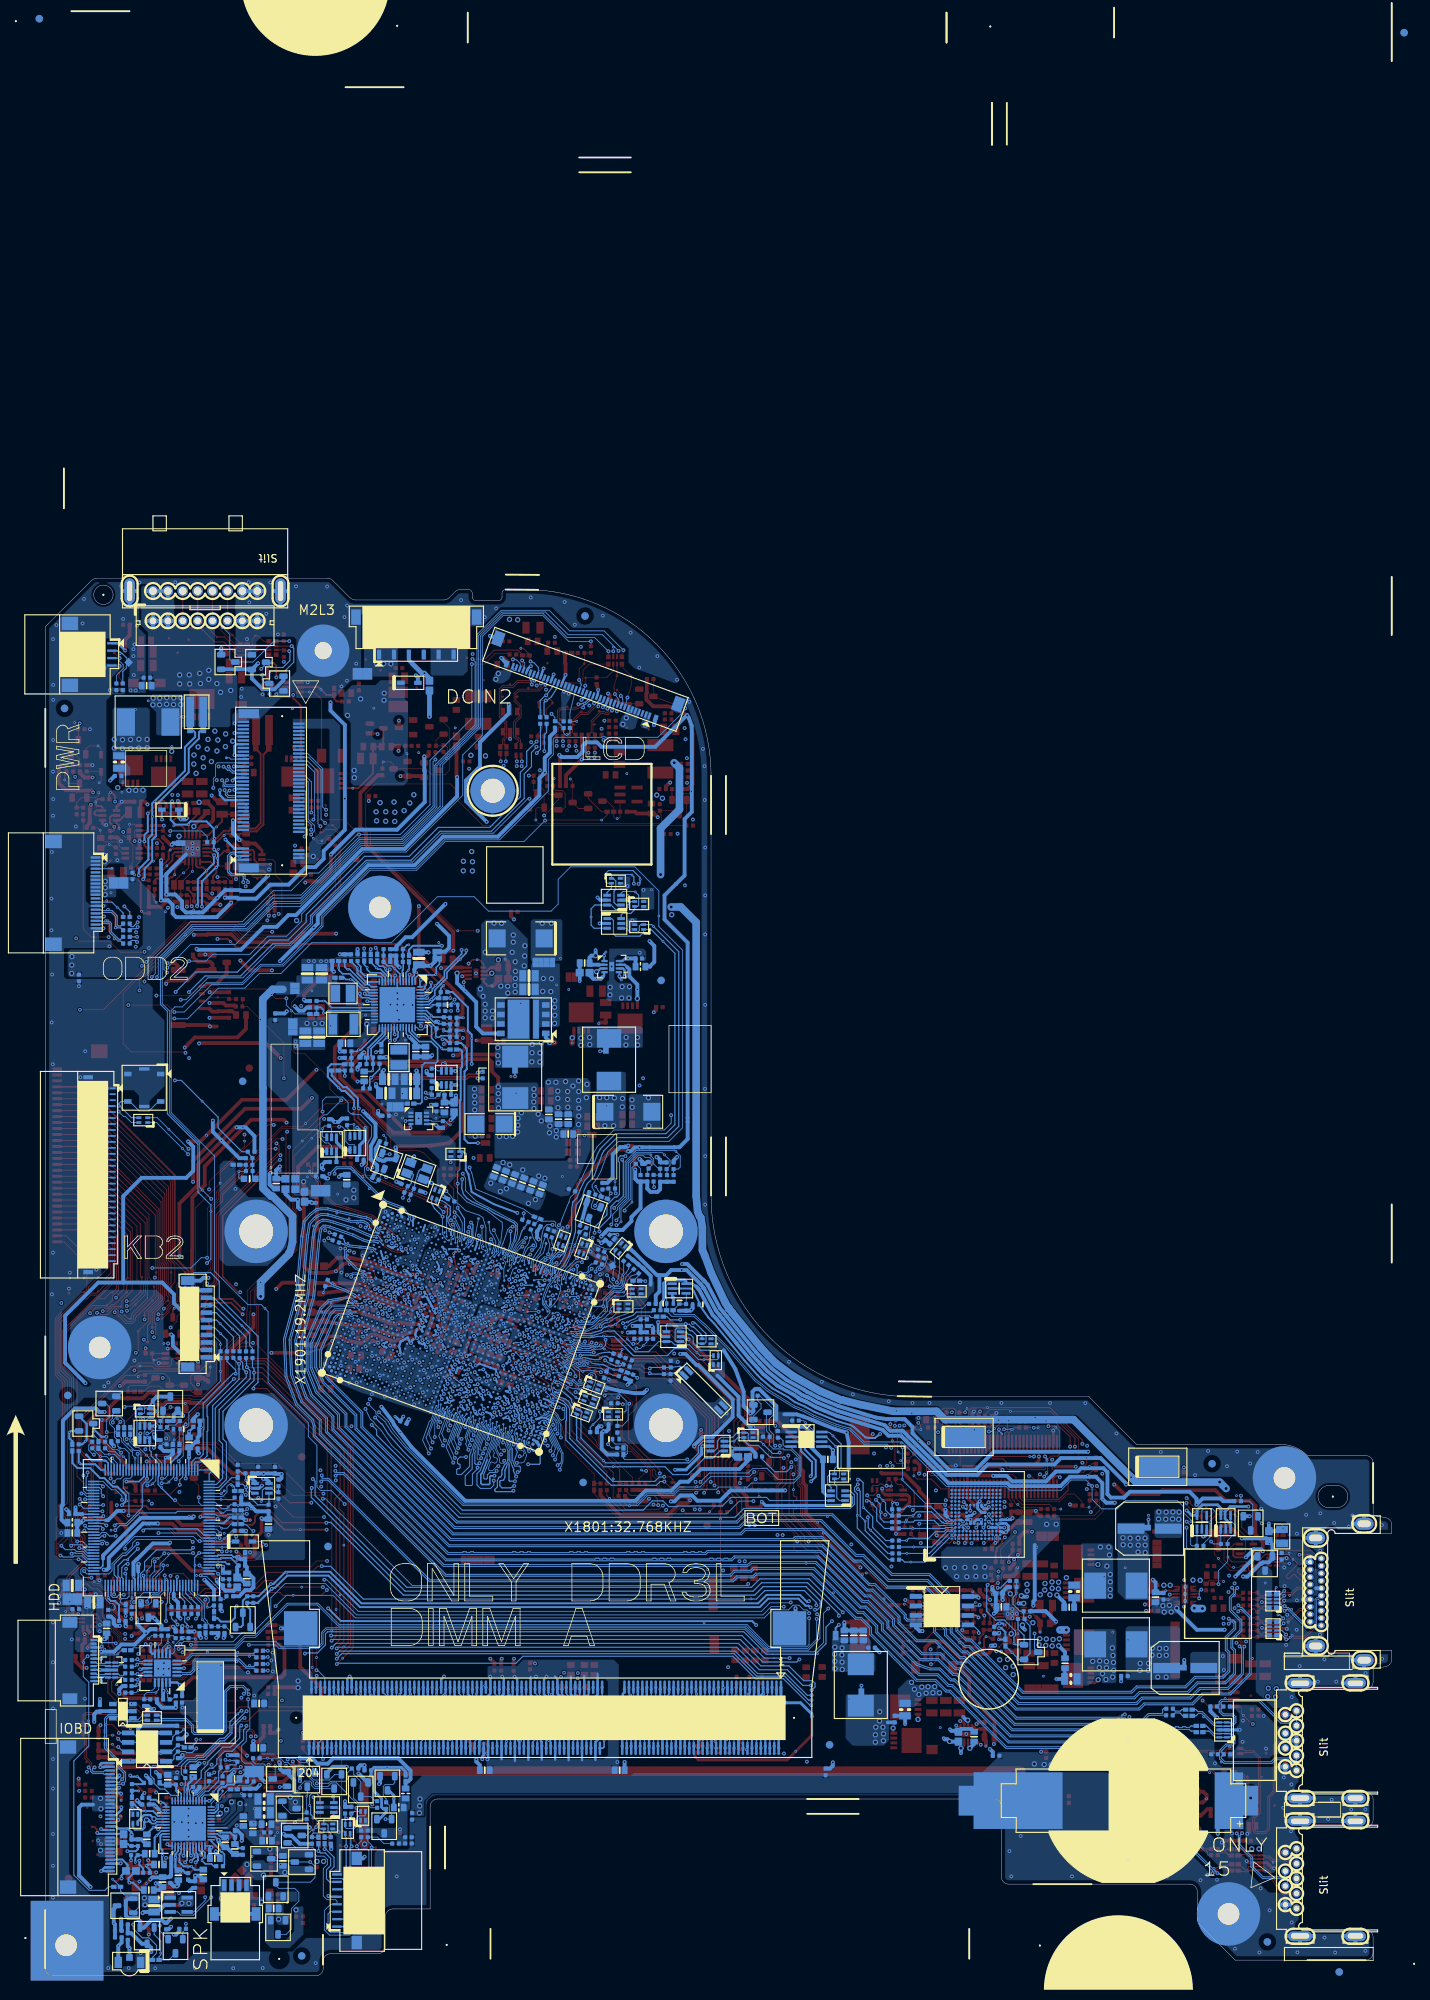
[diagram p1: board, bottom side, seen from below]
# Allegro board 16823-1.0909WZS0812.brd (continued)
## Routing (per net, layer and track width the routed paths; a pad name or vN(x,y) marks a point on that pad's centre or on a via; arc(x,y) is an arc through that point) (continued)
USB2_USB30_TX_CON_N: length 9.6
  TOP w0.127: 15.91,15.38 16.09,15.38 16.53,15.83 17.07,15.83 17.23,15.67 EU3504.7 EU3504.4 19.02,15.67 19.66,16.3 20.1,16.3 20.27,16.13 ER3509.2 ; 15.91,15.38 v1(15.91,15.24) ; 15.91,15.38 13.85,15.38 13.32,15.91 12.89,15.91 12.78,15.8 USB2.8
USB2_USB30_TX_CON_P: length 9.5
  TOP w0.127: ER3510.2 20.01,16.99 19.18,16.17 EU3504.5 EU3504.6 17.18,16.17 17.08,16.07 16.43,16.07 15.99,15.62 13.95,15.62 13.42,16.15 12.94,16.15 12.78,16.31 USB2.9
USB2_USB30_TX_N: length 187.3
  TOP w0.127: 27.69,16.76 24.87,16.76 24.75,16.64 24.75,16.26 24.67,16.18 C3508.1 ; 27.69,16.76 v1(27.69,16.61) ; 27.69,16.76 29.18,16.76 36.82,24.41 36.82,34.62 36.53,34.91 35.98,34.91 v2(35.82,35.08)
  BOTTOM w0.127: CPU1.K2 136.6,98.48 137.32,98.4 138.05,98.61 139.5,99.29 142.55,100.36 143.06,100.47 143.32,100.47 143.58,100.21 143.67,99.87 143.86,98.48 144.56,91.14 146.19,85.01 146.13,81.25 144.87,77.95 141.98,75.06 141.98,73.33 126.47,57.82 76.31,57.82 70.37,51.88 69.66,51.88 66,48.21 66,47.38 63.68,45.07 61.19,45.07 58.2,42.08 57.71,42.08 50.32,34.69 36.27,34.69 36.2,34.75 36.2,35 36.13,35.08 v2(35.82,35.08)
USB2_USB30_TX_N_R: length 2.1
  TOP w0.127: ER3509.1 21.84,16.13 22.21,16.5 23.03,16.5 C3508.2
USB2_USB30_TX_P: length 187.4
  TOP w0.127: 25.41,17.01 C3507.1 ; 25.41,17.01 29.08,17.01 36.58,24.51 36.58,34.52 36.43,34.67 36.1,34.67 v2(35.87,34.44) ; 25.41,17.01 v1(25.41,17.15)
  BOTTOM w0.089: CPU1.K3 135.87,98.55 135.93,98.6 136.15,98.68 136.25,98.68 136.56,98.73
  BOTTOM w0.127: v2(35.87,34.44) 50.42,34.44 57.81,41.84 58.3,41.84 61.29,44.83 63.78,44.83 66.24,47.28 66.24,48.11 69.76,51.64 70.47,51.64 76.41,57.58 126.57,57.58 142.22,73.23 142.22,74.96 145.07,77.82 146.37,81.2 146.37,81.24 146.44,85.01 146.44,85.04 144.8,91.18 144.1,98.51 144.08,98.7 144.07,98.76 143.91,99.91 143.91,99.92 143.8,100.34 143.63,100.5 143.61,100.52 143.42,100.71 143.03,100.71 142.48,100.59 142.47,100.58 139.41,99.52 139.4,99.51 137.96,98.84 137.3,98.65 136.58,98.72 136.56,98.73
USB2_USB30_TX_P_R: length 2
  TOP w0.127: ER3510.1 22.13,16.99 22.38,16.74 23.09,16.74 C3507.2
USB2_VBUS_SNS: length 8.1
  TOP w0.14: v2(131.84,90.41) 132.03,90.89 132.43,91.29 132.49,91.99 132.72,92.22 133.48,92.45 133.98,92.7 134.13,92.74 134.67,92.91 135.03,92.99 v1(136.35,93.63) 136.55,94.41 R1702.2
  BOTTOM w0.14: CPU1.AC16 v2(131.84,90.41)
USB3_CON_USB20_N: length 21.5
  TOP w0.127: 19.46,26.62 19.18,26.34 19.18,25.54 19.63,25.1 19.63,21.92 20.35,21.2 20.35,20.36 EU3502.3 20.35,19.88 20.35,19.42 v2(20.07,19.14) ; 19.46,26.62 AFTP3508.1 ; 19.46,26.62 20,27.15 20.68,27.15 20.92,27.39 EL3504.3
  BOTTOM w0.127: v2(20.07,19.14) 20.35,18.86 20.35,17.59 18.66,15.9 18.66,14.71 17.23,13.27 14.52,13.27 14.28,13.52 USB2.2
USB3_CON_USB20_P: length 22
  TOP w0.127: 19.87,24.94 AFTP3506.1 ; 19.87,24.94 19.87,25.2 19.43,25.64 19.43,26.24 20.1,26.91 20.56,26.91 20.76,26.71 EL3504.2 ; 19.87,24.94 19.87,23.05 EU3502.4 19.87,22.57 19.87,22.02 20.59,21.3 20.59,19.32 v2(20.81,19.1)
  BOTTOM w0.127: USB2.3 14,12.33 14,12.85 14.18,13.03 17.33,13.03 18.9,14.61 18.9,15.8 20.6,17.49 20.6,18.89 v2(20.81,19.1)
USB3_USB20_N: length 181.3
  TOP w0.127: v2(33.33,22.2) 33.21,22.32 33.21,22.84 ; 33.21,22.84 33.21,23.13 29.55,26.79 29.55,26.79 28.71,27.63 24.05,27.63 23.64,27.23 23.02,27.23 22.86,27.39 EL3504.4 ; 33.21,22.84 v1(33.36,22.84)
  L4 w0.114: v2(132.49,92.65) 132.46,91.81 132.46,91.61 132.58,91.4 132.61,91.26 132.81,90.99 132.9,90.75 132.88,90.4 132.39,89.36 132.37,89.31 132.4,88.67 132.46,88.5 132.86,87.4 132.88,87.35 133.19,87.04 133.33,86.97 133.37,86.95 134.57,86.39 134.62,86.37 135.66,86.36 135.78,86.4 135.84,86.42 137.86,87.16 138.86,87.01 138.87,87 140.34,86.51 142.28,82.97 142.77,80.82 142.77,79.38 142.01,78.62 142.01,69.17 142.52,68.66 142.52,66.83 142.88,66.47 143.52,66.47 v2(143.67,66.32)
  BOTTOM w0.127: v2(33.33,22.2) 33.22,22.32 33.22,22.75 36.6,26.13 36.6,27.04 40.05,30.49 51.77,30.49 59.35,38.08 59.84,38.08 61.29,39.52 63.8,39.52 70.06,45.79 70.06,46.64 71.28,47.86 71.99,47.86 77.92,53.78 85.29,53.78 85.66,53.41 87.84,53.41 88.38,52.87 129.14,52.87 142.77,66.5 143.49,66.5 v2(143.67,66.32) ; CPU1.V13 v2(132.49,92.65)
USB3_USB20_P: length 180.8
  TOP w0.127: EL3504.1 22.84,26.71 23.12,26.99 23.74,26.99 24.15,27.39 24.44,27.39 ; v1(24.44,27.26) 24.44,27.39 ; 24.44,27.39 28.61,27.39 29.45,26.55 29.45,26.55 32.97,23.03 32.97,22.52 v2(32.65,22.2)
  L4 w0.114: v2(132.9,91.8) 132.78,91.58 132.83,91.36 133,91.12 133.01,91.1 133.03,91.07 133.11,90.83 133.13,90.77 133.1,90.34 133.04,90.2 133.01,90.15 132.6,89.26 132.63,88.72 133.08,87.47 133.32,87.23 134.67,86.6 135.62,86.59 137.78,87.37 137.83,87.39 138.93,87.23 140.37,86.74 140.37,86.74 140.49,86.7 142.5,83.05 143,80.85 143,79.28 142.24,78.53 142.24,69.27 142.75,68.76 142.75,66.93 142.98,66.7 143.34,66.7 143.59,66.96 v2(143.59,67.13)
  BOTTOM w0.127: CPU1.Y13 132.36,92.13 132.67,92.13 132.9,91.9 v2(132.9,91.8) ; v2(32.65,22.2) 32.98,22.53 32.98,22.85 36.35,26.23 36.35,27.14 39.95,30.74 51.67,30.74 59.25,38.32 59.74,38.32 61.19,39.77 63.7,39.77 69.82,45.89 69.82,46.74 71.18,48.1 71.89,48.1 77.82,54.02 85.39,54.02 85.76,53.65 87.94,53.65 88.48,53.11 129.04,53.11 142.67,66.74 143.5,66.74 143.59,66.83 v2(143.59,67.13)
USB20_VCCA: length 28.4
  L4 w0.508: v3(173.29,23.8) 172.42,24.67 172.42,31.45 174.12,33.15 v2(174.12,34.09)
  BOTTOM w0.508: v2(174.12,34.09) 174.12,35.1 173.78,35.45 C6601.1 173.3,35.51 ED6601.5 ; 174.28,22.97 175.8,22.97 176.16,22.61 176.16,13.44 v2(174.63,11.91)
  vias: v3(167.32,9.53) v3(167.39,10.44) v3(173.24,22.4)
USB_CON_PN1: length 19
  TOP w0.127: AFTP6603.1 170.26,27.18 170.26,26.49 v2(170.37,26.38)
  BOTTOM w0.127: IOBD1.6 171.25,26.05 171.15,25.95 170.8,25.95 v2(170.37,26.38) 170.16,26.59 170.16,27.15 171.13,28.13 171.13,28.91 172.74,30.51 172.74,34.53 172.26,35.02 170.47,35.02 169.78,34.33 169.17,34.33 ED6601.1 168.71,34.33 168.27,34.33 167.64,34.96 EL6601.1
USB_CON_PN3: length 13.7
  TOP w0.127: AFTP5509.1 117.53,171.63 ; 117.53,171.63 117.53,171.12 116.85,170.43 116.85,168.89 117.61,168.12 117.61,167.17 EU5501.1 117.61,166.69 117.61,166.33 117.48,166.2 117.26,166.2 116.92,165.87 116.92,165.48 116.84,165.4 TR5501.4 ; 117.53,171.63 117.53,171.96 117.11,172.38 114.42,172.38 v2(113.57,173.23)
  BOTTOM w0.127: LCD1.30 v2(113.57,173.23)
USB_CON_PN5: length 16
  TOP w0.127: v2(154.13,146.74) 154.13,147.86 153.91,148.08 153.07,148.08 152.59,147.6 151.71,147.6 150.55,146.44 150.55,146.13 ; 150.55,146.13 150.55,145.9 149.96,145.3 149.96,143.97 ER6103.1 ; 150.55,146.13 AFTP6106.1
  BOTTOM w0.127: v2(154.13,146.74) 154.13,147.51 154.23,147.61 155.73,147.61 156.26,148.14 156.26,150.27 155.77,150.75 WLAN1.5
USB_CON_PN6: length 8.5
  TOP w0.127: 175.15,30.63 175.15,30.63 175.15,29.26 174.48,28.59 174.48,28.17 174.27,27.96 v2(174.08,27.96) ; 175.15,30.63 175.15,31.89 174.95,32.09 EL6602.1 ; 175.15,30.63 AFTP6601.1
  BOTTOM w0.127: IOBD1.3 172.71,27.55 172.89,27.37 174.21,27.37 174.36,27.51 174.36,27.76 174.16,27.96 v2(174.08,27.96)
USB_CON_PP1: length 19.6
  TOP w0.127: AFTP6604.1 171.28,26.39 170.81,25.92 170.43,25.92 v2(170.26,25.76)
  BOTTOM w0.127: EL6601.4 167.81,34.28 168,34.09 169.88,34.09 170.57,34.77 171.42,34.77 ED6601.6 171.85,34.77 172.16,34.77 172.5,34.43 172.5,30.61 170.89,29.01 170.89,28.23 169.92,27.25 169.92,26.49 169.92,26.49 169.92,26.1 v2(170.26,25.76) 170.31,25.71 171.15,25.71 171.31,25.55 IOBD1.7
USB_CON_PP3: length 13.9
  TOP w0.127: 115.86,172.62 117.21,172.62 117.77,172.06 117.77,171.02 117.09,170.33 117.09,169.9 EU5501.6 117.09,169.34 117.09,168.99 117.85,168.22 117.85,166.23 117.58,165.96 117.36,165.96 117.16,165.77 117.16,165.66 117.52,165.31 TR5501.1 ; 115.86,172.62 114.52,172.62 114.18,172.96 v2(114.18,173.41) ; 115.86,172.62 AFTP5508.1
  BOTTOM w0.127: LCD1.31 v2(114.18,173.41)
USB_CON_PP5: length 15.9
  TOP w0.127: v2(153.5,146.74) 153.5,146.99 153.6,147.09 153.75,147.09 153.89,147.23 153.89,147.76 153.81,147.84 153.17,147.84 152.69,147.36 152.23,147.36 ; 152.23,147.36 AFTP6107.1 ; 152.23,147.36 151.81,147.36 150.79,146.34 150.79,145.8 150.2,145.2 150.2,144.91 150.29,144.82 150.56,144.82 150.64,144.74 150.64,144.1 ER6102.1
  BOTTOM w0.127: v2(153.5,146.74) 153.5,146.99 153.59,147.08 153.75,147.08 153.89,147.22 153.89,147.61 154.13,147.86 155.63,147.86 156.01,148.24 156.01,150.17 155.67,150.51 155.14,150.51 155.07,150.45 155.07,150.32 155.01,150.25 WLAN1.3
USB_CON_PP6: length 8.6
  TOP w0.127: 175.04,28.81 175.39,29.16 175.39,31.85 175.63,32.09 EL6602.4 ; 175.04,28.81 AFTP6602.1 ; 175.04,28.81 174.72,28.49 174.72,28.12 v2(174.88,27.96)
  BOTTOM w0.127: IOBD1.4 172.8,27.05 172.88,27.13 174.31,27.13 174.6,27.41 174.6,27.68 v2(174.88,27.96)
USB_OC#0: length 234.6
  TOP w0.102: v2(161.15,44.42) 161.15,44.46 v1(162.08,45.39) 162.14,45.44 168.28,45.44 168.76,44.96 169.73,44.96 v2(169.98,45.21)
  L3 w0.102: v2(108.67,95.76) 108.38,94.27 108.44,94.08 108.64,93.41 108.69,92.97 108.59,92.82 108.18,92.69 107.54,92.69 106.77,92.81 106.22,92.81 106,92.92 105.75,93.17 105.75,94.12 105.67,94.41 105.6,94.47 104.07,94.47 104.05,94.46 103.86,94.44 101.73,92.31 101.7,92.31 97.45,88.06 97.45,81.8 89.91,74.26 88.35,74.26 82.84,68.74 82.84,68.74 82.71,68.61 82.71,67.8 82.66,67.75 82.66,65.78 77.07,60.19 77.07,59.78 77.07,59.78 77.07,53.88 79.05,51.89 79.05,48.64 78.39,47.98 v2(78.19,47.98) ; v2(158.43,10.54) 160.1,8.87 163.58,8.87 164.67,7.77 168.21,7.77 174.85,14.41 174.85,24.93 172.14,27.64 172.14,38.21 170.29,40.06 170.29,44.88 169.98,45.19 v2(169.98,45.21)
  BOTTOM w0.102: v2(78.19,47.98) 78.19,44.45 78.5,44.14 83.55,44.14 86.56,47.15 141.27,47.15 144.11,49.99 144.3,49.99 148.23,49.99 152.58,45.65 153.97,45.65 155.21,44.4 161.12,44.4 161.13,44.42 v2(161.15,44.42) ; 111.15,93.49 111.07,93.6 110.77,94.42 109.56,95.63 109.34,95.8 108.71,95.8 v2(108.67,95.76) 108.67,96.48 108.44,96.89 ; v2(158.43,10.54) 158.43,10.54 160.82,8.15 162.51,8.15 162.94,8.58 U3602.3
USB_OC#1: length 147.8
  TOP w0.102: v2(18.65,33.78) 18.75,33.78 v1(19.92,34.95) 20.2,35.23 20.2,36.04 20.29,36.14 U3601.3
  L4 w0.102: v2(18.65,33.78) 18.87,33.78 21.29,36.21 21.29,44.48 23.15,46.33 23.15,48.59 20.23,51.51 20.23,53.24 20.38,53.39 20.38,54.1 22.44,56.16 22.44,62.87 25.97,66.4 27.59,66.4 28.53,67.34 38.01,67.34 39.94,69.27 44.5,69.27 45.28,68.49 48.74,68.49 49.57,69.32 59.7,69.32 60.57,68.46 63.78,68.46 64.81,67.43 71.73,67.43 72.78,68.48 73.8,68.48 76.23,68.48 76.23,68.48 77.27,68.48 78.98,70.18 79.73,70.18 81.37,71.82 83.51,71.82 85,73.31 85,74.05 85.77,74.82 86.33,74.82 87.54,76.03 87.54,77.57 93.88,83.91 94.21,83.91 97.26,86.96 97.26,88.2 105.71,96.65 107.73,96.65 107.83,96.75 108.19,96.75 108.29,96.65 109,96.65 109.33,96.32 v2(109.33,96.32)
  BOTTOM w0.102: CPU1.C55 111.41,92.8 111.41,93.37 111.44,93.42 111.44,93.54 111.4,93.65 111.32,93.73 111.32,93.73 111.22,93.83 110.87,94.78 109.34,96.32 v2(109.33,96.32) RN1701.3
USB_PN4_TPNL: length 15.1
  TOP w0.127: 118.35,173.1 118.04,173.1 117.37,173.77 v2(115.05,173.77) ; 118.35,173.1 119.32,173.1 119.76,172.67 119.76,168.87 119.02,168.14 119.02,167.18 EU5501.3 119.02,166.68 119.02,166.22 119.35,165.89 119.35,165.18 R5506.1 ; 118.35,173.1 AFTP5518.1
  BOTTOM w0.127: v2(115.05,173.77) 115.32,173.92 115.41,174.09 115.39,174.2 LCD1.34
USB_PP4_TPNL: length 14.9
  TOP w0.127: 119.51,171.61 119.51,172.57 119.22,172.86 117.94,172.86 117.27,173.53 115.69,173.53 v2(115.41,173.25) ; 119.51,171.61 AFTP5519.1 ; 119.51,171.61 119.51,169.86 EU5501.4 119.51,169.38 119.51,168.97 118.78,168.24 118.78,166.12 119.11,165.79 119.11,165.19 R5516.1
  BOTTOM w0.127: v2(115.41,173.25) 115.53,173.77 115.63,173.99 115.64,174.01 115.73,174.26 LCD1.35
USB_PWR_EN#: length 277.5
  TOP w0.102: v2(150.73,28.32) 150.78,28.27 151.25,28.27 151.89,27.64 153.12,27.64 154.11,26.65 158.33,26.65 v1(158.78,27.1) 159.34,27.66 v2(159.34,28.58) ; v2(25.38,36.93) 24.58,36.14 U3601.4
  L3 w0.102: v2(159.24,10.54) 159.24,10.21 160.36,9.1 163.68,9.1 164.77,8 168.12,8 174.62,14.5 174.62,24.81 171.91,27.51 171.91,38.11 169.55,40.47 169.55,46.05 169.81,46.31 171.25,46.31 171.51,46.56 171.51,49.8 174.94,53.23 174.94,53.86 174.69,54.1 174.69,55.05 173.48,56.26 171.51,56.26 170.47,57.3 v2(169.98,57.3)
  L4 w0.102: v2(159.98,58.32) 159.52,57.86 159.52,54.74 161.28,52.98 161.28,48.3 161.09,48.11 161.09,46.74 161.58,46.26 161.58,44.24 160.97,43.62 160.97,34.47 160,33.51 160,29.75 159.34,29.09 v2(159.34,28.58) ; v2(150.73,28.32) 150.73,28.4 148.9,30.23 81.78,30.23 76.83,35.18 76.83,44.7 75.52,46 63.35,46 62.59,45.24 60.23,45.24 51.92,36.93 v2(25.38,36.93)
  BOTTOM w0.102: v2(159.24,10.54) 159.24,10.12 160.78,8.58 U3602.4 ; R2471.2 155.61,59.72 v1(156.7,58.63) 157,58.32 157.75,58.32 157.75,58.32 KBC24.108 159.97,58.32 v2(159.98,58.32) 160.21,58.32 160.81,58.93 168.72,58.93 169.98,57.67 v2(169.98,57.3)
USB_RCOMP: length 2.3
  TOP w0.203: v1(132.54,93.3) R2004.2 v2(131.84,92.3)
  BOTTOM w0.203: CPU1.Y15 131.84,92.28 v2(131.84,92.3)
USB_SSIC_RCOMP: length 1.2
  TOP w0.203: R2003.2 v2(132.01,91.47)
  BOTTOM w0.203: CPU1.AB15 v2(132.01,91.47)
VD1_EN#: length 5.7
  BOTTOM w0.203: KBC24.66 172.25,50.85
  BOTTOM w0.254: 172.25,50.85 172.25,50.77 v1(172.23,50.75) 172.23,50.64 171.89,50.29 171.36,50.29 170.81,49.75 R2468.1
VD_IN1: length 92.7
  L4 w0.127: v2(163.3,120.14) 163.3,114.55 164.84,113.01 164.84,100.28 161.54,96.97 161.54,94.48 160.8,93.74 160.8,86.84 160.8,86.14 160.8,85.72 159.75,84.67 159.75,82.23 160.71,81.26 160.71,77.2 161.18,76.73 161.18,74.94 160.92,74.68 160.92,72.2 161.16,71.96 161.16,68.54 160.68,68.05 160.68,62.72 161.47,61.93 161.47,61.32 160.47,60.32 160.47,58.08 160.05,57.66 v2(160.05,56.72)
  BOTTOM w0.14: R2610.1 152.88,107.3 C2606.1 152.9,108 C2607.1 R2608.2 152.9,109.82 153.51,110.43 R2612.2 154.31,110.57 157.51,113.76 157.51,115.21 v1(159.66,117.36) 162.44,120.14 v2(163.3,120.14) ; KBC24.95 160.65,56.12 v2(160.05,56.72) KBC24.104
VD_IN1_C: length 4.2
  BOTTOM w0.102: R2611.1 C2607.2 153.77,108.79 C2606.2 153.84,107.9 v1(154.72,107.9) 154.72,107.06 154.59,106.94 R2610.2
VD_OUT1#: length 28.8
  TOP w0.14: v2(167.27,70.64) 167.27,70.79 166.66,71.4 v1(164.86,71.4) 164.41,71.4 164.01,71.8 164.01,72.31 164.99,73.29 R2613.2 R2603.2 164.98,75.2 R2602.2
  L4 w0.127: v2(167.55,59.74) 167.55,69.41 167.27,69.68 v2(167.27,70.64)
  BOTTOM w0.14: KBC24.110 159.41,59.12 160.25,59.97 167.3,59.97 167.52,59.74 v2(167.55,59.74)
VRAM_ID1: length 14.4
  TOP w0.102: v2(102.85,87) v1(103.28,86.34) 105.01,86.72 105.33,87.01 106.01,87.55 106.35,87.55 108.38,86.53 109.43,86.35 111.26,86.35 111.56,86.44 v2(112.12,87.25)
  BOTTOM w0.102: CPU1.P57 v2(112.12,87.25) ; R2025.1 R2024.2 100.9,88.08 101.23,87.95 101.43,87.85 102.04,87.62 102.3,87.36 v2(102.85,87)
VREF_CA: length 4.6
  TOP w0.381: R1207.2 R1211.1 121.72,30.28 121.5,30.05 v1(121.5,29.87) 121.5,29.75 122.05,29.19 v2(122.05,29.06)
  BOTTOM w0.305: DM1.126 121.87,29.59 122.05,29.41 v2(122.05,29.06)
VREF_DQ: length 27.9
  TOP w0.381: v2(77.83,34.79) 77.83,32.27 v1(79.98,30.12) 81.13,28.97 93.06,28.97 93.5,29.42 R1212.1 93.49,29.97 R1208.2
  BOTTOM w0.381: DM1.1 81.97,37.34 81.26,36.63 79.33,36.63 77.83,35.13 v2(77.83,34.79)
WHITE_LED_BAT: length 5.7
  BOTTOM w0.508: EC6404.1 169.63,6.87 R6406.1 169.62,5.72 169.15,5.72 167.72,4.29 Q6404.C 166.48,3.74 v1(166.48,3.18)
WIFI_RF_EN: length 138.4
  TOP w0.102: v2(143.14,154.67) 142.86,154.38 AFTP6103.1 141.05,153.29 141.05,145.67 147.6,139.12 154.51,139.12 155.62,140.24 160.82,140.24 167.39,133.66 v2(167.39,133.4) ; v1(164.29,55.07) v2(164.85,55.07)
  L4 w0.127: v2(167.39,133.4) 167.13,133.14 167.13,97.43 165.25,95.55 165.25,89.33 164.94,89.02 164.94,83.87 164.49,83.42 164.49,81.28 164.49,80.03 165.3,79.21 165.3,73.33 165.37,73.25 165.37,68.58 165.76,68.19 165.76,65.39 165.48,65.1 165.48,61.43 166.03,60.87 166.03,56.95 164.97,55.88 164.97,55.65 164.85,55.53 v2(164.85,55.07)
  BOTTOM w0.102: KBC24.82 165.85,53.48 164.85,54.49 v2(164.85,55.07) ; v2(143.14,154.67) 143.7,155.22 143.7,161.83 145.37,163.5 WLAN1.56
WLAN_CLK_CPU: length 84.9
  L4 w0.114: v2(156.78,162.23) 156.4,162.61 156.4,162.9 156.13,163.16 154.56,163.16 151.48,160.08 151.48,160.08 151.34,159.94 151.34,139.69 151.08,139.42 151.08,109.6 149.52,108.04 143.63,108.04 143.18,108.49 142.41,108.49 142.09,108.17 142.09,107.85 v2(141.87,107.62)
  BOTTOM w0.089: CPU1.A7 131.98,101.58 131.89,101.72 131.89,101.81 131.89,101.81 131.93,101.95 131.93,101.95 132.42,102.52 132.49,102.57
  BOTTOM w0.127: v1(137.22,105.62) 137.11,105.71 ; 137.11,105.71 137.58,106.17 139.71,108.29 141.54,108.29 141.87,107.97 v2(141.87,107.62) ; 137.11,105.71 135.14,103.79 132.82,102.93 132.49,102.57 ; WLAN1.47 154.98,161.25 155.11,161.38 155.58,161.38 155.97,161.77 156.26,161.77 156.73,162.23 v2(156.78,162.23)
WLAN_CLK_CPU#: length 84.9
  L4 w0.114: v2(142.57,107.61) 142.32,107.85 142.32,108.08 142.5,108.26 143.09,108.26 143.53,107.82 149.61,107.82 151.31,109.51 151.31,139.33 151.57,139.59 151.57,159.85 154.66,162.93 156.04,162.93 156.17,162.8 156.17,162.31 v2(156.09,162.23)
  BOTTOM w0.089: CPU1.B8 131.71,101.4 131.7,101.41 131.7,101.84 131.71,101.86 131.75,102.05 132.31,102.68 132.31,102.73
  BOTTOM w0.127: 138.21,107.14 139.61,108.54 141.64,108.54 v2(142.57,107.61) ; 138.21,107.14 137.41,106.34 135.12,104.11 135,104 132.73,103.16 132.67,103.14 132.31,102.73 ; 138.21,107.14 v1(138.11,107.24) ; v2(156.09,162.23) 155.48,161.62 155.25,161.62 155.12,161.75 WLAN1.49
WLAN_CLKREQ_CPU#: length 46.3
  TOP w0.102: D1601.1 83.38,67.02 84.13,67.77 85.01,67.77 85.12,67.67 85.12,67.44 85.43,67.13 85.58,67.13 86.02,66.69 R1607.2 v1(87.33,66.69) 87.48,66.54 v2(87.48,66.12)
  L3 w0.102: v2(87.48,66.12) 87.52,66.08 88.01,66.08 89.16,67.24 90.94,67.24 90.98,67.27 91.81,67.27 91.85,67.24 94.18,67.24 95.75,68.81 96.04,69.1 96.67,69.1 96.87,69.31 100.51,69.31 102.28,71.07 102.28,72.02 104.67,74.41 104.67,74.97 107.35,77.65 108.87,77.65 v2(109.53,78.31)
  BOTTOM w0.102: CPU1.AH61 112.1,80.9 111.92,80.93 111.77,80.95 111.67,80.9 111.49,80.7 111.28,80.52 110.57,80.32 109.67,79.88 109.23,79.48 109.1,79.4 108.72,79.43 108.35,79.74 108.07,80.49 107.53,80.93 107.32,80.93 107.04,80.85 106.88,80.71 106.76,80.44 106.76,80.37 106.84,79.77 106.97,79.38 107.47,78.16 RN1603.1 v2(109.53,78.31)
WLAN_CLKREQ_D: length 9.1
  TOP w0.102: R1605.2 85.71,74.45 v1(85.73,74.42) 86.27,73.89 86.27,72.19 85.94,71.86 Q1601.D 83.61,68.96 D1601.3
WLAN_CPU_TX_N: length 5.4
  BOTTOM w0.127: C1602.1 140.65,98.88 140.56,98.63 140.57,98.49 140.46,98.32 140.14,98.18 ; CPU1.M2 136.62,97.65 136.76,97.72 137.13,97.76 137.29,97.78 138.32,97.9 138.5,97.9 139.87,98.06 140.14,98.18 ; 140.14,98.18 v1(140.09,98.3)
WLAN_CPU_TX_P: length 5.5
  BOTTOM w0.102: CPU1.N2 136.53,97.21 136.63,97.28 136.64,97.32 136.73,97.43 136.82,97.48
  BOTTOM w0.127: 136.82,97.48 137.32,97.54 138.33,97.65 138.51,97.66 138.51,97.66 139.93,97.82 139.97,97.84 140.48,98.06 140.71,98.16 140.76,98.18 141.01,98.28 C1601.1
WLAN_PCIE_RX_N: length 82.4
  L4 w0.114: v2(156.29,160.43) 156.56,160.7 156.56,161.14 156.31,161.39 154.94,161.39 152.66,159.12 152.66,159.12 152.3,158.75 152.3,108.34 151.03,107.07 150.53,106.58 143.99,104.37 143.98,104.36 138.2,101.64 137.8,101.35 136.2,100.2 135.99,99.8 135.96,99.76 135.77,98.55 135.7,98.48 135.49,98.23 135.38,98.18 135.15,98.08 v2(134.19,98.29)
  BOTTOM w0.127: WLAN1.43 155.08,160.25 155.15,160.17 155.15,159.96 155.31,159.79 156.4,159.79 156.57,159.97 156.57,160.15 v2(156.29,160.43) ; CPU1.H6 v2(134.19,98.29)
WLAN_PCIE_RX_P: length 82.4
  L4 w0.114: v2(156.98,160.43) 156.79,160.62 156.79,161.23 156.4,161.62 156.21,161.62 156.21,161.62 154.85,161.62 152.57,159.34 152.2,158.98 152.2,158.98 152.07,158.84 152.07,108.44 150.41,106.78 143.91,104.58 138.08,101.84 138.06,101.83 137.66,101.54 136.07,100.39 136.02,100.35 135.78,99.9 135.74,99.83 135.55,98.65 135.55,98.65 135.35,98.42 135.13,98.32 135.03,98.34 v2(134.91,98.6)
  BOTTOM w0.127: CPU1.H5 v2(134.91,98.6) ; v1(156.78,159.64) 156.68,159.74 ; 156.68,159.74 156.5,159.55 155.21,159.55 155.02,159.75 154.97,159.75 154.97,159.75 WLAN1.41 ; 156.68,159.74 156.81,159.87 156.81,160.26 v2(156.98,160.43)
WLAN_PCIE_TX_N: length 70.7
  L4 w0.114: v2(155.96,159.03) 155.96,158.8 156.09,158.68 156.32,158.68 156.4,158.6 156.4,158.26 152.79,154.66 152.79,108.1 144.36,99.67 143.98,99.53 143.31,99.41 142.96,99.35 142.65,99.49 142.57,99.66 v2(142.57,99.74)
  BOTTOM w0.127: WLAN1.37 155.05,158.75 155.18,158.63 155.18,158.45 155.27,158.36 156.09,158.36 156.29,158.56 156.29,158.78 156.04,159.03 v2(155.96,159.03) ; C1602.2 v2(142.57,99.74)
WLAN_PCIE_TX_P: length 70.4
  L4 w0.114: v2(142.71,98.97) 143.03,99.13 143.04,99.13 143.35,99.18 144.04,99.31 144.48,99.47 153.02,108.01 153.02,154.56 156.62,158.17 v2(156.62,159.08)
  BOTTOM w0.127: v2(156.62,159.08) 156.53,158.99 156.53,158.46 156.19,158.12 155.17,158.12 155.03,158.25 WLAN1.35 ; C1601.2 v2(142.71,98.97)
XDP_PRDY#: length 104.6
  TOP w0.14: v1(57,76.11) 57,76.11 57,76.1 57.26,75.85 v2(57.26,75.62) 57.3,75.58 R9918.1
  L4 w0.127: v2(127.24,102.49) 127.24,103.3 127.24,103.3 127.05,103.5 127.05,103.65 125.82,104.88 125.67,104.88 122.78,107.76 118.24,107.76 117.8,107.76 116.83,108.73 109.97,108.73 109.9,108.8 103.58,108.8 103.58,108.8 102.02,108.8 101.95,108.88 98.59,108.88 96.13,106.42 96.13,105.28 92.86,102.01 92.86,95.33 91.22,93.7 91.22,93.62 88.6,89.37 87.01,87 86.91,86.85 83.69,83.35 81.74,81.41 79.42,79.65 73.21,76.89 68.15,75.73 65.83,75.73 63.85,73.75 61.75,73.75 59.44,76.06 58.77,76.06 58.33,75.62 v2(57.26,75.62)
  BOTTOM w0.089: 125.94,99.4 126.01,99.31 126.04,99.22 126.11,99.15 126.12,99.14 126.16,99.08 126.24,99 126.24,98.76 126.24,98.75 126.24,98.31 CPU1.C21
  BOTTOM w0.102: 126.66,101.56 126.66,101.17 126.41,100.64 126.17,100.4 126.15,100.4 125.94,100.19 125.94,99.4
  BOTTOM w0.14: v2(127.24,102.49) 128.25,103.5 128.25,104.04 RN1802.4 127.46,103.99 127.02,103.74 126.35,103.21 126.35,102.06 126.66,101.74 126.66,101.56
XDP_PREQ#: length 96
  TOP w0.14: v2(63.53,74.2) 63.2,73.87 v1(63.2,73.28) 63.85,73.28 R9902.2
  L4 w0.127: v2(63.53,74.2) 65.32,75.99 68.21,76.01 73.11,77.14 75.76,78.3 79.24,79.85 81.43,81.49 86.74,87.09 86.77,87.12 86.77,87.12 88.32,89.41 88.32,89.43 88.35,89.47 88.46,89.7 90.89,93.73 92.6,95.44 92.6,102.11 95.88,105.39 95.88,106.53 98.48,109.13 102.05,109.13 102.13,109.06 103.48,109.06 103.48,109.06 110,109.06 110.08,108.98 116.94,108.98 117.9,108.02 122.47,108.02 122.89,108.02 125.77,105.13 125.93,105.13 127.3,103.76 127.3,103.6 127.55,103.35 127.69,102.98 127.69,102.18 127.38,101.87 v2(127.38,101.87)
  BOTTOM w0.102: v2(127.38,101.87) 127.38,99.87 127.42,99.74 127.42,99.63 127.35,99.47 127.24,99.36 127.09,99.05 126.73,98.69 126.72,98.68 CPU1.C20
  BOTTOM w0.14: RN1802.3 128.87,103.87 128.8,103.52 128.49,102.98 v2(127.38,101.87)
XDP_PTI_CLK0: length 5.3
  BOTTOM w0.089: 117.13,98.76 117.26,98.55 117.51,98.21 117.92,97.39 118.17,97.06 118.31,96.66 CPU1.A38
  BOTTOM w0.14: 117.13,98.76 116.75,99.93 v1(116.44,100.34) 116.15,100.74 R2117.1
XDP_TCK: length 92
  TOP w0.14: R9916.1 66.4,74.59 v1(66.54,74.45) 66.68,74.31 v2(66.68,73.79) ; R1827.1 127.19,106.86 125.92,105.59 125.92,102.69 v2(125.77,102.44)
  L4 w0.127: v2(125.77,102.44) 125.85,102.52 125.85,103.16 125.32,103.68 122,103.68 119.26,106.43 111.57,106.43 111.02,106.98 110.66,106.98 110.66,106.98 110.03,106.98 109.4,107.61 104.08,107.61 103.27,107.61 102.55,106.89 98.55,106.89 97.33,105.66 97.33,104.79 94.05,101.51 94.05,94.68 92.53,93.16 90.7,90.37 90.6,90.22 90.6,90.22 90.59,90.2 90.59,90.2 90.5,90.06 90.49,90.05 90.09,89.42 89.69,88.79 89.21,88.06 88.32,86.72 88.17,86.49 88.14,86.46 88.13,86.44 87.58,85.53 82,79.96 81.07,79.24 79.94,78.38 75.14,76.31 73.56,75.66 68.48,74.54 67.18,74.54 66.68,74.04 66.68,73.79 v2(66.68,73.79)
  BOTTOM w0.089: 124.75,101 124.75,99.92 124.88,99.14 124.9,99.09 125.02,98.74 CPU1.B23
  BOTTOM w0.102: 124.75,101 125.11,101.77 125.46,102.12 125.46,102.13 v2(125.77,102.44)
XDP_TDI: length 114.2
  TOP w0.14: v2(59.04,75.62) 59.08,75.58 R9922.1 ; v2(126,100.8) 126.27,100.8 126.79,101.32 126.79,102.68 127.14,103.03 132.6,105.36 132.95,105.36 134.36,105.99 136.73,107.06 137.9,107.06 137.99,107.09 138.83,107.61 v1(139.27,107.89) 139.79,108.2 R1806.2
  L4 w0.127: v2(126,100.8) 126.3,100.8 126.63,101.13 126.72,101.33 126.72,102.06 126.79,102.13 126.79,103.55 125.71,104.62 125.56,104.62 122.68,107.51 118.34,107.51 116.07,107.51 115.11,108.47 109.87,108.47 109.79,108.55 103.69,108.55 103.69,108.55 101.92,108.55 101.84,108.63 98.7,108.63 96.39,106.32 96.39,105.18 93.11,101.9 93.11,95.16 91.47,93.52 88.85,89.26 87.3,86.93 86.01,85.36 85.91,85.23 81.58,80.87 79.54,79.32 73.32,76.63 68.18,75.48 66.29,75.48 64.31,73.5 61.49,73.5 59.37,75.62 v2(59.04,75.62)
  BOTTOM w0.102: v2(126,100.8) 125.74,100.54 125.74,99.11 125.65,98.93 CPU1.C22
XDP_TDO: length 108.7
  TOP w0.14: R1833.1 139.71,108.97 138.65,107.91 138.26,107.65 137.63,107.36 136.74,107.36 132.94,105.65 132.59,105.65 132.54,105.63 132.45,105.63 127.05,103.44 126.48,102.87 126.48,101.87 126.48,101.86 v2(126.25,101.39) ; R9920.2 66.02,70.06 v1(66.25,70.28) 66.35,70.39 66.35,72.82 65.41,73.76 v2(65.41,73.84)
  L4 w0.127: v2(65.41,73.84) 66.8,75.22 68.31,75.22 73.43,76.38 79.62,79.04 81.6,80.53 86.09,85.06 87.56,86.82 87.58,86.85 87.6,86.88 88.87,88.8 88.96,88.93 89.11,89.16 89.89,90.39 89.89,90.4 89.98,90.52 90.47,91.29 90.47,91.3 91.83,93.42 91.95,93.6 93.37,95.02 93.37,101.8 96.64,105.07 96.64,106.21 98,107.57 101.96,107.57 102.69,108.29 103.79,108.29 103.79,108.3 109.69,108.3 109.76,108.22 114.8,108.22 115.81,107.22 122.61,107.22 125.45,104.37 125.61,104.37 126.54,103.44 126.54,102.24 126.46,102.17 126.46,101.84 v2(126.25,101.39)
  BOTTOM w0.102: CPU1.A22 125.39,99.74 125.24,100.13 125.74,101.2 v2(126.25,101.39)
XDP_TMS: length 95.4
  TOP w0.14: v2(66.05,73.81) 66.05,73.76 67.01,72.8 v1(67.01,71.78) 67.01,71.55 66.68,71.22 66.68,69.01 66.4,68.73 65.56,68.73 65.29,69.01 R1812.1 R9910.2
  L4 w0.127: v2(125.77,101.8) 126.21,102.24 126.21,102.27 126.28,102.35 126.28,103.34 125.5,104.12 122.28,104.12 119.51,106.89 115.69,106.89 114.61,107.96 109.66,107.96 109.58,108.04 103.9,108.04 103.9,108.04 102.94,108.04 102.22,107.32 98.11,107.32 96.9,106.11 96.9,104.97 93.62,101.69 93.62,94.85 92.1,93.34 92.1,93.34 90.69,91.16 90.2,90.4 90.16,90.33 90.16,90.33 89.33,89.02 89.32,89.02 89.17,88.79 87.96,86.96 87.81,86.74 87.77,86.68 87.3,85.92 81.76,80.33 79.76,78.82 73.53,76.13 68.43,74.97 67,74.97 66.05,74.02 66.05,73.81 v2(66.05,73.81)
  BOTTOM w0.089: 125.04,99.92 125.08,99.15 125.16,98.92 125.21,98.85 125.37,98.68 125.37,98.44 125.35,98.33 CPU1.C23
  BOTTOM w0.102: v2(125.77,101.8) 125.57,101.37 125.04,100.23 125.04,99.92
XDP_TRST#: length 90.3
  TOP w0.14: v1(67.29,73.46) v2(67.29,74.02) 67.29,74.54 R9908.1 ; ED1806.1 R1828.1 125.4,107.01 125.81,106.6 125.81,106.11 125.35,105.66 125.35,103.64 125.36,103.63 v2(125.36,103.02)
  L4 w0.127: v2(125.36,103.02) 120.58,103.02 117.61,106 111.39,106 110.84,106.55 110.48,106.55 110.48,106.55 109.85,106.55 109.22,107.18 104.26,107.18 103.56,107.18 102.84,106.45 102.58,106.45 102.57,106.45 98.73,106.45 97.76,105.48 97.76,104.61 94.48,101.33 94.48,94.5 92.96,92.98 91.06,90.13 90.86,89.82 90.05,88.56 88.68,86.49 88.52,86.24 88.49,86.21 88.3,85.65 82.29,79.64 80.13,77.96 76.99,76.6 73.55,75.19 68.56,74.11 67.38,74.11 v2(67.29,74.02)
  BOTTOM w0.089: 124.44,99.83 124.52,99.58 124.63,99.26 124.65,99.2 124.72,99.02 124.8,98.79 124.8,98.59 124.8,98.59 CPU1.C24
  BOTTOM w0.14: 124.44,99.83 124.44,101.63 124.52,101.7 v2(125.36,103.02)
XDP_UART_RXD_CPU: length 105.4
  TOP w0.14: R9901.2 40.85,69.59 v1(40.95,69.48) 40.95,68.71 41.81,67.85 45.4,67.85 45.58,68.03 45.58,68.63 45.57,68.63 v2(45.57,69.24)
  L4 w0.127: v2(117.13,94.58) 116.17,97.23 116.17,97.38 116.06,97.67 115.8,98.39 115.71,98.49 115.71,99.29 114.66,100.34 114.03,100.34 112.65,101.73 109.62,101.73 109.07,102.28 108.28,102.28 108.03,102.03 105.09,102.03 104.88,101.82 103.86,101.82 103.6,101.56 103.6,100.39 104.36,99.63 104.36,96.75 96.26,88.65 96.26,87.62 94.74,86.1 94.08,86.1 93.67,85.69 92.98,85 92.66,84.21 92.33,83.88 85.12,76.67 84.97,76.52 83.99,75.55 83.99,73.99 83.99,73.72 83.09,72.82 80.95,72.82 79.31,71.19 78.68,71.19 78.56,71.19 76.86,69.48 73.38,69.48 73.38,69.48 72.37,69.48 72.01,69.13 63.8,69.13 63.65,69.28 60.65,69.28 60.12,69.81 49.31,69.81 48.74,69.25 48.48,68.98 45.84,68.98 v2(45.57,69.24)
  BOTTOM w0.14: CPU1.C43 v2(117.13,94.58)
XTL_19D2M_X1_CPU: length 20.7
  L4 w0.127: v2(132.7,104.4) 132.02,104.71 131.48,104.45 131.35,104.31 130.03,101.97 129.35,100.82 128.06,99.54 128.06,99.5 127.12,98.56 126.91,98.56 125.61,97.26 125.61,97.13 125.45,96.97 125.45,94.05 v2(124.76,92.75)
  BOTTOM w0.14: CPU1.P29 v2(124.76,92.75) ; X1901.1 131.47,107.69 131.3,107.52 131.3,107.39 131.46,106.96 131.55,106.7 131.57,106.67 131.57,106.37 131.67,106.21 C1901.1 132.5,105.11 v2(132.7,104.4)
XTL_19D2M_X2_CPU: length 20.7
  L4 w0.127: v2(125,92.08) 125.58,93.21 125.99,93.99 125.99,96.79 126.12,96.92 126.12,97.04 127.07,98 127.44,98 128.3,98.95 128.52,98.95 129.3,99.74 130.38,101.57 130.47,101.72 131.45,103.45 v2(131.91,104.04)
  BOTTOM w0.14: v2(131.91,104.04) R1907.1 131.23,105.61 131.05,106.5 131.05,106.53 131.05,106.57 130.78,107.3 130.78,107.45 130.54,108.01 130.32,108.23 X1901.3 ; CPU1.R27 v2(125,92.08)
XTL_32K_X1_CPU: length 19.1
  TOP w0.102: 108.65,82.79 110.19,82.79 111.39,83.04 v2(111.92,83.14)
  TOP w0.14: 108.65,82.79 107.84,82.79 107.64,82.68 107.38,82.41 106.16,82.41 105.71,81.96 v1(103.21,81.96) 100.71,81.96 100.24,81.49 v2(99.58,81.49)
  BOTTOM w0.14: v2(99.58,81.49) 99.44,81.62 R1810.1 C1803.1 95.57,81.79 94.84,81.68 X1801.4 ; CPU1.AC59 v2(111.92,83.14)
XTL_32K_X2_CPU: length 19.6
  TOP w0.102: v2(112.71,83.49) 112.58,83.27 112.48,83.08 112.32,82.93 112.23,82.84 111.86,82.67 111.13,82.6 108.82,82.6 108.35,82.49 108.26,82.43
  TOP w0.14: v2(99.58,80.85) 99.69,80.96 100.45,80.96 100.92,81.43 v1(105.2,81.43) 105.92,81.43 106.38,81.89 107.68,81.89 108.16,82.38 108.26,82.43
  BOTTOM w0.14: CPU1.AC58 v2(112.71,83.49) ; v2(99.58,80.85) 99.46,80.74 R1810.2 C1804.1 95.87,81.04 95.46,81 X1801.1

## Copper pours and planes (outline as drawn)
1V_CPU_VCGI on TOP: outline of 82 points within 109.99,85.69 126.86,119.84 ; 40 cut-outs
1V_CPU_VCGI on BOTTOM: 123.71,85.42 123.53,85.5 123.48,85.68 123.5,85.9 123.27,86.21 123.1,86.21 122.89,86.16 122.82,85.98 122.73,85.92 122.49,85.88 122.26,85.98 121.9,86.82 121.44,87 121.29,87.1 121.27,87.25 121.27,87.45 121.11,87.68 120.84,87.71 120.63,87.56 120.45,87.4 120.2,87.43 119.95,88.06 119.67,88.32 119.23,88.27 117.53,87.66 116.97,87.61 116.47,87.51 116.29,87.53 116.21,87.76 116.57,88.65 116.69,88.8 117.63,89.13 118.24,89.08 118.45,89.03 118.8,89.13 118.85,89.36 119.01,89.44 119.26,89.38 119.46,89.33 120.3,89.64 121.75,90.07 122.41,89.99 122.79,88.67 122.97,88.5 123.32,88.42 123.43,88.27 123.43,87.78 124.04,86.16 124.01,85.68 123.96,85.52
1V_CPU_VCGI on BOTTOM: 126.52,84.23 126.25,84.33 125.74,84.48 125.03,84.36 124.77,84.43 124.72,84.56 124.8,84.71 125.28,85.63 125.23,85.9 125,86.08 124.83,86.58 124.75,87.3 124.54,87.45 124.26,88.7 124.19,88.8 123.9,89.05 123.73,89.51 123.78,89.74 123.73,89.97 123.53,90.17 123.48,90.25 123.45,90.45 123.53,90.55 124.8,90.98 125.18,91.04 125.33,90.88 125.56,90.17 125.56,89.87 125.64,89.69 125.76,89.59 125.81,89.46 126.32,88.14 126.78,86.84 126.7,86.57 126.75,86.39 126.8,86.29 127.05,86.12 127.24,85.75 127.31,85.3 127.21,85.17 126.75,84.28
1V_CPU_VCGI on BOTTOM: 111.11,109.65 110.6,110.16 110.6,113.34 109.94,114 109.94,114.66 110.01,114.73 112.45,114.73 112.55,114.84 112.55,115.27 112.66,115.37 113.62,115.37 114.54,116.28 114.54,119.61 114.79,119.86 120,119.86 120.4,119.46 120.4,109.81 120.25,109.65 ; 5 cut-outs
1V_CPU_VCGI on BOTTOM: 114.83,102.71 114.48,102.76 114.3,102.86 113.93,103.61 113.49,104.78 113.56,105.1 113.9,105.29 120.58,107.95 121.09,107.75 121.85,106.02 121.76,105.73 121.52,105.46 115.2,102.9 ; 5 cut-outs
1V_CPU_VCGI on L2VCC: 124.29,85.16 123.26,85.27 122.97,85.56 122.84,86.45 122.4,86.89 121.66,87.39 121.41,87.76 120.76,88.28 119.95,89.09 119.32,89.09 118.78,88.82 118.25,88.61 117.87,88.9 117.64,89.48 115.99,94.3 115.23,96.45 114.87,98.02 115.37,98.9 114.85,102.42 110.03,112.69 110.03,114.99 110.42,115.38 112.07,115.38 113.08,116.38 113.08,118.67 114.11,119.7 120.92,119.7 121.33,119.19 121.33,115.37 126.47,110.1 126.66,109.91 126.66,106.49 127.68,105.1 127.68,103.13 127.43,98.18 127.43,94.72 127.82,93.29 128.06,92.55 128.06,90.71 127.8,89.93 128.05,88.93 127.57,88.1 127.5,87.91 127.45,87.88 127.41,87.73 127.42,87.72 127.29,87.4 127.42,86.4 127.35,86.26 126.66,86.03 125.01,85.4
1V_CPU_VCGI on L3: 126.63,90.15 126.62,89.16 127.01,87.66 127.21,86.77 126.75,86.01 125.97,85.52 124.47,85.04 123.81,85.19 123.58,85.45 123.46,86.06 121.65,87.25 121.24,87.89 120.35,88.44 119.87,88.98 119.36,88.98 118.27,88.57 118.17,88.58 118.07,88.62 117.89,88.95 116.14,94.06 114.97,102.72 109.96,112.88 109.96,115.06 110.42,115.52 112.3,115.52 113.06,116.28 113.06,118.57 114.33,119.84 121.06,119.84 121.47,119.43 121.47,115.45 126.63,110.29
1V_CPU_VNN on TOP: 103.08,112.42 102.78,112.73 102.78,118.14 103,118.37 107.07,118.37 107.32,118.11 107.32,112.7 107.04,112.42 ; 8 cut-outs
1V_CPU_VNN on TOP: 128.38,84.35 128.31,84.38 128.16,84.79 128.27,85.02 128.61,85.14 128.71,85.37 128.41,86.22 128.48,86.38 129.58,86.78 130.55,86.33 130.62,86.11 130.53,85.9 129.68,85.59 129.58,85.36 129.64,85.19 129.42,84.73
1V_CPU_VNN on TOP: 119.49,82.42 119.34,82.52 119.15,83.06 119.16,83.16 119.21,83.26 119.26,83.31 119.36,83.52 119.31,83.77 119.09,84.27 119,84.62 119.05,84.72 119.38,84.86 119.57,84.89 119.66,84.76 119.83,84.34 120,84.27 121.32,84.75 122.08,85.22 122.97,85.47 123.12,85.5 123.2,85.4 123.32,85.02 123.48,84.61 123.6,84.25 123.6,84.21 123.55,84.18 123.07,83.95 122.85,83.68 122.64,83.54 119.85,82.53 ; 3 cut-outs
1V_CPU_VNN on BOTTOM: 120.79,81.91 120.52,81.92 120.3,82.11 119.92,82.24 119.52,82.19 119.29,82.23 119.11,82.35 118.92,82.78 118.89,82.89 118.91,83.16 118.94,83.19 119.04,83.21 119.2,83.27 119.28,83.35 119.33,83.47 119.35,83.61 119.41,83.8 119.51,83.93 119.53,84.05 119.5,84.18 119.45,84.24 119.38,84.3 119.31,84.33 119.27,84.37 119.24,84.43 119.23,84.47 119.28,84.59 119.31,84.72 119.38,84.76 119.54,84.76 119.67,84.67 119.71,84.55 119.71,84.48 119.68,84.37 119.67,84.3 119.68,84.24 119.7,84.18 119.75,84.1 119.86,84.03 120.01,84.02 120.11,84.05 120.2,84.13 120.25,84.21 120.3,84.28 120.48,84.37 120.69,84.35 120.93,84.46 121.12,84.64 121.28,84.64 121.55,84.61 121.67,84.66 121.71,84.79 121.86,84.91 121.95,84.92 122.35,84.89 122.56,84.96 123.26,85.22 123.5,85.13 123.57,84.96 123.83,84.18 123.77,83.87 123.63,83.68 122.75,83.37 122.62,82.92 122.52,82.53
1V_CPU_VNN on BOTTOM: 103.21,113.67 102.78,114.1 102.78,121.13 102.93,121.29 106.76,121.29 106.79,121.26 106.79,114.12 106.33,113.67
1V_CPU_VNN on BOTTOM: 129.23,84.92 128.66,85.19 128.57,85.43 128.73,85.77 129.14,85.92 129.5,85.86 129.69,85.67 129.37,84.97
1V_CPU_VNN on L2VCC: 123.67,82.75 121.79,83.12 117.76,83.12 117.15,83.49 115.4,83.99 114.9,84.49 114.23,84.76 113.33,85.14 112.54,85.37 112.42,85.84 111.4,86.61 111.16,87.32 110.9,87.96 110.15,89.58 110.15,90.21 109.76,91.26 108.87,93.54 108.62,94.18 107.88,96.14 108.38,97.66 107.86,99.88 103.16,111.83 102.66,113.07 102.66,118.03 102.93,118.3 106.58,118.3 106.98,117.91 106.98,114.6 108.49,113.1 109.65,113.1 109.65,112.61 114.48,102.31 114.97,98.97 114.46,98.08 114.86,96.34 115.63,94.17 117.28,89.34 117.55,88.65 118.19,88.18 118.93,88.47 119.41,88.71 119.79,88.71 120.5,88 121.12,87.5 121.38,87.11 122.16,86.59 122.48,86.27 122.61,85.38 123.08,84.91 124.34,84.77 125.14,85.04 126.79,85.67 127.63,85.95 127.81,86.33 127.69,87.35 127.76,87.53 128.54,87.33 129.63,86.24 130.23,85.4 130.34,84.88 129.79,84.12 128.23,83.76 127.22,83.76 126.55,83.63
1V_CPU_VNN on L3: 122.31,84.48 120.12,83.62 119.21,83.19 118.52,83.16 118.42,83.34 118.27,83.64 118.24,83.66 117.81,83.75 117.58,84.05 117.35,85.22 117.13,85.5 116.73,85.69 116.71,85.68 116.14,85.68 113.88,84.94 113.34,85.12 112.28,85.57 110.01,90.96 110.18,95.52 106.56,102.61 104.03,110.94 103.51,111.64 102.45,112.87 102.45,118.42 102.75,118.72 106.36,118.72 106.81,118.26 106.81,115.83 109.23,113.41 109.81,112.47 114.38,102.8 114.7,100.64 115.09,99.85 115.25,98.81 115.12,97.82 115.42,95.73 117.79,88.67 117.91,88.52 118.12,88.41 119.23,88.8 119.74,88.8 120.96,87.89 121.17,87.63 121.29,87.4 122.68,86.08 122.71,86.06 122.84,84.91 122.32,84.5
5V_HDD_S0 on BOTTOM: 173.82,43.44 173.72,43.54 173.72,44.68 173.77,44.73 174.73,44.73 174.81,44.81 174.81,45.77 174.2,46.38 174.2,50.88 174.63,51.31 176.72,51.31 176.79,51.23 176.79,49.76 176.72,49.68 176.59,49.68 176.46,49.56 176.46,48.95 176.41,48.9 176.31,48.9 176.23,48.82 176.23,46.61 176.74,46.1 176.74,43.82 176.36,43.44 ; 1 cut-out
5V_HDMI_S0 on BOTTOM: 10.45,55.07 10.35,55.17 10.35,56.72 12.25,58.63 16.09,58.63 16.16,58.55 16.16,57.41 16.14,57.38 15.55,57.38 15.37,57.2 15.37,56.57 15.25,56.44 13.88,56.44 12.5,55.07 ; 2 cut-outs
5V_PWR on TOP: 29.32,39.7 29.19,39.83 29.19,47.83 29.29,47.93 35.34,47.93 35.72,47.55 35.72,39.93 35.49,39.7
5V_PWR on BOTTOM: 28.61,39.7 28.4,39.91 28.4,46.61 28.68,46.89 35.41,46.89 35.72,46.59 35.72,39.93 35.49,39.7 ; 1 cut-out
5V_S0 on TOP: 44.53,26.8 44.2,27.13 44.2,29.24 44.48,29.52 49.56,29.52 49.87,29.21 49.87,26.93 49.74,26.8 ; 2 cut-outs
5V_S0 on TOP: 28.73,48.41 28.43,48.72 28.43,50.52 28.46,50.55 29.29,50.55 29.65,50.19 31.73,50.19 31.86,50.07 31.86,49.53 31.71,49.38 31.71,48.49 31.63,48.41 ; 2 cut-outs
5V_S0 on BOTTOM: 177.3,49.63 177.17,49.76 177.17,53.16 177.32,53.32 178.92,53.32 179.15,53.09 179.15,49.71 179.08,49.63
5V_S0 on BOTTOM: 28.66,48.62 28.43,48.85 28.43,50.52 28.68,50.78 32.11,50.78 32.21,50.68 32.21,48.85 31.99,48.62 ; 3 cut-outs
5V_S0 on BOTTOM: 167.22,133.99 166.17,135.03 166.17,136.76 164.6,138.33 164.6,142.95 165.95,144.3 165.95,144.86 168.56,147.47 170.47,147.47 170.52,147.42 170.52,145.8 167.62,142.9 167.62,138.33 168.26,137.7 177.35,137.7 177.68,137.37 177.68,134.29 177.38,133.99 ; 4 cut-outs
5V_S0 on BOTTOM: 149.91,21.06 149.8,21.16 149.8,23.76 149.61,23.95 148.39,23.95 148.04,23.6 148.04,22.33 147.76,22.05 146.59,22.05 146.41,22.23 146.41,24.61 146.69,24.89 151.06,24.89 151.19,24.77 151.19,21.08 151.16,21.06
5V_S0 on BOTTOM: 129.93,21.47 129.85,21.54 129.85,23.45 128.81,24.49 53.98,24.49 51.04,27.43 44.61,27.43 44.2,27.84 44.2,29.64 44.57,30.01 52.8,30.01 52.94,29.87 52.94,29.26 55,27.21 101.71,27.21 102.04,26.88 130.08,26.88 131.58,25.38 131.58,22.35 131.76,22.18 131.76,21.49 131.73,21.47 ; 4 cut-outs
5V_S0 on L3: 151.14,18.87 152.38,17.63 152.38,14.53 160.71,6.2 170.09,6.2 175.83,11.94 175.83,51.11 176.11,51.39 179.1,51.39 179.23,51.26 179.23,9.96 171.43,2.16 147.86,2.16 146.13,3.89 146.13,12.83 144.74,14.23 130.23,14.23 129.98,14.48 129.98,23.98 130.08,24.08 132.6,24.08 132.72,23.95 132.72,19 132.85,18.87
5V_S0 on L3: 28.15,42.7 28.15,39.25 30.84,36.55 37.98,36.55 45.52,29.01 48.06,29.01 48.37,28.7 48.37,24.77 48.24,24.64 28.51,24.64 21.55,31.6 21.55,43.64 27.01,49.1 28,49.1 29.5,50.6 31.76,50.6 32.38,49.98 32.38,44.97 32.11,44.71 30.16,44.71
5V_S0 on L4: 49.33,27.09 37.14,27.09 37.04,26.99 37.04,25.02 37.15,24.91 50.91,24.91 51.53,25.53 132.32,25.53 133.69,24.16 137.42,24.16 137.43,24.14 139.42,24.14 140.98,22.58 147.76,22.58 148.19,23.01 148.19,25.38 147.99,25.58 142.27,25.58 141.56,26.29 135.36,26.29 133.87,27.79 50.03,27.79
5V_S0 on L4: 176.61,137.64 176.69,137.72 179.15,137.72 179.31,137.57 179.31,91.24 179.76,90.78 179.76,48.44 179.53,48.21 176.87,48.21 176.61,48.47
5V_S0_SIP on BOTTOM: 149.23,17.6 149.11,17.73 149.11,19.79 148.19,20.7 148.19,21.74 148.42,21.97 149.46,21.97 149.64,21.8 149.64,21.13 149.92,20.86 150.71,20.86 150.76,20.8 150.76,17.71 150.65,17.6 ; 1 cut-out
5V_S5 on TOP: 132.01,13.92 131.45,14.48 131.45,22.53 129.45,24.54 51.75,24.54 50.99,23.78 41.79,23.78 39.68,25.88 39.68,32.9 37.14,35.44 27.69,35.44 25.38,37.75 22.77,37.75 22.71,37.8 22.71,38.36 23.1,38.74 23.1,47.88 23.45,48.24 23.45,51.11 23.58,51.23 25.28,51.23 25.46,51.41 26.04,51.41 26.07,51.39 26.07,51.08 26.04,51.06 25.71,51.06 25.43,50.78 25.43,50.4 25.56,50.27 25.99,50.27 26.27,50.55 27.06,50.55 27.11,50.5 27.11,49.58 28.84,47.86 28.84,39.5 29.98,38.36 34.88,38.36 35.01,38.23 40.14,38.23 43.56,34.81 43.56,26.81 44.03,26.34 50.68,26.34 51.04,26.7 109.91,26.7 109.93,26.68 134.23,26.68 137.14,23.78 137.14,17.2 138.01,16.33 144.56,16.33 144.71,16.18 144.71,14.15 144.48,13.92 ; 10 cut-outs
5V_S5 on TOP: 131.76,124.54 131.53,124.77 131.53,126.11 131.71,126.29 132.29,126.29 132.65,125.94 135.87,125.94 136.13,126.19 136.13,131.17 136.18,131.22 137.98,131.22 138.11,131.09 138.11,125.66 136.99,124.54 ; 4 cut-outs
5V_S5 on BOTTOM: 160.99,9.25 160.76,9.48 160.76,10.72 160.87,10.82 162.41,10.82 162.87,10.37 162.87,9.4 162.72,9.25
5V_S5 on BOTTOM: 138.46,124.56 136.24,126.79 136.24,127.65 136,127.89 136,128.35 136.08,128.42 137.78,128.42 137.88,128.32 137.88,126.7 138.84,125.73 140.01,125.73 140.16,125.58 140.16,124.61 140.11,124.56
5V_S5 on L2VCC: 21.78,64.96 21.13,65.61 21.13,65.96 22.54,67.38 26.83,67.38 27.59,66.61 33.72,66.61 42.22,75.12 59.62,75.12 60.64,76.14 66.42,76.14 67.32,76.27 71.02,77.03 74.47,77.93 79.71,80.61 80.1,80.87 83.55,83.56 86.62,87.13 88.79,89.81 90.84,93.65 91.99,97.11 92.88,103.11 92.88,144.07 93.53,144.72 96.93,144.72 97.2,144.45 97.2,142.07 96.8,141.67 95.03,141.67 93.9,140.54 93.9,100.98 93.39,97.7 93.02,96.33 89.99,89.77 86.07,84.96 83.29,82.06 81.28,80.55 76.98,78.15 73.46,76.51 67.15,75.38 61.5,75.38 60.35,74.23 42.7,74.23 34.32,65.85 23.27,65.85 22.38,64.96
5V_S5 on L3: 21.88,66.6 21.24,65.97 21.24,56.82 22.94,55.12 22.94,49.1 23.4,48.64 26.32,48.64 26.86,49.18 26.86,50.8 26.32,51.34 25.23,51.34 25.08,51.49 25.08,56.14 23.35,57.86 23.35,66.55 23.3,66.6
5V_S5 on L4: 133.31,135.69 134.2,134.8 134.2,133.23 136.79,130.63 136.79,127.48 137.04,127.23 138.11,127.23 138.49,127.61 138.49,130.48 135.21,133.76 135.21,135.77 133.66,137.31 130.97,137.31 124.24,144.05 96.4,144.05 96.17,143.82 96.17,138.86 96.74,138.29 99.69,138.29 99.85,138.46 99.85,139.02 99.78,139.09 97.19,139.09 96.88,139.4 96.88,141.68 97.26,142.06 121.75,142.06 125.46,138.36 125.46,137.42 127.19,135.69
5V_S5 on L4: 162.97,9.76 162.97,8.28 163.2,8.05 163.96,8.05 164.09,7.93 164.09,7.06 164.02,6.99 163.53,6.99 162.59,6.05 151.16,6.05 146.32,10.89 146.32,12.94 144.47,14.8 142.97,14.8 142.88,14.89 142.88,18.65 143.14,18.9 147.28,18.9 156.09,10.09 162.64,10.09
5V_USB30 on TOP: 13.82,33.99 13.49,34.32 13.49,36.37 14.16,37.04 14.16,40.59 14.33,40.77 21.83,40.77 22.08,40.52 22.08,37.85 21.95,37.72 20.17,37.72 19.34,36.88 19.34,35.59 19.18,35.44 17.18,35.44 15.73,33.99 ; 3 cut-outs
5V_USB30 on TOP: 13.9,15.98 13.6,16.28 13.6,18.32 13.77,18.49 19.34,18.49 19.46,18.37 19.46,16.66 19.2,16.4 16.38,16.4 16.06,16.08 15.32,16.08 15.22,15.98 ; 1 cut-out
5V_USB30 on L3: 19.39,39.17 19.59,38.97 19.59,24.79 22.11,22.28 22.11,16.82 21.83,16.54 17.81,16.54 16.72,15.45 13.8,15.45 13.67,15.57 13.67,18.21 15.76,20.3 15.76,32.56 14.84,33.48 13.72,33.48 13.52,33.68 13.52,35.56 13.53,35.57 13.53,36.41 14.59,37.47 14.59,38.99 14.76,39.17
19V_AD+ on TOP: 140.37,157.36 140.24,157.48 140.24,158.52 140.44,158.73 141.87,158.73 141.92,158.78 141.92,162 141.97,162.05 145.42,162.05 145.68,162.31 149.64,162.31 150.02,161.93 150.02,157.58 149.79,157.36 ; 4 cut-outs
19V_DCBATOUT on TOP: 51.14,28.32 44.69,34.77 44.69,38.08 44.89,38.28 49.41,38.28 49.94,38.81 49.94,41.63 51.09,42.78 54.52,42.78 54.97,42.32 54.97,37.39 52.59,35 52.59,31.35 53.73,30.2 62.49,30.2 62.54,30.15 62.54,28.48 62.39,28.32
19V_DCBATOUT on TOP: 44.61,59.11 44.48,59.23 44.48,60.91 44.64,61.06 47.81,61.06 47.89,60.99 47.89,59.18 47.81,59.11
19V_DCBATOUT on TOP: 55.15,52.38 55.14,52.39 55.04,52.39 54.24,53.19 54.24,57.48 54.39,57.63 65.39,57.63 70.84,63.08 70.84,68.39 70.11,69.12 68.59,69.12 68.03,69.67 68.03,75.67 68.79,76.43 73.96,77.84 77.72,79.45 84.39,84.51 88.45,89.14 90.71,93.75 92.11,98.45 92.67,102.57 92.9,103.5 92.95,103.95 92.95,148.52 97.34,152.91 97.34,153.57 97.44,153.67 121.7,153.67 126.04,158.02 126.04,159.39 126.4,159.74 136.33,159.74 136.74,159.34 136.74,152.33 127.86,143.41 117.99,143.41 117.7,143.12 117.7,142.31 115.55,140.16 115.55,138.25 115.2,137.9 111.61,137.9 111.41,137.7 111.41,134.27 111.28,134.14 107.68,134.14 107.53,134.29 107.53,137.21 107.18,137.56 105.18,137.56 98.1,130.48 98.1,112.8 99.73,111.18 99.73,108.54 101.15,107.11 107.8,107.11 108.31,106.61 108.31,99.85 98.66,90.2 98.64,90.2 83.28,74.84 82.34,74.84 78.95,71.45 78.95,68.2 78.57,67.82 78.57,66.3 78.07,65.8 78.07,62.35 68.1,52.38 ; 10 cut-outs
19V_DCBATOUT on TOP: 95.16,160.48 95.05,160.58 95.05,163.12 95.13,163.2 99.88,163.2 100.01,163.07 100.01,160.66 99.83,160.48 ; 3 cut-outs
19V_DCBATOUT on TOP: 158.99,159.54 158.81,159.72 154.57,159.72 153.6,160.68 153.6,164.64 153.14,165.1 151.82,165.1 151.75,165.18 151.75,169.27 152.08,169.6 160.1,169.6 160.23,169.47 160.23,168.38 160.51,168.1 161.68,168.1 162.24,167.54 162.24,163.5 163.38,162.36 166.38,162.36 166.56,162.18 166.56,159.62 166.48,159.54 ; 4 cut-outs
19V_DCBATOUT on BOTTOM: 52.71,52.83 52.15,53.39 50.63,53.39 44.5,59.53 44.5,61.43 44.86,61.8 49.69,61.8 51.16,60.33 51.16,59.11 52.66,57.61 59.7,57.61 60.46,56.85 60.46,54.74 58.55,52.83
19V_DCBATOUT on BOTTOM: 111.44,136.17 111.31,136.3 111.31,141.56 111.51,141.76 115.27,141.76 115.55,141.48 115.55,136.3 115.42,136.17
19V_DCBATOUT on L2VCC: 50.86,53.02 44.11,59.77 44.11,73.85 60.51,73.85 61.66,75 67.18,75 73.57,76.15 77.16,77.81 81.49,80.23 83.55,81.77 86.36,84.71 90.31,89.56 93.38,96.2 93.77,97.63 94.28,100.95 94.28,140.39 95.18,141.29 96.96,141.29 97.58,141.91 97.58,144.61 97.2,144.99 97.2,152.45 97.98,153.23 124.36,153.23 125.01,152.58 125.01,148.16 124.36,147.51 106.46,147.51 105.2,146.26 105.2,138 98.22,131.02 98.22,112.83 99.61,111.43 99.61,108.38 102.15,105.84 102.15,102.72 102.53,101.45 102.53,95.31 101.31,93.6 98.92,91.59 97.27,90.07 94.03,87.86 94.03,86.44 85.46,77.87 82.29,75.59 79.37,73.44 77.88,72.44 72.47,70.68 68.93,70.68 68.04,70.55 62.64,70.55 61.5,69.41 52.1,69.41 51.48,68.79 51.48,67.25 51.1,66.74 51.1,58.72 52.49,57.47 59.72,57.47 60.62,56.57 60.62,54.95 58.7,53.02
19V_DCBATOUT on L3: 159.47,170.28 162.54,167.21 162.54,161.11 162.16,160.73 158.12,160.73 157.77,161.09 157.77,162.59 156.78,163.58 153.27,163.58 150.88,161.19 150.88,158.9 148.93,156.95 142.37,156.95 142.02,156.59 142.02,154.38 141.76,154.13 132.7,154.13 130.66,156.16 130.66,169.88 131.07,170.28
19V_DCBATOUT on L3: 61.42,44.2 61.22,43.99 61.22,43.21 60.71,42.7 60.71,41.86 56.45,37.59 50.65,37.59 50.43,37.82 50.43,42.57 50.63,42.78 53.02,42.78 53.63,43.39 53.63,54.89 53.96,55.22 60.87,55.22 61.42,54.66
19V_DCBATOUT on L4: 162.06,161.06 162.39,161.39 162.39,167.31 159.49,170.21 152.36,170.21 152.27,170.3 146.45,170.3 146.36,170.21 144.76,170.21 138.56,164.01 131.1,164.01 130.66,163.58 130.66,154.41 130.94,154.13 139.07,154.13 139.66,154.71 139.66,158.02 140.32,158.68 147.61,158.68 152.56,163.63 156.6,163.63 157.77,162.46 157.77,161.29 158,161.06
19V_DCBATOUT_LCD on TOP: 96.43,164.26 96.3,164.39 96.3,165.89 97.19,166.78 97.19,169.62 97.34,169.78 101.4,169.78 101.56,169.62 101.56,164.34 101.48,164.26 ; 2 cut-outs
19V_DCBATOUT_LCD on BOTTOM: 99.96,167.24 99.79,167.33 99.63,167.72 99.68,168 99.58,168.66 99.37,169.27 99.32,169.39 99.32,169.45 99.96,169.67 100.06,169.7 100.11,169.67 100.16,169.52 100.52,168.56 100.85,167.86 100.74,167.51
+5V_PVDD on BOTTOM: 156.06,19.66 154.88,20.84 153.56,20.84 153.4,20.68 153.4,20.04 153.13,19.78 151.35,19.78 151.26,19.86 151.26,20.83 151.54,21.11 151.54,24.39 151.7,24.54 156.22,24.54 156.93,23.83 156.93,23.6 157.11,23.42 157.26,23.42 157.59,23.09 157.59,22.43 157.56,22.4 157.41,22.4 157.39,22.43 157.39,22.94 157.16,23.17 156.65,23.17 155.89,23.93 154.34,23.93 153.96,23.55 153.96,22.1 154.19,21.87 154.54,21.87 156.4,20.02 156.8,20.02 156.83,19.99 156.83,19.71 156.78,19.66 ; 5 cut-outs
GND on TOP: 150.68,36.5 150.48,36.71 150.48,39.3 150.63,39.45 160.38,39.45 161.42,38.41 163.43,38.41 164.19,39.17 167.95,39.17 168.13,39.35 168.79,39.35 168.97,39.52 168.97,40.79 168.84,40.92 161.86,40.92 161.78,41 161.78,41.28 161.81,41.3 163.96,41.3 164.62,41.96 165.13,41.96 165.72,41.38 168.82,41.38 168.92,41.48 168.92,42.72 168.71,42.93 168.05,42.93 167.95,43.03 167.95,43.18 167.85,43.28 167.32,43.28 167.24,43.36 167.24,43.97 167.34,44.07 169.58,44.07 170.64,43 170.64,39.27 169.34,37.96 165.76,37.96 164.88,37.09 154.16,37.09 153.75,37.49 152.99,37.49 152.92,37.42 152.92,36.73 152.69,36.5 ; 3 cut-outs
GND on TOP: 130.66,92.43 130.33,92.89 129.62,94.13 129.7,94.52 130.74,95.56 133.33,96.65 135.41,97.56 135.9,98.07 136.28,99.52 136.28,99.87 136.38,100.05 136.63,100.13 136.76,100.05 136.84,99.85 137.07,99.7 137.78,99.72 138.18,100.05 138.13,100.48 138.08,101.09 138.13,101.55 140.19,102.39 142.22,102.44 143.34,100.31 143.7,98.73 143.57,98.05 142.6,97.59 138.08,96.37 136.91,96.34 135.64,96.32 131.33,94.64 130.46,94.46 130.41,94.26 130.41,94.01 131.02,93.12 131.2,92.69 131.17,92.61 130.77,92.43
GND on TOP: 152.69,158.78 152.2,159.26 152.2,163.73 152.28,163.81 153.27,163.81 153.35,163.73 153.35,160.5 154.52,159.34 155.51,159.34 155.58,159.26 155.58,158.85 155.51,158.78 ; 2 cut-outs
GND on TOP: 169.68,147.22 169.6,147.3 169.6,149.18 169.43,149.35 169.43,150.12 169.5,150.19 170.54,150.19 170.72,150.37 170.72,150.62 171.18,151.08 172.27,151.08 172.65,150.7 174.58,150.7 174.73,150.55 174.73,148.97 174.63,148.87 172.55,148.87 172.3,149.13 172.3,149.89 172.24,149.94 171.48,149.94 171.43,149.89 171.43,149.38 170.85,148.8 170.85,147.35 170.72,147.22 ; 1 cut-out
GND on TOP: 158.94,158.02 158.81,158.14 158.81,159.03 158.99,159.21 166.89,159.21 167.19,159.51 167.19,160.33 167.42,160.56 169.81,160.56 169.83,160.53 169.83,158.75 169.1,158.02
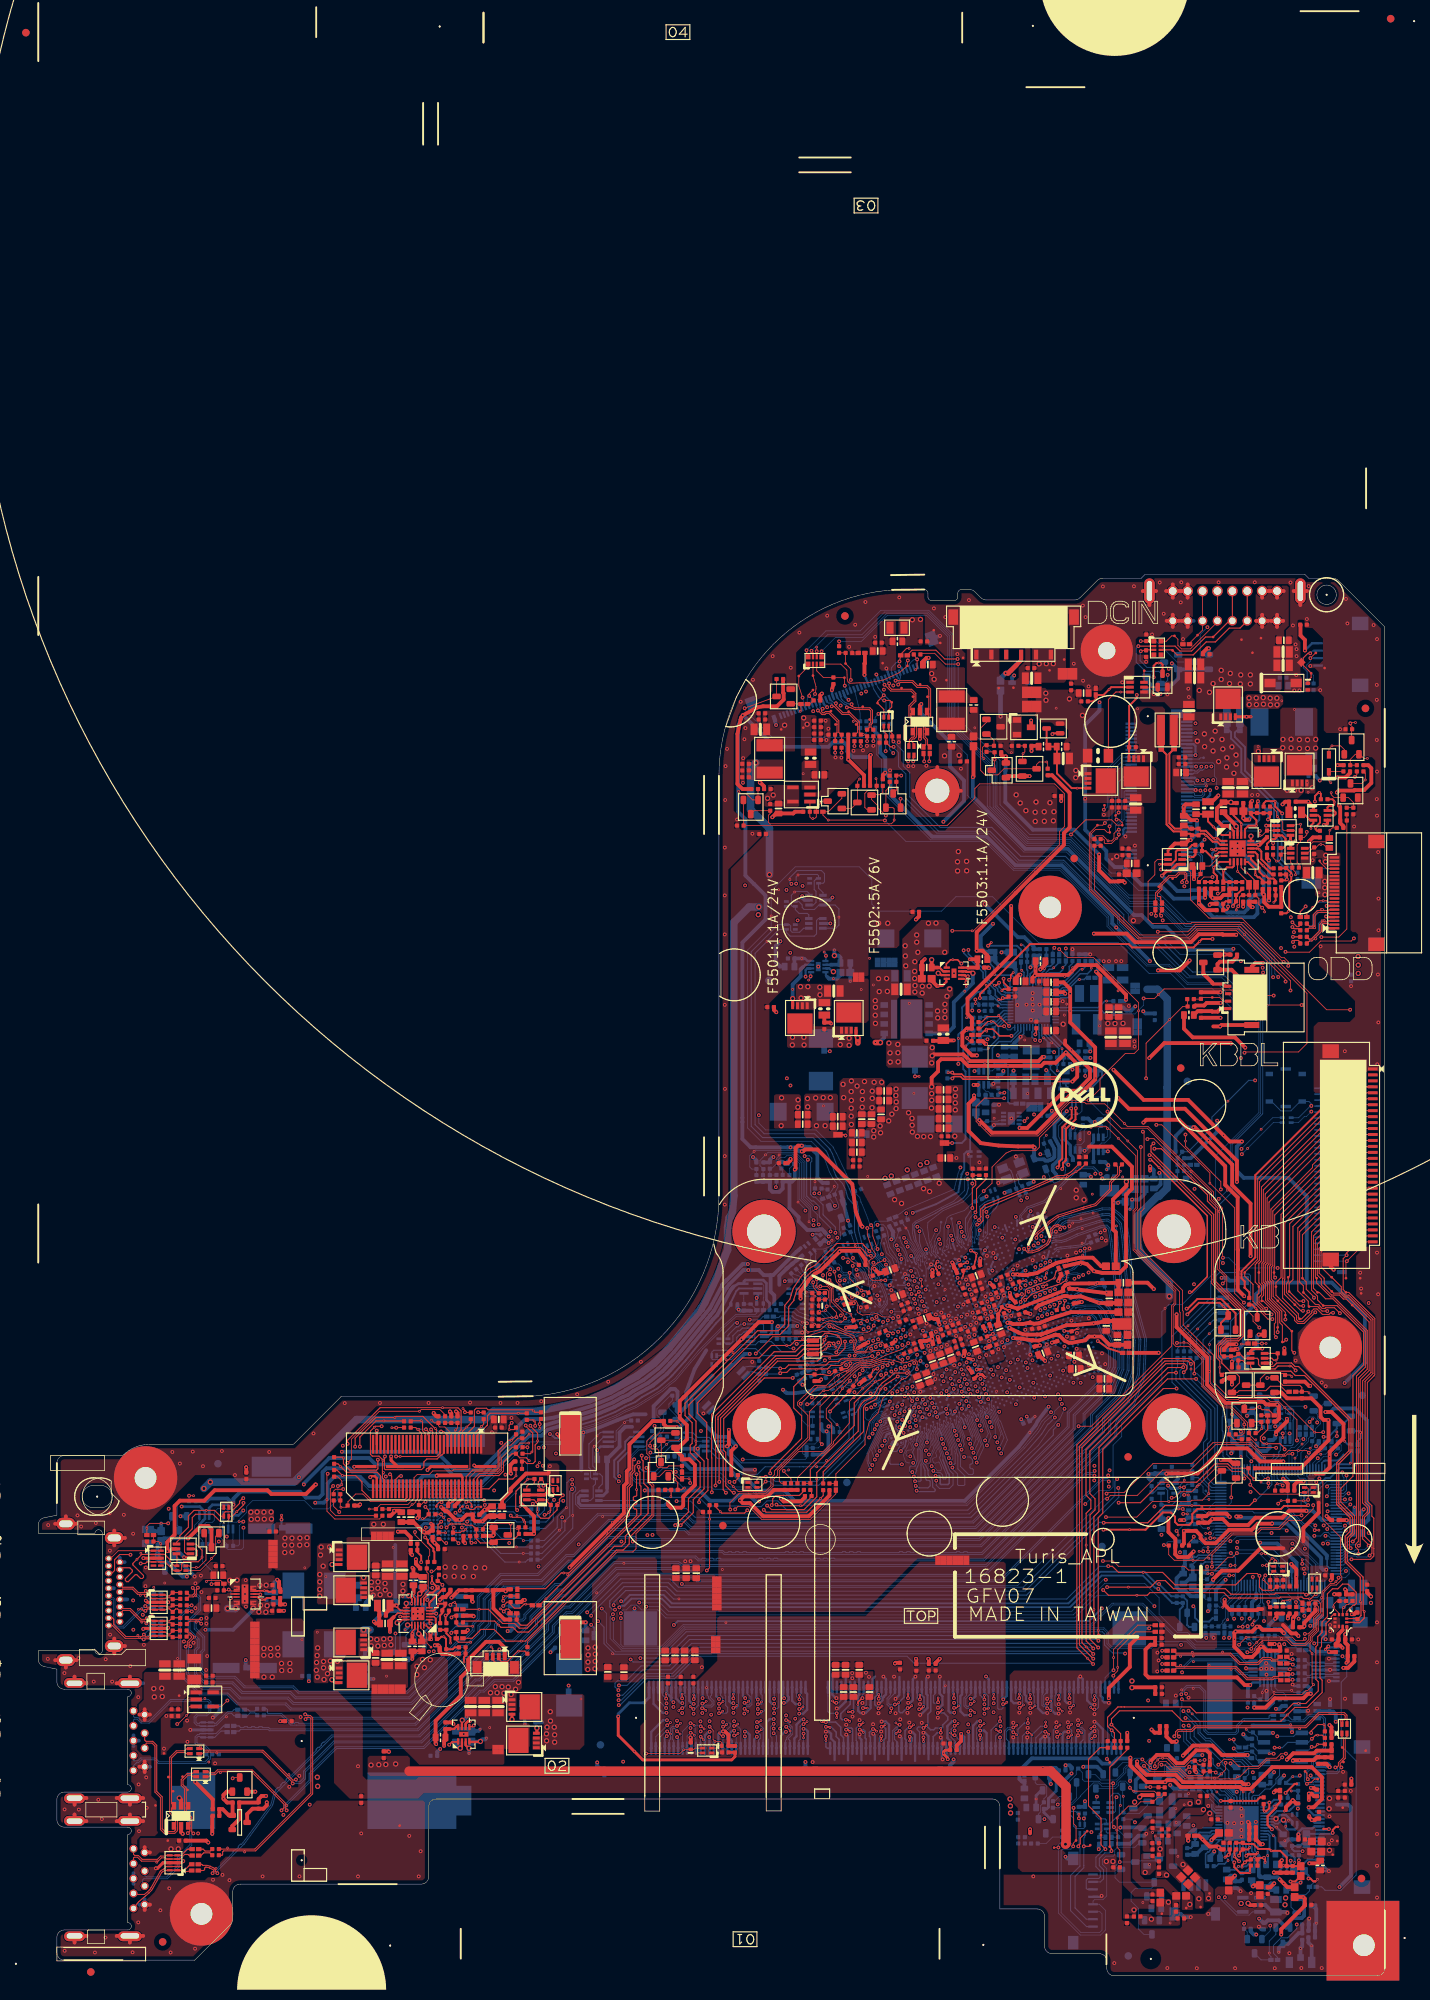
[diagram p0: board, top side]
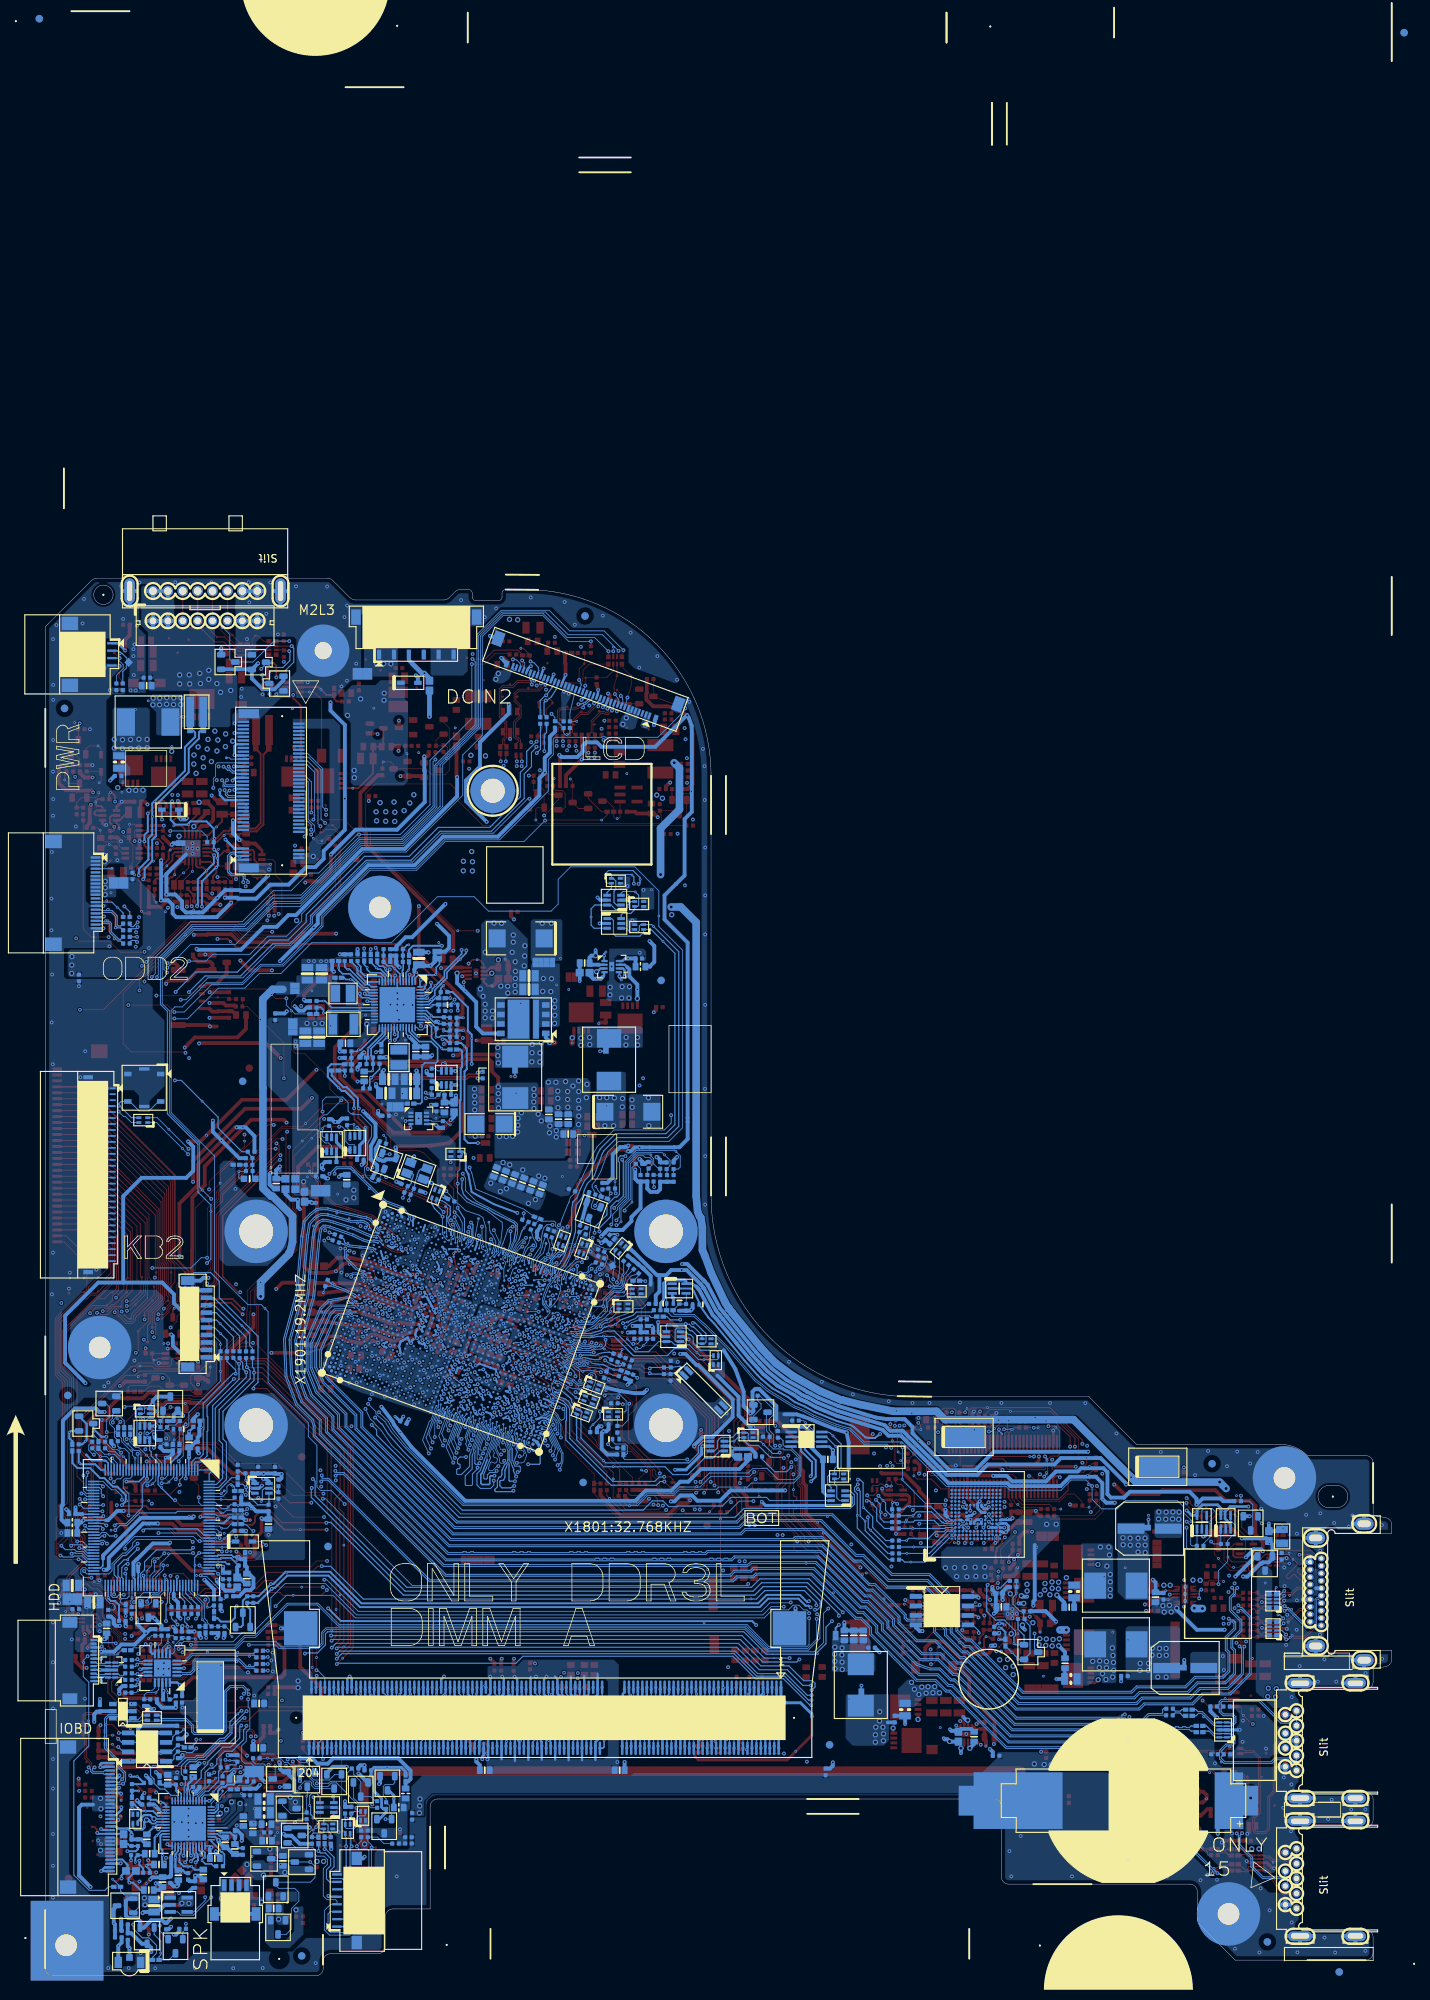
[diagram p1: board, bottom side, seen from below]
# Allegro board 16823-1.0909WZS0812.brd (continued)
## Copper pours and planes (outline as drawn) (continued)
GND on TOP: 64.62,72.72 64.55,72.8 64.55,73.69 63.66,74.58 63,74.58 62.92,74.5 62.92,73.41 62.69,73.18 62.11,73.18 61.86,73.43 61.86,75.01 62.11,75.26 64.07,75.26 65.03,74.3 65.03,73.61 65.29,73.36 65.29,72.77 65.23,72.72 ; 1 cut-out
GND on TOP: 132.32,86.41 132.14,86.49 132.11,86.84 132.16,86.95 132.98,87.05 133.41,87.17 134.02,87.17 135.92,87.78 138.01,88.34 141.18,88.57 141.33,88.37 141.33,88.01 141.21,87.89 138.82,87.63 138.31,87.66 137.57,87.63 134.3,86.57 133.69,86.54 133.08,86.44
GND on TOP: 43.26,50.65 43.16,50.75 43.16,52.22 43.21,52.28 44.2,52.28 44.32,52.39 44.32,54.02 44.46,54.15 49.41,54.15 49.56,54 49.56,51.56 48.65,50.65 ; 2 cut-outs
GND on TOP: 127.13,87.84 127.06,87.96 126.73,88.78 126.52,88.88 126.09,88.7 125.94,88.72 125.84,88.95 125.05,91.11 124.75,91.92 124.49,92.05 124.11,91.92 123.91,91.95 123.76,92.36 123.32,92.86 123.43,93.25 124.16,93.88 124.67,94.06 125.23,94.29 125.51,94.29 125.66,93.96 125.84,93.45 125.79,93.17 125.79,92.99 126.22,91.82 126.14,91.44 125.92,90.63 126.12,90.12 126.3,89.74 126.42,89.66 126.88,89.82 127.11,89.82 127.19,89.69 127.64,88.22 127.64,87.96 127.39,87.86 ; 2 cut-outs
GND on TOP: 130.46,31.19 130.36,31.29 130.36,40.36 130.97,40.97 141.99,40.97 142.83,41.81 142.83,45.42 145.68,48.26 152.53,48.26 154.79,46 158.05,46 158.2,45.85 158.2,44.12 157.87,43.79 153.02,43.79 152.69,44.12 150.71,44.12 150.38,43.79 150.38,42.62 150.58,42.42 150.58,42.14 150.4,41.96 150.4,40.69 150.27,40.57 149.54,40.57 149.44,40.67 149.44,43.77 149.61,43.94 150.17,43.94 150.43,44.2 150.43,47.42 150.3,47.55 147.45,47.55 143.72,43.82 143.72,40.11 142.69,39.08 142.69,37.15 142.96,36.88 143.97,36.88 144.03,36.83 144.03,36.43 143.09,35.49 143.09,33.12 143.82,32.39 143.82,31.24 143.77,31.19 ; 5 cut-outs
GND on TOP: 147.05,148.72 146.97,148.8 146.97,150.5 146.54,150.93 145.22,150.93 145.07,151.08 145.07,152.48 146.08,153.49 146.08,156.09 145.7,156.47 144.76,156.47 143.77,155.48 142.76,155.48 142.65,155.58 142.65,156.03 142.73,156.11 143.31,156.11 143.64,156.44 143.64,156.95 143.77,157.08 148.11,157.08 148.42,156.77 148.42,150.24 147.91,149.74 147.91,148.77 147.86,148.72 ; 3 cut-outs
GND on TOP: 158.76,17.55 158.76,18.14 158.78,18.16 159.09,18.16 159.37,18.44 159.37,20.22 158.94,20.65 158.1,20.65 158,20.75 158,21.8 157.28,22.51 156.93,22.51 156.55,22.89 156.55,24.39 156.65,24.49 157.69,24.49 157.84,24.34 157.84,23.22 158.17,22.89 161.37,22.89 161.91,22.35 161.91,18.42 161.88,18.39 160.48,18.39 160.18,18.09 160.18,17.63 160.1,17.55 ; 7 cut-outs
GND on TOP: 106.66,38.25 106.43,38.48 106.43,40.82 106.48,40.87 112,40.87 112.07,40.79 112.07,38.53 111.79,38.25 ; 8 cut-outs
GND on TOP: 143.42,78.06 143.21,78.28 143.19,78.89 143.19,80.55 142.81,81.21 141.03,81.16 140.27,80.88 139.45,80.9 139.33,81.03 139.35,81.76 139.15,82.04 138.89,82.15 138.79,82.4 138.79,82.55 138.94,82.69 139.03,83.79 139.1,84.3 139.28,84.41 142.96,83.8 144.76,82.53 144.69,78.64 144.48,78.06 ; 6 cut-outs
GND on TOP: 75.9,39.37 75.85,39.42 75.85,40.46 75.98,40.59 81.36,40.59 83.57,42.8 88.93,42.8 89.31,42.42 89.31,40.9 88.25,39.83 80.91,39.83 80.45,39.37 ; 14 cut-outs
GND on TOP: outline of 143 points within 0.51,0.51 180.19,187.49 ; 47 cut-outs
GND on TOP: 108.59,108.18 108.47,108.31 108.47,113.34 108.36,113.44 107.58,113.44 107.53,113.49 107.53,119.97 108.01,120.45 113.24,120.45 113.65,120.04 113.65,115.9 113.57,115.83 112.48,115.83 112.38,115.72 112.38,115.24 112.3,115.17 109.79,115.17 109.68,115.06 109.68,108.26 109.61,108.18 ; 14 cut-outs
GND on TOP: 94.47,159.82 94.27,160.02 94.27,165.94 94.67,168.63 95.69,169.65 96.93,169.65 96.96,169.62 96.96,166.88 95.64,165.56 95.64,163.98 94.83,163.17 94.83,159.97 94.67,159.82 ; 2 cut-outs
GND on TOP: 83.85,54.08 83.55,54.38 83.55,58.68 82.94,59.29 82.94,65.46 82.99,65.51 83.5,65.51 83.57,65.43 83.57,60.96 84.79,59.74 87.26,59.74 88.32,60.81 88.32,62.31 88.58,62.56 89.47,62.56 89.52,62.51 89.52,54.59 89.01,54.08 ; 5 cut-outs
GND on TOP: 28.25,59.29 28.13,59.41 28.13,62.38 28.38,62.64 31.38,62.64 31.63,62.38 31.63,60.78 31.33,60.48 31.33,59.34 31.27,59.29 ; 1 cut-out
GND on TOP: 148.34,16.66 148.22,16.79 148.22,19.1 149.23,20.12 151.04,20.12 151.09,20.07 151.09,19.38 151.04,19.33 149.66,19.33 149.54,19.2 149.54,18.29 149.82,18.01 149.82,16.77 149.71,16.66 ; 3 cut-outs
GND on TOP: 116.9,83.42 116.77,83.52 116.62,83.9 116.64,84.13 116.92,84.28 117.2,84.48 117.25,84.71 116.8,85.93 116.72,86.67 117.28,87.23 117.79,87.4 117.91,87.25 118.27,86.41 118.47,86.26 118.85,86.21 119.08,86.29 119.21,86.21 119.36,85.78 119.36,85.7 118.88,85.52 118.7,85.6 118.27,85.57 117.76,85.4 117.74,85.22 117.84,84.91 118.17,83.95 118.14,83.87 ; 2 cut-outs
GND on TOP: 134.73,126.21 134.65,126.29 134.65,127.59 134.5,127.74 130.33,127.74 130.11,127.97 130.11,130.81 130.16,130.86 130.61,130.86 130.72,130.96 130.72,132.49 130.89,132.67 131.81,132.67 132.04,132.89 132.04,133.91 132.16,134.04 132.8,134.04 132.9,133.94 132.9,132.89 133,132.79 133.92,132.79 134.02,132.89 134.02,133.81 134.12,133.91 135.64,133.91 135.74,133.81 135.74,126.27 135.69,126.21 ; 9 cut-outs
GND on TOP: 143.19,129.47 143.11,129.54 143.11,130.46 143.19,130.53 146.57,130.53 146.64,130.46 146.64,129.64 146.46,129.47
GND on TOP: 50.12,47.7 50.05,47.78 50.05,49.46 50.07,49.48 51.77,49.48 51.82,49.43 51.82,47.75 51.77,47.7
GND on TOP: 128.12,113.92 127.9,114.15 127.9,116.99 128.12,117.22 130.36,117.22 130.46,117.32 130.46,118.59 130.03,119.03 127.92,119.03 127.79,119.15 127.79,119.84 127.87,119.92 136.15,119.92 136.46,119.61 136.46,118.09 135.24,116.87 133.15,116.87 130.21,113.92
GND on TOP: 127.84,82 127.51,82.1 127.45,82.24 126.95,83.52 127.02,83.67 128.98,84.38 129.23,84.26 129.72,82.91 129.59,82.64 ; 2 cut-outs
GND on TOP: 63.13,35.54 62.97,35.69 62.97,36.3 62.87,36.4 57.31,36.4 57.23,36.48 57.23,39.78 58.2,40.74 58.2,42.34 59.32,43.46 60.36,43.46 60.48,43.33 60.48,42.01 60.61,41.89 62.97,41.89 63.35,42.27 64.7,42.27 64.9,42.06 64.9,38.61 64.19,37.9 64.19,35.61 64.12,35.54
GND on TOP: 98.84,113.69 98.74,113.79 98.74,118.06 98.97,118.29 102.12,118.29 102.37,118.04 102.37,113.84 102.22,113.69 ; 2 cut-outs
GND on TOP: 89.09,75.29 88.7,75.67 88.7,76.53 88.6,76.86 88.78,77.17 94.17,82.37 94.42,82.62 95.56,82.73 96.02,82.7 96.35,82.37 96.4,81.89 95.8,81.32 95.71,81.18 89.98,75.59 89.68,75.29
GND on TOP: 125.15,107.98 124.98,108.16 124.98,108.79 124.62,109.15 122.03,109.15 121.9,109.27 121.9,110.54 122,110.64 122.97,110.64 123.1,110.77 123.1,111.97 122.71,112.35 121.83,112.35 121.72,112.45 121.72,119.38 121.88,119.53 124.01,119.53 124.06,119.48 124.06,113.16 127.52,109.7 127.52,108.1 127.39,107.98 ; 8 cut-outs
GND on TOP: 101.28,85.96 101.1,86.13 101.1,89 102.75,90.65 102.75,91.75 102.93,91.92 104.12,91.92 104.2,91.85 104.2,87.02 104.07,86.9 103.61,86.9 103.54,86.97 103.54,87.4 103.49,87.45 102.88,87.45 102.7,87.28 102.7,86.72 102.85,86.57 102.85,86.11 102.7,85.96 ; 4 cut-outs
GND on TOP: 151.95,170.06 151.11,170.89 148.14,170.89 147.84,171.2 147.84,172.44 147.91,172.52 149.56,172.52 150.48,171.6 150.98,171.6 151.14,171.76 151.14,173.43 151.37,173.66 152.36,173.66 152.84,174.14 152.84,176.76 152.97,176.89 154.79,176.89 154.87,176.81 154.87,171.55 155.23,171.2 155.23,170.13 155.15,170.06
GND on TOP: 43.09,42.85 42.98,42.95 42.98,45.26 43.01,45.29 44.28,45.29 44.53,45.54 49.31,45.54 49.56,45.29 49.56,43.16 49.26,42.85 ; 2 cut-outs
GND on TOP: 101.71,129.62 101.66,129.67 101.66,132.97 101.79,133.1 106.36,133.1 106.46,133 106.46,130.2 106.26,130 104.5,130 104.12,129.62
GND on TOP: 117.76,155.48 117.08,156.16 117.08,161.24 116.52,161.8 114.66,161.8 114.59,161.72 114.59,160.81 114.51,160.73 113.98,160.73 113.93,160.78 113.93,161.9 113.75,162.08 111.31,162.08 108.68,159.45 107.21,159.45 105.95,158.19 102.8,158.19 102.72,158.27 102.72,158.73 102.78,158.78 104.68,158.78 105.06,159.16 105.06,164.9 104.68,165.28 104.68,168.66 104.78,168.76 106.15,168.76 106.33,168.58 106.33,163.93 106.53,163.73 107.93,163.73 108.03,163.63 108.03,162.79 108.24,162.59 108.87,162.59 109.13,162.84 109.13,164.59 109.2,164.67 110.73,164.67 110.88,164.82 110.88,165.13 111.06,165.31 112.33,165.31 112.61,165.58 112.61,166.58 112.63,166.6 113.11,166.6 113.19,166.52 113.19,165.25 112.81,164.87 112.81,163.53 112.99,163.35 114.79,163.35 115.17,163.73 115.17,166.55 115.22,166.6 115.73,166.6 115.78,166.55 115.78,162.99 116.19,162.59 119.41,162.59 119.67,162.33 123.91,162.33 124.29,162.71 124.29,163.2 124.37,163.27 124.85,163.27 124.92,163.2 124.92,158.07 122.33,155.48 ; 8 cut-outs
GND on TOP: 167.67,51.97 167.55,52.1 167.55,52.61 167.37,52.78 165.95,52.78 165.84,52.88 165.84,53.75 165.89,53.8 166.86,53.8 167.01,53.95 167.77,53.95 167.93,53.8 167.93,52.86 168.26,52.53 168.26,52.02 168.21,51.97 ; 2 cut-outs
GND on TOP: 123.91,84.3 123.76,84.43 123.35,85.55 122.99,85.63 122.28,85.83 122.03,85.96 121.55,87.15 121.55,87.25 122.05,87.4 122.13,87.35 122.26,87.07 122.46,86.77 122.66,86.77 123.53,87.02 123.91,87.2 124.49,87.35 124.77,87.07 125.1,86.36 125.33,85.65 125.56,85.5 126.3,85.8 126.63,85.83 126.73,85.7 126.8,85.52 126.93,85.47 127.34,85.37 127.92,85.68 128.35,85.85 128.48,85.85 128.63,85.42 128.63,85.32 127.95,85.02 127.13,84.76 126.96,84.79 126.17,84.81 125.2,84.48 124.39,84.46 ; 8 cut-outs
GND on TOP: 27.69,49.28 27.26,49.71 27.26,53.24 27.41,53.39 28.02,53.39 28.2,53.22 28.2,49.43 28.05,49.28
GND on TOP: 115.86,78.36 115.65,78.46 115.52,78.83 115.87,79.59 116.88,79.96 117.24,80.72 119.57,81.57 119.6,81.64 119.57,82.04 119.56,82.04 119.62,82.15 119.99,82.35 122.99,83.44 123.2,83.75 123.58,83.87 123.68,83.85 123.81,83.57 123.83,83.34 123.72,82.77 123.6,82.52 119.78,81.13 119.55,80.62 117.72,79.96 117.6,79.68 116.31,79.22 116.16,78.89 116.19,78.83 115.99,78.41 ; 3 cut-outs
GND on TOP: 129.12,105.79 128.76,105.87 128.56,106.33 128.38,108.59 128.58,108.84 131.02,110.16 132.14,110.39 132.44,110.06 133.13,107.67 133.13,107.29 129.57,105.95
GND on TOP: 143.01,135.71 141.92,136.81 138.54,136.81 138.44,136.91 138.44,138.05 138.59,138.2 145.63,138.2 146.21,137.62 146.21,135.92 146.01,135.71
GND on TOP: 173.18,44.86 173.11,44.93 173.11,47.17 173.74,47.8 173.74,48.08 173.77,48.11 174.56,48.11 174.71,47.96 174.71,46.53 173.97,45.8 173.97,44.99 173.84,44.86
GND on TOP: 138.49,85.27 137.9,85.5 137.75,85.68 137.88,86.01 138.16,86.03 138.49,85.93 138.82,85.93 139.05,85.98 139.12,86.16 139.17,86.41 139.58,86.82 142.68,86.97 143.8,86.97 143.9,86.84 144.05,86.64 144.33,86.57 144.89,86.49 145.32,86.49 145.4,86.39 145.37,85.57 145.27,85.52 144.13,85.55 143.62,85.9 142.81,86.13 140.7,86.11 140.14,85.65 139,85.3 ; 1 cut-out
GND on TOP: 110.24,84.97 110.14,85.04 109.99,85.4 109.99,85.93 110.34,86.13 111.18,86.24 112.1,86.44 112.83,87.2 114.23,87.63 114.46,87.86 114.43,88.29 114.31,88.5 113.98,88.55 112.55,88.14 112.25,88.22 111.16,88.57 110.17,89.28 110.07,89.64 110.14,89.89 110.4,90.02 110.75,90.02 111.08,90.1 111.39,90.35 111.36,90.73 111.36,91.01 112,91.29 112.06,91.42 111.69,92.36 111.13,92.51 109.94,92.97 109.48,93.7 109.53,94.24 109.91,94.36 110.73,94.54 111.08,94.44 111.56,93.35 111.79,93.14 112.93,93.13 113.42,92.94 113.9,92.23 114.08,92.15 114.41,92.25 114.74,92.18 115.17,91.39 115.37,90.86 115.83,90.4 115.93,90.38 116.03,90.32 116.11,90.2 116.42,89.38 116.49,89.13 116.47,89.03 116.21,88.85 115.78,88.42 115.81,88.14 115.96,87.73 115.98,87.43 115.78,87.07 114.61,86.57 114.26,86.59 113.98,87 113.85,87.02 113.16,86.74 113.11,86.57 113.24,86.24 113.24,86.01 112.71,85.78 111.21,85.4 110.55,85.04 ; 10 cut-outs
GND on TOP: 172.63,78.79 169.31,82.11 168.57,82.11 168.41,82.27 168.41,83.03 168.59,83.21 168.92,83.21 169.02,83.31 169.02,86.26 171.08,88.32 175.47,88.32 177.55,86.24 177.55,82.32 176.18,80.95 176.18,79.12 175.85,78.79
GND on TOP: 33.56,23.5 28.86,28.2 23.38,28.2 23.25,28.32 23.25,29.14 23.32,29.21 30.08,29.21 34.02,25.28 34.78,25.28 34.91,25.4 34.91,26.55 30.63,30.82 22.35,30.82 22,31.17 18.3,31.17 17.2,30.08 17.2,29.69 17.13,29.62 16.54,29.62 16.44,29.72 16.44,34.5 17.15,35.21 19.16,35.21 19.49,35.54 19.49,36.88 20,37.39 21.93,37.39 22,37.31 22,36.86 21.95,36.81 20.2,36.81 20.02,36.63 20.02,35.38 19.11,34.47 17.91,34.47 17.74,34.29 17.74,33.4 17.89,33.25 19.21,33.25 19.44,33.48 19.44,34.09 20.78,35.44 26.93,35.44 27.34,35.03 35.29,35.03 35.47,34.85 35.47,34.11 35.87,33.71 35.87,24.31 35.06,23.5 ; 2 cut-outs
GND on TOP: 127.9,90.43 127.82,90.45 127.62,90.88 127.64,90.96 127.82,91.06 128.18,91.24 128.23,91.32 128.18,91.62 128.18,91.8 128.25,91.85 128.66,92 128.79,91.92 129.09,91.09 129.09,91.01 129.01,90.83
GND on TOP: 118.9,126.44 118.8,126.54 118.8,130.56 117.86,131.5 116.14,131.5 115.96,131.68 115.96,139.14 118.47,141.66 121.6,141.66 122.21,141.05 122.21,137.24 121.93,136.96 118.96,136.96 118.02,136.02 118.02,133.25 118.17,133.1 119.74,133.1 120.43,132.41 121.65,132.41 122.03,132.79 122.54,132.79 122.79,132.54 122.79,131.55 122.21,130.96 122.21,126.67 121.98,126.44
GND on TOP: 14.1,52.02 13.98,52.15 13.98,52.81 14.54,53.37 14.54,53.75 14.03,54.26 14.03,54.87 14.21,55.04 14.71,55.04 14.82,54.94 14.82,54.61 15.02,54.41 17.1,54.41 18.37,53.14 20.28,53.14 22.66,55.53 23.96,55.53 24.14,55.35 24.14,53.37 24.01,53.24 22.13,53.24 21.27,52.38 15.2,52.38 14.84,52.02 ; 3 cut-outs
GND on TOP, BOTTOM: 143.24,124.21 143.11,124.34 143.11,125.73 143.16,125.78 147.35,125.78 147.45,125.68 147.45,124.36 147.3,124.21
GND on BOTTOM: 162.69,26.24 162.64,26.29 162.64,27.46 162.75,27.56 164.62,27.56 164.8,27.38 164.8,26.65 164.73,26.57 163.76,26.57 163.43,26.24 ; 1 cut-out
GND on BOTTOM: 146.06,55.78 145.85,55.98 145.85,73.94 146.54,74.63 146.54,74.65 150.05,78.16 153.83,78.16 156.14,75.85 156.14,69.17 155.2,68.23 154.41,68.23 154.16,67.97 148.67,67.97 148.42,67.72 148.42,64.7 148.78,64.34 149.77,64.34 150.07,64.04 150.07,62.82 149.97,62.71 149.97,60.61 150.17,60.4 151.19,60.4 151.32,60.28 151.32,58.98 150.68,58.35 150.68,57.25 150.96,56.97 152.71,56.97 152.86,57.13 154.11,57.13 154.21,57.03 154.21,56.54 154.16,56.49 153.14,56.49 152.43,55.78 ; 9 cut-outs
GND on BOTTOM: 106.46,91.72 106.09,92.09 106.09,92.65 106.09,92.65 106.09,93.78 105.32,94.34 104.88,94.62 104.45,95.91 104.5,95.99 104.76,95.99 105.21,95.66 105.32,95.48 105.54,94.77 106.41,94.29 106.69,94.16 106.94,93.93 107.04,93.6 107.14,93.22 107.27,92.99 107.61,92.85 107.7,92.76 108.03,92.1 107.98,91.95 107.35,91.8 106.61,91.72
GND on BOTTOM: 128.63,90.27 128.33,90.35 128.28,90.55 128.43,90.83 128.51,90.91 128.63,91.11 128.74,91.36 129.5,92.64 130.08,93.14 130.26,93.58 130.39,93.7 130.59,93.7 130.72,93.6 130.82,93.42 130.97,93.37 136.84,95.4 137.35,95.66 137.54,96.34 137.27,96.83 136.79,97 136.71,97.13 136.75,97.26 136.82,97.33 138.25,97.33 138.37,97.21 138.44,96.65 138.31,95.91 137.93,95.35 137.5,95.15 130.46,92.66 130.23,92.59 129.95,92.53 129.78,92.41 129.32,91.47 128.79,90.35
GND on BOTTOM: 28.35,58.75 28.13,58.98 28.13,62.38 28.33,62.59 31.63,62.59 31.83,62.38 31.83,59.01 31.58,58.75
GND on BOTTOM: 112.86,82.25 112.68,82.65 112.73,82.78 117.53,84.53 118.07,84.74 118.12,84.84 118.04,85.07 117.2,85.63 116.82,85.83 116.75,85.98 116.85,86.31 117.15,86.79 117.96,87 118.35,86.97 118.42,86.87 118.37,86.67 118.3,86.51 118.12,86.26 118.17,85.98 118.37,85.45 118.65,84.81 118.78,84.53 119.36,84.18 119.41,84.05 119.34,83.9 119.13,83.87 118.45,84.25 118.17,84.23 117.23,83.82 116.42,83.59 116.03,83.59 115.86,83.42 115.58,83.29 114.76,82.91 113.19,82.3
GND on BOTTOM: 110.85,168 110.8,168.05 110.8,169.93 110.78,170.49 110.16,171.7 109.96,172.32 109.66,173.15 109.66,173.23 110.32,173.48 110.73,173.64 110.88,173.66 110.9,173.61 111.04,173.24 111.34,172.44 111.37,172.37 111.37,172.37 111.54,171.99 111.44,170.83 111.44,168.07 111.36,168
GND on BOTTOM: 22.42,40.58 22.2,40.79 22.2,43.16 22.51,43.46 26.75,43.46 27.06,43.16 27.06,40.87 26.77,40.58
GND on BOTTOM: 130.03,85.02 129.83,85.17 129.82,85.25 129.88,85.4 129.88,85.73 129.76,85.82 129.6,85.98 129.22,86.06 129.17,86.13 128.43,88.29 128.43,88.37 128.45,88.43 128.63,88.47 128.86,88.55 128.99,88.47 129.14,88.09 129.94,86.15 130.44,85.93 130.49,85.88 130.49,85.7 130.31,85.17 130.21,85.07
GND on BOTTOM: 150.48,148.03 150.3,148.21 150.3,149.25 150.38,149.33 153.3,149.33 153.35,149.38 153.35,149.91 153.37,149.94 155.4,149.94 155.56,149.79 155.56,148.16 155.43,148.03
GND on BOTTOM: 150.86,95.25 148.32,97.79 148.32,101.78 151.01,104.47 153.42,104.47 155.15,106.2 155.15,109.12 155.38,109.35 156.78,109.35 157.31,108.82 157.31,96.14 156.42,95.25 ; 1 cut-out
GND on BOTTOM: 64.12,36.04 62.67,37.49 60.48,37.49 60.33,37.64 60.33,38.28 61.25,39.19 63.74,39.19 64.29,39.75 64.98,39.75 66.28,38.46 66.28,36.2 66.12,36.04
GND on BOTTOM: outline of 412 points within 108.75,75.34 143.44,98.91
GND on BOTTOM: 121.83,112.35 121.72,112.45 121.72,119.38 121.88,119.53 124.01,119.53 124.06,119.48 124.06,112.57 123.83,112.35
GND on BOTTOM: 113.42,80.01 113.27,80.09 112.86,80.34 112.83,81.13 113.06,81.28 113.85,81.54 115.07,81.99 115.42,82.2 116.24,82.35 116.42,82.5 116.62,82.5 117.18,82.15 117.23,81.94 117.1,81.31 116.97,81.23 116.64,81.26 116.59,81.38 116.69,81.69 116.67,81.87 116.62,81.96 116.49,82.06 116.01,81.99 115.93,81.94 115.73,81.92 115.4,81.76 115.35,81.74 115.3,81.64 115.32,81.49 115.35,81.38 115.32,81.23 115.22,81.1 115.04,81.08 114.87,81.16 114.64,81.38 114.43,81.41 113.85,81.18 113.37,81.03 113.32,80.93 113.39,80.75 113.7,80.27 113.67,80.11 113.52,80.04
GND on BOTTOM: 50.81,47.68 50.71,47.78 50.71,48.29 50.65,48.34 50.1,48.34 50.02,48.41 50.02,48.72 51.37,50.07 52.05,50.07 52.13,49.99 52.13,48.29 51.52,47.68 ; 1 cut-out
GND on BOTTOM: outline of 84 points within 113.37,77.27 123.78,82.17
GND on BOTTOM: 56.24,68.3 53.68,70.87 44.53,70.87 44.46,70.94 44.46,73.51 44.84,73.89 60.21,73.89 61.37,75.06 63.84,75.06 63.94,74.96 63.94,73.13 59.11,68.3
GND on BOTTOM: outline of 125 points within 0.51,0.51 180.19,187.49 ; 19 cut-outs
GND on BOTTOM: 163.89,40.13 163.81,40.21 163.81,42.39 163.86,42.45 166.1,42.45 166.12,42.42 166.12,40.18 166.07,40.13
GND on BOTTOM: 98.28,113.69 98.13,113.84 98.13,118.16 98.25,118.29 102.12,118.29 102.37,118.04 102.37,113.84 102.22,113.69
GND on BOTTOM: 119.06,127.31 119.01,127.36 119.01,130.96 118.47,131.5 116.14,131.5 115.96,131.68 115.96,139.14 118.5,141.68 121.6,141.68 122.21,141.07 122.21,133.15 122.82,132.54 122.82,131.6 122.21,130.99 122.21,127.38 122.13,127.31
GND on BOTTOM: 163.28,71 163.23,71.05 163.23,73.64 163.3,73.71 163.71,73.71 163.79,73.64 163.79,73.18 163.99,72.98 164.6,72.98 164.73,72.85 164.73,71.07 164.65,71 ; 1 cut-out
GND on BOTTOM: outline of 85 points within 127.64,94.52 136.84,103
GND on BOTTOM: 111.49,104.55 110.46,104.69 110.28,104.9 110.13,105.41 109.23,106.78 107.54,110.83 107.53,110.85 107.53,119.97 108.01,120.45 113.24,120.45 113.65,120.04 113.65,115.88 113.57,115.8 112.5,115.8 112.38,115.67 112.38,115.29 112.28,115.19 109.79,115.19 109.63,115.04 109.63,114.07 110.32,113.39 110.32,109.86 110.83,109.35 120.3,109.35 120.71,108.52 120.71,108.28 113.6,105.41 ; 11 cut-outs
GND on BOTTOM: 142.7,134.72 142.6,134.83 142.6,136.4 142.65,136.45 146.24,136.45 146.34,136.35 146.34,134.77 146.29,134.72
GND on BOTTOM: 107.75,88.32 107.4,88.52 107.3,88.78 107.32,89.84 107.58,90.2 107.96,90.38 108.08,90.3 108.26,90.17 108.72,90.22 109.15,90.25 109.43,90.68 109.53,90.88 109.71,90.96 109.86,90.91 110.27,90.73 110.62,90.83 110.68,90.98 110.6,91.09 110.5,91.19 110.47,91.42 110.5,91.54 110.73,91.62 111.23,91.52 111.59,91.26 112.02,89.77 112.07,89.56 112.02,89.49 111.54,89.36 111.21,89.51 110.83,89.54 110.45,89.38 109.94,89.16 109,88.83 108.08,88.52
GND on BOTTOM: 151.14,17.55 150.98,17.71 150.98,19.51 151.04,19.56 153.32,19.56 153.58,19.81 153.58,20.42 153.65,20.5 155.05,20.5 155.28,20.27 155.28,20.02 155.18,19.92 154.74,19.92 153.86,19.03 153.86,18.67 152.74,17.55 ; 1 cut-out
GND on BOTTOM: 119.97,84.15 119.84,84.18 119.77,84.3 119.82,84.48 120.1,84.76 120.68,85.02 120.76,85.17 120.71,85.45 120.5,85.57 120.43,85.75 120.53,85.93 120.78,86.01 121.27,85.98 121.42,86.13 121.44,86.34 121.37,86.44 120.73,86.69 119.59,87.17 119.54,87.33 119.57,87.56 119.51,87.76 119.39,87.84 119.31,87.91 119.29,88.06 119.34,88.17 119.57,88.19 119.72,88.04 119.92,87.71 119.97,87.43 120.25,87.35 120.58,87.33 120.66,87.38 120.71,87.53 120.91,87.63 121.11,87.58 121.19,87.33 121.19,87.07 121.37,86.9 121.83,86.69 121.9,86.54 122.18,85.93 122.46,85.83 122.56,85.83 122.74,85.85 122.97,86.01 123.15,86.11 123.27,86.08 123.4,85.96 123.43,85.73 123.04,85.22 122.16,84.94 122.05,84.99 121.88,84.97 121.72,84.91 121.65,84.79 121.55,84.71 121.39,84.69 121.09,84.69 120.91,84.53 120.76,84.43 120.61,84.43 120.48,84.46 120.33,84.41 120.17,84.3 120.05,84.18
GND on BOTTOM: 113.44,84.05 112.76,84.36 112.73,84.66 112.88,85.32 113.01,85.37 115.15,86.06 115.32,86.03 115.42,85.9 115.42,85.57 115.63,85.17 115.76,85.02 115.68,84.81 115.55,84.74 115.17,84.86 114.69,85.02 113.85,84.66 113.72,84.23 113.6,84.05
GND on BOTTOM: 95.21,70.06 92.77,72.49 91.47,72.49 88.83,75.14 88.83,76.94 89.62,77.73 90.08,77.73 90.84,76.96 92.56,76.96 95.79,80.19 100.06,80.19 100.24,80.37 100.24,82.02 100.06,82.2 96.48,82.2 96.35,82.07 95.77,82.07 95.59,82.25 95.59,82.53 95.89,82.83 96.83,82.83 96.98,82.98 102.04,82.98 102.19,82.88 102.62,81.58 102.6,81.54 102.51,81.44 102.19,81.33 101.38,81.33 101.02,80.98 101.02,80.26 101.73,79.28 102.04,79.22 105.08,80.28 105.68,80.55 105.82,80.6 105.9,80.57 106.05,80.14 106.08,79.99 106.05,79.91 105.95,79.73 105.57,79.56 102.37,78.46 100.81,78.83 100.26,79.07 99.65,78.97 99.52,78.69 99.52,78.46 99.73,78.18 100.22,77.89 100.72,77.4 101.63,76.66 101.79,76.25 101.79,73.59 102.17,73.2 104.17,73.2 104.22,73.15 104.22,72.67 103.97,72.42 103.97,71.73 103.89,71.66 102.7,71.66 102.42,71.38 101,71.38 99.68,70.06 ; 5 cut-outs
GND on BOTTOM: 102.01,130.79 101.96,130.84 101.96,133 102.22,133.25 103.84,133.25 104.33,133.73 104.33,136.5 103.87,136.96 101.1,136.96 100.92,136.78 100.92,136.27 100.85,136.2 100.13,136.2 100.06,136.27 100.06,137.44 100.44,137.82 104.93,137.82 105.04,137.72 105.04,133.61 105.34,133.3 105.34,131.04 105.09,130.79 ; 1 cut-out
GND on BOTTOM: 157,32.97 156.8,33.17 156.8,38.86 156.19,39.47 153.8,39.47 152.94,38.61 152.94,37.42 153.09,37.26 153.09,36.1 152.97,35.97 152.28,35.97 152.2,36.04 152.2,38.03 149.66,40.57 149.66,43.77 149.87,43.97 150.3,43.97 150.43,43.84 150.43,42.57 150.6,42.39 150.6,42.22 150.43,42.04 150.43,40.77 150.76,40.44 152.92,40.44 154.34,41.86 155.51,41.86 155.71,42.06 160.23,42.06 160.43,41.86 160.43,37.82 160.41,37.8 160.41,37.47 160.89,36.98 162.57,36.98 162.67,36.88 162.67,35.38 160.26,32.97 ; 1 cut-out
GND on L2VCC: outline of 122 points within 0.51,0.51 180.19,187.49 ; 3 cut-outs
GND on L3: 95.82,81.33 95.71,81.18 89.98,75.59 89.55,75.16 89.14,75.16 88.6,75.69 88.6,76.86 88.78,77.17 94.17,82.37 94.42,82.62 95.23,82.73 95.92,82.68 96.22,82.4 96.22,81.82
GND on L3: outline of 121 points within 0.51,0.51 180.19,187.49 ; 1 cut-out
GND on L3, L4: 128.61,108.84 131.05,110.16 132.16,110.39 132.47,110.06 133.15,107.67 133.15,107.29 129.6,105.95 129.14,105.79 128.79,105.87 128.58,106.33 128.4,108.59
GND on L4: 95.82,81.33 95.71,81.18 89.98,75.59 89.8,75.52 88.7,76.53 88.6,76.86 88.78,77.17 94.17,82.37 94.42,82.62 94.88,83.01 95.38,82.93 96.02,82.54 96.06,82.49 96.1,82.35 96.04,81.79
GND on L4: outline of 119 points within 0.51,0.51 180.19,187.49 ; 1 cut-out
GND on L5GND: outline of 120 points within 0.51,0.51 180.19,187.49 ; 1 cut-out
0D675V_VREF_S0 on BOTTOM: 145.25,29.65 145.15,29.75 145.15,31.75 144.49,32.41 144.49,37.14 144.79,37.44 144.79,40.63 145.3,41.14 148.52,41.14 152.08,37.58 152.08,30.21 151.52,29.65 ; 6 cut-outs
1D05V_IO_3PHASEIO on TOP: 128.45,89.03 128.22,89.13 127.88,90.08 127.96,90.24 129.07,90.64 129.24,91.01 128.75,92.29 128.71,92.89 128.91,93.14 128.89,93.52 128.76,93.8 128.78,93.92 129.32,94.13 129.47,94.05 129.75,92.92 129.74,92.01 129.92,91.51 129.86,91.37 130.05,90.83 129.84,90.37 128.69,89.95 128.63,89.81 128.8,89.34 128.69,89.11
1D05V_PCH on TOP: 127.85,87.96 127.62,88.46 127.4,89.4 127.21,89.91 126.71,90.15 126.4,90.04 126.24,90.11 126.06,90.62 126.49,91.54 125.91,93.13 126.08,93.49 125.8,94.27 125.8,94.28 125.81,94.62 126.79,95.01 126.88,95.15 126.85,96.37 126.85,96.37 126.4,96.93 126.17,98.25 126.3,99.24 127.36,101.32 127.41,101.36 127.75,101.82 128.1,102.9 128.53,103.23 131.48,104.62 133.07,105.1 137.49,106.8 137.5,106.81 139.15,106.96 139.91,105.95 140.9,104.19 140.78,103.65 140.06,103.39 136.88,102.36 135.5,101.78 134.96,101.29 134.25,99.9 131.54,98.25 131.06,97.4 130.84,96.01 128.79,94.26 128.15,93.73 127.54,93.4 127.26,93.03 127.34,92.74 127.48,92.6 127.57,92.51 128.05,91.34 128.02,91.29 127.75,91.18 127.44,91.07 127.38,90.93 128.13,88.87 128.35,88.32 128.35,88.14 127.9,87.96 ; 3 cut-outs
1D05V_PCH on BOTTOM: 138.69,103.41 138.62,103.48 138.62,106.38 138.84,106.61 143.06,106.61 143.39,106.28 143.39,103.63 143.16,103.41 ; 2 cut-outs
1D05V_PCH on BOTTOM: 127.92,87.73 127.77,87.76 127.69,87.91 127.67,88.37 127.52,88.5 127.44,88.62 127.41,89.05 127.27,89.17 126.73,89.59 126.19,91.06 126.17,91.32 125.51,92.86 125.03,94.31 125.18,94.59 125.61,94.74 125.79,94.87 125.81,95.25 126.09,95.58 126.71,95.87 127.13,96.8 127.65,97.47 128.99,97.49 129.45,97.47 129.75,97.24 130.26,95.86 130.49,95.23 130.49,95.11 130.01,94.47 130,93.32 129.13,92.31 129.06,92.13 129.01,92.03 128.51,91.19 128.46,91.09 128.3,91.06 128.2,91.04 128.15,90.98 128.12,90.81 128.18,90.22 128.05,90.05 127.9,89.71 127.85,89.56 127.87,89.44 128.35,88.14 128.43,87.96 128.4,87.91 128.33,87.89
1D05V_PCH on L3: 139.36,106.39 135.1,105.6 132.79,104.52 127.36,100 126.8,90.93 126.85,89.87 126.98,89.33 127.24,89.16 127.44,88.9 127.49,88.75 127.69,88.72 128.4,88.9 129.09,89.16 129.5,89.38 129.8,90.32 130.86,93.02 130.95,96.74 132.14,99.75 140.77,103.24 140.93,103.4 140.93,104.27 140.19,105.62 139.76,106.25
1D05V_S0 on BOTTOM: 144.13,104.27 144,104.4 144,109.58 144.01,109.59 144.01,118.15 147.71,121.85 147.71,127 147.63,127.08 147.63,128.48 147.73,128.58 150.6,128.58 150.88,128.3 150.88,119.43 147.56,116.11 147.56,105.03 147.17,104.65 145.52,104.65 145.14,104.27 ; 9 cut-outs
1D8V_PCH on BOTTOM: 118.93,84.56 118.83,84.66 118.42,85.75 118.31,86.12 118.35,86.21 118.42,86.26 118.47,86.26 118.6,86.21 118.65,86.16 119.03,86.03 119.23,86.03 119.46,86.13 119.57,86.24 119.72,86.36 119.8,86.38 120.17,86.16 120.3,86.11 120.38,86.01 120.38,85.93 120.35,85.85 120.35,85.6 120.63,85.32 120.66,85.24 120.58,85.14 119.79,84.81 119.69,84.81 119.62,84.86 119.54,84.94 119.44,84.97 119.21,84.89 119.18,84.79 119.16,84.66 119.03,84.56
1D8V_S0 on BOTTOM: 110.89,98.62 110.8,98.67 110.36,99.96 110.32,100.61 110.45,100.78 110.68,100.76 110.8,100.74 110.88,100.61 110.9,100.21 111.09,99.94 111.29,99.89 113.27,100.54 113.37,100.51 113.44,100.38 113.6,100.05 113.55,99.98 112.58,99.62 112.3,99.47 112.13,99.08 111.23,98.76
1D8V_S0_SIP on BOTTOM: 127.97,114.86 127.72,115.11 126.7,115.11 126.6,115.22 126.6,116.21 126.68,116.28 129.83,116.28 129.9,116.21 129.9,115.19 129.83,115.11 128.94,115.11 128.68,114.86 ; 2 cut-outs
1D8V_S5 on TOP: 59.34,69.93 59.24,70.03 59.24,72.6 59.27,72.6 60.59,73.92 60.59,75.06 60.74,75.21 61.55,75.21 61.65,75.11 61.65,73.08 61.35,72.77 61.35,70.18 61.09,69.93 ; 2 cut-outs
1D8V_S5 on TOP: 94.62,65.15 94.5,65.28 94.5,68 94.67,68.18 96.35,68.18 96.45,68.07 96.45,67.39 95.77,66.7 95.77,65.25 95.66,65.15
1D8V_S5 on TOP: 139.4,109.53 139.33,109.6 139.33,111.56 139.34,111.57 139.34,112.84 139.89,113.39 141.23,113.39 141.31,113.31 141.31,112.7 141.28,112.68 141.28,110.59 140.88,110.19 140.88,109.6 140.8,109.53 ; 1 cut-out
1D8V_S5 on TOP: 24.65,62.51 24.52,62.64 24.52,63.63 24.57,63.68 26.35,63.68 26.45,63.58 26.45,63.1 25.86,62.51
1D8V_S5 on BOTTOM: 101.28,140.18 101.25,140.21 101.25,141.86 101.33,141.94 102.29,141.94 102.8,141.43 103.92,141.43 103.97,141.38 103.97,140.97 103.94,140.95 102.83,140.95 102.06,140.18
1D8V_S5 on BOTTOM: 102.45,89.11 102.11,89.27 101.71,89.74 101.58,89.77 100.97,89.77 100.39,89.99 99.56,91.3 98.97,91.9 98.97,93.12 99.02,93.19 99.55,93.19 99.96,92.79 101,92.79 101.12,92.59 101.18,92.48 101.18,91.29 101.3,91.16 102.37,91.16 102.42,91.16 103.11,90.48 103.11,89.23 103.02,89.11
1D8V_S5 on BOTTOM: 127.72,104.9 127.62,105.18 125.64,107.16 125.64,111.79 126.6,112.75 131.4,112.75 132.72,114.07 132.72,114.96 132.57,115.11 131.3,115.11 131.27,115.14 131.27,116.36 131.35,116.44 134.88,116.44 134.91,116.41 134.91,112.88 133.18,111.15 129.45,111.15 127.79,109.5 127.79,108.49 128.2,108.08 128.2,106.2 128.48,105.92 128.68,105.46 128.68,105.21 128.4,105.11 127.82,104.9 ; 2 cut-outs
1D8V_S5 on BOTTOM: 105.65,95.92 105.54,95.96 105.39,96.42 105.39,96.45 105.42,96.49 105.65,96.62 106.3,96.89 106.31,97.08 106.15,97.49 106.15,97.59 106.43,97.69 106.49,97.76 106.56,97.79 107.35,98.1 107.7,98.4 107.8,98.77 107.93,99.09 107.83,99.44 107.8,99.67 107.93,99.75 108.34,99.87 108.44,99.82 108.52,99.62 108.59,99.34 108.8,99.11 109.1,98.22 109.1,97.94 109.02,97.84 108.06,97.44 107.86,96.83 107.65,96.67 ; 1 cut-out
1D8V_S5 on BOTTOM: 107.32,74.35 107.17,74.42 106.94,74.78 106.11,77.6 105.75,78.21 105.29,78.46 105.06,79.1 105.11,79.2 105.82,79.45 106.53,79.69 106.64,79.61 107.86,76.43 108.25,75.97 108.62,74.93 108.62,74.86
1D24V_MPHY on TOP: 129.75,87.99 129.55,88.11 129.24,89 129.29,89.11 129.67,89.23 129.75,89.23 129.85,89.11 129.95,88.85 130.16,88.83 130.49,88.85 131.81,89.11 131.86,89.03 131.96,88.78 132.21,88.6 132.77,88.5 133.31,88.5 133.48,88.7 133.46,89.38 133.51,89.56 133.74,89.92 133.87,89.94 134.17,89.77 134.25,89.64 134.09,89.33 134.09,88.95 133.79,88.47 133.33,88.14 132.57,88.09 132.11,88.19 131.78,88.44 131.58,88.39 130.13,88.09
1D24V_S5 on TOP: 145.68,85.55 145.63,85.6 145.63,86.77 145.7,86.84 145.7,92.03 145.9,92.23 146.69,92.23 146.77,92.15 146.77,91.82 147,91.59 152.1,91.59 152.25,91.44 152.25,90.53 151.37,89.64 151.37,86.36 150.55,85.55 ; 4 cut-outs
1D24V_S5 on BOTTOM: 147.43,131.62 147.35,131.7 147.35,133.33 147.43,133.4 149.44,133.4 149.79,133.05 149.79,131.75 149.66,131.62
1D35V_CPU_VDDQ_S3 on TOP: 91.37,48.82 91.27,48.92 91.27,57.36 94.85,60.94 103.54,60.94 106.13,63.53 107.91,63.53 108.38,64 113.14,74.22 112.92,74.83 113.95,77.04 114.43,77.21 114.52,77.17 114.83,77.83 117.26,78.72 117.74,79.76 119.63,80.44 119.88,80.97 124.87,82.79 125.49,84.1 126.13,84.34 126.61,84.11 127.47,81.75 127.63,81.67 129.52,82.36 129.79,82.94 129.26,84.39 129.37,84.62 131.46,85.38 133.01,84.66 133.9,82.2 134.45,81.94 135.4,82.28 135.44,82.38 134.75,84.27 135.09,84.98 135.46,85.11 138.77,83.57 138.75,82.7 138.59,82.55 138.59,82.12 138.67,82.02 138.84,81.99 138.96,81.93 138.96,80.96 139.28,80.65 140.47,80.65 140.77,80.95 142.78,80.95 142.86,80.88 142.86,76.94 138.96,73.04 138.96,56.61 138.31,55.96 117.96,55.96 110.83,48.82 ; 9 cut-outs
1D35V_DIMM_VDDQ_S3 on TOP: 103.99,28.35 103.79,28.55 103.79,29.01 103.51,29.29 81.26,29.29 80.8,29.75 80.8,33.56 81.52,34.27 81.52,39.19 81.87,39.55 88.4,39.55 91.12,42.27 91.12,47.96 91.42,48.26 111.01,48.26 118.3,55.55 129.57,55.55 129.83,55.3 129.83,28.93 129.24,28.35 ; 29 cut-outs
1D35V_DIMM_VDDQ_S3 on BOTTOM: 103.87,27.1 103.74,27.23 103.74,41.76 104.4,42.42 116.54,42.42 117.41,41.56 121.17,41.56 121.35,41.38 121.35,40.12 121.22,40 105.72,40 105.19,39.46 105.19,29.61 105.72,29.07 121.35,29.07 121.47,28.95 121.47,27.23 121.34,27.1 ; 2 cut-outs
3D3V_AUX_KBC on TOP: 166.71,54.08 166.63,54.15 166.63,58.9 166.76,59.03 170.29,59.03 170.54,58.78 170.54,54.54 170.37,54.36 169.53,54.36 169.35,54.54 169.35,54.76 169.45,54.87 169.91,54.87 170.03,54.99 170.03,56.11 169.78,56.36 168.23,56.36 167.72,55.86 167.72,54.13 167.67,54.08
3D3V_AUX_KBC on TOP: 171.56,63.3 171.46,63.4 171.46,63.83 170.62,64.67 170.62,65.69 170.37,65.94 170.37,67.08 170.94,67.65 171.6,67.65 171.64,67.62 171.64,67.08 171.1,66.55 171.1,66.09 171.34,65.85 172.05,65.85 172.19,65.71 172.19,63.35 172.14,63.3
3D3V_AUX_S5 on TOP: 167.22,46.46 166.86,46.81 165.29,46.81 164.85,47.25 164.85,48.16 164.73,48.29 164.22,48.29 164.22,49.48 164.29,49.56 164.75,49.56 164.8,49.51 164.8,49.07 164.93,48.95 165.56,48.95 165.59,48.92 165.59,47.7 165.87,47.42 167.32,47.42 167.77,46.97 167.77,46.79 167.44,46.46
3D3V_CAMERA_S0 on TOP: 113.19,175.11 112.88,175.41 112.88,181.61 113.06,181.79 114.99,181.79 115.12,181.66 115.12,175.29 114.94,175.11 ; 5 cut-outs
3D3V_LCDVDD_S0 on TOP: 102.5,159.16 102.45,159.21 102.45,162.79 102.75,163.1 104.68,163.1 104.73,163.04 104.73,159.31 104.58,159.16 ; 2 cut-outs
3D3V_LCDVDD_S0_CONN on TOP: 102.42,163.68 102.34,163.76 102.34,169.01 102.5,169.17 104.25,169.17 104.45,168.96 104.45,163.76 104.38,163.68 ; 5 cut-outs
3D3V_LCDVDD_S0_CONN on BOTTOM: 102.32,167.18 101.79,167.24 101.52,167.4 101.05,169.06 101,169.17 100.74,169.88 100.74,169.95 101.89,170.36 102.34,170.54 102.47,170.54 102.59,170.16 102.78,169.62 102.95,169.27 103,169.22 103.33,168.96 103.74,167.79 103.59,167.58 103.19,167.41
3D3V_PWR on TOP: 31.91,54.41 31.66,54.66 31.66,60.56 31.96,60.86 36.41,60.86 36.56,60.71 36.56,54.99 35.97,54.41 ; 2 cut-outs
3D3V_PWR on BOTTOM: 32.62,50.42 32.54,50.5 32.54,59.11 33.1,59.67 33.1,60.76 33.13,60.78 36.71,60.78 36.79,60.71 36.79,51.49 35.72,50.42
3D3V_S0 on TOP: 97.59,156.87 97.47,157 97.47,158.4 97.92,158.85 97.92,159.69 98.03,159.79 101.96,159.79 102.12,159.64 102.12,157 101.99,156.87 ; 5 cut-outs
3D3V_S0 on TOP: 28.48,51.92 28.43,51.97 28.43,53.44 28.71,53.72 31.6,53.72 31.73,53.6 31.73,52.07 31.58,51.92 ; 1 cut-out
3D3V_S0 on TOP: 115.58,178.49 115.45,178.61 115.45,181.66 115.46,181.68 115.46,182.08 115.7,182.32 118.63,182.32 118.75,182.2 118.75,178.74 118.5,178.49 ; 3 cut-outs
3D3V_S0 on TOP: 121.01,162.64 120.86,162.79 120.86,165.28 120.94,165.36 123.96,165.36 124.06,165.25 124.06,162.71 123.98,162.64 ; 3 cut-outs
3D3V_S0 on TOP: 146.74,141.1 146.29,141.56 146.29,142.06 146.92,142.7 146.92,148.44 147.02,148.54 148.09,148.54 148.37,148.26 148.37,141.68 147.78,141.1 ; 1 cut-out
3D3V_S0 on BOTTOM: 89.47,83.62 89.31,83.77 89.31,84.03 91.02,85.73 91.68,85.73 91.73,85.68 91.73,84.41 91.47,84.15 90.43,84.15 89.9,83.62
3D3V_S0 on BOTTOM: 102.42,145.77 102.19,146 102.19,147.47 102.24,147.53 103.77,147.53 103.89,147.4 103.89,145.98 103.69,145.77
3D3V_S0 on BOTTOM: 72.6,66.32 72.6,67.85 72.73,67.97 73.79,67.97 73.95,67.82 73.95,66.55 73.72,66.32
3D3V_S0 on BOTTOM: 79.53,72.8 79.38,72.95 79.38,73.92 79.51,74.04 79.99,74.04 80.14,74.2 80.14,75.54 80.3,75.69 82.71,75.69 82.82,75.58 82.82,72.96 82.66,72.8 ; 3 cut-outs
3D3V_S0 on L3: 92.73,157.98 94.06,159.31 100.52,159.31 100.72,159.11 100.72,156.85 100.52,156.64 96.78,156.64 95.46,155.32 95.46,96.29 94.85,95.68 94.85,94.21 93.54,92.9 91.43,89.59 91.22,86.9 90.96,86.46 80.88,76.38 79.79,76.38 79.2,75.8 77.05,75.8 76.27,75.02 75.66,75.02 73.24,72.6 71.15,72.6 70.44,73.31 68.28,73.31 66.9,71.92 62.07,71.92 62.06,71.93 61.81,71.93 61.7,72.04 61.7,73.28 61.63,73.36 60.21,73.36 60.05,73.2 60.05,72.16 59.81,71.92 40.99,71.92 36.35,67.29 27.95,67.29 27.13,66.47 27.13,59.26 31.73,54.66 31.73,52.07 31.58,51.92 28.56,51.92 28.3,52.17 28.3,53.52 23.67,58.16 23.67,67.65 25.92,69.9 32.47,69.9 34.83,69.95 41.21,76.38 47.84,76.46 60.26,76.43 65.51,76.43 68.28,76.68 69.93,76.96 72.68,77.62 76.66,79.1 80.17,81.16 83.29,83.54 86.14,86.49 88.12,89.03 90.41,93.47 91.52,96.24 92.32,99.21 92.62,101.75 92.62,112.73 92.73,112.84
3D3V_S0 on L4: 105.98,159.18 108.24,161.44 108.24,163.2 108.49,163.45 108.87,163.45 109.43,162.89 115.4,162.89 115.98,163.48 115.98,182.04 116.26,182.32 119.92,182.32 120.5,181.74 123.58,181.74 124.37,180.95 124.37,157.84 124.01,157.48 112.91,157.48 110.42,154.99 97.72,154.99 97.52,155.2 97.52,158.17 98.53,159.18
3D3V_S5 on TOP: 170.75,52.83 170.67,52.91 170.67,54.89 170.8,55.02 172.96,55.02 173.11,54.87 173.11,53.29 172.65,52.83 ; 2 cut-outs
3D3V_S5 on TOP: 26.04,51.92 25.36,52.61 25.36,53.14 25.25,53.24 24.47,53.24 24.39,53.32 24.39,58.45 24.49,58.55 31.3,58.55 31.35,58.5 31.35,54.43 30.87,53.95 27.49,53.95 27.11,53.57 27.11,52 27.03,51.92 ; 3 cut-outs
3D3V_S5 on TOP: 68.43,66.07 68.28,66.22 68.28,68.63 68.41,68.76 69.63,68.76 69.93,68.46 69.93,66.19 69.81,66.07
3D3V_S5 on BOTTOM: 84.16,71.96 84.11,72.01 84.11,73.81 84.28,73.99 85.99,73.99 86.16,73.81 86.16,72.06 86.06,71.96 ; 1 cut-out
3D3V_S5 on BOTTOM: 99.12,143.05 98.98,143.19 98.98,145.94 99.04,146 100.67,146 100.77,145.9 100.77,143.16 100.67,143.05
3D3V_S5 on BOTTOM: 89.57,80.16 89.47,80.27 89.47,82.3 89.57,82.4 91.29,82.4 91.4,82.3 91.4,80.88 90.69,80.16
3D3V_S5 on BOTTOM: 104.73,73.79 104.55,73.97 104.55,76.13 104.4,76.28 104.4,77.19 104.3,77.29 103.66,77.29 103.56,77.4 103.56,77.75 103.69,77.88 105.04,77.88 105.77,77.14 105.77,74.04 105.52,73.79 ; 2 cut-outs
3D3V_USB on TOP: 120.7,85.32 120.43,85.45 120.33,85.71 120.04,85.85 119.61,85.69 119.43,85.78 119.18,86.45 119.05,86.52 118.61,86.36 118.35,86.48 118.19,86.92 118.04,87.43 117.86,87.63 117.74,87.68 117.36,87.56 117.23,87.51 117.15,87.56 117,87.93 117.08,88.06 117.64,88.26 117.65,88.26 118.49,88.57 118.67,88.49 118.89,87.88 120.81,86.99 121.11,87.1 121.25,87.03 121.68,85.85 121.58,85.64 ; 1 cut-out
3D3V_USB on BOTTOM: 120.94,86.03 120.38,86.16 119.95,86.41 118.96,86.87 117.91,87.15 117.66,87.28 117.66,87.56 117.79,87.63 118.88,87.94 119.34,87.76 119.46,87.66 119.49,87.43 119.46,87.23 119.54,87.07 120.56,86.69 121.14,86.34 121.17,86.16 121.11,86.06
3D3V_WLAN_S0 on TOP: 144,147.42 143.59,147.83 143.59,150.57 143.7,150.67 146.59,150.67 146.64,150.62 146.64,147.55 146.51,147.42 ; 5 cut-outs
3D3V_WLAN_S0 on BOTTOM: 144.57,149.19 143.72,150.04 143.72,151.44 141.1,154.05 141.1,167.74 142.02,168.66 147.48,168.66 147.48,167.36 147.45,167.34 142.73,167.34 142.55,167.16 142.55,154.71 145.3,151.97 145.3,150.8 145.42,150.67 147.38,150.67 147.43,150.62 147.43,149.43 147.19,149.19
+DC_IN on TOP: 138.97,160 137.73,161.24 137.73,165.71 138.23,166.22 138.23,167.13 137.68,167.69 136.43,167.69 135.97,168.15 134.6,168.15 133.66,169.09 133.66,172.75 133.71,172.8 135.11,172.8 135.34,172.57 139.94,172.57 139.99,172.52 139.99,170.54 140.42,170.11 142.91,170.11 143.01,170 143.01,165.31 142.88,165.18 141.87,165.18 141.38,164.7 141.38,160.05 141.33,160 ; 7 cut-outs
+DC_IN on BOTTOM: 132.62,159.69 132.04,160.28 132.04,166.3 132.02,166.31 132.02,167.4 132.01,167.41 132.01,170.89 132.44,171.33 132.44,173.76 132.49,173.81 135.72,173.81 136.35,173.18 139.53,173.18 140.67,172.04 140.67,168.96 139.71,168 139.71,160.1 139.3,159.69
+DC_IN_C on TOP: 127.16,169.47 126.75,169.88 126.75,171.38 124.62,173.51 124.62,182.27 124.8,182.45 128.63,182.45 128.66,182.48 132.75,182.48 133.13,182.09 133.13,169.6 133,169.47 ; 3 cut-outs
+DC_IN_C on BOTTOM: 124.62,174.45 124.01,175.06 124.01,179.96 124.67,180.62 124.67,182.27 124.87,182.48 132.77,182.48 133.15,182.09 133.15,178.69 132.82,178.36 129.24,178.36 128.99,178.11 128.99,174.68 128.76,174.45
AD+_TO_SYS on TOP: 147.1,162.82 147.02,162.89 147.02,164.04 147.2,164.21 147.2,165.31 146.97,165.53 146.97,169.88 147.4,170.31 150.86,170.31 151.21,169.95 151.21,165.2 151.09,165.08 150.4,165.08 150.27,164.95 150.27,163.04 150.05,162.82 ; 2 cut-outs
AUD_AGND on L2VCC, L5GND: 165.65,11.24 165.15,11.62 162.37,11.62 161.6,12.38 159.06,12.38 158.92,12.53 158.92,13.16 158.56,13.53 156.4,13.53 153.97,15.96 153.97,17.32 154.11,17.46 154.62,17.46 154.99,17.83 154.99,18.72 155.13,18.86 155.64,18.86 156.02,19.24 157.03,19.24 157.29,19.5 158.78,19.5 158.92,19.35 158.92,18.75 158.78,18.61 158.27,18.61 156.13,16.46 156.13,14.4 156.49,14.04 158.56,14.04 159.06,14.54 159.72,14.54 160.19,15.18 160.19,16.1 160.45,16.86 160.45,17.7 160.72,17.97 163.64,17.97 164,18.34 164,22.67 164.92,23.81 166.17,23.81 167.69,25.08 169.45,25.08 169.72,24.82 169.72,20.5 170.08,20.13 173.77,20.13 174.04,19.86 174.04,15.19 173.77,14.92 171.35,14.92 170.99,14.56 170.99,12.91 170.84,12.77 170.21,12.77 169.72,12.27 169.72,11.64 169.57,11.5 168.2,11.5 167.82,11.24
AUD_SPK_L+ on TOP: 152.36,9.1 152.18,9.27 152.18,10.67 150.96,11.89 148.04,11.89 146.82,13.11 146.82,19.56 148.66,21.4 150.87,21.4 153.19,23.73 154.85,23.73 154.92,23.65 154.92,22.76 154.85,22.68 153.7,22.68 151.44,20.42 149.13,20.42 147.89,19.18 147.89,13.51 148.47,12.93 151.37,12.93 153.25,11.05 153.25,9.2 153.14,9.1 ; 4 cut-outs
AUD_SPK_L+ on BOTTOM: 156.5,20.14 154.62,22.02 154.36,22.02 154.13,22.25 154.13,23.37 154.29,23.52 154.74,23.52 154.95,23.32 154.95,22.13 156.73,20.35 158.91,20.35 158.94,20.32 158.94,20.17 158.91,20.14
AUD_SPK_L+_C on TOP: 153.55,8.84 153.47,8.92 153.47,11.23 153.58,11.33 154.31,11.33 154.95,10.7 154.95,8.92 154.87,8.84 ; 1 cut-out
AUD_SPK_L+_C on BOTTOM: 154.21,9.17 154.19,9.2 154.19,11.13 154.36,11.31 154.36,13.01 154.44,13.08 155,13.08 155.05,13.03 155.05,9.25 154.97,9.17
AUD_SPK_L+_R on TOP: 147.86,6.73 147.63,6.96 147.63,8.21 147.71,8.28 149.23,8.28 149.59,7.93 152.05,7.93 152.2,8.08 152.2,8.84 152.28,8.92 153.14,8.92 153.25,8.82 153.25,6.91 153.07,6.73 ; 3 cut-outs
AUD_SPK_L+_R on BOTTOM: 148.14,6.83 147.99,6.99 147.99,8.16 148.04,8.21 148.55,8.21 148.72,8.38 148.72,9.83 148.6,9.96 147.02,9.96 146.84,10.14 146.84,11.1 147.05,11.31 149.54,11.31 149.77,11.08 149.77,7.22 149.38,6.83 ; 2 cut-outs
AUD_SPK_L- on TOP: 147.1,10.62 145.55,12.17 145.55,21.21 146.64,22.3 147.43,22.3 147.94,22.81 150.32,22.81 152.41,24.89 156.04,24.89 156.24,24.69 156.24,23.04 156.15,22.95 155.16,22.95 155.13,22.99 155.13,23.7 154.97,23.85 152.89,23.85 150.81,21.77 148.47,21.77 147.82,21.12 147.01,21.12 146.62,20.73 146.62,12.68 147.63,11.66 150.98,11.66 151.09,11.56 151.09,10.64 151.06,10.62 ; 4 cut-outs
AUD_SPK_L- on BOTTOM: 156.73,20.55 155.1,22.18 155.1,23.67 155.13,23.7 155.94,23.7 156.06,23.57 156.06,22.96 155.86,22.76 155.86,21.92 157.03,20.75 158.91,20.75 158.94,20.73 158.94,20.58 158.91,20.55
AUD_SPK_L-_C on TOP: 150.15,8.1 150.05,8.21 150.05,10.24 150.1,10.29 151.9,10.29 152.03,10.16 152.03,8.18 151.95,8.1 ; 1 cut-out
AUD_SPK_L-_C on BOTTOM: 151.62,9.35 151.52,9.45 151.52,10.47 151.62,10.57 152.59,10.57 152.84,10.82 152.84,12.91 152.89,12.96 153.98,12.96 154.01,12.93 154.01,10.31 153.04,9.35
AUD_SPK_L-_R on TOP: 145.65,7.67 145.57,7.75 145.57,10.21 145.7,10.34 149.77,10.34 149.84,10.26 149.84,9.07 149.77,8.99 147.71,8.99 147.35,8.64 147.35,7.72 147.3,7.67 ; 2 cut-outs
AUD_SPK_L-_R on BOTTOM: 147.9,3.72 146.06,5.56 146.06,9.22 146.13,9.3 147.12,9.3 147.3,9.12 147.3,5.97 148.5,4.78 149.77,4.78 149.99,5.01 149.99,11.2 150.15,11.36 151.11,11.36 151.19,11.28 151.19,4.5 150.41,3.72 ; 2 cut-outs
AUD_SPK_R+ on TOP: 154.16,13.51 152.51,15.17 152.51,19.43 154.49,21.41 156.27,21.41 157.08,22.23 157.39,22.23 157.75,21.86 157.75,20.31 157.44,19.99 156.45,19.99 156.14,19.69 155.56,19.69 155.1,19.23 154.13,19.23 153.93,19.03 153.93,17.83 153.58,17.48 153.58,15.72 154.97,14.33 154.97,14.23 154.26,13.51 ; 2 cut-outs
AUD_SPK_R+ on TOP: 150.02,13.13 149.97,13.18 149.97,14.05 150.05,14.12 151.32,14.12 151.8,13.64 151.8,13.29 151.65,13.13 ; 1 cut-out
AUD_SPK_R+ on BOTTOM: 151.16,12.83 151.06,12.93 151.06,13.74 151.19,13.87 151.52,13.87 151.82,14.18 152.97,14.18 153.14,14.35 153.14,15.27 153.32,15.45 153.91,15.45 154.21,15.14 154.21,13.64 153.65,13.08 152.84,13.08 152.59,12.83
AUD_SPK_R+ on BOTTOM: 157.18,21.34 156.9,21.62 156.9,21.97 157.06,22.13 157.36,22.13 157.79,21.69 157.79,21.64 157.87,21.57 158.91,21.57 158.94,21.54 158.94,21.36 158.91,21.34
AUD_SPK_R+_C on TOP: 156.62,9.88 156.55,9.96 156.55,11.15 154.59,13.11 154.59,13.21 155.3,13.92 155.48,13.92 157.72,11.69 157.72,9.98 157.61,9.88
AUD_SPK_R+_C on BOTTOM: 156.4,9.88 156.32,9.96 156.32,12.93 156.37,12.98 157.33,12.98 157.41,12.91 157.41,10.04 157.26,9.88
AUD_SPK_R+_R on TOP: 148.17,13.51 148.01,13.67 148.01,16.26 148.19,16.44 149.82,16.44 149.87,16.39 149.87,15.8 149.97,15.7 150.63,15.7 150.71,15.62 150.71,14.33 150.63,14.25 149.92,14.25 149.18,13.51 ; 2 cut-outs
AUD_SPK_R+_R on BOTTOM: 144.84,13.39 144.69,13.54 144.69,14.58 144.84,14.73 147.81,14.73 148.24,15.17 151.06,15.17 151.39,15.5 152.79,15.5 152.99,15.29 152.99,14.56 152.76,14.33 151.65,14.33 151.39,14.07 149.79,14.07 149.11,13.39
AUD_SPK_R- on TOP: 153.19,12.42 151.37,14.25 151.37,19.94 153.98,22.56 156.32,22.56 156.62,22.25 156.62,21.97 156.22,21.57 154.46,21.57 152.38,19.48 152.38,15.04 154.16,13.26 154.16,13.18 153.4,12.42 ; 3 cut-outs
AUD_SPK_R- on BOTTOM: 157.03,20.93 155.99,21.97 155.99,22.61 156.04,22.66 156.57,22.66 156.73,22.51 156.73,21.59 157.11,21.21 157.87,21.21 157.92,21.16 158.91,21.16 158.94,21.13 158.94,20.96 158.91,20.93
AUD_SPK_R-_C on TOP: 155.33,9.02 155.25,9.1 155.25,10.64 153.73,12.17 153.73,12.27 154.39,12.93 154.52,12.93 156.37,11.08 156.37,9.12 156.27,9.02
AUD_SPK_R-_C on BOTTOM: 155.48,9.83 155.38,9.93 155.38,13.01 155.43,13.06 155.94,13.06 156.01,12.98 156.01,11.33 156.22,11.13 156.22,9.91 156.14,9.83
AUD_SPK_R-_R on TOP: 150.12,15.95 150.07,16 150.07,17.96 149.73,18.3 149.73,18.94 149.87,19.08 151.06,19.08 151.11,19.03 151.11,16.05 151.01,15.95 ; 4 cut-outs
AUD_SPK_R-_R on BOTTOM: 148.24,15.67 148.05,15.86 144.8,15.86 144.71,15.95 144.71,16.87 144.89,17.05 148.47,17.05 148.8,17.38 152.84,17.38 153.04,17.17 153.04,16.39 152.89,16.23 149.84,16.23 149.28,15.67
BT+ on TOP: 155.53,169.95 155.4,170.08 155.4,176.74 155.56,176.89 156.78,176.89 156.88,176.99 156.88,177.55 156.95,177.62 157.51,177.62 160.48,180.6 162.52,180.6 163.38,181.46 163.38,186.41 163.48,186.51 167.57,186.51 167.83,186.26 167.83,181.18 167.2,180.56 167.2,179.75 166.94,179.48 166.94,172.7 166.63,172.39 161.93,172.39 161.75,172.21 161.75,170.18 161.53,169.95 ; 3 cut-outs
BT+ on BOTTOM: 156.09,167.54 155.86,167.77 155.86,169.88 155.66,170.08 155.1,170.08 154.92,170.26 154.92,174.42 155.18,174.68 157.54,174.68 157.92,175.06 157.92,177.85 157.93,177.87 157.93,180.68 158.2,180.95 162.87,180.95 163.38,181.46 163.38,186.36 163.53,186.51 167.57,186.51 167.83,186.26 167.83,181.18 166.94,180.29 166.94,172.7 166.63,172.39 160.66,172.39 160.26,171.99 160.26,167.74 160.05,167.54 ; 2 cut-outs
BT+_R on TOP: 162.34,169.98 162.03,170.28 162.03,171.76 162.21,171.93 166.78,171.93 167.06,171.66 167.06,170.64 166.4,169.98
BT+_R on BOTTOM: 162.47,166.45 162.41,166.5 162.41,167.36 162.21,167.57 160.71,167.57 160.51,167.77 160.51,171.73 160.71,171.93 166.35,171.93 166.61,171.68 166.61,170.36 165.82,169.57 165.82,166.63 165.64,166.45
BT+_R_1 on BOTTOM: 170.16,159.9 170.06,160 170.06,160.91 169.93,161.04 169.4,161.04 169.3,161.14 169.3,162.16 169.91,162.77 171.38,162.77 171.64,162.51 171.64,161.55 171.53,161.44 170.87,161.44 170.8,161.37 170.8,160.02 170.67,159.9 ; 1 cut-out
CHG_AGND on TOP: 159.9,150.17 159.82,150.24 159.82,152.33 159.85,152.35 161.98,152.35 162.06,152.28 162.06,150.22 162.01,150.17
CHG_AGND on BOTTOM: 160,150.01 159.85,150.17 159.85,152.35 159.93,152.43 162.31,152.43 162.36,152.38 162.36,150.19 162.19,150.01
HDMI_PLL_GND on BOTTOM: 16.11,45.32 16.03,45.39 16.03,54.31 16.67,54.94 17.38,54.94 18.12,54.21 18.12,45.44 17.99,45.32
JGND on TOP: 133.51,173.51 133.38,173.64 133.38,181.97 133.89,182.48 137.57,182.48 137.93,182.12 137.93,173.76 137.68,173.51 ; 2 cut-outs
JGND on BOTTOM: 133.56,174.32 133.38,174.5 133.38,181.97 133.89,182.48 137.55,182.48 137.93,182.09 137.93,174.4 137.85,174.32
MIC2_VREFO on BOTTOM: 168.1,21.29 168.05,21.34 168.05,21.92 168.79,22.66 169.43,22.66 169.45,22.63 169.45,21.36 169.37,21.29
ODD_PWR_5V on TOP: 171.66,144.71 171.38,144.99 171.38,148.8 171.43,148.85 172.32,148.85 172.4,148.77 172.4,147.91 172.57,147.73 174.61,147.73 174.68,147.65 174.68,145.01 174.56,144.88 173.24,144.88 173.06,144.71
ODD_PWR_5V on BOTTOM: 171.33,144.71 171.18,144.86 171.18,147.6 171.3,147.73 174.61,147.73 174.68,147.65 174.68,145.01 174.56,144.88 173.26,144.88 173.08,144.71
PS_ID_R2 on TOP: 130.18,163.93 129.45,164.67 128.94,164.67 128.84,164.77 128.84,165.46 128.56,165.74 128.56,169.14 128.71,169.29 131.68,169.29 131.99,168.99 131.99,166.12 131.88,166.02 131.35,166.02 130.97,165.64 130.97,164.06 130.84,163.93 ; 3 cut-outs
PWR_1D05V on TOP: 142.22,126.14 142.15,126.21 142.15,128.91 142.35,129.11 146.79,129.11 147.05,128.86 147.05,126.32 146.87,126.14 ; 3 cut-outs
PWR_1D05V on BOTTOM: 141.51,126.11 141.36,126.27 141.36,129.06 141.43,129.14 142.78,129.14 143.31,128.6 147.33,128.6 147.4,128.53 147.4,126.21 147.3,126.11
PWR_1D8V on BOTTOM: 131.88,116.74 131.81,116.82 131.81,122.84 131.86,122.89 134.55,122.89 134.65,122.79 134.65,117.68 134.83,117.5 135.67,117.5 135.69,117.48 135.69,116.84 135.59,116.74 ; 1 cut-out
PWR_1D8V_PH on BOTTOM: 132.09,123.57 132.06,123.6 132.06,125.66 132.54,126.14 132.54,127.71 132.57,127.74 133.15,127.74 133.18,127.71 133.18,126.77 133.14,126.74 133.14,125.72 133.99,124.87 134.37,124.87 134.42,124.82 134.42,123.62 134.37,123.57
PWR_1D24V on BOTTOM: 141.16,130.56 141.08,130.63 141.08,132.95 141.54,133.4 141.54,134.14 141.64,134.24 146.84,134.24 147.01,134.08 147.01,131.38 146.95,131.32 142.6,131.32 142.5,131.22 142.5,130.71 142.35,130.56 ; 1 cut-out
PWR_1D24V_PH on BOTTOM: 136.08,130.18 136.05,130.2 136.05,130.38 136.08,130.41 137.68,130.41 137.85,130.58 138.64,130.58 139.07,131.02 139.07,133 139.15,133.07 140.37,133.07 140.42,133.02 140.42,130.28 140.32,130.18
PWR_3D3V_DRVL2 on TOP: 43.19,52.48 43.14,52.53 43.14,53.72 43.21,53.8 44.1,53.8 44.15,53.75 44.15,52.53 44.1,52.48
PWR_3D3V_LL2 on TOP: 37.6,49.84 37.4,50.04 37.4,57.63 37.78,58.02 40.88,58.02 40.93,57.96 40.93,55.7 40.85,55.63 39.12,55.63 38.95,55.45 38.95,54.56 39.25,54.26 42.48,54.26 42.65,54.08 42.65,50.01 42.48,49.84
PWR_3D3V_LL2 on BOTTOM: 37.55,50.57 37.4,50.73 37.4,57.63 37.78,58.02 41.56,58.02 41.71,57.86 41.71,53.04 41.82,52.94 43.42,52.94 43.44,52.91 43.44,51.87 43.39,51.82 41.87,51.82 41.71,51.67 41.71,50.85 41.43,50.57
PWR_5V_DRVL1 on TOP: 43.19,45.49 43.16,45.52 43.16,46.69 43.24,46.76 44.05,46.76 44.15,46.66 44.15,45.54 44.1,45.49
PWR_5V_LL1 on TOP: 37.12,39.27 36.96,39.42 36.96,46.26 37.24,46.53 42.6,46.53 42.65,46.48 42.65,43.06 42.58,42.98 41.41,42.98 40.93,42.5 40.93,39.85 40.85,39.78 39.86,39.78 39.71,39.93 39.02,39.93 38.92,39.83 38.92,39.37 38.82,39.27
PWR_5V_LL1 on BOTTOM: 40.7,38.94 39.71,39.93 39.02,39.93 38.92,39.83 38.92,39.37 38.82,39.27 37.14,39.27 36.96,39.45 36.96,46.26 37.24,46.53 42.63,46.53 42.68,46.48 42.68,39.04 42.58,38.94
